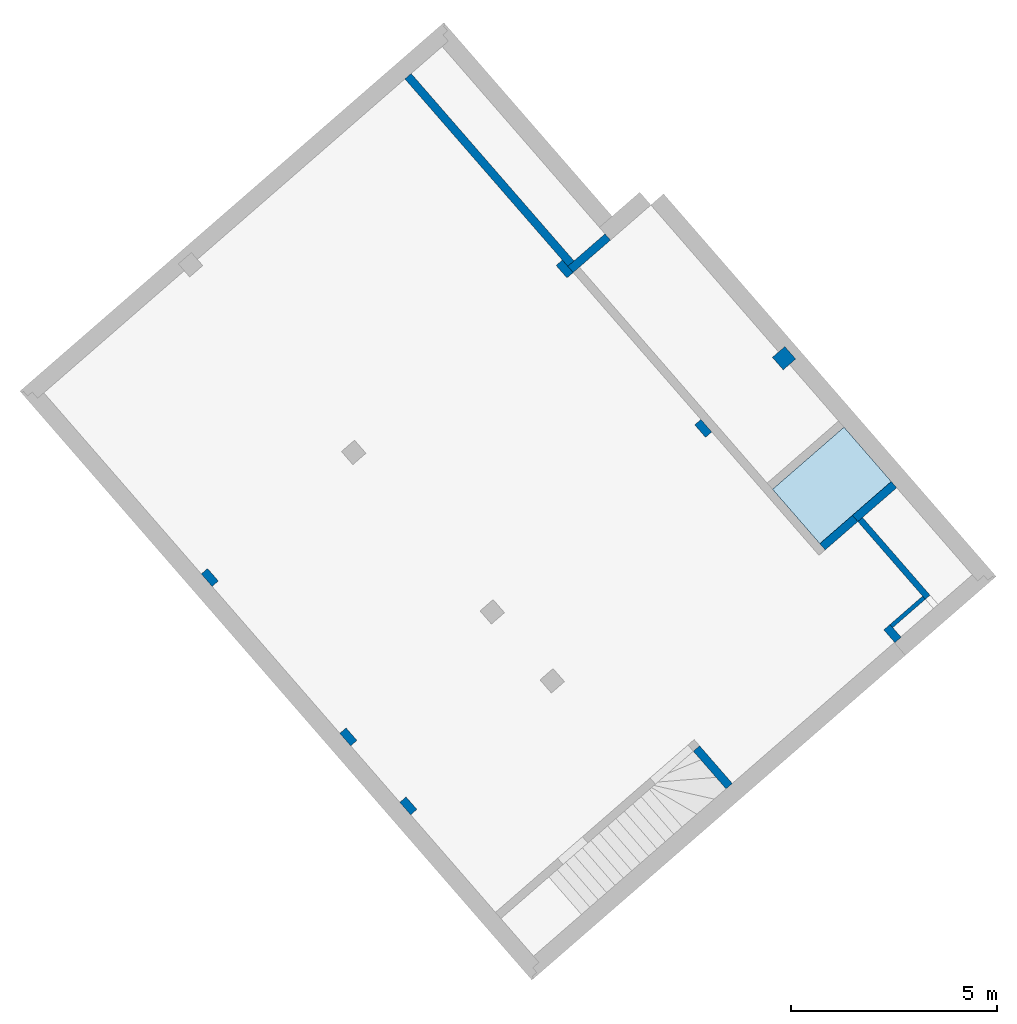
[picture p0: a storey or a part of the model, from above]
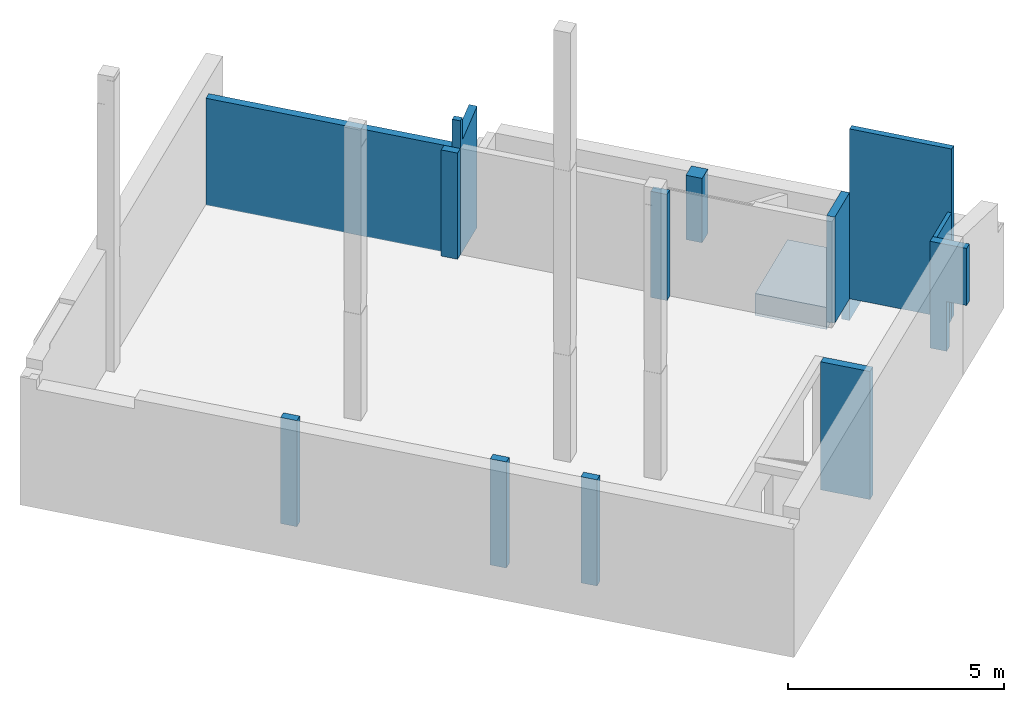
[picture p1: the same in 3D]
Properties of the parts of a building model (IFC2X3), part 1 of 13

# File
Description: ViewDefinition [CoordinationView_V2.0], Option [Drawing Scale: 100.000000], Option [Global Unique Identifiers (GUID): Keep existing], Option [Elements to export: Visible elements (on all stories)], Option [Partial Structure Display: Entire Model], Option [IFC Domain: All], Option [Structural Function: All Elements], Option [Convert Grid elements: On], Option [Convert IFC Annotations and ARCHICAD 2D elements: Off], Option [Convert 2D symbols of Doors and Windows: Off], Option [Explode Composite and Complex Profile elements into parts: Off], Option [Export geometries that Participates in Collision Detection only: Off], Option [Multi-skin complex geometries: Complex profile], Option [Elements in Solid Element Operations: BRep], Option [Elements with junctions: BRep], Option [Slabs with slanted edge(s): BRep], Option [Use legacy geometric methods as in Coordination View 1.0: Off], Option [IFC Site Geometry: As boundary representation (BRep)], Option [IFC Site Location: At Project Origin], Option [Curtain Wall export mode: Container Element], Option [Railing export mode: Single Element], Option [Stair export mode: Container Element], Option [Properties To Export: All properties], Option [Space containment: Off], Option [Bounding Box: Off], Option [Geometry to type objects: Off], Option [Element Properties: Off], Option [Building Material Properties: Off], Option [Element Parameters: Off], Option [Component Parameters: Off], Option [IFC Base Quantities: Off], Option [Door Window Parameters: On], Option [IFC Space boundaries: Off], Option [ARCHICAD Zone Categories as IFC Space classification data: Off], Option [Element Classifications: Off]
File name: C:\Users\Andro\Documents\2019_Tabasalu\VALMIS\PÕHIPROJEKT_2020-01-27\1940-A_TP_AR_2020-03-07.ifc
Time: 2020-03-06T18:38:55
Author: Architect
Organization: Building Designer Office
Written by: The EXPRESS Data Manager Version 5.02.0100.09 : 26 Sep 2013
Made in: IFC file generated by GRAPHISOFT ARCHICAD-64 22.0.0 INT FULL Windows version (IFC add-on version: 5009 INT FULL).
Authorization: The authorising person

# IfcSite, Site
RefLatitude: 47, 33, 34, 948800; RefLongitude: 19, 3, 17, 204400; RefElevation: 0 mm

# IfcBuildingStorey (6)
In: Building
Name | Elevation (mm)
-1 korrus | -3415
0 korrus | -1615
1 korrus | 0
1,5 korrus | 1800
2 korrus | 5215
Katus | 8715

# IfcSpace: Generic, 001
In: 0 korrus
Type - ElementType: Element type 001
LongName: Auditoorium; InteriorOrExteriorSpace: INTERNAL; Classification: 1.15 IfcSpace (ruum) (_RKAS BIM + ARCHICAD Classification)
Pset_SpaceCommon - Category: Generic
RUUMID - 1 Nimetus: Auditoorium; 2 Number: 001; 3 Kategooria: Generic; 4 Ruumi pindala: 151,9 Kasulik pindala: 151,9; 5 Ruumi kõrgus: 6 360
AC_Pset_RenovationAndPhasing - Renovation Status: New

# IfcSpace: Generic, 002
In: 0 korrus
Type - ElementType: Element type 002
LongName: Kabinet; InteriorOrExteriorSpace: INTERNAL; Classification: 1.15 IfcSpace (ruum) (_RKAS BIM + ARCHICAD Classification)
Pset_SpaceCommon - Category: Generic
RUUMID - 1 Nimetus: Kabinet; 2 Number: 002; 3 Kategooria: Generic; 4 Ruumi pindala: 18,7 Kasulik pindala: 18,7; 5 Ruumi kõrgus: 3 000
AC_Pset_RenovationAndPhasing - Renovation Status: New

# IfcSpace: Generic, 003
In: 0 korrus
Type - ElementType: Element type 003
LongName: Arvutiklass; InteriorOrExteriorSpace: INTERNAL; Classification: 1.15 IfcSpace (ruum) (_RKAS BIM + ARCHICAD Classification)
Pset_SpaceCommon - Category: Generic
RUUMID - 1 Nimetus: Arvutiklass; 2 Number: 003; 3 Kategooria: Generic; 4 Ruumi pindala: 40,9 Kasulik pindala: 40,9; 5 Ruumi kõrgus: 3 000
AC_Pset_RenovationAndPhasing - Renovation Status: New

# IfcSpace: Generic, 004
In: 0 korrus
Type - ElementType: Element type 004
LongName: IKT juht; InteriorOrExteriorSpace: INTERNAL; Classification: 1.15 IfcSpace (ruum) (_RKAS BIM + ARCHICAD Classification)
Pset_SpaceCommon - Category: Generic
RUUMID - 1 Nimetus: IKT juht; 2 Number: 004; 3 Kategooria: Generic; 4 Ruumi pindala: 15,7 Kasulik pindala: 15,7; 5 Ruumi kõrgus: 3 000
AC_Pset_RenovationAndPhasing - Renovation Status: New

# IfcSpace: Generic, 005
In: 0 korrus
Type - ElementType: Element type 005
LongName: Õpilasesindus; InteriorOrExteriorSpace: INTERNAL; Classification: 1.15 IfcSpace (ruum) (_RKAS BIM + ARCHICAD Classification)
Pset_SpaceCommon - Category: Generic
RUUMID - 1 Nimetus: Õpilasesindus; 2 Number: 005; 3 Kategooria: Generic; 4 Ruumi pindala: 17,8 Kasulik pindala: 17,8; 5 Ruumi kõrgus: 3 000
AC_Pset_RenovationAndPhasing - Renovation Status: New

# IfcSpace: Generic, 006
In: 0 korrus
Type - ElementType: Element type 006
LongName: Arvutiklass; InteriorOrExteriorSpace: INTERNAL; Classification: 1.15 IfcSpace (ruum) (_RKAS BIM + ARCHICAD Classification)
Pset_SpaceCommon - Category: Generic
RUUMID - 1 Nimetus: Arvutiklass; 2 Number: 006; 3 Kategooria: Generic; 4 Ruumi pindala: 72,2 Kasulik pindala: 72,2; 5 Ruumi kõrgus: 3 000
AC_Pset_RenovationAndPhasing - Renovation Status: New

# IfcSpace: Generic, 007
In: 0 korrus
Type - ElementType: Element type 007
LongName: IKT ladu; InteriorOrExteriorSpace: INTERNAL; Classification: 1.15 IfcSpace (ruum) (_RKAS BIM + ARCHICAD Classification)
Pset_SpaceCommon - Category: Generic
RUUMID - 1 Nimetus: IKT ladu; 2 Number: 007; 3 Kategooria: Generic; 4 Ruumi pindala: 3,3 Kasulik pindala: 3,3; 5 Ruumi kõrgus: 3 000
AC_Pset_RenovationAndPhasing - Renovation Status: New

# IfcSpace: Generic, 008
In: 0 korrus
Type - ElementType: Element type 008
LongName: IKT ladu; InteriorOrExteriorSpace: INTERNAL; Classification: 1.15 IfcSpace (ruum) (_RKAS BIM + ARCHICAD Classification)
Pset_SpaceCommon - Category: Generic
RUUMID - 1 Nimetus: IKT ladu; 2 Number: 008; 3 Kategooria: Generic; 4 Ruumi pindala: 3,4 Kasulik pindala: 3,4; 5 Ruumi kõrgus: 3 000
AC_Pset_RenovationAndPhasing - Renovation Status: New

# IfcSpace: Generic, 009
In: 0 korrus
Type - ElementType: Element type 009
LongName: Raamatukogu/rekreatsioon; InteriorOrExteriorSpace: INTERNAL; Classification: 1.15 IfcSpace (ruum) (_RKAS BIM + ARCHICAD Classification)
Pset_SpaceCommon - Category: Generic
RUUMID - 1 Nimetus: Raamatukogu/rekreatsioon; 2 Number: 009; 3 Kategooria: Generic; 4 Ruumi pindala: 240,4 Kasulik pindala: 238,7; 5 Ruumi kõrgus: 6 415
AC_Pset_RenovationAndPhasing - Renovation Status: New

# IfcSpace: Generic, 010
In: 0 korrus
Type - ElementType: Element type 010
LongName: Haridustehnoloog; InteriorOrExteriorSpace: INTERNAL; Classification: 1.15 IfcSpace (ruum) (_RKAS BIM + ARCHICAD Classification)
Pset_SpaceCommon - Category: Generic
RUUMID - 1 Nimetus: Haridustehnoloog; 2 Number: 010; 3 Kategooria: Generic; 4 Ruumi pindala: 21,0 Kasulik pindala: 21,0; 5 Ruumi kõrgus: 3 000
AC_Pset_RenovationAndPhasing - Renovation Status: New

# IfcSpace: Generic, 011
In: 0 korrus
Type - ElementType: Element type 011
LongName: Nõupidamisteruum; InteriorOrExteriorSpace: INTERNAL; Classification: 1.15 IfcSpace (ruum) (_RKAS BIM + ARCHICAD Classification)
Pset_SpaceCommon - Category: Generic
RUUMID - 1 Nimetus: Nõupidamisteruum; 2 Number: 011; 3 Kategooria: Generic; 4 Ruumi pindala: 28,0 Kasulik pindala: 27,7; 5 Ruumi kõrgus: 3 000
AC_Pset_RenovationAndPhasing - Renovation Status: New

# IfcSpace: Generic, 012
In: 0 korrus
Type - ElementType: Element type 012
LongName: Õppenõustaja; InteriorOrExteriorSpace: INTERNAL; Classification: 1.15 IfcSpace (ruum) (_RKAS BIM + ARCHICAD Classification)
Pset_SpaceCommon - Category: Generic
RUUMID - 1 Nimetus: Õppenõustaja; 2 Number: 012; 3 Kategooria: Generic; 4 Ruumi pindala: 12,6 Kasulik pindala: 12,6; 5 Ruumi kõrgus: 3 000
AC_Pset_RenovationAndPhasing - Renovation Status: New

# IfcSpace: Generic, 013
In: 0 korrus
Type - ElementType: Element type 013
LongName: Kilbiruum; InteriorOrExteriorSpace: INTERNAL; Classification: 1.15 IfcSpace (ruum) (_RKAS BIM + ARCHICAD Classification)
Pset_SpaceCommon - Category: Generic
RUUMID - 1 Nimetus: Kilbiruum; 2 Number: 013; 3 Kategooria: Generic; 4 Ruumi pindala: 3,0 Kasulik pindala: 3,0; 5 Ruumi kõrgus: 3 000
AC_Pset_RenovationAndPhasing - Renovation Status: New

# IfcSpace: Generic, 014
In: 0 korrus
Type - ElementType: Element type 014
LongName: Lift; InteriorOrExteriorSpace: INTERNAL; Classification: 1.15 IfcSpace (ruum) (_RKAS BIM + ARCHICAD Classification)
Pset_SpaceCommon - Category: Generic
RUUMID - 1 Nimetus: Lift; 2 Number: 014; 3 Kategooria: Generic; 4 Ruumi pindala: 4,0 Kasulik pindala: 4,0; 5 Ruumi kõrgus: 10 330
AC_Pset_RenovationAndPhasing - Renovation Status: New

# IfcSpace: Generic, 015
In: -1 korrus
Type - ElementType: Element type 015
LongName: Nõrkvool; InteriorOrExteriorSpace: INTERNAL; Classification: 1.15 IfcSpace (ruum) (_RKAS BIM + ARCHICAD Classification)
Pset_SpaceCommon - Category: Generic
RUUMID - 1 Nimetus: Nõrkvool; 2 Number: 015; 3 Kategooria: Generic; 4 Ruumi pindala: 15,9 Kasulik pindala: 14,3; 5 Ruumi kõrgus: 4 315
AC_Pset_RenovationAndPhasing - Renovation Status: New

# IfcSpace: Generic, 016
In: -1 korrus
Type - ElementType: Element type 016
LongName: Vent.ruum; InteriorOrExteriorSpace: INTERNAL; Classification: 1.15 IfcSpace (ruum) (_RKAS BIM + ARCHICAD Classification)
Pset_SpaceCommon - Category: Generic
RUUMID - 1 Nimetus: Vent.ruum; 2 Number: 016; 3 Kategooria: Generic; 4 Ruumi pindala: 200,6 Kasulik pindala: 200,6; 5 Ruumi kõrgus: 3 000
AC_Pset_RenovationAndPhasing - Renovation Status: New

# IfcSpace: Generic, 101
In: 1 korrus
Type - ElementType: Element type 101
LongName: Tuulekoda; InteriorOrExteriorSpace: INTERNAL; Classification: 1.15 IfcSpace (ruum) (_RKAS BIM + ARCHICAD Classification)
Pset_SpaceCommon - Category: Generic
RUUMID - 1 Nimetus: Tuulekoda; 2 Number: 101; 3 Kategooria: Generic; 4 Ruumi pindala: 11,2 Kasulik pindala: 11,2; 5 Ruumi kõrgus: 4 800
AC_Pset_RenovationAndPhasing - Renovation Status: New

# IfcSpace: Generic, 102
In: 1 korrus
Type - ElementType: Element type 102
LongName: Koridor; InteriorOrExteriorSpace: INTERNAL; Classification: 1.15 IfcSpace (ruum) (_RKAS BIM + ARCHICAD Classification)
Pset_SpaceCommon - Category: Generic
RUUMID - 1 Nimetus: Koridor; 2 Number: 102; 3 Kategooria: Generic; 4 Ruumi pindala: 33,4 Kasulik pindala: 1,3; 5 Ruumi kõrgus: 5 400
AC_Pset_RenovationAndPhasing - Renovation Status: New

# IfcSpace: Generic, 103
In: 1 korrus
Type - ElementType: Element type 103
LongName: Fuajee/rekreatsioon; InteriorOrExteriorSpace: INTERNAL; Classification: 1.15 IfcSpace (ruum) (_RKAS BIM + ARCHICAD Classification)
Pset_SpaceCommon - Category: Generic
RUUMID - 1 Nimetus: Fuajee/rekreatsioon; 2 Number: 103; 3 Kategooria: Generic; 4 Ruumi pindala: 248,1 Kasulik pindala: 248,1; 5 Ruumi kõrgus: 11 972
AC_Pset_RenovationAndPhasing - Renovation Status: New

# IfcSpace: Generic, 104
In: 1 korrus
Type - ElementType: Element type 104
LongName: Tuulekoda; InteriorOrExteriorSpace: INTERNAL; Classification: 1.15 IfcSpace (ruum) (_RKAS BIM + ARCHICAD Classification)
Pset_SpaceCommon - Category: Generic
RUUMID - 1 Nimetus: Tuulekoda; 2 Number: 104; 3 Kategooria: Generic; 4 Ruumi pindala: 5,7 Kasulik pindala: 5,7; 5 Ruumi kõrgus: 4 800
AC_Pset_RenovationAndPhasing - Renovation Status: New

# IfcSpace: Generic, 105
In: 1 korrus
Type - ElementType: Element type 105
LongName: Administraator; InteriorOrExteriorSpace: INTERNAL; Classification: 1.15 IfcSpace (ruum) (_RKAS BIM + ARCHICAD Classification)
Pset_SpaceCommon - Category: Generic
RUUMID - 1 Nimetus: Administraator; 2 Number: 105; 3 Kategooria: Generic; 4 Ruumi pindala: 6,1 Kasulik pindala: 6,1; 5 Ruumi kõrgus: 4 800
AC_Pset_RenovationAndPhasing - Renovation Status: New

# IfcSpace: Generic, 106
In: 1 korrus
Type - ElementType: Element type 106
LongName: Trepikoda; InteriorOrExteriorSpace: INTERNAL; Classification: 1.15 IfcSpace (ruum) (_RKAS BIM + ARCHICAD Classification)
Pset_SpaceCommon - Category: Generic
RUUMID - 1 Nimetus: Trepikoda; 2 Number: 106; 3 Kategooria: Generic; 4 Ruumi pindala: 7,3 Kasulik pindala: 7,3; 5 Ruumi kõrgus: 8 025
AC_Pset_RenovationAndPhasing - Renovation Status: New

# IfcSpace: Generic, 107
In: 1 korrus
Type - ElementType: Element type 107
LongName: Abiruum; InteriorOrExteriorSpace: INTERNAL; Classification: 1.15 IfcSpace (ruum) (_RKAS BIM + ARCHICAD Classification)
Pset_SpaceCommon - Category: Generic
RUUMID - 1 Nimetus: Abiruum; 2 Number: 107; 3 Kategooria: Generic; 4 Ruumi pindala: 1,8 Kasulik pindala: 1,8; 5 Ruumi kõrgus: 4 800
AC_Pset_RenovationAndPhasing - Renovation Status: New

# IfcSpace: Generic, 108
In: 1 korrus
Type - ElementType: Element type 108
LongName: Muusikaklassi abiruum; InteriorOrExteriorSpace: INTERNAL; Classification: 1.15 IfcSpace (ruum) (_RKAS BIM + ARCHICAD Classification)
Pset_SpaceCommon - Category: Generic
RUUMID - 1 Nimetus: Muusikaklassi abiruum; 2 Number: 108; 3 Kategooria: Generic; 4 Ruumi pindala: 10,5 Kasulik pindala: 10,5; 5 Ruumi kõrgus: 4 800
AC_Pset_RenovationAndPhasing - Renovation Status: New

# IfcSpace: Generic, 109
In: 1 korrus
Type - ElementType: Element type 109
LongName: Muusikaklass; InteriorOrExteriorSpace: INTERNAL; Classification: 1.15 IfcSpace (ruum) (_RKAS BIM + ARCHICAD Classification)
Pset_SpaceCommon - Category: Generic
RUUMID - 1 Nimetus: Muusikaklass; 2 Number: 109; 3 Kategooria: Generic; 4 Ruumi pindala: 61,5 Kasulik pindala: 61,5; 5 Ruumi kõrgus: 4 800
AC_Pset_RenovationAndPhasing - Renovation Status: New

# IfcSpace: Generic, 110
In: 1 korrus
Type - ElementType: Element type 110
LongName: Ladu; InteriorOrExteriorSpace: INTERNAL; Classification: 1.15 IfcSpace (ruum) (_RKAS BIM + ARCHICAD Classification)
Pset_SpaceCommon - Category: Generic
RUUMID - 1 Nimetus: Ladu; 2 Number: 110; 3 Kategooria: Generic; 4 Ruumi pindala: 9,2 Kasulik pindala: 9,2; 5 Ruumi kõrgus: 4 820
AC_Pset_RenovationAndPhasing - Renovation Status: New

# IfcSpace: Generic, 112
In: 1 korrus
Type - ElementType: Element type 112
LongName: Trepikoda; InteriorOrExteriorSpace: INTERNAL; Classification: 1.15 IfcSpace (ruum) (_RKAS BIM + ARCHICAD Classification)
Pset_SpaceCommon - Category: Generic
RUUMID - 1 Nimetus: Trepikoda; 2 Number: 112; 3 Kategooria: Generic; 4 Ruumi pindala: 6,2 Kasulik pindala: 1,2; 5 Ruumi kõrgus: 4 820
AC_Pset_RenovationAndPhasing - Renovation Status: New

# IfcSpace: Generic, 113
In: 1 korrus
Type - ElementType: Element type 113
LongName: Koristus; InteriorOrExteriorSpace: INTERNAL; Classification: 1.15 IfcSpace (ruum) (_RKAS BIM + ARCHICAD Classification)
Pset_SpaceCommon - Category: Generic
RUUMID - 1 Nimetus: Koristus; 2 Number: 113; 3 Kategooria: Generic; 4 Ruumi pindala: 0,9 Kasulik pindala: 0,9; 5 Ruumi kõrgus: 2 300
AC_Pset_RenovationAndPhasing - Renovation Status: New

# IfcSpace: Generic, 114
In: 1 korrus
Type - ElementType: Element type 114
LongName: Köök; InteriorOrExteriorSpace: INTERNAL; Classification: 1.15 IfcSpace (ruum) (_RKAS BIM + ARCHICAD Classification)
Pset_SpaceCommon - Category: Generic
RUUMID - 1 Nimetus: Köök; 2 Number: 114; 3 Kategooria: Generic; 4 Ruumi pindala: 51,5 Kasulik pindala: 51,5; 5 Ruumi kõrgus: 4 820
AC_Pset_RenovationAndPhasing - Renovation Status: New

# IfcSpace: Generic, 115
In: 1,5 korrus
Type - ElementType: Element type 115
LongName: Riietus; InteriorOrExteriorSpace: INTERNAL; Classification: 1.15 IfcSpace (ruum) (_RKAS BIM + ARCHICAD Classification)
Pset_SpaceCommon - Category: Generic
RUUMID - 1 Nimetus: Riietus; 2 Number: 115; 3 Kategooria: Generic; 4 Ruumi pindala: 5,6 Kasulik pindala: 5,6; 5 Ruumi kõrgus: 2 300
AC_Pset_RenovationAndPhasing - Renovation Status: New

# IfcSpace: Generic, 116
In: 1,5 korrus
Type - ElementType: Element type 116
LongName: Pesu; InteriorOrExteriorSpace: INTERNAL; Classification: 1.15 IfcSpace (ruum) (_RKAS BIM + ARCHICAD Classification)
Pset_SpaceCommon - Category: Generic
RUUMID - 1 Nimetus: Pesu; 2 Number: 116; 3 Kategooria: Generic; 4 Ruumi pindala: 1,4 Kasulik pindala: 1,4; 5 Ruumi kõrgus: 2 300
AC_Pset_RenovationAndPhasing - Renovation Status: New

# IfcSpace: Generic, 117
In: 1,5 korrus
Type - ElementType: Element type 117
LongName: wc; InteriorOrExteriorSpace: INTERNAL; Classification: 1.15 IfcSpace (ruum) (_RKAS BIM + ARCHICAD Classification)
Pset_SpaceCommon - Category: Generic
RUUMID - 1 Nimetus: wc; 2 Number: 117; 3 Kategooria: Generic; 4 Ruumi pindala: 1,4 Kasulik pindala: 1,4; 5 Ruumi kõrgus: 2 300
AC_Pset_RenovationAndPhasing - Renovation Status: New

# IfcSpace: Generic, 118
In: 1,5 korrus
Type - ElementType: Element type 118
LongName: Ladu; InteriorOrExteriorSpace: INTERNAL; Classification: 1.15 IfcSpace (ruum) (_RKAS BIM + ARCHICAD Classification)
Pset_SpaceCommon - Category: Generic
RUUMID - 1 Nimetus: Ladu; 2 Number: 118; 3 Kategooria: Generic; 4 Ruumi pindala: 9,7 Kasulik pindala: 9,7; 5 Ruumi kõrgus: 2 300
AC_Pset_RenovationAndPhasing - Renovation Status: New

# IfcSpace: Generic, 121
In: 1 korrus
Type - ElementType: Element type 121
LongName: Rekreatsioon/söökla; InteriorOrExteriorSpace: INTERNAL; Classification: 1.15 IfcSpace (ruum) (_RKAS BIM + ARCHICAD Classification)
Pset_SpaceCommon - Category: Generic
RUUMID - 1 Nimetus: Rekreatsioon/söökla; 2 Number: 121; 3 Kategooria: Generic; 4 Ruumi pindala: 210,1 Kasulik pindala: 209,5; 5 Ruumi kõrgus: 10 471
AC_Pset_RenovationAndPhasing - Renovation Status: New

# IfcSpace: Generic, 122
In: 1 korrus
Type - ElementType: Element type 122
LongName: Garderoob; InteriorOrExteriorSpace: INTERNAL; Classification: 1.15 IfcSpace (ruum) (_RKAS BIM + ARCHICAD Classification)
Pset_SpaceCommon - Category: Generic
RUUMID - 1 Nimetus: Garderoob; 2 Number: 122; 3 Kategooria: Generic; 4 Ruumi pindala: 110,3 Kasulik pindala: 109,2; 5 Ruumi kõrgus: 3 500
AC_Pset_RenovationAndPhasing - Renovation Status: New

# IfcSpace: Generic, 123
In: 1 korrus
Type - ElementType: Element type 123
LongName: Eesruum; InteriorOrExteriorSpace: INTERNAL; Classification: 1.15 IfcSpace (ruum) (_RKAS BIM + ARCHICAD Classification)
Pset_SpaceCommon - Category: Generic
RUUMID - 1 Nimetus: Eesruum; 2 Number: 123; 3 Kategooria: Generic; 4 Ruumi pindala: 10,8 Kasulik pindala: 10,8; 5 Ruumi kõrgus: 3 500
AC_Pset_RenovationAndPhasing - Renovation Status: New

# IfcSpace: Generic, 125
In: 1 korrus
Type - ElementType: Element type 125
LongName: wc; InteriorOrExteriorSpace: INTERNAL; Classification: 1.15 IfcSpace (ruum) (_RKAS BIM + ARCHICAD Classification)
Pset_SpaceCommon - Category: Generic
RUUMID - 1 Nimetus: wc; 2 Number: 125; 3 Kategooria: Generic; 4 Ruumi pindala: 1,3 Kasulik pindala: 1,3; 5 Ruumi kõrgus: 3 500
AC_Pset_RenovationAndPhasing - Renovation Status: New

# IfcSpace: Generic, 126
In: 1 korrus
Type - ElementType: Element type 126
LongName: wc; InteriorOrExteriorSpace: INTERNAL; Classification: 1.15 IfcSpace (ruum) (_RKAS BIM + ARCHICAD Classification)
Pset_SpaceCommon - Category: Generic
RUUMID - 1 Nimetus: wc; 2 Number: 126; 3 Kategooria: Generic; 4 Ruumi pindala: 1,1 Kasulik pindala: 1,1; 5 Ruumi kõrgus: 3 500
AC_Pset_RenovationAndPhasing - Renovation Status: New

# IfcSpace: Generic, 127
In: 1 korrus
Type - ElementType: Element type 127
LongName: wc; InteriorOrExteriorSpace: INTERNAL; Classification: 1.15 IfcSpace (ruum) (_RKAS BIM + ARCHICAD Classification)
Pset_SpaceCommon - Category: Generic
RUUMID - 1 Nimetus: wc; 2 Number: 127; 3 Kategooria: Generic; 4 Ruumi pindala: 1,3 Kasulik pindala: 1,3; 5 Ruumi kõrgus: 3 500
AC_Pset_RenovationAndPhasing - Renovation Status: New

# IfcSpace: Generic, 128
In: 1 korrus
Type - ElementType: Element type 128
LongName: wc; InteriorOrExteriorSpace: INTERNAL; Classification: 1.15 IfcSpace (ruum) (_RKAS BIM + ARCHICAD Classification)
Pset_SpaceCommon - Category: Generic
RUUMID - 1 Nimetus: wc; 2 Number: 128; 3 Kategooria: Generic; 4 Ruumi pindala: 1,3 Kasulik pindala: 1,3; 5 Ruumi kõrgus: 3 500
AC_Pset_RenovationAndPhasing - Renovation Status: New

# IfcSpace: Generic, 129
In: 1 korrus
Type - ElementType: Element type 129
LongName: wc; InteriorOrExteriorSpace: INTERNAL; Classification: 1.15 IfcSpace (ruum) (_RKAS BIM + ARCHICAD Classification)
Pset_SpaceCommon - Category: Generic
RUUMID - 1 Nimetus: wc; 2 Number: 129; 3 Kategooria: Generic; 4 Ruumi pindala: 1,3 Kasulik pindala: 1,3; 5 Ruumi kõrgus: 3 500
AC_Pset_RenovationAndPhasing - Renovation Status: New

# IfcSpace: Generic, 130
In: 1 korrus
Type - ElementType: Element type 130
LongName: Inva wc; InteriorOrExteriorSpace: INTERNAL; Classification: 1.15 IfcSpace (ruum) (_RKAS BIM + ARCHICAD Classification)
Pset_SpaceCommon - Category: Generic
RUUMID - 1 Nimetus: Inva wc; 2 Number: 130; 3 Kategooria: Generic; 4 Ruumi pindala: 6,5 Kasulik pindala: 6,5; 5 Ruumi kõrgus: 3 500
AC_Pset_RenovationAndPhasing - Renovation Status: New

# IfcSpace: Generic, 131
In: 1 korrus
Type - ElementType: Element type 131
LongName: korist.; InteriorOrExteriorSpace: INTERNAL; Classification: 1.15 IfcSpace (ruum) (_RKAS BIM + ARCHICAD Classification)
Pset_SpaceCommon - Category: Generic
RUUMID - 1 Nimetus: korist.; 2 Number: 131; 3 Kategooria: Generic; 4 Ruumi pindala: 1,5 Kasulik pindala: 1,5; 5 Ruumi kõrgus: 3 500
AC_Pset_RenovationAndPhasing - Renovation Status: New

# IfcSpace: Generic, 132
In: 1 korrus
Type - ElementType: Element type 132
LongName: wc; InteriorOrExteriorSpace: INTERNAL; Classification: 1.15 IfcSpace (ruum) (_RKAS BIM + ARCHICAD Classification)
Pset_SpaceCommon - Category: Generic
RUUMID - 1 Nimetus: wc; 2 Number: 132; 3 Kategooria: Generic; 4 Ruumi pindala: 1,3 Kasulik pindala: 1,3; 5 Ruumi kõrgus: 3 500
AC_Pset_RenovationAndPhasing - Renovation Status: New

# IfcSpace: Generic, 133
In: 1 korrus
Type - ElementType: Element type 133
LongName: wc; InteriorOrExteriorSpace: INTERNAL; Classification: 1.15 IfcSpace (ruum) (_RKAS BIM + ARCHICAD Classification)
Pset_SpaceCommon - Category: Generic
RUUMID - 1 Nimetus: wc; 2 Number: 133; 3 Kategooria: Generic; 4 Ruumi pindala: 1,3 Kasulik pindala: 1,3; 5 Ruumi kõrgus: 3 500
AC_Pset_RenovationAndPhasing - Renovation Status: New

# IfcSpace: Generic, 134
In: 1 korrus
Type - ElementType: Element type 134
LongName: wc; InteriorOrExteriorSpace: INTERNAL; Classification: 1.15 IfcSpace (ruum) (_RKAS BIM + ARCHICAD Classification)
Pset_SpaceCommon - Category: Generic
RUUMID - 1 Nimetus: wc; 2 Number: 134; 3 Kategooria: Generic; 4 Ruumi pindala: 1,3 Kasulik pindala: 1,3; 5 Ruumi kõrgus: 3 500
AC_Pset_RenovationAndPhasing - Renovation Status: New

# IfcSpace: Generic, 135
In: 1 korrus
Type - ElementType: Element type 135
LongName: Eesruum; InteriorOrExteriorSpace: INTERNAL; Classification: 1.15 IfcSpace (ruum) (_RKAS BIM + ARCHICAD Classification)
Pset_SpaceCommon - Category: Generic
RUUMID - 1 Nimetus: Eesruum; 2 Number: 135; 3 Kategooria: Generic; 4 Ruumi pindala: 1,7 Kasulik pindala: 1,7; 5 Ruumi kõrgus: 3 500
AC_Pset_RenovationAndPhasing - Renovation Status: New

# IfcSpace: Generic, 136
In: 1 korrus
Type - ElementType: Element type 136
LongName: Riietus; InteriorOrExteriorSpace: INTERNAL; Classification: 1.15 IfcSpace (ruum) (_RKAS BIM + ARCHICAD Classification)
Pset_SpaceCommon - Category: Generic
RUUMID - 1 Nimetus: Riietus; 2 Number: 136; 3 Kategooria: Generic; 4 Ruumi pindala: 18,4 Kasulik pindala: 18,4; 5 Ruumi kõrgus: 3 500
AC_Pset_RenovationAndPhasing - Renovation Status: New

# IfcSpace: Generic, 137
In: 1 korrus
Type - ElementType: Element type 137
LongName: Pesuruum; InteriorOrExteriorSpace: INTERNAL; Classification: 1.15 IfcSpace (ruum) (_RKAS BIM + ARCHICAD Classification)
Pset_SpaceCommon - Category: Generic
RUUMID - 1 Nimetus: Pesuruum; 2 Number: 137; 3 Kategooria: Generic; 4 Ruumi pindala: 7,9 Kasulik pindala: 7,9; 5 Ruumi kõrgus: 3 500
AC_Pset_RenovationAndPhasing - Renovation Status: New

# IfcSpace: Generic, 138
In: 1 korrus
Type - ElementType: Element type 138
LongName: wc; InteriorOrExteriorSpace: INTERNAL; Classification: 1.15 IfcSpace (ruum) (_RKAS BIM + ARCHICAD Classification)
Pset_SpaceCommon - Category: Generic
RUUMID - 1 Nimetus: wc; 2 Number: 138; 3 Kategooria: Generic; 4 Ruumi pindala: 2,2 Kasulik pindala: 2,2; 5 Ruumi kõrgus: 3 500
AC_Pset_RenovationAndPhasing - Renovation Status: New

# IfcSpace: Generic, 139
In: 1 korrus
Type - ElementType: Element type 139
LongName: wc; InteriorOrExteriorSpace: INTERNAL; Classification: 1.15 IfcSpace (ruum) (_RKAS BIM + ARCHICAD Classification)
Pset_SpaceCommon - Category: Generic
RUUMID - 1 Nimetus: wc; 2 Number: 139; 3 Kategooria: Generic; 4 Ruumi pindala: 2,2 Kasulik pindala: 2,2; 5 Ruumi kõrgus: 3 500
AC_Pset_RenovationAndPhasing - Renovation Status: New

# IfcSpace: Generic, 140
In: 1 korrus
Type - ElementType: Element type 140
LongName: Pesuruum; InteriorOrExteriorSpace: INTERNAL; Classification: 1.15 IfcSpace (ruum) (_RKAS BIM + ARCHICAD Classification)
Pset_SpaceCommon - Category: Generic
RUUMID - 1 Nimetus: Pesuruum; 2 Number: 140; 3 Kategooria: Generic; 4 Ruumi pindala: 8,1 Kasulik pindala: 8,1; 5 Ruumi kõrgus: 3 500
AC_Pset_RenovationAndPhasing - Renovation Status: New

# IfcSpace: Generic, 141
In: 1 korrus
Type - ElementType: Element type 141
LongName: Riietus; InteriorOrExteriorSpace: INTERNAL; Classification: 1.15 IfcSpace (ruum) (_RKAS BIM + ARCHICAD Classification)
Pset_SpaceCommon - Category: Generic
RUUMID - 1 Nimetus: Riietus; 2 Number: 141; 3 Kategooria: Generic; 4 Ruumi pindala: 18,4 Kasulik pindala: 18,4; 5 Ruumi kõrgus: 3 500
AC_Pset_RenovationAndPhasing - Renovation Status: New

# IfcSpace: Generic, 142
In: 1 korrus
Type - ElementType: Element type 142
LongName: Eesruum; InteriorOrExteriorSpace: INTERNAL; Classification: 1.15 IfcSpace (ruum) (_RKAS BIM + ARCHICAD Classification)
Pset_SpaceCommon - Category: Generic
RUUMID - 1 Nimetus: Eesruum; 2 Number: 142; 3 Kategooria: Generic; 4 Ruumi pindala: 2,5 Kasulik pindala: 2,5; 5 Ruumi kõrgus: 3 500
AC_Pset_RenovationAndPhasing - Renovation Status: New

# IfcSpace: Generic, 143
In: 1 korrus
Type - ElementType: Element type 143
LongName: Riietus; InteriorOrExteriorSpace: INTERNAL; Classification: 1.15 IfcSpace (ruum) (_RKAS BIM + ARCHICAD Classification)
Pset_SpaceCommon - Category: Generic
RUUMID - 1 Nimetus: Riietus; 2 Number: 143; 3 Kategooria: Generic; 4 Ruumi pindala: 3,9 Kasulik pindala: 3,9; 5 Ruumi kõrgus: 3 500
AC_Pset_RenovationAndPhasing - Renovation Status: New

# IfcSpace: Generic, 144
In: 1 korrus
Type - ElementType: Element type 144
LongName: Pesuruum/wc; InteriorOrExteriorSpace: INTERNAL; Classification: 1.15 IfcSpace (ruum) (_RKAS BIM + ARCHICAD Classification)
Pset_SpaceCommon - Category: Generic
RUUMID - 1 Nimetus: Pesuruum/wc; 2 Number: 144; 3 Kategooria: Generic; 4 Ruumi pindala: 3,0 Kasulik pindala: 3,0; 5 Ruumi kõrgus: 3 500
AC_Pset_RenovationAndPhasing - Renovation Status: New

# IfcSpace: Generic, 145
In: 1 korrus
Type - ElementType: Element type 145
LongName: Mööbli/majandus ladu; InteriorOrExteriorSpace: INTERNAL; Classification: 1.15 IfcSpace (ruum) (_RKAS BIM + ARCHICAD Classification)
Pset_SpaceCommon - Category: Generic
RUUMID - 1 Nimetus: Mööbli/majandus ladu; 2 Number: 145; 3 Kategooria: Generic; 4 Ruumi pindala: 24,0 Kasulik pindala: 24,0; 5 Ruumi kõrgus: 3 500
AC_Pset_RenovationAndPhasing - Renovation Status: New

# IfcSpace: Generic, 146
In: 1 korrus
Type - ElementType: Element type 146
LongName: Dokumendihoidla; InteriorOrExteriorSpace: INTERNAL; Classification: 1.15 IfcSpace (ruum) (_RKAS BIM + ARCHICAD Classification)
Pset_SpaceCommon - Category: Generic
RUUMID - 1 Nimetus: Dokumendihoidla; 2 Number: 146; 3 Kategooria: Generic; 4 Ruumi pindala: 13,8 Kasulik pindala: 13,8; 5 Ruumi kõrgus: 3 500
AC_Pset_RenovationAndPhasing - Renovation Status: New

# IfcSpace: Generic, 147
In: 1,5 korrus
Type - ElementType: Element type 147
LongName: Klass; InteriorOrExteriorSpace: INTERNAL; Classification: 1.15 IfcSpace (ruum) (_RKAS BIM + ARCHICAD Classification)
Pset_SpaceCommon - Category: Generic
RUUMID - 1 Nimetus: Klass; 2 Number: 147; 3 Kategooria: Generic; 4 Ruumi pindala: 40,0 Kasulik pindala: 40,0; 5 Ruumi kõrgus: 3 000
AC_Pset_RenovationAndPhasing - Renovation Status: New

# IfcSpace: Generic, 148
In: 1,5 korrus
Type - ElementType: Element type 148
LongName: Abiruum; InteriorOrExteriorSpace: INTERNAL; Classification: 1.15 IfcSpace (ruum) (_RKAS BIM + ARCHICAD Classification)
Pset_SpaceCommon - Category: Generic
RUUMID - 1 Nimetus: Abiruum; 2 Number: 148; 3 Kategooria: Generic; 4 Ruumi pindala: 12,2 Kasulik pindala: 12,2; 5 Ruumi kõrgus: 3 000
AC_Pset_RenovationAndPhasing - Renovation Status: New

# IfcSpace: Generic, 149
In: 1,5 korrus
Type - ElementType: Element type 149
LongName: Füüsikaklass; InteriorOrExteriorSpace: INTERNAL; Classification: 1.15 IfcSpace (ruum) (_RKAS BIM + ARCHICAD Classification)
Pset_SpaceCommon - Category: Generic
RUUMID - 1 Nimetus: Füüsikaklass; 2 Number: 149; 3 Kategooria: Generic; 4 Ruumi pindala: 61,3 Kasulik pindala: 61,3; 5 Ruumi kõrgus: 3 000
AC_Pset_RenovationAndPhasing - Renovation Status: New

# IfcSpace: Generic, 150
In: 1,5 korrus
Type - ElementType: Element type 150
LongName: Klass; InteriorOrExteriorSpace: INTERNAL; Classification: 1.15 IfcSpace (ruum) (_RKAS BIM + ARCHICAD Classification)
Pset_SpaceCommon - Category: Generic
RUUMID - 1 Nimetus: Klass; 2 Number: 150; 3 Kategooria: Generic; 4 Ruumi pindala: 61,3 Kasulik pindala: 61,3; 5 Ruumi kõrgus: 3 000
AC_Pset_RenovationAndPhasing - Renovation Status: New

# IfcSpace: Generic, 151
In: 1,5 korrus
Type - ElementType: Element type 151
LongName: Astmestik/koridor/ rekreatsioon; InteriorOrExteriorSpace: INTERNAL; Classification: 1.15 IfcSpace (ruum) (_RKAS BIM + ARCHICAD Classification)
Pset_SpaceCommon - Category: Generic
RUUMID - 1 Nimetus: Astmestik/koridor/ rekreatsioon; 2 Number: 151; 3 Kategooria: Generic; 4 Ruumi pindala: 172,4 Kasulik pindala: 0,4; 5 Ruumi kõrgus: 11 830
AC_Pset_RenovationAndPhasing - Renovation Status: New

# IfcSpace: Generic, 152
In: 1,5 korrus
Type - ElementType: Element type 152
LongName: Õppekorraldusspets.; InteriorOrExteriorSpace: INTERNAL; Classification: 1.15 IfcSpace (ruum) (_RKAS BIM + ARCHICAD Classification)
Pset_SpaceCommon - Category: Generic
RUUMID - 1 Nimetus: Õppekorraldusspets.; 2 Number: 152; 3 Kategooria: Generic; 4 Ruumi pindala: 11,4 Kasulik pindala: 11,4; 5 Ruumi kõrgus: 3 000
AC_Pset_RenovationAndPhasing - Renovation Status: New

# IfcSpace: Generic, 153
In: 1,5 korrus
Type - ElementType: Element type 153
LongName: Õppealajuhataja; InteriorOrExteriorSpace: INTERNAL; Classification: 1.15 IfcSpace (ruum) (_RKAS BIM + ARCHICAD Classification)
Pset_SpaceCommon - Category: Generic
RUUMID - 1 Nimetus: Õppealajuhataja; 2 Number: 153; 3 Kategooria: Generic; 4 Ruumi pindala: 14,4 Kasulik pindala: 14,4; 5 Ruumi kõrgus: 3 000
AC_Pset_RenovationAndPhasing - Renovation Status: New

# IfcSpace: Generic, 154
In: 1,5 korrus
Type - ElementType: Element type 154
LongName: Juhiabi; InteriorOrExteriorSpace: INTERNAL; Classification: 1.15 IfcSpace (ruum) (_RKAS BIM + ARCHICAD Classification)
Pset_SpaceCommon - Category: Generic
RUUMID - 1 Nimetus: Juhiabi; 2 Number: 154; 3 Kategooria: Generic; 4 Ruumi pindala: 12,3 Kasulik pindala: 12,3; 5 Ruumi kõrgus: 3 000
AC_Pset_RenovationAndPhasing - Renovation Status: New

# IfcSpace: Generic, 155
In: 1,5 korrus
Type - ElementType: Element type 155
LongName: Direktor; InteriorOrExteriorSpace: INTERNAL; Classification: 1.15 IfcSpace (ruum) (_RKAS BIM + ARCHICAD Classification)
Pset_SpaceCommon - Category: Generic
RUUMID - 1 Nimetus: Direktor; 2 Number: 155; 3 Kategooria: Generic; 4 Ruumi pindala: 16,2 Kasulik pindala: 16,2; 5 Ruumi kõrgus: 3 000
AC_Pset_RenovationAndPhasing - Renovation Status: New

# IfcSpace: Generic, 156
In: 1,5 korrus
Type - ElementType: Element type 156
LongName: Õpetajate tuba; InteriorOrExteriorSpace: INTERNAL; Classification: 1.15 IfcSpace (ruum) (_RKAS BIM + ARCHICAD Classification)
Pset_SpaceCommon - Category: Generic
RUUMID - 1 Nimetus: Õpetajate tuba; 2 Number: 156; 3 Kategooria: Generic; 4 Ruumi pindala: 42,9 Kasulik pindala: 42,9; 5 Ruumi kõrgus: 3 000
AC_Pset_RenovationAndPhasing - Renovation Status: New

# IfcSpace: Generic, 157
In: 1,5 korrus
Type - ElementType: Element type 157
LongName: Trepp; InteriorOrExteriorSpace: INTERNAL; Classification: 1.15 IfcSpace (ruum) (_RKAS BIM + ARCHICAD Classification)
Pset_SpaceCommon - Category: Generic
RUUMID - 1 Nimetus: Trepp; 2 Number: 157; 3 Kategooria: Generic; 4 Ruumi pindala: 6,1 Kasulik pindala: 0,2; 5 Ruumi kõrgus: 6 244
AC_Pset_RenovationAndPhasing - Renovation Status: New

# IfcSpace: Generic, 158
In: 1,5 korrus
Type - ElementType: Element type 158
LongName: wc; InteriorOrExteriorSpace: INTERNAL; Classification: 1.15 IfcSpace (ruum) (_RKAS BIM + ARCHICAD Classification)
Pset_SpaceCommon - Category: Generic
RUUMID - 1 Nimetus: wc; 2 Number: 158; 3 Kategooria: Generic; 4 Ruumi pindala: 2,6 Kasulik pindala: 2,6; 5 Ruumi kõrgus: 3 000
AC_Pset_RenovationAndPhasing - Renovation Status: New

# IfcSpace: Generic, 159
In: 1,5 korrus
Type - ElementType: Element type 159
LongName: Koristus; InteriorOrExteriorSpace: INTERNAL; Classification: 1.15 IfcSpace (ruum) (_RKAS BIM + ARCHICAD Classification)
Pset_SpaceCommon - Category: Generic
RUUMID - 1 Nimetus: Koristus; 2 Number: 159; 3 Kategooria: Generic; 4 Ruumi pindala: 3,0 Kasulik pindala: 3,0; 5 Ruumi kõrgus: 3 000
AC_Pset_RenovationAndPhasing - Renovation Status: New

# IfcSpace: Generic, 201
In: 2 korrus
Type - ElementType: Element type 201
LongName: Klass; InteriorOrExteriorSpace: INTERNAL; Classification: 1.15 IfcSpace (ruum) (_RKAS BIM + ARCHICAD Classification)
Pset_SpaceCommon - Category: Generic
RUUMID - 1 Nimetus: Klass; 2 Number: 201; 3 Kategooria: Generic; 4 Ruumi pindala: 41,6 Kasulik pindala: 41,6; 5 Ruumi kõrgus: 3 500
AC_Pset_RenovationAndPhasing - Renovation Status: New

# IfcSpace: Generic, 202
In: 2 korrus
Type - ElementType: Element type 202
LongName: Abiruum; InteriorOrExteriorSpace: INTERNAL; Classification: 1.15 IfcSpace (ruum) (_RKAS BIM + ARCHICAD Classification)
Pset_SpaceCommon - Category: Generic
RUUMID - 1 Nimetus: Abiruum; 2 Number: 202; 3 Kategooria: Generic; 4 Ruumi pindala: 2,6 Kasulik pindala: 2,6; 5 Ruumi kõrgus: 3 500
AC_Pset_RenovationAndPhasing - Renovation Status: New

# IfcSpace: Generic, 203
In: 2 korrus
Type - ElementType: Element type 203
LongName: Kunstiklass; InteriorOrExteriorSpace: INTERNAL; Classification: 1.15 IfcSpace (ruum) (_RKAS BIM + ARCHICAD Classification)
Pset_SpaceCommon - Category: Generic
RUUMID - 1 Nimetus: Kunstiklass; 2 Number: 203; 3 Kategooria: Generic; 4 Ruumi pindala: 65,6 Kasulik pindala: 65,6; 5 Ruumi kõrgus: 3 500
AC_Pset_RenovationAndPhasing - Renovation Status: New

# IfcSpace: Generic, 204
In: 2 korrus
Type - ElementType: Element type 204
LongName: Abiruum; InteriorOrExteriorSpace: INTERNAL; Classification: 1.15 IfcSpace (ruum) (_RKAS BIM + ARCHICAD Classification)
Pset_SpaceCommon - Category: Generic
RUUMID - 1 Nimetus: Abiruum; 2 Number: 204; 3 Kategooria: Generic; 4 Ruumi pindala: 11,6 Kasulik pindala: 11,6; 5 Ruumi kõrgus: 3 500
AC_Pset_RenovationAndPhasing - Renovation Status: New

# IfcSpace: Generic, 205
In: 2 korrus
Type - ElementType: Element type 205
LongName: Keemiaklass; InteriorOrExteriorSpace: INTERNAL; Classification: 1.15 IfcSpace (ruum) (_RKAS BIM + ARCHICAD Classification)
Pset_SpaceCommon - Category: Generic
RUUMID - 1 Nimetus: Keemiaklass; 2 Number: 205; 3 Kategooria: Generic; 4 Ruumi pindala: 61,3 Kasulik pindala: 61,3; 5 Ruumi kõrgus: 3 500
AC_Pset_RenovationAndPhasing - Renovation Status: New

# IfcSpace: Generic, 206
In: 2 korrus
Type - ElementType: Element type 206
LongName: Abiruum; InteriorOrExteriorSpace: INTERNAL; Classification: 1.15 IfcSpace (ruum) (_RKAS BIM + ARCHICAD Classification)
Pset_SpaceCommon - Category: Generic
RUUMID - 1 Nimetus: Abiruum; 2 Number: 206; 3 Kategooria: Generic; 4 Ruumi pindala: 17,9 Kasulik pindala: 17,9; 5 Ruumi kõrgus: 3 500
AC_Pset_RenovationAndPhasing - Renovation Status: New

# IfcSpace: Generic, 207
In: 2 korrus
Type - ElementType: Element type 207
LongName: Labor; InteriorOrExteriorSpace: INTERNAL; Classification: 1.15 IfcSpace (ruum) (_RKAS BIM + ARCHICAD Classification)
Pset_SpaceCommon - Category: Generic
RUUMID - 1 Nimetus: Labor; 2 Number: 207; 3 Kategooria: Generic; 4 Ruumi pindala: 90,1 Kasulik pindala: 90,1; 5 Ruumi kõrgus: 3 500
AC_Pset_RenovationAndPhasing - Renovation Status: New

# IfcSpace: Generic, 208
In: 2 korrus
Type - ElementType: Element type 208
LongName: Kilbiruum; InteriorOrExteriorSpace: INTERNAL; Classification: 1.15 IfcSpace (ruum) (_RKAS BIM + ARCHICAD Classification)
Pset_SpaceCommon - Category: Generic
RUUMID - 1 Nimetus: Kilbiruum; 2 Number: 208; 3 Kategooria: Generic; 4 Ruumi pindala: 1,4 Kasulik pindala: 1,4; 5 Ruumi kõrgus: 3 500
AC_Pset_RenovationAndPhasing - Renovation Status: New

# IfcSpace: Generic, 209
In: 2 korrus
Type - ElementType: Element type 209
LongName: Vaheruum; InteriorOrExteriorSpace: INTERNAL; Classification: 1.15 IfcSpace (ruum) (_RKAS BIM + ARCHICAD Classification)
Pset_SpaceCommon - Category: Generic
RUUMID - 1 Nimetus: Vaheruum; 2 Number: 209; 3 Kategooria: Generic; 4 Ruumi pindala: 1,1 Kasulik pindala: 1,1; 5 Ruumi kõrgus: 3 500
AC_Pset_RenovationAndPhasing - Renovation Status: New

# IfcSpace: Generic, 210
In: 2 korrus
Type - ElementType: Element type 210
LongName: Bioloogia klass; InteriorOrExteriorSpace: INTERNAL; Classification: 1.15 IfcSpace (ruum) (_RKAS BIM + ARCHICAD Classification)
Pset_SpaceCommon - Category: Generic
RUUMID - 1 Nimetus: Bioloogia klass; 2 Number: 210; 3 Kategooria: Generic; 4 Ruumi pindala: 61,3 Kasulik pindala: 61,3; 5 Ruumi kõrgus: 3 500
AC_Pset_RenovationAndPhasing - Renovation Status: New

# IfcSpace: Generic, 211
In: 2 korrus
Type - ElementType: Element type 211
LongName: Klass; InteriorOrExteriorSpace: INTERNAL; Classification: 1.15 IfcSpace (ruum) (_RKAS BIM + ARCHICAD Classification)
Pset_SpaceCommon - Category: Generic
RUUMID - 1 Nimetus: Klass; 2 Number: 211; 3 Kategooria: Generic; 4 Ruumi pindala: 40,0 Kasulik pindala: 40,0; 5 Ruumi kõrgus: 3 500
AC_Pset_RenovationAndPhasing - Renovation Status: New

# IfcSpace: Generic, 212
In: 2 korrus
Type - ElementType: Element type 212
LongName: Seminariruum; InteriorOrExteriorSpace: INTERNAL; Classification: 1.15 IfcSpace (ruum) (_RKAS BIM + ARCHICAD Classification)
Pset_SpaceCommon - Category: Generic
RUUMID - 1 Nimetus: Seminariruum; 2 Number: 212; 3 Kategooria: Generic; 4 Ruumi pindala: 19,1 Kasulik pindala: 19,1; 5 Ruumi kõrgus: 3 500
AC_Pset_RenovationAndPhasing - Renovation Status: New

# IfcSpace: Generic, 213
In: 2 korrus
Type - ElementType: Element type 213
LongName: Koridor/trepistik/ rekreatsioon; InteriorOrExteriorSpace: INTERNAL; Classification: 1.15 IfcSpace (ruum) (_RKAS BIM + ARCHICAD Classification)
Pset_SpaceCommon - Category: Generic
RUUMID - 1 Nimetus: Koridor/trepistik/ rekreatsioon; 2 Number: 213; 3 Kategooria: Generic; 4 Ruumi pindala: 312,0 Kasulik pindala: 2,3; 5 Ruumi kõrgus: 8 415
AC_Pset_RenovationAndPhasing - Renovation Status: New

# IfcSpace: Generic, 214
In: 2 korrus
Type - ElementType: Element type 214
LongName: Koridor; InteriorOrExteriorSpace: INTERNAL; Classification: 1.15 IfcSpace (ruum) (_RKAS BIM + ARCHICAD Classification)
Pset_SpaceCommon - Category: Generic
RUUMID - 1 Nimetus: Koridor; 2 Number: 214; 3 Kategooria: Generic; 4 Ruumi pindala: 5,7 Kasulik pindala: 5,7; 5 Ruumi kõrgus: 3 500
AC_Pset_RenovationAndPhasing - Renovation Status: New

# IfcSpace: Generic, 215
In: 2 korrus
Type - ElementType: Element type 215
LongName: Klass; InteriorOrExteriorSpace: INTERNAL; Classification: 1.15 IfcSpace (ruum) (_RKAS BIM + ARCHICAD Classification)
Pset_SpaceCommon - Category: Generic
RUUMID - 1 Nimetus: Klass; 2 Number: 215; 3 Kategooria: Generic; 4 Ruumi pindala: 39,7 Kasulik pindala: 39,7; 5 Ruumi kõrgus: 3 500
AC_Pset_RenovationAndPhasing - Renovation Status: New

# IfcSpace: Generic, 216
In: 2 korrus
Type - ElementType: Element type 216
LongName: Klass; InteriorOrExteriorSpace: INTERNAL; Classification: 1.15 IfcSpace (ruum) (_RKAS BIM + ARCHICAD Classification)
Pset_SpaceCommon - Category: Generic
RUUMID - 1 Nimetus: Klass; 2 Number: 216; 3 Kategooria: Generic; 4 Ruumi pindala: 40,2 Kasulik pindala: 40,2; 5 Ruumi kõrgus: 3 500
AC_Pset_RenovationAndPhasing - Renovation Status: New

# IfcSpace: Generic, 217
In: 2 korrus
Type - ElementType: Element type 217
LongName: Õpetajate (töö)tuba; InteriorOrExteriorSpace: INTERNAL; Classification: 1.15 IfcSpace (ruum) (_RKAS BIM + ARCHICAD Classification)
Pset_SpaceCommon - Category: Generic
RUUMID - 1 Nimetus: Õpetajate (töö)tuba; 2 Number: 217; 3 Kategooria: Generic; 4 Ruumi pindala: 20,3 Kasulik pindala: 20,3; 5 Ruumi kõrgus: 3 500
AC_Pset_RenovationAndPhasing - Renovation Status: New

# IfcSpace: Generic, 218
In: 2 korrus
Type - ElementType: Element type 218
LongName: Koristus; InteriorOrExteriorSpace: INTERNAL; Classification: 1.15 IfcSpace (ruum) (_RKAS BIM + ARCHICAD Classification)
Pset_SpaceCommon - Category: Generic
RUUMID - 1 Nimetus: Koristus; 2 Number: 218; 3 Kategooria: Generic; 4 Ruumi pindala: 3,0 Kasulik pindala: 3,0; 5 Ruumi kõrgus: 3 500
AC_Pset_RenovationAndPhasing - Renovation Status: New

# IfcSpace: Generic, 219
In: 2 korrus
Type - ElementType: Element type 219
LongName: Klass; InteriorOrExteriorSpace: INTERNAL; Classification: 1.15 IfcSpace (ruum) (_RKAS BIM + ARCHICAD Classification)
Pset_SpaceCommon - Category: Generic
RUUMID - 1 Nimetus: Klass; 2 Number: 219; 3 Kategooria: Generic; 4 Ruumi pindala: 40,3 Kasulik pindala: 40,3; 5 Ruumi kõrgus: 3 500
AC_Pset_RenovationAndPhasing - Renovation Status: New

# IfcSpace: Generic, 220
In: 2 korrus
Type - ElementType: Element type 220
LongName: wc; InteriorOrExteriorSpace: INTERNAL; Classification: 1.15 IfcSpace (ruum) (_RKAS BIM + ARCHICAD Classification)
Pset_SpaceCommon - Category: Generic
RUUMID - 1 Nimetus: wc; 2 Number: 220; 3 Kategooria: Generic; 4 Ruumi pindala: 1,2 Kasulik pindala: 1,2; 5 Ruumi kõrgus: 3 500
AC_Pset_RenovationAndPhasing - Renovation Status: New

# IfcSpace: Generic, 221
In: 2 korrus
Type - ElementType: Element type 221
LongName: wc; InteriorOrExteriorSpace: INTERNAL; Classification: 1.15 IfcSpace (ruum) (_RKAS BIM + ARCHICAD Classification)
Pset_SpaceCommon - Category: Generic
RUUMID - 1 Nimetus: wc; 2 Number: 221; 3 Kategooria: Generic; 4 Ruumi pindala: 1,2 Kasulik pindala: 1,2; 5 Ruumi kõrgus: 3 500
AC_Pset_RenovationAndPhasing - Renovation Status: New

# IfcSpace: Generic, 222
In: 2 korrus
Type - ElementType: Element type 222
LongName: wc; InteriorOrExteriorSpace: INTERNAL; Classification: 1.15 IfcSpace (ruum) (_RKAS BIM + ARCHICAD Classification)
Pset_SpaceCommon - Category: Generic
RUUMID - 1 Nimetus: wc; 2 Number: 222; 3 Kategooria: Generic; 4 Ruumi pindala: 1,2 Kasulik pindala: 1,2; 5 Ruumi kõrgus: 3 500
AC_Pset_RenovationAndPhasing - Renovation Status: New

# IfcSpace: Generic, 223
In: 2 korrus
Type - ElementType: Element type 223
LongName: wc; InteriorOrExteriorSpace: INTERNAL; Classification: 1.15 IfcSpace (ruum) (_RKAS BIM + ARCHICAD Classification)
Pset_SpaceCommon - Category: Generic
RUUMID - 1 Nimetus: wc; 2 Number: 223; 3 Kategooria: Generic; 4 Ruumi pindala: 1,2 Kasulik pindala: 1,2; 5 Ruumi kõrgus: 3 500
AC_Pset_RenovationAndPhasing - Renovation Status: New

# IfcSpace: Generic, 224
In: 2 korrus
Type - ElementType: Element type 224
LongName: Eesruum; InteriorOrExteriorSpace: INTERNAL; Classification: 1.15 IfcSpace (ruum) (_RKAS BIM + ARCHICAD Classification)
Pset_SpaceCommon - Category: Generic
RUUMID - 1 Nimetus: Eesruum; 2 Number: 224; 3 Kategooria: Generic; 4 Ruumi pindala: 7,4 Kasulik pindala: 7,4; 5 Ruumi kõrgus: 3 500
AC_Pset_RenovationAndPhasing - Renovation Status: New

# IfcSpace: Generic, 225
In: 2 korrus
Type - ElementType: Element type 225
LongName: wc; InteriorOrExteriorSpace: INTERNAL; Classification: 1.15 IfcSpace (ruum) (_RKAS BIM + ARCHICAD Classification)
Pset_SpaceCommon - Category: Generic
RUUMID - 1 Nimetus: wc; 2 Number: 225; 3 Kategooria: Generic; 4 Ruumi pindala: 1,8 Kasulik pindala: 1,8; 5 Ruumi kõrgus: 3 500
AC_Pset_RenovationAndPhasing - Renovation Status: New

# IfcSpace: Generic, 226
In: 2 korrus
Type - ElementType: Element type 226
LongName: wc; InteriorOrExteriorSpace: INTERNAL; Classification: 1.15 IfcSpace (ruum) (_RKAS BIM + ARCHICAD Classification)
Pset_SpaceCommon - Category: Generic
RUUMID - 1 Nimetus: wc; 2 Number: 226; 3 Kategooria: Generic; 4 Ruumi pindala: 1,9 Kasulik pindala: 1,9; 5 Ruumi kõrgus: 3 500
AC_Pset_RenovationAndPhasing - Renovation Status: New

# IfcSpace: Generic, 227
In: 2 korrus
Type - ElementType: Element type 227
LongName: Klass; InteriorOrExteriorSpace: INTERNAL; Classification: 1.15 IfcSpace (ruum) (_RKAS BIM + ARCHICAD Classification)
Pset_SpaceCommon - Category: Generic
RUUMID - 1 Nimetus: Klass; 2 Number: 227; 3 Kategooria: Generic; 4 Ruumi pindala: 62,5 Kasulik pindala: 62,5; 5 Ruumi kõrgus: 3 500
AC_Pset_RenovationAndPhasing - Renovation Status: New

# IfcSpace: Generic, 228
In: 2 korrus
Type - ElementType: Element type 228
LongName: Klass; InteriorOrExteriorSpace: INTERNAL; Classification: 1.15 IfcSpace (ruum) (_RKAS BIM + ARCHICAD Classification)
Pset_SpaceCommon - Category: Generic
RUUMID - 1 Nimetus: Klass; 2 Number: 228; 3 Kategooria: Generic; 4 Ruumi pindala: 68,6 Kasulik pindala: 68,6; 5 Ruumi kõrgus: 3 500
AC_Pset_RenovationAndPhasing - Renovation Status: New

# IfcSpace: Generic, 229
In: 2 korrus
Type - ElementType: Element type 229
LongName: Koridor/trepp/rekreatsioon; InteriorOrExteriorSpace: INTERNAL; Classification: 1.15 IfcSpace (ruum) (_RKAS BIM + ARCHICAD Classification)
Pset_SpaceCommon - Category: Generic
RUUMID - 1 Nimetus: Koridor/trepp/rekreatsioon; 2 Number: 229; 3 Kategooria: Generic; 4 Ruumi pindala: 58,2 Kasulik pindala: 58,2; 5 Ruumi kõrgus: 10 471
AC_Pset_RenovationAndPhasing - Renovation Status: New

# IfcSpace: Generic, 230
In: 2 korrus
Type - ElementType: Element type 230
LongName: Klass; InteriorOrExteriorSpace: INTERNAL; Classification: 1.15 IfcSpace (ruum) (_RKAS BIM + ARCHICAD Classification)
Pset_SpaceCommon - Category: Generic
RUUMID - 1 Nimetus: Klass; 2 Number: 230; 3 Kategooria: Generic; 4 Ruumi pindala: 62,0 Kasulik pindala: 62,0; 5 Ruumi kõrgus: 3 500
AC_Pset_RenovationAndPhasing - Renovation Status: New

# IfcSpace: Generic, 231
In: 2 korrus
Type - ElementType: Element type 231
LongName: Klass; InteriorOrExteriorSpace: INTERNAL; Classification: 1.15 IfcSpace (ruum) (_RKAS BIM + ARCHICAD Classification)
Pset_SpaceCommon - Category: Generic
RUUMID - 1 Nimetus: Klass; 2 Number: 231; 3 Kategooria: Generic; 4 Ruumi pindala: 61,8 Kasulik pindala: 61,8; 5 Ruumi kõrgus: 3 500
AC_Pset_RenovationAndPhasing - Renovation Status: New

# IfcSpace: Generic, 017
In: -1 korrus
Type - ElementType: Element type ZON - 015
LongName: Abiruum; InteriorOrExteriorSpace: INTERNAL; Classification: 1.15 IfcSpace (ruum) (_RKAS BIM + ARCHICAD Classification)
Pset_SpaceCommon - Category: Generic
RUUMID - 1 Nimetus: Abiruum; 2 Number: 017; 3 Kategooria: Generic; 4 Ruumi pindala: 4,2 Kasulik pindala: 4,2; 5 Ruumi kõrgus: 3 000
AC_Pset_RenovationAndPhasing - Renovation Status: New

# IfcSpace: Generic, 119
In: 1 korrus
Type - ElementType: Element type ZON - 041
LongName: Prügiruum; InteriorOrExteriorSpace: INTERNAL; Classification: 1.15 IfcSpace (ruum) (_RKAS BIM + ARCHICAD Classification)
Pset_SpaceCommon - Category: Generic
RUUMID - 1 Nimetus: Prügiruum; 2 Number: 119; 3 Kategooria: Generic; 4 Ruumi pindala: 16,1 Kasulik pindala: 16,1; 5 Ruumi kõrgus: 8 728
AC_Pset_RenovationAndPhasing - Renovation Status: New

# IfcSpace: Generic, 120
In: 1 korrus
Type - ElementType: Element type ZON - 042
LongName: Väliinventar; InteriorOrExteriorSpace: INTERNAL; Classification: 1.15 IfcSpace (ruum) (_RKAS BIM + ARCHICAD Classification)
Pset_SpaceCommon - Category: Generic
RUUMID - 1 Nimetus: Väliinventar; 2 Number: 120; 3 Kategooria: Generic; 4 Ruumi pindala: 15,6 Kasulik pindala: 15,6; 5 Ruumi kõrgus: 8 878
AC_Pset_RenovationAndPhasing - Renovation Status: New

# IfcBeam: Sarikas (24)
In: 2 korrus
Type - ElementType: Element type Sarikas
Classification: 1.1 IfcBeam (tala) (_RKAS BIM + ARCHICAD Classification); Material: Puit - Konstruktsioon
Ehituskonstruktsioonid - 01 Nimetus: Puit - Konstruktsioon; 02 Materjal: Puit - Konstruktsioon; 03 Tähistus või ristlõige: Sarikas; 06 Maht (kubatuur): 0,0; 11 Ülemine kõrgusmärk: 9 187; 12 Alumine kõrgusmärk: 9 187 - Tala paksus 150
AC_Pset_RenovationAndPhasing - Renovation Status: New
Pset_BeamCommon - LoadBearing: yes; IsExternal: yes; Reference: Puit - Konstruktsioon 50 x 150

# IfcBeam: T-11 (16)
Type - ElementType: Element type T-11
Classification: 1.1 IfcBeam (tala) (_RKAS BIM + ARCHICAD Classification); Material: Teras (musta värvi)
Ehituskonstruktsioonid - 02 Materjal: Teras (musta värvi); 03 Tähistus või ristlõige: T-11; 06 Maht (kubatuur): 0,0
AC_Pset_RenovationAndPhasing - Renovation Status: New
Pset_BeamCommon - LoadBearing: yes; IsExternal: yes
Name | In | 01 Nimetus | 11 Ülemine kõrgusmärk | 12 Alumine kõrgusmärk | Reference
2 x IPE 140 | 1 korrus | IPE 140 | 4 | 4 - Tala paksus 140 | IPE 140 73 x 140
Teras (musta värvi) | 1 korrus | Teras (musta värvi) | 99 | 99 - Tala paksus 480 | Teras (musta värvi) 5 x 480
2 x Teras (musta värvi) | 1,5 korrus | Teras (musta värvi) | 3 315 | 3 315 - Tala paksus 480 | Teras (musta värvi) 5 x 480
2 x Teras (musta värvi) | 1,5 korrus | Teras (musta värvi) | 5 195 | 5 195 - Tala paksus 480 | Teras (musta värvi) 20 x 480
4 x IPE 140 | 1,5 korrus | IPE 140 | 3 220 | 3 220 - Tala paksus 140 | IPE 140 73 x 140
2 x IPE 140 | 1,5 korrus | IPE 140 | 5 145 | 5 145 - Tala paksus 140 | IPE 140 73 x 140
IPE 140 | 1,5 korrus | IPE 140 | 3 080 | 3 080 - Tala paksus 140 | IPE 140 73 x 140
2 x IPE 140 | 1,5 korrus | IPE 140 | 5 005 | 5 005 - Tala paksus 140 | IPE 140 73 x 140

# IfcBeam: Tala (84)
Type - ElementType: Element type Tala
Classification: 1.1 IfcBeam (tala) (_RKAS BIM + ARCHICAD Classification)
Ehituskonstruktsioonid - 03 Tähistus või ristlõige: Tala
AC_Pset_RenovationAndPhasing - Renovation Status: New
Pset_BeamCommon - LoadBearing: yes
Name | In | Material | 01 Nimetus | 02 Materjal | 06 Maht (kubatuur) | 11 Ülemine kõrgusmärk | 12 Alumine kõrgusmärk | IsExternal | Reference | Slope (deg) | 01_Nimetus | 02_Materjal | 03_Ristloige | 04_Tugevusklass | 05_Keskkonnaklass | 06_Maht (m3) | 07_Mass | 08_Pikkus (mm) | 11_Ulemine korgusmark (mm) | 12_Alumine korgusmark (mm)
GENEERILINE - KONSTRUKTRIOON | 1 korrus | GENEERILINE - KONSTRUKTRIOON | GENEERILINE - KONSTRUKTRIOON | GENEERILINE - KONSTRUKTRIOON | 0,7 | 4 745 | 4 745 - Tala paksus 320 | no | GENEERILINE - KONSTRUKTRIOON 340 x 320
2 x GENEERILINE - KONSTRUKTRIOON | 1 korrus | GENEERILINE - KONSTRUKTRIOON | GENEERILINE - KONSTRUKTRIOON | GENEERILINE - KONSTRUKTRIOON | 0,8 | 4 745 | 4 745 - Tala paksus 320 | no | GENEERILINE - KONSTRUKTRIOON 340 x 320
GENEERILINE - KONSTRUKTRIOON | 1 korrus | GENEERILINE - KONSTRUKTRIOON | GENEERILINE - KONSTRUKTRIOON | GENEERILINE - KONSTRUKTRIOON | 0,0 | 4 745 | 4 745 - Tala paksus 320 | no | GENEERILINE - KONSTRUKTRIOON 140 x 320
Betoon - Konstuktsioon | 1 korrus | Betoon - Konstuktsioon | Betoon - Konstuktsioon | Betoon - Konstuktsioon | 0,6 | 4 745 | 4 745 - Tala paksus 140 | no | Betoon - Konstuktsioon 550 x 140
Betoon - Konstuktsioon | 1,5 korrus | Betoon - Konstuktsioon | Betoon - Konstuktsioon | Betoon - Konstuktsioon | 0,9 | 8 715 | 8 715 - Tala paksus 700 | no | Betoon - Konstuktsioon 420 x 700
3 x Betoon - Konstuktsioon | 1,5 korrus | Betoon - Konstuktsioon | Betoon - Konstuktsioon | Betoon - Konstuktsioon | 1,1 | 8 715 | 8 715 - Tala paksus 700 | no | Betoon - Konstuktsioon 420 x 700
5 x Betoon - Konstuktsioon | 1,5 korrus | Betoon - Konstuktsioon | Betoon - Konstuktsioon | Betoon - Konstuktsioon | 0,8 | 1 385 | 1 385 - Tala paksus 500 | no | Betoon - Konstuktsioon 420 x 500
5 x Betoon - Konstuktsioon | 1,5 korrus | Betoon - Konstuktsioon | Betoon - Konstuktsioon | Betoon - Konstuktsioon | 0,8 | 4 800 | 4 800 - Tala paksus 500 | no | Betoon - Konstuktsioon 420 x 500
Betoon - Konstuktsioon | 1,5 korrus | Betoon - Konstuktsioon | Betoon - Konstuktsioon | Betoon - Konstuktsioon | 1,9 | 4 800 | 4 800 - Tala paksus 500 | no | Betoon - Konstuktsioon 420 x 500
Betoon - Konstuktsioon | 1,5 korrus | Betoon - Konstuktsioon | Betoon - Konstuktsioon | Betoon - Konstuktsioon | 0,7 | 1 385 | 1 385 - Tala paksus 500 | no | Betoon - Konstuktsioon 420 x 500
3 x Betoon - Konstuktsioon | 1,5 korrus | Betoon - Konstuktsioon | Betoon - Konstuktsioon | Betoon - Konstuktsioon | 1,2 | 8 715 | 8 715 - Tala paksus 700 | no | Betoon - Konstuktsioon 420 x 700
Betoon - Konstuktsioon | 1,5 korrus | Betoon - Konstuktsioon | Betoon - Konstuktsioon | Betoon - Konstuktsioon | 0,7 | 4 800 | 4 800 - Tala paksus 500 | no | Betoon - Konstuktsioon 420 x 500
Betoon - Konstuktsioon | 1,5 korrus | Betoon - Konstuktsioon | Betoon - Konstuktsioon | Betoon - Konstuktsioon | 1,0 | 8 715 | 8 715 - Tala paksus 700 | no | Betoon - Konstuktsioon 420 x 700
Betoon - Konstuktsioon | 1,5 korrus | Betoon - Konstuktsioon | Betoon - Konstuktsioon | Betoon - Konstuktsioon | 0,6 | 8 715 | 8 715 - Tala paksus 700 | no | Betoon - Konstuktsioon 420 x 700
6 x Tala - teras - RHS:100x150x5:1643704 | 1,5 korrus | Teras (musta värvi) | 100x150x5 | Teras (musta värvi) | 0,0 | 150 | 150 - Tala paksus 100 | yes | 100x150x5 | 0 | Tala - teras - RHS | Teras, S355 | 100x150x5 | S355 | C3 | 0.0155784 | 122 | 6491 | 2500 | 2400
Betoon - Konstuktsioon | 1,5 korrus | Betoon - Konstuktsioon | Betoon - Konstuktsioon | Betoon - Konstuktsioon | 0,6 | 4 800 | 4 800 - Tala paksus 500 | no | Betoon - Konstuktsioon 420 x 500
2 x Tala - teras - RHS:100x150x5:1643704 | 1,5 korrus | Teras (musta värvi) (2) | 100x150x5 | Teras (musta värvi) | 0,0 | 150 | 150 - Tala paksus 100 | yes | 100x150x5 | 0 | Tala - teras - RHS | Teras, S355 | 100x150x5 | S355 | C3 | 0.0155784 | 122 | 6491 | 2500 | 2400
Betoon - Konstuktsioon | 1,5 korrus | Betoon - Konstuktsioon | Betoon - Konstuktsioon | Betoon - Konstuktsioon | 1,4 | 4 800 | 4 800 - Tala paksus 900 | no | Betoon - Konstuktsioon 340 x 900
Tala - teras - RHS:100x150x5:1653303 | 1,5 korrus | Teras (musta värvi) | Teras (musta värvi) | Teras (musta värvi) | 0,0 | 2 320 | 2 320 - Tala paksus 100 | yes | 100x150x5 | 0 | Tala - teras - RHS | Teras, S355 | 100x150x5 | S355 | C3 | 0.005616 | 44 | 2340 | 2500 | 2400
Tala - teras - RHS:100x150x5:1653280 | 1,5 korrus | Teras (musta värvi) (2) | Teras (musta värvi) | Teras (musta värvi) | 0,0 | 2 320 | 2 320 - Tala paksus 100 | yes | 100x150x5 | 0 | Tala - teras - RHS | Teras, S355 | 100x150x5 | S355 | C3 | 0.005616 | 44 | 2340 | 2500 | 2400
Tala - teras - RHS:100x150x5:1652662 | 1,5 korrus | Teras (musta värvi) | Teras (musta värvi) | Teras (musta värvi) | 0,0 | 2 320 | 2 320 - Tala paksus 100 | yes | 100x150x5 | 0 | Tala - teras - RHS | Teras, S355 | 100x150x5 | S355 | C3 | 0.005616 | 44 | 2340 | 2500 | 2400
Tala - teras - RHS:100x150x5:1652660 | 1,5 korrus | Teras (musta värvi) | Teras (musta värvi) | Teras (musta värvi) | 0,0 | 2 320 | 2 320 - Tala paksus 100 | yes | 100x150x5 | 0 | Tala - teras - RHS | Teras, S355 | 100x150x5 | S355 | C3 | 0.005616 | 44 | 2340 | 2500 | 2400
Tala - teras - RHS:100x150x5:1643704 | 1,5 korrus | Teras (musta värvi) (6) | 100x150x5 | Teras (musta värvi) | 0,1 | 2 270 | 2 270 - Tala paksus 100 | yes | 100x150x5 | 0 | Tala - teras - RHS | Teras, S355 | 100x150x5 | S355 | C3 | 0.0155784 | 122 | 6491 | 2500 | 2400
Tala - teras - RHS:100x150x5:1643702 | 1,5 korrus | Teras (musta värvi) (5) | 100x150x5 | Teras (musta värvi) | 0,1 | 2 270 | 2 270 - Tala paksus 100 | yes | 100x150x5 | 0 | Tala - teras - RHS | Teras, S355 | 100x150x5 | S355 | C3 | 0.0150744 | 118 | 6281 | 2500 | 2400
4 x Tala - teras - RHS:100x150x5:1652662 | 1,5 korrus | Teras (musta värvi) | Teras (musta värvi) | Teras (musta värvi) | 0,0 | 9 710 | 9 710 - Tala paksus 100 | yes | 100x150x5 | 0 | Tala - teras - RHS | Teras, S355 | 100x150x5 | S355 | C3 | 0.005616 | 44 | 2340 | 2500 | 2400
Tala - teras - RHS:100x150x5:1643704 | 1,5 korrus | Teras (musta värvi) | 100x150x5 | Teras (musta värvi) | 0,3 | 9 660 | 9 660 - Tala paksus 100 | yes | 100x150x5 | 0 | Tala - teras - RHS | Teras, S355 | 100x150x5 | S355 | C3 | 0.0155784 | 122 | 6491 | 2500 | 2400
Betoon - Konstuktsioon | 1,5 korrus | Betoon - Konstuktsioon | Betoon - Konstuktsioon | Betoon - Konstuktsioon | 1,3 | 8 715 | 8 715 - Tala paksus 700 | no | Betoon - Konstuktsioon 420 x 700
GENEERILINE - KONSTRUKTRIOON | 2 korrus | GENEERILINE - KONSTRUKTRIOON | GENEERILINE - KONSTRUKTRIOON | GENEERILINE - KONSTRUKTRIOON | 1,7 | 4 745 | 4 745 - Tala paksus 320 | no | GENEERILINE - KONSTRUKTRIOON 560 x 320
Tala - teras - SHS:150x150x5:1652076 | 2 korrus | Teras (musta värvi) | Teras (musta värvi) | Teras (musta värvi) | 0,1 | 4 800 | 4 800 - Tala paksus 150 | yes | 150x150x5 | 0 | Tala - teras - SHS | Teras, S355 | 150x150x5 | S355 | C3 | 0.006786 | 53 | 2340 | 4860 | 4710
Tala - teras - SHS:150x150x5:1652074 | 2 korrus | Teras (musta värvi) | Teras (musta värvi) | Teras (musta värvi) | 0,1 | 4 800 | 4 800 - Tala paksus 150 | yes | 150x150x5 | 0 | Tala - teras - SHS | Teras, S355 | 150x150x5 | S355 | C3 | 0.006786 | 53 | 2340 | 4860 | 4710
Tala - teras - SHS:150x150x5:1652072 | 2 korrus | Teras (musta värvi) | Teras (musta värvi) | Teras (musta värvi) | 0,1 | 4 800 | 4 800 - Tala paksus 150 | yes | 150x150x5 | 0 | Tala - teras - SHS | Teras, S355 | 150x150x5 | S355 | C3 | 0.006786 | 53 | 2340 | 4860 | 4710
Tala - teras - SHS:150x150x5:1652070 | 2 korrus | Teras (musta värvi) | Teras (musta värvi) | Teras (musta värvi) | 0,1 | 4 800 | 4 800 - Tala paksus 150 | yes | 150x150x5 | 0 | Tala - teras - SHS | Teras, S355 | 150x150x5 | S355 | C3 | 0.006786 | 53 | 2340 | 4860 | 4710
Tala - teras - SHS:150x150x5:1652068 | 2 korrus | Teras (musta värvi) | Teras (musta värvi) | Teras (musta värvi) | 0,0 | 4 800 | 4 800 - Tala paksus 150 | yes | 150x150x5 | 0 | Tala - teras - SHS | Teras, S355 | 150x150x5 | S355 | C3 | 0.0011107 | 9 | 383 | 4860 | 4710
Tala - teras - SHS:150x150x5:1652066 | 2 korrus | Teras (musta värvi) | Teras (musta värvi) | Teras (musta värvi) | 0,0 | 4 800 | 4 800 - Tala paksus 150 | yes | 150x150x5 | 0 | Tala - teras - SHS | Teras, S355 | 150x150x5 | S355 | C3 | 0.0011107 | 9 | 383 | 4860 | 4710
Tala - teras - SHS:150x150x5:1652064 | 2 korrus | Teras (musta värvi) | Teras (musta värvi) | Teras (musta värvi) | 0,0 | 4 800 | 4 800 - Tala paksus 150 | yes | 150x150x5 | 0 | Tala - teras - SHS | Teras, S355 | 150x150x5 | S355 | C3 | 0.0011107 | 9 | 383 | 4860 | 4710
Tala - teras - SHS:150x150x5:1652062 | 2 korrus | Teras (musta värvi) | Teras (musta värvi) | Teras (musta värvi) | 0,0 | 4 800 | 4 800 - Tala paksus 150 | yes | 150x150x5 | 0 | Tala - teras - SHS | Teras, S355 | 150x150x5 | S355 | C3 | 0.0011107 | 9 | 383 | 4860 | 4710
Tala - teras - SHS:150x150x5:1652060 | 2 korrus | Teras (musta värvi) | Teras (musta värvi) | Teras (musta värvi) | 0,1 | 4 800 | 4 800 - Tala paksus 150 | yes | 150x150x5 | 0 | Tala - teras - SHS | Teras, S355 | 150x150x5 | S355 | C3 | 0.006786 | 53 | 2340 | 4860 | 4710
Tala - teras - SHS:150x150x5:1652058 | 2 korrus | Teras (musta värvi) | Teras (musta värvi) | Teras (musta värvi) | 0,1 | 4 800 | 4 800 - Tala paksus 150 | yes | 150x150x5 | 0 | Tala - teras - SHS | Teras, S355 | 150x150x5 | S355 | C3 | 0.006786 | 53 | 2340 | 4860 | 4710
Tala - teras - SHS:150x150x5:1652052 | 2 korrus | Teras (musta värvi) | 150x150x5 (1) | Teras (musta värvi) | 0,2 | 4 725 | 4 725 - Tala paksus 150 | yes | 150x150x5 | 0 | Tala - teras - SHS | Teras, S355 | 150x150x5 | S355 | C3 | 0.0196939 | 155 | 6791 | 4860 | 4710
Tala - teras - SHS:150x150x5:1652056 | 2 korrus | Teras (musta värvi) | 150x150x5 (1) | Teras (musta värvi) | 0,1 | 7 790 | 7 790 - Tala paksus 150 | yes | 150x150x5 | 0 | Tala - teras - SHS | Teras, S355 | 150x150x5 | S355 | C3 | 0.0112636 | 88 | 3884 | 4860 | 4710
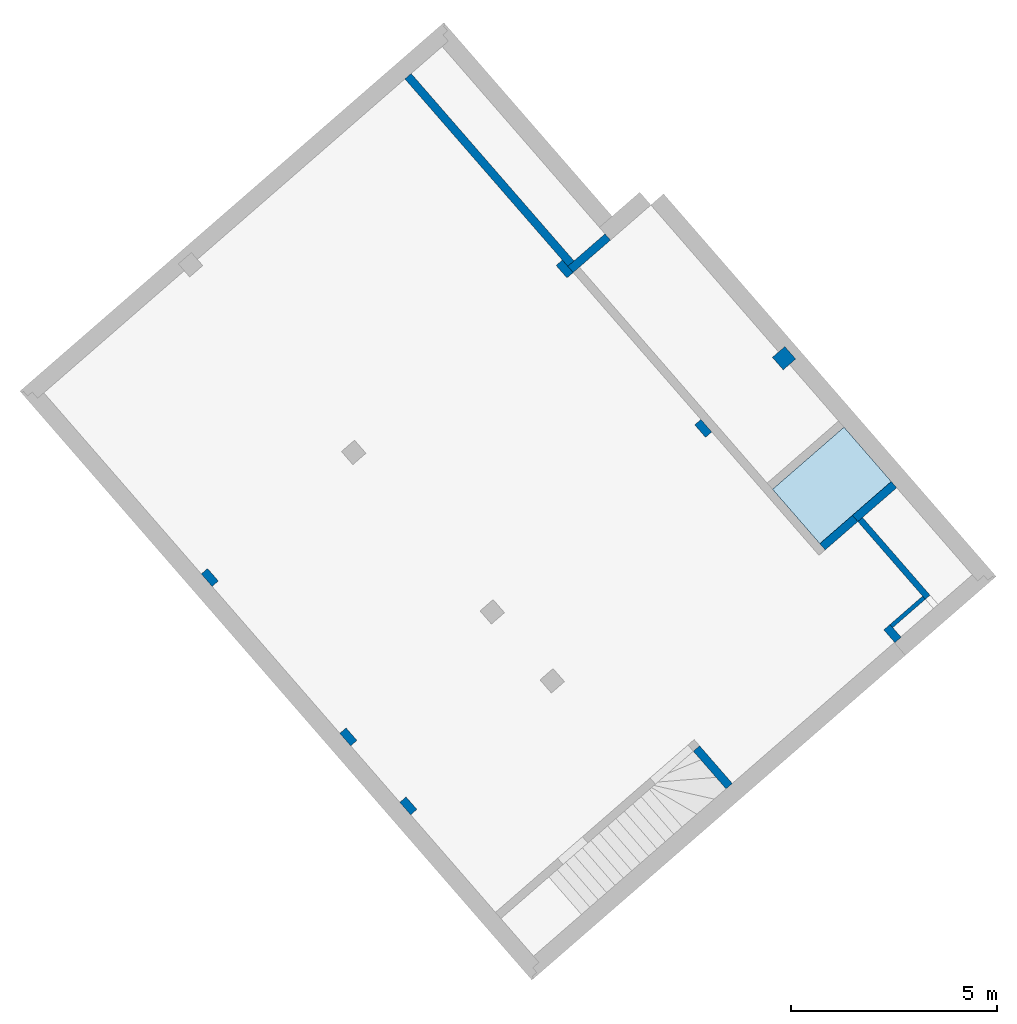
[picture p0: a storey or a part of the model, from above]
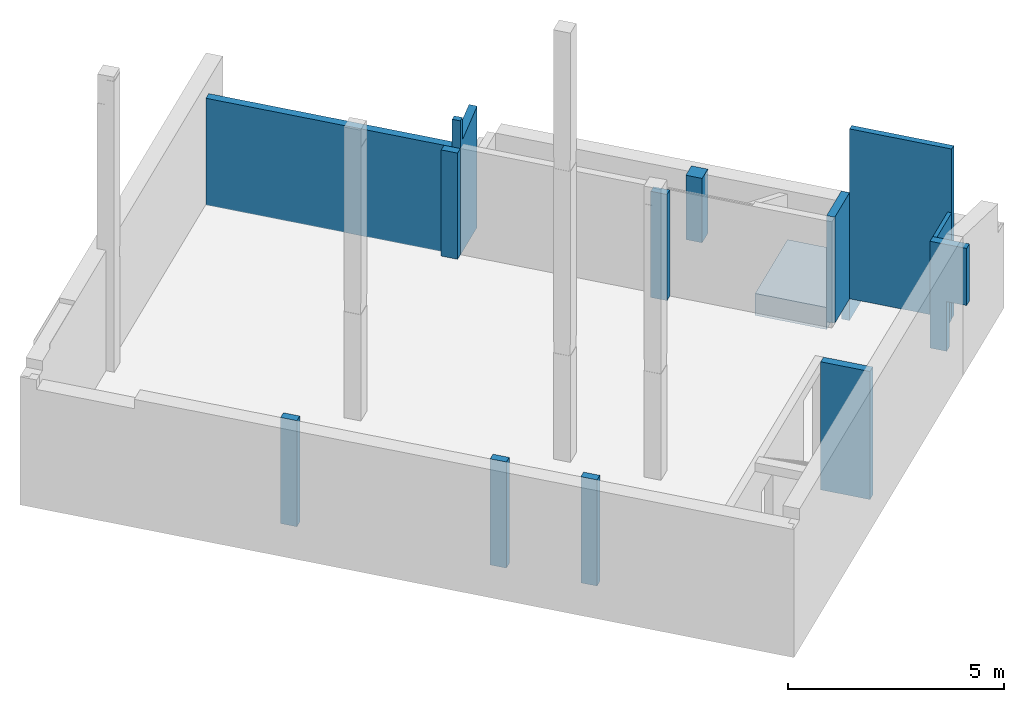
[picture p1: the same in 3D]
Properties of the parts of a building model (IFC2X3), part 2 of 13

# IfcBeam: Tala (84)
Name | In | Material | 01 Nimetus | 02 Materjal | 06 Maht (kubatuur) | 11 Ülemine kõrgusmärk | 12 Alumine kõrgusmärk | IsExternal | Reference | Slope (deg) | 01_Nimetus | 02_Materjal | 03_Ristloige | 04_Tugevusklass | 05_Keskkonnaklass | 06_Maht (m3) | 07_Mass | 08_Pikkus (mm) | 11_Ulemine korgusmark (mm) | 12_Alumine korgusmark (mm)
Tala - teras - SHS:150x150x5:1652050 | 2 korrus | Teras (musta värvi) (2) | 150x150x5 (1) | Teras (musta värvi) | 0,1 | 4 725 | 4 725 - Tala paksus 150 | yes | 150x150x5 | 0 | Tala - teras - SHS | Teras, S355 | 150x150x5 | S355 | C3 | 0.0196985 | 155 | 6792.6 | 4860 | 4710
Tala - teras - SHS:150x150x5:1652048 | 2 korrus | Teras (musta värvi) | 150x150x5 (1) | Teras (musta värvi) | 0,1 | 4 725 | 4 725 - Tala paksus 150 | yes | 150x150x5 | 0 | Tala - teras - SHS | Teras, S355 | 150x150x5 | S355 | C3 | 0.0190774 | 150 | 6578.4 | 4860 | 4710
Tala - teras - SHS:150x150x5:1652046 | 2 korrus | Teras (musta värvi) | 150x150x5 (1) | Teras (musta värvi) | 0,1 | 4 725 | 4 725 - Tala paksus 150 | yes | 150x150x5 | 0 | Tala - teras - SHS | Teras, S355 | 150x150x5 | S355 | C3 | 0.0190849 | 150 | 6581 | 4860 | 4710
Tala - teras - SHS:150x150x5:1652044 | 2 korrus | Teras (musta värvi) | Teras (musta värvi) | Teras (musta värvi) | 0,1 | 4 800 | 4 800 - Tala paksus 150 | yes | 150x150x5 | 0 | Tala - teras - SHS | Teras, S355 | 150x150x5 | S355 | C3 | 0.006786 | 53 | 2340 | 4860 | 4710
Tala - teras - SHS:150x150x5:1652042 | 2 korrus | Teras (musta värvi) | Teras (musta värvi) | Teras (musta värvi) | 0,1 | 4 800 | 4 800 - Tala paksus 150 | yes | 150x150x5 | 0 | Tala - teras - SHS | Teras, S355 | 150x150x5 | S355 | C3 | 0.006786 | 53 | 2340 | 4860 | 4710
Tala - teras - SHS:150x150x5:1651674 | Katus | Teras (musta värvi) | Teras (musta värvi) | Teras (musta värvi) | 0,1 | 8 878 | 8 878 - Tala paksus 150 | yes | 150x150x5 | 0 | Tala - teras - SHS | Teras, S355 | 150x150x5 | S355 | C3 | 0.006786 | 53 | 2340 | 8950 | 8800
Tala - teras - SHS:150x150x5:1651691 | Katus | Teras (musta värvi) | Teras (musta värvi) | Teras (musta värvi) | 0,1 | 8 878 | 8 878 - Tala paksus 150 | yes | 150x150x5 | 0 | Tala - teras - SHS | Teras, S355 | 150x150x5 | S355 | C3 | 0.006786 | 53 | 2340 | 8950 | 8800
Tala - teras - SHS:150x150x5:1651659 | Katus | Teras (musta värvi) | Teras (musta värvi) | Teras (musta värvi) | 0,1 | 8 878 | 8 878 - Tala paksus 150 | yes | 150x150x5 | 0 | Tala - teras - SHS | Teras, S355 | 150x150x5 | S355 | C3 | 0.006786 | 53 | 2340 | 8950 | 8800
Tala - teras - SHS:150x150x5:1650563 | Katus | Teras (musta värvi) | Teras (musta värvi) | Teras (musta värvi) | 0,0 | 8 878 | 8 878 - Tala paksus 150 | yes | 150x150x5 | 0 | Tala - teras - SHS | Teras, S355 | 150x150x5 | S355 | C3 | 0.0011107 | 9 | 383 | 8950 | 8800
Tala - teras - SHS:150x150x5:1651505 | Katus | Teras (musta värvi) | Teras (musta värvi) | Teras (musta värvi) | 0,1 | 8 878 | 8 878 - Tala paksus 150 | yes | 150x150x5 | 0 | Tala - teras - SHS | Teras, S355 | 150x150x5 | S355 | C3 | 0.006786 | 53 | 2340 | 8950 | 8800
Tala - teras - SHS:150x150x5:1650557 | Katus | Teras (musta värvi) | Teras (musta värvi) | Teras (musta värvi) | 0,0 | 8 878 | 8 878 - Tala paksus 150 | yes | 150x150x5 | 0 | Tala - teras - SHS | Teras, S355 | 150x150x5 | S355 | C3 | 0.0011107 | 9 | 383 | 8950 | 8800
Tala - teras - SHS:150x150x5:1650460 | Katus | Teras (musta värvi) | Teras (musta värvi) | Teras (musta värvi) | 0,0 | 8 878 | 8 878 - Tala paksus 150 | yes | 150x150x5 | 0 | Tala - teras - SHS | Teras, S355 | 150x150x5 | S355 | C3 | 0.0011107 | 9 | 383 | 8950 | 8800
Tala - teras - SHS:150x150x5:1650547 | Katus | Teras (musta värvi) | Teras (musta värvi) | Teras (musta värvi) | 0,0 | 8 878 | 8 878 - Tala paksus 150 | yes | 150x150x5 | 0 | Tala - teras - SHS | Teras, S355 | 150x150x5 | S355 | C3 | 0.0011107 | 9 | 383 | 8950 | 8800
Tala - teras - SHS:150x150x5:1648059 | Katus | Teras (musta värvi) | Teras (musta värvi) | Teras (musta värvi) | 0,1 | 8 878 | 8 878 - Tala paksus 150 | yes | 150x150x5 | 0 | Tala - teras - SHS | Teras, S355 | 150x150x5 | S355 | C3 | 0.006786 | 53 | 2340 | 8950 | 8800
Tala - teras - SHS:150x150x5:1643594 | Katus | Teras (musta värvi) | 150x150x5 (1) | Teras (musta värvi) | 0,1 | 8 803 | 8 803 - Tala paksus 150 | yes | 150x150x5 | 0 | Tala - teras - SHS | Teras, S355 | 150x150x5 | S355 | C3 | 0.0112636 | 88 | 3884 | 8950 | 8800
Tala - teras - SHS:150x150x5:1648046 | Katus | Teras (musta värvi) | Teras (musta värvi) | Teras (musta värvi) | 0,1 | 8 878 | 8 878 - Tala paksus 150 | yes | 150x150x5 | 0 | Tala - teras - SHS | Teras, S355 | 150x150x5 | S355 | C3 | 0.006786 | 53 | 2340 | 8950 | 8800
Tala - teras - SHS:150x150x5:1643590 | Katus | Teras (musta värvi) | 150x150x5 (1) | Teras (musta värvi) | 0,2 | 8 803 | 8 803 - Tala paksus 150 | yes | 150x150x5 | 0 | Tala - teras - SHS | Teras, S355 | 150x150x5 | S355 | C3 | 0.0196939 | 155 | 6791 | 8950 | 8800
Tala - teras - SHS:150x150x5:1643586 | Katus | Teras (musta värvi) | 150x150x5 (1) | Teras (musta värvi) | 0,1 | 8 803 | 8 803 - Tala paksus 150 | yes | 150x150x5 | 0 | Tala - teras - SHS | Teras, S355 | 150x150x5 | S355 | C3 | 0.0190774 | 150 | 6578.4 | 8950 | 8800
Tala - teras - SHS:150x150x5:1643588 | Katus | Teras (musta värvi) | 150x150x5 (1) | Teras (musta värvi) | 0,1 | 8 803 | 8 803 - Tala paksus 150 | yes | 150x150x5 | 0 | Tala - teras - SHS | Teras, S355 | 150x150x5 | S355 | C3 | 0.0196985 | 155 | 6792.6 | 8950 | 8800
Tala - teras - SHS:150x150x5:1643584 | Katus | Teras (musta värvi) | 150x150x5 (1) | Teras (musta värvi) | 0,1 | 8 803 | 8 803 - Tala paksus 150 | yes | 150x150x5 | 0 | Tala - teras - SHS | Teras, S355 | 150x150x5 | S355 | C3 | 0.0190849 | 150 | 6581 | 8950 | 8800
Tala - teras - SHS:150x150x5:1643502 | Katus | Teras (musta värvi) | Teras (musta värvi) | Teras (musta värvi) | 0,1 | 8 878 | 8 878 - Tala paksus 150 | yes | 150x150x5 | 0 | Tala - teras - SHS | Teras, S355 | 150x150x5 | S355 | C3 | 0.006786 | 53 | 2340 | 8950 | 8800
Tala - teras - SHS:150x150x5:1643535 | Katus | Teras (musta värvi) | Teras (musta värvi) | Teras (musta värvi) | 0,1 | 8 878 | 8 878 - Tala paksus 150 | yes | 150x150x5 | 0 | Tala - teras - SHS | Teras, S355 | 150x150x5 | S355 | C3 | 0.006786 | 53 | 2340 | 8950 | 8800

# IfcBuildingElementProxy: BMR - 052 (12)
In: 1 korrus
Type - ElementType: Element type BMR - 052
Material: Teras (musta värvi)
SEADMED - 02 Tähis: BMR - 052
AC_Pset_RenovationAndPhasing - Renovation Status: New

# IfcBuildingElementProxy: BMR - 054 (4)
In: 2 korrus
Type - ElementType: Element type BMR - 054
Material: Puit - Konstruktsioon
SEADMED - 02 Tähis: BMR - 054
AC_Pset_RenovationAndPhasing - Renovation Status: New

# IfcBuildingElementProxy: Frame-Bnd-441, Aluminium MUST; Objekti nimi: Modular Frame 22
In: 1,5 korrus
Type - ElementType: Element type Frame-Bnd-441
Material: Aluminium MUST (3)
SEADMED - 02 Tähis: Frame-Bnd-441
AC_Pset_RenovationAndPhasing - Renovation Status: New

# IfcBuildingElementProxy: Frame-Bnd-442, Aluminium MUST; Objekti nimi: Modular Frame 22
In: 1,5 korrus
Type - ElementType: Element type Frame-Bnd-442
Material: Aluminium MUST (3)
SEADMED - 02 Tähis: Frame-Bnd-442
AC_Pset_RenovationAndPhasing - Renovation Status: New

# IfcBuildingElementProxy: Frame-Bnd-443, Aluminium MUST; Objekti nimi: Modular Frame 22
In: 1,5 korrus
Type - ElementType: Element type Frame-Bnd-443
Material: Aluminium MUST (3)
SEADMED - 02 Tähis: Frame-Bnd-443
AC_Pset_RenovationAndPhasing - Renovation Status: New

# IfcBuildingElementProxy: Frame-Bnd-444, Aluminium MUST; Objekti nimi: Modular Frame 22
In: 1,5 korrus
Type - ElementType: Element type Frame-Bnd-444
Material: Aluminium MUST (3)
SEADMED - 02 Tähis: Frame-Bnd-444
AC_Pset_RenovationAndPhasing - Renovation Status: New

# IfcBuildingElementProxy: Frame-Bnd-445, Aluminium MUST; Objekti nimi: Modular Frame 22
In: 1,5 korrus
Type - ElementType: Element type Frame-Bnd-445
Material: Aluminium MUST (3)
SEADMED - 02 Tähis: Frame-Bnd-445
AC_Pset_RenovationAndPhasing - Renovation Status: New

# IfcBuildingElementProxy: Frame-Bnd-446, Aluminium MUST; Objekti nimi: Modular Frame 22
In: 1,5 korrus
Type - ElementType: Element type Frame-Bnd-446
Material: Aluminium MUST (3)
SEADMED - 02 Tähis: Frame-Bnd-446
AC_Pset_RenovationAndPhasing - Renovation Status: New

# IfcBuildingElementProxy: Frame-Mll-330, Aluminium MUST; Objekti nimi: Frame 22
In: 1,5 korrus
Type - ElementType: Element type Frame-Mll-330
Material: Aluminium MUST (2)
SEADMED - 02 Tähis: Frame-Mll-330
AC_Pset_RenovationAndPhasing - Renovation Status: New

# IfcBuildingElementProxy: SLA - 001, Default; Objekti nimi:
In: 1 korrus
Type - ElementType: Element type SLA - 001
Material: Default
SEADMED - 02 Tähis: SLA - 001
AC_Pset_RenovationAndPhasing - Renovation Status: New

# IfcColumn: Post (82)
Type - ElementType: Element type Post
Ehituskonstruktsioonid - 03 Tähistus või ristlõige: Post
AC_Pset_RenovationAndPhasing - Renovation Status: New
Name | In | Classification | Material | 01 Nimetus | 06 Maht (kubatuur) | 11 Ülemine kõrgusmärk | 12 Alumine kõrgusmärk | LoadBearing | IsExternal | Reference
Betoon - Konstuktsioon | -1 korrus | 1.3 IfcColumn (post) (_RKAS BIM + ARCHICAD Classification); 0 TELLIJA KULUD (EHITUSKULUDE LIIGITAMINE EVS 885:2005) | Betoon - Konstuktsioon, Krohv - Lubjakivi (2) | Betoon - Konstuktsioon | 2,1 | -3 435 + Posti kõrgus: 12 150 | -3 435 | yes | no | Betoon - Konstuktsioon 400 x 400
5 x Betoon - Konstuktsioon | -1 korrus | 1.3 IfcColumn (post) (_RKAS BIM + ARCHICAD Classification) | Betoon - Konstuktsioon | Betoon - Konstuktsioon | 0,2 | -3 415 + Posti kõrgus: 3 000 | -3 415 | yes | no | Betoon - Konstuktsioon 200 x 400
Betoon - Konstuktsioon | -1 korrus | 1.3 IfcColumn (post) (_RKAS BIM + ARCHICAD Classification); 0 TELLIJA KULUD (EHITUSKULUDE LIIGITAMINE EVS 885:2005) | Betoon - Konstuktsioon, Krohv - Lubjakivi (2) | Betoon - Konstuktsioon | 1,4 | -3 435 + Posti kõrgus: 8 235 | -3 435 | yes | no | Betoon - Konstuktsioon 400 x 400
Betoon - Konstuktsioon | -1 korrus | 1.3 IfcColumn (post) (_RKAS BIM + ARCHICAD Classification) | Betoon - Konstuktsioon, Krohv - Lubjakivi (2) | Betoon - Konstuktsioon | 1,4 | -3 435 + Posti kõrgus: 8 235 | -3 435 | yes | no | Betoon - Konstuktsioon 400 x 400
Betoon - Konstuktsioon | -1 korrus | 1.3 IfcColumn (post) (_RKAS BIM + ARCHICAD Classification); 0 TELLIJA KULUD (EHITUSKULUDE LIIGITAMINE EVS 885:2005) | Betoon - Konstuktsioon | Betoon - Konstuktsioon | 0,3 | -3 435 + Posti kõrgus: 1 820 | -3 435 | yes | no | Betoon - Konstuktsioon 400 x 400
Betoon - Konstuktsioon | -1 korrus | 1.3 IfcColumn (post) (_RKAS BIM + ARCHICAD Classification); 0 TELLIJA KULUD (EHITUSKULUDE LIIGITAMINE EVS 885:2005) | Betoon - Konstuktsioon, Krohv - Lubjakivi | Betoon - Konstuktsioon | 1,5 | -3 435 + Posti kõrgus: 8 350 | -3 435 | yes | yes | Betoon - Konstuktsioon 400 x 400
3 x Teras (musta värvi) | 0 korrus | 1.3 IfcColumn (post) (_RKAS BIM + ARCHICAD Classification); 0 TELLIJA KULUD (EHITUSKULUDE LIIGITAMINE EVS 885:2005) | Teras (musta värvi) | Teras (musta värvi) | 0,1 | -1 615 + Posti kõrgus: 2 550 | -1 615 |  |  | Teras (musta värvi) 150 x 150
Betoon - Konstuktsioon | 0 korrus | 1.3 IfcColumn (post) (_RKAS BIM + ARCHICAD Classification); 0 TELLIJA KULUD (EHITUSKULUDE LIIGITAMINE EVS 885:2005) | Betoon - Konstuktsioon, Krohv - Lubjakivi | Betoon - Konstuktsioon | 1,8 | -1 615 + Posti kõrgus: 10 330 | -1 615 | yes | no | Betoon - Konstuktsioon 400 x 400
Betoon - Konstuktsioon | 1 korrus | 1.3 IfcColumn (post) (_RKAS BIM + ARCHICAD Classification); 0 TELLIJA KULUD (EHITUSKULUDE LIIGITAMINE EVS 885:2005) | Betoon - Konstuktsioon, Krohv - Lubjakivi | Betoon - Konstuktsioon | 0,4 | 0 + Posti kõrgus: 4 100 | 0 | yes | yes | Betoon - Konstuktsioon 300 x 300
Betoon - Konstuktsioon | 1 korrus | 1.3 IfcColumn (post) (_RKAS BIM + ARCHICAD Classification); 0 TELLIJA KULUD (EHITUSKULUDE LIIGITAMINE EVS 885:2005) | Betoon - Konstuktsioon, Krohv - Lubjakivi | Betoon - Konstuktsioon | 0,9 | -400 + Posti kõrgus: 5 200 | -400 | yes | yes | Betoon - Konstuktsioon 400 x 400
2 x Betoon - Konstuktsioon | 1 korrus | 1.3 IfcColumn (post) (_RKAS BIM + ARCHICAD Classification); 0 TELLIJA KULUD (EHITUSKULUDE LIIGITAMINE EVS 885:2005) | Betoon - Konstuktsioon, Krohv - Lubjakivi | Betoon - Konstuktsioon | 0,8 | -20 + Posti kõrgus: 4 765 | -20 | yes | no | Betoon - Konstuktsioon 400 x 400
Betoon - Konstuktsioon | 1 korrus | 1.3 IfcColumn (post) (_RKAS BIM + ARCHICAD Classification); 0 TELLIJA KULUD (EHITUSKULUDE LIIGITAMINE EVS 885:2005) | Betoon - Konstuktsioon, Krohv - Lubjakivi | Betoon - Konstuktsioon | 0,8 | -20 + Posti kõrgus: 4 800 | -20 | yes | no | Betoon - Konstuktsioon 400 x 400
Betoon - Konstuktsioon | 1 korrus | 1.3 IfcColumn (post) (_RKAS BIM + ARCHICAD Classification) | Betoon - Konstuktsioon | Betoon - Konstuktsioon | 1,6 | 8 715 + Posti kõrgus: | 8 715 | yes | no
Betoon - Konstuktsioon | 1 korrus | 1.3 IfcColumn (post) (_RKAS BIM + ARCHICAD Classification) | Betoon - Konstuktsioon, Krohv - Lubjakivi | Betoon - Konstuktsioon | 0,5 | 0 + Posti kõrgus: 4 800 | 0 | yes | no | Betoon - Konstuktsioon 300 x 325
Betoon - Konstuktsioon | 1 korrus | 1.3 IfcColumn (post) (_RKAS BIM + ARCHICAD Classification); 0 TELLIJA KULUD (EHITUSKULUDE LIIGITAMINE EVS 885:2005) | Betoon - Konstuktsioon, Krohv - Lubjakivi | Betoon - Konstuktsioon | 0,8 | 0 + Posti kõrgus: 4 800 | 0 | yes | no | Betoon - Konstuktsioon 400 x 400
4 x Betoon - Konstuktsioon | 1 korrus | 1.3 IfcColumn (post) (_RKAS BIM + ARCHICAD Classification); 0 TELLIJA KULUD (EHITUSKULUDE LIIGITAMINE EVS 885:2005) | Betoon - Konstuktsioon, Krohv - Lubjakivi | Betoon - Konstuktsioon | 0,2 | -600 + Posti kõrgus: 2 770 | -600 | yes | no | Betoon - Konstuktsioon 320 x 200
Betoon - Konstuktsioon | 1 korrus | 1.3 IfcColumn (post) (_RKAS BIM + ARCHICAD Classification); 0 TELLIJA KULUD (EHITUSKULUDE LIIGITAMINE EVS 885:2005) | Betoon - Konstuktsioon, Krohv - Lubjakivi | Betoon - Konstuktsioon | 0,4 | -600 + Posti kõrgus: 2 770 | -600 | yes | no | Betoon - Konstuktsioon 794 x 200
Betoon - Konstuktsioon | 1 korrus | 1.3 IfcColumn (post) (_RKAS BIM + ARCHICAD Classification); 0 TELLIJA KULUD (EHITUSKULUDE LIIGITAMINE EVS 885:2005) | Betoon - Konstuktsioon, Krohv - Lubjakivi | Betoon - Konstuktsioon | 0,9 | -20 + Posti kõrgus: 4 820 | -20 | yes | no | Betoon - Konstuktsioon 400 x 400
Betoon - Konstuktsioon | 1 korrus | 1.3 IfcColumn (post) (_RKAS BIM + ARCHICAD Classification); 0 TELLIJA KULUD (EHITUSKULUDE LIIGITAMINE EVS 885:2005) | Betoon - Konstuktsioon, Krohv - Lubjakivi | Betoon - Konstuktsioon | 0,8 | -20 + Posti kõrgus: 4 820 | -20 | yes | no | Betoon - Konstuktsioon 400 x 400
Betoon - Konstuktsioon | 1 korrus | 1.3 IfcColumn (post) (_RKAS BIM + ARCHICAD Classification); 0 TELLIJA KULUD (EHITUSKULUDE LIIGITAMINE EVS 885:2005) | Betoon - Konstuktsioon, Krohv - Lubjakivi | Betoon - Konstuktsioon | 0,2 | -20 + Posti kõrgus: 2 320 | -20 | yes | no | Betoon - Konstuktsioon 300 x 300
Betoon - Konstuktsioon | 1 korrus | 1.3 IfcColumn (post) (_RKAS BIM + ARCHICAD Classification); 0 TELLIJA KULUD (EHITUSKULUDE LIIGITAMINE EVS 885:2005) | Betoon - Konstuktsioon, Krohv - Lubjakivi (3) | Betoon - Konstuktsioon | 0,8 | -20 + Posti kõrgus: 4 820 | -20 | yes | no | Betoon - Konstuktsioon 400 x 400
Betoon - Konstuktsioon | 1 korrus | 1.3 IfcColumn (post) (_RKAS BIM + ARCHICAD Classification) | Betoon - Konstuktsioon, Krohv - Lubjakivi | Betoon - Konstuktsioon | 0,8 | -20 + Posti kõrgus: 4 820 | -20 | yes | no | Betoon - Konstuktsioon 400 x 400
Betoon - Konstuktsioon | 1 korrus | 1.3 IfcColumn (post) (_RKAS BIM + ARCHICAD Classification); 0 TELLIJA KULUD (EHITUSKULUDE LIIGITAMINE EVS 885:2005) | Betoon - Konstuktsioon, Krohv - Lubjakivi (2) | Betoon - Konstuktsioon | 0,8 | -20 + Posti kõrgus: 4 820 | -20 | yes | no | Betoon - Konstuktsioon 400 x 400
Betoon - Konstuktsioon | 1 korrus | 1.3 IfcColumn (post) (_RKAS BIM + ARCHICAD Classification); 0 TELLIJA KULUD (EHITUSKULUDE LIIGITAMINE EVS 885:2005) | Betoon - Konstuktsioon, Krohv - Lubjakivi | Betoon - Konstuktsioon | 0,9 | -600 + Posti kõrgus: 5 345 | -600 | yes | no | Betoon - Konstuktsioon 400 x 400
Betoon - Konstuktsioon | 1 korrus | 1.3 IfcColumn (post) (_RKAS BIM + ARCHICAD Classification); 0 TELLIJA KULUD (EHITUSKULUDE LIIGITAMINE EVS 885:2005) | Betoon - Konstuktsioon, Krohv - Lubjakivi | Betoon - Konstuktsioon | 0,8 | -20 + Posti kõrgus: 4 765 | -20 | yes | yes | Betoon - Konstuktsioon 400 x 400
Betoon - Konstuktsioon | 1 korrus | 1.3 IfcColumn (post) (_RKAS BIM + ARCHICAD Classification); 0 TELLIJA KULUD (EHITUSKULUDE LIIGITAMINE EVS 885:2005) | Betoon - Konstuktsioon, Krohv - Lubjakivi | Betoon - Konstuktsioon | 0,8 | -20 + Posti kõrgus: 4 765 | -20 |  |  | Betoon - Konstuktsioon 400 x 400
GENEERILINE - KONSTRUKTRIOON | 1 korrus | 1.3 IfcColumn (post) (_RKAS BIM + ARCHICAD Classification) | GENEERILINE - KONSTRUKTRIOON | GENEERILINE - KONSTRUKTRIOON | 0,5 | 4 800 + Posti kõrgus: | 4 800 | no | no
Betoon - Konstuktsioon | 1 korrus | 1.3 IfcColumn (post) (_RKAS BIM + ARCHICAD Classification) | Betoon - Konstuktsioon | Betoon - Konstuktsioon | 0,3 | 2 775 + Posti kõrgus: | 2 775 | yes | no
Betoon - Konstuktsioon | 1 korrus | 1.3 IfcColumn (post) (_RKAS BIM + ARCHICAD Classification); 0 TELLIJA KULUD (EHITUSKULUDE LIIGITAMINE EVS 885:2005) | Betoon - Konstuktsioon | Betoon - Konstuktsioon | 0,3 | 2 775 + Posti kõrgus: | 2 775 | yes | no
Teras (musta värvi) | 1 korrus | 1.3 IfcColumn (post) (_RKAS BIM + ARCHICAD Classification) | Teras (musta värvi), Krohv - Lubjakivi (3) | Teras (musta värvi) | 0,1 | -620 + Posti kõrgus: 3 520 | -620 | yes | no | Teras (musta värvi) 300 x 300
Teras (musta värvi) | 1 korrus | 1.3 IfcColumn (post) (_RKAS BIM + ARCHICAD Classification) | Teras (musta värvi), Krohv - Lubjakivi | Teras (musta värvi) | 0,3 | -620 + Posti kõrgus: 3 520 | -620 | yes | no | Teras (musta värvi) 200 x 340
Post - teras - SHS:150x150x5:1650512 | 1 korrus | 1.3 IfcColumn (post) (_RKAS BIM + ARCHICAD Classification) | Teras (musta värvi) | 150x150x5 | 0,0 | -500 + Posti kõrgus: 9 228 | -500 | yes | yes | 150x150x5 | KONSTRUKTSIOON - 01_Nimetus: Post - teras - SHS; 02_Materjal: Teras, S355; 03_Ristloige: 150x150x5; 04_Tugevusklass: S355; 05_Keskkonnaklass: C3; 06_Maht: 0.015109 m3; 07_Mass: 115; 08_Pikkus: 5210 mm; 11_Ulemine korgusmark: 4710 mm; 12_Alumine korgusmark: -500 mm
Post - teras - SHS:150x150x5:1650528 | 1 korrus | 1.3 IfcColumn (post) (_RKAS BIM + ARCHICAD Classification) | Teras (musta värvi) | 150x150x5 | 0,0 | -500 + Posti kõrgus: 9 228 | -500 | yes | yes | 150x150x5 | KONSTRUKTSIOON - 01_Nimetus: Post - teras - SHS; 02_Materjal: Teras, S355; 03_Ristloige: 150x150x5; 04_Tugevusklass: S355; 05_Keskkonnaklass: C3; 06_Maht: 0.015109 m3; 07_Mass: 115; 08_Pikkus: 5210 mm; 11_Ulemine korgusmark: 4710 mm; 12_Alumine korgusmark: -500 mm
Post - teras - SHS:150x150x5:1650526 | 1 korrus | 1.3 IfcColumn (post) (_RKAS BIM + ARCHICAD Classification) | Teras (musta värvi) | 150x150x5 | 0,0 | -500 + Posti kõrgus: 5 150 | -500 | yes | yes | 150x150x5 | KONSTRUKTSIOON - 01_Nimetus: Post - teras - SHS; 02_Materjal: Teras, S355; 03_Ristloige: 150x150x5; 04_Tugevusklass: S355; 05_Keskkonnaklass: C3; 06_Maht: 0.015109 m3; 07_Mass: 115; 08_Pikkus: 5210 mm; 11_Ulemine korgusmark: 4710 mm; 12_Alumine korgusmark: -500 mm
Post - teras - SHS:150x150x5:1650510 | 1 korrus | 1.3 IfcColumn (post) (_RKAS BIM + ARCHICAD Classification) | Teras (musta värvi) | 150x150x5 | 0,0 | -500 + Posti kõrgus: 5 210 | -500 | yes | yes | 150x150x5 | KONSTRUKTSIOON - 01_Nimetus: Post - teras - SHS; 02_Materjal: Teras, S355; 03_Ristloige: 150x150x5; 04_Tugevusklass: S355; 05_Keskkonnaklass: C3; 06_Maht: 0.015109 m3; 07_Mass: 115; 08_Pikkus: 5210 mm; 11_Ulemine korgusmark: 4710 mm; 12_Alumine korgusmark: -500 mm
Post - teras - SHS:150x150x5:1650494 | 1 korrus | 1.3 IfcColumn (post) (_RKAS BIM + ARCHICAD Classification) | Teras (musta värvi) | 150x150x5 | 0,0 | -500 + Posti kõrgus: 5 150 | -500 | yes | yes | 150x150x5 | KONSTRUKTSIOON - 01_Nimetus: Post - teras - SHS; 02_Materjal: Teras, S355; 03_Ristloige: 150x150x5; 04_Tugevusklass: S355; 05_Keskkonnaklass: C3; 06_Maht: 0.015109 m3; 07_Mass: 115; 08_Pikkus: 5210 mm; 11_Ulemine korgusmark: 4710 mm; 12_Alumine korgusmark: -500 mm
Post - teras - SHS:150x150x5:1650496 | 1 korrus | 1.3 IfcColumn (post) (_RKAS BIM + ARCHICAD Classification) | Teras (musta värvi) | 150x150x5 | 0,0 | -500 + Posti kõrgus: 5 210 | -500 | yes | yes | 150x150x5 | KONSTRUKTSIOON - 01_Nimetus: Post - teras - SHS; 02_Materjal: Teras, S355; 03_Ristloige: 150x150x5; 04_Tugevusklass: S355; 05_Keskkonnaklass: C3; 06_Maht: 0.015109 m3; 07_Mass: 115; 08_Pikkus: 5210 mm; 11_Ulemine korgusmark: 4710 mm; 12_Alumine korgusmark: -500 mm
Post - teras - RHS:150x100x5:1643691 | 1 korrus | 1.3 IfcColumn (post) (_RKAS BIM + ARCHICAD Classification) | Teras (musta värvi) | 150x100x5 | 0,0 | -500 + Posti kõrgus: 5 150 | -500 | yes | yes | 150x100x5 | KONSTRUKTSIOON - 01_Nimetus: Post - teras - RHS; 02_Materjal: Teras, S355; 03_Ristloige: 150x100x5; 04_Tugevusklass: S355; 05_Keskkonnaklass: C3; 06_Maht: 0.012504 m3; 07_Mass: 95; 08_Pikkus: 5210 mm; 11_Ulemine korgusmark: 4710 mm; 12_Alumine korgusmark: -500 mm
Post - teras - RHS:150x100x5:1643688 | 1 korrus | 1.3 IfcColumn (post) (_RKAS BIM + ARCHICAD Classification) | Teras (musta värvi) | 150x100x5 | 0,0 | -500 + Posti kõrgus: 5 150 | -500 | yes | yes | 150x100x5 | KONSTRUKTSIOON - 01_Nimetus: Post - teras - RHS; 02_Materjal: Teras, S355; 03_Ristloige: 150x100x5; 04_Tugevusklass: S355; 05_Keskkonnaklass: C3; 06_Maht: 0.012504 m3; 07_Mass: 95; 08_Pikkus: 5210 mm; 11_Ulemine korgusmark: 4710 mm; 12_Alumine korgusmark: -500 mm
Post - teras - RHS:150x100x5:1643681 | 1 korrus | 1.3 IfcColumn (post) (_RKAS BIM + ARCHICAD Classification) | Teras (musta värvi) | 150x100x5 | 0,0 | -500 + Posti kõrgus: 5 210 | -500 | yes | yes | 150x100x5 | KONSTRUKTSIOON - 01_Nimetus: Post - teras - RHS; 02_Materjal: Teras, S355; 03_Ristloige: 150x100x5; 04_Tugevusklass: S355; 05_Keskkonnaklass: C3; 06_Maht: 0.012504 m3; 07_Mass: 95; 08_Pikkus: 5210 mm; 11_Ulemine korgusmark: 4710 mm; 12_Alumine korgusmark: -500 mm
Post - teras - RHS:150x100x5:1643673 | 1 korrus | 1.3 IfcColumn (post) (_RKAS BIM + ARCHICAD Classification) | Teras (musta värvi) | 150x100x5 | 0,0 | -500 + Posti kõrgus: 5 210 | -500 | yes | yes | 150x100x5 | KONSTRUKTSIOON - 01_Nimetus: Post - teras - RHS; 02_Materjal: Teras, S355; 03_Ristloige: 150x100x5; 04_Tugevusklass: S355; 05_Keskkonnaklass: C3; 06_Maht: 0.012504 m3; 07_Mass: 95; 08_Pikkus: 5210 mm; 11_Ulemine korgusmark: 4710 mm; 12_Alumine korgusmark: -500 mm; Pset_ColumnCommon - Slope: 0 deg
Post - teras - SHS:150x150x5:1634704 | 1 korrus | 1.3 IfcColumn (post) (_RKAS BIM + ARCHICAD Classification) | Teras (musta värvi) | 150x150x5 | 0,0 | -500 + Posti kõrgus: 5 210 | -500 | yes | yes | 150x150x5 | KONSTRUKTSIOON - 01_Nimetus: Post - teras - SHS; 02_Materjal: Teras, S355; 03_Ristloige: 150x150x5; 04_Tugevusklass: S355; 05_Keskkonnaklass: C3; 06_Maht: 0.015109 m3; 07_Mass: 115; 08_Pikkus: 5210 mm; 11_Ulemine korgusmark: 4710 mm; 12_Alumine korgusmark: -500 mm
Post - teras - SHS:150x150x5:1634688 | 1 korrus | 1.3 IfcColumn (post) (_RKAS BIM + ARCHICAD Classification) | Teras (musta värvi) | 150x150x5 | 0,0 | -500 + Posti kõrgus: 5 150 | -500 | yes | yes | 150x150x5 | KONSTRUKTSIOON - 01_Nimetus: Post - teras - SHS; 02_Materjal: Teras, S355; 03_Ristloige: 150x150x5; 04_Tugevusklass: S355; 05_Keskkonnaklass: C3; 06_Maht: 0.015109 m3; 07_Mass: 115; 08_Pikkus: 5210 mm; 11_Ulemine korgusmark: 4710 mm; 12_Alumine korgusmark: -500 mm; Pset_ColumnCommon - Slope: 0 deg
Teras (musta värvi) | 1,5 korrus | 1.3 IfcColumn (post) (_RKAS BIM + ARCHICAD Classification); 0 TELLIJA KULUD (EHITUSKULUDE LIIGITAMINE EVS 885:2005) | Teras (musta värvi) | Teras (musta värvi) | 0,1 | 1 780 + Posti kõrgus: 2 520 | 1 780 |  |  | Teras (musta värvi) 150 x 150
Betoon - Konstuktsioon | 2 korrus | 1.3 IfcColumn (post) (_RKAS BIM + ARCHICAD Classification); 0 TELLIJA KULUD (EHITUSKULUDE LIIGITAMINE EVS 885:2005) | Betoon - Konstuktsioon, Krohv - Lubjakivi (3) | Betoon - Konstuktsioon | 1,8 | -1 635 + Posti kõrgus: 10 350 | -1 635 | yes | no | Betoon - Konstuktsioon 400 x 400
5 x Betoon - Konstuktsioon | 2 korrus | 1.3 IfcColumn (post) (_RKAS BIM + ARCHICAD Classification); 0 TELLIJA KULUD (EHITUSKULUDE LIIGITAMINE EVS 885:2005) | Betoon - Konstuktsioon, Krohv - Lubjakivi | Betoon - Konstuktsioon | 1,8 | -1 635 + Posti kõrgus: 10 350 | -1 635 | yes | no | Betoon - Konstuktsioon 400 x 400
Betoon - Konstuktsioon | 2 korrus | 1.3 IfcColumn (post) (_RKAS BIM + ARCHICAD Classification); 0 TELLIJA KULUD (EHITUSKULUDE LIIGITAMINE EVS 885:2005) | Betoon - Konstuktsioon, Krohv - Lubjakivi | Betoon - Konstuktsioon | 1,8 | -1 615 + Posti kõrgus: 10 330 | -1 615 | yes | no | Betoon - Konstuktsioon 400 x 400
Betoon - Konstuktsioon | 2 korrus | 1.3 IfcColumn (post) (_RKAS BIM + ARCHICAD Classification); 0 TELLIJA KULUD (EHITUSKULUDE LIIGITAMINE EVS 885:2005) | Betoon - Konstuktsioon, Krohv - Lubjakivi | Betoon - Konstuktsioon | 0,7 | 4 800 + Posti kõrgus: 3 915 | 4 800 | no | no | Betoon - Konstuktsioon 400 x 400
Betoon - Konstuktsioon | 2 korrus | 1.3 IfcColumn (post) (_RKAS BIM + ARCHICAD Classification); 0 TELLIJA KULUD (EHITUSKULUDE LIIGITAMINE EVS 885:2005) | Betoon - Konstuktsioon, Krohv - Lubjakivi (2) | Betoon - Konstuktsioon | 1,8 | -1 635 + Posti kõrgus: 10 350 | -1 635 | yes | yes | Betoon - Konstuktsioon 400 x 400
Betoon - Konstuktsioon | 2 korrus | 1.3 IfcColumn (post) (_RKAS BIM + ARCHICAD Classification); 0 TELLIJA KULUD (EHITUSKULUDE LIIGITAMINE EVS 885:2005) | Betoon - Konstuktsioon, Krohv - Lubjakivi (3) | Betoon - Konstuktsioon | 1,8 | -1 635 + Posti kõrgus: 10 350 | -1 635 | yes | yes | Betoon - Konstuktsioon 400 x 400
Post - teras - RHS:150x100x5:1653070 | 2 korrus | 1.3 IfcColumn (post) (_RKAS BIM + ARCHICAD Classification) | Teras (musta värvi) | 150x100x5 | 0,0 | 4 800 + Posti kõrgus: 3 928 | 4 800 | yes | yes | 150x100x5 | KONSTRUKTSIOON - 01_Nimetus: Post - teras - RHS; 02_Materjal: Teras, S355; 03_Ristloige: 150x100x5; 04_Tugevusklass: S355; 05_Keskkonnaklass: C3; 06_Maht: 0.009456 m3; 07_Mass: 74; 08_Pikkus: 3940 mm; 11_Ulemine korgusmark: 8800 mm; 12_Alumine korgusmark: 4860 mm
Post - teras - RHS:150x100x5:1653066 | 2 korrus | 1.3 IfcColumn (post) (_RKAS BIM + ARCHICAD Classification) | Teras (musta värvi) | 150x100x5 | 0,0 | 4 800 + Posti kõrgus: 3 928 | 4 800 | yes | yes | 150x100x5 | KONSTRUKTSIOON - 01_Nimetus: Post - teras - RHS; 02_Materjal: Teras, S355; 03_Ristloige: 150x100x5; 04_Tugevusklass: S355; 05_Keskkonnaklass: C3; 06_Maht: 0.009456 m3; 07_Mass: 74; 08_Pikkus: 3940 mm; 11_Ulemine korgusmark: 8800 mm; 12_Alumine korgusmark: 4860 mm
Post - teras - RHS:150x100x5:1653068 | 2 korrus | 1.3 IfcColumn (post) (_RKAS BIM + ARCHICAD Classification) | Teras (musta värvi) | 150x100x5 | 0,0 | 4 800 + Posti kõrgus: 3 928 | 4 800 | yes | yes | 150x100x5 | KONSTRUKTSIOON - 01_Nimetus: Post - teras - RHS; 02_Materjal: Teras, S355; 03_Ristloige: 150x100x5; 04_Tugevusklass: S355; 05_Keskkonnaklass: C3; 06_Maht: 0.009456 m3; 07_Mass: 74; 08_Pikkus: 3940 mm; 11_Ulemine korgusmark: 8800 mm; 12_Alumine korgusmark: 4860 mm
Post - teras - RHS:150x100x5:1653064 | 2 korrus | 1.3 IfcColumn (post) (_RKAS BIM + ARCHICAD Classification) | Teras (musta värvi) | 150x100x5 | 0,0 | 4 800 + Posti kõrgus: 3 928 | 4 800 | yes | yes | 150x100x5 | KONSTRUKTSIOON - 01_Nimetus: Post - teras - RHS; 02_Materjal: Teras, S355; 03_Ristloige: 150x100x5; 04_Tugevusklass: S355; 05_Keskkonnaklass: C3; 06_Maht: 0.009456 m3; 07_Mass: 74; 08_Pikkus: 3940 mm; 11_Ulemine korgusmark: 8800 mm; 12_Alumine korgusmark: 4860 mm; Pset_ColumnCommon - Slope: 0 deg
Post - teras - SHS:150x150x5:1650530 | 2 korrus | 1.3 IfcColumn (post) (_RKAS BIM + ARCHICAD Classification) | Teras (musta värvi) | 150x150x5 | 0,0 | 4 800 + Posti kõrgus: 3 928 | 4 800 | yes | yes | 150x150x5 | KONSTRUKTSIOON - 01_Nimetus: Post - teras - SHS; 02_Materjal: Teras, S355; 03_Ristloige: 150x150x5; 04_Tugevusklass: S355; 05_Keskkonnaklass: C3; 06_Maht: 0.011426 m3; 07_Mass: 90; 08_Pikkus: 3940 mm; 11_Ulemine korgusmark: 8800 mm; 12_Alumine korgusmark: 4860 mm
Post - teras - SHS:150x150x5:1650514 | 2 korrus | 1.3 IfcColumn (post) (_RKAS BIM + ARCHICAD Classification) | Teras (musta värvi) | 150x150x5 | 0,0 | 4 800 + Posti kõrgus: 3 928 | 4 800 | yes | yes | 150x150x5 | KONSTRUKTSIOON - 01_Nimetus: Post - teras - SHS; 02_Materjal: Teras, S355; 03_Ristloige: 150x150x5; 04_Tugevusklass: S355; 05_Keskkonnaklass: C3; 06_Maht: 0.011426 m3; 07_Mass: 90; 08_Pikkus: 3940 mm; 11_Ulemine korgusmark: 8800 mm; 12_Alumine korgusmark: 4860 mm
Post - teras - SHS:150x150x5:1650500 | 2 korrus | 1.3 IfcColumn (post) (_RKAS BIM + ARCHICAD Classification) | Teras (musta värvi) | 150x150x5 | 0,0 | 4 800 + Posti kõrgus: 3 928 | 4 800 | yes | yes | 150x150x5 | KONSTRUKTSIOON - 01_Nimetus: Post - teras - SHS; 02_Materjal: Teras, S355; 03_Ristloige: 150x150x5; 04_Tugevusklass: S355; 05_Keskkonnaklass: C3; 06_Maht: 0.011426 m3; 07_Mass: 90; 08_Pikkus: 3940 mm; 11_Ulemine korgusmark: 8800 mm; 12_Alumine korgusmark: 4860 mm
Post - teras - SHS:150x150x5:1650498 | 2 korrus | 1.3 IfcColumn (post) (_RKAS BIM + ARCHICAD Classification) | Teras (musta värvi) | 150x150x5 | 0,0 | 4 800 + Posti kõrgus: 3 928 | 4 800 | yes | yes | 150x150x5 | KONSTRUKTSIOON - 01_Nimetus: Post - teras - SHS; 02_Materjal: Teras, S355; 03_Ristloige: 150x150x5; 04_Tugevusklass: S355; 05_Keskkonnaklass: C3; 06_Maht: 0.011426 m3; 07_Mass: 90; 08_Pikkus: 3940 mm; 11_Ulemine korgusmark: 8800 mm; 12_Alumine korgusmark: 4860 mm
Post - teras - SHS:150x150x5:1650477 | 2 korrus | 1.3 IfcColumn (post) (_RKAS BIM + ARCHICAD Classification) | Teras (musta värvi) | 150x150x5 | 0,0 | 4 800 + Posti kõrgus: 3 928 | 4 800 | yes | yes | 150x150x5 | KONSTRUKTSIOON - 01_Nimetus: Post - teras - SHS; 02_Materjal: Teras, S355; 03_Ristloige: 150x150x5; 04_Tugevusklass: S355; 05_Keskkonnaklass: C3; 06_Maht: 0.011426 m3; 07_Mass: 90; 08_Pikkus: 3940 mm; 11_Ulemine korgusmark: 8800 mm; 12_Alumine korgusmark: 4860 mm; Pset_ColumnCommon - Slope: 0 deg
Post - teras - SHS:150x150x5:1650479 | 2 korrus | 1.3 IfcColumn (post) (_RKAS BIM + ARCHICAD Classification) | Teras (musta värvi) | 150x150x5 | 0,0 | 4 800 + Posti kõrgus: 3 928 | 4 800 | yes | yes | 150x150x5 | KONSTRUKTSIOON - 01_Nimetus: Post - teras - SHS; 02_Materjal: Teras, S355; 03_Ristloige: 150x150x5; 04_Tugevusklass: S355; 05_Keskkonnaklass: C3; 06_Maht: 0.011426 m3; 07_Mass: 90; 08_Pikkus: 3940 mm; 11_Ulemine korgusmark: 8800 mm; 12_Alumine korgusmark: 4860 mm
8 x Post - teras - SHS:150x150x5:1650498 | 2 korrus | 1.3 IfcColumn (post) (_RKAS BIM + ARCHICAD Classification) | Teras (musta värvi) | 150x150x5 | 0,0 | 8 878 + Posti kõrgus: 732 | 8 878 | yes | yes | 150x150x5 | KONSTRUKTSIOON - 01_Nimetus: Post - teras - SHS; 02_Materjal: Teras, S355; 03_Ristloige: 150x150x5; 04_Tugevusklass: S355; 05_Keskkonnaklass: C3; 06_Maht: 0.011426 m3; 07_Mass: 90; 08_Pikkus: 3940 mm; 11_Ulemine korgusmark: 8800 mm; 12_Alumine korgusmark: 4860 mm

# IfcColumn: Post (C-profiiliga karkass; puitlaastplaat 12mm; mineraalkrohv 10mm) (16)
In: 1 korrus
Type - ElementType: Element type Post (C-profiiliga karkass; puitlaastplaat 12mm; mineraalkrohv 10mm)
Classification: 1.3 IfcColumn (post) (_RKAS BIM + ARCHICAD Classification); Material: GENEERILINE - KONSTRUKTRIOON, Krohv - Lubjakivi
Ehituskonstruktsioonid - 01 Nimetus: GENEERILINE - KONSTRUKTRIOON; 03 Tähistus või ristlõige: Post (C-profiiliga karkass; puitlaastplaat 12mm; mineraalkrohv 10mm)
AC_Pset_RenovationAndPhasing - Renovation Status: New
Pset_ColumnCommon - IsExternal: no; Reference: GENEERILINE - KONSTRUKTRIOON 300 x 300
Name | 06 Maht (kubatuur) | 11 Ülemine kõrgusmärk | 12 Alumine kõrgusmärk | LoadBearing
14 x GENEERILINE - KONSTRUKTRIOON | 0,4 | 0 + Posti kõrgus: 4 100 | 0 | no
GENEERILINE - KONSTRUKTRIOON | 0,5 | -150 + Posti kõrgus: 4 900 | -150 | yes
GENEERILINE - KONSTRUKTRIOON | 0,4 | -600 + Posti kõrgus: 4 700 | -600 | no

# IfcColumn: Päikesevarjestuspost (140)
In: 1 korrus
Type - ElementType: Element type Päikesevarjestuspost
Classification: 1.3 IfcColumn (post) (_RKAS BIM + ARCHICAD Classification); Material: Teras (musta värvi)
Ehituskonstruktsioonid - 01 Nimetus: Teras (musta värvi); 03 Tähistus või ristlõige: Päikesevarjestuspost
AC_Pset_RenovationAndPhasing - Renovation Status: New
Pset_ColumnCommon - LoadBearing: no; IsExternal: yes
Name | 06 Maht (kubatuur) | 11 Ülemine kõrgusmärk | 12 Alumine kõrgusmärk
105 x Teras (musta värvi) | 0,4 | 0 + Posti kõrgus: | 0
3 x Teras (musta värvi) | 0,5 | -2 015 + Posti kõrgus: | -2 015
12 x Teras (musta värvi) | 0,2 | 0 + Posti kõrgus: | 0
Teras (musta värvi) | 0,5 | -1 911 + Posti kõrgus: | -1 911
10 x Teras (musta värvi) | 0,5 | -1 715 + Posti kõrgus: | -1 715
Teras (musta värvi) | 0,5 | -1 659 + Posti kõrgus: | -1 659
Teras (musta värvi) | 0,5 | -1 615 + Posti kõrgus: | -1 615
Teras (musta värvi) | 0,5 | -1 865 + Posti kõrgus: | -1 865
6 x Teras (musta värvi) | 0,3 | 0 + Posti kõrgus: | 0

# IfcCovering: SS-01_krohv (4)
In: 0 korrus
Type - ElementType: Element type SS-01_krohv; PredefinedType: CLADDING
Classification: 1.5 IfcCovering (siseviimistlus) (_RKAS BIM + ARCHICAD Classification); Material: Krohv - Lubjakivi (5)
Pset_CoveringCommon - Material: Foreground
Ripplagi - 01 Nimetus: Foreground; 02 Materjal: Krohv - Lubjakivi
Siseviimistlus - 01 Nimetus: SS-01_krohv; 02 Materjal: Siseviimistlus; Lubikrohv 10mm; 03 Kategooria / tüüp: Undefined; 06 Aluspind: Undefined; 07 Tehnilised omadused: Undefined; 08 Toon: Undefined; 09 Tootja: Undefined; 10 Mudel või toote tunnus: Undefined; 11 Tooteinfo: Undefined; 12 Kasutus- ja hooldusjuhend: Undefined
AC_Pset_RenovationAndPhasing - Renovation Status: New

# IfcCovering: SS-07_krohv (2)
In: 1,5 korrus
Type - ElementType: Element type SS-07_krohv; PredefinedType: CLADDING
Classification: 1.5 IfcCovering (siseviimistlus) (_RKAS BIM + ARCHICAD Classification); Material: Krohv - Lubjakivi (5)
Pset_CoveringCommon - Material: Foreground
Ripplagi - 01 Nimetus: Foreground; 02 Materjal: Krohv - Lubjakivi
Siseviimistlus - 01 Nimetus: SS-07_krohv; 02 Materjal: Siseviimistlus; Lubikrohv 10mm; 03 Kategooria / tüüp: Undefined; 06 Aluspind: Undefined; 07 Tehnilised omadused: Undefined; 08 Toon: Undefined; 09 Tootja: Undefined; 10 Mudel või toote tunnus: Undefined; 11 Tooteinfo: Undefined; 12 Kasutus- ja hooldusjuhend: Undefined
AC_Pset_RenovationAndPhasing - Renovation Status: New

# IfcCovering: SS-10_krohv, Foreground
In: 0 korrus
Type - ElementType: Element type SS-10_krohv; PredefinedType: CLADDING
Classification: 1.5 IfcCovering (siseviimistlus) (_RKAS BIM + ARCHICAD Classification); Material: Krohv - Lubjakivi (5)
Pset_CoveringCommon - Material: Foreground
Ripplagi - 01 Nimetus: Foreground; 02 Materjal: Krohv - Lubjakivi
Siseviimistlus - 01 Nimetus: SS-10_krohv; 02 Materjal: Siseviimistlus; Lubikrohv 10mm; 03 Kategooria / tüüp: Undefined; 06 Aluspind: Undefined; 07 Tehnilised omadused: Undefined; 08 Toon: Undefined; 09 Tootja: Undefined; 10 Mudel või toote tunnus: Undefined; 11 Tooteinfo: Undefined; 12 Kasutus- ja hooldusjuhend: Undefined
AC_Pset_RenovationAndPhasing - Renovation Status: New

# IfcCurtainWall: KLF-01, Klaasfassaad
In: 0 korrus
Type - ElementType: Element type KLF-01
Classification: 0 TELLIJA KULUD (EHITUSKULUDE LIIGITAMINE EVS 885:2005); 1.7 IfcCurtainWall (rippfassaad) (_RKAS BIM + ARCHICAD Classification)
Rippfassaad - 01 Nimetus: Klaasfassaad; 02 Materjal: Klaas; Metall; 03 Kategooria / tüüp: KLF-01; 04 Pindala: Pinna pindala: 6,0; Pinna pindala ka. Äärte ala6,0 Täpsustus: 6,0 m2; 05 Helipidavus: 35dB; 06 Klaaspakett: kolmekordne klaaspakett, välimine klaas lamineeritud, sisemine klaas karastatud, klaaside vahelised liistud musta värvi; 07 Soojusläbivus: 0,7 W/m2K; 08 Päikesekiirgus tegur (g-väärtus): 0,38; 09 Tulekindlus: nõudeid ei esitata; 10 Raamistiku jaotus: jaotatud neljaks; 11 Paneelide materjal: kirgas klaas; 12 Karkassi materjal: metall, värvitud tehaseliselt tumehalliks RAL7016 (Anthrazitgrau); 13 Tootja: Schüco (või samaväärne analoog); 14 Mudel või toote tunnus: FWS 50 SI (või samaväärne analoog); 15 Tooteinfo: Undefined; 16 Kasutus- ja hooldusjuhend: Undefined
AC_Pset_RenovationAndPhasing - Renovation Status: New
Pset_CurtainWallCommon - IsExternal: yes

# IfcCurtainWall: KLF-02, Klaasfassaad
In: 0 korrus
Type - ElementType: Element type KLF-02
Classification: 0 TELLIJA KULUD (EHITUSKULUDE LIIGITAMINE EVS 885:2005); 1.7 IfcCurtainWall (rippfassaad) (_RKAS BIM + ARCHICAD Classification)
Rippfassaad - 01 Nimetus: Klaasfassaad; 02 Materjal: Klaas; Metall; 03 Kategooria / tüüp: KLF-02; 04 Pindala: Pinna pindala: 7,7; Pinna pindala ka. Äärte ala7,7 Täpsustus: 7,7 m2; 05 Helipidavus: 35dB; 06 Klaaspakett: kolmekordne klaaspakett, välimine klaas lamineeritud, sisemine klaas karastatud, klaaside vahelised liistud musta värvi; 07 Soojusläbivus: 0,7 W/m2K; 08 Päikesekiirgus tegur (g-väärtus): 0,38; 09 Tulekindlus: nõudeid ei esitata; 10 Raamistiku jaotus: jaotatud kolmeks; 11 Paneelide materjal: kirgas klaas; 12 Karkassi materjal: metall, värvitud tehaseliselt tumehalliks RAL7016 (Anthrazitgrau); 13 Tootja: Schüco (või samaväärne analoog); 14 Mudel või toote tunnus: FWS 50 SI (või samaväärne analoog); 15 Tooteinfo: Undefined; 16 Kasutus- ja hooldusjuhend: Undefined
AC_Pset_RenovationAndPhasing - Renovation Status: New
Pset_CurtainWallCommon - IsExternal: yes

# IfcCurtainWall: KLF-03, Klaasfassaad
In: 0 korrus
Type - ElementType: Element type KLF-03
Classification: 1.7 IfcCurtainWall (rippfassaad) (_RKAS BIM + ARCHICAD Classification)
Rippfassaad - 01 Nimetus: Klaasfassaad; 02 Materjal: Klaas; Metall; 03 Kategooria / tüüp: KLF-03; 04 Pindala: Pinna pindala: 8,7; Pinna pindala ka. Äärte ala8,7 Täpsustus: 8,7 m2; 05 Helipidavus: 35dB; 06 Klaaspakett: kolmekordne klaaspakett, välimine klaas lamineeritud, sisemine klaas karastatud, klaaside vahelised liistud musta värvi; 07 Soojusläbivus: 0,7 W/m2K; 08 Päikesekiirgus tegur (g-väärtus): 0,38; 09 Tulekindlus: nõudeid ei esitata; 10 Raamistiku jaotus: jaotatud kolmeks; 11 Paneelide materjal: kirgas klaas; 12 Karkassi materjal: metall, värvitud tehaseliselt tumehalliks RAL7016 (Anthrazitgrau); 13 Tootja: Schüco (või samaväärne analoog); 14 Mudel või toote tunnus: FWS 50 SI (või samaväärne analoog); 15 Tooteinfo: Undefined; 16 Kasutus- ja hooldusjuhend: Undefined
AC_Pset_RenovationAndPhasing - Renovation Status: New
Pset_CurtainWallCommon - IsExternal: no

# IfcCurtainWall: KLF-04, Klaasfassaad
In: 0 korrus
Type - ElementType: Element type KLF-04
Classification: 0 TELLIJA KULUD (EHITUSKULUDE LIIGITAMINE EVS 885:2005); 1.7 IfcCurtainWall (rippfassaad) (_RKAS BIM + ARCHICAD Classification)
Rippfassaad - 01 Nimetus: Klaasfassaad; 02 Materjal: Klaas; Metall; 03 Kategooria / tüüp: KLF-04; 04 Pindala: Pinna pindala: 15,8; Pinna pindala ka. Äärte ala15,8 Täpsustus: 15,8 m2; 05 Helipidavus: 35dB; 06 Klaaspakett: kolmekordne klaaspakett, välimine klaas lamineeritud, sisemine klaas karastatud, klaaside vahelised liistud musta värvi; 07 Soojusläbivus: 0,7 W/m2K; 08 Päikesekiirgus tegur (g-väärtus): 0,38; 09 Tulekindlus: nõudeid ei esitata; 10 Raamistiku jaotus: jaotatud kuueks; 11 Paneelide materjal: kirgas klaas; 12 Karkassi materjal: metall, värvitud tehaseliselt tumehalliks RAL7016 (Anthrazitgrau); 13 Tootja: Schüco (või samaväärne analoog); 14 Mudel või toote tunnus: FWS 50 SI (või samaväärne analoog); 15 Tooteinfo: Undefined; 16 Kasutus- ja hooldusjuhend: Undefined
AC_Pset_RenovationAndPhasing - Renovation Status: New
Pset_CurtainWallCommon - IsExternal: no

# IfcCurtainWall: KLF-05, Klaasfassaad
In: 0 korrus
Type - ElementType: Element type KLF-05
Classification: 1.7 IfcCurtainWall (rippfassaad) (_RKAS BIM + ARCHICAD Classification)
Rippfassaad - 01 Nimetus: Klaasfassaad; 02 Materjal: Klaas; Metall; 03 Kategooria / tüüp: KLF-05; 04 Pindala: Pinna pindala: 7,3; Pinna pindala ka. Äärte ala7,3 Täpsustus: 7,3 m2; 05 Helipidavus: 35dB; 06 Klaaspakett: kolmekordne klaaspakett, välimine klaas lamineeritud, sisemine klaas karastatud, klaaside vahelised liistud musta värvi; 07 Soojusläbivus: 0,7 W/m2K; 08 Päikesekiirgus tegur (g-väärtus): 0,38; 09 Tulekindlus: nõudeid ei esitata; 10 Raamistiku jaotus: jaotatud kolmeks; 11 Paneelide materjal: kirgas klaas; 12 Karkassi materjal: metall, värvitud tehaseliselt tumehalliks RAL7016 (Anthrazitgrau); 13 Tootja: Schüco (või samaväärne analoog); 14 Mudel või toote tunnus: FWS 50 SI (või samaväärne analoog); 15 Tooteinfo: Undefined; 16 Kasutus- ja hooldusjuhend: Undefined
AC_Pset_RenovationAndPhasing - Renovation Status: New
Pset_CurtainWallCommon - IsExternal: yes

# IfcCurtainWall: KLF-06, Klaasfassaad
In: 0 korrus
Type - ElementType: Element type KLF-06
Classification: 0 TELLIJA KULUD (EHITUSKULUDE LIIGITAMINE EVS 885:2005); 1.7 IfcCurtainWall (rippfassaad) (_RKAS BIM + ARCHICAD Classification)
Rippfassaad - 01 Nimetus: Klaasfassaad; 02 Materjal: Klaas; Metall; 03 Kategooria / tüüp: KLF-06; 04 Pindala: Pinna pindala: 5,6; Pinna pindala ka. Äärte ala5,6 Täpsustus: 5,6 m2; 05 Helipidavus: 35dB; 06 Klaaspakett: kolmekordne klaaspakett, välimine klaas lamineeritud, sisemine klaas karastatud, klaaside vahelised liistud musta värvi; 07 Soojusläbivus: 0,7 W/m2K; 08 Päikesekiirgus tegur (g-väärtus): 0,38; 09 Tulekindlus: nõudeid ei esitata; 10 Raamistiku jaotus: jaotatud kolmeks; 11 Paneelide materjal: kirgas klaas; 12 Karkassi materjal: metall, värvitud tehaseliselt tumehalliks RAL7016 (Anthrazitgrau); 13 Tootja: Schüco (või samaväärne analoog); 14 Mudel või toote tunnus: FWS 50 SI (või samaväärne analoog); 15 Tooteinfo: Undefined; 16 Kasutus- ja hooldusjuhend: Undefined
AC_Pset_RenovationAndPhasing - Renovation Status: New
Pset_CurtainWallCommon - IsExternal: no

# IfcCurtainWall: KLF-07, Klaasfassaad
In: 0 korrus
Type - ElementType: Element type KLF-07
Classification: 1.7 IfcCurtainWall (rippfassaad) (_RKAS BIM + ARCHICAD Classification)
Rippfassaad - 01 Nimetus: Klaasfassaad; 02 Materjal: Klaas; Metall; 03 Kategooria / tüüp: KLF-07; 04 Pindala: Pinna pindala: 5,2; Pinna pindala ka. Äärte ala5,2 Täpsustus: 5,2 m2; 05 Helipidavus: 35 dB; 06 Klaaspakett: kolmekordne klaaspakett, välimine klaas lamineeritud, sisemine klaas karastatud, klaaside vahelised liistud musta värvi; 07 Soojusläbivus: 0,7 W/m2K; 08 Päikesekiirgus tegur (g-väärtus): 0,38; 09 Tulekindlus: nõudeid ei esitata; 10 Raamistiku jaotus: jaotatud kolmeks; 11 Paneelide materjal: kirgas klaas; 12 Karkassi materjal: metall, värvitud tehaseliselt tumehalliks RAL7016 (Anthrazitgrau); 13 Tootja: Schüco (või samaväärne analoog); 14 Mudel või toote tunnus: FWS 50 SI (või samaväärne analoog); 15 Tooteinfo: Undefined; 16 Kasutus- ja hooldusjuhend: Undefined
AC_Pset_RenovationAndPhasing - Renovation Status: New
Pset_CurtainWallCommon - IsExternal: yes

# IfcCurtainWall: KLF-08, Klaasfassaad
In: 1,5 korrus
Type - ElementType: Element type KLF-08
Classification: 1.7 IfcCurtainWall (rippfassaad) (_RKAS BIM + ARCHICAD Classification)
Rippfassaad - 01 Nimetus: Klaasfassaad; 02 Materjal: Klaas; Metall; 03 Kategooria / tüüp: KLF-08; 04 Pindala: Pinna pindala: 12,0; Pinna pindala ka. Äärte ala12,0 Täpsustus: 12,0 m2; 05 Helipidavus: 35dB; 06 Klaaspakett: kolmekordne klaaspakett, välimine klaas karastatud, sisemine klaas lamineeritud, klaaside vahelised liistud musta värvi; 07 Soojusläbivus: 0,7 W/m2K; 08 Päikesekiirgus tegur (g-väärtus): 0,38; 09 Tulekindlus: nõudeid ei esitata; 10 Raamistiku jaotus: jaotatud viieks; 11 Paneelide materjal: kirgas klaas; 12 Karkassi materjal: metall, värvitud tehaseliselt tumehalliks RAL7016 (Anthrazitgrau); 13 Tootja: Schüco (või samaväärne analoog); 14 Mudel või toote tunnus: FWS 50 SI (või samaväärne analoog); 15 Tooteinfo: Undefined; 16 Kasutus- ja hooldusjuhend: Undefined
AC_Pset_RenovationAndPhasing - Renovation Status: New
Pset_CurtainWallCommon - IsExternal: yes

# IfcCurtainWall: KLF-09, Klaasfassaad
In: 2 korrus
Type - ElementType: Element type KLF-09
Classification: 1.7 IfcCurtainWall (rippfassaad) (_RKAS BIM + ARCHICAD Classification)
Rippfassaad - 01 Nimetus: Klaasfassaad; 02 Materjal: Klaas; Metall; 03 Kategooria / tüüp: KLF-09; 04 Pindala: Pinna pindala: 9,2; Pinna pindala ka. Äärte ala9,2 Täpsustus: 9,2 m2; 05 Helipidavus: 35dB; 06 Klaaspakett: kolmekordne klaaspakett, välimine klaas karastatud, sisemine klaas lamineeritud, klaaside vahelised liistud musta värvi; 07 Soojusläbivus: 0,7 W/m2K; 08 Päikesekiirgus tegur (g-väärtus): 0,38; 09 Tulekindlus: nõudeid ei esitata; 10 Raamistiku jaotus: jaotatud neljaks; 11 Paneelide materjal: kirgas klaas; 12 Karkassi materjal: metall, värvitud tehaseliselt tumehalliks RAL7016 (Anthrazitgrau); 13 Tootja: Schüco (või samaväärne analoog); 14 Mudel või toote tunnus: FWS 50 SI (või samaväärne analoog); 15 Tooteinfo: Undefined; 16 Kasutus- ja hooldusjuhend: Undefined
AC_Pset_RenovationAndPhasing - Renovation Status: New
Pset_CurtainWallCommon - IsExternal: yes

# IfcCurtainWall: KLF-10, Klaasfassaad
In: 2 korrus
Type - ElementType: Element type KLF-10
Classification: 1.7 IfcCurtainWall (rippfassaad) (_RKAS BIM + ARCHICAD Classification)
Rippfassaad - 01 Nimetus: Klaasfassaad; 02 Materjal: Klaas; Metall; 03 Kategooria / tüüp: KLF-10; 04 Pindala: Pinna pindala: 8,0; Pinna pindala ka. Äärte ala8,0 Täpsustus: 8,0 m2; 05 Helipidavus: 35dB; 06 Klaaspakett: kolmekordne klaaspakett, välimine klaas karastatud, sisemine klaas lamineeritud, klaaside vahelised liistud musta värvi; 07 Soojusläbivus: 0,7 W/m2K; 08 Päikesekiirgus tegur (g-väärtus): 0,38; 09 Tulekindlus: nõudeid ei esitata; 10 Raamistiku jaotus: jaotatud kolmeks; 11 Paneelide materjal: kirgas klaas; 12 Karkassi materjal: metall, värvitud tehaseliselt tumehalliks RAL7016 (Anthrazitgrau); 13 Tootja: Schüco (või samaväärne analoog); 14 Mudel või toote tunnus: FWS 50 SI (või samaväärne analoog); 15 Tooteinfo: Undefined; 16 Kasutus- ja hooldusjuhend: Undefined
AC_Pset_RenovationAndPhasing - Renovation Status: New
Pset_CurtainWallCommon - IsExternal: yes

# IfcCurtainWall: KLF-11 (2)
In: 1 korrus
Type - ElementType: Element type KLF-11
Rippfassaad - 01 Nimetus: Klaasfassaad; 02 Materjal: Klaas; Metall; 03 Kategooria / tüüp: KLF-11; 04 Pindala: Pinna pindala: 9,8; Pinna pindala ka. Äärte ala9,8 Täpsustus: 9,8 m2; 05 Helipidavus: 35dB; 06 Klaaspakett: kolmekordne klaaspakett, välimine klaas lamineeritud, sisemine klaas karastatud, klaaside vahelised liistud musta värvi; 07 Soojusläbivus: 0,7 W/m2K; 08 Päikesekiirgus tegur (g-väärtus): 0,38; 09 Tulekindlus: nõudeid ei esitata; 10 Raamistiku jaotus: jaotatud neljaks; 11 Paneelide materjal: kirgas klaas; 12 Karkassi materjal: metall, värvitud tehaseliselt tumehalliks RAL7016 (Anthrazitgrau); 13 Tootja: Schüco (või samaväärne analoog); 14 Mudel või toote tunnus: FWS 50 SI (või samaväärne analoog); 15 Tooteinfo: Undefined; 16 Kasutus- ja hooldusjuhend: Undefined
AC_Pset_RenovationAndPhasing - Renovation Status: New
Pset_CurtainWallCommon - IsExternal: yes
Name | Classification
Klaasfassaad | 0 TELLIJA KULUD (EHITUSKULUDE LIIGITAMINE EVS 885:2005); 1.7 IfcCurtainWall (rippfassaad) (_RKAS BIM + ARCHICAD Classification)
Klaasfassaad | 1.7 IfcCurtainWall (rippfassaad) (_RKAS BIM + ARCHICAD Classification)

# IfcCurtainWall: KLF-12, Klaasfassaad
In: 2 korrus
Type - ElementType: Element type KLF-12
Classification: 1.7 IfcCurtainWall (rippfassaad) (_RKAS BIM + ARCHICAD Classification)
Rippfassaad - 01 Nimetus: Klaasfassaad; 02 Materjal: Klaas; Metall; 03 Kategooria / tüüp: KLF-12; 04 Pindala: Pinna pindala: 3,8; Pinna pindala ka. Äärte ala3,8 Täpsustus: 3,8 m2; 05 Helipidavus: 35dB; 06 Klaaspakett: kolmekordne klaaspakett, välimine klaas karastatud, sisemine klaas lamineeritud, klaaside vahelised liistud musta värvi; 07 Soojusläbivus: 0,7 W/m2K; 08 Päikesekiirgus tegur (g-väärtus): 0,38; 09 Tulekindlus: nõudeid ei esitata; 10 Raamistiku jaotus: jaotatud kaheks; 11 Paneelide materjal: Kirgas klaas; 12 Karkassi materjal: metall, värvitud tehaseliselt tumehalliks RAL7016 (Anthrazitgrau); 13 Tootja: Schüco (või samaväärne analoog); 14 Mudel või toote tunnus: FWS 50 SI (või samaväärne analoog); 15 Tooteinfo: Undefined; 16 Kasutus- ja hooldusjuhend: Undefined
AC_Pset_RenovationAndPhasing - Renovation Status: New
Pset_CurtainWallCommon - IsExternal: yes

# IfcCurtainWall: KLF-13, Klaasfassaad
In: 1 korrus
Type - ElementType: Element type KLF-13
Classification: 1.7 IfcCurtainWall (rippfassaad) (_RKAS BIM + ARCHICAD Classification)
Rippfassaad - 01 Nimetus: Klaasfassaad; 02 Materjal: Klaas; Metall; 03 Kategooria / tüüp: KLF-13; 04 Pindala: Pinna pindala: 28,8; Pinna pindala ka. Äärte ala28,8 Täpsustus: 28,8 m2; 05 Helipidavus: 35dB; 06 Klaaspakett: kolmekordne klaaspakett, välimine klaas lamineeritud, sisemine klaas karastatud, klaaside vahelised liistud musta värvi; 07 Soojusläbivus: 0,7 W/m2K; 08 Päikesekiirgus tegur (g-väärtus): 0,38; 09 Tulekindlus: nõudeid ei esitata; 10 Raamistiku jaotus: jaotatud 12-ks; 11 Paneelide materjal: kirgas klaas; 12 Karkassi materjal: metall, värvitud tehaseliselt tumehalliks RAL7016 (Anthrazitgrau); 13 Tootja: Schüco (või samaväärne analoog); 14 Mudel või toote tunnus: FWS 50 SI (või samaväärne analoog); 15 Tooteinfo: Undefined; 16 Kasutus- ja hooldusjuhend: Undefined
AC_Pset_RenovationAndPhasing - Renovation Status: New
Pset_CurtainWallCommon - IsExternal: yes

# IfcCurtainWall: KLF-14, Klaasfassaad
In: 1 korrus
Type - ElementType: Element type KLF-14
Classification: 1.7 IfcCurtainWall (rippfassaad) (_RKAS BIM + ARCHICAD Classification)
Rippfassaad - 01 Nimetus: Klaasfassaad; 02 Materjal: Klaas; Metall; 03 Kategooria / tüüp: KLF-14; 04 Pindala: Pinna pindala: 47,4; Pinna pindala ka. Äärte ala47,4 Täpsustus: 48,7 m2; 05 Helipidavus: 35dB; 06 Klaaspakett: kolmekordne klaaspakett, välimine klaas lamineeritud, sisemine klaas karastatud, klaaside vahelised liistud musta värvi; 07 Soojusläbivus: 0,7 W/m2K; 08 Päikesekiirgus tegur (g-väärtus): 0,38; 09 Tulekindlus: nõudeid ei esitata; 10 Raamistiku jaotus: jaotatud 39-ks; 11 Paneelide materjal: kirgas klaas; 12 Karkassi materjal: metall, värvitud tehaseliselt tumehalliks RAL7016 (Anthrazitgrau); 13 Tootja: Schüco (või samaväärne analoog); 14 Mudel või toote tunnus: FWS 50 SI (või samaväärne analoog); 15 Tooteinfo: Undefined; 16 Kasutus- ja hooldusjuhend: Undefined
AC_Pset_RenovationAndPhasing - Renovation Status: New
Pset_CurtainWallCommon - IsExternal: yes

# IfcCurtainWall: KLF-15, Klaasfassaad
In: 2 korrus
Type - ElementType: Element type KLF-15
Classification: 1.7 IfcCurtainWall (rippfassaad) (_RKAS BIM + ARCHICAD Classification)
Rippfassaad - 01 Nimetus: Klaasfassaad; 02 Materjal: Klaas; Metall; 03 Kategooria / tüüp: KLF-15; 04 Pindala: Pinna pindala: 18,6; Pinna pindala ka. Äärte ala18,6 Täpsustus: 7,7 m2; 05 Helipidavus: 35dB; 06 Klaaspakett: kolmekordne klaaspakett, välimine klaas lamineeritud, sisemine klaas karastatud, klaaside vahelised liistud musta värvi; 07 Soojusläbivus: 0,7 W/m2K; 08 Päikesekiirgus tegur (g-väärtus): 0,38; 09 Tulekindlus: nõudeid ei esitata; 10 Raamistiku jaotus: jaotatud kaheksaks; 11 Paneelide materjal: kirgas klaas; 12 Karkassi materjal: metall, värvitud tehaseliselt tumehalliks RAL7016 (Anthrazitgrau); 13 Tootja: Schüco (või samaväärne analoog); 14 Mudel või toote tunnus: FWS 50 SI (või samaväärne analoog); 15 Tooteinfo: Undefined; 16 Kasutus- ja hooldusjuhend: Undefined
AC_Pset_RenovationAndPhasing - Renovation Status: New
Pset_CurtainWallCommon - IsExternal: yes

# IfcCurtainWall: KLF-16, Klaasfassaad
In: 1 korrus
Type - ElementType: Element type KLF-16
Classification: 1.7 IfcCurtainWall (rippfassaad) (_RKAS BIM + ARCHICAD Classification)
Rippfassaad - 01 Nimetus: Klaasfassaad; 02 Materjal: Klaas; Metall; 03 Kategooria / tüüp: KLF-16; 04 Pindala: Pinna pindala: 59,5; Pinna pindala ka. Äärte ala59,5 Täpsustus: 59,5 m2; 05 Helipidavus: 35dB; 06 Klaaspakett: kolmekordne klaaspakett, välimine klaas lamineeritud, sisemine klaas karastatud, klaaside vahelised liistud musta värvi; 07 Soojusläbivus: 0,7 W/m2K; 08 Päikesekiirgus tegur (g-väärtus): 0,38; 09 Tulekindlus: nõudeid ei esitata; 10 Raamistiku jaotus: jaotatud 37-ks; 11 Paneelide materjal: kirgas klaas; 12 Karkassi materjal: metall, värvitud tehaseliselt tumehalliks RAL7016 (Anthrazitgrau); 13 Tootja: Schüco (või samaväärne analoog); 14 Mudel või toote tunnus: FWS 50 SI (või samaväärne analoog); 15 Tooteinfo: Undefined; 16 Kasutus- ja hooldusjuhend: Undefined
AC_Pset_RenovationAndPhasing - Renovation Status: New
Pset_CurtainWallCommon - IsExternal: yes

# IfcCurtainWall: KLF-17, Klaasfassaad
In: 1 korrus
Type - ElementType: Element type KLF-17
Classification: 1.7 IfcCurtainWall (rippfassaad) (_RKAS BIM + ARCHICAD Classification)
Rippfassaad - 14 Mudel või toote tunnus: FWS 50 SI (või samaväärne analoog); 01 Nimetus: Klaasfassaad; 02 Materjal: Klaas; Metall; 03 Kategooria / tüüp: KLF-17; 04 Pindala: Pinna pindala: 131,8; Pinna pindala ka. Äärte ala131,8 Täpsustus: 131,8 m2; 05 Helipidavus: 35dB; 06 Klaaspakett: kolmekordne klaaspakett, välimine klaas lamineeritud, sisemine klaas karastatud, klaaside vahelised liistud musta värvi; 07 Soojusläbivus: 0,7 W/m2K; 08 Päikesekiirgus tegur (g-väärtus): 0,58; 09 Tulekindlus: nõudeid ei esitata; 10 Raamistiku jaotus: jaotatud 64-ks; 11 Paneelide materjal: kirgas klaas, vahelae ja postide taga olevas osas on 1x taustvärvitud (must) karastatud 6mm klaas, mille tagune peab olema tuulduv; 12 Karkassi materjal: metall, värvitud tehaseliselt tumehalliks RAL7016 (Anthrazitgrau); 13 Tootja: Schüco (või samaväärne analoog); 15 Tooteinfo: Undefined; 16 Kasutus- ja hooldusjuhend: Undefined
AC_Pset_RenovationAndPhasing - Renovation Status: New
Pset_CurtainWallCommon - IsExternal: yes

# IfcCurtainWall: KS-01, Klaas-sein
In: 2 korrus
Type - ElementType: Element type KS-01
Classification: 1.7 IfcCurtainWall (rippfassaad) (_RKAS BIM + ARCHICAD Classification)
Rippfassaad - 01 Nimetus: Klaas-sein; 02 Materjal: Klaas; Alumiinium; 03 Kategooria / tüüp: KS-01; 04 Pindala: Pinna pindala: 11,3; Pinna pindala ka. Äärte ala11,3 Täpsustus: 11,3 m2; 05 Helipidavus: 38dB; 06 Klaaspakett: 6+1+6 kilelaminaadiga karastatud kirgas klaas; 07 Soojusläbivus: -; 08 Päikesekiirgus tegur (g-väärtus): -; 09 Tulekindlus: nõudeid ei esitata; 10 Raamistiku jaotus: jaotatud neljaks; 11 Paneelide materjal: kirgas klaas; 12 Karkassi materjal: metall, värvitud tehaseliselt tumehalliks RAL7016 (Anthrazitgrau); 13 Tootja: Forster (või samaväärne analoog); 14 Mudel või toote tunnus: Fuego Light (või samaväärne analoog); 15 Tooteinfo: Undefined; 16 Kasutus- ja hooldusjuhend: Undefined
AC_Pset_RenovationAndPhasing - Renovation Status: New
Pset_CurtainWallCommon - IsExternal: no

# IfcCurtainWall: KS-02, Klaas-sein
In: 2 korrus
Type - ElementType: Element type KS-02
Classification: 0 TELLIJA KULUD (EHITUSKULUDE LIIGITAMINE EVS 885:2005); 1.7 IfcCurtainWall (rippfassaad) (_RKAS BIM + ARCHICAD Classification)
Rippfassaad - 01 Nimetus: Klaas-sein; 02 Materjal: Klaas; Alumiinium; 03 Kategooria / tüüp: KS-02; 04 Pindala: Pinna pindala: 4,6; Pinna pindala ka. Äärte ala4,6 Täpsustus: 4,6 m2; 05 Helipidavus: 38dB; 06 Klaaspakett: 6+1+6 kilelaminaadiga karastatud kirgas klaas; 07 Soojusläbivus: -; 08 Päikesekiirgus tegur (g-väärtus): -; 09 Tulekindlus: nõudeid ei esitata; 10 Raamistiku jaotus: jaotatud kaheks; 11 Paneelide materjal: kirgas klaas; 12 Karkassi materjal: metall, värvitud tumehalliks RAL7016 (Anthrazitgrau); 13 Tootja: Forster (või samaväärne analoog); 14 Mudel või toote tunnus: Fuego Light (või samaväärne analoog); 15 Tooteinfo: Undefined; 16 Kasutus- ja hooldusjuhend: Undefined
AC_Pset_RenovationAndPhasing - Renovation Status: New
Pset_CurtainWallCommon - IsExternal: no

# IfcCurtainWall: KS-03, Klaasfassaad
In: 1,5 korrus
Type - ElementType: Element type KS-03
Classification: 1.7 IfcCurtainWall (rippfassaad) (_RKAS BIM + ARCHICAD Classification)
Rippfassaad - 01 Nimetus: Klaasfassaad; 02 Materjal: Klaas; Metall; 03 Kategooria / tüüp: KS-03; 04 Pindala: Pinna pindala: 4,3; Pinna pindala ka. Äärte ala4,3 Täpsustus: 4,6 m2; 05 Helipidavus: 38dB; 06 Klaaspakett: 6+1+6 kilelaminaadiga karastatud kirgas klaas; 07 Soojusläbivus: -; 08 Päikesekiirgus tegur (g-väärtus): -; 09 Tulekindlus: nõudeid ei esitata; 10 Raamistiku jaotus: jaotatud kaheks; 11 Paneelide materjal: kirgas klaas; 12 Karkassi materjal: metall, värvitud tehaseliselt tumehalliks RAL7016 (Anthrazitgrau); 13 Tootja: Forster (või samaväärne analoog); 14 Mudel või toote tunnus: Fuego Light (või samaväärne analoog); 15 Tooteinfo: Undefined; 16 Kasutus- ja hooldusjuhend: Undefined
AC_Pset_RenovationAndPhasing - Renovation Status: New
Pset_CurtainWallCommon - IsExternal: no

# IfcCurtainWall: KS-07 (6)
In: 0 korrus
Type - ElementType: Element type KS-07
Rippfassaad - 01 Nimetus: Klaas-sein; 02 Materjal: Klaas; Metall; 03 Kategooria / tüüp: KS-07; 04 Pindala: Pinna pindala: 2,2; Pinna pindala ka. Äärte ala2,2 Täpsustus: 2,2 m2; 05 Helipidavus: 38dB; 06 Klaaspakett: 6+1+6 kilelaminaadiga karastatud kirgas klaas; 07 Soojusläbivus: -; 08 Päikesekiirgus tegur (g-väärtus): -; 09 Tulekindlus: nõudeid ei esitata; 10 Raamistiku jaotus: -; 11 Paneelide materjal: Kirgas klaas; 12 Karkassi materjal: Metall; 13 Tootja: Forster (või samaväärne analoog); 14 Mudel või toote tunnus: Fuego Light (või samaväärne analoog); 15 Tooteinfo: Undefined; 16 Kasutus- ja hooldusjuhend: Undefined
AC_Pset_RenovationAndPhasing - Renovation Status: New
Pset_CurtainWallCommon - IsExternal: no
Name | Classification
2 x Klaas-sein | 1.7 IfcCurtainWall (rippfassaad) (_RKAS BIM + ARCHICAD Classification)
4 x Klaas-sein | 0 TELLIJA KULUD (EHITUSKULUDE LIIGITAMINE EVS 885:2005); 1.7 IfcCurtainWall (rippfassaad) (_RKAS BIM + ARCHICAD Classification)

# IfcCurtainWall: KS-08, Klaas-sein
In: 0 korrus
Type - ElementType: Element type KS-08
Classification: 1.7 IfcCurtainWall (rippfassaad) (_RKAS BIM + ARCHICAD Classification)
Rippfassaad - 01 Nimetus: Klaas-sein; 02 Materjal: Klaas; Metall; 03 Kategooria / tüüp: KS-08; 04 Pindala: Pinna pindala: 0,9; Pinna pindala ka. Äärte ala0,9 Täpsustus: 1,1 m2; 05 Helipidavus: 38dB; 06 Klaaspakett: 6+1+6 kilelaminaadiga karastatud kirgas klaas; 07 Soojusläbivus: -; 08 Päikesekiirgus tegur (g-väärtus): -; 09 Tulekindlus: nõudeid ei esitata; 10 Raamistiku jaotus: -; 11 Paneelide materjal: kirgas klaas; 12 Karkassi materjal: metall; 13 Tootja: Forster (või samaväärne analoog); 14 Mudel või toote tunnus: Fuego Light (või samaväärne analoog); 15 Tooteinfo: Undefined; 16 Kasutus- ja hooldusjuhend: Undefined
AC_Pset_RenovationAndPhasing - Renovation Status: New
Pset_CurtainWallCommon - IsExternal: no

# IfcCurtainWall: KS-09, Klaas-sein
In: 0 korrus
Type - ElementType: Element type KS-09
Classification: 0 TELLIJA KULUD (EHITUSKULUDE LIIGITAMINE EVS 885:2005); 1.7 IfcCurtainWall (rippfassaad) (_RKAS BIM + ARCHICAD Classification)
Rippfassaad - 01 Nimetus: Klaas-sein; 02 Materjal: Klaas; Metall; 03 Kategooria / tüüp: KS-09; 04 Pindala: Pinna pindala: 1,5; Pinna pindala ka. Äärte ala1,5 Täpsustus: 1,5 m2; 05 Helipidavus: 38dB; 06 Klaaspakett: 6+1+6 kilelaminaadiga karastatud kirgas klaas; 07 Soojusläbivus: -; 08 Päikesekiirgus tegur (g-väärtus): -; 09 Tulekindlus: nõudeid ei esitata; 10 Raamistiku jaotus: -; 11 Paneelide materjal: kirgas klaas; 12 Karkassi materjal: metall; 13 Tootja: Forster (või samaväärne analoog); 14 Mudel või toote tunnus: Fuego Light (või samaväärne analoog); 15 Tooteinfo: Undefined; 16 Kasutus- ja hooldusjuhend: Undefined
AC_Pset_RenovationAndPhasing - Renovation Status: New
Pset_CurtainWallCommon - IsExternal: no

# IfcCurtainWall: KS-11, Klaas-sein
In: 0 korrus
Type - ElementType: Element type KS-11
Classification: 0 TELLIJA KULUD (EHITUSKULUDE LIIGITAMINE EVS 885:2005); 1.7 IfcCurtainWall (rippfassaad) (_RKAS BIM + ARCHICAD Classification)
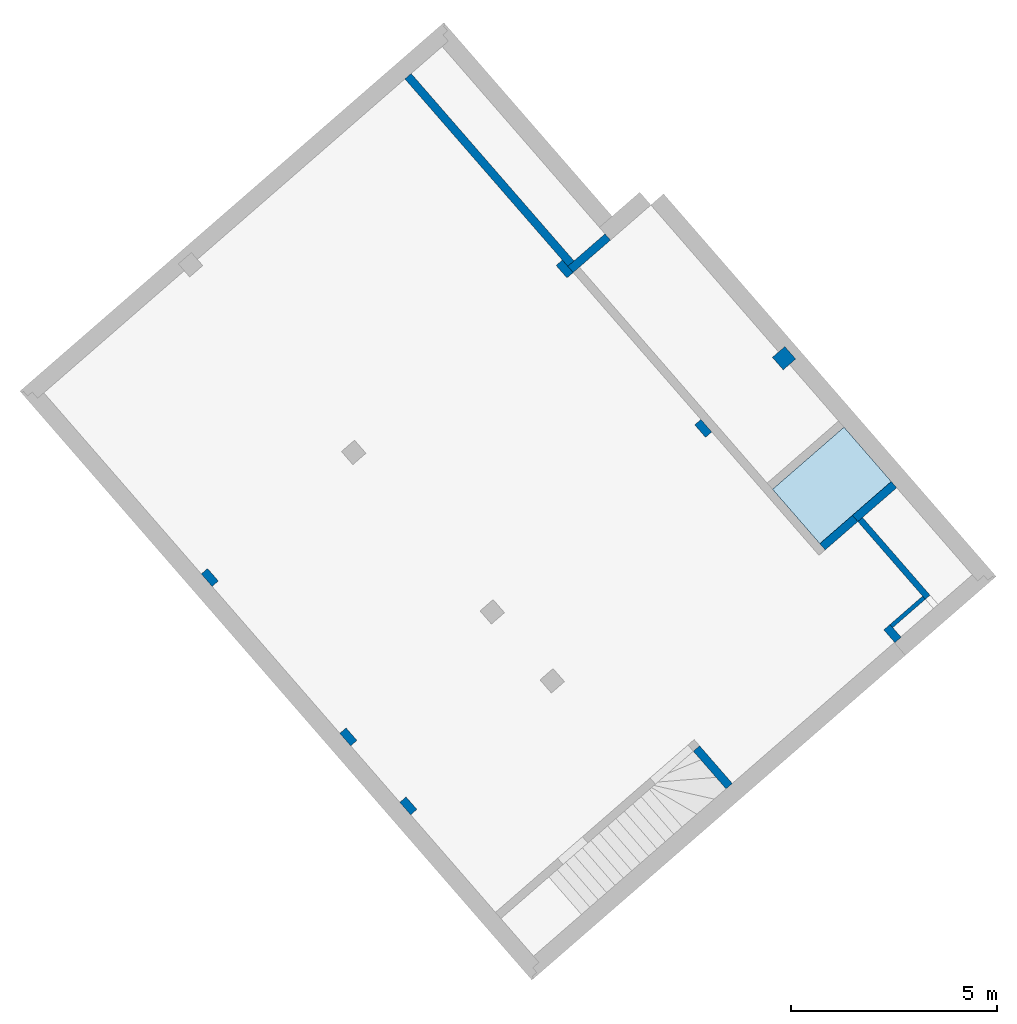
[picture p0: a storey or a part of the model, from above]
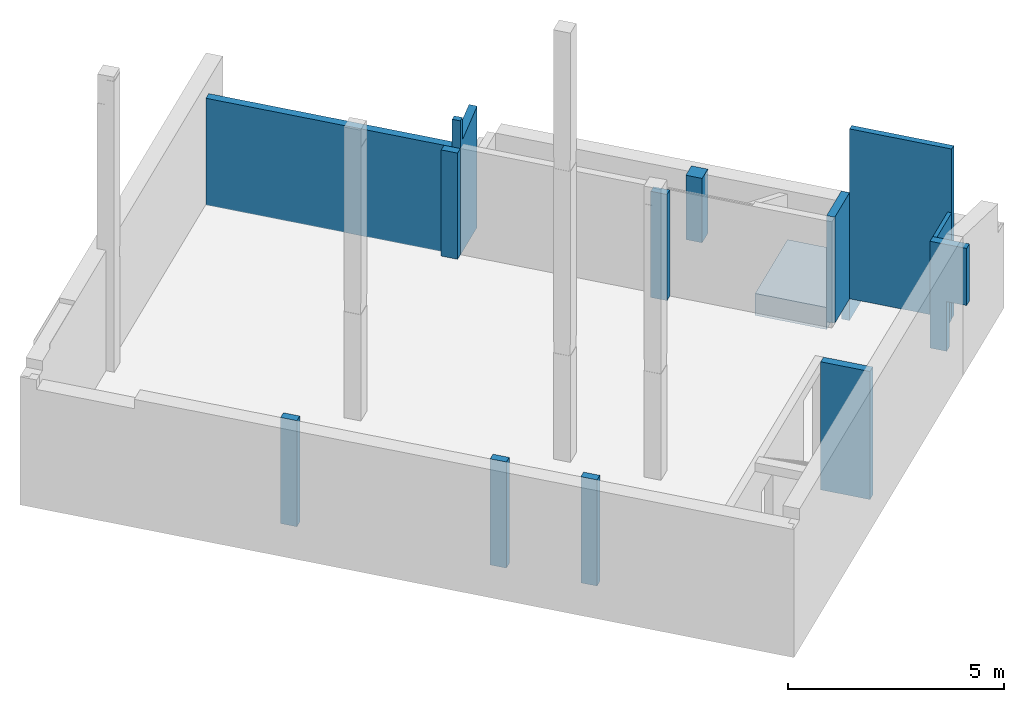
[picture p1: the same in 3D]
Properties of the parts of a building model (IFC2X3), part 3 of 13

# IfcCurtainWall: KS-11, Klaas-sein
Rippfassaad - 01 Nimetus: Klaas-sein; 02 Materjal: Klaas; Metall; 03 Kategooria / tüüp: KS-11; 04 Pindala: Pinna pindala: 1,9; Pinna pindala ka. Äärte ala1,9 Täpsustus: 1,9 m2; 05 Helipidavus: 38dB; 06 Klaaspakett: 6+1+6 kilelaminaadiga karastatud kirgas klaas; 07 Soojusläbivus: -; 08 Päikesekiirgus tegur (g-väärtus): -; 09 Tulekindlus: nõudeid ei esitata; 10 Raamistiku jaotus: -; 11 Paneelide materjal: kirgas klaas; 12 Karkassi materjal: metall; 13 Tootja: Forster (või samaväärne analoog); 14 Mudel või toote tunnus: Fuego Light (või samaväärne analoog); 15 Tooteinfo: Undefined; 16 Kasutus- ja hooldusjuhend: Undefined
AC_Pset_RenovationAndPhasing - Renovation Status: New
Pset_CurtainWallCommon - IsExternal: no

# IfcCurtainWall: KS-13, Klaas-sein
In: 0 korrus
Type - ElementType: Element type KS-13
Classification: 1.7 IfcCurtainWall (rippfassaad) (_RKAS BIM + ARCHICAD Classification)
Rippfassaad - 01 Nimetus: Klaas-sein; 02 Materjal: Klaas; Metall; 03 Kategooria / tüüp: KS-13; 04 Pindala: Pinna pindala: 11,0; Pinna pindala ka. Äärte ala11,0 Täpsustus: 11,0 m2; 05 Helipidavus: 38dB; 06 Klaaspakett: 6+1+6 kilelaminaadiga karastatud kirgas klaas; 07 Soojusläbivus: -; 08 Päikesekiirgus tegur (g-väärtus): -; 09 Tulekindlus: nõudeid ei esitata; 10 Raamistiku jaotus: jaotatud neljaks; 11 Paneelide materjal: kirgas klaas; 12 Karkassi materjal: metall; 13 Tootja: Forster (või samaväärne analoog); 14 Mudel või toote tunnus: Fuego Light (või samaväärne analoog); 15 Tooteinfo: Undefined; 16 Kasutus- ja hooldusjuhend: Undefined
AC_Pset_RenovationAndPhasing - Renovation Status: New
Pset_CurtainWallCommon - IsExternal: no

# IfcCurtainWall: KS-14, Klaas-sein
In: 0 korrus
Type - ElementType: Element type KS-14
Classification: 0 TELLIJA KULUD (EHITUSKULUDE LIIGITAMINE EVS 885:2005); 1.7 IfcCurtainWall (rippfassaad) (_RKAS BIM + ARCHICAD Classification)
Rippfassaad - 01 Nimetus: Klaas-sein; 02 Materjal: Klaas; Metall; 03 Kategooria / tüüp: KS-14; 04 Pindala: Pinna pindala: 16,5; Pinna pindala ka. Äärte ala16,5 Täpsustus: 16,5 m2; 05 Helipidavus: 38dB; 06 Klaaspakett: 6+1+6 kilelaminaadiga karastatud kirgas klaas; 07 Soojusläbivus: -; 08 Päikesekiirgus tegur (g-väärtus): -; 09 Tulekindlus: nõudeid ei esitata; 10 Raamistiku jaotus: jaotatud kuueks; 11 Paneelide materjal: kirgas klaas; 12 Karkassi materjal: metall; 13 Tootja: Forster (või samaväärne analoog); 14 Mudel või toote tunnus: Fuego Light (või samaväärne analoog); 15 Tooteinfo: Undefined; 16 Kasutus- ja hooldusjuhend: Undefined
AC_Pset_RenovationAndPhasing - Renovation Status: New
Pset_CurtainWallCommon - IsExternal: no

# IfcCurtainWall: KS-15, Klaas-sein
In: 0 korrus
Type - ElementType: Element type KS-15
Classification: 1.7 IfcCurtainWall (rippfassaad) (_RKAS BIM + ARCHICAD Classification)
Rippfassaad - 01 Nimetus: Klaas-sein; 02 Materjal: Klaas; Metall; 03 Kategooria / tüüp: KS-15; 04 Pindala: Pinna pindala: 5,8; Pinna pindala ka. Äärte ala5,8 Täpsustus: 5,8 m2; 05 Helipidavus: 38dB; 06 Klaaspakett: 6+1+6 kilelaminaadiga karastatud kirgas klaas; 07 Soojusläbivus: -; 08 Päikesekiirgus tegur (g-väärtus): -; 09 Tulekindlus: nõudeid ei esitata; 10 Raamistiku jaotus: jaotatud kaheks; 11 Paneelide materjal: kirgas klaas; 12 Karkassi materjal: metall; 13 Tootja: Forster (või samaväärne analoog); 14 Mudel või toote tunnus: Fuego Light (või samaväärne analoog); 15 Tooteinfo: Undefined; 16 Kasutus- ja hooldusjuhend: Undefined
AC_Pset_RenovationAndPhasing - Renovation Status: New
Pset_CurtainWallCommon - IsExternal: no

# IfcCurtainWall: KS-16 (2)
In: 1 korrus
Type - ElementType: Element type KS-16
Rippfassaad - 01 Nimetus: Klaas-sein; 02 Materjal: Klaas; Metall; 03 Kategooria / tüüp: KS-16; 04 Pindala: Pinna pindala: 9,8; Pinna pindala ka. Äärte ala9,8 Täpsustus: 9,8 m2; 05 Helipidavus: -; 06 Klaaspakett: kahekordne karastatud klaasist klaaspakett, klaaside vahelised liistud musta värvi; 07 Soojusläbivus: -; 08 Päikesekiirgus tegur (g-väärtus): -; 09 Tulekindlus: nõudeid ei esitata; 10 Raamistiku jaotus: jaotatud neljaks; 11 Paneelide materjal: kirgas karastatud klaas; 12 Karkassi materjal: metall, värvitud tehaseliselt tumehalliks RAL7016 (Anthrazitgrau); 13 Tootja: Schüco (või samaväärne analoog); 14 Mudel või toote tunnus: FW50+ (või samaväärne analoog); 15 Tooteinfo: Undefined; 16 Kasutus- ja hooldusjuhend: Undefined
AC_Pset_RenovationAndPhasing - Renovation Status: New
Pset_CurtainWallCommon - IsExternal: no
Name | Classification
Klaas-sein | 1.7 IfcCurtainWall (rippfassaad) (_RKAS BIM + ARCHICAD Classification)
Klaas-sein | 0 TELLIJA KULUD (EHITUSKULUDE LIIGITAMINE EVS 885:2005); 1.7 IfcCurtainWall (rippfassaad) (_RKAS BIM + ARCHICAD Classification)

# IfcCurtainWall: KS-17 (5)
In: 1 korrus
Type - ElementType: Element type KS-17
Classification: 1.7 IfcCurtainWall (rippfassaad) (_RKAS BIM + ARCHICAD Classification)
Rippfassaad - 01 Nimetus: Klaas-sein; 02 Materjal: Klaas; Metall; 03 Kategooria / tüüp: KS-17; 04 Pindala: Pinna pindala: 1,5; Pinna pindala ka. Äärte ala1,5 Täpsustus: 1,5 m2; 05 Helipidavus: 50dB; 06 Klaaspakett: 2xSSG Stadip Silence laminaadiga kirgas klaas; 07 Soojusläbivus: -; 08 Päikesekiirgus tegur (g-väärtus): -; 09 Tulekindlus: nõudeid ei esitata; 10 Raamistiku jaotus: -; 11 Paneelide materjal: 2xSSG Stadip Silence laminaadiga kirgas klaas; 12 Karkassi materjal: metall; 13 Tootja: Forster (või samaväärne analoog); 14 Mudel või toote tunnus: Fuego Light (või samaväärne analoog); 15 Tooteinfo: Undefined; 16 Kasutus- ja hooldusjuhend: Undefined
AC_Pset_RenovationAndPhasing - Renovation Status: New
Pset_CurtainWallCommon - IsExternal: no

# IfcCurtainWall: KS-18 (2)
In: 1 korrus
Type - ElementType: Element type KS-18
Classification: 1.7 IfcCurtainWall (rippfassaad) (_RKAS BIM + ARCHICAD Classification)
Rippfassaad - 01 Nimetus: Klaas-sein; 02 Materjal: Klaas; Metall; 03 Kategooria / tüüp: KS-18; 04 Pindala: Pinna pindala: 9,0; Pinna pindala ka. Äärte ala9,0 Täpsustus: 9,0 m2; 05 Helipidavus: -; 06 Klaaspakett: kahekordne klaaspakett, klaasid karastatud, klaaside vahelised liistud musta värvi; 07 Soojusläbivus: -; 08 Päikesekiirgus tegur (g-väärtus): -; 09 Tulekindlus: nõudeid ei esitata; 10 Raamistiku jaotus: jaotatud neljaks; 11 Paneelide materjal: kirgas karastatud klaas; 12 Karkassi materjal: metall, värvitud tehaseliselt tumehalliks RAL7016 (Anthrazitgrau); 13 Tootja: Schüco (või samaväärne analoog); 14 Mudel või toote tunnus: FWS 50 (või samaväärne analoog); 15 Tooteinfo: Undefined; 16 Kasutus- ja hooldusjuhend: Undefined
AC_Pset_RenovationAndPhasing - Renovation Status: New
Pset_CurtainWallCommon - IsExternal: no

# IfcCurtainWall: KS-19, Klaasfassaad
In: 1 korrus
Type - ElementType: Element type KS-19
Classification: 1.7 IfcCurtainWall (rippfassaad) (_RKAS BIM + ARCHICAD Classification)
Rippfassaad - 01 Nimetus: Klaasfassaad; 02 Materjal: Klaas; Metall; 03 Kategooria / tüüp: KS-19; 04 Pindala: Pinna pindala: 9,3; Pinna pindala ka. Äärte ala9,3 Täpsustus: 9,3 m2; 05 Helipidavus: -; 06 Klaaspakett: kahekordne klaaspakett, klaasid karastatud, klaaside vahelised liistud musta värvi; 07 Soojusläbivus: -; 08 Päikesekiirgus tegur (g-väärtus): -; 09 Tulekindlus: nõudeid ei esitata; 10 Raamistiku jaotus: jaotatud neljaks; 11 Paneelide materjal: kirgas karastatud klaas; 12 Karkassi materjal: metall, värvitud tehaseliselt tumehalliks RAL7016 (Anthrazitgrau); 13 Tootja: Schüco (või samaväärne analoog); 14 Mudel või toote tunnus: FWS 50 (või samaväärne analoog); 15 Tooteinfo: Undefined; 16 Kasutus- ja hooldusjuhend: Undefined
AC_Pset_RenovationAndPhasing - Renovation Status: New
Pset_CurtainWallCommon - IsExternal: no

# IfcCurtainWall: KS-20, Klaas-sein
In: 1,5 korrus
Type - ElementType: Element type KS-20
Classification: 1.7 IfcCurtainWall (rippfassaad) (_RKAS BIM + ARCHICAD Classification)
Rippfassaad - 01 Nimetus: Klaas-sein; 02 Materjal: Klaas; Metall; 03 Kategooria / tüüp: KS-20; 04 Pindala: Pinna pindala: 14,9; Pinna pindala ka. Äärte ala14,9 Täpsustus: 14,9 m2; 05 Helipidavus: 34dB; 06 Klaaspakett: Kahekordne; 07 Soojusläbivus: -; 08 Päikesekiirgus tegur (g-väärtus): -; 09 Tulekindlus: EI 60; 10 Raamistiku jaotus: jaotatud viieks; 11 Paneelide materjal: kirgas tuletõkke klaas, üks klaas karastatud, teine lamineeritud; 12 Karkassi materjal: metall, värvitud tehaseliselt tumehalliks RAL7016 (Anthrazitgrau); 13 Tootja: Forster (või samaväärne analoog); 14 Mudel või toote tunnus: Fuego Light (või samaväärne analoog); 15 Tooteinfo: Undefined; 16 Kasutus- ja hooldusjuhend: Undefined
AC_Pset_RenovationAndPhasing - Renovation Status: New
Pset_CurtainWallCommon - IsExternal: no

# IfcCurtainWall: KS-21, Klaas-sein
In: 0 korrus
Type - ElementType: Element type KS-21
Classification: 1.7 IfcCurtainWall (rippfassaad) (_RKAS BIM + ARCHICAD Classification)
Rippfassaad - 01 Nimetus: Klaas-sein; 02 Materjal: Klaas; Metall; 03 Kategooria / tüüp: KS-21; 04 Pindala: Pinna pindala: 4,3; Pinna pindala ka. Äärte ala4,3 Täpsustus: 4,0 m2; 05 Helipidavus: -; 06 Klaaspakett: 6+1+6 kilelaminaadiga karastatud kirgas klaas; 07 Soojusläbivus: -; 08 Päikesekiirgus tegur (g-väärtus): -; 09 Tulekindlus: nõudeid ei esitata; 10 Raamistiku jaotus: jaotatud kolmeks; 11 Paneelide materjal: kirgas klaas; 12 Karkassi materjal: metall, värvitud tehaseliselt tumehalliks RAL7016 (Anthrazitgrau); 13 Tootja: Forster (või samaväärne analoog); 14 Mudel või toote tunnus: Fuego Light (või samaväärne analoog); 15 Tooteinfo: Undefined; 16 Kasutus- ja hooldusjuhend: Undefined
AC_Pset_RenovationAndPhasing - Renovation Status: New
Pset_CurtainWallCommon - IsExternal: no

# IfcDiscreteAccessory: 1045 x 2256 x 20, KLF-17 klaaspakett
In: 1 korrus
Type - ElementType: Element type KLF-17 klaaspakett
Classification: 1.8 IfcDiscreteAccessory (tarvik) (_RKAS BIM + ARCHICAD Classification); Material: Klaas
AC_Pset_RenovationAndPhasing - Renovation Status: New

# IfcDiscreteAccessory: 1045 x 2281 x 20, KLF-17 klaaspakett
In: 1 korrus
Type - ElementType: Element type KLF-17 klaaspakett
Classification: 1.8 IfcDiscreteAccessory (tarvik) (_RKAS BIM + ARCHICAD Classification); Material: Klaas
AC_Pset_RenovationAndPhasing - Renovation Status: New

# IfcDiscreteAccessory: 1045 x 2305 x 20, KLF-17 klaaspakett
In: 1 korrus
Type - ElementType: Element type KLF-17 klaaspakett
Classification: 1.8 IfcDiscreteAccessory (tarvik) (_RKAS BIM + ARCHICAD Classification); Material: Klaas
AC_Pset_RenovationAndPhasing - Renovation Status: New

# IfcDiscreteAccessory: 1045 x 2320 x 20 (3)
In: 1 korrus
Type - ElementType: Element type KLF-17 klaaspakett
Classification: 1.8 IfcDiscreteAccessory (tarvik) (_RKAS BIM + ARCHICAD Classification); Material: Klaas
AC_Pset_RenovationAndPhasing - Renovation Status: New

# IfcDiscreteAccessory: 1045 x 2380 x 20, KLF-17 klaaspakett
In: 1 korrus
Type - ElementType: Element type KLF-17 klaaspakett
Classification: 1.8 IfcDiscreteAccessory (tarvik) (_RKAS BIM + ARCHICAD Classification); Material: Klaas
AC_Pset_RenovationAndPhasing - Renovation Status: New

# IfcDiscreteAccessory: 1045 x 2655 x 20 (3)
In: 1 korrus
Type - ElementType: Element type KLF-17 klaaspakett
Classification: 1.8 IfcDiscreteAccessory (tarvik) (_RKAS BIM + ARCHICAD Classification); Material: Klaas
AC_Pset_RenovationAndPhasing - Renovation Status: New

# IfcDiscreteAccessory: 1045 x 520 x 20 (4)
In: 1 korrus
Type - ElementType: Element type KLF-17 klaaspakett
Classification: 1.8 IfcDiscreteAccessory (tarvik) (_RKAS BIM + ARCHICAD Classification); Material: Klaas
AC_Pset_RenovationAndPhasing - Renovation Status: New

# IfcDiscreteAccessory: 1160 x 2223 x 20, KLF-17 klaaspakett
In: 1 korrus
Type - ElementType: Element type KLF-17 klaaspakett
Classification: 1.8 IfcDiscreteAccessory (tarvik) (_RKAS BIM + ARCHICAD Classification); Material: Klaas
AC_Pset_RenovationAndPhasing - Renovation Status: New

# IfcDiscreteAccessory: 1160 x 2320 x 20, KLF-17 klaaspakett
In: 1 korrus
Type - ElementType: Element type KLF-17 klaaspakett
Classification: 1.8 IfcDiscreteAccessory (tarvik) (_RKAS BIM + ARCHICAD Classification); Material: Klaas
AC_Pset_RenovationAndPhasing - Renovation Status: New

# IfcDiscreteAccessory: 1160 x 2655 x 20, KLF-17 klaaspakett
In: 1 korrus
Type - ElementType: Element type KLF-17 klaaspakett
Classification: 1.8 IfcDiscreteAccessory (tarvik) (_RKAS BIM + ARCHICAD Classification); Material: Klaas
AC_Pset_RenovationAndPhasing - Renovation Status: New

# IfcDiscreteAccessory: 1160 x 520 x 20, KLF-17 klaaspakett
In: 1 korrus
Type - ElementType: Element type KLF-17 klaaspakett
Classification: 1.8 IfcDiscreteAccessory (tarvik) (_RKAS BIM + ARCHICAD Classification); Material: Klaas
AC_Pset_RenovationAndPhasing - Renovation Status: New

# IfcDiscreteAccessory: 1170 x 2142 x 20, KLF-17 klaaspakett
In: 1 korrus
Type - ElementType: Element type KLF-17 klaaspakett
Classification: 1.8 IfcDiscreteAccessory (tarvik) (_RKAS BIM + ARCHICAD Classification); Material: Klaas
AC_Pset_RenovationAndPhasing - Renovation Status: New

# IfcDiscreteAccessory: 1170 x 2169 x 20, KLF-17 klaaspakett
In: 1 korrus
Type - ElementType: Element type KLF-17 klaaspakett
Classification: 1.8 IfcDiscreteAccessory (tarvik) (_RKAS BIM + ARCHICAD Classification); Material: Klaas
AC_Pset_RenovationAndPhasing - Renovation Status: New

# IfcDiscreteAccessory: 1170 x 2196 x 20, KLF-17 klaaspakett
In: 1 korrus
Type - ElementType: Element type KLF-17 klaaspakett
Classification: 1.8 IfcDiscreteAccessory (tarvik) (_RKAS BIM + ARCHICAD Classification); Material: Klaas
AC_Pset_RenovationAndPhasing - Renovation Status: New

# IfcDiscreteAccessory: 1170 x 2320 x 20 (3)
In: 1 korrus
Type - ElementType: Element type KLF-17 klaaspakett
Classification: 1.8 IfcDiscreteAccessory (tarvik) (_RKAS BIM + ARCHICAD Classification); Material: Klaas
AC_Pset_RenovationAndPhasing - Renovation Status: New

# IfcDiscreteAccessory: 1170 x 2655 x 20 (3)
In: 1 korrus
Type - ElementType: Element type KLF-17 klaaspakett
Classification: 1.8 IfcDiscreteAccessory (tarvik) (_RKAS BIM + ARCHICAD Classification); Material: Klaas
AC_Pset_RenovationAndPhasing - Renovation Status: New

# IfcDiscreteAccessory: 1170 x 520 x 20 (3)
In: 1 korrus
Type - ElementType: Element type KLF-17 klaaspakett
Classification: 1.8 IfcDiscreteAccessory (tarvik) (_RKAS BIM + ARCHICAD Classification); Material: Klaas
AC_Pset_RenovationAndPhasing - Renovation Status: New

# IfcDiscreteAccessory: 1195 x 2320 x 20, KLF-17 klaaspakett
In: 1 korrus
Type - ElementType: Element type KLF-17 klaaspakett
Classification: 1.8 IfcDiscreteAccessory (tarvik) (_RKAS BIM + ARCHICAD Classification); Material: Klaas
AC_Pset_RenovationAndPhasing - Renovation Status: New

# IfcDiscreteAccessory: 1195 x 520 x 20, KLF-17 klaaspakett
In: 1 korrus
Type - ElementType: Element type KLF-17 klaaspakett
Classification: 1.8 IfcDiscreteAccessory (tarvik) (_RKAS BIM + ARCHICAD Classification); Material: Klaas
AC_Pset_RenovationAndPhasing - Renovation Status: New

# IfcDiscreteAccessory: 1260 x 1988 x 20, KLF-17 klaaspakett
In: 1 korrus
Type - ElementType: Element type KLF-17 klaaspakett
Classification: 1.8 IfcDiscreteAccessory (tarvik) (_RKAS BIM + ARCHICAD Classification); Material: Klaas
AC_Pset_RenovationAndPhasing - Renovation Status: New

# IfcDiscreteAccessory: 1260 x 2017 x 20, KLF-17 klaaspakett
In: 1 korrus
Type - ElementType: Element type KLF-17 klaaspakett
Classification: 1.8 IfcDiscreteAccessory (tarvik) (_RKAS BIM + ARCHICAD Classification); Material: Klaas
AC_Pset_RenovationAndPhasing - Renovation Status: New

# IfcDiscreteAccessory: 1260 x 2047 x 20, KLF-17 klaaspakett
In: 1 korrus
Type - ElementType: Element type KLF-17 klaaspakett
Classification: 1.8 IfcDiscreteAccessory (tarvik) (_RKAS BIM + ARCHICAD Classification); Material: Klaas
AC_Pset_RenovationAndPhasing - Renovation Status: New

# IfcDiscreteAccessory: 1260 x 2076 x 20, KLF-17 klaaspakett
In: 1 korrus
Type - ElementType: Element type KLF-17 klaaspakett
Classification: 1.8 IfcDiscreteAccessory (tarvik) (_RKAS BIM + ARCHICAD Classification); Material: Klaas
AC_Pset_RenovationAndPhasing - Renovation Status: New

# IfcDiscreteAccessory: 1260 x 2106 x 20, KLF-17 klaaspakett
In: 1 korrus
Type - ElementType: Element type KLF-17 klaaspakett
Classification: 1.8 IfcDiscreteAccessory (tarvik) (_RKAS BIM + ARCHICAD Classification); Material: Klaas
AC_Pset_RenovationAndPhasing - Renovation Status: New

# IfcDiscreteAccessory: 1260 x 2320 x 20 (4)
In: 1 korrus
Type - ElementType: Element type KLF-17 klaaspakett
Classification: 1.8 IfcDiscreteAccessory (tarvik) (_RKAS BIM + ARCHICAD Classification); Material: Klaas
AC_Pset_RenovationAndPhasing - Renovation Status: New

# IfcDiscreteAccessory: 1260 x 2655 x 20 (3)
In: 1 korrus
Type - ElementType: Element type KLF-17 klaaspakett
Classification: 1.8 IfcDiscreteAccessory (tarvik) (_RKAS BIM + ARCHICAD Classification); Material: Klaas
AC_Pset_RenovationAndPhasing - Renovation Status: New

# IfcDiscreteAccessory: 1260 x 520 x 20 (5)
In: 1 korrus
Type - ElementType: Element type KLF-17 klaaspakett
Classification: 1.8 IfcDiscreteAccessory (tarvik) (_RKAS BIM + ARCHICAD Classification); Material: Klaas
AC_Pset_RenovationAndPhasing - Renovation Status: New

# IfcDiscreteAccessory: 370 x 2114 x 20, KLF-17 klaaspakett
In: 1 korrus
Type - ElementType: Element type KLF-17 klaaspakett
Classification: 1.8 IfcDiscreteAccessory (tarvik) (_RKAS BIM + ARCHICAD Classification); Material: Klaas
AC_Pset_RenovationAndPhasing - Renovation Status: New

# IfcDiscreteAccessory: 370 x 2232 x 20, KLF-17 klaaspakett
In: 1 korrus
Type - ElementType: Element type KLF-17 klaaspakett
Classification: 1.8 IfcDiscreteAccessory (tarvik) (_RKAS BIM + ARCHICAD Classification); Material: Klaas
AC_Pset_RenovationAndPhasing - Renovation Status: New

# IfcDiscreteAccessory: 370 x 2320 x 20 (2)
In: 1 korrus
Type - ElementType: Element type KLF-17 klaaspakett
Classification: 1.8 IfcDiscreteAccessory (tarvik) (_RKAS BIM + ARCHICAD Classification); Material: Klaas
AC_Pset_RenovationAndPhasing - Renovation Status: New

# IfcDiscreteAccessory: 370 x 2655 x 20 (2)
In: 1 korrus
Type - ElementType: Element type KLF-17 klaaspakett
Classification: 1.8 IfcDiscreteAccessory (tarvik) (_RKAS BIM + ARCHICAD Classification); Material: Klaas
AC_Pset_RenovationAndPhasing - Renovation Status: New

# IfcDiscreteAccessory: 370 x 520 x 20 (2)
In: 1 korrus
Type - ElementType: Element type KLF-17 klaaspakett
Classification: 1.8 IfcDiscreteAccessory (tarvik) (_RKAS BIM + ARCHICAD Classification); Material: Klaas
AC_Pset_RenovationAndPhasing - Renovation Status: New

# IfcDiscreteAccessory: 5 x 1959 x 20, KLF-17 klaaspakett
In: 1 korrus
Type - ElementType: Element type KLF-17 klaaspakett
Classification: 1.8 IfcDiscreteAccessory (tarvik) (_RKAS BIM + ARCHICAD Classification); Material: Klaas
AC_Pset_RenovationAndPhasing - Renovation Status: New

# IfcDiscreteAccessory: 5 x 2320 x 20, KLF-17 klaaspakett
In: 1 korrus
Type - ElementType: Element type KLF-17 klaaspakett
Classification: 1.8 IfcDiscreteAccessory (tarvik) (_RKAS BIM + ARCHICAD Classification); Material: Klaas
AC_Pset_RenovationAndPhasing - Renovation Status: New

# IfcDiscreteAccessory: 5 x 2655 x 20, KLF-17 klaaspakett
In: 1 korrus
Type - ElementType: Element type KLF-17 klaaspakett
Classification: 1.8 IfcDiscreteAccessory (tarvik) (_RKAS BIM + ARCHICAD Classification); Material: Klaas
AC_Pset_RenovationAndPhasing - Renovation Status: New

# IfcDiscreteAccessory: 5 x 520 x 20, KLF-17 klaaspakett
In: 1 korrus
Type - ElementType: Element type KLF-17 klaaspakett
Classification: 1.8 IfcDiscreteAccessory (tarvik) (_RKAS BIM + ARCHICAD Classification); Material: Klaas
AC_Pset_RenovationAndPhasing - Renovation Status: New

# IfcDiscreteAccessory: 50 x 150 (139)
In: 1 korrus
Type - ElementType: Element type KLF-14 profiil
AC_Pset_RenovationAndPhasing - Renovation Status: New
Name | Classification | Material
88 x KLF-14 profiil | 1.8 IfcDiscreteAccessory (tarvik) (_RKAS BIM + ARCHICAD Classification) | Aluminium MUST (3)
50 x KLF-14 profiil | 1.8 IfcDiscreteAccessory (tarvik) (_RKAS BIM + ARCHICAD Classification) | Aluminium MUST (2)
KLF-14 profiil | 0 TELLIJA KULUD (EHITUSKULUDE LIIGITAMINE EVS 885:2005); 1.8 IfcDiscreteAccessory (tarvik) (_RKAS BIM + ARCHICAD Classification) | Aluminium MUST (2)

# IfcDiscreteAccessory: 50 x 150 (7)
In: 2 korrus
Type - ElementType: Element type KS-02 profiil
Classification: 1.8 IfcDiscreteAccessory (tarvik) (_RKAS BIM + ARCHICAD Classification)
AC_Pset_RenovationAndPhasing - Renovation Status: New
Name | Material
6 x KS-02 profiil | Aluminium MUST (3)
KS-02 profiil | Aluminium MUST (2)

# IfcDiscreteAccessory: 50 x 150 (19)
In: 1,5 korrus
Type - ElementType: Element type KS-20 profiil
Classification: 1.8 IfcDiscreteAccessory (tarvik) (_RKAS BIM + ARCHICAD Classification)
AC_Pset_RenovationAndPhasing - Renovation Status: New
Name | Material
14 x KS-20 profiil | Aluminium MUST (3)
5 x KS-20 profiil | Aluminium MUST (2)

# IfcDiscreteAccessory: 50 x 150 (15)
In: 0 korrus
Type - ElementType: Element type KS-21 profiil
Classification: 1.8 IfcDiscreteAccessory (tarvik) (_RKAS BIM + ARCHICAD Classification)
AC_Pset_RenovationAndPhasing - Renovation Status: New
Name | Material
11 x KS-21 profiil | Aluminium MUST
4 x KS-21 profiil | Aluminium MUST (2)

# IfcDiscreteAccessory: 50 x 200 (10)
In: 0 korrus
Type - ElementType: Element type KLF-02 profiil
Classification: 1.8 IfcDiscreteAccessory (tarvik) (_RKAS BIM + ARCHICAD Classification)
AC_Pset_RenovationAndPhasing - Renovation Status: New
Name | Material
2 x KLF-02 profiil | Aluminium MUST (2)
8 x KLF-02 profiil | Aluminium MUST

# IfcDiscreteAccessory: 50 x 200 (9)
In: 0 korrus
Type - ElementType: Element type KLF-03 profiil
Classification: 1.8 IfcDiscreteAccessory (tarvik) (_RKAS BIM + ARCHICAD Classification)
AC_Pset_RenovationAndPhasing - Renovation Status: New
Name
7 x KLF-03 profiil
2 x KLF-03 profiil | Material: Aluminium MUST (2)

# IfcDiscreteAccessory: 50 x 200 (32)
In: 0 korrus
Type - ElementType: Element type KLF-04 profiil
Classification: 1.8 IfcDiscreteAccessory (tarvik) (_RKAS BIM + ARCHICAD Classification)
AC_Pset_RenovationAndPhasing - Renovation Status: New
Name | Material
10 x KLF-04 profiil | Aluminium MUST
8 x KLF-04 profiil | Aluminium MUST (2)
14 x KLF-04 profiil

# IfcDiscreteAccessory: 50 x 200 (9)
In: 0 korrus
Type - ElementType: Element type KLF-05 profiil
Classification: 1.8 IfcDiscreteAccessory (tarvik) (_RKAS BIM + ARCHICAD Classification)
AC_Pset_RenovationAndPhasing - Renovation Status: New
Name | Material
7 x KLF-05 profiil | Aluminium MUST (3)
2 x KLF-05 profiil | Aluminium MUST (2)

# IfcDiscreteAccessory: 50 x 200 (10)
In: 0 korrus
Type - ElementType: Element type KLF-06 profiil
Classification: 1.8 IfcDiscreteAccessory (tarvik) (_RKAS BIM + ARCHICAD Classification)
AC_Pset_RenovationAndPhasing - Renovation Status: New
Name | Material
8 x KLF-06 profiil | Aluminium MUST (3)
2 x KLF-06 profiil | Aluminium MUST (2)

# IfcDiscreteAccessory: 50 x 200 (10)
In: 0 korrus
Type - ElementType: Element type KLF-07 profiil
Classification: 1.8 IfcDiscreteAccessory (tarvik) (_RKAS BIM + ARCHICAD Classification)
AC_Pset_RenovationAndPhasing - Renovation Status: New
Name | Material
8 x KLF-07 profiil | Aluminium MUST
2 x KLF-07 profiil | Aluminium MUST (2)

# IfcDiscreteAccessory: 50 x 200 (16)
In: 1,5 korrus
Type - ElementType: Element type KLF-08 profiil
Classification: 1.8 IfcDiscreteAccessory (tarvik) (_RKAS BIM + ARCHICAD Classification)
AC_Pset_RenovationAndPhasing - Renovation Status: New
Name | Material
12 x KLF-08 profiil | Aluminium MUST
4 x KLF-08 profiil | Aluminium MUST (2)

# IfcDiscreteAccessory: 50 x 200 (13)
In: 2 korrus
Type - ElementType: Element type KLF-09 profiil
Classification: 1.8 IfcDiscreteAccessory (tarvik) (_RKAS BIM + ARCHICAD Classification)
AC_Pset_RenovationAndPhasing - Renovation Status: New
Name | Material
10 x KLF-09 profiil | Aluminium MUST
3 x KLF-09 profiil | Aluminium MUST (2)

# IfcDiscreteAccessory: 50 x 200 (10)
In: 2 korrus
Type - ElementType: Element type KLF-10 profiil
Classification: 1.8 IfcDiscreteAccessory (tarvik) (_RKAS BIM + ARCHICAD Classification)
AC_Pset_RenovationAndPhasing - Renovation Status: New
Name | Material
8 x KLF-10 profiil | Aluminium MUST
2 x KLF-10 profiil | Aluminium MUST (2)

# IfcDiscreteAccessory: 50 x 200 (7)
In: 2 korrus
Type - ElementType: Element type KLF-12 profiil
Classification: 1.8 IfcDiscreteAccessory (tarvik) (_RKAS BIM + ARCHICAD Classification)
AC_Pset_RenovationAndPhasing - Renovation Status: New
Name | Material
6 x KLF-12 profiil | Aluminium MUST
KLF-12 profiil | Aluminium MUST (2)

# IfcDiscreteAccessory: 50 x 200 (102)
In: 1 korrus
Type - ElementType: Element type KLF-16 profiil
Classification: 1.8 IfcDiscreteAccessory (tarvik) (_RKAS BIM + ARCHICAD Classification)
AC_Pset_RenovationAndPhasing - Renovation Status: New
Name | Material
54 x KLF-16 profiil | Aluminium MUST (2)
48 x KLF-16 profiil | Aluminium MUST (3)

# IfcDiscreteAccessory: 50 x 200 (156)
In: 1 korrus
Type - ElementType: Element type KLF-17 profiil
Classification: 1.8 IfcDiscreteAccessory (tarvik) (_RKAS BIM + ARCHICAD Classification)
AC_Pset_RenovationAndPhasing - Renovation Status: New
Name | Material
112 x KLF-17 profiil | Aluminium MUST (2)
44 x KLF-17 profiil

# IfcDiscreteAccessory: 50 x 200 (12)
In: 2 korrus
Type - ElementType: Element type KS-01 profiil
Classification: 1.8 IfcDiscreteAccessory (tarvik) (_RKAS BIM + ARCHICAD Classification)
AC_Pset_RenovationAndPhasing - Renovation Status: New
Name | Material
9 x KS-01 profiil | Aluminium MUST (3)
3 x KS-01 profiil | Aluminium MUST (2)

# IfcDiscreteAccessory: 50 x 200 (42)
In: 0 korrus
Type - ElementType: Element type KS-07 profiil
Classification: 1.8 IfcDiscreteAccessory (tarvik) (_RKAS BIM + ARCHICAD Classification); Material: Aluminium MUST (3)
AC_Pset_RenovationAndPhasing - Renovation Status: New

# IfcDiscreteAccessory: 50 x 200 (4)
In: 0 korrus
Type - ElementType: Element type KS-08 profiil
Classification: 1.8 IfcDiscreteAccessory (tarvik) (_RKAS BIM + ARCHICAD Classification); Material: Aluminium MUST (3)
AC_Pset_RenovationAndPhasing - Renovation Status: New

# IfcDiscreteAccessory: 50 x 200 (4)
In: 0 korrus
Type - ElementType: Element type KS-09 profiil
Classification: 1.8 IfcDiscreteAccessory (tarvik) (_RKAS BIM + ARCHICAD Classification); Material: Aluminium MUST (3)
AC_Pset_RenovationAndPhasing - Renovation Status: New

# IfcDiscreteAccessory: 50 x 200 (6)
In: 0 korrus
Type - ElementType: Element type KS-11profiil
Classification: 1.8 IfcDiscreteAccessory (tarvik) (_RKAS BIM + ARCHICAD Classification); Material: Aluminium MUST (3)
AC_Pset_RenovationAndPhasing - Renovation Status: New

# IfcDiscreteAccessory: 50 x 200 (17)
In: 0 korrus
Type - ElementType: Element type KS-13 profiil
Classification: 1.8 IfcDiscreteAccessory (tarvik) (_RKAS BIM + ARCHICAD Classification)
AC_Pset_RenovationAndPhasing - Renovation Status: New
Name | Material
6 x KS-13 profiil | Aluminium MUST (2)
11 x KS-13 profiil | Aluminium MUST

# IfcDiscreteAccessory: 50 x 200 (25)
In: 0 korrus
Type - ElementType: Element type KS-14 profiil
Classification: 1.8 IfcDiscreteAccessory (tarvik) (_RKAS BIM + ARCHICAD Classification)
AC_Pset_RenovationAndPhasing - Renovation Status: New
Name
10 x KS-14 profiil | Material: Aluminium MUST (2)
15 x KS-14 profiil

# IfcDiscreteAccessory: 50 x 200 (10)
In: 0 korrus
Type - ElementType: Element type KS-15 profiil
Classification: 1.8 IfcDiscreteAccessory (tarvik) (_RKAS BIM + ARCHICAD Classification)
AC_Pset_RenovationAndPhasing - Renovation Status: New
Name | Material
2 x KS-15 profiil | Aluminium MUST (2)
8 x KS-15 profiil | Aluminium MUST

# IfcDiscreteAccessory: 50 x 200 (28)
In: 1 korrus
Type - ElementType: Element type KS-17 profiil
Classification: 1.8 IfcDiscreteAccessory (tarvik) (_RKAS BIM + ARCHICAD Classification); Material: Aluminium MUST (3)
AC_Pset_RenovationAndPhasing - Renovation Status: New

# IfcDiscreteAccessory: 50 x 250 (6)
In: 1 korrus
Type - ElementType: Element type KLF-11 profiil
Material: Aluminium MUST (2)
AC_Pset_RenovationAndPhasing - Renovation Status: New
Name | Classification
4 x KLF-11 profiil | 0 TELLIJA KULUD (EHITUSKULUDE LIIGITAMINE EVS 885:2005); 1.8 IfcDiscreteAccessory (tarvik) (_RKAS BIM + ARCHICAD Classification)
2 x KLF-11 profiil | 1.8 IfcDiscreteAccessory (tarvik) (_RKAS BIM + ARCHICAD Classification)

# IfcDiscreteAccessory: 50 x 250 (28)
In: 1 korrus
Type - ElementType: Element type KLF-13 profiil
AC_Pset_RenovationAndPhasing - Renovation Status: New
Name | Classification | Material
12 x KLF-13 profiil | 1.8 IfcDiscreteAccessory (tarvik) (_RKAS BIM + ARCHICAD Classification) | Aluminium MUST
8 x KLF-13 profiil | 1.8 IfcDiscreteAccessory (tarvik) (_RKAS BIM + ARCHICAD Classification) | Aluminium MUST (2)
8 x KLF-13 profiil | 0 TELLIJA KULUD (EHITUSKULUDE LIIGITAMINE EVS 885:2005); 1.8 IfcDiscreteAccessory (tarvik) (_RKAS BIM + ARCHICAD Classification) | Aluminium MUST (2)

# IfcDiscreteAccessory: 50 x 250 (5)
In: 1 korrus
Type - ElementType: Element type KLF-16 profiil
AC_Pset_RenovationAndPhasing - Renovation Status: New
Name | Classification | Material
KLF-16 profiil | 1.8 IfcDiscreteAccessory (tarvik) (_RKAS BIM + ARCHICAD Classification) | Aluminium MUST (2)
2 x KLF-16 profiil | 0 TELLIJA KULUD (EHITUSKULUDE LIIGITAMINE EVS 885:2005); 1.8 IfcDiscreteAccessory (tarvik) (_RKAS BIM + ARCHICAD Classification) | Aluminium MUST (2)
2 x KLF-16 profiil | 1.8 IfcDiscreteAccessory (tarvik) (_RKAS BIM + ARCHICAD Classification) | Aluminium MUST (3)

# IfcDiscreteAccessory: 50 x 250 (3)
In: 1 korrus
Type - ElementType: Element type KS-16 profiil
Material: Aluminium MUST (2)
AC_Pset_RenovationAndPhasing - Renovation Status: New
Name | Classification
KS-16 profiil | 1.8 IfcDiscreteAccessory (tarvik) (_RKAS BIM + ARCHICAD Classification)
2 x KS-16 profiil | 0 TELLIJA KULUD (EHITUSKULUDE LIIGITAMINE EVS 885:2005); 1.8 IfcDiscreteAccessory (tarvik) (_RKAS BIM + ARCHICAD Classification)

# IfcDiscreteAccessory: 50 x 250 (6)
In: 1 korrus
Type - ElementType: Element type KS-18 profiil
Material: Aluminium MUST (2)
AC_Pset_RenovationAndPhasing - Renovation Status: New
Name | Classification
2 x KS-18 profiil | 1.8 IfcDiscreteAccessory (tarvik) (_RKAS BIM + ARCHICAD Classification)
4 x KS-18 profiil | 0 TELLIJA KULUD (EHITUSKULUDE LIIGITAMINE EVS 885:2005); 1.8 IfcDiscreteAccessory (tarvik) (_RKAS BIM + ARCHICAD Classification)

# IfcDiscreteAccessory: 50 x 250 (3)
In: 1 korrus
Type - ElementType: Element type KS-19 profiil
Material: Aluminium MUST (2)
AC_Pset_RenovationAndPhasing - Renovation Status: New
Name | Classification
KS-19 profiil | 1.8 IfcDiscreteAccessory (tarvik) (_RKAS BIM + ARCHICAD Classification)
2 x KS-19 profiil | 0 TELLIJA KULUD (EHITUSKULUDE LIIGITAMINE EVS 885:2005); 1.8 IfcDiscreteAccessory (tarvik) (_RKAS BIM + ARCHICAD Classification)

# IfcDiscreteAccessory: 50 x 300 (16)
In: 1 korrus
Type - ElementType: Element type KLF-11 profiil
Classification: 1.8 IfcDiscreteAccessory (tarvik) (_RKAS BIM + ARCHICAD Classification); Material: Aluminium MUST
AC_Pset_RenovationAndPhasing - Renovation Status: New

# IfcDiscreteAccessory: 50 x 300 (14)
In: 2 korrus
Type - ElementType: Element type KLF-15 profiil
Classification: 1.8 IfcDiscreteAccessory (tarvik) (_RKAS BIM + ARCHICAD Classification)
AC_Pset_RenovationAndPhasing - Renovation Status: New
Name | Material
10 x KLF-15 profiil | Aluminium MUST
4 x KLF-15 profiil | Aluminium MUST (2)

# IfcDiscreteAccessory: 50 x 300 (7)
In: 1 korrus
Type - ElementType: Element type KLF-16 profiil
Classification: 1.8 IfcDiscreteAccessory (tarvik) (_RKAS BIM + ARCHICAD Classification); Material: Aluminium MUST
AC_Pset_RenovationAndPhasing - Renovation Status: New

# IfcDiscreteAccessory: 50 x 300 (7)
In: 1 korrus
Type - ElementType: Element type KS-16 profiil
Classification: 1.8 IfcDiscreteAccessory (tarvik) (_RKAS BIM + ARCHICAD Classification); Material: Aluminium MUST
AC_Pset_RenovationAndPhasing - Renovation Status: New

# IfcDiscreteAccessory: 50 x 300 (12)
In: 1 korrus
Type - ElementType: Element type KS-18 profiil
Classification: 1.8 IfcDiscreteAccessory (tarvik) (_RKAS BIM + ARCHICAD Classification); Material: Aluminium MUST
AC_Pset_RenovationAndPhasing - Renovation Status: New

# IfcDiscreteAccessory: 50 x 300 (6)
In: 1 korrus
Type - ElementType: Element type KS-19 profiil
Classification: 1.8 IfcDiscreteAccessory (tarvik) (_RKAS BIM + ARCHICAD Classification); Material: Aluminium MUST
AC_Pset_RenovationAndPhasing - Renovation Status: New

# IfcDiscreteAccessory: 50 x 350 (5)
In: 2 korrus
Type - ElementType: Element type KLF-15 profiil
Classification: 1.8 IfcDiscreteAccessory (tarvik) (_RKAS BIM + ARCHICAD Classification); Material: Aluminium MUST (2)
AC_Pset_RenovationAndPhasing - Renovation Status: New

# IfcDiscreteAccessory: Betoon - Konstuktsioon 300 x 300, Aluslaudis
In: 1 korrus
Type - ElementType: Element type Aluslaudis
Classification: 1.8 IfcDiscreteAccessory (tarvik) (_RKAS BIM + ARCHICAD Classification); Material: Betoon - Konstuktsioon
AC_Pset_RenovationAndPhasing - Renovation Status: New

# IfcDiscreteAccessory: Distinct Panel 101 x 64 x 20, KS-21 klaaspakett
In: 0 korrus
Type - ElementType: Element type KS-21 klaaspakett
Classification: 1.8 IfcDiscreteAccessory (tarvik) (_RKAS BIM + ARCHICAD Classification); Material: Klaas
AC_Pset_RenovationAndPhasing - Renovation Status: Existing

# IfcDiscreteAccessory: Distinct Panel 1010 x 380 x 20, KS-14 klaaspakett
In: 0 korrus
Type - ElementType: Element type KS-14 klaaspakett
Classification: 1.8 IfcDiscreteAccessory (tarvik) (_RKAS BIM + ARCHICAD Classification); Material: Klaas
AC_Pset_RenovationAndPhasing - Renovation Status: New

# IfcDiscreteAccessory: Distinct Panel 1015 x 2460 x 20, KLF-08 klaaspakett
In: 1,5 korrus
Type - ElementType: Element type KLF-08 klaaspakett
Classification: 1.8 IfcDiscreteAccessory (tarvik) (_RKAS BIM + ARCHICAD Classification); Material: Klaas
AC_Pset_RenovationAndPhasing - Renovation Status: New

# IfcDiscreteAccessory: Distinct Panel 1020 x 2460 x 20, KLF-08 klaaspakett
In: 1,5 korrus
Type - ElementType: Element type KLF-08 klaaspakett
Classification: 1.8 IfcDiscreteAccessory (tarvik) (_RKAS BIM + ARCHICAD Classification); Material: Klaas
AC_Pset_RenovationAndPhasing - Renovation Status: New

# IfcDiscreteAccessory: Distinct Panel 1059 x 1830 x 20, KLF-15 klaaspakett
In: 2 korrus
Type - ElementType: Element type KLF-15 klaaspakett
Classification: 1.8 IfcDiscreteAccessory (tarvik) (_RKAS BIM + ARCHICAD Classification); Material: Klaas
AC_Pset_RenovationAndPhasing - Renovation Status: Existing

# IfcDiscreteAccessory: Distinct Panel 1059 x 2430 x 20, KLF-15 klaaspakett
In: 2 korrus
Type - ElementType: Element type KLF-15 klaaspakett
Classification: 1.8 IfcDiscreteAccessory (tarvik) (_RKAS BIM + ARCHICAD Classification); Material: Klaas
AC_Pset_RenovationAndPhasing - Renovation Status: New

# IfcDiscreteAccessory: Distinct Panel 1060 x 1830 x 20, KLF-15 klaaspakett
In: 2 korrus
Type - ElementType: Element type KLF-15 klaaspakett
Classification: 1.8 IfcDiscreteAccessory (tarvik) (_RKAS BIM + ARCHICAD Classification); Material: Klaas
AC_Pset_RenovationAndPhasing - Renovation Status: Existing

# IfcDiscreteAccessory: Distinct Panel 1070 x 380 x 20, KS-13 klaaspakett
In: 0 korrus
Type - ElementType: Element type KS-13 klaaspakett
Classification: 1.8 IfcDiscreteAccessory (tarvik) (_RKAS BIM + ARCHICAD Classification); Material: Klaas
AC_Pset_RenovationAndPhasing - Renovation Status: New

# IfcDiscreteAccessory: Distinct Panel 1075 x 1645 x 20 (3)
In: 1 korrus
Type - ElementType: Element type KLF-16 klaaspakett
Classification: 1.8 IfcDiscreteAccessory (tarvik) (_RKAS BIM + ARCHICAD Classification); Material: Klaas
AC_Pset_RenovationAndPhasing - Renovation Status: Existing

# IfcDiscreteAccessory: Distinct Panel 1080 x 1645 x 20, KLF-16 klaaspakett
In: 1 korrus
Type - ElementType: Element type KLF-16 klaaspakett
Classification: 1.8 IfcDiscreteAccessory (tarvik) (_RKAS BIM + ARCHICAD Classification); Material: Klaas
AC_Pset_RenovationAndPhasing - Renovation Status: Existing

# IfcDiscreteAccessory: Distinct Panel 1080 x 1655 x 20 (2)
In: 1 korrus
Type - ElementType: Element type KS-18 klaaspakett
Classification: 1.8 IfcDiscreteAccessory (tarvik) (_RKAS BIM + ARCHICAD Classification); Material: Klaas
AC_Pset_RenovationAndPhasing - Renovation Status: New

# IfcDiscreteAccessory: Distinct Panel 1080 x 1830 x 20 (2)
In: 2 korrus
Type - ElementType: Element type KLF-15 klaaspakett
Classification: 1.8 IfcDiscreteAccessory (tarvik) (_RKAS BIM + ARCHICAD Classification); Material: Klaas
AC_Pset_RenovationAndPhasing - Renovation Status: Existing

# IfcDiscreteAccessory: Distinct Panel 1080 x 2430 x 20, KLF-15 klaaspakett
In: 2 korrus
Type - ElementType: Element type KLF-15 klaaspakett
Classification: 1.8 IfcDiscreteAccessory (tarvik) (_RKAS BIM + ARCHICAD Classification); Material: Klaas
AC_Pset_RenovationAndPhasing - Renovation Status: New

# IfcDiscreteAccessory: Distinct Panel 1090 x 2510 x 20 (2)
In: 0 korrus
Type - ElementType: Element type KLF-03 klaaspakett
Classification: 1.8 IfcDiscreteAccessory (tarvik) (_RKAS BIM + ARCHICAD Classification); Material: Klaas
AC_Pset_RenovationAndPhasing - Renovation Status: New

# IfcDiscreteAccessory: Distinct Panel 1090 x 380 x 20 (2)
In: 0 korrus
Type - ElementType: Element type KS-13 klaaspakett
Classification: 1.8 IfcDiscreteAccessory (tarvik) (_RKAS BIM + ARCHICAD Classification); Material: Klaas
AC_Pset_RenovationAndPhasing - Renovation Status: New

# IfcDiscreteAccessory: Distinct Panel 1100 x 380 x 20 (4)
In: 0 korrus
Type - ElementType: Element type KS-14 klaaspakett
Classification: 1.8 IfcDiscreteAccessory (tarvik) (_RKAS BIM + ARCHICAD Classification); Material: Klaas
AC_Pset_RenovationAndPhasing - Renovation Status: New

# IfcDiscreteAccessory: Distinct Panel 1119 x 1820 x 20, KLF-14 klaaspakett
In: 1 korrus
Type - ElementType: Element type KLF-14 klaaspakett
Classification: 1.8 IfcDiscreteAccessory (tarvik) (_RKAS BIM + ARCHICAD Classification); Material: Klaas
AC_Pset_RenovationAndPhasing - Renovation Status: Existing

# IfcDiscreteAccessory: Distinct Panel 1120 x 1655 x 20, KS-19 klaaspakett
In: 1 korrus
Type - ElementType: Element type KS-19 klaaspakett
Classification: 1.8 IfcDiscreteAccessory (tarvik) (_RKAS BIM + ARCHICAD Classification); Material: Klaas
AC_Pset_RenovationAndPhasing - Renovation Status: New

# IfcDiscreteAccessory: Distinct Panel 1120 x 1880 x 20 (2)
In: 1 korrus
Type - ElementType: Element type KLF-11 klaaspakett
Classification: 1.8 IfcDiscreteAccessory (tarvik) (_RKAS BIM + ARCHICAD Classification); Material: Klaas
AC_Pset_RenovationAndPhasing - Renovation Status: New

# IfcDiscreteAccessory: Distinct Panel 1120 x 1880 x 20 (2)
In: 1 korrus
Type - ElementType: Element type KS-16 klaaspakett
Classification: 1.8 IfcDiscreteAccessory (tarvik) (_RKAS BIM + ARCHICAD Classification); Material: Klaas
AC_Pset_RenovationAndPhasing - Renovation Status: New

# IfcDiscreteAccessory: Distinct Panel 1125 x 1820 x 20, KLF-14 klaaspakett
In: 1 korrus
Type - ElementType: Element type KLF-14 klaaspakett
Classification: 1.8 IfcDiscreteAccessory (tarvik) (_RKAS BIM + ARCHICAD Classification); Material: Klaas
AC_Pset_RenovationAndPhasing - Renovation Status: Existing

# IfcDiscreteAccessory: Distinct Panel 1125 x 2565 x 20, KLF-14 klaaspakett
In: 1 korrus
Type - ElementType: Element type KLF-14 klaaspakett
Classification: 1.8 IfcDiscreteAccessory (tarvik) (_RKAS BIM + ARCHICAD Classification); Material: Klaas
AC_Pset_RenovationAndPhasing - Renovation Status: Existing

# IfcDiscreteAccessory: Distinct Panel 1130 x 380 x 20, KS-15 klaaspakett
In: 0 korrus
Type - ElementType: Element type KS-15 klaaspakett
Classification: 1.8 IfcDiscreteAccessory (tarvik) (_RKAS BIM + ARCHICAD Classification); Material: Klaas
AC_Pset_RenovationAndPhasing - Renovation Status: New

# IfcDiscreteAccessory: Distinct Panel 1135 x 2114 x 20, KLF-02 klaaspakett
In: 0 korrus
Type - ElementType: Element type KLF-02 klaaspakett
Classification: 1.8 IfcDiscreteAccessory (tarvik) (_RKAS BIM + ARCHICAD Classification); Material: Klaas
AC_Pset_RenovationAndPhasing - Renovation Status: New

# IfcDiscreteAccessory: Distinct Panel 1135 x 2407 x 20, KLF-02 klaaspakett
In: 0 korrus
Type - ElementType: Element type KLF-02 klaaspakett
Classification: 1.8 IfcDiscreteAccessory (tarvik) (_RKAS BIM + ARCHICAD Classification); Material: Klaas
AC_Pset_RenovationAndPhasing - Renovation Status: New

# IfcDiscreteAccessory: Distinct Panel 1150 x 2650 x 20 (2)
In: 1 korrus
Type - ElementType: Element type KLF-13 klaaspakett
Classification: 1.8 IfcDiscreteAccessory (tarvik) (_RKAS BIM + ARCHICAD Classification); Material: Klaas
AC_Pset_RenovationAndPhasing - Renovation Status: Existing

# IfcDiscreteAccessory: Distinct Panel 1150 x 2820 x 20 (2)
In: 1 korrus
Type - ElementType: Element type KLF-13 klaaspakett
Classification: 1.8 IfcDiscreteAccessory (tarvik) (_RKAS BIM + ARCHICAD Classification); Material: Klaas
AC_Pset_RenovationAndPhasing - Renovation Status: Existing

# IfcDiscreteAccessory: Distinct Panel 1155 x 2262 x 20, KLF-02 klaaspakett
In: 0 korrus
Type - ElementType: Element type KLF-02 klaaspakett
Classification: 1.8 IfcDiscreteAccessory (tarvik) (_RKAS BIM + ARCHICAD Classification); Material: Klaas
AC_Pset_RenovationAndPhasing - Renovation Status: New

# IfcDiscreteAccessory: Distinct Panel 1160 x 1536 x 20, KS-21 klaaspakett
In: 0 korrus
Type - ElementType: Element type KS-21 klaaspakett
Classification: 1.8 IfcDiscreteAccessory (tarvik) (_RKAS BIM + ARCHICAD Classification); Material: Klaas
AC_Pset_RenovationAndPhasing - Renovation Status: Existing

# IfcDiscreteAccessory: Distinct Panel 1160 x 2360 x 20 (2)
In: 2 korrus
Type - ElementType: Element type KS-01 klaaspakett
Classification: 1.8 IfcDiscreteAccessory (tarvik) (_RKAS BIM + ARCHICAD Classification); Material: Klaas
AC_Pset_RenovationAndPhasing - Renovation Status: New

# IfcDiscreteAccessory: Distinct Panel 1160 x 801 x 20, KS-21 klaaspakett
In: 0 korrus
Type - ElementType: Element type KS-21 klaaspakett
Classification: 1.8 IfcDiscreteAccessory (tarvik) (_RKAS BIM + ARCHICAD Classification); Material: Klaas
AC_Pset_RenovationAndPhasing - Renovation Status: Existing

# IfcDiscreteAccessory: Distinct Panel 1165 x 64 x 20, KS-21 klaaspakett
In: 0 korrus
Type - ElementType: Element type KS-21 klaaspakett
Classification: 1.8 IfcDiscreteAccessory (tarvik) (_RKAS BIM + ARCHICAD Classification); Material: Klaas
AC_Pset_RenovationAndPhasing - Renovation Status: New

# IfcDiscreteAccessory: Distinct Panel 1180 x 2360 x 20, KS-01 klaaspakett
In: 2 korrus
Type - ElementType: Element type KS-01 klaaspakett
Classification: 1.8 IfcDiscreteAccessory (tarvik) (_RKAS BIM + ARCHICAD Classification); Material: Klaas
AC_Pset_RenovationAndPhasing - Renovation Status: New

# IfcDiscreteAccessory: Distinct Panel 370 x 1645 x 20 (2)
In: 1 korrus
Type - ElementType: Element type KLF-16 klaaspakett
Classification: 1.8 IfcDiscreteAccessory (tarvik) (_RKAS BIM + ARCHICAD Classification); Material: Klaas
AC_Pset_RenovationAndPhasing - Renovation Status: Existing

# IfcDiscreteAccessory: Distinct Panel 370 x 2415 x 20 (2)
In: 1 korrus
Type - ElementType: Element type KLF-16 klaaspakett
Classification: 1.8 IfcDiscreteAccessory (tarvik) (_RKAS BIM + ARCHICAD Classification); Material: Klaas
AC_Pset_RenovationAndPhasing - Renovation Status: New

# IfcDiscreteAccessory: Distinct Panel 5 x 1645 x 20, KLF-16 klaaspakett
In: 1 korrus
Type - ElementType: Element type KLF-16 klaaspakett
Classification: 1.8 IfcDiscreteAccessory (tarvik) (_RKAS BIM + ARCHICAD Classification); Material: Klaas
AC_Pset_RenovationAndPhasing - Renovation Status: Existing

# IfcDiscreteAccessory: Distinct Panel 5 x 2270 x 20, KS-21 klaaspakett
In: 0 korrus
Type - ElementType: Element type KS-21 klaaspakett
Classification: 1.8 IfcDiscreteAccessory (tarvik) (_RKAS BIM + ARCHICAD Classification); Material: Klaas
AC_Pset_RenovationAndPhasing - Renovation Status: Existing

# IfcDiscreteAccessory: Distinct Panel 5 x 5 x 20, KLF-14 klaaspakett
In: 1 korrus
Type - ElementType: Element type KLF-14 klaaspakett
Classification: 1.8 IfcDiscreteAccessory (tarvik) (_RKAS BIM + ARCHICAD Classification); Material: Klaas
AC_Pset_RenovationAndPhasing - Renovation Status: Existing

# IfcDiscreteAccessory: Distinct Panel 5 x 5 x 20, KLF-16 klaaspakett
In: 1 korrus
Type - ElementType: Element type KLF-16 klaaspakett
Classification: 1.8 IfcDiscreteAccessory (tarvik) (_RKAS BIM + ARCHICAD Classification); Material: Klaas
AC_Pset_RenovationAndPhasing - Renovation Status: Existing

# IfcDiscreteAccessory: Distinct Panel 5 x 590 x 20, KLF-14 klaaspakett
In: 1 korrus
Type - ElementType: Element type KLF-14 klaaspakett
Classification: 1.8 IfcDiscreteAccessory (tarvik) (_RKAS BIM + ARCHICAD Classification); Material: Klaas
AC_Pset_RenovationAndPhasing - Renovation Status: Existing

# IfcDiscreteAccessory: Distinct Panel 50 x 1820 x 20, KLF-14 klaaspakett
In: 1 korrus
Type - ElementType: Element type KLF-14 klaaspakett
Classification: 1.8 IfcDiscreteAccessory (tarvik) (_RKAS BIM + ARCHICAD Classification); Material: Klaas
AC_Pset_RenovationAndPhasing - Renovation Status: Existing

# IfcDiscreteAccessory: Distinct Panel 660 x 2060 x 20, KS-17 klaaspakett
In: 1 korrus
Type - ElementType: Element type KS-17 klaaspakett
Classification: 1.8 IfcDiscreteAccessory (tarvik) (_RKAS BIM + ARCHICAD Classification); Material: Klaas
AC_Pset_RenovationAndPhasing - Renovation Status: Existing

# IfcDiscreteAccessory: Distinct Panel 680 x 2660 x 20, KLF-12 klaaspakett
In: 2 korrus
Type - ElementType: Element type KLF-12 klaaspakett
Classification: 1.8 IfcDiscreteAccessory (tarvik) (_RKAS BIM + ARCHICAD Classification); Material: Klaas
AC_Pset_RenovationAndPhasing - Renovation Status: New

# IfcDiscreteAccessory: Distinct Panel 720 x 2105 x 20 (2)
In: 1 korrus
Type - ElementType: Element type KLF-13 klaaspakett
Classification: 1.8 IfcDiscreteAccessory (tarvik) (_RKAS BIM + ARCHICAD Classification); Material: Klaas
AC_Pset_RenovationAndPhasing - Renovation Status: New

# IfcDiscreteAccessory: Distinct Panel 720 x 2650 x 20, KLF-13 klaaspakett
In: 1 korrus
Type - ElementType: Element type KLF-13 klaaspakett
Classification: 1.8 IfcDiscreteAccessory (tarvik) (_RKAS BIM + ARCHICAD Classification); Material: Klaas
AC_Pset_RenovationAndPhasing - Renovation Status: Existing

# IfcDiscreteAccessory: Distinct Panel 720 x 2820 x 20, KLF-13 klaaspakett
In: 1 korrus
Type - ElementType: Element type KLF-13 klaaspakett
Classification: 1.8 IfcDiscreteAccessory (tarvik) (_RKAS BIM + ARCHICAD Classification); Material: Klaas
AC_Pset_RenovationAndPhasing - Renovation Status: Existing

# IfcDiscreteAccessory: Distinct Panel 725 x 2510 x 20 (2)
In: 0 korrus
Type - ElementType: Element type KLF-06 klaaspakett
Classification: 1.8 IfcDiscreteAccessory (tarvik) (_RKAS BIM + ARCHICAD Classification); Material: Klaas
Name | Renovation Status
KLF-06 klaaspakett | New
KLF-06 klaaspakett | Existing

# IfcDiscreteAccessory: Distinct Panel 730 x 2360 x 20, KS-07 klaaspakett
In: 0 korrus
Type - ElementType: Element type KS-07 klaaspakett
Classification: 1.8 IfcDiscreteAccessory (tarvik) (_RKAS BIM + ARCHICAD Classification); Material: Klaas
AC_Pset_RenovationAndPhasing - Renovation Status: Existing

# IfcDiscreteAccessory: Distinct Panel 785 x 1235 x 20, KLF-14 klaaspakett
In: 1 korrus
Type - ElementType: Element type KLF-14 klaaspakett
Classification: 1.8 IfcDiscreteAccessory (tarvik) (_RKAS BIM + ARCHICAD Classification); Material: Klaas
AC_Pset_RenovationAndPhasing - Renovation Status: Existing

# IfcDiscreteAccessory: Distinct Panel 785 x 1415 x 20, KLF-14 klaaspakett
In: 1 korrus
Type - ElementType: Element type KLF-14 klaaspakett
Classification: 1.8 IfcDiscreteAccessory (tarvik) (_RKAS BIM + ARCHICAD Classification); Material: Klaas
AC_Pset_RenovationAndPhasing - Renovation Status: Existing

# IfcDiscreteAccessory: Distinct Panel 785 x 1645 x 20, KLF-14 klaaspakett
In: 1 korrus
Type - ElementType: Element type KLF-14 klaaspakett
Classification: 1.8 IfcDiscreteAccessory (tarvik) (_RKAS BIM + ARCHICAD Classification); Material: Klaas
AC_Pset_RenovationAndPhasing - Renovation Status: Existing

# IfcDiscreteAccessory: Distinct Panel 785 x 1820 x 20 (7)
In: 1 korrus
Type - ElementType: Element type KLF-14 klaaspakett
Classification: 1.8 IfcDiscreteAccessory (tarvik) (_RKAS BIM + ARCHICAD Classification); Material: Klaas
AC_Pset_RenovationAndPhasing - Renovation Status: Existing

# IfcDiscreteAccessory: Distinct Panel 785 x 2055 x 20, KLF-14 klaaspakett
In: 1 korrus
Type - ElementType: Element type KLF-14 klaaspakett
Classification: 1.8 IfcDiscreteAccessory (tarvik) (_RKAS BIM + ARCHICAD Classification); Material: Klaas
AC_Pset_RenovationAndPhasing - Renovation Status: Existing

# IfcDiscreteAccessory: Distinct Panel 785 x 2565 x 20, KLF-14 klaaspakett
In: 1 korrus
Type - ElementType: Element type KLF-14 klaaspakett
Classification: 1.8 IfcDiscreteAccessory (tarvik) (_RKAS BIM + ARCHICAD Classification); Material: Klaas
AC_Pset_RenovationAndPhasing - Renovation Status: Existing

# IfcDiscreteAccessory: Distinct Panel 785 x 415 x 20, KLF-14 klaaspakett
In: 1 korrus
Type - ElementType: Element type KLF-14 klaaspakett
Classification: 1.8 IfcDiscreteAccessory (tarvik) (_RKAS BIM + ARCHICAD Classification); Material: Klaas
AC_Pset_RenovationAndPhasing - Renovation Status: Existing

# IfcDiscreteAccessory: Distinct Panel 785 x 590 x 20, KLF-14 klaaspakett
In: 1 korrus
Type - ElementType: Element type KLF-14 klaaspakett
Classification: 1.8 IfcDiscreteAccessory (tarvik) (_RKAS BIM + ARCHICAD Classification); Material: Klaas
AC_Pset_RenovationAndPhasing - Renovation Status: Existing

# IfcDiscreteAccessory: Distinct Panel 785 x 825 x 20, KLF-14 klaaspakett
In: 1 korrus
Type - ElementType: Element type KLF-14 klaaspakett
Classification: 1.8 IfcDiscreteAccessory (tarvik) (_RKAS BIM + ARCHICAD Classification); Material: Klaas
AC_Pset_RenovationAndPhasing - Renovation Status: Existing

# IfcDiscreteAccessory: Distinct Panel 790 x 1005 x 20 (2)
In: 1 korrus
Type - ElementType: Element type KLF-14 klaaspakett
Classification: 1.8 IfcDiscreteAccessory (tarvik) (_RKAS BIM + ARCHICAD Classification); Material: Klaas
AC_Pset_RenovationAndPhasing - Renovation Status: Existing

# IfcDiscreteAccessory: Distinct Panel 790 x 1235 x 20, KLF-14 klaaspakett
In: 1 korrus
Type - ElementType: Element type KLF-14 klaaspakett
Classification: 1.8 IfcDiscreteAccessory (tarvik) (_RKAS BIM + ARCHICAD Classification); Material: Klaas
AC_Pset_RenovationAndPhasing - Renovation Status: Existing

# IfcDiscreteAccessory: Distinct Panel 790 x 1415 x 20, KLF-14 klaaspakett
In: 1 korrus
Type - ElementType: Element type KLF-14 klaaspakett
Classification: 1.8 IfcDiscreteAccessory (tarvik) (_RKAS BIM + ARCHICAD Classification); Material: Klaas
AC_Pset_RenovationAndPhasing - Renovation Status: Existing

# IfcDiscreteAccessory: Distinct Panel 790 x 1645 x 20, KLF-14 klaaspakett
In: 1 korrus
Type - ElementType: Element type KLF-14 klaaspakett
Classification: 1.8 IfcDiscreteAccessory (tarvik) (_RKAS BIM + ARCHICAD Classification); Material: Klaas
AC_Pset_RenovationAndPhasing - Renovation Status: Existing

# IfcDiscreteAccessory: Distinct Panel 790 x 1820 x 20 (6)
In: 1 korrus
Type - ElementType: Element type KLF-14 klaaspakett
Classification: 1.8 IfcDiscreteAccessory (tarvik) (_RKAS BIM + ARCHICAD Classification); Material: Klaas
AC_Pset_RenovationAndPhasing - Renovation Status: Existing

# IfcDiscreteAccessory: Distinct Panel 790 x 2055 x 20, KLF-14 klaaspakett
In: 1 korrus
Type - ElementType: Element type KLF-14 klaaspakett
Classification: 1.8 IfcDiscreteAccessory (tarvik) (_RKAS BIM + ARCHICAD Classification); Material: Klaas
AC_Pset_RenovationAndPhasing - Renovation Status: Existing

# IfcDiscreteAccessory: Distinct Panel 790 x 415 x 20, KLF-14 klaaspakett
In: 1 korrus
Type - ElementType: Element type KLF-14 klaaspakett
Classification: 1.8 IfcDiscreteAccessory (tarvik) (_RKAS BIM + ARCHICAD Classification); Material: Klaas
AC_Pset_RenovationAndPhasing - Renovation Status: Existing

# IfcDiscreteAccessory: Distinct Panel 790 x 5 x 20, KLF-14 klaaspakett
In: 1 korrus
Type - ElementType: Element type KLF-14 klaaspakett
Classification: 1.8 IfcDiscreteAccessory (tarvik) (_RKAS BIM + ARCHICAD Classification); Material: Klaas
AC_Pset_RenovationAndPhasing - Renovation Status: Existing

# IfcDiscreteAccessory: Distinct Panel 790 x 825 x 20, KLF-14 klaaspakett
In: 1 korrus
Type - ElementType: Element type KLF-14 klaaspakett
Classification: 1.8 IfcDiscreteAccessory (tarvik) (_RKAS BIM + ARCHICAD Classification); Material: Klaas
AC_Pset_RenovationAndPhasing - Renovation Status: Existing

# IfcDiscreteAccessory: Distinct Panel 80 x 2060 x 20 (4)
In: 1 korrus
Type - ElementType: Element type KS-17 klaaspakett
Classification: 1.8 IfcDiscreteAccessory (tarvik) (_RKAS BIM + ARCHICAD Classification); Material: Klaas
AC_Pset_RenovationAndPhasing - Renovation Status: New

# IfcDiscreteAccessory: Distinct Panel 80 x 2360 x 20 (4)
In: 0 korrus
Type - ElementType: Element type KS-07 klaaspakett
Material: Klaas
AC_Pset_RenovationAndPhasing - Renovation Status: Existing
Name | Classification
3 x KS-07 klaaspakett | 1.8 IfcDiscreteAccessory (tarvik) (_RKAS BIM + ARCHICAD Classification)
KS-07 klaaspakett | 0 TELLIJA KULUD (EHITUSKULUDE LIIGITAMINE EVS 885:2005); 1.8 IfcDiscreteAccessory (tarvik) (_RKAS BIM + ARCHICAD Classification)

# IfcDiscreteAccessory: Distinct Panel 800 x 2510 x 20, KLF-05 klaaspakett
In: 0 korrus
Type - ElementType: Element type KLF-05 klaaspakett
Classification: 1.8 IfcDiscreteAccessory (tarvik) (_RKAS BIM + ARCHICAD Classification); Material: Klaas
AC_Pset_RenovationAndPhasing - Renovation Status: New

# IfcDiscreteAccessory: Distinct Panel 820 x 2360 x 20, KS-02 klaaspakett
In: 2 korrus
Type - ElementType: Element type KS-02 klaaspakett
Classification: 1.8 IfcDiscreteAccessory (tarvik) (_RKAS BIM + ARCHICAD Classification); Material: Klaas
AC_Pset_RenovationAndPhasing - Renovation Status: New

# IfcDiscreteAccessory: Distinct Panel 825 x 2510 x 20, KLF-05 klaaspakett
In: 0 korrus
Type - ElementType: Element type KLF-05 klaaspakett
Classification: 1.8 IfcDiscreteAccessory (tarvik) (_RKAS BIM + ARCHICAD Classification); Material: Klaas
AC_Pset_RenovationAndPhasing - Renovation Status: New

# IfcDiscreteAccessory: Distinct Panel 843 x 1601 x 20, KLF-01 klaaspakett
In: 0 korrus
Type - ElementType: Element type KLF-01 klaaspakett
Classification: 1.8 IfcDiscreteAccessory (tarvik) (_RKAS BIM + ARCHICAD Classification); Material: Klaas
AC_Pset_RenovationAndPhasing - Renovation Status: New

# IfcDiscreteAccessory: Distinct Panel 843 x 1888 x 20, KLF-01 klaaspakett
In: 0 korrus
Type - ElementType: Element type KLF-01 klaaspakett
Classification: 1.8 IfcDiscreteAccessory (tarvik) (_RKAS BIM + ARCHICAD Classification); Material: Klaas
AC_Pset_RenovationAndPhasing - Renovation Status: New

# IfcDiscreteAccessory: Distinct Panel 845 x 1832 x 20, KLF-07 klaaspakett
In: 0 korrus
Type - ElementType: Element type KLF-07 klaaspakett
Classification: 1.8 IfcDiscreteAccessory (tarvik) (_RKAS BIM + ARCHICAD Classification); Material: Klaas
AC_Pset_RenovationAndPhasing - Renovation Status: New

# IfcDiscreteAccessory: Distinct Panel 845 x 2079 x 20, KLF-07 klaaspakett
In: 0 korrus
Type - ElementType: Element type KLF-07 klaaspakett
Classification: 1.8 IfcDiscreteAccessory (tarvik) (_RKAS BIM + ARCHICAD Classification); Material: Klaas
AC_Pset_RenovationAndPhasing - Renovation Status: New

# IfcDiscreteAccessory: Distinct Panel 845 x 2660 x 20 (3)
In: 2 korrus
Type - ElementType: Element type KLF-09 klaaspakett
Classification: 1.8 IfcDiscreteAccessory (tarvik) (_RKAS BIM + ARCHICAD Classification); Material: Klaas
AC_Pset_RenovationAndPhasing - Renovation Status: New

# IfcDiscreteAccessory: Distinct Panel 850 x 1832 x 20, KLF-07 klaaspakett
In: 0 korrus
Type - ElementType: Element type KLF-07 klaaspakett
Classification: 1.8 IfcDiscreteAccessory (tarvik) (_RKAS BIM + ARCHICAD Classification); Material: Klaas
AC_Pset_RenovationAndPhasing - Renovation Status: New

# IfcDiscreteAccessory: Distinct Panel 855 x 2360 x 20, KS-04 klaaspakett
In: 1,5 korrus
Type - ElementType: Element type KS-04 klaaspakett
Classification: 1.8 IfcDiscreteAccessory (tarvik) (_RKAS BIM + ARCHICAD Classification); Material: Klaas
AC_Pset_RenovationAndPhasing - Renovation Status: New

# IfcDiscreteAccessory: Distinct Panel 855 x 2460 x 20 (2)
In: 1,5 korrus
Type - ElementType: Element type KLF-08 klaaspakett
Classification: 1.8 IfcDiscreteAccessory (tarvik) (_RKAS BIM + ARCHICAD Classification); Material: Klaas
AC_Pset_RenovationAndPhasing - Renovation Status: New

# IfcDiscreteAccessory: Distinct Panel 860 x 1439 x 20, KS-09 klaaspakett
In: 0 korrus
Type - ElementType: Element type KS-09 klaaspakett
Classification: 1.8 IfcDiscreteAccessory (tarvik) (_RKAS BIM + ARCHICAD Classification); Material: Klaas
AC_Pset_RenovationAndPhasing - Renovation Status: Existing

# IfcDiscreteAccessory: Distinct Panel 860 x 2360 x 20, KS-07 klaaspakett
In: 0 korrus
Type - ElementType: Element type KS-07 klaaspakett
Classification: 1.8 IfcDiscreteAccessory (tarvik) (_RKAS BIM + ARCHICAD Classification); Material: Klaas
AC_Pset_RenovationAndPhasing - Renovation Status: Existing

# IfcDiscreteAccessory: Distinct Panel 860 x 666 x 20, KS-11 klaaspakett
In: 0 korrus
Type - ElementType: Element type KS-11 klaaspakett
Classification: 1.8 IfcDiscreteAccessory (tarvik) (_RKAS BIM + ARCHICAD Classification); Material: Klaas
AC_Pset_RenovationAndPhasing - Renovation Status: Existing

# IfcDiscreteAccessory: Distinct Panel 860 x 811 x 20, KS-08 klaaspakett
In: 0 korrus
Type - ElementType: Element type KS-08 klaaspakett
Classification: 1.8 IfcDiscreteAccessory (tarvik) (_RKAS BIM + ARCHICAD Classification); Material: Klaas
AC_Pset_RenovationAndPhasing - Renovation Status: Existing

# IfcDiscreteAccessory: Distinct Panel 863 x 1698 x 20, KLF-01 klaaspakett
In: 0 korrus
Type - ElementType: Element type KLF-01 klaaspakett
Classification: 1.8 IfcDiscreteAccessory (tarvik) (_RKAS BIM + ARCHICAD Classification); Material: Klaas
AC_Pset_RenovationAndPhasing - Renovation Status: New

# IfcDiscreteAccessory: Distinct Panel 863 x 1794 x 20, KLF-01 klaaspakett
In: 0 korrus
Type - ElementType: Element type KLF-01 klaaspakett
Classification: 1.8 IfcDiscreteAccessory (tarvik) (_RKAS BIM + ARCHICAD Classification); Material: Klaas
AC_Pset_RenovationAndPhasing - Renovation Status: New

# IfcDiscreteAccessory: Distinct Panel 905 x 2360 x 20, KS-05 klaaspakett
In: 1,5 korrus
Type - ElementType: Element type KS-05 klaaspakett
Classification: 1.8 IfcDiscreteAccessory (tarvik) (_RKAS BIM + ARCHICAD Classification); Material: Klaas
AC_Pset_RenovationAndPhasing - Renovation Status: New

# IfcDiscreteAccessory: Distinct Panel 910 x 1645 x 20, KLF-16 klaaspakett
In: 1 korrus
Type - ElementType: Element type KLF-16 klaaspakett
Classification: 1.8 IfcDiscreteAccessory (tarvik) (_RKAS BIM + ARCHICAD Classification); Material: Klaas
AC_Pset_RenovationAndPhasing - Renovation Status: Existing

# IfcDiscreteAccessory: Distinct Panel 910 x 1855 x 20, KLF-16 klaaspakett
In: 1 korrus
Type - ElementType: Element type KLF-16 klaaspakett
Classification: 1.8 IfcDiscreteAccessory (tarvik) (_RKAS BIM + ARCHICAD Classification); Material: Klaas
AC_Pset_RenovationAndPhasing - Renovation Status: New

# IfcDiscreteAccessory: Distinct Panel 915 x 1390 x 20 (2)
In: 1 korrus
Type - ElementType: Element type KLF-16 klaaspakett
Classification: 1.8 IfcDiscreteAccessory (tarvik) (_RKAS BIM + ARCHICAD Classification); Material: Klaas
AC_Pset_RenovationAndPhasing - Renovation Status: New

# IfcDiscreteAccessory: Distinct Panel 915 x 1645 x 20 (8)
In: 1 korrus
Type - ElementType: Element type KLF-16 klaaspakett
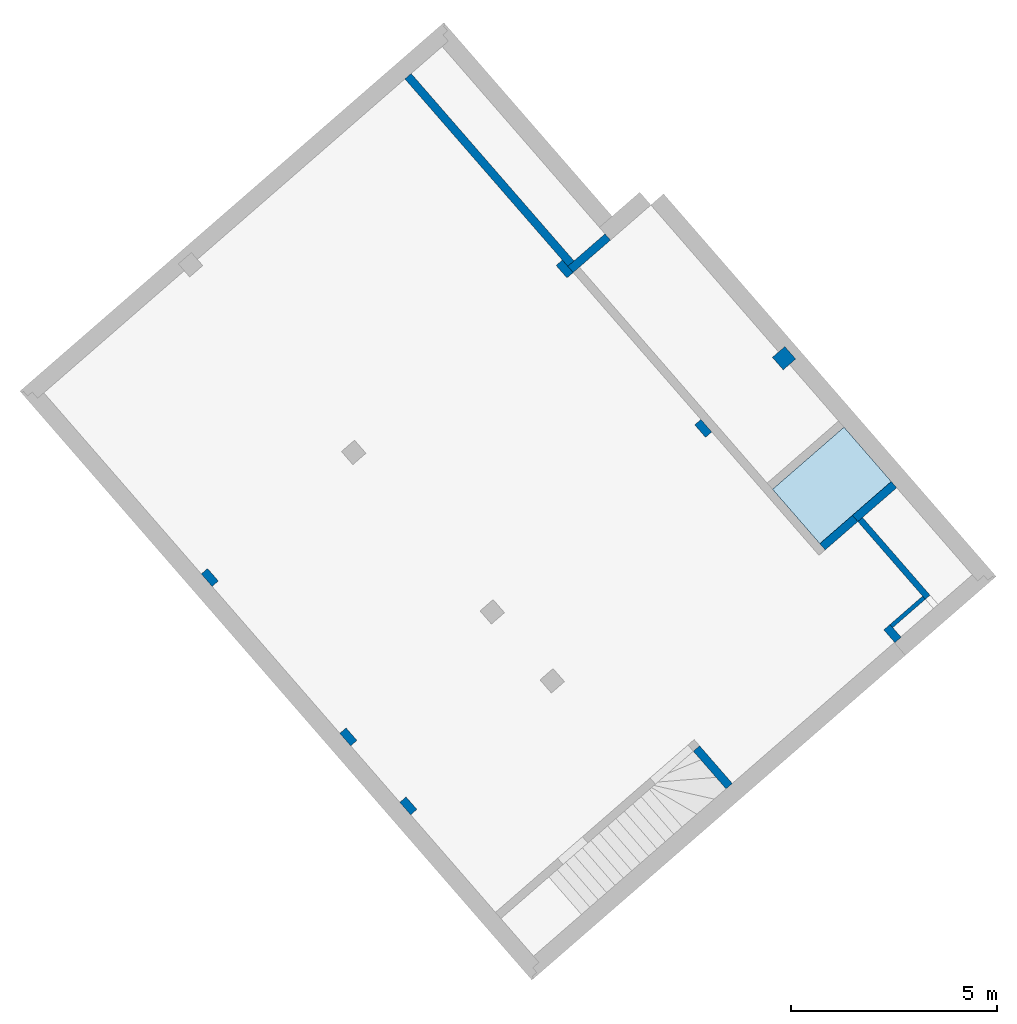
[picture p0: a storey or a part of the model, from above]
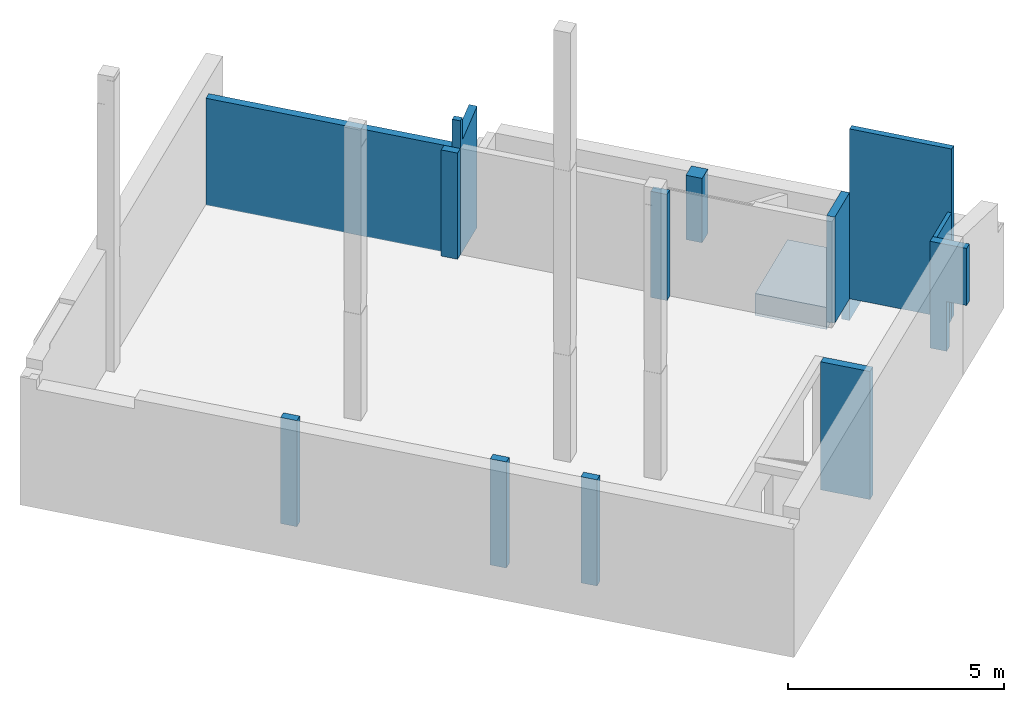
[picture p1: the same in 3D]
Properties of the parts of a building model (IFC2X3), part 4 of 13

# IfcDiscreteAccessory: Distinct Panel 915 x 1645 x 20 (8)
Classification: 1.8 IfcDiscreteAccessory (tarvik) (_RKAS BIM + ARCHICAD Classification); Material: Klaas
AC_Pset_RenovationAndPhasing - Renovation Status: Existing

# IfcDiscreteAccessory: Distinct Panel 915 x 1855 x 20, KLF-16 klaaspakett
In: 1 korrus
Type - ElementType: Element type KLF-16 klaaspakett
Classification: 1.8 IfcDiscreteAccessory (tarvik) (_RKAS BIM + ARCHICAD Classification); Material: Klaas
AC_Pset_RenovationAndPhasing - Renovation Status: New

# IfcDiscreteAccessory: Distinct Panel 915 x 2415 x 20, KLF-16 klaaspakett
In: 1 korrus
Type - ElementType: Element type KLF-16 klaaspakett
Classification: 1.8 IfcDiscreteAccessory (tarvik) (_RKAS BIM + ARCHICAD Classification); Material: Klaas
AC_Pset_RenovationAndPhasing - Renovation Status: New

# IfcDiscreteAccessory: Distinct Panel 915 x 465 x 20 (2)
In: 1 korrus
Type - ElementType: Element type KLF-16 klaaspakett
Classification: 1.8 IfcDiscreteAccessory (tarvik) (_RKAS BIM + ARCHICAD Classification); Material: Klaas
Name | Renovation Status
KLF-16 klaaspakett | Existing
KLF-16 klaaspakett | New

# IfcDiscreteAccessory: Distinct Panel 915 x 930 x 20 (2)
In: 1 korrus
Type - ElementType: Element type KLF-16 klaaspakett
Classification: 1.8 IfcDiscreteAccessory (tarvik) (_RKAS BIM + ARCHICAD Classification); Material: Klaas
AC_Pset_RenovationAndPhasing - Renovation Status: New

# IfcDiscreteAccessory: Distinct Panel 970 x 2460 x 20 (5)
In: 1,5 korrus
Type - ElementType: Element type KS-20 klaaspakett
Classification: 1.8 IfcDiscreteAccessory (tarvik) (_RKAS BIM + ARCHICAD Classification); Material: Klaas
Name | Renovation Status
4 x KS-20 klaaspakett | New
KS-20 klaaspakett | Existing

# IfcDiscreteAccessory: Distinct Panel 970 x 2510 x 20, KLF-04 klaaspakett
In: 0 korrus
Type - ElementType: Element type KLF-04 klaaspakett
Classification: 1.8 IfcDiscreteAccessory (tarvik) (_RKAS BIM + ARCHICAD Classification); Material: Klaas
AC_Pset_RenovationAndPhasing - Renovation Status: New

# IfcDiscreteAccessory: Distinct Panel 975 x 2660 x 20 (2)
In: 2 korrus
Type - ElementType: Element type KLF-10 klaaspakett
Classification: 1.8 IfcDiscreteAccessory (tarvik) (_RKAS BIM + ARCHICAD Classification); Material: Klaas
AC_Pset_RenovationAndPhasing - Renovation Status: New

# IfcDiscreteAccessory: Distinct Panel 990 x 1645 x 20 (4)
In: 1 korrus
Type - ElementType: Element type KLF-16 klaaspakett
Classification: 1.8 IfcDiscreteAccessory (tarvik) (_RKAS BIM + ARCHICAD Classification); Material: Klaas
AC_Pset_RenovationAndPhasing - Renovation Status: Existing

# IfcDiscreteAccessory: Distinct Panel 990 x 2415 x 20 (4)
In: 1 korrus
Type - ElementType: Element type KLF-16 klaaspakett
Classification: 1.8 IfcDiscreteAccessory (tarvik) (_RKAS BIM + ARCHICAD Classification); Material: Klaas
AC_Pset_RenovationAndPhasing - Renovation Status: New

# IfcDiscreteAccessory: Distinct Panel 990 x 2510 x 20 (3)
In: 0 korrus
Type - ElementType: Element type KLF-04 klaaspakett
Classification: 1.8 IfcDiscreteAccessory (tarvik) (_RKAS BIM + ARCHICAD Classification); Material: Klaas
AC_Pset_RenovationAndPhasing - Renovation Status: New

# IfcDiscreteAccessory: Distinct Panel 995 x 2510 x 20, KLF-04 klaaspakett
In: 0 korrus
Type - ElementType: Element type KLF-04 klaaspakett
Classification: 1.8 IfcDiscreteAccessory (tarvik) (_RKAS BIM + ARCHICAD Classification); Material: Klaas
AC_Pset_RenovationAndPhasing - Renovation Status: New

# IfcDiscreteAccessory: GENEERILINE - VÄLINE VOODER (420)
In: 1 korrus
Type - ElementType: Element type Päikesevarjestuspost
Classification: 1.8 IfcDiscreteAccessory (tarvik) (_RKAS BIM + ARCHICAD Classification); Material: GENEERILINE - VÄLINE VOODER
AC_Pset_RenovationAndPhasing - Renovation Status: New

# IfcDiscreteAccessory: GENERIC - STRUCTURAL 145 x 28 (60)
In: 2 korrus
Type - ElementType: Element type lehise laudis
Classification: 1.8 IfcDiscreteAccessory (tarvik) (_RKAS BIM + ARCHICAD Classification); Material: GENERIC - STRUCTURAL
AC_Pset_RenovationAndPhasing - Renovation Status: Existing

# IfcDiscreteAccessory: GENERIC - STRUCTURAL 5 (39)
In: 2 korrus
Type - ElementType: Element type Terasleht
Classification: 1.8 IfcDiscreteAccessory (tarvik) (_RKAS BIM + ARCHICAD Classification)
AC_Pset_RenovationAndPhasing - Renovation Status: Existing
Name | Material
38 x Terasleht | GENERIC - STRUCTURAL
Terasleht | GENERIC - STRUCTURAL (2)

# IfcDiscreteAccessory: GENERIC - STRUCTURAL 70 x 28 (6)
In: 2 korrus
Type - ElementType: Element type lehise laudis
Classification: 1.8 IfcDiscreteAccessory (tarvik) (_RKAS BIM + ARCHICAD Classification); Material: GENERIC - STRUCTURAL
AC_Pset_RenovationAndPhasing - Renovation Status: Existing

# IfcDiscreteAccessory: Lipp teras 50 x 50 (20)
In: 2 korrus
Type - ElementType: Element type Terasest lipp
Classification: 1.8 IfcDiscreteAccessory (tarvik) (_RKAS BIM + ARCHICAD Classification)
AC_Pset_RenovationAndPhasing - Renovation Status: New
Name | Material
10 x Terasest lipp | Teras (musta värvi)
10 x Terasest lipp | Teras (musta värvi) (5)

# IfcDiscreteAccessory: MISSING 1 (2)
In: 2 korrus
Type - ElementType: Element type Valtsplekk
Classification: 1.8 IfcDiscreteAccessory (tarvik) (_RKAS BIM + ARCHICAD Classification)
AC_Pset_RenovationAndPhasing - Renovation Status: New

# IfcDiscreteAccessory: Main Panel 1080 x 1655 x 20 (2)
In: 1 korrus
Type - ElementType: Element type KS-18 klaaspakett
Classification: 1.8 IfcDiscreteAccessory (tarvik) (_RKAS BIM + ARCHICAD Classification); Material: Klaas
AC_Pset_RenovationAndPhasing - Renovation Status: New

# IfcDiscreteAccessory: Main Panel 1120 x 1655 x 20, KS-19 klaaspakett
In: 1 korrus
Type - ElementType: Element type KS-19 klaaspakett
Classification: 1.8 IfcDiscreteAccessory (tarvik) (_RKAS BIM + ARCHICAD Classification); Material: Klaas
AC_Pset_RenovationAndPhasing - Renovation Status: New

# IfcDiscreteAccessory: Main Panel 1120 x 1880 x 20 (2)
In: 1 korrus
Type - ElementType: Element type KLF-11 klaaspakett
Classification: 1.8 IfcDiscreteAccessory (tarvik) (_RKAS BIM + ARCHICAD Classification); Material: Klaas
AC_Pset_RenovationAndPhasing - Renovation Status: New

# IfcDiscreteAccessory: Main Panel 1120 x 1880 x 20 (2)
In: 1 korrus
Type - ElementType: Element type KS-16 klaaspakett
Classification: 1.8 IfcDiscreteAccessory (tarvik) (_RKAS BIM + ARCHICAD Classification); Material: Klaas
AC_Pset_RenovationAndPhasing - Renovation Status: New

# IfcDiscreteAccessory: Puit - Konstruktsioon (787)
In: 2 korrus
Type - ElementType: Element type Puitlaudis
Classification: 1.8 IfcDiscreteAccessory (tarvik) (_RKAS BIM + ARCHICAD Classification); Material: Puit - Konstruktsioon
AC_Pset_RenovationAndPhasing - Renovation Status: New

# IfcDiscreteAccessory: Puit - Konstruktsioon 21 x 95 (227)
In: 1 korrus
Type - ElementType: Element type Puitroovitus
Classification: 1.8 IfcDiscreteAccessory (tarvik) (_RKAS BIM + ARCHICAD Classification)
AC_Pset_RenovationAndPhasing - Renovation Status: New
Name | Material
223 x Puitroovitus | Puit - Konstruktsioon
4 x Puitroovitus | Puit - Konstruktsioon (2)

# IfcDiscreteAccessory: Puit - Konstruktsioon 6260 x 21 (23)
In: 2 korrus
Type - ElementType: Element type Aluslaudis
Classification: 1.8 IfcDiscreteAccessory (tarvik) (_RKAS BIM + ARCHICAD Classification); Material: Puit - Konstruktsioon
AC_Pset_RenovationAndPhasing - Renovation Status: New

# IfcDiscreteAccessory: Puit - Konstruktsioon 6480 x 21 (23)
In: 2 korrus
Type - ElementType: Element type Aluslaudis
Classification: 1.8 IfcDiscreteAccessory (tarvik) (_RKAS BIM + ARCHICAD Classification); Material: Puit - Konstruktsioon
AC_Pset_RenovationAndPhasing - Renovation Status: New

# IfcDiscreteAccessory: Site specified 105 x 22 (2)
In: 1 korrus
Type - ElementType: Element type Puitfassaadi laudis
Classification: 1.8 IfcDiscreteAccessory (tarvik) (_RKAS BIM + ARCHICAD Classification); Material: Site specified
AC_Pset_RenovationAndPhasing - Renovation Status: New

# IfcDiscreteAccessory: Site specified 130 x 22 (2)
In: 1 korrus
Type - ElementType: Element type Puitfassaadi laudis
Classification: 1.8 IfcDiscreteAccessory (tarvik) (_RKAS BIM + ARCHICAD Classification); Material: Site specified
AC_Pset_RenovationAndPhasing - Renovation Status: New

# IfcDiscreteAccessory: Site specified 150 x 22 (100)
In: 1 korrus
Type - ElementType: Element type Puitfassaadi laudis
Classification: 1.8 IfcDiscreteAccessory (tarvik) (_RKAS BIM + ARCHICAD Classification)
AC_Pset_RenovationAndPhasing - Renovation Status: New
Name | Material
70 x Puitfassaadi laudis | Site specified
30 x Puitfassaadi laudis | Site specified (2)

# IfcDiscreteAccessory: Site specified 60 x 22 (2)
In: 1 korrus
Type - ElementType: Element type Puitfassaadi laudis
Classification: 1.8 IfcDiscreteAccessory (tarvik) (_RKAS BIM + ARCHICAD Classification); Material: Site specified
AC_Pset_RenovationAndPhasing - Renovation Status: New

# IfcDiscreteAccessory: Site specified 80 x 22 (4)
In: 1 korrus
Type - ElementType: Element type Puitfassaadi laudis
Classification: 1.8 IfcDiscreteAccessory (tarvik) (_RKAS BIM + ARCHICAD Classification); Material: Site specified
AC_Pset_RenovationAndPhasing - Renovation Status: New

# IfcDiscreteAccessory: Site specified 90 x 22 (5)
In: 1 korrus
Type - ElementType: Element type Puitfassaadi laudis
Classification: 1.8 IfcDiscreteAccessory (tarvik) (_RKAS BIM + ARCHICAD Classification); Material: Site specified
AC_Pset_RenovationAndPhasing - Renovation Status: New

# IfcDiscreteAccessory: Teras (musta värvi) 3 x 2120 (10)
In: 2 korrus
Type - ElementType: Element type Terasest lipp
Classification: 1.8 IfcDiscreteAccessory (tarvik) (_RKAS BIM + ARCHICAD Classification); Material: Teras (musta värvi)
AC_Pset_RenovationAndPhasing - Renovation Status: New

# IfcDiscreteAccessory: Teras (musta värvi) 30 x 30 (2)
In: 1,5 korrus
Type - ElementType: Element type Piirdepulk
Classification: 1.8 IfcDiscreteAccessory (tarvik) (_RKAS BIM + ARCHICAD Classification); Material: Teras (musta värvi)
AC_Pset_RenovationAndPhasing - Renovation Status: New

# IfcDiscreteAccessory: Teras (musta värvi) 395 (3)
In: 1 korrus
Type - ElementType: Element type Kasvumuld
Classification: 1.8 IfcDiscreteAccessory (tarvik) (_RKAS BIM + ARCHICAD Classification); Material: Teras (musta värvi)
AC_Pset_RenovationAndPhasing - Renovation Status: New

# IfcDiscreteAccessory: Teras (musta värvi) 42 x 42 (8)
In: 1 korrus
Type - ElementType: Element type Metall-raam
Classification: 1.8 IfcDiscreteAccessory (tarvik) (_RKAS BIM + ARCHICAD Classification); Material: Teras (musta värvi) (2)
AC_Pset_RenovationAndPhasing - Renovation Status: New

# IfcDiscreteAccessory: Teras (musta värvi) 60 (44)
In: 1 korrus
Type - ElementType: Element type Rattahoidja
Classification: 1.8 IfcDiscreteAccessory (tarvik) (_RKAS BIM + ARCHICAD Classification); Material: Teras (musta värvi)
AC_Pset_RenovationAndPhasing - Renovation Status: New

# IfcDiscreteAccessory: Text 3D 22, Nimesilt N-01 (vt. 2D jooniseid)
In: Katus
Type - ElementType: Element type Nimesilt N-01 (vt. 2D jooniseid)
Classification: 1.8 IfcDiscreteAccessory (tarvik) (_RKAS BIM + ARCHICAD Classification)
AC_Pset_RenovationAndPhasing - Renovation Status: New

# IfcDoor: 1040 x 2380 x 20, Klaas-seina integreeritud siseuks * CW Door 22
In: 2 korrus
Type - ParameterTakesPrecedence: no; Sizeable: no
Classification: 0 TELLIJA KULUD (EHITUSKULUDE LIIGITAMINE EVS 885:2005); 1.9 IfcDoor (uks) (_RKAS BIM + ARCHICAD Classification); Material: Aluminium MUST (23), Klaas
Avatäited - 01 Nimetus: Klaas-seina integreeritud siseuks; 02 Materjal: Klaas; Alumiinium; 06 Soojusläbivus: -; 07 Helipidavus: 30dB; 08 Veepidavus: -; 09 Õhuläbilaskvus: -; 10 Tulekindlus: nõudeid ei esitata; 11 Vastupanu tulekoormusele: -; 12 Klaaspakett: -; 13 Klaasingu erisused: karastatud ja lamineeritud kirgas klaas; 14 Päikesekiirgus tegur (g-väärtus): -; 15 Avanemine: Avanemine: "R{Abbreviation of Right}" (L - vasak; R - parem); 16 Liigendatus: -; 17 Sulused, lukustus: Link AssaAbloy Aperio (tagasi keeratud lingi otsaga). Lukustus vastavalt lukustusprojektile. Sulgur puudub. Hinged tootekesksed, viimistlus on sama, mis on ukselehel. Uks varustada piirajaga.; 18 Viimistlus: Tehaseliselt värvitud tumehalliks RAL7016 (Anthrazitgrau). Lävepakk - harjatud roostevaba terasleht t=1mm, kõrgus max 20mm.; 19 Mudel või toote tunnus: Fuego Light (või samaväärne analoog); 20 Tootja: Forster (või samaväärne analoog); 21 Tooteinfo: Undefined; 22 Kasutus- ja hooldusjuhend: Undefined; 23 viide sõlmele: Undefined
Pset_ManufacturerOccurrence - SerialNumber: Off
AC_Pset_RenovationAndPhasing - Renovation Status: New

# IfcDoor: 1060 x 2450 x 20, Klaasfassaadi integreeritud välisuks * CW Double Door 22
In: 2 korrus
Type - ParameterTakesPrecedence: no; Sizeable: no
Classification: 1.9 IfcDoor (uks) (_RKAS BIM + ARCHICAD Classification); Material: Aluminium MUST (31), Klaas (2)
Avatäited - 01 Nimetus: Klaasfassaadi integreeritud välisuks; 02 Materjal: Klaas; Metall; 06 Soojusläbivus: 1,1 W/m2K; 07 Helipidavus: 35dB; 08 Veepidavus: A7; 09 Õhuläbilaskvus: klass 4; 10 Tulekindlus: nõudeid ei esitata; 11 Vastupanu tulekoormusele: C3; 12 Klaaspakett: kolmekordne klaaspakett; 13 Klaasingu erisused: Kirgas klaas, sisemine klaas karastatud, välimine klaas lamineeritud, klaaside vahelised liistud musta värvi; 14 Päikesekiirgus tegur (g-väärtus): 0,38; 15 Avanemine: Avanemine: "" (L - vasak; R - parem); 16 Liigendatus: Uks koosneb kahest ukselehest; 17 Sulused, lukustus: Link AssaAbloy Inoxi 3-19 tagasi pööratud otsaga evak.link (harjatud roostevaba viimistlusega). Lukustus vastavalt lukustusprojektile. Uksed varustatud evakuatsioonipoomidega (vt. lukustusprojekti). Must liugsulgur Abloy DC700 (või samaväärne analoog), sulgur paigaldada sissepoole. Uks varustada taktiseadmega. Hinged tootekesksed, viimistlus on sama, mis on ukselehel. Uks varustada piirajaga (sulguri sisene).; 18 Viimistlus: Tehaseliselt värvitud tumehalliks RAL7016 (Anthrazitgrau). Lävepakk - harjatud roostevaba terasleht t=1mm, kõrgus max 20mm.; 19 Mudel või toote tunnus: AD UP 75 (või samaväärne analoog); 20 Tootja: Schüco (või samaväärne analoog); 21 Tooteinfo: Undefined; 22 Kasutus- ja hooldusjuhend: Undefined; 23 viide sõlmele: Undefined
Pset_ManufacturerOccurrence - SerialNumber: Off
AC_Pset_RenovationAndPhasing - Renovation Status: New

# IfcDoor: 1075 x 2435 x 20, Klaasfassaadi integreeritud välisuks * CW Double Door 22
In: 1 korrus
Type - ParameterTakesPrecedence: no; Sizeable: no
Classification: 0 TELLIJA KULUD (EHITUSKULUDE LIIGITAMINE EVS 885:2005); 1.9 IfcDoor (uks) (_RKAS BIM + ARCHICAD Classification); Material: Aluminium MUST (31), Klaas (2)
Avatäited - 01 Nimetus: Klaasfassaadi integreeritud välisuks; 02 Materjal: Klaas; Metall; 06 Soojusläbivus: 1,1 W/m2K; 07 Helipidavus: 30dB; 08 Veepidavus: 7A; 09 Õhuläbilaskvus: klass 4; 10 Tulekindlus: nõudeid ei esitata; 11 Vastupanu tulekoormusele: C3; 12 Klaaspakett: kolmekordne klaaspakett; 13 Klaasingu erisused: kirgas klaas, sisemine klaas karastatud, välimine klaas lamineeritud, klaaside vahelised liistud musta värvi; 14 Päikesekiirgus tegur (g-väärtus): 0,38; 15 Avanemine: Avanemine: "" (L - vasak; R - parem); 16 Liigendatus: uks koosneb kahest ukselehest; 17 Sulused, lukustus: aktiivsel ukselehel kahepoolsed käepidemed Dormakaba TG9335 (käepide on sama kõrge kui on ukse klaas). Lukustus vastavalt lukustusprojektile. Ukselehed varustatud mustade liugsulguritega Abloy DC700 (või samaväärne analoog), sulgurid paigaldada tuulekoja poole. Hinged tootekesksed, viimistlus sama mis on ukselengil. Uks varustada taktiseadmega. Uks varustada piirajaga (sulguri sisene).; 18 Viimistlus: tehaseliselt värvitud tumehalliks RAL7016 (Anthrazitgrau). Lävepakk - harjatud roostevaba terasleht t=1mm, kõrgus max 20mm.; 19 Mudel või toote tunnus: AD UP 75 (või samaväärne analoog); 20 Tootja: Schüco (või samaväärne analoog); 21 Tooteinfo: Undefined; 22 Kasutus- ja hooldusjuhend: Undefined; 23 viide sõlmele: Undefined
Pset_ManufacturerOccurrence - SerialNumber: Off
AC_Pset_RenovationAndPhasing - Renovation Status: New

# IfcDoor: 1080 x 2425 x 20 (2)
In: 1 korrus
Type - ParameterTakesPrecedence: no; Sizeable: no
Avatäited - 01 Nimetus: Klaas-seina integreeritud siseuks; 02 Materjal: Klaas; Metall; 06 Soojusläbivus: -; 07 Helipidavus: -; 08 Veepidavus: -; 09 Õhuläbilaskvus: -; 10 Tulekindlus: nõudeid ei esitata; 11 Vastupanu tulekoormusele: -; 13 Klaasingu erisused: Kirgas klaas, sisemine klaas karastatud, välimine klaas lamineeritud, klaaside vahelised liistud musta värvi; 14 Päikesekiirgus tegur (g-väärtus): -; 15 Avanemine: Avanemine: "" (L - vasak; R - parem); 16 Liigendatus: Uks koosneb kahest ukselehest; 19 Mudel või toote tunnus: AD UP 75 (või samaväärne analoog); 20 Tootja: Schüco (või samaväärne analoog); 21 Tooteinfo: Undefined; 22 Kasutus- ja hooldusjuhend: Undefined; 23 viide sõlmele: Undefined
Pset_ManufacturerOccurrence - SerialNumber: Off
AC_Pset_RenovationAndPhasing - Renovation Status: New
Name | Classification | 12 Klaaspakett | 17 Sulused, lukustus | 18 Viimistlus
Klaas-seina integreeritud siseuks * CW Double Door 22 | 1.9 IfcDoor (uks) (_RKAS BIM + ARCHICAD Classification) | kahekordne klaaspakett | ukselehtedel kahepoolsed käepidemed Dormakaba TG9335 (käepide on sama kõrge kui on ukse klaas). Lukustus vastavalt lukustusprojektile. Ukselehed varustatud mustade liugsulguritega Abloy DC700 (või samaväärne analoog), sulgurid paigaldada tuulekoja poole. Hinged tootekesksed, viimistlus sama mis on ukselengil. Uks varustada taktiseadmega. Uks varustada piirajaga (sulguri sisene). | Tehaseliselt värvitud tumehalliks RAL7016 (Anthrazitgrau). Lävepakk - harjatud roostevaba terasleht t=1mm, kõrgus max 20mm | Material: Aluminium MUST (17), Klaas (2), Teras - Roostevaba (14)
Klaas-seina integreeritud siseuks * CW Double Door 22 | 0 TELLIJA KULUD (EHITUSKULUDE LIIGITAMINE EVS 885:2005); 1.9 IfcDoor (uks) (_RKAS BIM + ARCHICAD Classification) | Kahekordne klaaspakett | ukselehtedel kahepoolsed käepidemed Dormakaba TG9335 (käepide on sama kõrge kui on ukse klaas). Lukustus vastavalt lukustusprojektile. Ukselehed varustatud mustade liugsulguritega Abloy DC700 (või samaväärne analoog), sulgurid paigaldada tuulekoja poole. Hinged tootekesksed, viimistlus sama mis on ukselengil. Uks varustada taktiseadmega. Uks varustada piirajaga (sulguri sisene). Uks varustada forosilmaga. | Tehaseliselt värvitud tumehalliks RAL7016 (Anthrazitgrau). Lävepakk - harjatud roostevaba terasleht t=1mm, kõrgus max 20mm.

# IfcDoor: 1080 x 2435 x 20, Klaasfassaadi integreeritud välisuks * CW Double Door 22
In: 1 korrus
Type - ParameterTakesPrecedence: no; Sizeable: no
Classification: 1.9 IfcDoor (uks) (_RKAS BIM + ARCHICAD Classification); Material: Aluminium MUST (31), Klaas (2)
Avatäited - 01 Nimetus: Klaasfassaadi integreeritud välisuks; 02 Materjal: Klaas; Metall; 06 Soojusläbivus: 1,1 W/m2K; 07 Helipidavus: 30dB; 08 Veepidavus: 7A; 09 Õhuläbilaskvus: klass 4; 10 Tulekindlus: nõudeid ei esitata; 11 Vastupanu tulekoormusele: C3; 12 Klaaspakett: kolmekordne klaaspakett; 13 Klaasingu erisused: kirgas klaas, sisemine klaas karastatud, välimine klaas lamineeritud, klaaside vahelised liistud musta värvi; 14 Päikesekiirgus tegur (g-väärtus): 0,38; 15 Avanemine: Avanemine: "" (L - vasak; R - parem); 16 Liigendatus: uks koosneb kahest ukselehest; 17 Sulused, lukustus: aktiivsel ukselehel kahepoolsed käepidemed Dormakaba TG9335 (käepide on sama kõrge kui on ukse klaas). Lukustus vastavalt lukustusprojektile. Uks varustatud fotosilmaga. Uks varustatud fonolukuga (musta viimistlusega). Ukselehed varustatud mustade liugsulguritega Abloy DC700 (või samaväärne analoog), sulgurid paigaldada tuulekoja poole. Hinged tootekesksed, viimistlus sama mis on ukselengil. Uks varustada taktiseadmega. Uks varustada piirajaga (sulguri sisene).; 18 Viimistlus: Tehaseliselt värvitud tumehalliks RAL7016 (Anthrazitgrau). Lävepakk - harjatud roostevaba terasleht t=1mm, kõrgus max 20mm.; 19 Mudel või toote tunnus: AD UP 75 (või samaväärne analoog); 20 Tootja: Schüco (või samaväärne analoog); 21 Tooteinfo: Undefined; 22 Kasutus- ja hooldusjuhend: Undefined; 23 viide sõlmele: Undefined
Pset_ManufacturerOccurrence - SerialNumber: Off
AC_Pset_RenovationAndPhasing - Renovation Status: New

# IfcDoor: 1080 x 2460 x 20, Klaas-seina integreeritud tuletõkke klaasuks * CW Door 22
In: 1,5 korrus
Type - ParameterTakesPrecedence: no; Sizeable: no
Classification: 1.9 IfcDoor (uks) (_RKAS BIM + ARCHICAD Classification)
Avatäited - 01 Nimetus: Klaas-seina integreeritud tuletõkke klaasuks; 02 Materjal: Klaas; Metall; 06 Soojusläbivus: -; 07 Helipidavus: 30dB; 08 Veepidavus: -; 09 Õhuläbilaskvus: -; 10 Tulekindlus: EI 30; 11 Vastupanu tulekoormusele: -; 12 Klaaspakett: Kahekordne klaaspakett; 13 Klaasingu erisused: kirgas tuletõkkeklaas, mille üks klaas on lamineeritud ja teine karastatud. Klaaside vaheline liist musta värvi; 14 Päikesekiirgus tegur (g-väärtus): -; 15 Avanemine: Avanemine: "R{Abbreviation of Right}" (L - vasak; R - parem); 16 Liigendatus: -; 17 Sulused, lukustus: Link AssaAbloy Inoxi 3-19 (harjatud roostevaba viimistlusega) tagasi keeratud lingi otsaga. Lukustus vastavalt lukustusprojektile. Uks peab olema õpetajate toa poolt lingist avatav. Must liugsulgur Abloy DC700 (või samaväärne analoog), sulgur paigaldada trepi poole. Hinged tootekesksed, viimistlus on sama, mis on ukselehel.; 18 Viimistlus: Tehaseliselt värvitud tumehalliks RAL7016 (Anthrazitgrau). Lävepakk - harjatud roostevaba terasleht t=1mm, kõrgus max 20mm; 19 Mudel või toote tunnus: Fuego Light (või samaväärne analoog); 20 Tootja: Forster (või samaväärne analoog); 21 Tooteinfo: Undefined; 22 Kasutus- ja hooldusjuhend: Undefined; 23 viide sõlmele: Undefined
Pset_ManufacturerOccurrence - SerialNumber: Off
AC_Pset_RenovationAndPhasing - Renovation Status: Existing

# IfcDoor: 1120 x 2400 x 20 (4)
In: 1 korrus
Type - ParameterTakesPrecedence: no; Sizeable: no
Avatäited - 02 Materjal: Klaas; Metall; 10 Tulekindlus: nõudeid ei esitata; 15 Avanemine: Avanemine: "" (L - vasak; R - parem); 18 Viimistlus: Tehaseliselt värvitud tumehalliks RAL7016 (Anthrazitgrau). Lävepakk - harjatud roostevaba terasleht t=1mm, kõrgus max 20mm.; 19 Mudel või toote tunnus: AD UP 75 (või samaväärne analoog); 20 Tootja: Schüco (või samaväärne analoog); 21 Tooteinfo: Undefined; 22 Kasutus- ja hooldusjuhend: Undefined; 23 viide sõlmele: Undefined
Pset_ManufacturerOccurrence - SerialNumber: Off
AC_Pset_RenovationAndPhasing - Renovation Status: New
Name | Classification | Material | 01 Nimetus | 06 Soojusläbivus | 07 Helipidavus | 08 Veepidavus | 09 Õhuläbilaskvus | 11 Vastupanu tulekoormusele | 12 Klaaspakett | 13 Klaasingu erisused | 14 Päikesekiirgus tegur (g-väärtus) | 16 Liigendatus | 17 Sulused, lukustus
Klaasfassaadi integreeritud välisuks * CW Double Door 22 | 0 TELLIJA KULUD (EHITUSKULUDE LIIGITAMINE EVS 885:2005); 1.9 IfcDoor (uks) (_RKAS BIM + ARCHICAD Classification) | Aluminium MUST (17), Klaas (2), Teras (musta värvi) (14) | Klaasfassaadi integreeritud välisuks | 1,1 W/m2K | 30dB | 7A | klass 4 | C3 | Kolmekordne klaaspakett | kirgas kolmekordne klaaspakett, välimine klaas lamineeritud, sisemine klaas karastatud, klaaside vahelised liistud musta värvi | 0,38 | Uks koosneb kahest ukselehest | Link AssaAbloy Inoxi 3-19 (harjatud roostevaba viimistlusega). Lukustus vastavalt lukustusprojektile. Mustad liugsulgurid Abloy DC700 (või samaväärne analoog), sulgur paigaldada sissepoole. Uks varustada taktiseadmega. Hinged tootekesksed, viimistlus on sama, mis on ukselehel. Uks varustada piirajaga (sulguri sisene).
Klaas-seina integreeritud siseuks * CW Double Door 22 | 1.9 IfcDoor (uks) (_RKAS BIM + ARCHICAD Classification) | Aluminium MUST (17), Klaas (2), Teras (musta värvi) (14) | Klaas-seina integreeritud siseuks | - | - | - | - | - | kahekordne klaaspakett | Kirgas klaas, sisemine klaas karastatud, välimine klaas lamineeritud, klaaside vahelised liistud musta värvi | - | Uks koosneb kahest ukselehest | ukselehtedel kahepoolsed käepidemed Dormakaba TG9335 (käepide on sama kõrge kui on ukse klaas). Lukustus vastavalt lukustusprojektile. Ukselehed varustatud mustade liugsulguritega Abloy DC700 (või samaväärne analoog), sulgurid paigaldada tuulekoja poole. Hinged tootekesksed, viimistlus sama mis on ukselengil. Uks varustada taktiseadmega. Uks varustada piirajaga (sulguri sisene).
Klaas-seina integreeritud siseuks * CW Double Door 22 | 1.9 IfcDoor (uks) (_RKAS BIM + ARCHICAD Classification) | Aluminium MUST (17), Klaas (2), Teras (musta värvi) (14) | Klaas-seina integreeritud siseuks | - | - | - | - | - | kahekordne klaaspakett | Kirgas klaas, sisemine klaas karastatud, välimine klaas lamineeritud, klaaside vahelised liistud musta värvi | - | uks koosneb kahest ukselehest | ukselehtedel kahepoolsed käepidemed Dormakaba TG9335 (käepide on sama kõrge kui on ukse klaas). Lukustus vastavalt lukustusprojektile. Ukselehed varustatud mustade liugsulguritega Abloy DC700 (või samaväärne analoog), sulgurid paigaldada tuulekoja poole. Hinged tootekesksed, viimistlus sama mis on ukselengil. Uks varustada taktiseadmega. Uks varustada piirajaga (sulguri sisene).
Klaasfassaadi integreeritud välisuks * CW Double Door 22 | 0 TELLIJA KULUD (EHITUSKULUDE LIIGITAMINE EVS 885:2005); 1.9 IfcDoor (uks) (_RKAS BIM + ARCHICAD Classification) |  | Klaasfassaadi integreeritud välisuks | 1,1 W/m2K | 30dB | 7A | klass 4 | C3 | kolmekordne klaaspakett | kirkast klaasist kolmekordne klaaspakett, välimine klaas lamineeritud, sisemine klaas karastatud, klaaside vahelised liistud musta värvi | 0,38 | Uks koosneb kahest ukselehest | Link AssaAbloy Inoxi 3-19 (harjatud roostevaba viimistlusega). Lukustus vastavalt lukustusprojektile. Mustad liugsulgurid Abloy DC700 (või samaväärne analoog), sulgur paigaldada sissepoole. Uks varustada taktiseadmega. Hinged tootekesksed, viimistlus on sama, mis on ukselehel. Uks varustada piirajaga (sulguri sisene).

# IfcDoor: 1120 x 2425 x 20, Klaas-seina integreeritud siseuks * CW Double Door 22
In: 1 korrus
Type - ParameterTakesPrecedence: no; Sizeable: no
Classification: 1.9 IfcDoor (uks) (_RKAS BIM + ARCHICAD Classification); Material: Aluminium MUST (17), Klaas (2), Teras (musta värvi) (14)
Avatäited - 01 Nimetus: Klaas-seina integreeritud siseuks; 02 Materjal: Klaas; Metall; 06 Soojusläbivus: -; 07 Helipidavus: -; 08 Veepidavus: -; 09 Õhuläbilaskvus: -; 10 Tulekindlus: nõudeid ei esitata; 11 Vastupanu tulekoormusele: -; 12 Klaaspakett: kahekordne klaaspakett; 13 Klaasingu erisused: Kirgas klaas, sisemine klaas karastatud, välimine klaas lamineeritud, klaaside vahelised liistud musta värvi; 14 Päikesekiirgus tegur (g-väärtus): -; 15 Avanemine: Avanemine: "" (L - vasak; R - parem); 16 Liigendatus: Uks koosneb kahest ukselehest; 17 Sulused, lukustus: ukselehtedel kahepoolsed käepidemed Dormakaba TG9335 (käepide on sama kõrge kui on ukse klaas). Lukustus vastavalt lukustusprojektile. Ukselehed varustatud mustade liugsulguritega Abloy DC700 (või samaväärne analoog), sulgurid paigaldada tuulekoja poole. Hinged tootekesksed, viimistlus sama mis on ukselengil. Uks varustada taktiseadmega. Uks varustada piirajaga (sulguri sisene).; 18 Viimistlus: Tehaseliselt värvitud tumehalliks RAL7016 (Anthrazitgrau). Lävepakk - harjatud roostevaba terasleht t=1mm, kõrgus max 20mm.; 19 Mudel või toote tunnus: AD UP 75 (või samaväärne analoog); 20 Tootja: Schüco (või samaväärne analoog); 21 Tooteinfo: Undefined; 22 Kasutus- ja hooldusjuhend: Undefined; 23 viide sõlmele: Undefined
Pset_ManufacturerOccurrence - SerialNumber: Off
AC_Pset_RenovationAndPhasing - Renovation Status: New

# IfcDoor: 1130 x 380 x 20 (3)
In: 0 korrus
Type - ParameterTakesPrecedence: no; Sizeable: no
Avatäited - 02 Materjal: Klaas; Metall; 06 Soojusläbivus: -; 07 Helipidavus: 30dB; 08 Veepidavus: -; 09 Õhuläbilaskvus: -; 10 Tulekindlus: nõudeid ei esitata; 11 Vastupanu tulekoormusele: -; 12 Klaaspakett: 6+1+6 kilelaminaadiga karastatud kirgas klaas; 14 Päikesekiirgus tegur (g-väärtus): -; 16 Liigendatus: -; 17 Sulused, lukustus: Link AssaAbloy Aperio (tagasi keeratud lingi otsaga). Lukustus vastavalt lukustusprojektile. Sulgur puudub. Hinged tootekesksed, viimistlus on sama, mis on ukselehel.; 18 Viimistlus: Tehaseliselt värvitud tumehalliks RAL7016 (Anthrazitgrau). Lävepakk - harjatud roostevaba terasleht t=1mm, kõrgus max 20mm.; 19 Mudel või toote tunnus: Fuego Light (või samaväärne analoog); 20 Tootja: Forster (või samaväärne analoog); 21 Tooteinfo: Undefined; 22 Kasutus- ja hooldusjuhend: Undefined; 23 viide sõlmele: Undefined
Pset_ManufacturerOccurrence - SerialNumber: Off
AC_Pset_RenovationAndPhasing - Renovation Status: New
Name | Classification | Material | 01 Nimetus | 13 Klaasingu erisused | 15 Avanemine
Klaas-seina integreeritud siseuks * CW Door 22 | 1.9 IfcDoor (uks) (_RKAS BIM + ARCHICAD Classification) | Aluminium MUST (27), Klaas | Klaas-seina integreeritud siseuks | lamineeritud, karastatud kirgas klaas | Avanemine: "L{Abbreviation of Left}" (L - vasak; R - parem)
Klaas-seinaintegreeritud siseuks * CW Door 22 | 0 TELLIJA KULUD (EHITUSKULUDE LIIGITAMINE EVS 885:2005); 1.9 IfcDoor (uks) (_RKAS BIM + ARCHICAD Classification) | Aluminium MUST (13), Klaas, Teras (musta värvi) (14) | Klaas-seinaintegreeritud siseuks | lamineeritud, karastatud kirgas klaas | Avanemine: "R{Abbreviation of Right}" (L - vasak; R - parem)
Klaas-seina integreeritud siseuks * CW Door 22 | 0 TELLIJA KULUD (EHITUSKULUDE LIIGITAMINE EVS 885:2005); 1.9 IfcDoor (uks) (_RKAS BIM + ARCHICAD Classification) | Aluminium MUST (13), Klaas, Teras (musta värvi) (14) | Klaas-seina integreeritud siseuks | karastatud, lamineeritud kirgas klaas | Avanemine: "R{Abbreviation of Right}" (L - vasak; R - parem)

# IfcDoor: 1150 x 2125 x 20, Klaasfassaadi integreeritud klaasuks * CW Double Door 22
In: 1 korrus
Type - ParameterTakesPrecedence: no; Sizeable: no
Classification: 0 TELLIJA KULUD (EHITUSKULUDE LIIGITAMINE EVS 885:2005); 1.9 IfcDoor (uks) (_RKAS BIM + ARCHICAD Classification); Material: Aluminium MUST (31), Klaas (2)
Avatäited - 01 Nimetus: Klaasfassaadi integreeritud klaasuks; 02 Materjal: Metall, klaas; 06 Soojusläbivus: 1,1W/m2K; 07 Helipidavus: 35dB; 08 Veepidavus: 7A; 09 Õhuläbilaskvus: klass 4; 10 Tulekindlus: nõudeid ei esitata; 11 Vastupanu tulekoormusele: C3; 12 Klaaspakett: kolmekordne klaaspakett; 13 Klaasingu erisused: kirkast klaasist kolmekordne klaaspakett, välimine klaas lamineeritud, sisemine klaas karastatud, klaaside vahelised liistud musta värvi; 14 Päikesekiirgus tegur (g-väärtus): 0,38; 15 Avanemine: Avanemine: "" (L - vasak; R - parem); 16 Liigendatus: Uks koosneb kahest ukselehest; 17 Sulused, lukustus: Link AssaAbloy Inoxi 3-19 (harjatud roostevaba viimistlusega). Lukustus vastavalt lukustusprojektile. Must liugsulgur Abloy DC700 (või samaväärne analoog), sulgur paigaldada sissepoole. Uks varustada taktiseadmega. Hinged tootekesksed, viimistlus on sama, mis on ukselehel. Uks varustada piirajaga (sulguri sisene).; 18 Viimistlus: Tehaseliselt värvitud tumehalliks RAL7016 (Anthrazitgrau). Lävepakk - harjatud roostevaba terasleht t=1mm, kõrgus max 20mm.; 19 Mudel või toote tunnus: AD UP 75 (või samaväärne analoog); 20 Tootja: Schüco (või samaväärne analoog); 21 Tooteinfo: Undefined; 22 Kasutus- ja hooldusjuhend: Undefined; 23 viide sõlmele: Undefined
Pset_ManufacturerOccurrence - SerialNumber: Off
AC_Pset_RenovationAndPhasing - Renovation Status: New

# IfcDoor: 1180 x 2380 x 20, Klaas-seina integreeritud siseuks * CW Door 22
In: 2 korrus
Type - ParameterTakesPrecedence: no; Sizeable: no
Classification: 0 TELLIJA KULUD (EHITUSKULUDE LIIGITAMINE EVS 885:2005); 1.9 IfcDoor (uks) (_RKAS BIM + ARCHICAD Classification); Material: Aluminium MUST (23), Klaas
Avatäited - 01 Nimetus: Klaas-seina integreeritud siseuks; 02 Materjal: Metall-raamis klaaspakett; 06 Soojusläbivus: -; 07 Helipidavus: 30dB; 08 Veepidavus: -; 09 Õhuläbilaskvus: -; 10 Tulekindlus: nõudeid ei esitata; 11 Vastupanu tulekoormusele: -; 12 Klaaspakett: -; 13 Klaasingu erisused: karastatud ja lamineeritud kirgas klaas; 14 Päikesekiirgus tegur (g-väärtus): -; 15 Avanemine: Avanemine: "R{Abbreviation of Right}" (L - vasak; R - parem); 16 Liigendatus: -; 17 Sulused, lukustus: Link AssaAbloy Aperio (tagasi keeratud lingi otsaga). Lukustus vastavalt lukustusprojektile. Sulgur puudub. Hinged tootekesksed, viimistlus on sama, mis on ukselehel. Uks varustada piirajaga.; 18 Viimistlus: Tehaseliselt värvitud tumehalliks RAL7016 (Anthrazitgrau). Lävepakk - harjatud roostevaba terasleht t=1mm, kõrgus max 20mm.; 19 Mudel või toote tunnus: Fuego Light (või samaväärne analoog); 20 Tootja: Forster (või samaväärne analoog); 21 Tooteinfo: Undefined; 22 Kasutus- ja hooldusjuhend: Undefined; 23 viide sõlmele: Undefined
Pset_ManufacturerOccurrence - SerialNumber: Off
AC_Pset_RenovationAndPhasing - Renovation Status: New

# IfcDoor: 1195 x 2380 x 20, Klaasfassaadi integreeritud välisuks * CW Door 22
In: 1 korrus
Type - ParameterTakesPrecedence: no; Sizeable: no
Classification: 1.9 IfcDoor (uks) (_RKAS BIM + ARCHICAD Classification); Material: Aluminium MUST (28), Klaas
Avatäited - 01 Nimetus: Klaasfassaadi integreeritud välisuks; 02 Materjal: Klaas; Metall; 06 Soojusläbivus: 1,1 W/m2K; 07 Helipidavus: 30dB; 08 Veepidavus: 7A; 09 Õhuläbilaskvus: klass 4; 10 Tulekindlus: nõudeid ei esitata; 11 Vastupanu tulekoormusele: C3; 12 Klaaspakett: Kolmekordne klaaspakett; 13 Klaasingu erisused: Kirgas klaas, sisemine klaas karastatud, välimine klaas lamineeritud, klaaside vahelised liistud musta värvi; 14 Päikesekiirgus tegur (g-väärtus): 0,58; 15 Avanemine: Avanemine: "L{Abbreviation of Left}" (L - vasak; R - parem); 16 Liigendatus: -; 17 Sulused, lukustus: Link seespool AssaAbloy Inoxi 3-19 (harjatud roostevaba viimistlusega), väljaspool käepide Dormakaba TG9335 (käepide sama kõrge kui ukseklaas). Lukustus vastavalt lukustusprojektile. Must liugsulgur Abloy DC700 (või samaväärne analoog), sulgur paigaldada sissepoole. Uks varustada piirajaga (sulguri siene). Hinged tootekesksed, viimistlus on sama, mis on ukselehel.; 18 Viimistlus: Tehaseliselt värvitud tumehalliks RAL7016 (Anthrazitgrau). Lävepakk - harjatud roostevaba terasleht t=1mm, kõrgus max 20mm.; 19 Mudel või toote tunnus: AD UP 75 (või samaväärne analoog); 20 Tootja: Schüco (või samaväärne analoog); 21 Tooteinfo: Undefined; 22 Kasutus- ja hooldusjuhend: Undefined; 23 viide sõlmele: Undefined
Pset_ManufacturerOccurrence - SerialNumber: Off
AC_Pset_RenovationAndPhasing - Renovation Status: New

# IfcDoor: 1200 x 2530 x 20, Klaasfassaadi integreeritud välisuks * CW Door 22
In: 0 korrus
Type - ParameterTakesPrecedence: no; Sizeable: no
Classification: 0 TELLIJA KULUD (EHITUSKULUDE LIIGITAMINE EVS 885:2005); 1.9 IfcDoor (uks) (_RKAS BIM + ARCHICAD Classification); Material: Aluminium MUST (27), Klaas
Avatäited - 01 Nimetus: Klaasfassaadi integreeritud välisuks; 02 Materjal: Metall, klaas; 06 Soojusläbivus: 1,1w/m2K; 07 Helipidavus: 35dB; 08 Veepidavus: 7A; 09 Õhuläbilaskvus: klass 4; 10 Tulekindlus: nõudeid ei esitata; 11 Vastupanu tulekoormusele: C3; 12 Klaaspakett: Kolmekordne klaaspakett; 13 Klaasingu erisused: kolmekordne klaaspakett, välimine klaas lamineeritud, sisemine klaas karastatud, klaaside vahelised liistud musta värvi; 14 Päikesekiirgus tegur (g-väärtus): 0,38; 15 Avanemine: Avanemine: "L{Abbreviation of Left}" (L - vasak; R - parem); 16 Liigendatus: -; 17 Sulused, lukustus: Link AssaAbloy Inoxi 3-19 (harjatud roostevaba viimistlusega). Lukustus vastavalt lukustusprojektile. Must liugsulgur Abloy DC700 (või samaväärne analoog), sulgur paigaldada sissepoole. Hinged tootekesksed, viimistlus on sama, mis on ukselehel. Uks varustada piirajaga (sulguri sisene).; 18 Viimistlus: Tehaseliselt värvitud tumehalliks RAL7016 (Anthrazitgrau). Lävepakk - harjatud roostevaba terasleht t=1mm, kõrgus max 20mm. Sulgur puudub.; 19 Mudel või toote tunnus: AD UP 75 (või samaväärne analoog); 20 Tootja: Schüco (või samaväärne analoog); 21 Tooteinfo: Undefined; 22 Kasutus- ja hooldusjuhend: Undefined; 23 viide sõlmele: Undefined
Pset_ManufacturerOccurrence - SerialNumber: Off
AC_Pset_RenovationAndPhasing - Renovation Status: New

# IfcDoor: 1205 x 2510 x 20, Klaasfassaadi integreeritud välisuks * CW Door 22
In: 0 korrus
Type - ParameterTakesPrecedence: no; Sizeable: no
Classification: 1.9 IfcDoor (uks) (_RKAS BIM + ARCHICAD Classification); Material: Aluminium MUST (27), Teras - Roostevaba, Klaas
Avatäited - 01 Nimetus: Klaasfassaadi integreeritud välisuks; 02 Materjal: Klaas; Metall; 06 Soojusläbivus: 1,0W/m2K; 07 Helipidavus: 30dB; 08 Veepidavus: 7A; 09 Õhuläbilaskvus: klass 4; 10 Tulekindlus: nõudeid ei esitata; 11 Vastupanu tulekoormusele: C3; 12 Klaaspakett: kolmekordne klaaspakett; 13 Klaasingu erisused: kolmekordne klaaspakett, välimine klaas lamineeritud, sisemine klaas karastatud, klaaside vahelised liistud musta värvi; 14 Päikesekiirgus tegur (g-väärtus): 0,38; 15 Avanemine: Avanemine: "L{Abbreviation of Left}" (L - vasak; R - parem); 16 Liigendatus: -; 17 Sulused, lukustus: Link AssaAbloy Inoxi 3-19 (harjatud roostevaba viimistlusega). Lukustus vastavalt lukustusprojektile. Must liugsulgur Abloy DC700 (või samaväärne analoog), sulgur paigaldada sissepoole. Hinged tootekesksed, viimistlus on sama, mis on ukselehel. Uks varustada piirajaga (sulguri sisene).; 18 Viimistlus: Tehaseliselt värvitud tumehalliks RAL7016 (Anthrazitgrau). Lävepakk - harjatud roostevaba terasleht t=1mm, kõrgus max 20mm. Sulgur puudub.; 19 Mudel või toote tunnus: AD UP 75 (või samaväärne analoog); 20 Tootja: Schüco (või samaväärne analoog); 21 Tooteinfo: Undefined; 22 Kasutus- ja hooldusjuhend: Undefined; 23 viide sõlmele: Undefined
Pset_ManufacturerOccurrence - SerialNumber: Off
AC_Pset_RenovationAndPhasing - Renovation Status: New

# IfcDoor: 1205 x 2530 x 20, Klaasfassaadi integreeritud välisuks * CW Door 22
In: 0 korrus
Type - ParameterTakesPrecedence: no; Sizeable: no
Classification: 1.9 IfcDoor (uks) (_RKAS BIM + ARCHICAD Classification); Material: Aluminium MUST (27), Klaas
Avatäited - 01 Nimetus: Klaasfassaadi integreeritud välisuks; 02 Materjal: Klaas; Metall; 06 Soojusläbivus: 1,1W/m2K; 07 Helipidavus: 35dB; 08 Veepidavus: 7A; 09 Õhuläbilaskvus: klass 4; 10 Tulekindlus: nõudeid ei esitata; 11 Vastupanu tulekoormusele: C3; 12 Klaaspakett: kolmekordne klaaspakett; 13 Klaasingu erisused: kolmekordne klaaspakett, välimine klaas lamineeritud, sisemine klaas karastatud, klaaside vahelised liistud musta värvi; 14 Päikesekiirgus tegur (g-väärtus): 0,38; 15 Avanemine: Avanemine: "L{Abbreviation of Left}" (L - vasak; R - parem); 16 Liigendatus: -; 17 Sulused, lukustus: Link AssaAbloy Inoxi 3-19 (harjatud roostevaba viimistlusega). Lukustus vastavalt lukustusprojektile. Must liugsulgur Abloy DC700 (või samaväärne analoog), sulgur paigaldada sissepoole. Hinged tootekesksed, viimistlus on sama, mis on ukselehel. Uks varustada piirajaga (sulguri sisene).; 18 Viimistlus: Tehaseliselt värvitud tumehalliks RAL7016 (Anthrazitgrau). Lävepakk - harjatud roostevaba terasleht t=1mm, kõrgus max 20mm. Sulgur puudub.; 19 Mudel või toote tunnus: AD UP 75 (või samaväärne analoog); 20 Tootja: Schüco (või samaväärne analoog); 21 Tooteinfo: Undefined; 22 Kasutus- ja hooldusjuhend: Undefined; 23 viide sõlmele: Undefined
Pset_ManufacturerOccurrence - SerialNumber: Off
AC_Pset_RenovationAndPhasing - Renovation Status: New

# IfcDoor: 50 x 2565 x 20, Klaasfassaadi integreeritud välisuks * CW Double Door 22
In: 1 korrus
Type - ParameterTakesPrecedence: no; Sizeable: no
Classification: 1.9 IfcDoor (uks) (_RKAS BIM + ARCHICAD Classification); Material: Aluminium MUST (31), Klaas (2)
Avatäited - 01 Nimetus: Klaasfassaadi integreeritud välisuks; 02 Materjal: Klaas; Metall; 06 Soojusläbivus: 1,1 W/m2K; 07 Helipidavus: 35dB; 08 Veepidavus: A7; 09 Õhuläbilaskvus: klass 4; 10 Tulekindlus: nõudeid ei esitata; 11 Vastupanu tulekoormusele: C3; 12 Klaaspakett: kolmekordne klaaspakett; 13 Klaasingu erisused: Kirgas klaas, sisemine klaas karastatud, välimine klaas lamineeritud, klaaside vahelised liistud musta värvi; 14 Päikesekiirgus tegur (g-väärtus): 0,38; 15 Avanemine: Avanemine: "" (L - vasak; R - parem); 16 Liigendatus: Uks koosneb kahest ukselehest; 17 Sulused, lukustus: Link AssaAbloy Inoxi 3-19 (harjatud roostevaba viimistlusega). Lukustus vastavalt lukustusprojektile. Must liugsulgur Abloy DC700 (või samaväärne analoog), sulgur paigaldada sissepoole. Uks varustada taktiseadmega. Hinged tootekesksed, viimistlus on sama, mis on ukselehel. Uks varustada piirajaga (sulguri sisene).; 18 Viimistlus: Tehaseliselt värvitud tumehalliks RAL7016 (Anthrazitgrau). Lävepakk - harjatud roostevaba terasleht t=1mm, kõrgus max 20mm.; 19 Mudel või toote tunnus: AD UP 75 (või samaväärne analoog); 20 Tootja: Schüco (või samaväärne analoog); 21 Tooteinfo: Undefined; 22 Kasutus- ja hooldusjuhend: Undefined
Pset_ManufacturerOccurrence - SerialNumber: Off
AC_Pset_RenovationAndPhasing - Renovation Status: Existing

# IfcDoor: SS-02 900×2 100, Siseuks * Door 22
In: 1,5 korrus
Type - OperationType: SINGLE_SWING_LEFT; ParameterTakesPrecedence: no; Sizeable: no
Type - Door Lining Properties - LiningDepth: 100 mm; LiningThickness: 40 mm; ThresholdDepth: 60 mm; ThresholdThickness: 5 mm; LiningOffset: 210 mm; ThresholdOffset: 250 mm
Type - Door Panel Properties - Panel 1 - PanelDepth: 40 mm; PanelOperation: SWINGING; PanelWidth: 1; PanelPosition: MIDDLE
OverallHeight: 2100 mm; OverallWidth: 900 mm; Classification: 1.9 IfcDoor (uks) (_RKAS BIM + ARCHICAD Classification)
Pset_DoorCommon - ThermalTransmittance: 0; GlazingAreaFraction: 1.14117; IsExternal: no
Avatäited - 01 Nimetus: Siseuks; 02 Materjal: Klaas; Alumiinium; 03 Tähistus: SS-02 900×2 100; 04 Avamõõdu geomeetria: 900×2 100; 05 Asukoha info: Interior; 06 Soojusläbivus: -; 07 Helipidavus: 30dB; 08 Veepidavus: -; 09 Õhuläbilaskvus: -; 10 Tulekindlus: EI 30; 11 Vastupanu tulekoormusele: -; 12 Klaaspakett: 6+1+6 kilelaminaadiga karastatud kirgas klaas; 13 Klaasingu erisused: kahekordne kirgas tuletõkke klaaspakett, välimine klaas karastatud, sisemine klaas lamineeritud, klaaside vahelised liistud musta värvi; 14 Päikesekiirgus tegur (g-väärtus): -; 15 Avanemine: Avanemine: "R" (L - vasak; R - parem); 16 Liigendatus: -; 17 Sulused, lukustus: Link AssaAbloy Aperio (tagasi keeratud lingi otsaga). Lukustus vastavalt lukustusprojektile. Sulgur puudub. Hinged tootekesksed, viimistlus on sama, mis on ukselehel.; 18 Viimistlus: Tehaseliselt värvitud tumehalliks RAL7016 (Anthrazitgrau). Lävepakk - harjatud roostevaba terasleht t=1mm, kõrgus max 20mm. Leng - pikendatud leng, detailijoonist vt. sisearhitektuursest osast, viimistlus sama, mis ukselehel.; 19 Mudel või toote tunnus: Fuego Light (või samaväärne analoog); 20 Tootja: Forster (või samaväärne analoog); 21 Tooteinfo: Undefined; 22 Kasutus- ja hooldusjuhend: Undefined; 23 viide sõlmele: Undefined
AC_Pset_RenovationAndPhasing - Renovation Status: New

# IfcDoor: SU-01 900×2 400, Siseuks * Door 22
In: 2 korrus
Type - OperationType: SINGLE_SWING_LEFT; ParameterTakesPrecedence: no; Sizeable: no
Type - Door Lining Properties - LiningDepth: 100 mm; LiningThickness: 40 mm; ThresholdDepth: 60 mm; ThresholdThickness: 5 mm; LiningOffset: -10 mm; ThresholdOffset: -10 mm
Type - Door Panel Properties - Panel 1 - PanelDepth: 40 mm; PanelOperation: SWINGING; PanelWidth: 1; PanelPosition: MIDDLE
OverallHeight: 2400 mm; OverallWidth: 900 mm; Classification: 0 TELLIJA KULUD (EHITUSKULUDE LIIGITAMINE EVS 885:2005); 1.9 IfcDoor (uks) (_RKAS BIM + ARCHICAD Classification)
Pset_DoorCommon - ThermalTransmittance: 0; GlazingAreaFraction: 1.33437; IsExternal: no
Avatäited - 01 Nimetus: Siseuks; 02 Materjal: Metallraamis klaasuks; 03 Tähistus: SU-01 900×2 400; 04 Avamõõdu geomeetria: 900×2 400; 05 Asukoha info: Interior; 06 Soojusläbivus: -; 07 Helipidavus: 30dB; 08 Veepidavus: -; 09 Õhuläbilaskvus: -; 10 Tulekindlus: nõudeid ei esitata; 11 Vastupanu tulekoormusele: -; 12 Klaaspakett: -; 13 Klaasingu erisused: karastatud ja lamineeritud kirgas klaas; 14 Päikesekiirgus tegur (g-väärtus): -; 15 Avanemine: Avanemine: "R" (L - vasak; R - parem); 16 Liigendatus: -; 17 Sulused, lukustus: Link AssaAbloy Aperio (tagasi keeratud lingi otsaga). Lukustus vastavalt lukustusprojektile. Sulgur puudub. Hinged tootekesksed, viimistlus on sama, mis on ukselehel.; 18 Viimistlus: Tehaseliselt värvitud tumehalliks RAL7016 (Anthrazitgrau). Lävepakk - harjatud roostevaba terasleht t=1mm, kõrgus max 20mm. Leng - pikendatud leng, detailijoonist vt. sisearhitektuursest osast, viimistlus sama, mis ukselehel.; 19 Mudel või toote tunnus: Fuego Light (või samaväärne analoog); 20 Tootja: Forster (või samaväärne analoog); 21 Tooteinfo: Undefined; 22 Kasutus- ja hooldusjuhend: Undefined; 23 viide sõlmele: Undefined
AC_Pset_RenovationAndPhasing - Renovation Status: New

# IfcDoor: SU-01 900×2 400 (2)
In: 2 korrus
Type - OperationType: SINGLE_SWING_LEFT; ParameterTakesPrecedence: no; Sizeable: no
Type - Door Lining Properties - LiningDepth: 100 mm; LiningThickness: 40 mm; ThresholdDepth: 60 mm; ThresholdThickness: 5 mm; LiningOffset: 210 mm; ThresholdOffset: 210 mm
Type - Door Panel Properties - Panel 1 - PanelDepth: 40 mm; PanelOperation: SWINGING; PanelWidth: 1; PanelPosition: MIDDLE
OverallHeight: 2400 mm; OverallWidth: 900 mm; Classification: 0 TELLIJA KULUD (EHITUSKULUDE LIIGITAMINE EVS 885:2005); 1.9 IfcDoor (uks) (_RKAS BIM + ARCHICAD Classification)
Pset_DoorCommon - ThermalTransmittance: 0; GlazingAreaFraction: 1.33437; IsExternal: no
Avatäited - 01 Nimetus: Siseuks; 02 Materjal: Metallraamis klaasuks; 03 Tähistus: SU-01 900×2 400; 04 Avamõõdu geomeetria: 900×2 400; 05 Asukoha info: Interior; 06 Soojusläbivus: -; 07 Helipidavus: 30dB; 08 Veepidavus: -; 09 Õhuläbilaskvus: -; 11 Vastupanu tulekoormusele: -; 12 Klaaspakett: -; 13 Klaasingu erisused: karastatud ja lamineeritud kirgas klaas; 14 Päikesekiirgus tegur (g-väärtus): -; 15 Avanemine: Avanemine: "R" (L - vasak; R - parem); 16 Liigendatus: -; 18 Viimistlus: Tehaseliselt värvitud tumehalliks RAL7016 (Anthrazitgrau). Lävepakk - harjatud roostevaba terasleht t=1mm, kõrgus max 20mm. Leng - pikendatud leng, detailijoonist vt. sisearhitektuursest osast, viimistlus sama, mis ukselehel.; 19 Mudel või toote tunnus: Fuego Light (või samaväärne analoog); 20 Tootja: Forster (või samaväärne analoog); 21 Tooteinfo: Undefined; 22 Kasutus- ja hooldusjuhend: Undefined; 23 viide sõlmele: Undefined
AC_Pset_RenovationAndPhasing - Renovation Status: New
Name | 10 Tulekindlus | 17 Sulused, lukustus
Siseuks * Door 22 | EI 30 | Link AssaAbloy Aperio (tagasi keeratud lingi otsaga). Lukustus vastavalt lukustusprojektile. Must liugsulgur Abloy DC700 (või samaväärne analoog), sulgur paigaldada abiruumi poole. Hinged tootekesksed, viimistlus on sama, mis on ukselehel.
Siseuks * Door 22 | nõudeid ei esitata | Link AssaAbloy Aperio (tagasi keeratud lingi otsaga). Lukustus vastavalt lukustusprojektile. Sulgur puudub. Hinged tootekesksed, viimistlus on sama, mis on ukselehel.

# IfcDoor: SU-01 900×2 400 (7)
Type - OperationType: SINGLE_SWING_LEFT; ParameterTakesPrecedence: no; Sizeable: no
Type - Door Lining Properties - LiningDepth: 100 mm; LiningThickness: 40 mm; ThresholdDepth: 60 mm; ThresholdThickness: 5 mm; LiningOffset: 210 mm; ThresholdOffset: 250 mm
Type - Door Panel Properties - Panel 1 - PanelDepth: 40 mm; PanelOperation: SWINGING; PanelWidth: 1; PanelPosition: MIDDLE
OverallHeight: 2400 mm; OverallWidth: 900 mm
Pset_DoorCommon - ThermalTransmittance: 0; GlazingAreaFraction: 1.33437; IsExternal: no
Avatäited - 01 Nimetus: Siseuks; 03 Tähistus: SU-01 900×2 400; 04 Avamõõdu geomeetria: 900×2 400; 05 Asukoha info: Interior; 06 Soojusläbivus: -; 08 Veepidavus: -; 09 Õhuläbilaskvus: -; 11 Vastupanu tulekoormusele: -; 14 Päikesekiirgus tegur (g-väärtus): -; 15 Avanemine: Avanemine: "R" (L - vasak; R - parem); 16 Liigendatus: -; 18 Viimistlus: Tehaseliselt värvitud tumehalliks RAL7016 (Anthrazitgrau). Lävepakk - harjatud roostevaba terasleht t=1mm, kõrgus max 20mm. Leng - pikendatud leng, detailijoonist vt. sisearhitektuursest osast, viimistlus sama, mis ukselehel.; 19 Mudel või toote tunnus: Fuego Light (või samaväärne analoog); 20 Tootja: Forster (või samaväärne analoog); 21 Tooteinfo: Undefined; 22 Kasutus- ja hooldusjuhend: Undefined; 23 viide sõlmele: Undefined
AC_Pset_RenovationAndPhasing - Renovation Status: New
Name | In | Classification | 02 Materjal | 07 Helipidavus | 10 Tulekindlus | 12 Klaaspakett | 13 Klaasingu erisused | 17 Sulused, lukustus
Siseuks * Door 22 | 0 korrus | 0 TELLIJA KULUD (EHITUSKULUDE LIIGITAMINE EVS 885:2005); 1.9 IfcDoor (uks) (_RKAS BIM + ARCHICAD Classification) | Klaas; Metall | 38dB | nõudeid ei esitata | 6+1+6 kilelaminaadiga karastatud kirgas klaas | - | Link AssaAbloy Aperio (tagasi keeratud lingi otsaga). Lukustus vastavalt lukustusprojektile. Sulgur puudub. Hinged tootekesksed, viimistlus on sama, mis on ukselehel.
Siseuks * Door 22 | 2 korrus | 0 TELLIJA KULUD (EHITUSKULUDE LIIGITAMINE EVS 885:2005); 1.9 IfcDoor (uks) (_RKAS BIM + ARCHICAD Classification) | Metallraamis klaasuks | 30dB | EI 30 | - | karastatud ja lamineeritud kirgas klaas | Link AssaAbloy Aperio (tagasi keeratud lingi otsaga). Lukustus vastavalt lukustusprojektile. Must liugsulgur Abloy DC700 (või samaväärne analoog), sulgur paigaldada abiruumi poole. Hinged tootekesksed, viimistlus on sama, mis on ukselehel.
4 x Siseuks * Door 22 | 2 korrus | 0 TELLIJA KULUD (EHITUSKULUDE LIIGITAMINE EVS 885:2005); 1.9 IfcDoor (uks) (_RKAS BIM + ARCHICAD Classification) | Metallraamis klaasuks | 30dB | nõudeid ei esitata | - | karastatud ja lamineeritud kirgas klaas | Link AssaAbloy Aperio (tagasi keeratud lingi otsaga). Lukustus vastavalt lukustusprojektile. Sulgur puudub. Hinged tootekesksed, viimistlus on sama, mis on ukselehel.
Siseuks * Door 22 | 2 korrus | 1.9 IfcDoor (uks) (_RKAS BIM + ARCHICAD Classification) | Metallraamis klaasuks | 30dB | nõudeid ei esitata | - | karastatud ja lamineeritud kirgas klaas | Link AssaAbloy Aperio (tagasi keeratud lingi otsaga). Lukustus vastavalt lukustusprojektile. Sulgur puudub. Hinged tootekesksed, viimistlus on sama, mis on ukselehel.

# IfcDoor: SU-01 900×2 400, Siseuks * Door 22
In: 0 korrus
Type - OperationType: SINGLE_SWING_RIGHT; ParameterTakesPrecedence: no; Sizeable: no
Type - Door Lining Properties - LiningDepth: 100 mm; LiningThickness: 40 mm; ThresholdDepth: 60 mm; ThresholdThickness: 5 mm; LiningOffset: -10 mm; ThresholdOffset: -10 mm
Type - Door Panel Properties - Panel 1 - PanelDepth: 40 mm; PanelOperation: SWINGING; PanelWidth: 1; PanelPosition: MIDDLE
OverallHeight: 2400 mm; OverallWidth: 900 mm; Classification: 0 TELLIJA KULUD (EHITUSKULUDE LIIGITAMINE EVS 885:2005); 1.9 IfcDoor (uks) (_RKAS BIM + ARCHICAD Classification)
Pset_DoorCommon - ThermalTransmittance: 0; GlazingAreaFraction: 1.33437; IsExternal: no
Avatäited - 01 Nimetus: Siseuks; 02 Materjal: Klaas; Metall; 03 Tähistus: SU-01 900×2 400; 04 Avamõõdu geomeetria: 900×2 400; 05 Asukoha info: Interior; 06 Soojusläbivus: -; 07 Helipidavus: 38dB; 08 Veepidavus: -; 09 Õhuläbilaskvus: -; 10 Tulekindlus: nõudeid ei esitata; 11 Vastupanu tulekoormusele: -; 12 Klaaspakett: 6+1+6 kilelaminaadiga karastatud kirgas klaas; 13 Klaasingu erisused: -; 14 Päikesekiirgus tegur (g-väärtus): -; 15 Avanemine: Avanemine: "L" (L - vasak; R - parem); 16 Liigendatus: -; 17 Sulused, lukustus: Link AssaAbloy Aperio (tagasi keeratud lingi otsaga). Lukustus vastavalt lukustusprojektile. Sulgur puudub. Hinged tootekesksed, viimistlus on sama, mis on ukselehel.; 18 Viimistlus: Tehaseliselt värvitud tumehalliks RAL7016 (Anthrazitgrau). Lävepakk - harjatud roostevaba terasleht t=1mm, kõrgus max 20mm. Leng - pikendatud leng, detailijoonist vt. sisearhitektuursest osast, viimistlus sama, mis ukselehel.; 19 Mudel või toote tunnus: Fuego Light (või samaväärne analoog); 20 Tootja: Forster (või samaväärne analoog); 21 Tooteinfo: Undefined; 22 Kasutus- ja hooldusjuhend: Undefined; 23 viide sõlmele: Undefined
AC_Pset_RenovationAndPhasing - Renovation Status: New

# IfcDoor: SU-01 900×2 400 (4)
In: 2 korrus
Type - OperationType: SINGLE_SWING_RIGHT; ParameterTakesPrecedence: no; Sizeable: no
Type - Door Lining Properties - LiningDepth: 100 mm; LiningThickness: 40 mm; ThresholdDepth: 60 mm; ThresholdThickness: 5 mm; LiningOffset: -10 mm; ThresholdOffset: 30 mm
Type - Door Panel Properties - Panel 1 - PanelDepth: 40 mm; PanelOperation: SWINGING; PanelWidth: 1; PanelPosition: MIDDLE
OverallHeight: 2400 mm; OverallWidth: 900 mm; Classification: 0 TELLIJA KULUD (EHITUSKULUDE LIIGITAMINE EVS 885:2005); 1.9 IfcDoor (uks) (_RKAS BIM + ARCHICAD Classification)
Pset_DoorCommon - ThermalTransmittance: 0; GlazingAreaFraction: 1.33437; IsExternal: no
Avatäited - 01 Nimetus: Siseuks; 03 Tähistus: SU-01 900×2 400; 04 Avamõõdu geomeetria: 900×2 400; 05 Asukoha info: Interior; 06 Soojusläbivus: -; 07 Helipidavus: 30dB; 08 Veepidavus: -; 09 Õhuläbilaskvus: -; 10 Tulekindlus: nõudeid ei esitata; 11 Vastupanu tulekoormusele: -; 12 Klaaspakett: -; 13 Klaasingu erisused: karastatud ja lamineeritud kirgas klaas; 14 Päikesekiirgus tegur (g-väärtus): -; 15 Avanemine: Avanemine: "L" (L - vasak; R - parem); 16 Liigendatus: -; 17 Sulused, lukustus: Link AssaAbloy Aperio (tagasi keeratud lingi otsaga). Lukustus vastavalt lukustusprojektile. Sulgur puudub. Hinged tootekesksed, viimistlus on sama, mis on ukselehel.; 18 Viimistlus: Tehaseliselt värvitud tumehalliks RAL7016 (Anthrazitgrau). Lävepakk - harjatud roostevaba terasleht t=1mm, kõrgus max 20mm. Leng - pikendatud leng, detailijoonist vt. sisearhitektuursest osast, viimistlus sama, mis ukselehel.; 19 Mudel või toote tunnus: Fuego Light (või samaväärne analoog); 20 Tootja: Forster (või samaväärne analoog); 21 Tooteinfo: Undefined; 22 Kasutus- ja hooldusjuhend: Undefined; 23 viide sõlmele: Undefined
AC_Pset_RenovationAndPhasing - Renovation Status: New
Name | 02 Materjal
3 x Siseuks * Door 22 | Metallraamis klaasuks
Siseuks * Door 22 | Klaas; Alumiinium

# IfcDoor: SU-01 900×2 400, Siseuks * Door 22
In: 0 korrus
Type - OperationType: SINGLE_SWING_RIGHT; ParameterTakesPrecedence: no; Sizeable: no
Type - Door Lining Properties - LiningDepth: 100 mm; LiningThickness: 40 mm; ThresholdDepth: 60 mm; ThresholdThickness: 5 mm; LiningOffset: 210 mm; ThresholdOffset: 210 mm
Type - Door Panel Properties - Panel 1 - PanelDepth: 40 mm; PanelOperation: SWINGING; PanelWidth: 1; PanelPosition: MIDDLE
OverallHeight: 2400 mm; OverallWidth: 900 mm; Classification: 0 TELLIJA KULUD (EHITUSKULUDE LIIGITAMINE EVS 885:2005); 1.9 IfcDoor (uks) (_RKAS BIM + ARCHICAD Classification)
Pset_DoorCommon - ThermalTransmittance: 0; GlazingAreaFraction: 1.33437; IsExternal: no
Avatäited - 01 Nimetus: Siseuks; 02 Materjal: Klaas; Metall; 03 Tähistus: SU-01 900×2 400; 04 Avamõõdu geomeetria: 900×2 400; 05 Asukoha info: Interior; 06 Soojusläbivus: -; 07 Helipidavus: 38dB; 08 Veepidavus: -; 09 Õhuläbilaskvus: -; 10 Tulekindlus: nõudeid ei esitata; 11 Vastupanu tulekoormusele: -; 12 Klaaspakett: 6+1+6 kilelaminaadiga karastatud kirgas klaas; 13 Klaasingu erisused: -; 14 Päikesekiirgus tegur (g-väärtus): -; 15 Avanemine: Avanemine: "L" (L - vasak; R - parem); 16 Liigendatus: -; 17 Sulused, lukustus: Link AssaAbloy Aperio (tagasi keeratud lingi otsaga). Lukustus vastavalt lukustusprojektile. Sulgur puudub. Hinged tootekesksed, viimistlus on sama, mis on ukselehel.; 18 Viimistlus: Tehaseliselt värvitud tumehalliks RAL7016 (Anthrazitgrau). Lävepakk - harjatud roostevaba terasleht t=1mm, kõrgus max 20mm. Leng - pikendatud leng, detailijoonist vt. sisearhitektuursest osast, viimistlus sama, mis ukselehel.; 19 Mudel või toote tunnus: Fuego Light (või samaväärne analoog); 20 Tootja: Forster (või samaväärne analoog); 21 Tooteinfo: Undefined; 22 Kasutus- ja hooldusjuhend: Undefined; 23 viide sõlmele: Undefined
AC_Pset_RenovationAndPhasing - Renovation Status: New

# IfcDoor: SU-01 900×2 400 (3)
In: 2 korrus
Type - OperationType: SINGLE_SWING_RIGHT; ParameterTakesPrecedence: no; Sizeable: no
Type - Door Lining Properties - LiningDepth: 100 mm; LiningThickness: 40 mm; ThresholdDepth: 60 mm; ThresholdThickness: 5 mm; LiningOffset: 210 mm; ThresholdOffset: 250 mm
Type - Door Panel Properties - Panel 1 - PanelDepth: 40 mm; PanelOperation: SWINGING; PanelWidth: 1; PanelPosition: MIDDLE
OverallHeight: 2400 mm; OverallWidth: 900 mm
Pset_DoorCommon - ThermalTransmittance: 0; GlazingAreaFraction: 1.33437; IsExternal: no
Avatäited - 01 Nimetus: Siseuks; 02 Materjal: Metallraamis klaasuks; 03 Tähistus: SU-01 900×2 400; 04 Avamõõdu geomeetria: 900×2 400; 05 Asukoha info: Interior; 06 Soojusläbivus: -; 07 Helipidavus: 30dB; 08 Veepidavus: -; 09 Õhuläbilaskvus: -; 11 Vastupanu tulekoormusele: -; 12 Klaaspakett: -; 13 Klaasingu erisused: karastatud ja lamineeritud kirgas klaas; 14 Päikesekiirgus tegur (g-väärtus): -; 15 Avanemine: Avanemine: "L" (L - vasak; R - parem); 16 Liigendatus: -; 18 Viimistlus: Tehaseliselt värvitud tumehalliks RAL7016 (Anthrazitgrau). Lävepakk - harjatud roostevaba terasleht t=1mm, kõrgus max 20mm. Leng - pikendatud leng, detailijoonist vt. sisearhitektuursest osast, viimistlus sama, mis ukselehel.; 19 Mudel või toote tunnus: Fuego Light (või samaväärne analoog); 20 Tootja: Forster (või samaväärne analoog); 21 Tooteinfo: Undefined; 22 Kasutus- ja hooldusjuhend: Undefined; 23 viide sõlmele: Undefined
AC_Pset_RenovationAndPhasing - Renovation Status: New
Name | Classification | 10 Tulekindlus | 17 Sulused, lukustus
Siseuks * Door 22 | 1.9 IfcDoor (uks) (_RKAS BIM + ARCHICAD Classification) | nõudeid ei esitata | Link AssaAbloy Aperio (tagasi keeratud lingi otsaga). Lukustus vastavalt lukustusprojektile. Sulgur puudub. Hinged tootekesksed, viimistlus on sama, mis on ukselehel.
Siseuks * Door 22 | 1.9 IfcDoor (uks) (_RKAS BIM + ARCHICAD Classification) | EI 30 | Link AssaAbloy Aperio (tagasi keeratud lingi otsaga). Lukustus vastavalt lukustusprojektile. Must liugsulgur Abloy DC700 (või samaväärne analoog), sulgur paigaldada abiruumi poole. Hinged tootekesksed, viimistlus on sama, mis on ukselehel.
Siseuks * Door 22 | 0 TELLIJA KULUD (EHITUSKULUDE LIIGITAMINE EVS 885:2005); 1.9 IfcDoor (uks) (_RKAS BIM + ARCHICAD Classification) | nõudeid ei esitata | Link AssaAbloy Aperio (tagasi keeratud lingi otsaga). Lukustus vastavalt lukustusprojektile. Sulgur puudub. Hinged tootekesksed, viimistlus on sama, mis on ukselehel.

# IfcDoor: SU-02 900×2 100, Siseuks * Door 22
In: 0 korrus
Type - OperationType: SINGLE_SWING_LEFT; ParameterTakesPrecedence: no; Sizeable: no
Type - Door Lining Properties - LiningDepth: 100 mm; LiningThickness: 40 mm; ThresholdDepth: 60 mm; ThresholdThickness: 5 mm; LiningOffset: -10 mm; ThresholdOffset: 30 mm
Type - Door Panel Properties - Panel 1 - PanelDepth: 40 mm; PanelOperation: SWINGING; PanelWidth: 1; PanelPosition: MIDDLE
OverallHeight: 2100 mm; OverallWidth: 900 mm; Classification: 0 TELLIJA KULUD (EHITUSKULUDE LIIGITAMINE EVS 885:2005); 1.9 IfcDoor (uks) (_RKAS BIM + ARCHICAD Classification)
Pset_DoorCommon - ThermalTransmittance: 0; GlazingAreaFraction: 1.14117; IsExternal: no
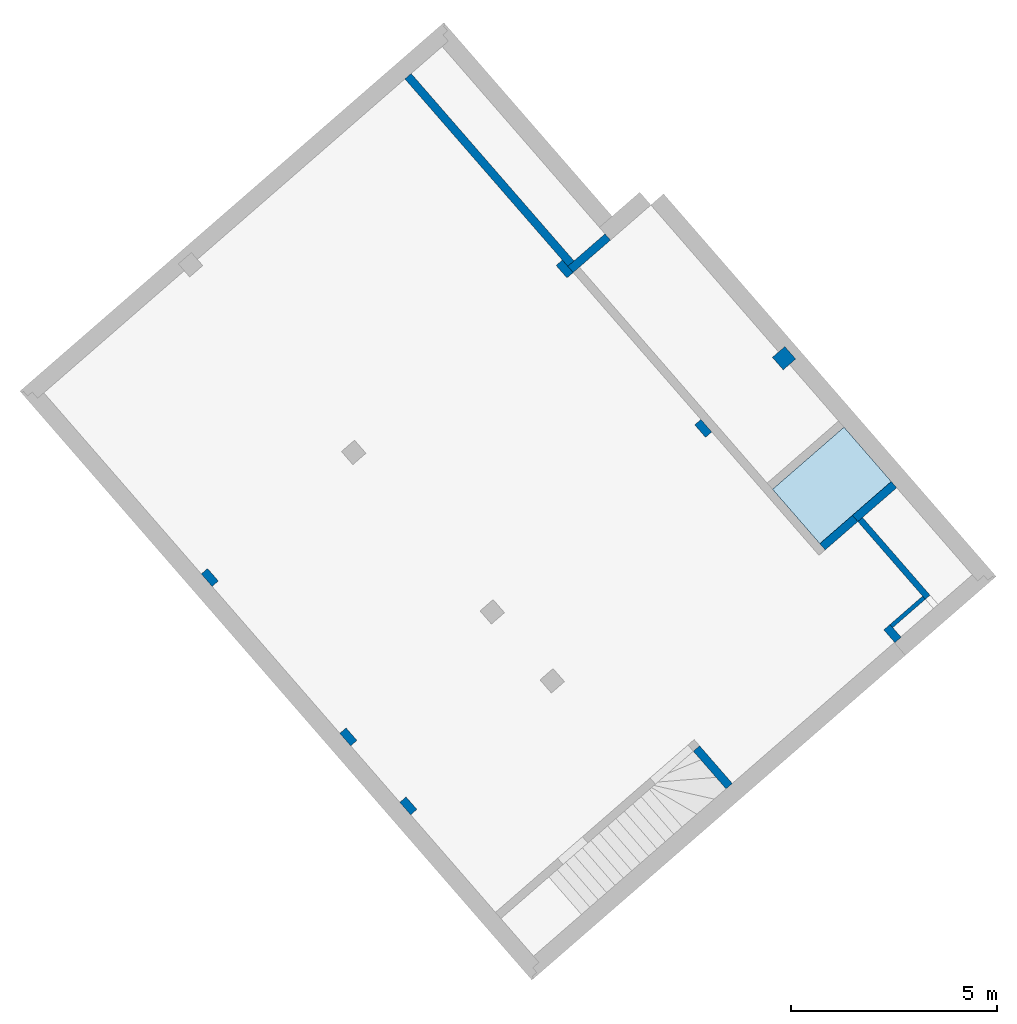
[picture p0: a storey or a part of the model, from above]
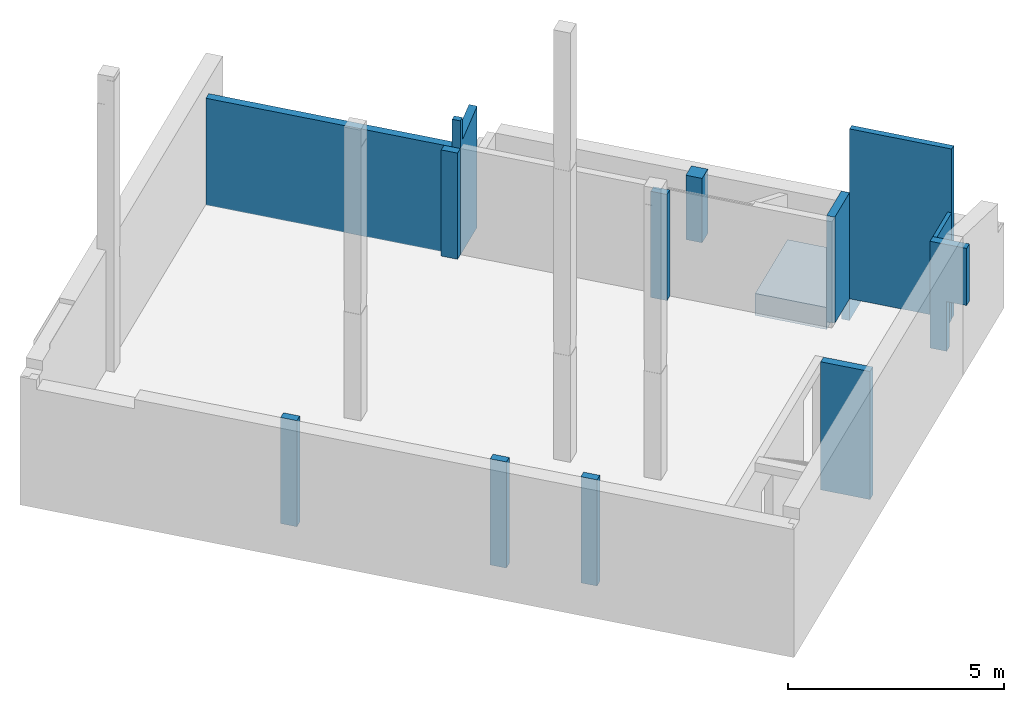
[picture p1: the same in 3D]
Properties of the parts of a building model (IFC2X3), part 5 of 13

# IfcDoor: SU-02 900×2 100, Siseuks * Door 22
Avatäited - 01 Nimetus: Siseuks; 02 Materjal: Klaas; Alumiinium; 03 Tähistus: SU-02 900×2 100; 04 Avamõõdu geomeetria: 900×2 100; 05 Asukoha info: Interior; 06 Soojusläbivus: -; 07 Helipidavus: 30dB; 08 Veepidavus: -; 09 Õhuläbilaskvus: -; 10 Tulekindlus: nõudeid ei esitata; 11 Vastupanu tulekoormusele: -; 12 Klaaspakett: 6+1+6 kilelaminaadiga karastatud kirgas klaas; 13 Klaasingu erisused: lamineeritud ja karastatud kirgas klaas; 14 Päikesekiirgus tegur (g-väärtus): -; 15 Avanemine: Avanemine: "R" (L - vasak; R - parem); 16 Liigendatus: -; 17 Sulused, lukustus: Link AssaAbloy Aperio (tagasi keeratud lingi otsaga). Lukustus vastavalt lukustusprojektile. Sulgur puudub. Hinged tootekesksed, viimistlus on sama, mis on ukselehel.; 18 Viimistlus: Tehaseliselt värvitud tumehalliks RAL7016 (Anthrazitgrau). Lävepakk - harjatud roostevaba terasleht t=1mm, kõrgus max 20mm. Leng - pikendatud leng, detailijoonist vt. sisearhitektuursest osast, viimistlus sama, mis ukselehel.; 19 Mudel või toote tunnus: Fuego Light (või samaväärne analoog); 20 Tootja: Forster (või samaväärne analoog); 21 Tooteinfo: Undefined; 22 Kasutus- ja hooldusjuhend: Undefined; 23 viide sõlmele: Undefined
AC_Pset_RenovationAndPhasing - Renovation Status: New

# IfcDoor: SU-02 900×2 100, Siseuks * Door 22
In: 1,5 korrus
Type - OperationType: SINGLE_SWING_LEFT; ParameterTakesPrecedence: no; Sizeable: no
Type - Door Lining Properties - LiningDepth: 100 mm; LiningThickness: 40 mm; ThresholdDepth: 60 mm; ThresholdThickness: 5 mm; LiningOffset: 160 mm; ThresholdOffset: 200 mm
Type - Door Panel Properties - Panel 1 - PanelDepth: 40 mm; PanelOperation: SWINGING; PanelWidth: 1; PanelPosition: MIDDLE
OverallHeight: 2100 mm; OverallWidth: 900 mm; Classification: 0 TELLIJA KULUD (EHITUSKULUDE LIIGITAMINE EVS 885:2005); 1.9 IfcDoor (uks) (_RKAS BIM + ARCHICAD Classification)
Pset_DoorCommon - ThermalTransmittance: 0; GlazingAreaFraction: 1.14117; IsExternal: no
Avatäited - 01 Nimetus: Siseuks; 02 Materjal: Metall, klaas; 03 Tähistus: SU-02 900×2 100; 04 Avamõõdu geomeetria: 900×2 100; 05 Asukoha info: Interior; 06 Soojusläbivus: -; 07 Helipidavus: 30dB; 08 Veepidavus: -; 09 Õhuläbilaskvus: -; 10 Tulekindlus: EI 30; 11 Vastupanu tulekoormusele: -; 12 Klaaspakett: kahekordne klaaspakett; 13 Klaasingu erisused: kahekordne kirgas tuletõkke klaaspakett, välimine klaas karastatud, sisemine klaas lamineeritud, klaaside vahelised liistud musta värvi; 14 Päikesekiirgus tegur (g-väärtus): -; 15 Avanemine: Avanemine: "R" (L - vasak; R - parem); 16 Liigendatus: -; 17 Sulused, lukustus: Link AssaAbloy Aperio (tagasi keeratud lingi otsaga). Lukustus vastavalt lukustusprojektile. Uks peab ATS-i rakendumise korral automaatselt avanema! Sulgur puudub. Hinged tootekesksed, viimistlus on sama, mis on ukselehel.; 18 Viimistlus: Tehaseliselt värvitud tumehalliks RAL7016 (Anthrazitgrau). Lävepakk - harjatud roostevaba terasleht t=1mm, kõrgus max 20mm. Leng - pikendatud leng, detailijoonist vt. sisearhitektuursest osast, viimistlus sama, mis ukselehel.; 19 Mudel või toote tunnus: Fuego Light (või samaväärne analoog); 20 Tootja: Forster (või samaväärne analoog); 21 Tooteinfo: Undefined; 22 Kasutus- ja hooldusjuhend: Undefined; 23 viide sõlmele: Undefined
AC_Pset_RenovationAndPhasing - Renovation Status: New

# IfcDoor: SU-02 900×2 100, Siseuks * Door 22
In: 1 korrus
Type - OperationType: SINGLE_SWING_LEFT; ParameterTakesPrecedence: no; Sizeable: no
Type - Door Lining Properties - LiningDepth: 100 mm; LiningThickness: 40 mm; ThresholdDepth: 60 mm; ThresholdThickness: 5 mm; LiningOffset: 210 mm; ThresholdOffset: 210 mm
Type - Door Panel Properties - Panel 1 - PanelDepth: 40 mm; PanelOperation: SWINGING; PanelWidth: 1; PanelPosition: MIDDLE
OverallHeight: 2100 mm; OverallWidth: 900 mm; Classification: 0 TELLIJA KULUD (EHITUSKULUDE LIIGITAMINE EVS 885:2005); 1.9 IfcDoor (uks) (_RKAS BIM + ARCHICAD Classification)
Pset_DoorCommon - ThermalTransmittance: 0; GlazingAreaFraction: 1.14117; IsExternal: no
Avatäited - 01 Nimetus: Siseuks; 02 Materjal: Klaas; Metall; 03 Tähistus: SU-02 900×2 100; 04 Avamõõdu geomeetria: 900×2 100; 05 Asukoha info: Interior; 06 Soojusläbivus: -; 07 Helipidavus: 50dB; 08 Veepidavus: -; 09 Õhuläbilaskvus: -; 10 Tulekindlus: nõudeid ei esitata; 11 Vastupanu tulekoormusele: -; 12 Klaaspakett: 2xSSG Stadip Silence laminaadiga klaas; 13 Klaasingu erisused: 2xSSG Stadip Silence laminaadiga klaas; 14 Päikesekiirgus tegur (g-väärtus): -; 15 Avanemine: Avanemine: "R" (L - vasak; R - parem); 16 Liigendatus: -; 17 Sulused, lukustus: Link AssaAbloy Aperio (tagasi keeratud lingi otsaga). Lukustus vastavalt lukustusprojektile. Must liugsulgur Abloy DC700 (või samaväärne analoog), sulgur paigaldada klassi poole. Hinged tootekesksed, viimistlus on sama, mis on ukselehel.; 18 Viimistlus: Tehaseliselt värvitud tumehalliks RAL7016 (Anthrazitgrau). Lävepakk - harjatud roostevaba terasleht t=1mm, kõrgus max 20mm. Leng - pikendatud leng, detailijoonist vt. sisearhitektuursest osast, viimistlus sama, mis ukselehel.; 19 Mudel või toote tunnus: Fuego Light (või samaväärne analoog); 20 Tootja: Forster (või samaväärne analoog); 21 Tooteinfo: Undefined; 22 Kasutus- ja hooldusjuhend: Undefined; 23 viide sõlmele: Undefined
AC_Pset_RenovationAndPhasing - Renovation Status: New

# IfcDoor: SU-02 900×2 100 (6)
In: 1,5 korrus
Type - OperationType: SINGLE_SWING_LEFT; ParameterTakesPrecedence: no; Sizeable: no
Type - Door Lining Properties - LiningDepth: 100 mm; LiningThickness: 40 mm; ThresholdDepth: 60 mm; ThresholdThickness: 5 mm; LiningOffset: 210 mm; ThresholdOffset: 250 mm
Type - Door Panel Properties - Panel 1 - PanelDepth: 40 mm; PanelOperation: SWINGING; PanelWidth: 1; PanelPosition: MIDDLE
OverallHeight: 2100 mm; OverallWidth: 900 mm
Pset_DoorCommon - ThermalTransmittance: 0; GlazingAreaFraction: 1.14117; IsExternal: no
Avatäited - 01 Nimetus: Siseuks; 02 Materjal: Metall, klaas; 03 Tähistus: SU-02 900×2 100; 04 Avamõõdu geomeetria: 900×2 100; 05 Asukoha info: Interior; 06 Soojusläbivus: -; 07 Helipidavus: 30dB; 08 Veepidavus: -; 11 Vastupanu tulekoormusele: -; 12 Klaaspakett: kahekordne klaaspakett; 13 Klaasingu erisused: kahekordne kirgas tuletõkke klaaspakett, välimine klaas karastatud, sisemine klaas lamineeritud, klaaside vahelised liistud musta värvi; 14 Päikesekiirgus tegur (g-väärtus): -; 15 Avanemine: Avanemine: "R" (L - vasak; R - parem); 16 Liigendatus: -; 18 Viimistlus: Tehaseliselt värvitud tumehalliks RAL7016 (Anthrazitgrau). Lävepakk - harjatud roostevaba terasleht t=1mm, kõrgus max 20mm. Leng - pikendatud leng, detailijoonist vt. sisearhitektuursest osast, viimistlus sama, mis ukselehel.; 19 Mudel või toote tunnus: Fuego Light (või samaväärne analoog); 20 Tootja: Forster (või samaväärne analoog); 21 Tooteinfo: Undefined; 22 Kasutus- ja hooldusjuhend: Undefined; 23 viide sõlmele: Undefined
AC_Pset_RenovationAndPhasing - Renovation Status: New
Name | Classification | 09 Õhuläbilaskvus | 10 Tulekindlus | 17 Sulused, lukustus
Siseuks * Door 22 | 0 TELLIJA KULUD (EHITUSKULUDE LIIGITAMINE EVS 885:2005); 1.9 IfcDoor (uks) (_RKAS BIM + ARCHICAD Classification) | - | nõudeid ei esitata | Link AssaAbloy Aperio (tagasi keeratud lingi otsaga). Lukustus vastavalt lukustusprojektile. Uks peab ATS-i rakendumise korral automaatselt avanema! Sulgur puudub. Hinged tootekesksed, viimistlus on sama, mis on ukselehel.
Siseuks * Door 22 | 0 TELLIJA KULUD (EHITUSKULUDE LIIGITAMINE EVS 885:2005); 1.9 IfcDoor (uks) (_RKAS BIM + ARCHICAD Classification) | ukse all siirdeõhu pilu | nõudeid ei esitata | Link AssaAbloy Aperio (tagasi keeratud lingi otsaga). Lukustus vastavalt lukustusprojektile. Uks peab ATS-i rakendumise korral automaatselt avanema! Sulgur puudub. Hinged tootekesksed, viimistlus on sama, mis on ukselehel.
2 x Siseuks * Door 22 | 0 TELLIJA KULUD (EHITUSKULUDE LIIGITAMINE EVS 885:2005); 1.9 IfcDoor (uks) (_RKAS BIM + ARCHICAD Classification) | - | EI 30 | Link AssaAbloy Aperio (tagasi keeratud lingi otsaga). Lukustus vastavalt lukustusprojektile. Must liugsulgur Abloy DC700 (või samaväärne analoog), sulgur paigaldada klassi poole. Hinged tootekesksed, viimistlus on sama, mis on ukselehel.
Siseuks * Door 22 | 1.9 IfcDoor (uks) (_RKAS BIM + ARCHICAD Classification) | - | nõudeid ei esitata | Link AssaAbloy Aperio (tagasi keeratud lingi otsaga). Lukustus vastavalt lukustusprojektile. Uks peab ATS-i rakendumise korral automaatselt avanema! Sulgur puudub. Hinged tootekesksed, viimistlus on sama, mis on ukselehel.
Siseuks * Door 22 | 1.9 IfcDoor (uks) (_RKAS BIM + ARCHICAD Classification) | - | EI 30 | Link AssaAbloy Inoxi 3-19 (harjatud roostevaba viimistlusega). Lukustus vastavalt lukustusprojektile. Uksel direktori kabineti pool väändenupp, millega saab ukse avada. Sulgur puudub. Hinged tootekesksed, viimistlus on sama, mis on ukselehel.

# IfcDoor: SU-02 900×2 100, Siseuks * Door 22
In: 1,5 korrus
Type - OperationType: SINGLE_SWING_RIGHT; ParameterTakesPrecedence: no; Sizeable: no
Type - Door Lining Properties - LiningDepth: 100 mm; LiningThickness: 40 mm; ThresholdDepth: 60 mm; ThresholdThickness: 5 mm; LiningOffset: -10 mm; ThresholdOffset: -10 mm
Type - Door Panel Properties - Panel 1 - PanelDepth: 40 mm; PanelOperation: SWINGING; PanelWidth: 1; PanelPosition: MIDDLE
OverallHeight: 2100 mm; OverallWidth: 900 mm; Classification: 0 TELLIJA KULUD (EHITUSKULUDE LIIGITAMINE EVS 885:2005); 1.9 IfcDoor (uks) (_RKAS BIM + ARCHICAD Classification)
Pset_DoorCommon - ThermalTransmittance: 0; GlazingAreaFraction: 1.14117; IsExternal: no
Avatäited - 01 Nimetus: Siseuks; 02 Materjal: Metall, klaas; 03 Tähistus: SU-02 900×2 100; 04 Avamõõdu geomeetria: 900×2 100; 05 Asukoha info: Interior; 06 Soojusläbivus: -; 07 Helipidavus: 30dB; 08 Veepidavus: -; 09 Õhuläbilaskvus: -; 10 Tulekindlus: EI 30; 11 Vastupanu tulekoormusele: -; 12 Klaaspakett: kahekordne klaaspakett; 13 Klaasingu erisused: kahekordne kirgas tuletõkke klaaspakett, välimine klaas karastatud, sisemine klaas lamineeritud, klaaside vahelised liistud musta värvi; 14 Päikesekiirgus tegur (g-väärtus): -; 15 Avanemine: Avanemine: "L" (L - vasak; R - parem); 16 Liigendatus: -; 17 Sulused, lukustus: Link AssaAbloy Inoxi 3-19 (harjatud roostevaba viimistlusega). Lukustus vastavalt lukustusprojektile. Uks peab ATS-i rakendumise korral automaatselt avanema! Sulgur puudub. Hinged tootekesksed, viimistlus on sama, mis on ukselehel.; 18 Viimistlus: Tehaseliselt värvitud tumehalliks RAL7016 (Anthrazitgrau). Lävepakk - harjatud roostevaba terasleht t=1mm, kõrgus max 20mm. Leng - pikendatud leng, detailijoonist vt. sisearhitektuursest osast, viimistlus sama, mis ukselehel.; 19 Mudel või toote tunnus: Fuego Light (või samaväärne analoog); 20 Tootja: Forster (või samaväärne analoog); 21 Tooteinfo: Undefined; 22 Kasutus- ja hooldusjuhend: Undefined; 23 viide sõlmele: Undefined
AC_Pset_RenovationAndPhasing - Renovation Status: New

# IfcDoor: SU-02 900×2 100 (2)
Type - OperationType: SINGLE_SWING_RIGHT; ParameterTakesPrecedence: no; Sizeable: no
Type - Door Lining Properties - LiningDepth: 100 mm; LiningThickness: 40 mm; ThresholdDepth: 60 mm; ThresholdThickness: 5 mm; LiningOffset: -10 mm; ThresholdOffset: 30 mm
Type - Door Panel Properties - Panel 1 - PanelDepth: 40 mm; PanelOperation: SWINGING; PanelWidth: 1; PanelPosition: MIDDLE
OverallHeight: 2100 mm; OverallWidth: 900 mm
Pset_DoorCommon - ThermalTransmittance: 0; GlazingAreaFraction: 1.14117; IsExternal: no
Avatäited - 01 Nimetus: Siseuks; 03 Tähistus: SU-02 900×2 100; 04 Avamõõdu geomeetria: 900×2 100; 05 Asukoha info: Interior; 06 Soojusläbivus: -; 07 Helipidavus: 30dB; 08 Veepidavus: -; 09 Õhuläbilaskvus: -; 11 Vastupanu tulekoormusele: -; 14 Päikesekiirgus tegur (g-väärtus): -; 15 Avanemine: Avanemine: "L" (L - vasak; R - parem); 16 Liigendatus: -; 18 Viimistlus: Tehaseliselt värvitud tumehalliks RAL7016 (Anthrazitgrau). Lävepakk - harjatud roostevaba terasleht t=1mm, kõrgus max 20mm. Leng - pikendatud leng, detailijoonist vt. sisearhitektuursest osast, viimistlus sama, mis ukselehel.; 19 Mudel või toote tunnus: Fuego Light (või samaväärne analoog); 20 Tootja: Forster (või samaväärne analoog); 21 Tooteinfo: Undefined; 22 Kasutus- ja hooldusjuhend: Undefined; 23 viide sõlmele: Undefined
AC_Pset_RenovationAndPhasing - Renovation Status: New
Name | In | Classification | 02 Materjal | 10 Tulekindlus | 12 Klaaspakett | 13 Klaasingu erisused | 17 Sulused, lukustus
Siseuks * Door 22 | 0 korrus | 0 TELLIJA KULUD (EHITUSKULUDE LIIGITAMINE EVS 885:2005); 1.9 IfcDoor (uks) (_RKAS BIM + ARCHICAD Classification) | Klaas; Alumiinium | nõudeid ei esitata | 6+1+6 kilelaminaadiga karastatud kirgas klaas | lamineeritud ja karastatud kirgas klaas | Link AssaAbloy Aperio (tagasi keeratud lingi otsaga). Lukustus vastavalt lukustusprojektile. Sulgur puudub. Hinged tootekesksed, viimistlus on sama, mis on ukselehel.
Siseuks * Door 22 | 1,5 korrus | 1.9 IfcDoor (uks) (_RKAS BIM + ARCHICAD Classification) | Metall, klaas | EI 30 | kahekordne klaaspakett | kahekordne kirgas tuletõkke klaaspakett, välimine klaas karastatud, sisemine klaas lamineeritud, klaaside vahelised liistud musta värvi | Link AssaAbloy Aperio (tagasi keeratud lingi otsaga). Lukustus vastavalt lukustusprojektile. Uks peab ATS-i rakendumise korral automaatselt avanema! Sulgur puudub. Hinged tootekesksed, viimistlus on sama, mis on ukselehel.

# IfcDoor: SU-02 900×2 100 (3)
In: 1,5 korrus
Type - OperationType: SINGLE_SWING_RIGHT; ParameterTakesPrecedence: no; Sizeable: no
Type - Door Lining Properties - LiningDepth: 100 mm; LiningThickness: 40 mm; ThresholdDepth: 60 mm; ThresholdThickness: 5 mm; LiningOffset: 210 mm; ThresholdOffset: 250 mm
Type - Door Panel Properties - Panel 1 - PanelDepth: 40 mm; PanelOperation: SWINGING; PanelWidth: 1; PanelPosition: MIDDLE
OverallHeight: 2100 mm; OverallWidth: 900 mm; Classification: 0 TELLIJA KULUD (EHITUSKULUDE LIIGITAMINE EVS 885:2005); 1.9 IfcDoor (uks) (_RKAS BIM + ARCHICAD Classification)
Pset_DoorCommon - ThermalTransmittance: 0; GlazingAreaFraction: 1.14117; IsExternal: no
Avatäited - 01 Nimetus: Siseuks; 02 Materjal: Metall, klaas; 03 Tähistus: SU-02 900×2 100; 04 Avamõõdu geomeetria: 900×2 100; 05 Asukoha info: Interior; 06 Soojusläbivus: -; 07 Helipidavus: 30dB; 08 Veepidavus: -; 09 Õhuläbilaskvus: -; 10 Tulekindlus: EI 30; 11 Vastupanu tulekoormusele: -; 12 Klaaspakett: kahekordne klaaspakett; 13 Klaasingu erisused: kahekordne kirgas tuletõkke klaaspakett, välimine klaas karastatud, sisemine klaas lamineeritud, klaaside vahelised liistud musta värvi; 14 Päikesekiirgus tegur (g-väärtus): -; 15 Avanemine: Avanemine: "L" (L - vasak; R - parem); 16 Liigendatus: -; 18 Viimistlus: Tehaseliselt värvitud tumehalliks RAL7016 (Anthrazitgrau). Lävepakk - harjatud roostevaba terasleht t=1mm, kõrgus max 20mm. Leng - pikendatud leng, detailijoonist vt. sisearhitektuursest osast, viimistlus sama, mis ukselehel.; 19 Mudel või toote tunnus: Fuego Light (või samaväärne analoog); 20 Tootja: Forster (või samaväärne analoog); 21 Tooteinfo: Undefined; 22 Kasutus- ja hooldusjuhend: Undefined; 23 viide sõlmele: Undefined
AC_Pset_RenovationAndPhasing - Renovation Status: New
Name | 17 Sulused, lukustus
Siseuks * Door 22 | Link AssaAbloy Aperio (tagasi keeratud lingi otsaga). Lukustus vastavalt lukustusprojektile. Must liugsulgur Abloy DC700 (või samaväärne analoog), sulgur paigaldada õpetajate toa poole. Hinged tootekesksed, viimistlus on sama, mis on ukselehel.
2 x Siseuks * Door 22 | Link AssaAbloy Aperio (tagasi keeratud lingi otsaga). Lukustus vastavalt lukustusprojektile. Must liugsulgur Abloy DC700 (või samaväärne analoog), sulgur paigaldada kabineti poole. Hinged tootekesksed, viimistlus on sama, mis on ukselehel.

# IfcDoor: SU-03 800×2 400, Siseuks * Door 22
In: 2 korrus
Type - OperationType: SINGLE_SWING_LEFT; ParameterTakesPrecedence: no; Sizeable: no
Type - Door Lining Properties - LiningDepth: 100 mm; LiningThickness: 40 mm; ThresholdDepth: 60 mm; ThresholdThickness: 5 mm; LiningOffset: 210 mm; ThresholdOffset: 250 mm
Type - Door Panel Properties - Panel 1 - PanelDepth: 40 mm; PanelOperation: SWINGING; PanelWidth: 1; PanelPosition: MIDDLE
OverallHeight: 2400 mm; OverallWidth: 800 mm; Classification: 1.9 IfcDoor (uks) (_RKAS BIM + ARCHICAD Classification)
Pset_DoorCommon - ThermalTransmittance: 0; GlazingAreaFraction: 1.12717; IsExternal: no
Avatäited - 01 Nimetus: Siseuks; 02 Materjal: Metallraamis klaasuks; 03 Tähistus: SU-03 800×2 400; 04 Avamõõdu geomeetria: 800×2 400; 05 Asukoha info: Interior; 06 Soojusläbivus: -; 07 Helipidavus: 30dB; 08 Veepidavus: -; 09 Õhuläbilaskvus: -; 10 Tulekindlus: nõudeid ei esitata; 11 Vastupanu tulekoormusele: -; 12 Klaaspakett: -; 13 Klaasingu erisused: karastatud ja lamineeritud kirgas klaas; 14 Päikesekiirgus tegur (g-väärtus): -; 15 Avanemine: Avanemine: "R" (L - vasak; R - parem); 16 Liigendatus: -; 17 Sulused, lukustus: Link AssaAbloy Aperio (tagasi keeratud lingi otsaga). Lukustus vastavalt lukustusprojektile. Sulgur puudub. Hinged tootekesksed, viimistlus on sama, mis on ukselehel.; 18 Viimistlus: Tehaseliselt värvitud tumehalliks RAL7016 (Anthrazitgrau). Lävepakk - harjatud roostevaba terasleht t=1mm, kõrgus max 20mm. Leng - pikendatud leng, detailijoonist vt. sisearhitektuursest osast, viimistlus sama, mis ukselehel.; 19 Mudel või toote tunnus: Fuego Light (või samaväärne analoog); 20 Tootja: Forster (või samaväärne analoog); 21 Tooteinfo: Undefined; 22 Kasutus- ja hooldusjuhend: Undefined; 23 viide sõlmele: Undefined
AC_Pset_RenovationAndPhasing - Renovation Status: New

# IfcDoor: SU-03 800×2 400, Siseuks * Door 22
In: 2 korrus
Type - OperationType: SINGLE_SWING_RIGHT; ParameterTakesPrecedence: no; Sizeable: no
Type - Door Lining Properties - LiningDepth: 100 mm; LiningThickness: 40 mm; ThresholdDepth: 60 mm; ThresholdThickness: 5 mm; LiningOffset: 210 mm; ThresholdOffset: 250 mm
Type - Door Panel Properties - Panel 1 - PanelDepth: 40 mm; PanelOperation: SWINGING; PanelWidth: 1; PanelPosition: MIDDLE
OverallHeight: 2400 mm; OverallWidth: 800 mm; Classification: 1.9 IfcDoor (uks) (_RKAS BIM + ARCHICAD Classification)
Pset_DoorCommon - ThermalTransmittance: 0; GlazingAreaFraction: 1.12717; IsExternal: no
Avatäited - 01 Nimetus: Siseuks; 02 Materjal: Metallraamis klaasuks; 03 Tähistus: SU-03 800×2 400; 04 Avamõõdu geomeetria: 800×2 400; 05 Asukoha info: Interior; 06 Soojusläbivus: -; 07 Helipidavus: -; 08 Veepidavus: -; 09 Õhuläbilaskvus: ukse all siirdeõhu pilu; 10 Tulekindlus: nõudeid ei esitata; 11 Vastupanu tulekoormusele: -; 12 Klaaspakett: -; 13 Klaasingu erisused: karastatud ja lamineeritud kirgas klaas; 14 Päikesekiirgus tegur (g-väärtus): -; 15 Avanemine: Avanemine: "L" (L - vasak; R - parem); 16 Liigendatus: -; 17 Sulused, lukustus: Link AssaAbloy Aperio (tagasi keeratud lingi otsaga). Lukustus vastavalt lukustusprojektile. Sulgur puudub. Hinged tootekesksed, viimistlus on sama, mis on ukselehel.; 18 Viimistlus: Tehaseliselt värvitud tumehalliks RAL7016 (Anthrazitgrau). Lävepakk - harjatud roostevaba terasleht t=1mm, kõrgus max 20mm. Leng - pikendatud leng, detailijoonist vt. sisearhitektuursest osast, viimistlus sama, mis ukselehel.; 19 Mudel või toote tunnus: Fuego Light (või samaväärne analoog); 20 Tootja: Forster (või samaväärne analoog); 21 Tooteinfo: Undefined; 22 Kasutus- ja hooldusjuhend: Undefined; 23 viide sõlmele: Undefined
AC_Pset_RenovationAndPhasing - Renovation Status: New

# IfcDoor: SU-04 800×2 100, Siseuks * Door 22
In: 0 korrus
Type - OperationType: SINGLE_SWING_RIGHT; ParameterTakesPrecedence: no; Sizeable: no
Type - Door Lining Properties - LiningDepth: 100 mm; LiningThickness: 40 mm; ThresholdDepth: 60 mm; ThresholdThickness: 5 mm; LiningOffset: -10 mm; ThresholdOffset: -10 mm
Type - Door Panel Properties - Panel 1 - PanelDepth: 40 mm; PanelOperation: SWINGING; PanelWidth: 1; PanelPosition: MIDDLE
OverallHeight: 2100 mm; OverallWidth: 800 mm; Classification: 1.9 IfcDoor (uks) (_RKAS BIM + ARCHICAD Classification)
Pset_DoorCommon - ThermalTransmittance: 0; GlazingAreaFraction: 0.963968; IsExternal: no
Avatäited - 01 Nimetus: Siseuks; 02 Materjal: Klaas; Alumiinium; 03 Tähistus: SU-04 800×2 100; 04 Avamõõdu geomeetria: 800×2 100; 05 Asukoha info: Interior; 06 Soojusläbivus: -; 07 Helipidavus: 30dB; 08 Veepidavus: -; 09 Õhuläbilaskvus: -; 10 Tulekindlus: nõudeid ei esitata; 11 Vastupanu tulekoormusele: -; 12 Klaaspakett: -; 13 Klaasingu erisused: karastatud ja lamineeritud kirgas klaas; 14 Päikesekiirgus tegur (g-väärtus): -; 15 Avanemine: Avanemine: "L" (L - vasak; R - parem); 16 Liigendatus: -; 17 Sulused, lukustus: Link AssaAbloy Aperio (tagasi keeratud lingi otsaga). Lukustus vastavalt lukustusprojektile. Sulgur puudub. Hinged tootekesksed, viimistlus on sama, mis on ukselehel.; 18 Viimistlus: Tehaseliselt värvitud tumehalliks RAL7016 (Anthrazitgrau). Lävepakk - harjatud roostevaba terasleht t=1mm, kõrgus max 20mm. Leng - pikendatud leng, detailijoonist vt. sisearhitektuursest osast, viimistlus sama, mis ukselehel.; 19 Mudel või toote tunnus: Fuego Light (või samaväärne analoog); 20 Tootja: Forster (või samaväärne analoog); 21 Tooteinfo: Undefined; 22 Kasutus- ja hooldusjuhend: Undefined; 23 viide sõlmele: Undefined
AC_Pset_RenovationAndPhasing - Renovation Status: New

# IfcDoor: SU-05 1 200×2 400, Siseuks * Door 22
In: 2 korrus
Type - OperationType: SINGLE_SWING_LEFT; ParameterTakesPrecedence: no; Sizeable: no
Type - Door Lining Properties - LiningDepth: 100 mm; LiningThickness: 40 mm; ThresholdDepth: 60 mm; ThresholdThickness: 5 mm; LiningOffset: 210 mm; ThresholdOffset: 210 mm
Type - Door Panel Properties - Panel 1 - PanelDepth: 40 mm; PanelOperation: SWINGING; PanelWidth: 1; PanelPosition: MIDDLE
OverallHeight: 2400 mm; OverallWidth: 1200 mm; Classification: 0 TELLIJA KULUD (EHITUSKULUDE LIIGITAMINE EVS 885:2005); 1.9 IfcDoor (uks) (_RKAS BIM + ARCHICAD Classification)
Pset_DoorCommon - ThermalTransmittance: 0; GlazingAreaFraction: 1.95597; IsExternal: no
Avatäited - 01 Nimetus: Siseuks; 02 Materjal: Metallraamis klaasuks; 03 Tähistus: SU-05 1 200×2 400; 04 Avamõõdu geomeetria: 1 200×2 400; 05 Asukoha info: Interior; 06 Soojusläbivus: -; 07 Helipidavus: -; 08 Veepidavus: -; 09 Õhuläbilaskvus: -; 10 Tulekindlus: EI 30; 11 Vastupanu tulekoormusele: -; 12 Klaaspakett: Kahekordne klaaspakett, klaaside vahelised liistudmusta värvi; 13 Klaasingu erisused: karastatud ja lamineeritud kirgas tuletõkke klaas; 14 Päikesekiirgus tegur (g-väärtus): -; 15 Avanemine: Avanemine: "R" (L - vasak; R - parem); 16 Liigendatus: -; 17 Sulused, lukustus: AssaAbloy Inoxi 3-19 (harjatud roostevaba viimistlus), Lukustus vastavalt lukustusprojektile. Must liugsulgur Abloy DC700 (või samaväärne analoog), sulgur paigaldada koridori (ruum 214) poole. Hinged tootekesksed, viimistlus on sama, mis on ukselehel.; 18 Viimistlus: Tehaseliselt värvitud tumehalliks RAL7016 (Anthrazitgrau). Lävepakk - harjatud roostevaba terasleht t=1mm, kõrgus max 20mm. Leng - pikendatud leng, detailijoonist vt. sisearhitektuursest osast, viimistlus sama, mis ukselehel.; 19 Mudel või toote tunnus: Fuego Light (või samaväärne analoog); 20 Tootja: Forster (või samaväärne analoog); 21 Tooteinfo: Undefined; 22 Kasutus- ja hooldusjuhend: Undefined; 23 viide sõlmele: Undefined
AC_Pset_RenovationAndPhasing - Renovation Status: New

# IfcDoor: SU-06 800×2 100, Siseuks * Door 22
In: 1 korrus
Type - OperationType: SINGLE_SWING_LEFT; ParameterTakesPrecedence: no; Sizeable: no
Type - Door Lining Properties - LiningDepth: 100 mm; LiningThickness: 40 mm; ThresholdDepth: 60 mm; ThresholdThickness: 5 mm; LiningOffset: -10 mm; ThresholdOffset: 30 mm
Type - Door Panel Properties - Panel 1 - PanelDepth: 40 mm; PanelOperation: SWINGING; PanelWidth: 1; PanelPosition: MIDDLE
OverallHeight: 2100 mm; OverallWidth: 800 mm; Classification: 0 TELLIJA KULUD (EHITUSKULUDE LIIGITAMINE EVS 885:2005); 1.9 IfcDoor (uks) (_RKAS BIM + ARCHICAD Classification)
Pset_DoorCommon - ThermalTransmittance: 0; GlazingAreaFraction: 0.963968; IsExternal: no
Avatäited - 01 Nimetus: Siseuks; 02 Materjal: Metallraamis klaasuks; 03 Tähistus: SU-06 800×2 100; 04 Avamõõdu geomeetria: 800×2 100; 05 Asukoha info: Interior; 06 Soojusläbivus: -; 07 Helipidavus: -; 08 Veepidavus: -; 09 Õhuläbilaskvus: -; 10 Tulekindlus: nõudeid ei esitata; 11 Vastupanu tulekoormusele: -; 12 Klaaspakett: 4+1+4 kilelaminaadiga karastatud kirgas klaas.; 13 Klaasingu erisused: Klaasi osa kaetud matistava kilega.; 14 Päikesekiirgus tegur (g-väärtus): -; 15 Avanemine: Avanemine: "R" (L - vasak; R - parem); 16 Liigendatus: -; 17 Sulused, lukustus: Link AssaAbloy Inoxi 3-19 (harjatud roostevaba viimistlusega). Lukustus vastavalt lukustusprojektile. Must liugsulgur Abloy DC700 (või samaväärne analoog), sulgur paigaldada eesruumi (ruum 142) poole. Uks varustada piirajaga (sulguri sisene). Hinged tootekesksed, viimistlus on sama, mis on ukselehel.; 18 Viimistlus: Tehaseliselt värvitud tumehalliks RAL7016 (Anthrazitgrau). Lävepakk - harjatud roostevaba terasleht t=1mm, kõrgus max 20mm. Leng - pikendatud leng, detailijoonist vt. sisearhitektuursest osast, viimistlus sama, mis ukselehel.; 19 Mudel või toote tunnus: Undefined; 20 Tootja: Undefined; 21 Tooteinfo: Undefined; 22 Kasutus- ja hooldusjuhend: Undefined; 23 viide sõlmele: Undefined
AC_Pset_RenovationAndPhasing - Renovation Status: New

# IfcDoor: SU-06 800×2 100 (2)
In: 1 korrus
Type - OperationType: SINGLE_SWING_LEFT; ParameterTakesPrecedence: no; Sizeable: no
Type - Door Lining Properties - LiningDepth: 100 mm; LiningThickness: 40 mm; ThresholdDepth: 60 mm; ThresholdThickness: 5 mm; LiningOffset: 210 mm; ThresholdOffset: 250 mm
Type - Door Panel Properties - Panel 1 - PanelDepth: 40 mm; PanelOperation: SWINGING; PanelWidth: 1; PanelPosition: MIDDLE
OverallHeight: 2100 mm; OverallWidth: 800 mm; Classification: 0 TELLIJA KULUD (EHITUSKULUDE LIIGITAMINE EVS 885:2005); 1.9 IfcDoor (uks) (_RKAS BIM + ARCHICAD Classification)
Pset_DoorCommon - ThermalTransmittance: 0; GlazingAreaFraction: 0.963968; IsExternal: no
Avatäited - 01 Nimetus: Siseuks; 02 Materjal: Metallraamis klaasuks; 03 Tähistus: SU-06 800×2 100; 04 Avamõõdu geomeetria: 800×2 100; 05 Asukoha info: Interior; 06 Soojusläbivus: -; 07 Helipidavus: -; 08 Veepidavus: -; 09 Õhuläbilaskvus: -; 10 Tulekindlus: nõudeid ei esitata; 11 Vastupanu tulekoormusele: -; 12 Klaaspakett: 4+1+4 kilelaminaadiga karastatud kirgas klaas.; 13 Klaasingu erisused: Klaasi osa kaetud matistava kilega.; 14 Päikesekiirgus tegur (g-väärtus): -; 15 Avanemine: Avanemine: "R" (L - vasak; R - parem); 16 Liigendatus: -; 17 Sulused, lukustus: Link AssaAbloy Inoxi 3-19 (harjatud roostevaba viimistlusega). Lukustus vastavalt lukustusprojektile. Must liugsulgur Abloy DC700 (või samaväärne analoog), sulgur paigaldada eesruumi (ruum 142) poole. Uks varustada piirajaga (sulguri sisene). Hinged tootekesksed, viimistlus on sama, mis on ukselehel.; 18 Viimistlus: Tehaseliselt värvitud tumehalliks RAL7016 (Anthrazitgrau). Lävepakk - harjatud roostevaba terasleht t=1mm, kõrgus max 20mm. Leng - pikendatud leng, detailijoonist vt. sisearhitektuursest osast, viimistlus sama, mis ukselehel.; 19 Mudel või toote tunnus: Undefined; 20 Tootja: Undefined; 21 Tooteinfo: Undefined; 22 Kasutus- ja hooldusjuhend: Undefined; 23 viide sõlmele: Undefined
AC_Pset_RenovationAndPhasing - Renovation Status: New

# IfcDoor: SU-06 800×2 100, Siseuks * Door 22
In: 1 korrus
Type - OperationType: SINGLE_SWING_RIGHT; ParameterTakesPrecedence: no; Sizeable: no
Type - Door Lining Properties - LiningDepth: 100 mm; LiningThickness: 40 mm; ThresholdDepth: 60 mm; ThresholdThickness: 5 mm; LiningOffset: -10 mm; ThresholdOffset: 30 mm
Type - Door Panel Properties - Panel 1 - PanelDepth: 40 mm; PanelOperation: SWINGING; PanelWidth: 1; PanelPosition: MIDDLE
OverallHeight: 2100 mm; OverallWidth: 800 mm; Classification: 0 TELLIJA KULUD (EHITUSKULUDE LIIGITAMINE EVS 885:2005); 1.9 IfcDoor (uks) (_RKAS BIM + ARCHICAD Classification)
Pset_DoorCommon - ThermalTransmittance: 0; GlazingAreaFraction: 0.963968; IsExternal: no
Avatäited - 01 Nimetus: Siseuks; 02 Materjal: Metallraamis klaasuks; 03 Tähistus: SU-06 800×2 100; 04 Avamõõdu geomeetria: 800×2 100; 05 Asukoha info: Interior; 06 Soojusläbivus: -; 07 Helipidavus: -; 08 Veepidavus: -; 09 Õhuläbilaskvus: -; 10 Tulekindlus: nõudeid ei esitata; 11 Vastupanu tulekoormusele: -; 12 Klaaspakett: 4+1+4 kilelaminaadiga karastatud kirgas klaas.; 13 Klaasingu erisused: Klaasi osa kaetud matistava kilega.; 14 Päikesekiirgus tegur (g-väärtus): -; 15 Avanemine: Avanemine: "L" (L - vasak; R - parem); 16 Liigendatus: -; 17 Sulused, lukustus: Link AssaAbloy Inoxi 3-19 (harjatud roostevaba viimistlusega). Lukustus vastavalt lukustusprojektile. Must liugsulgur Abloy DC700 (või samaväärne analoog), sulgur paigaldada eesruumi (ruum 135) poole. Uks varustada piirajaga (sulguri sisene). Hinged tootekesksed, viimistlus on sama, mis on ukselehel.; 18 Viimistlus: Tehaseliselt värvitud tumehalliks RAL7016 (Anthrazitgrau). Lävepakk - harjatud roostevaba terasleht t=1mm, kõrgus max 20mm. Leng - pikendatud leng, detailijoonist vt. sisearhitektuursest osast, viimistlus sama, mis ukselehel.; 19 Mudel või toote tunnus: Undefined; 20 Tootja: Undefined; 21 Tooteinfo: Undefined; 22 Kasutus- ja hooldusjuhend: Undefined; 23 viide sõlmele: Undefined
AC_Pset_RenovationAndPhasing - Renovation Status: New

# IfcDoor: SU-06 800×2 100, Siseuks * Door 22
In: 1 korrus
Type - OperationType: SINGLE_SWING_RIGHT; ParameterTakesPrecedence: no; Sizeable: no
Type - Door Lining Properties - LiningDepth: 100 mm; LiningThickness: 40 mm; ThresholdDepth: 60 mm; ThresholdThickness: 5 mm; LiningOffset: 210 mm; ThresholdOffset: 210 mm
Type - Door Panel Properties - Panel 1 - PanelDepth: 40 mm; PanelOperation: SWINGING; PanelWidth: 1; PanelPosition: MIDDLE
OverallHeight: 2100 mm; OverallWidth: 800 mm; Classification: 0 TELLIJA KULUD (EHITUSKULUDE LIIGITAMINE EVS 885:2005); 1.9 IfcDoor (uks) (_RKAS BIM + ARCHICAD Classification)
Pset_DoorCommon - ThermalTransmittance: 0; GlazingAreaFraction: 0.963968; IsExternal: no
Avatäited - 01 Nimetus: Siseuks; 02 Materjal: Metallraamis klaasuks; 03 Tähistus: SU-06 800×2 100; 04 Avamõõdu geomeetria: 800×2 100; 05 Asukoha info: Interior; 06 Soojusläbivus: -; 07 Helipidavus: -; 08 Veepidavus: -; 09 Õhuläbilaskvus: -; 10 Tulekindlus: nõudeid ei esitata; 11 Vastupanu tulekoormusele: -; 12 Klaaspakett: 4+1+4 kilelaminaadiga karastatud kirgas klaas.; 13 Klaasingu erisused: Klaasi osa kaetud matistava kilega.; 14 Päikesekiirgus tegur (g-väärtus): -; 15 Avanemine: Avanemine: "L" (L - vasak; R - parem); 16 Liigendatus: -; 17 Sulused, lukustus: Link AssaAbloy Inoxi 3-19 (harjatud roostevaba viimistlusega). Lukustus vastavalt lukustusprojektile. Must liugsulgur Abloy DC700 (või samaväärne analoog), sulgur paigaldada eesruumi (ruum 135) poole. Uks varustada piirajaga (sulguri sisene). Hinged tootekesksed, viimistlus on sama, mis on ukselehel.; 18 Viimistlus: Tehaseliselt värvitud tumehalliks RAL7016 (Anthrazitgrau). Lävepakk - harjatud roostevaba terasleht t=1mm, kõrgus max 20mm. Leng - pikendatud leng, detailijoonist vt. sisearhitektuursest osast, viimistlus sama, mis ukselehel.; 19 Mudel või toote tunnus: Undefined; 20 Tootja: Undefined; 21 Tooteinfo: Undefined; 22 Kasutus- ja hooldusjuhend: Undefined; 23 viide sõlmele: Undefined
AC_Pset_RenovationAndPhasing - Renovation Status: New

# IfcDoor: SU-07 1 000×2 100, Siseuks * Door 22
In: 1 korrus
Type - OperationType: SINGLE_SWING_LEFT; ParameterTakesPrecedence: no; Sizeable: no
Type - Door Lining Properties - LiningDepth: 100 mm; LiningThickness: 40 mm; ThresholdDepth: 60 mm; ThresholdThickness: 5 mm; LiningOffset: -10 mm; ThresholdOffset: 30 mm
Type - Door Panel Properties - Panel 1 - PanelDepth: 40 mm; PanelOperation: SWINGING; PanelWidth: 1; PanelPosition: MIDDLE
OverallHeight: 2100 mm; OverallWidth: 1000 mm; Classification: 1.9 IfcDoor (uks) (_RKAS BIM + ARCHICAD Classification)
Pset_DoorCommon - ThermalTransmittance: 0; GlazingAreaFraction: 1.31837; IsExternal: no
Avatäited - 01 Nimetus: Siseuks; 02 Materjal: Klaas; Metall; 03 Tähistus: SU-07 1 000×2 100; 04 Avamõõdu geomeetria: 1 000×2 100; 05 Asukoha info: Interior; 06 Soojusläbivus: -; 07 Helipidavus: -; 08 Veepidavus: -; 09 Õhuläbilaskvus: -; 10 Tulekindlus: nõudeid ei esitata; 11 Vastupanu tulekoormusele: -; 12 Klaaspakett: 4+1+4 kilelaminaadiga karastatud kirgas klaas; 13 Klaasingu erisused: kirgas klaas; 14 Päikesekiirgus tegur (g-väärtus): -; 15 Avanemine: Avanemine: "R" (L - vasak; R - parem); 16 Liigendatus: -; 17 Sulused, lukustus: Link AssaAbloy Inoxi 3-19 (harjatud roostevaba viimistlusega). Lukustus vastavalt lukustusprojektile. Sulgur puudub. Hinged tootekesksed, viimistlus on sama, mis on ukselehel.; 18 Viimistlus: Tehaseliselt värvitud tumehalliks RAL7016 (Anthrazitgrau). Lävepakk - harjatud roostevaba terasleht t=1mm, kõrgus max 20mm.; 19 Mudel või toote tunnus: Undefined; 20 Tootja: Undefined; 21 Tooteinfo: Undefined; 22 Kasutus- ja hooldusjuhend: Undefined; 23 viide sõlmele: Undefined
AC_Pset_RenovationAndPhasing - Renovation Status: New

# IfcDoor: SU-08 1 800×2 500, Siseuks * Double Door 22
In: 0 korrus
Type - OperationType: DOUBLE_DOOR_SINGLE_SWING; ParameterTakesPrecedence: no; Sizeable: no
Type - Door Lining Properties - LiningDepth: 115 mm; LiningThickness: 40 mm; LiningOffset: -5 mm; CasingThickness: 50 mm; CasingDepth: 19 mm
Type - Door Panel Properties - Panel 1 - PanelDepth: 40 mm; PanelOperation: SWINGING; PanelWidth: 0.506977; PanelPosition: LEFT
Type - Door Panel Properties - Panel 2 - PanelDepth: 40 mm; PanelOperation: SWINGING; PanelWidth: 0.506977; PanelPosition: RIGHT
OverallHeight: 2500 mm; OverallWidth: 1800 mm; Classification: 0 TELLIJA KULUD (EHITUSKULUDE LIIGITAMINE EVS 885:2005); 1.9 IfcDoor (uks) (_RKAS BIM + ARCHICAD Classification)
Pset_DoorCommon - ThermalTransmittance: 0; GlazingAreaFraction: 2.91917; IsExternal: no
Avatäited - 01 Nimetus: Siseuks; 02 Materjal: Klaas; Metall; 03 Tähistus: SU-08 1 800×2 500; 04 Avamõõdu geomeetria: 1 800×2 500; 05 Asukoha info: Interior; 06 Soojusläbivus: -; 07 Helipidavus: 30dB; 08 Veepidavus: -; 09 Õhuläbilaskvus: -; 10 Tulekindlus: nõudeid ei esitata; 11 Vastupanu tulekoormusele: -; 12 Klaaspakett: 6+1+6 kilelaminaadiga karastatud kirgas klaas; 13 Klaasingu erisused: karastatud kirgas klaas; 14 Päikesekiirgus tegur (g-väärtus): -; 15 Avanemine: Avanemine: "L" (L - vasak; R - parem); 16 Liigendatus: Uks koosneb kahest ukselehest; 17 Sulused, lukustus: Link AssaAbloy Aperio (tagasi keeratud lingi otsaga). Lukustus vastavalt lukustusprojektile. Must liugsulgur Abloy DC700 (või samaväärne analoog), sulgur paigaldada auditooriumi poole. Hinged tootekesksed, viimistlus on sama, mis on ukselehel. Uks varustada taktiseadmega. Uks varustada piirajaga (sulguri sisene).; 18 Viimistlus: Tehaseliselt värvitud tumehalliks RAL7016 (Anthrazitgrau). Lävepakk - harjatud roostevaba terasleht t=1mm, kõrgus max 20mm. Leng - pikendatud leng, detailijoonist vt. sisearhitektuursest osast, viimistlus sama, mis ukselehel.; 19 Mudel või toote tunnus: Fuego Light (või samaväärne analoog); 20 Tootja: Forster (või samaväärne analoog); 21 Tooteinfo: Undefined; 22 Kasutus- ja hooldusjuhend: Undefined; 23 viide sõlmele: Undefined
AC_Pset_RenovationAndPhasing - Renovation Status: New

# IfcDoor: SU-09 700×2 100, Siseuks * Door 22
In: 1 korrus
Type - OperationType: SINGLE_SWING_RIGHT; ParameterTakesPrecedence: no; Sizeable: no
Type - Door Lining Properties - LiningDepth: 100 mm; LiningThickness: 40 mm; ThresholdDepth: 60 mm; ThresholdThickness: 5 mm; LiningOffset: -10 mm; ThresholdOffset: 30 mm
Type - Door Panel Properties - Panel 1 - PanelDepth: 40 mm; PanelOperation: SWINGING; PanelWidth: 1; PanelPosition: MIDDLE
OverallHeight: 2100 mm; OverallWidth: 700 mm; Classification: 1.9 IfcDoor (uks) (_RKAS BIM + ARCHICAD Classification)
Pset_DoorCommon - ThermalTransmittance: 0; GlazingAreaFraction: 0; IsExternal: no
Avatäited - 01 Nimetus: Siseuks; 02 Materjal: Puitlengil olev vahtolüsterooltäidisega puidust sileuks, kaetud kõrgsurvelaminaadiga Formica F7902 MAT; 03 Tähistus: SU-09 700×2 100; 04 Avamõõdu geomeetria: 700×2 100; 05 Asukoha info: Interior; 06 Soojusläbivus: -; 07 Helipidavus: -; 08 Veepidavus: -; 09 Õhuläbilaskvus: ukse all siirdeõhu pilu; 10 Tulekindlus: nõudeid ei esitata; 11 Vastupanu tulekoormusele: -; 12 Klaaspakett: -; 13 Klaasingu erisused: -; 14 Päikesekiirgus tegur (g-väärtus): -; 15 Avanemine: Avanemine: "L" (L - vasak; R - parem); 16 Liigendatus: -; 17 Sulused, lukustus: AssaAbloy Aperio (harjatud roostevaba viimistlusega). Lukustus vastavalt lukustusprojektile. Sulgur puudub. Hinged on tootekesksed, lengiga sama viimistlusega.; 18 Viimistlus: Leng värvitud halliks RAL 7044 (Seidengrau), ukseleht on kaetud kõrgsurvelaminaadiga Formica F7902 MAT. Lävepakk - harjatud roostevaba terasleht t=1mm, kõrgus max 20mm. Leng - pikendatud leng, detailijoonist vt. sisearhitektuursest osast, viimistlus sama, mis ukselehel.; 19 Mudel või toote tunnus: Undefined; 20 Tootja: Undefined; 21 Tooteinfo: Undefined; 22 Kasutus- ja hooldusjuhend: Undefined; 23 viide sõlmele: Undefined
AC_Pset_RenovationAndPhasing - Renovation Status: New

# IfcDoor: SU-09 700×2 100, Siseuks * Door 22
In: 1 korrus
Type - OperationType: SINGLE_SWING_RIGHT; ParameterTakesPrecedence: no; Sizeable: no
Type - Door Lining Properties - LiningDepth: 100 mm; LiningThickness: 40 mm; ThresholdDepth: 60 mm; ThresholdThickness: 5 mm; LiningOffset: 210 mm; ThresholdOffset: 210 mm
Type - Door Panel Properties - Panel 1 - PanelDepth: 40 mm; PanelOperation: SWINGING; PanelWidth: 1; PanelPosition: MIDDLE
OverallHeight: 2100 mm; OverallWidth: 700 mm; Classification: 1.9 IfcDoor (uks) (_RKAS BIM + ARCHICAD Classification)
Pset_DoorCommon - ThermalTransmittance: 0; GlazingAreaFraction: 0; IsExternal: no
Avatäited - 01 Nimetus: Siseuks; 02 Materjal: Puitlengil olev vahtolüsterooltäidisega puidust sileuks, kaetud kõrgsurvelaminaadiga Formica F7902 MAT; 03 Tähistus: SU-09 700×2 100; 04 Avamõõdu geomeetria: 700×2 100; 05 Asukoha info: Interior; 06 Soojusläbivus: -; 07 Helipidavus: -; 08 Veepidavus: -; 09 Õhuläbilaskvus: ukse all siirdeõhu pilu; 10 Tulekindlus: nõudeid ei esitata; 11 Vastupanu tulekoormusele: -; 12 Klaaspakett: -; 13 Klaasingu erisused: -; 14 Päikesekiirgus tegur (g-väärtus): -; 15 Avanemine: Avanemine: "L" (L - vasak; R - parem); 16 Liigendatus: -; 17 Sulused, lukustus: AssaAbloy Inoxi 3-19 (harjatud roostevaba viimistlusega). Lukustus vastavalt lukustusprojektile. Sulgur puudub. Hinged on tootekesksed, lengiga sama viimistlusega.; 18 Viimistlus: Leng värvitud halliks RAL 7044 (Seidengrau), ukseleht on kaetud kõrgsurvelaminaadiga Formica F7902 MAT; 19 Mudel või toote tunnus: Undefined; 20 Tootja: Undefined; 21 Tooteinfo: Undefined; 22 Kasutus- ja hooldusjuhend: Undefined; 23 viide sõlmele: Undefined
AC_Pset_RenovationAndPhasing - Renovation Status: New

# IfcDoor: SU-10 700×2 100 (4)
In: 1 korrus
Type - OperationType: SINGLE_SWING_LEFT; ParameterTakesPrecedence: no; Sizeable: no
Type - Door Lining Properties - LiningDepth: 100 mm; LiningThickness: 40 mm; ThresholdDepth: 60 mm; ThresholdThickness: 5 mm; LiningOffset: -10 mm; ThresholdOffset: -10 mm
Type - Door Panel Properties - Panel 1 - PanelDepth: 40 mm; PanelOperation: SWINGING; PanelWidth: 1; PanelPosition: MIDDLE
OverallHeight: 2100 mm; OverallWidth: 700 mm; Classification: 1.9 IfcDoor (uks) (_RKAS BIM + ARCHICAD Classification)
Pset_DoorCommon - ThermalTransmittance: 0; GlazingAreaFraction: 0; IsExternal: no
Avatäited - 01 Nimetus: Siseuks; 02 Materjal: Puitlengil olev vahtolüsterooltäidisega puidust sileuks, kaetud kõrgsurvelaminaadiga Formica F2297 MAT; 03 Tähistus: SU-10 700×2 100; 04 Avamõõdu geomeetria: 700×2 100; 05 Asukoha info: Interior; 06 Soojusläbivus: -; 07 Helipidavus: -; 08 Veepidavus: -; 09 Õhuläbilaskvus: ukse all siirdeõhu pilu; 10 Tulekindlus: nõudeid ei esitata; 11 Vastupanu tulekoormusele: -; 12 Klaaspakett: -; 13 Klaasingu erisused: -; 14 Päikesekiirgus tegur (g-väärtus): -; 15 Avanemine: Avanemine: "R" (L - vasak; R - parem); 16 Liigendatus: -; 17 Sulused, lukustus: AssaAbloy Inoxi 3-19 (harjatud roostevaba viimistlusega). Lukustus vastavalt lukustusprojektile, ustel on seespool Abloy 007 WC indikaatoriga lukustusnupp (mattkroomi viimistlusega). Sulgur puudub. Hinged on tootekesksed, lengiga sama viimistlusega.; 18 Viimistlus: Leng värvitud tumehalliks RAL 7016 (Anthrazitgrau), ukseleht on kaetud kõrgsurvelaminaadiga Formica F2297 MAT. Leng - pikendatud leng, detailijoonist vt. sisearhitektuursest osast.; 19 Mudel või toote tunnus: Undefined; 20 Tootja: Undefined; 21 Tooteinfo: Undefined; 22 Kasutus- ja hooldusjuhend: Undefined; 23 viide sõlmele: Undefined
AC_Pset_RenovationAndPhasing - Renovation Status: New

# IfcDoor: SU-10 700×2 100 (4)
Type - OperationType: SINGLE_SWING_LEFT; ParameterTakesPrecedence: no; Sizeable: no
Type - Door Lining Properties - LiningDepth: 100 mm; LiningThickness: 40 mm; ThresholdDepth: 60 mm; ThresholdThickness: 5 mm; LiningOffset: -10 mm; ThresholdOffset: 30 mm
Type - Door Panel Properties - Panel 1 - PanelDepth: 40 mm; PanelOperation: SWINGING; PanelWidth: 1; PanelPosition: MIDDLE
OverallHeight: 2100 mm; OverallWidth: 700 mm; Classification: 1.9 IfcDoor (uks) (_RKAS BIM + ARCHICAD Classification)
Pset_DoorCommon - ThermalTransmittance: 0; GlazingAreaFraction: 0; IsExternal: no
Avatäited - 01 Nimetus: Siseuks; 02 Materjal: Puitlengil olev vahtolüsterooltäidisega puidust sileuks, kaetud kõrgsurvelaminaadiga Formica F2297 MAT; 03 Tähistus: SU-10 700×2 100; 04 Avamõõdu geomeetria: 700×2 100; 05 Asukoha info: Interior; 06 Soojusläbivus: -; 07 Helipidavus: -; 08 Veepidavus: -; 10 Tulekindlus: nõudeid ei esitata; 11 Vastupanu tulekoormusele: -; 12 Klaaspakett: -; 13 Klaasingu erisused: -; 14 Päikesekiirgus tegur (g-väärtus): -; 15 Avanemine: Avanemine: "R" (L - vasak; R - parem); 16 Liigendatus: -; 19 Mudel või toote tunnus: Undefined; 20 Tootja: Undefined; 21 Tooteinfo: Undefined; 22 Kasutus- ja hooldusjuhend: Undefined; 23 viide sõlmele: Undefined
AC_Pset_RenovationAndPhasing - Renovation Status: New
Name | In | 09 Õhuläbilaskvus | 17 Sulused, lukustus | 18 Viimistlus
Siseuks * Door 22 | 1 korrus | ukse sisse integreeritud siirdeõhurest (toon sama, mis ukselehel) | AssaAbloy Inoxi 3-19 (harjatud roostevaba viimistlusega). Lukustus vastavalt lukustusprojektile, ustel on seespool Abloy 007 WC indikaatoriga lukustusnupp (mattkroomi viimistlusega). Sulgur puudub. Hinged on tootekesksed, lengiga sama viimistlusega. | Leng värvitud halliks RAL 7016 (Anthrazitgrau), ukseleht on kaetud kõrgsurvelaminaadiga Formica F2297 MAT. Leng - pikendatud leng, detailijoonist vt. sisearhitektuursest osast.
Siseuks * Door 22 | 1 korrus | ukse sisse integreeritud siirdeõhurest (toon sama, mis ukselehel) | AssaAbloy Inoxi 3-19 (harjatud roostevaba viimistlusega). Lukustus vastavalt lukustusprojektile. Sulgur puudub. Hinged on tootekesksed, lengiga sama viimistlusega. | Leng värvitud halliks RAL 7016 (Anthrazitgrau), ukseleht on kaetud kõrgsurvelaminaadiga Formica F2297 MAT. Leng - pikendatud leng, detailijoonist vt. sisearhitektuursest osast.
2 x Siseuks * Door 22 | 2 korrus | ukse all siirdeõhu pilu | AssaAbloy Inoxi 3-19 (harjatud roostevaba viimistlusega). Lukustus vastavalt lukustusprojektile, ustel on seespool Abloy 007 WC indikaatoriga lukustusnupp (mattkroomi viimistlusega). Sulgur puudub. Hinged on tootekesksed, lengiga sama viimistlusega. | Leng värvitud tumehalliks RAL 7016 (Anthrazitgrau), ukseleht on kaetud kõrgsurvelaminaadiga Formica F2297 MAT. Leng - pikendatud leng, detailijoonist vt. sisearhitektuursest osast.

# IfcDoor: SU-10 700×2 100, Siseuks * Door 22
In: 1,5 korrus
Type - OperationType: SINGLE_SWING_LEFT; ParameterTakesPrecedence: no; Sizeable: no
Type - Door Lining Properties - LiningDepth: 100 mm; LiningThickness: 40 mm; ThresholdDepth: 60 mm; ThresholdThickness: 5 mm; LiningOffset: 110 mm; ThresholdOffset: 110 mm
Type - Door Panel Properties - Panel 1 - PanelDepth: 40 mm; PanelOperation: SWINGING; PanelWidth: 1; PanelPosition: MIDDLE
OverallHeight: 2100 mm; OverallWidth: 700 mm; Classification: 0 TELLIJA KULUD (EHITUSKULUDE LIIGITAMINE EVS 885:2005); 1.9 IfcDoor (uks) (_RKAS BIM + ARCHICAD Classification)
Pset_DoorCommon - ThermalTransmittance: 0; GlazingAreaFraction: 0; IsExternal: no
Avatäited - 01 Nimetus: Siseuks; 02 Materjal: Puitlengil olev vahtolüsterooltäidisega puidust sileuks, kaetud kõrgsurvelaminaadiga Formica F7902 MAT; 03 Tähistus: SU-10 700×2 100; 04 Avamõõdu geomeetria: 700×2 100; 05 Asukoha info: Interior; 06 Soojusläbivus: -; 07 Helipidavus: -; 08 Veepidavus: -; 09 Õhuläbilaskvus: ukse all siirdeõhu pilu; 10 Tulekindlus: nõudeid ei esitata; 11 Vastupanu tulekoormusele: -; 12 Klaaspakett: -; 13 Klaasingu erisused: -; 14 Päikesekiirgus tegur (g-väärtus): -; 15 Avanemine: Avanemine: "R" (L - vasak; R - parem); 16 Liigendatus: -; 17 Sulused, lukustus: AssaAbloy Inoxi 3-19 (harjatud roostevaba viimistlusega). Lukustus vastavalt lukustusprojektile, uksel on seespool Abloy 007 WC indikaatoriga lukustusnupp (mattkroomi viimistlusega). Sulgur puudub. Hinged on tootekesksed, lengiga sama viimistlusega.; 18 Viimistlus: Leng värvitud halliks RAL 7044 (Seidengrau), ukseleht on kaetud kõrgsurvelaminaadiga Formica F7902 MAT; 19 Mudel või toote tunnus: Undefined; 20 Tootja: Undefined; 21 Tooteinfo: Undefined; 22 Kasutus- ja hooldusjuhend: Undefined; 23 viide sõlmele: Undefined
AC_Pset_RenovationAndPhasing - Renovation Status: New

# IfcDoor: SU-10 700×2 100, Siseuks * Door 22
In: 1 korrus
Type - OperationType: SINGLE_SWING_RIGHT; ParameterTakesPrecedence: no; Sizeable: no
Type - Door Lining Properties - LiningDepth: 100 mm; LiningThickness: 40 mm; ThresholdDepth: 60 mm; ThresholdThickness: 5 mm; LiningOffset: -10 mm; ThresholdOffset: -10 mm
Type - Door Panel Properties - Panel 1 - PanelDepth: 40 mm; PanelOperation: SWINGING; PanelWidth: 1; PanelPosition: MIDDLE
OverallHeight: 2100 mm; OverallWidth: 700 mm; Classification: 0 TELLIJA KULUD (EHITUSKULUDE LIIGITAMINE EVS 885:2005); 1.9 IfcDoor (uks) (_RKAS BIM + ARCHICAD Classification)
Pset_DoorCommon - ThermalTransmittance: 0; GlazingAreaFraction: 0; IsExternal: no
Avatäited - 01 Nimetus: Siseuks; 02 Materjal: Puitlengil olev vahtolüsterooltäidisega puidust sileuks, kaetud kõrgsurvelaminaadiga Formica F7902 MAT; 03 Tähistus: SU-10 700×2 100; 04 Avamõõdu geomeetria: 700×2 100; 05 Asukoha info: Interior; 06 Soojusläbivus: -; 07 Helipidavus: -; 08 Veepidavus: -; 09 Õhuläbilaskvus: ukse all siirdeõhu pilu; 10 Tulekindlus: nõudeid ei esitata; 11 Vastupanu tulekoormusele: -; 12 Klaaspakett: -; 13 Klaasingu erisused: -; 14 Päikesekiirgus tegur (g-väärtus): -; 15 Avanemine: Avanemine: "L" (L - vasak; R - parem); 16 Liigendatus: -; 17 Sulused, lukustus: AssaAbloy Inoxi 3-19 (harjatud roostevaba viimistlusega). Lukustus vastavalt lukustusprojektile, ustel on seespool Abloy 007 WC indikaatoriga lukustusnupp (mattkroomi viimistlusega). Sulgur puudub. Hinged on tootekesksed, lengiga sama viimistlusega.; 18 Viimistlus: Leng värvitud halliks RAL 7044 (Seidengrau), ukseleht on kaetud kõrgsurvelaminaadiga Formica F7902 MAT. Leng - pikendatud leng, detailijoonist vt. sisearhitektuursest osast.; 19 Mudel või toote tunnus: Undefined; 20 Tootja: Undefined; 21 Tooteinfo: Undefined; 22 Kasutus- ja hooldusjuhend: Undefined; 23 viide sõlmele: Undefined
AC_Pset_RenovationAndPhasing - Renovation Status: New

# IfcDoor: SU-10 700×2 100 (6)
Type - OperationType: SINGLE_SWING_RIGHT; ParameterTakesPrecedence: no; Sizeable: no
Type - Door Lining Properties - LiningDepth: 100 mm; LiningThickness: 40 mm; ThresholdDepth: 60 mm; ThresholdThickness: 5 mm; LiningOffset: -10 mm; ThresholdOffset: 30 mm
Type - Door Panel Properties - Panel 1 - PanelDepth: 40 mm; PanelOperation: SWINGING; PanelWidth: 1; PanelPosition: MIDDLE
OverallHeight: 2100 mm; OverallWidth: 700 mm; Classification: 1.9 IfcDoor (uks) (_RKAS BIM + ARCHICAD Classification)
Pset_DoorCommon - ThermalTransmittance: 0; GlazingAreaFraction: 0; IsExternal: no
Avatäited - 01 Nimetus: Siseuks; 02 Materjal: Puitlengil olev vahtolüsterooltäidisega puidust sileuks, kaetud kõrgsurvelaminaadiga Formica F2297 MAT; 03 Tähistus: SU-10 700×2 100; 04 Avamõõdu geomeetria: 700×2 100; 05 Asukoha info: Interior; 06 Soojusläbivus: -; 07 Helipidavus: -; 08 Veepidavus: -; 10 Tulekindlus: nõudeid ei esitata; 11 Vastupanu tulekoormusele: -; 12 Klaaspakett: -; 13 Klaasingu erisused: -; 14 Päikesekiirgus tegur (g-väärtus): -; 15 Avanemine: Avanemine: "L" (L - vasak; R - parem); 16 Liigendatus: -; 19 Mudel või toote tunnus: Undefined; 20 Tootja: Undefined; 21 Tooteinfo: Undefined; 22 Kasutus- ja hooldusjuhend: Undefined; 23 viide sõlmele: Undefined
AC_Pset_RenovationAndPhasing - Renovation Status: New
Name | In | 09 Õhuläbilaskvus | 17 Sulused, lukustus | 18 Viimistlus
2 x Siseuks * Door 22 | 1 korrus | ukse sisse integreeritud siirdeõhurest (toon sama, mis ukselehel) | AssaAbloy Inoxi 3-19 (harjatud roostevaba viimistlusega). Lukustus vastavalt lukustusprojektile. Sulgur puudub. Hinged on tootekesksed, lengiga sama viimistlusega. | Leng värvitud halliks RAL 7016 (Anthrazitgrau), ukseleht on kaetud kõrgsurvelaminaadiga Formica F2297 MAT. Leng - pikendatud leng, detailijoonist vt. sisearhitektuursest osast.
4 x Siseuks * Door 22 | 2 korrus | ukse all siirdeõhu pilu | AssaAbloy Inoxi 3-19 (harjatud roostevaba viimistlusega). Lukustus vastavalt lukustusprojektile, ustel on seespool Abloy 007 WC indikaatoriga lukustusnupp (mattkroomi viimistlusega). Sulgur puudub. Hinged on tootekesksed, lengiga sama viimistlusega. | Leng värvitud tumehalliks RAL 7016 (Anthrazitgrau), ukseleht on kaetud kõrgsurvelaminaadiga Formica F2297 MAT. Leng - pikendatud leng, detailijoonist vt. sisearhitektuursest osast.

# IfcDoor: SU-10 700×2 100 (5)
In: 1 korrus
Type - OperationType: SINGLE_SWING_RIGHT; ParameterTakesPrecedence: no; Sizeable: no
Type - Door Lining Properties - LiningDepth: 100 mm; LiningThickness: 40 mm; ThresholdDepth: 60 mm; ThresholdThickness: 5 mm; LiningOffset: 100 mm; ThresholdOffset: 140 mm
Type - Door Panel Properties - Panel 1 - PanelDepth: 40 mm; PanelOperation: SWINGING; PanelWidth: 1; PanelPosition: MIDDLE
OverallHeight: 2100 mm; OverallWidth: 700 mm; Classification: 1.9 IfcDoor (uks) (_RKAS BIM + ARCHICAD Classification)
Pset_DoorCommon - ThermalTransmittance: 0; GlazingAreaFraction: 0; IsExternal: no
Avatäited - 01 Nimetus: Siseuks; 02 Materjal: Puitlengil olev vahtolüsterooltäidisega puidust sileuks, kaetud kõrgsurvelaminaadiga Formica F2297 MAT; 03 Tähistus: SU-10 700×2 100; 04 Avamõõdu geomeetria: 700×2 100; 05 Asukoha info: Interior; 06 Soojusläbivus: -; 07 Helipidavus: -; 08 Veepidavus: -; 09 Õhuläbilaskvus: ukse all siirdeõhu pilu; 10 Tulekindlus: nõudeid ei esitata; 11 Vastupanu tulekoormusele: -; 12 Klaaspakett: -; 13 Klaasingu erisused: -; 14 Päikesekiirgus tegur (g-väärtus): -; 15 Avanemine: Avanemine: "L" (L - vasak; R - parem); 16 Liigendatus: -; 17 Sulused, lukustus: AssaAbloy Inoxi 3-19 (harjatud roostevaba viimistlusega). Lukustus vastavalt lukustusprojektile, ustel on seespool Abloy 007 WC indikaatoriga lukustusnupp (mattkroomi viimistlusega). Sulgur puudub. Hinged on tootekesksed, lengiga sama viimistlusega.; 18 Viimistlus: Leng värvitud tumehalliks RAL 7016 (Anthrazitgrau), ukseleht on kaetud kõrgsurvelaminaadiga Formica F2297 MAT. Leng - pikendatud leng, detailijoonist vt. sisearhitektuursest osast.; 19 Mudel või toote tunnus: Undefined; 20 Tootja: Undefined; 21 Tooteinfo: Undefined; 22 Kasutus- ja hooldusjuhend: Undefined; 23 viide sõlmele: Undefined
AC_Pset_RenovationAndPhasing - Renovation Status: New

# IfcDoor: SU-10 700×2 100, Siseuks * Door 22
In: 1,5 korrus
Type - OperationType: SINGLE_SWING_RIGHT; ParameterTakesPrecedence: no; Sizeable: no
Type - Door Lining Properties - LiningDepth: 100 mm; LiningThickness: 40 mm; ThresholdDepth: 60 mm; ThresholdThickness: 5 mm; LiningOffset: 110 mm; ThresholdOffset: 150 mm
Type - Door Panel Properties - Panel 1 - PanelDepth: 40 mm; PanelOperation: SWINGING; PanelWidth: 1; PanelPosition: MIDDLE
OverallHeight: 2100 mm; OverallWidth: 700 mm; Classification: 0 TELLIJA KULUD (EHITUSKULUDE LIIGITAMINE EVS 885:2005); 1.9 IfcDoor (uks) (_RKAS BIM + ARCHICAD Classification)
Pset_DoorCommon - ThermalTransmittance: 0; GlazingAreaFraction: 0; IsExternal: no
Avatäited - 01 Nimetus: Siseuks; 02 Materjal: Puitlengil olev vahtolüsterooltäidisega puidust sileuks, kaetud kõrgsurvelaminaadiga Formica F7902 MAT; 03 Tähistus: SU-10 700×2 100; 04 Avamõõdu geomeetria: 700×2 100; 05 Asukoha info: Interior; 06 Soojusläbivus: -; 07 Helipidavus: -; 08 Veepidavus: -; 09 Õhuläbilaskvus: ukse all siirdeõhu pilu; 10 Tulekindlus: nõudeid ei esitata; 11 Vastupanu tulekoormusele: -; 12 Klaaspakett: -; 13 Klaasingu erisused: -; 14 Päikesekiirgus tegur (g-väärtus): -; 15 Avanemine: Avanemine: "L" (L - vasak; R - parem); 16 Liigendatus: -; 17 Sulused, lukustus: AssaAbloy Inoxi 3-19 (harjatud roostevaba viimistlusega). Lukustus vastavalt lukustusprojektile, uksel on seespool Abloy 007 WC indikaatoriga lukustusnupp (mattkroomi viimistlusega). Sulgur puudub. Hinged on tootekesksed, lengiga sama viimistlusega.; 18 Viimistlus: Leng värvitud halliks RAL 7044 (Seidengrau), ukseleht on kaetud kõrgsurvelaminaadiga Formica F7902 MAT; 19 Mudel või toote tunnus: Undefined; 20 Tootja: Undefined; 21 Tooteinfo: Undefined; 22 Kasutus- ja hooldusjuhend: Undefined; 23 viide sõlmele: Undefined
AC_Pset_RenovationAndPhasing - Renovation Status: New

# IfcDoor: SU-11 1 000×2 100, Siseuks * Door 22
In: 1 korrus
Type - OperationType: SINGLE_SWING_LEFT; ParameterTakesPrecedence: no; Sizeable: no
Type - Door Lining Properties - LiningDepth: 100 mm; LiningThickness: 40 mm; ThresholdDepth: 60 mm; ThresholdThickness: 5 mm; LiningOffset: 110 mm; ThresholdOffset: 150 mm
Type - Door Panel Properties - Panel 1 - PanelDepth: 40 mm; PanelOperation: SWINGING; PanelWidth: 1; PanelPosition: MIDDLE
OverallHeight: 2100 mm; OverallWidth: 1000 mm; Classification: 1.9 IfcDoor (uks) (_RKAS BIM + ARCHICAD Classification)
Pset_DoorCommon - ThermalTransmittance: 0; GlazingAreaFraction: 0; IsExternal: no
Avatäited - 01 Nimetus: Siseuks; 02 Materjal: Puitlengil olev vahtolüsterooltäidisega puidust sileuks, kaetud kõrgsurvelaminaadiga Formica F2297 MAT; 03 Tähistus: SU-11 1 000×2 100; 04 Avamõõdu geomeetria: 1 000×2 100; 05 Asukoha info: Interior; 06 Soojusläbivus: -; 07 Helipidavus: -; 08 Veepidavus: -; 09 Õhuläbilaskvus: ukse all siirdeõhu pilu; 10 Tulekindlus: nõudeid ei esitata; 11 Vastupanu tulekoormusele: -; 12 Klaaspakett: -; 13 Klaasingu erisused: -; 14 Päikesekiirgus tegur (g-väärtus): -; 15 Avanemine: Avanemine: "R" (L - vasak; R - parem); 16 Liigendatus: -; 17 Sulused, lukustus: AssaAbloy Inoxi 3-19 (harjatud roostevaba viimistlusega). Lukustus seestpoolt lingiga. Sulgur puudub. Hinged on tootekesksed, lengiga sama viimistlusega.; 18 Viimistlus: Leng värvitud tumehalliks RAL 7016 (Anthrazitgrau), ukseleht on kaetud kõrgsurvelaminaadiga Formica F2297 MAT. Leng - pikendatud leng, detailijoonist vt. sisearhitektuursest osast.; 19 Mudel või toote tunnus: Undefined; 20 Tootja: Undefined; 21 Tooteinfo: Undefined; 22 Kasutus- ja hooldusjuhend: Undefined; 23 viide sõlmele: Undefined
AC_Pset_RenovationAndPhasing - Renovation Status: New

# IfcDoor: SU-12 700×2 400, Siseuks * Door 22
In: 2 korrus
Type - OperationType: SINGLE_SWING_RIGHT; ParameterTakesPrecedence: no; Sizeable: no
Type - Door Lining Properties - LiningDepth: 100 mm; LiningThickness: 40 mm; ThresholdDepth: 60 mm; ThresholdThickness: 5 mm; LiningOffset: -10 mm; ThresholdOffset: -10 mm
Type - Door Panel Properties - Panel 1 - PanelDepth: 40 mm; PanelOperation: SWINGING; PanelWidth: 1; PanelPosition: MIDDLE
OverallHeight: 2400 mm; OverallWidth: 700 mm; Classification: 1.9 IfcDoor (uks) (_RKAS BIM + ARCHICAD Classification)
Pset_DoorCommon - ThermalTransmittance: 0; GlazingAreaFraction: 0; IsExternal: no
Avatäited - 01 Nimetus: Siseuks; 02 Materjal: Metall; 03 Tähistus: SU-12 700×2 400; 04 Avamõõdu geomeetria: 700×2 400; 05 Asukoha info: Interior; 06 Soojusläbivus: -; 07 Helipidavus: -; 08 Veepidavus: -; 09 Õhuläbilaskvus: -; 10 Tulekindlus: EI 30; 11 Vastupanu tulekoormusele: -; 12 Klaaspakett: -; 13 Klaasingu erisused: -; 14 Päikesekiirgus tegur (g-väärtus): -; 15 Avanemine: Avanemine: "L" (L - vasak; R - parem); 16 Liigendatus: -; 17 Sulused, lukustus: link AssaAbloy Aperio (tagasi keeratud lingi otsaga). Lukustus vastavalt lukustusprojektile. Käärvarrega sulgur, sulgur paigaldada kilbiruumi poole. Hinged tootekesksed, viimistlus on sama, mis on ukslehel.; 18 Viimistlus: Tehaseliselt värvitud tumehalliks RAL7016 (Anthrazitgrau). Lävepakk - harjatud roostevaba terasleht t=1mm, kõrgus max 20mm. Leng - pikendatud leng, detailijoonist vt. sisearhitektuursest osast, viimistlus sama, mis ukselehel.; 19 Mudel või toote tunnus: Undefined; 20 Tootja: Undefined; 21 Tooteinfo: Undefined; 22 Kasutus- ja hooldusjuhend: Undefined; 23 viide sõlmele: Undefined
AC_Pset_RenovationAndPhasing - Renovation Status: New

# IfcDoor: SU-12 700×2 400, Siseuks * Door 22
In: 2 korrus
Type - OperationType: SINGLE_SWING_RIGHT; ParameterTakesPrecedence: no; Sizeable: no
Type - Door Lining Properties - LiningDepth: 100 mm; LiningThickness: 40 mm; ThresholdDepth: 60 mm; ThresholdThickness: 5 mm; LiningOffset: 160 mm; ThresholdOffset: 200 mm
Type - Door Panel Properties - Panel 1 - PanelDepth: 40 mm; PanelOperation: SWINGING; PanelWidth: 1; PanelPosition: MIDDLE
OverallHeight: 2400 mm; OverallWidth: 700 mm; Classification: 0 TELLIJA KULUD (EHITUSKULUDE LIIGITAMINE EVS 885:2005); 1.9 IfcDoor (uks) (_RKAS BIM + ARCHICAD Classification)
Pset_DoorCommon - ThermalTransmittance: 0; GlazingAreaFraction: 0; IsExternal: no
Avatäited - 01 Nimetus: Siseuks; 02 Materjal: Metall; 03 Tähistus: SU-12 700×2 400; 04 Avamõõdu geomeetria: 700×2 400; 05 Asukoha info: Interior; 06 Soojusläbivus: -; 07 Helipidavus: -; 08 Veepidavus: -; 09 Õhuläbilaskvus: ukse all siirdeõhu pilu; 10 Tulekindlus: nõudeid ei esitata; 11 Vastupanu tulekoormusele: -; 12 Klaaspakett: -; 13 Klaasingu erisused: -; 14 Päikesekiirgus tegur (g-väärtus): -; 15 Avanemine: Avanemine: "L" (L - vasak; R - parem); 16 Liigendatus: -; 17 Sulused, lukustus: Link AssaAbloy Aperio (tagasi keeratud lingi otsaga)- Lukustus vastavalt lukustusprojektile. Sulgur puudub. Hinged tootekesksed, viimistlus on sama, mis on ukselehel.; 18 Viimistlus: Tehaseliselt värvitud tumehalliks RAL7016 (Anthrazitgrau). Lävepakk - harjatud roostevaba terasleht t=1mm, kõrgus max 20mm. Leng - pikendatud leng, detailijoonist vt. sisearhitektuursest osast, viimistlus sama, mis ukselehel.; 19 Mudel või toote tunnus: Undefined; 20 Tootja: Undefined; 21 Tooteinfo: Undefined; 22 Kasutus- ja hooldusjuhend: Undefined; 23 viide sõlmele: Undefined
AC_Pset_RenovationAndPhasing - Renovation Status: New

# IfcDoor: SU-12 700×2 400, Siseuks * Door 22
In: 2 korrus
Type - OperationType: SINGLE_SWING_RIGHT; ParameterTakesPrecedence: no; Sizeable: no
Type - Door Lining Properties - LiningDepth: 100 mm; LiningThickness: 40 mm; ThresholdDepth: 60 mm; ThresholdThickness: 5 mm; LiningOffset: 210 mm; ThresholdOffset: 210 mm
Type - Door Panel Properties - Panel 1 - PanelDepth: 40 mm; PanelOperation: SWINGING; PanelWidth: 1; PanelPosition: MIDDLE
OverallHeight: 2400 mm; OverallWidth: 700 mm; Classification: 1.9 IfcDoor (uks) (_RKAS BIM + ARCHICAD Classification)
Pset_DoorCommon - ThermalTransmittance: 0; GlazingAreaFraction: 0; IsExternal: no
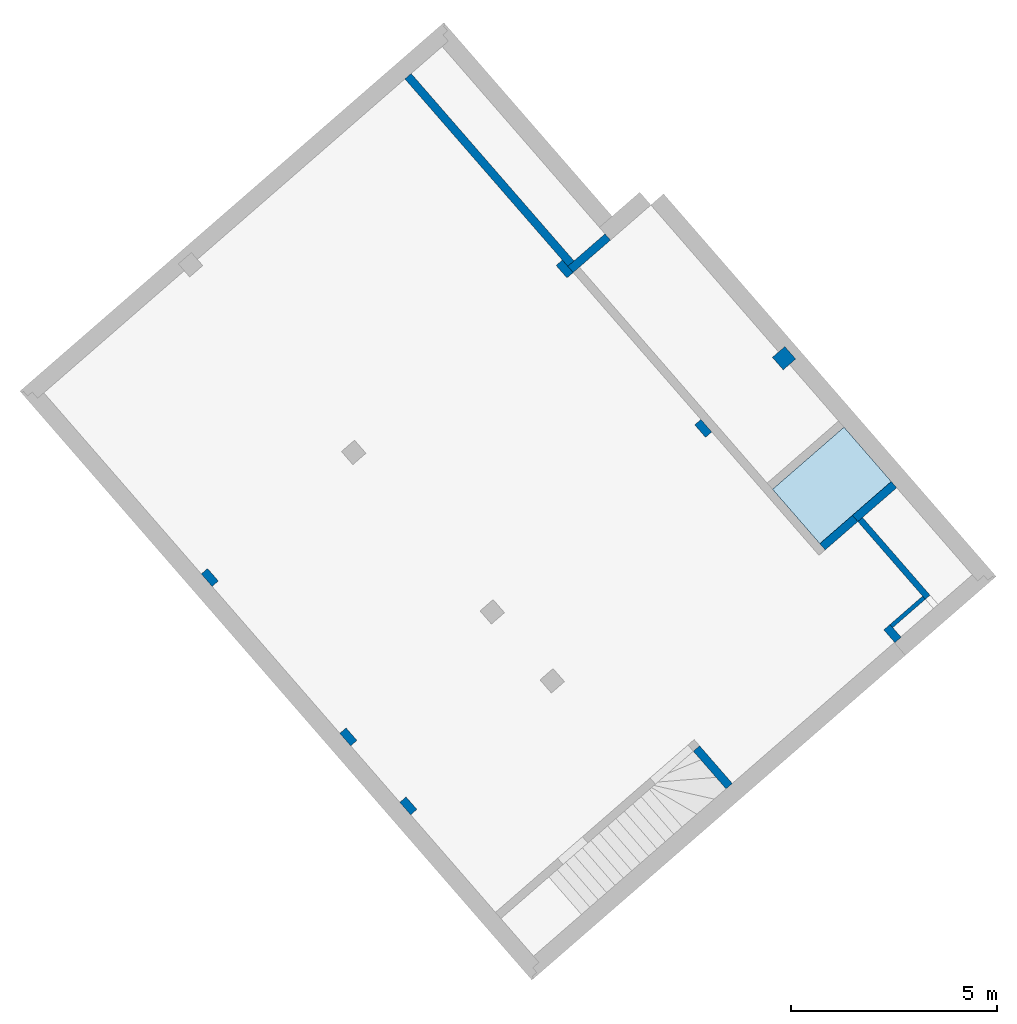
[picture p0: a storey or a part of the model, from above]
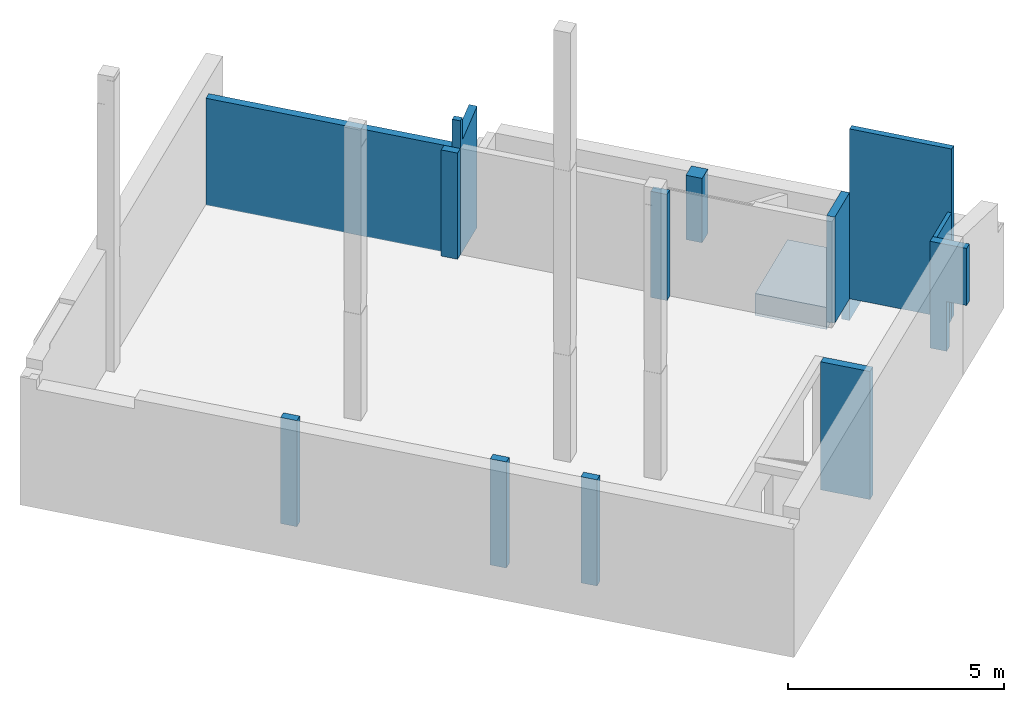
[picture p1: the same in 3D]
Properties of the parts of a building model (IFC2X3), part 6 of 13

# IfcDoor: SU-12 700×2 400, Siseuks * Door 22
Avatäited - 01 Nimetus: Siseuks; 02 Materjal: Metall; 03 Tähistus: SU-12 700×2 400; 04 Avamõõdu geomeetria: 700×2 400; 05 Asukoha info: Interior; 06 Soojusläbivus: -; 07 Helipidavus: -; 08 Veepidavus: -; 09 Õhuläbilaskvus: -; 10 Tulekindlus: EI 30; 11 Vastupanu tulekoormusele: -; 12 Klaaspakett: -; 13 Klaasingu erisused: -; 14 Päikesekiirgus tegur (g-väärtus): -; 15 Avanemine: Avanemine: "L" (L - vasak; R - parem); 16 Liigendatus: -; 17 Sulused, lukustus: link AssaAbloy Aperio. Lukustus vastavalt lukustusprojektile. Käärvarrega sulgur, sulgur paigaldada kilbiruumi poole. Hinged tootekesksed, viimistlus on sama, mis on ukslehel.; 18 Viimistlus: Tehaseliselt värvitud tumehalliks RAL7016 (Anthrazitgrau). Lävepakk - harjatud roostevaba terasleht t=1mm, kõrgus max 20mm. Leng - pikendatud leng, detailijoonist vt. sisearhitektuursest osast, viimistlus sama, mis ukselehel.; 19 Mudel või toote tunnus: Undefined; 20 Tootja: Undefined; 21 Tooteinfo: Undefined; 22 Kasutus- ja hooldusjuhend: Undefined; 23 viide sõlmele: Undefined
AC_Pset_RenovationAndPhasing - Renovation Status: New

# IfcDoor: SU-13 900×2 280 (2)
Type - OperationType: SINGLE_SWING_RIGHT; ParameterTakesPrecedence: no; Sizeable: no
Type - Door Lining Properties - LiningDepth: 100 mm; LiningThickness: 40 mm; ThresholdDepth: 60 mm; ThresholdThickness: 5 mm; LiningOffset: 210 mm; ThresholdOffset: 250 mm
Type - Door Panel Properties - Panel 1 - PanelDepth: 40 mm; PanelOperation: SWINGING; PanelWidth: 1; PanelPosition: MIDDLE
OverallHeight: 2280 mm; OverallWidth: 900 mm; Classification: 1.9 IfcDoor (uks) (_RKAS BIM + ARCHICAD Classification)
Pset_DoorCommon - ThermalTransmittance: 0; GlazingAreaFraction: 0; IsExternal: no
Avatäited - 01 Nimetus: Siseuks; 02 Materjal: Metall; 03 Tähistus: SU-13 900×2 280; 04 Avamõõdu geomeetria: 900×2 280; 05 Asukoha info: Interior; 06 Soojusläbivus: -; 07 Helipidavus: -; 08 Veepidavus: -; 09 Õhuläbilaskvus: ukse all siirdeõhu pilu; 10 Tulekindlus: nõudeid ei esitata; 11 Vastupanu tulekoormusele: -; 12 Klaaspakett: -; 13 Klaasingu erisused: -; 14 Päikesekiirgus tegur (g-väärtus): -; 15 Avanemine: Avanemine: "L" (L - vasak; R - parem); 16 Liigendatus: -; 18 Viimistlus: Tehaseliselt värvitud helehalliks RAL7044 (Seidengrau). Lävepakk - harjatud roostevaba terasleht t=1mm, kõrgus max 20mm. Leng - pikendatud leng, detailijoonist vt. sisearhitektuursest osast, viimistlus sama, mis ukselehel.; 19 Mudel või toote tunnus: Undefined; 20 Tootja: Undefined; 21 Tooteinfo: Undefined; 22 Kasutus- ja hooldusjuhend: Undefined; 23 viide sõlmele: Undefined
AC_Pset_RenovationAndPhasing - Renovation Status: New
Name | In | 17 Sulused, lukustus
Siseuks * Door 22 | 1,5 korrus | Link AssaAbloy Aperio (tagasi keeratud lingi otsaga). Lukustus vastavalt lukustusprojektile. Hinged tootekesksed, viimistlus on sama, mis on ukselehel.
Siseuks * Door 22 | 2 korrus | Link AssaAbloy Aperio (tagasi keeratud lingi otsaga). Lukustus vastavalt lukustusprojektile. Sulgur puudub. Hinged tootekesksed, viimistlus on sama, mis on ukselehel.

# IfcDoor: SU-14 900×2 100, Siseuks * Door 22
In: 1,5 korrus
Type - OperationType: SINGLE_SWING_LEFT; ParameterTakesPrecedence: no; Sizeable: no
Type - Door Lining Properties - LiningDepth: 100 mm; LiningThickness: 40 mm; ThresholdDepth: 60 mm; ThresholdThickness: 5 mm; LiningOffset: 110 mm; ThresholdOffset: 150 mm
Type - Door Panel Properties - Panel 1 - PanelDepth: 40 mm; PanelOperation: SWINGING; PanelWidth: 1; PanelPosition: MIDDLE
OverallHeight: 2100 mm; OverallWidth: 900 mm; Classification: 0 TELLIJA KULUD (EHITUSKULUDE LIIGITAMINE EVS 885:2005); 1.9 IfcDoor (uks) (_RKAS BIM + ARCHICAD Classification)
Pset_DoorCommon - ThermalTransmittance: 0; GlazingAreaFraction: 0; IsExternal: no
Avatäited - 01 Nimetus: Siseuks; 02 Materjal: Metall; 03 Tähistus: SU-14 900×2 100; 04 Avamõõdu geomeetria: 900×2 100; 05 Asukoha info: Interior; 06 Soojusläbivus: -; 07 Helipidavus: -; 08 Veepidavus: -; 09 Õhuläbilaskvus: -; 10 Tulekindlus: nõudeid ei esitata; 11 Vastupanu tulekoormusele: -; 12 Klaaspakett: -; 13 Klaasingu erisused: -; 14 Päikesekiirgus tegur (g-väärtus): -; 15 Avanemine: Avanemine: "R" (L - vasak; R - parem); 16 Liigendatus: -; 17 Sulused, lukustus: AssaAbloy Inoxi 3-19 (harjatud roostevaba viimistlusega). Lukustus vastavalt lukustusprojektile. Sulgur puudub. Hinged on tootekesksed, lengiga sama viimistlusega.; 18 Viimistlus: Tehaseliselt värvitud tumehalliks RAL7016 (Anthrazitgrau). Lävepakk - harjatud roostevaba terasleht t=1mm, kõrgus max 20mm.; 19 Mudel või toote tunnus: Undefined; 20 Tootja: Undefined; 21 Tooteinfo: Undefined; 22 Kasutus- ja hooldusjuhend: Undefined; 23 viide sõlmele: Undefined
AC_Pset_RenovationAndPhasing - Renovation Status: New

# IfcDoor: SU-14 900×2 100, Siseuks * Door 22
In: 1,5 korrus
Type - OperationType: SINGLE_SWING_LEFT; ParameterTakesPrecedence: no; Sizeable: no
Type - Door Lining Properties - LiningDepth: 100 mm; LiningThickness: 40 mm; ThresholdDepth: 60 mm; ThresholdThickness: 5 mm; LiningOffset: 210 mm; ThresholdOffset: 210 mm
Type - Door Panel Properties - Panel 1 - PanelDepth: 40 mm; PanelOperation: SWINGING; PanelWidth: 1; PanelPosition: MIDDLE
OverallHeight: 2100 mm; OverallWidth: 900 mm; Classification: 1.9 IfcDoor (uks) (_RKAS BIM + ARCHICAD Classification)
Pset_DoorCommon - ThermalTransmittance: 0; GlazingAreaFraction: 0; IsExternal: no
Avatäited - 01 Nimetus: Siseuks; 02 Materjal: Metall; 03 Tähistus: SU-14 900×2 100; 04 Avamõõdu geomeetria: 900×2 100; 05 Asukoha info: Interior; 06 Soojusläbivus: -; 07 Helipidavus: 30dB; 08 Veepidavus: -; 09 Õhuläbilaskvus: -; 10 Tulekindlus: EI 30; 11 Vastupanu tulekoormusele: -; 12 Klaaspakett: -; 13 Klaasingu erisused: -; 14 Päikesekiirgus tegur (g-väärtus): -; 15 Avanemine: Avanemine: "R" (L - vasak; R - parem); 16 Liigendatus: -; 17 Sulused, lukustus: AssaAbloy Inoxi 3-19 (harjatud roostevaba viimistlusega). Lukustus vastavalt lukustusprojektile, ustel on seespool Abloy 007 WC indikaatoriga lukustusnupp (mattkroomi viimistlusega). Must liugsulgur Abloy DC700 (või samaväärne analoog), sulgur paigaldada WC poole.; 18 Viimistlus: Tehaseliselt värvitud tumehalliks RAL7016 (Anthrazitgrau). Lävepakk - harjatud roostevaba terasleht t=1mm, kõrgus max 20mm. Leng - pikendatud leng, detailijoonist vt. sisearhitektuursest osast, viimistlus sama, mis ukselehel.; 19 Mudel või toote tunnus: Undefined; 20 Tootja: Undefined; 21 Tooteinfo: Undefined; 22 Kasutus- ja hooldusjuhend: Undefined; 23 viide sõlmele: Undefined
AC_Pset_RenovationAndPhasing - Renovation Status: New

# IfcDoor: SU-14 900×2 100, Siseuks * Door 22
In: 1 korrus
Type - OperationType: SINGLE_SWING_RIGHT; ParameterTakesPrecedence: no; Sizeable: no
Type - Door Lining Properties - LiningDepth: 100 mm; LiningThickness: 40 mm; ThresholdDepth: 60 mm; ThresholdThickness: 5 mm; LiningOffset: -10 mm; ThresholdOffset: -10 mm
Type - Door Panel Properties - Panel 1 - PanelDepth: 40 mm; PanelOperation: SWINGING; PanelWidth: 1; PanelPosition: MIDDLE
OverallHeight: 2100 mm; OverallWidth: 900 mm; Classification: 1.9 IfcDoor (uks) (_RKAS BIM + ARCHICAD Classification)
Pset_DoorCommon - ThermalTransmittance: 0; GlazingAreaFraction: 0; IsExternal: no
Avatäited - 01 Nimetus: Siseuks; 02 Materjal: Metall; 03 Tähistus: SU-14 900×2 100; 04 Avamõõdu geomeetria: 900×2 100; 05 Asukoha info: Interior; 06 Soojusläbivus: -; 07 Helipidavus: -; 08 Veepidavus: -; 09 Õhuläbilaskvus: ukse all siirdeõhu pilu; 10 Tulekindlus: nõudeid ei esitata; 11 Vastupanu tulekoormusele: -; 12 Klaaspakett: -; 13 Klaasingu erisused: -; 14 Päikesekiirgus tegur (g-väärtus): -; 15 Avanemine: Avanemine: "L" (L - vasak; R - parem); 16 Liigendatus: -; 17 Sulused, lukustus: AssaAbloy Inoxi 3-19 (harjatud roostevaba viimistlusega). Lukustus vastavalt lukustusprojektile. Sulgur puudub. Hinged tootekesksed, viimistlus on sama, mis on ukselehel.; 18 Viimistlus: Tehaseliselt värvitud tumehalliks RAL7044 (Seidengrau). Lävepakk - harjatud roostevaba terasleht t=1mm, kõrgus max 20mm. Leng - pikendatud leng, detailijoonist vt. sisearhitektuursest osast, viimistlus sama, mis ukselehel.; 19 Mudel või toote tunnus: Undefined; 20 Tootja: Undefined; 21 Tooteinfo: Undefined; 22 Kasutus- ja hooldusjuhend: Undefined; 23 viide sõlmele: Undefined
AC_Pset_RenovationAndPhasing - Renovation Status: New

# IfcDoor: SU-14 900×2 100, Siseuks * Door 22
In: 1 korrus
Type - OperationType: SINGLE_SWING_RIGHT; ParameterTakesPrecedence: no; Sizeable: no
Type - Door Lining Properties - LiningDepth: 100 mm; LiningThickness: 40 mm; ThresholdDepth: 60 mm; ThresholdThickness: 5 mm; LiningOffset: -10 mm; ThresholdOffset: 30 mm
Type - Door Panel Properties - Panel 1 - PanelDepth: 40 mm; PanelOperation: SWINGING; PanelWidth: 1; PanelPosition: MIDDLE
OverallHeight: 2100 mm; OverallWidth: 900 mm; Classification: 0 TELLIJA KULUD (EHITUSKULUDE LIIGITAMINE EVS 885:2005); 1.9 IfcDoor (uks) (_RKAS BIM + ARCHICAD Classification)
Pset_DoorCommon - ThermalTransmittance: 0; GlazingAreaFraction: 0; IsExternal: no
Avatäited - 01 Nimetus: Siseuks; 02 Materjal: Klaas; Metall; 03 Tähistus: SU-14 900×2 100; 04 Avamõõdu geomeetria: 900×2 100; 05 Asukoha info: Interior; 06 Soojusläbivus: -; 07 Helipidavus: -; 08 Veepidavus: -; 09 Õhuläbilaskvus: -; 10 Tulekindlus: nõudeid ei esitata; 11 Vastupanu tulekoormusele: -; 12 Klaaspakett: -; 13 Klaasingu erisused: -; 14 Päikesekiirgus tegur (g-väärtus): -; 15 Avanemine: Avanemine: "L" (L - vasak; R - parem); 16 Liigendatus: -; 17 Sulused, lukustus: Link AssaAbloy Aperio (tagasi keeratud lingi otsaga). Lukustus vastavalt lukustusprojektile. Sulgur puudub. Hinged tootekesksed, viimistlus on sama, mis on ukselehel.; 18 Viimistlus: Tehaseliselt värvitud tumehalliks RAL7016 (Anthrazitgrau). Lävepakk - harjatud roostevaba terasleht t=1mm, kõrgus max 20mm. Leng - pikendatud leng, detailijoonist vt. sisearhitektuursest osast, viimistlus sama, mis ukselehel.; 19 Mudel või toote tunnus: Undefined; 20 Tootja: Undefined; 21 Tooteinfo: Undefined; 22 Kasutus- ja hooldusjuhend: Undefined; 23 viide sõlmele: Undefined
AC_Pset_RenovationAndPhasing - Renovation Status: New

# IfcDoor: SU-14 900×2 100, Siseuks * Door 22
In: 1,5 korrus
Type - OperationType: SINGLE_SWING_RIGHT; ParameterTakesPrecedence: no; Sizeable: no
Type - Door Lining Properties - LiningDepth: 100 mm; LiningThickness: 40 mm; ThresholdDepth: 60 mm; ThresholdThickness: 5 mm; LiningOffset: 110 mm; ThresholdOffset: 110 mm
Type - Door Panel Properties - Panel 1 - PanelDepth: 40 mm; PanelOperation: SWINGING; PanelWidth: 1; PanelPosition: MIDDLE
OverallHeight: 2100 mm; OverallWidth: 900 mm; Classification: 1.9 IfcDoor (uks) (_RKAS BIM + ARCHICAD Classification)
Pset_DoorCommon - ThermalTransmittance: 0; GlazingAreaFraction: 0; IsExternal: no
Avatäited - 01 Nimetus: Siseuks; 02 Materjal: Metall; 03 Tähistus: SU-14 900×2 100; 04 Avamõõdu geomeetria: 900×2 100; 05 Asukoha info: Interior; 06 Soojusläbivus: -; 07 Helipidavus: -; 08 Veepidavus: -; 09 Õhuläbilaskvus: ukse all siirdeõhu pilu; 10 Tulekindlus: nõudeid ei esitata; 11 Vastupanu tulekoormusele: -; 12 Klaaspakett: -; 13 Klaasingu erisused: -; 14 Päikesekiirgus tegur (g-väärtus): -; 15 Avanemine: Avanemine: "L" (L - vasak; R - parem); 16 Liigendatus: -; 17 Sulused, lukustus: AssaAbloy Inoxi 3-19 (harjatud roostevaba viimistlusega). Lukustus vastavalt lukustusprojektile. Sulgur puudub. Hinged on tootekesksed, lengiga sama viimistlusega.; 18 Viimistlus: Tehaseliselt värvitud tumehalliks RAL7016 (Anthrazitgrau). Lävepakk - harjatud roostevaba terasleht t=1mm, kõrgus max 20mm.; 19 Mudel või toote tunnus: Undefined; 20 Tootja: Undefined; 21 Tooteinfo: Undefined; 22 Kasutus- ja hooldusjuhend: Undefined; 23 viide sõlmele: Undefined
AC_Pset_RenovationAndPhasing - Renovation Status: New

# IfcDoor: SU-15 900×2 400, Siseuks * Door 22
In: 0 korrus
Type - OperationType: SINGLE_SWING_LEFT; ParameterTakesPrecedence: no; Sizeable: no
Type - Door Lining Properties - LiningDepth: 100 mm; LiningThickness: 40 mm; ThresholdDepth: 60 mm; ThresholdThickness: 5 mm; LiningOffset: 210 mm; ThresholdOffset: 250 mm
Type - Door Panel Properties - Panel 1 - PanelDepth: 40 mm; PanelOperation: SWINGING; PanelWidth: 1; PanelPosition: MIDDLE
OverallHeight: 2400 mm; OverallWidth: 900 mm; Classification: 1.9 IfcDoor (uks) (_RKAS BIM + ARCHICAD Classification)
Pset_DoorCommon - ThermalTransmittance: 0; GlazingAreaFraction: 0; IsExternal: no
Avatäited - 01 Nimetus: Siseuks; 02 Materjal: Metall; 03 Tähistus: SU-15 900×2 400; 04 Avamõõdu geomeetria: 900×2 400; 05 Asukoha info: Interior; 06 Soojusläbivus: -; 07 Helipidavus: -; 08 Veepidavus: -; 09 Õhuläbilaskvus: ukse all siirdeõhu pilu; 10 Tulekindlus: nõudeid ei esitata; 11 Vastupanu tulekoormusele: -; 12 Klaaspakett: -; 13 Klaasingu erisused: -; 14 Päikesekiirgus tegur (g-väärtus): -; 15 Avanemine: Avanemine: "R" (L - vasak; R - parem); 16 Liigendatus: -; 17 Sulused, lukustus: Link AssaAbloy Inoxi 3-19 (harjatud roostevaba viimistlusega). Lukustus vastavalt lukustusprojektile. Sulgur puudub. Hinged tootekesksed, viimistlus on sama, mis on ukselehel.; 18 Viimistlus: Tehaseliselt värvitud tumehalliks RAL7016 (Anthrazitgrau). Lävepakk - harjatud roostevaba terasleht t=1mm, kõrgus max 20mm. Leng - pikendatud leng, detailijoonist vt. sisearhitektuursest osast, viimistlus sama, mis ukselehel.; 19 Mudel või toote tunnus: Undefined; 20 Tootja: Undefined; 21 Tooteinfo: Undefined; 22 Kasutus- ja hooldusjuhend: Undefined; 23 viide sõlmele: Undefined
AC_Pset_RenovationAndPhasing - Renovation Status: New

# IfcDoor: SU-15 900×2 400, Siseuks * Door 22
In: 0 korrus
Type - OperationType: SINGLE_SWING_RIGHT; ParameterTakesPrecedence: no; Sizeable: no
Type - Door Lining Properties - LiningDepth: 100 mm; LiningThickness: 40 mm; ThresholdDepth: 60 mm; ThresholdThickness: 5 mm; LiningOffset: 210 mm; ThresholdOffset: 250 mm
Type - Door Panel Properties - Panel 1 - PanelDepth: 40 mm; PanelOperation: SWINGING; PanelWidth: 1; PanelPosition: MIDDLE
OverallHeight: 2400 mm; OverallWidth: 900 mm; Classification: 0 TELLIJA KULUD (EHITUSKULUDE LIIGITAMINE EVS 885:2005); 1.9 IfcDoor (uks) (_RKAS BIM + ARCHICAD Classification)
Pset_DoorCommon - ThermalTransmittance: 0; GlazingAreaFraction: 0; IsExternal: no
Avatäited - 01 Nimetus: Siseuks; 02 Materjal: Metall; 03 Tähistus: SU-15 900×2 400; 04 Avamõõdu geomeetria: 900×2 400; 05 Asukoha info: Interior; 06 Soojusläbivus: -; 07 Helipidavus: -; 08 Veepidavus: -; 09 Õhuläbilaskvus: -; 10 Tulekindlus: nõudeid ei esitata; 11 Vastupanu tulekoormusele: -; 12 Klaaspakett: -; 13 Klaasingu erisused: -; 14 Päikesekiirgus tegur (g-väärtus): -; 15 Avanemine: Avanemine: "L" (L - vasak; R - parem); 16 Liigendatus: -; 17 Sulused, lukustus: Link AssaAbloy Inoxi 3-19 (harjatud roostevaba viimistlusega). Lukustus vastavalt lukustusprojektile. Sulgur puudub. Hinged tootekesksed, viimistlus on sama, mis on ukselehel.; 18 Viimistlus: Tehaseliselt värvitud tumehalliks RAL7016 (Anthrazitgrau). Lävepakk - harjatud roostevaba terasleht t=1mm, kõrgus max 20mm. Leng - pikendatud leng, detailijoonist vt. sisearhitektuursest osast, viimistlus sama, mis ukselehel.; 19 Mudel või toote tunnus: Undefined; 20 Tootja: Undefined; 21 Tooteinfo: Undefined; 22 Kasutus- ja hooldusjuhend: Undefined; 23 viide sõlmele: Undefined
AC_Pset_RenovationAndPhasing - Renovation Status: New

# IfcDoor: SU-16 2 000×2 100 (2)
In: 1 korrus
Type - OperationType: DOUBLE_DOOR_SINGLE_SWING; ParameterTakesPrecedence: no; Sizeable: no
Type - Door Lining Properties - LiningDepth: 115 mm; LiningThickness: 40 mm; ThresholdDepth: 75 mm; ThresholdThickness: 10 mm; LiningOffset: -10 mm; ThresholdOffset: 30 mm; CasingThickness: 50 mm; CasingDepth: 19 mm
Type - Door Panel Properties - Panel 1 - PanelDepth: 40 mm; PanelOperation: SWINGING; PanelWidth: 0.50625; PanelPosition: RIGHT
Type - Door Panel Properties - Panel 2 - PanelDepth: 40 mm; PanelOperation: SWINGING; PanelWidth: 0.50625; PanelPosition: LEFT
OverallHeight: 2100 mm; OverallWidth: 2000 mm
Pset_DoorCommon - ThermalTransmittance: 0; GlazingAreaFraction: 0; IsExternal: no
Avatäited - 01 Nimetus: Siseuks; 02 Materjal: Metall; 03 Tähistus: SU-16 2 000×2 100; 04 Avamõõdu geomeetria: 2 000×2 100; 05 Asukoha info: Interior; 06 Soojusläbivus: -; 07 Helipidavus: 30dB; 08 Veepidavus: -; 09 Õhuläbilaskvus: -; 10 Tulekindlus: EI 30; 11 Vastupanu tulekoormusele: -; 12 Klaaspakett: -; 13 Klaasingu erisused: -; 14 Päikesekiirgus tegur (g-väärtus): -; 15 Avanemine: Avanemine: "R" (L - vasak; R - parem); 16 Liigendatus: Uks koosneb kahest ukselehest; 17 Sulused, lukustus: Link AssaAbloy Aperio (tagasi keeratud lingi otsaga). Lukustus vastavalt lukustusprojektile. Käärsulgur, sulgur paigaldada lao poole. Hinged tootekesksed, viimistlus on sama, mis on ukselehel.; 19 Mudel või toote tunnus: Undefined; 20 Tootja: Undefined; 21 Tooteinfo: Undefined; 22 Kasutus- ja hooldusjuhend: Undefined; 23 viide sõlmele: Undefined
AC_Pset_RenovationAndPhasing - Renovation Status: New
Name | Classification | 18 Viimistlus
Siseuks * Double Door 22 | 0 TELLIJA KULUD (EHITUSKULUDE LIIGITAMINE EVS 885:2005); 1.9 IfcDoor (uks) (_RKAS BIM + ARCHICAD Classification) | Tehaseliselt värvitud tumehalliks RAL7016 (Anthrazitgrau). Lävepakk - harjatud roostevaba terasleht t=1mm, kõrgus max 20mm. Leng - pikendatud leng, detailijoonist vt. sisearhitektuursest osast, viimistlus sama, mis ukselehel.
Siseuks * Double Door 22 | 1.9 IfcDoor (uks) (_RKAS BIM + ARCHICAD Classification) | Tehaseliselt värvitud helehalliks RAL7044 (Seidengrau). Lävepakk - harjatud roostevaba terasleht t=1mm, kõrgus max 20mm. Leng - pikendatud leng, detailijoonist vt. sisearhitektuursest osast, viimistlus sama, mis ukselehel.

# IfcDoor: SU-17 1 200×2 100, Siseuks * Double Door Asymmetric 22
In: 1 korrus
Type - OperationType: DOUBLE_DOOR_SINGLE_SWING; ParameterTakesPrecedence: no; Sizeable: no
Type - Door Lining Properties - LiningDepth: 100 mm; LiningThickness: 40 mm; ThresholdDepth: 60 mm; ThresholdThickness: 10 mm; LiningOffset: -10 mm; ThresholdOffset: -10 mm; CasingThickness: 50 mm; CasingDepth: 19 mm
Type - Door Panel Properties - Panel 1 - PanelDepth: 40 mm; PanelOperation: SWINGING; PanelWidth: 0.753571; PanelPosition: LEFT
Type - Door Panel Properties - Panel 2 - PanelDepth: 40 mm; PanelOperation: SWINGING; PanelWidth: 0.267857; PanelPosition: RIGHT
OverallHeight: 2100 mm; OverallWidth: 1200 mm; Classification: 1.9 IfcDoor (uks) (_RKAS BIM + ARCHICAD Classification)
Pset_DoorCommon - ThermalTransmittance: 0; GlazingAreaFraction: 0; IsExternal: no
Avatäited - 01 Nimetus: Siseuks; 02 Materjal: Metall; 03 Tähistus: SU-17 1 200×2 100; 04 Avamõõdu geomeetria: 1 200×2 100; 05 Asukoha info: Interior; 06 Soojusläbivus: -; 07 Helipidavus: -; 08 Veepidavus: -; 09 Õhuläbilaskvus: -; 10 Tulekindlus: EI 60; 11 Vastupanu tulekoormusele: -; 12 Klaaspakett: -; 13 Klaasingu erisused: -; 14 Päikesekiirgus tegur (g-väärtus): -; 15 Avanemine: Avanemine: "L" (L - vasak; R - parem); 16 Liigendatus: Uks koosneb kahest poolest; 17 Sulused, lukustus: Link AssaAbloy Aperio (tagasi keeratud lingi otsaga). Lukustus vastavalt lukustusprojektile. Passiivne pool varustatud servariiviga. Uks peab olema varustatud taktiseadmega. Käärsulgur, sulgur paigaldada laoruumi poole. Hinged tootekesksed, viimistlus on sama, mis on ukselehel.; 18 Viimistlus: Tehaseliselt värvitud helehalliks RAL7044 (Seidengrau). Lävepakk - harjatud roostevaba terasleht t=1mm, kõrgus max 20mm. Leng - pikendatud leng, detailijoonist vt. sisearhitektuursest osast, viimistlus sama, mis ukselehel.; 19 Mudel või toote tunnus: Undefined; 20 Tootja: Undefined; 21 Tooteinfo: Undefined; 22 Kasutus- ja hooldusjuhend: Undefined; 23 viide sõlmele: Undefined
AC_Pset_RenovationAndPhasing - Renovation Status: New

# IfcDoor: SU-18 1 600×2 280, Siseuks * Double Door 22
In: 0 korrus
Type - OperationType: DOUBLE_DOOR_SINGLE_SWING; ParameterTakesPrecedence: no; Sizeable: no
Type - Door Lining Properties - LiningDepth: 115 mm; LiningThickness: 40 mm; ThresholdDepth: 75 mm; ThresholdThickness: 10 mm; LiningOffset: 210 mm; ThresholdOffset: 250 mm; CasingThickness: 50 mm; CasingDepth: 19 mm
Type - Door Panel Properties - Panel 1 - PanelDepth: 40 mm; PanelOperation: SWINGING; PanelWidth: 0.507895; PanelPosition: LEFT
Type - Door Panel Properties - Panel 2 - PanelDepth: 40 mm; PanelOperation: SWINGING; PanelWidth: 0.507895; PanelPosition: RIGHT
OverallHeight: 2280 mm; OverallWidth: 1600 mm; Classification: 1.9 IfcDoor (uks) (_RKAS BIM + ARCHICAD Classification)
Pset_DoorCommon - ThermalTransmittance: 0; GlazingAreaFraction: 0; IsExternal: no
Avatäited - 01 Nimetus: Siseuks; 02 Materjal: Metall; 03 Tähistus: SU-18 1 600×2 280; 04 Avamõõdu geomeetria: 1 600×2 280; 05 Asukoha info: Interior; 06 Soojusläbivus: -; 07 Helipidavus: -; 08 Veepidavus: -; 09 Õhuläbilaskvus: -; 10 Tulekindlus: EI 30; 11 Vastupanu tulekoormusele: -; 12 Klaaspakett: -; 13 Klaasingu erisused: -; 14 Päikesekiirgus tegur (g-väärtus): -; 15 Avanemine: Avanemine: "L" (L - vasak; R - parem); 16 Liigendatus: Uks koosneb kahest ukselehest; 17 Sulused, lukustus: Link puudub. Lukustus vastavalt lukustusprojektile. Käärsulgur, sulgur paigaldada kilbiruumi poole. Uks varustada taktiseadmega. Hinged tootekesksed, viimistlus on sama, mis on ukselehel. Uks varustada piirajaga (sulguri sisene). Passiivsel ukselehel servariiv.; 18 Viimistlus: Tehaseliselt värvitud tumehalliks RAL7044 (Seidengrau). Lävepakk - harjatud roostevaba terasleht t=1mm, kõrgus max 20mm. Leng - pikendatud leng, detailijoonist vt. sisearhitektuursest osast, viimistlus sama, mis ukselehel.; 19 Mudel või toote tunnus: Undefined; 20 Tootja: Undefined; 21 Tooteinfo: Undefined; 22 Kasutus- ja hooldusjuhend: Undefined; 23 viide sõlmele: Undefined
AC_Pset_RenovationAndPhasing - Renovation Status: New

# IfcDoor: SU-19 900×1 700, Siseuks * Viltune uks 1
In: 0 korrus
Type - ParameterTakesPrecedence: no; Sizeable: no
OverallHeight: 1700 mm; OverallWidth: 900 mm; Classification: 1.9 IfcDoor (uks) (_RKAS BIM + ARCHICAD Classification); Material: Teras (musta värvi) (2)
Avatäited - 01 Nimetus: Siseuks; 02 Materjal: Metall; 03 Tähistus: SU-19 900×1 700; 04 Avamõõdu geomeetria: 900×1 700; 05 Asukoha info: Interior; 06 Soojusläbivus: -; 07 Helipidavus: -; 08 Veepidavus: -; 09 Õhuläbilaskvus: -; 10 Tulekindlus: EI 30; 11 Vastupanu tulekoormusele: -; 12 Klaaspakett: -; 13 Klaasingu erisused: -; 14 Päikesekiirgus tegur (g-väärtus): -; 15 Avanemine: Avanemine: "L" (L - vasak; R - parem); 16 Liigendatus: -; 17 Sulused, lukustus: Link AssaAbloy Inoxi 3-19 (harjatud roostevaba viimistlusega). Lukustus vastavalt lukustusprojektile. Sulgur puudub. Hinged tootekesksed, viimistlus on sama, mis on ukselehel.; 18 Viimistlus: Tehaseliselt värvitud tumehalliks RAL7016 (Anthrazitgrau). Lävepakk - harjatud roostevaba terasleht t=1mm, kõrgus max 20mm.; 19 Mudel või toote tunnus: Undefined; 20 Tootja: Undefined; 21 Tooteinfo: Undefined; 22 Kasutus- ja hooldusjuhend: Undefined; 23 viide sõlmele: Undefined
AC_Pset_RenovationAndPhasing - Renovation Status: New
Pset_DoorCommon - IsExternal: no

# IfcDoor: SU-20 700×2 100, Peitluuk (vt. sisearhitektuurset projekti) * Door 22
In: 1 korrus
Type - OperationType: SINGLE_SWING_RIGHT; ParameterTakesPrecedence: no; Sizeable: no
Type - Door Lining Properties - LiningDepth: 100 mm; LiningThickness: 40 mm; ThresholdDepth: 60 mm; ThresholdThickness: 5 mm; LiningOffset: 110 mm; ThresholdOffset: 150 mm
Type - Door Panel Properties - Panel 1 - PanelDepth: 40 mm; PanelOperation: SWINGING; PanelWidth: 1; PanelPosition: MIDDLE
OverallHeight: 2100 mm; OverallWidth: 700 mm; Classification: 1.9 IfcDoor (uks) (_RKAS BIM + ARCHICAD Classification)
Pset_DoorCommon - ThermalTransmittance: 0; GlazingAreaFraction: 0; IsExternal: no
Avatäited - 01 Nimetus: Peitluuk (vt. sisearhitektuurset projekti); 02 Materjal: Puidust sileuks seina viimistlusega (vt. sisearhitektuurset projekti); 03 Tähistus: SU-20 700×2 100; 04 Avamõõdu geomeetria: 700×2 100; 05 Asukoha info: Interior; 06 Soojusläbivus: -; 07 Helipidavus: -; 08 Veepidavus: -; 09 Õhuläbilaskvus: -; 10 Tulekindlus: nõudeid ei esitata; 11 Vastupanu tulekoormusele: -; 12 Klaaspakett: -; 13 Klaasingu erisused: -; 14 Päikesekiirgus tegur (g-väärtus): -; 15 Avanemine: Avanemine: "L" (L - vasak; R - parem); 16 Liigendatus: -; 17 Sulused, lukustus: Link puudub. Lukustus vastavalt lukustusprojektile. Sulgur puudub. Peithinged.; 18 Viimistlus: vt. sisearhitektuurset projekti; 19 Mudel või toote tunnus: Undefined; 20 Tootja: Undefined; 21 Tooteinfo: Undefined; 22 Kasutus- ja hooldusjuhend: Undefined; 23 viide sõlmele: Undefined
AC_Pset_RenovationAndPhasing - Renovation Status: New

# IfcDoor: VU-05 1 400×2 400, Välisuks * Double Door 22
In: 1 korrus
Type - OperationType: DOUBLE_DOOR_SINGLE_SWING; ParameterTakesPrecedence: no; Sizeable: no
Type - Door Lining Properties - LiningDepth: 115 mm; LiningThickness: 40 mm; LiningOffset: 412 mm
Type - Door Panel Properties - Panel 1 - PanelDepth: 40 mm; PanelOperation: SWINGING; PanelWidth: 0.509091; PanelPosition: LEFT
Type - Door Panel Properties - Panel 2 - PanelDepth: 40 mm; PanelOperation: SWINGING; PanelWidth: 0.509091; PanelPosition: RIGHT
OverallHeight: 2400 mm; OverallWidth: 1400 mm; Classification: 1.9 IfcDoor (uks) (_RKAS BIM + ARCHICAD Classification)
Pset_DoorCommon - ThermalTransmittance: 0; GlazingAreaFraction: 0; IsExternal: yes
Avatäited - 01 Nimetus: Välisuks; 02 Materjal: Metall; 03 Tähistus: VU-05 1 400×2 400; 04 Avamõõdu geomeetria: 1 400×2 400; 05 Asukoha info: Exterior; 06 Soojusläbivus: 1,54 W/m2K; 07 Helipidavus: -; 08 Veepidavus: 7A; 09 Õhuläbilaskvus: klass 4; 10 Tulekindlus: nõudeid ei esitata; 11 Vastupanu tulekoormusele: C3; 12 Klaaspakett: -; 13 Klaasingu erisused: -; 14 Päikesekiirgus tegur (g-väärtus): -; 15 Avanemine: Avanemine: "L" (L - vasak; R - parem); 16 Liigendatus: Uks koosneb kahest ukselehest; 17 Sulused, lukustus: Link AssaAbloy Inoxi 3-19 (harjatud roostevaba viimistlusega). Lukustus vastavalt lukustusprojektile. Käärsulgur), sulgur paigaldada sissepoole. Uks varustada taktiseadmega. Hinged tootekesksed, viimistlus on sama, mis on ukselehel. Uks varustada piirajaga (sulguri sisene). Passiivsel poolel servariiv.; 18 Viimistlus: Tehaseliselt värvitud tumepunaseks RAL3011 (Braunrot). Lävepakk - harjatud roostevaba terasleht t=1mm, kõrgus max 20mm. Uks kaetud peale liimitud puitribidega (ribide mõõdud 50x25 ja 50x50mm). Ribide viimistlus sama, mis hoone fassaadil.; 19 Mudel või toote tunnus: Undefined; 20 Tootja: Undefined; 21 Tooteinfo: Undefined; 22 Kasutus- ja hooldusjuhend: Undefined; 23 viide sõlmele: Undefined
AC_Pset_RenovationAndPhasing - Renovation Status: New

# IfcDoor: VU-06 1 000×3 000 (2)
In: 1 korrus
Type - OperationType: SINGLE_SWING_LEFT; ParameterTakesPrecedence: no; Sizeable: no
Type - Door Lining Properties - LiningDepth: 100 mm; LiningThickness: 40 mm; TransomThickness: 40 mm; TransomOffset: 2400 mm; LiningOffset: 372 mm
Type - Door Panel Properties - Panel 1 - PanelDepth: 40 mm; PanelOperation: SWINGING; PanelWidth: 1; PanelPosition: MIDDLE
OverallHeight: 3000 mm; OverallWidth: 1000 mm; Classification: 1.9 IfcDoor (uks) (_RKAS BIM + ARCHICAD Classification)
Pset_DoorCommon - ThermalTransmittance: 0; GlazingAreaFraction: 2.04973; IsExternal: yes
Avatäited - 01 Nimetus: Välisuks framuugiga; 02 Materjal: Klaas; Metall; 03 Tähistus: VU-06 1 000×3 000; 04 Avamõõdu geomeetria: 1 000×3 000; 05 Asukoha info: Exterior; 06 Soojusläbivus: 1,1W/m2K; 08 Veepidavus: 7A; 09 Õhuläbilaskvus: klass 4; 10 Tulekindlus: nõudeid ei esitata; 11 Vastupanu tulekoormusele: C3; 12 Klaaspakett: kolmekordne klaaspakett; 13 Klaasingu erisused: kirka klaasiga kolmekordne klaaspakett, välimine klaas lamineeritud, sisemine klaas karastatud, klaaside vahelised liistud musta värvi; 14 Päikesekiirgus tegur (g-väärtus): 0,38; 15 Avanemine: Avanemine: "R" (L - vasak; R - parem); 16 Liigendatus: jaotatud kaheks (ukselehe kohal framuug); 17 Sulused, lukustus: Link AssaAbloy Inoxi 3-19 (harjatud roostevaba viimistlusega). Lukustus vastavalt lukustusprojektile. Must liugsulgur Abloy DC700 (või samaväärne analoog), sulgur paigaldada sissepoole. Hinged tootekesksed, viimistlus on sama, mis on ukselehel.; 18 Viimistlus: Tehaseliselt värvitud tumehalliks RAL7016 (Anthrazitgrau). Lävepakk - harjatud roostevaba terasleht t=1mm, kõrgus max 20mm.; 19 Mudel või toote tunnus: AD UP 75 (või samaväärne analoog); 20 Tootja: Schüco (või samaväärne analoog); 21 Tooteinfo: Undefined; 22 Kasutus- ja hooldusjuhend: Undefined; 23 viide sõlmele: Undefined
AC_Pset_RenovationAndPhasing - Renovation Status: New
Name | 07 Helipidavus
Välisuks framuugiga * Door with Transom 22 | 35dB
Välisuks framuugiga * Door with Transom 22 | 30dB

# IfcDoor: VU-12 1 200×2 400, Välisuks * Door 22
In: 2 korrus
Type - OperationType: SINGLE_SWING_RIGHT; ParameterTakesPrecedence: no; Sizeable: no
Type - Door Lining Properties - LiningDepth: 115 mm; LiningThickness: 40 mm; LiningOffset: 429 mm
Type - Door Panel Properties - Panel 1 - PanelDepth: 40 mm; PanelOperation: SWINGING; PanelWidth: 1; PanelPosition: MIDDLE
OverallHeight: 2400 mm; OverallWidth: 1200 mm; Classification: 1.9 IfcDoor (uks) (_RKAS BIM + ARCHICAD Classification)
Pset_DoorCommon - ThermalTransmittance: 0; GlazingAreaFraction: 1.95597
Avatäited - 01 Nimetus: Välisuks; 02 Materjal: Metallraamis klaasuks; 03 Tähistus: VU-12 1 200×2 400; 04 Avamõõdu geomeetria: 1 200×2 400; 05 Asukoha info: Undefined; 06 Soojusläbivus: 1,1W/m2K; 07 Helipidavus: 35dB; 08 Veepidavus: 7A; 09 Õhuläbilaskvus: klass 4; 10 Tulekindlus: nõudeid ei esitata; 11 Vastupanu tulekoormusele: C3; 12 Klaaspakett: kolmekordne klaaspakett; 13 Klaasingu erisused: kolmekordne klaaspakett, välimine klaas lamineeritud, sisemine klaas karastatud, klaaside vahelised liistud musta värvi; 14 Päikesekiirgus tegur (g-väärtus): 0,38; 15 Avanemine: Avanemine: "L" (L - vasak; R - parem); 16 Liigendatus: -; 17 Sulused, lukustus: Link AssaAbloy Inoxi 3-19 tagasi pööratud otsaga evak.link (harjatud roostevaba viimistlusega). Lukustus vastavalt lukustusprojektile. Must liugsulgur Abloy DC700 (või samaväärne analoog), sulgur paigaldada sissepoole. Hinged tootekesksed, viimistlus on sama, mis on ukselehel.; 18 Viimistlus: Tehaseliselt värvitud tumehalliks RAL7016 (Anthrazitgrau). Lävepakk - harjatud roostevaba terasleht t=1mm, kõrgus max 20mm.; 19 Mudel või toote tunnus: AD UP 75 (või samaväärne analoog); 20 Tootja: Schüco (või samaväärne analoog); 21 Tooteinfo: Undefined; 22 Kasutus- ja hooldusjuhend: Undefined; 23 viide sõlmele: Undefined
AC_Pset_RenovationAndPhasing - Renovation Status: New

# IfcDoor: VU-13 1 150×2 300, Välisuks * Door 22
In: 1,5 korrus
Type - OperationType: SINGLE_SWING_LEFT; ParameterTakesPrecedence: no; Sizeable: no
Type - Door Lining Properties - LiningDepth: 100 mm; LiningThickness: 40 mm; ThresholdDepth: 60 mm; ThresholdThickness: 5 mm; LiningOffset: 487 mm; ThresholdOffset: 527 mm
Type - Door Panel Properties - Panel 1 - PanelDepth: 40 mm; PanelOperation: SWINGING; PanelWidth: 1; PanelPosition: MIDDLE
OverallHeight: 2300 mm; OverallWidth: 1150 mm; Classification: 1.9 IfcDoor (uks) (_RKAS BIM + ARCHICAD Classification)
Pset_DoorCommon - ThermalTransmittance: 0; GlazingAreaFraction: 1.76297; IsExternal: no
Avatäited - 01 Nimetus: Välisuks; 02 Materjal: Metallraamis klaasuks; 03 Tähistus: VU-13 1 150×2 300; 04 Avamõõdu geomeetria: 1 150×2 300; 05 Asukoha info: Interior; 06 Soojusläbivus: 1,1W/m2K; 07 Helipidavus: 35dB; 08 Veepidavus: 7A; 09 Õhuläbilaskvus: klass 4; 10 Tulekindlus: nõudeid ei esitata; 11 Vastupanu tulekoormusele: C3; 12 Klaaspakett: kolmekordne klaaspakett; 13 Klaasingu erisused: kolmekordne klaaspakett, välimine klaas lamineeritud, sisemine klaas karastatud, klaaside vahelised liistud musta värvi; 14 Päikesekiirgus tegur (g-väärtus): 0,38; 15 Avanemine: Avanemine: "R" (L - vasak; R - parem); 16 Liigendatus: -; 17 Sulused, lukustus: Link AssaAbloy Inoxi 3-19 tagasi pööratud otsaga evak.link (harjatud roostevaba viimistlusega). Lukustus vastavalt lukustusprojektile. Must liugsulgur Abloy DC700 (või samaväärne analoog), sulgur paigaldada sissepoole. Hinged tootekesksed, viimistlus on sama, mis on ukselehel.; 18 Viimistlus: Tehaseliselt värvitud tumehalliks RAL7016 (Anthrazitgrau). Lävepakk - harjatud roostevaba terasleht t=1mm, kõrgus max 20mm.; 19 Mudel või toote tunnus: AD UP 75 (või samaväärne analoog); 20 Tootja: Schüco (või samaväärne analoog); 21 Tooteinfo: Undefined; 22 Kasutus- ja hooldusjuhend: Undefined; 23 viide sõlmele: Undefined
AC_Pset_RenovationAndPhasing - Renovation Status: New

# IfcPlate: KLF-i paneel (2)
In: 1 korrus
Type - ElementType: Element type KLF-i paneel; PredefinedType: CURTAIN_PANEL
Classification: Curtain Wall Panel (_RKAS BIM + ARCHICAD Classification); Material: Klaas
Ehituskonstruktsioonid - 01 Nimetus: Klaas; 02 Materjal: Klaas; 03 Tähistus või ristlõige: KLF-i paneel; 06 Maht (kubatuur): 0,0
AC_Pset_RenovationAndPhasing - Renovation Status: Existing
Name | 12 Alumine kõrgusmärk
Klaas | 2 125
Klaas | 4 775

# IfcRailing: Keermelatt M12 (80)
Type - ElementType: Element type Keermelatt M12
Classification: 1.11 IfcRailing (piire) (_RKAS BIM + ARCHICAD Classification); Material: Teras (musta värvi)
AC_Pset_RenovationAndPhasing - Renovation Status: New
Pset_RailingCommon - IsExternal: yes
Name | In
24 x Keermelatt M12 | 1 korrus
25 x Keermelatt M12 | 1,5 korrus
31 x Keermelatt M12 | 2 korrus

# IfcRailing: T-11 (2)
Type - ElementType: Element type T-11
Classification: 1.11 IfcRailing (piire) (_RKAS BIM + ARCHICAD Classification)
AC_Pset_RenovationAndPhasing - Renovation Status: New
Pset_RailingCommon - IsExternal: yes
Name | In | Material
T-11 | 1 korrus | Teras (musta värvi)
T-11 | 1,5 korrus | Teras (musta värvi) (2)

# IfcRailing: Teraspost
In: 1 korrus
Type - ElementType: Element type Teraspost
Classification: 1.11 IfcRailing (piire) (_RKAS BIM + ARCHICAD Classification); Material: Teras (musta värvi)
AC_Pset_RenovationAndPhasing - Renovation Status: New
Pset_RailingCommon - IsExternal: yes

# IfcRailing: Terastala (14)
Type - ElementType: Element type Terastala
Classification: 1.11 IfcRailing (piire) (_RKAS BIM + ARCHICAD Classification); Material: Teras (musta värvi)
AC_Pset_RenovationAndPhasing - Renovation Status: New
Pset_RailingCommon - IsExternal: yes
Name | In
6 x Terastala | 1 korrus
4 x Terastala | 1,5 korrus
4 x Terastala | 2 korrus

# IfcRamp (2)
In: 1 korrus
Classification: 1.12 IfcRamp (ramp) (_RKAS BIM + ARCHICAD Classification)
Arhitektuur - 05 Asukoht: Interior
AC_Pset_RenovationAndPhasing - Renovation Status: New
Pset_RampCommon - IsExternal: no
Name | Material | 01 Nimetus = 03 Tähistus | 02 Materjal | 04 Tulepüsivus | 06 Kandevelementide eristatus | 07 Helipidavus | 08 Soojusläbivus (U-arv)
PP-01 | Membraan - Veekindel (2), Killustik, Soojustus - Plastik Kõva (2), Radoonitõkke kile, Betoon, Puit - Põrand | PP-01 | Puit - Põrand; Betoon; Membraan - Veekindel; Soojustus - Plastik Kõva; Radoonitõkke kile; Soojustus - Plastik Kõva; Killustik; Membraan - Veekindel | nõudeid ei esitata | Non-Load-Bearing Element | - | 0,11 W/m2K
VL-01 | Raudbetoon - Konstruktsioon, Soojustus - Plastik Kõva, 00_mineraalvillaplaat - jäik, Membraan - Veekindel, Betoon, Puit - Põrand | VL-01 | Puit - Põrand; Betoon; Membraan - Veekindel; 00_mineraalvillaplaat - jäik; Soojustus - Plastik Kõva; Raudbetoon - Konstruktsioon | EI 60 | Load-Bearing Element | 60dB | -

# IfcRoof (96)
Arhitektuur - 05 Asukoht: Exterior
AC_Pset_RenovationAndPhasing - Renovation Status: New
Pset_RoofCommon - IsExternal: yes
Name | In | Classification | Material | Arhitektuur, 01 Nimetus | Arhitektuur, 02 Materjal | 03 Tähistus = 03 Tähistus või ristlõige | 04 Tulepüsivus | 06 Kandevelementide eristatus | 07 Helipidavus | 08 Soojusläbivus (U-arv) | Ehituskonstruktsioonid, 01 Nimetus | Ehituskonstruktsioonid, 02 Materjal | 06 Maht (kubatuur) | 12 Alumine kõrgusmärk
KL-03 | 1 korrus | 0 TELLIJA KULUD (EHITUSKULUDE LIIGITAMINE EVS 885:2005); 1.13 IfcRoof (katus) (_RKAS BIM + ARCHICAD Classification) | Raudbetoon - Konstruktsioon (2), 00_mineraalvillaplaat - jäik, 00_membraan_PVC kate | katus | Kiudbetoonplaat 120mm; PUR-soojustusplaadid Kingspan Therma (või analoog) 200mm, alt soontega vee liikumise võimaldamiseks; Hüdroisolatsioon 3x SBS rullmaterjal; Monoliitne kalde all r/bet.plaat 250mm; Viimistluskiht | KL-03 | R 60 | Load-Bearing Element | 60dB | 0,11W/m2K | KL-03 | Raudbetoon - Konstruktsioon; 00_mineraalvillaplaat - jäik; 00_membraan_PVC kate; Raudbetoon - Konstruktsioon | 34,9 | -934
KL-03 | 1 korrus | 0 TELLIJA KULUD (EHITUSKULUDE LIIGITAMINE EVS 885:2005); 1.13 IfcRoof (katus) (_RKAS BIM + ARCHICAD Classification) | Raudbetoon - Konstruktsioon (2), 00_membraan_PVC kate, 00_mineraalvillaplaat - jäik | katus | Kiudbetoonplaat 120mm; PUR-soojustusplaadid Kingspan Therma (või analoog) 200mm, alt soontega vee liikumise võimaldamiseks; Hüdroisolatsioon 3x SBS rullmaterjal; Monoliitne kalde all r/bet.plaat 250mm; Viimistluskiht | KL-03 | R 60 | Load-Bearing Element | 60dB | 0,11W/m2K | KL-03 | Raudbetoon - Konstruktsioon; 00_mineraalvillaplaat - jäik; 00_membraan_PVC kate; Raudbetoon - Konstruktsioon | 82,3 | 295
Teras (musta värvi) | 1,5 korrus | 1.13 IfcRoof (katus) (_RKAS BIM + ARCHICAD Classification) | Teras (musta värvi) | Varikatus | 3mm Terasleht (keskkonnaklass C3); Teraskarkass; Valtsplekk RR33 | V-02 | nõudeid ei esitata | Non-Load-Bearing Element | - | - | Teras (musta värvi) | Teras (musta värvi) | 5,5 | 4 100
Teras (musta värvi) | 1,5 korrus | 1.13 IfcRoof (katus) (_RKAS BIM + ARCHICAD Classification) | Teras (musta värvi) | Varikatus | 3mm Terasleht (keskkonnaklass C3); Teraskarkass; Valtsplekk RR33 | V-01 | nõudeid ei esitata | Non-Load-Bearing Element | - | - | Teras (musta värvi) | Teras (musta värvi) | 4,7 | 1 330
KL-03 | 1,5 korrus | 0 TELLIJA KULUD (EHITUSKULUDE LIIGITAMINE EVS 885:2005); 1.13 IfcRoof (katus) (_RKAS BIM + ARCHICAD Classification) | Raudbetoon - Konstruktsioon (2), 00_mineraalvillaplaat - jäik, 00_membraan_PVC kate | katus | Kiudbetoonplaat 120mm; PUR-soojustusplaadid Kingspan Therma (või analoog) 200mm, alt soontega vee liikumise võimaldamiseks; Hüdroisolatsioon 3x SBS rullmaterjal; Monoliitne kalde all r/bet.plaat 250mm; Viimistluskiht | KL-03 | R 60 | Load-Bearing Element | 60dB | 0,11W/m2K | KL-03 | Raudbetoon - Konstruktsioon; 00_mineraalvillaplaat - jäik; 00_membraan_PVC kate; Raudbetoon - Konstruktsioon | 94,1 | 2 775
Teras (musta värvi) | 2 korrus | 1.13 IfcRoof (katus) (_RKAS BIM + ARCHICAD Classification) | Teras (musta värvi) | Metallrestist evakuatsioonitrepi made | Kuumtsingitud metallrest | K-11 | nõudeid ei esitata | Load-Bearing Element | - | - | Teras (musta värvi) | Teras (musta värvi) | 0,1 | 5 195
Membraan - Veekindel | 2 korrus | 1.13 IfcRoof (katus) (_RKAS BIM + ARCHICAD Classification) | Membraan - Veekindel | Katusekattematerjal | 2x Veekindel membraan | KL-04 | nõudeid ei esitata | Non-Load-Bearing Element | - | - | Membraan - Veekindel | Membraan - Veekindel | 0,1 | 4 147
KL-01 | Katus | 1.13 IfcRoof (katus) (_RKAS BIM + ARCHICAD Classification) | Membraan - Veekindel, Raudbetoon - Toode | Katuslagi | R/betoon õõnespaneel 265mm | KL-01 | nõudeid ei esitata | Load-Bearing Element | Undefined | 0,09W/m2K | KL-01 | Membraan - Veekindel; Raudbetoon - Toode | 365,5 | 8 985
8 x Membraan - Veekindel | Katus | 1.13 IfcRoof (katus) (_RKAS BIM + ARCHICAD Classification) | Membraan - Veekindel | Katusekattematerjal | 2x Veekindel membraan | KL-04 | nõudeid ei esitata | Load-Bearing Element | - | - | Membraan - Veekindel | Membraan - Veekindel | 0,1 | 10 273
8 x Membraan - Veekindel | Katus | 1.13 IfcRoof (katus) (_RKAS BIM + ARCHICAD Classification) | Membraan - Veekindel | Katusekattematerjal | 2x Veekindel membraan | KL-04 | nõudeid ei esitata | Load-Bearing Element | - | - | Membraan - Veekindel | Membraan - Veekindel | 0,2 | 9 860
3 x Membraan - Veekindel | Katus | 1.13 IfcRoof (katus) (_RKAS BIM + ARCHICAD Classification) | Membraan - Veekindel | Katusekattematerjal | 2x Veekindel membraan | KL-04 | nõudeid ei esitata | Load-Bearing Element | - | - | Membraan - Veekindel | Membraan - Veekindel | 0,1 | 9 860
KL-01* | Katus | 1.13 IfcRoof (katus) (_RKAS BIM + ARCHICAD Classification) | Membraan - Veekindel (4), 00_mineraalvillaplaat - jäik (2), Soojustus - Plastik Kõva (2) | Katuslae välimine kiht | Hüdroisolatsioon PVC kate (musta värvi); Tuulutussoontega jäik mineraalvillaplaat 50mm; Vahtpolüstüreenplaat EPS 60 (või analoog), ülemine kiht kaldu lõigatud 50...150mm; Soojusisolatsioon KINGSPAN Therma TR26 (või analoog); Aurutõkke 1x SBS rullmaterjal; | KL-01* | nõudeid ei esitata | Non-Load-Bearing Element | 60dB | 0,09W/m2K | KL-01* | Membraan - Veekindel; Membraan - Veekindel; 00_mineraalvillaplaat - jäik; Soojustus - Plastik Kõva | 11,7 | 8 895
KL-01* | Katus | 1.13 IfcRoof (katus) (_RKAS BIM + ARCHICAD Classification) | Membraan - Veekindel (2), 00_mineraalvillaplaat - jäik, Soojustus - Plastik Kõva | Katuslae välimine kiht | Hüdroisolatsioon PVC kate (musta värvi); Tuulutussoontega jäik mineraalvillaplaat 50mm; Vahtpolüstüreenplaat EPS 60 (või analoog), ülemine kiht kaldu lõigatud 50...150mm; Soojusisolatsioon KINGSPAN Therma TR26 (või analoog); Aurutõkke 1x SBS rullmaterjal; | KL-01* | nõudeid ei esitata | Non-Load-Bearing Element | 60dB | 0,09W/m2K | KL-01* | Membraan - Veekindel; Membraan - Veekindel; 00_mineraalvillaplaat - jäik; Soojustus - Plastik Kõva | 3,1 | 8 878
KL-01* | Katus | 1.13 IfcRoof (katus) (_RKAS BIM + ARCHICAD Classification) | Membraan - Veekindel (2), 00_mineraalvillaplaat - jäik, Soojustus - Plastik Kõva | Katuslae välimine kiht | Hüdroisolatsioon PVC kate (musta värvi); Tuulutussoontega jäik mineraalvillaplaat 50mm; Vahtpolüstüreenplaat EPS 60 (või analoog), ülemine kiht kaldu lõigatud 50...150mm; Soojusisolatsioon KINGSPAN Therma TR26 (või analoog); Aurutõkke 1x SBS rullmaterjal; | KL-01* | nõudeid ei esitata | Non-Load-Bearing Element | 60dB | 0,09W/m2K | KL-01* | Membraan - Veekindel; Membraan - Veekindel; 00_mineraalvillaplaat - jäik; Soojustus - Plastik Kõva | 13,8 | 8 894
KL-01* | Katus | 1.13 IfcRoof (katus) (_RKAS BIM + ARCHICAD Classification) | Membraan - Veekindel (4), 00_mineraalvillaplaat - jäik (2), Soojustus - Plastik Kõva (2) | Katuslae välimine kiht | Hüdroisolatsioon PVC kate (musta värvi); Tuulutussoontega jäik mineraalvillaplaat 50mm; Vahtpolüstüreenplaat EPS 60 (või analoog), ülemine kiht kaldu lõigatud 50...150mm; Soojusisolatsioon KINGSPAN Therma TR26 (või analoog); Aurutõkke 1x SBS rullmaterjal; | KL-01* | nõudeid ei esitata | Non-Load-Bearing Element | 60dB | 0,09W/m2K | KL-01* | Membraan - Veekindel; Membraan - Veekindel; 00_mineraalvillaplaat - jäik; Soojustus - Plastik Kõva | 4,0 | 8 889
KL-01* | Katus | 1.13 IfcRoof (katus) (_RKAS BIM + ARCHICAD Classification) | Membraan - Veekindel (2), 00_mineraalvillaplaat - jäik, Soojustus - Plastik Kõva | Katuslae välimine kiht | Hüdroisolatsioon PVC kate (musta värvi); Tuulutussoontega jäik mineraalvillaplaat 50mm; Vahtpolüstüreenplaat EPS 60 (või analoog), ülemine kiht kaldu lõigatud 50...150mm; Soojusisolatsioon KINGSPAN Therma TR26 (või analoog); Aurutõkke 1x SBS rullmaterjal; | KL-01* | nõudeid ei esitata | Non-Load-Bearing Element | 60dB | 0,09W/m2K | KL-01* | Membraan - Veekindel; Membraan - Veekindel; 00_mineraalvillaplaat - jäik; Soojustus - Plastik Kõva | 7,7 | 8 895
2 x KL-01* | Katus | 1.13 IfcRoof (katus) (_RKAS BIM + ARCHICAD Classification) | Membraan - Veekindel (2), 00_mineraalvillaplaat - jäik, Soojustus - Plastik Kõva | Katuslae välimine kiht | Hüdroisolatsioon PVC kate (musta värvi); Tuulutussoontega jäik mineraalvillaplaat 50mm; Vahtpolüstüreenplaat EPS 60 (või analoog), ülemine kiht kaldu lõigatud 50...150mm; Soojusisolatsioon KINGSPAN Therma TR26 (või analoog); Aurutõkke 1x SBS rullmaterjal; | KL-01* | nõudeid ei esitata | Non-Load-Bearing Element | 60dB | 0,09W/m2K | KL-01* | Membraan - Veekindel; Membraan - Veekindel; 00_mineraalvillaplaat - jäik; Soojustus - Plastik Kõva | 6,7 | 8 893
KL-01* | Katus | 1.13 IfcRoof (katus) (_RKAS BIM + ARCHICAD Classification) | Membraan - Veekindel (2), 00_mineraalvillaplaat - jäik, Soojustus - Plastik Kõva | Katuslae välimine kiht | Hüdroisolatsioon PVC kate (musta värvi); Tuulutussoontega jäik mineraalvillaplaat 50mm; Vahtpolüstüreenplaat EPS 60 (või analoog), ülemine kiht kaldu lõigatud 50...150mm; Soojusisolatsioon KINGSPAN Therma TR26 (või analoog); Aurutõkke 1x SBS rullmaterjal; | KL-01* | nõudeid ei esitata | Non-Load-Bearing Element | 60dB | 0,09W/m2K | KL-01* | Membraan - Veekindel; Membraan - Veekindel; 00_mineraalvillaplaat - jäik; Soojustus - Plastik Kõva | 12,7 | 8 895
KL-01* | Katus | 1.13 IfcRoof (katus) (_RKAS BIM + ARCHICAD Classification) | Membraan - Veekindel (2), 00_mineraalvillaplaat - jäik, Soojustus - Plastik Kõva | Katuslae välimine kiht | Hüdroisolatsioon PVC kate (musta värvi); Tuulutussoontega jäik mineraalvillaplaat 50mm; Vahtpolüstüreenplaat EPS 60 (või analoog), ülemine kiht kaldu lõigatud 50...150mm; Soojusisolatsioon KINGSPAN Therma TR26 (või analoog); Aurutõkke 1x SBS rullmaterjal; | KL-01* | nõudeid ei esitata | Non-Load-Bearing Element | 60dB | 0,09W/m2K | KL-01* | Membraan - Veekindel; Membraan - Veekindel; 00_mineraalvillaplaat - jäik; Soojustus - Plastik Kõva | 8,3 | 8 893
2 x KL-01* | Katus | 1.13 IfcRoof (katus) (_RKAS BIM + ARCHICAD Classification) | Membraan - Veekindel (2), 00_mineraalvillaplaat - jäik, Soojustus - Plastik Kõva | Katuslae välimine kiht | Hüdroisolatsioon PVC kate (musta värvi); Tuulutussoontega jäik mineraalvillaplaat 50mm; Vahtpolüstüreenplaat EPS 60 (või analoog), ülemine kiht kaldu lõigatud 50...150mm; Soojusisolatsioon KINGSPAN Therma TR26 (või analoog); Aurutõkke 1x SBS rullmaterjal; | KL-01* | nõudeid ei esitata | Non-Load-Bearing Element | 60dB | 0,09W/m2K | KL-01* | Membraan - Veekindel; Membraan - Veekindel; 00_mineraalvillaplaat - jäik; Soojustus - Plastik Kõva | 8,8 | 8 893
KL-01* | Katus | 1.13 IfcRoof (katus) (_RKAS BIM + ARCHICAD Classification) | Membraan - Veekindel (2), 00_mineraalvillaplaat - jäik, Soojustus - Plastik Kõva | Katuslae välimine kiht | Hüdroisolatsioon PVC kate (musta värvi); Tuulutussoontega jäik mineraalvillaplaat 50mm; Vahtpolüstüreenplaat EPS 60 (või analoog), ülemine kiht kaldu lõigatud 50...150mm; Soojusisolatsioon KINGSPAN Therma TR26 (või analoog); Aurutõkke 1x SBS rullmaterjal; | KL-01* | nõudeid ei esitata | Non-Load-Bearing Element | 60dB | 0,09W/m2K | KL-01* | Membraan - Veekindel; Membraan - Veekindel; 00_mineraalvillaplaat - jäik; Soojustus - Plastik Kõva | 11,4 | 8 895
KL-01* | Katus | 1.13 IfcRoof (katus) (_RKAS BIM + ARCHICAD Classification) | Membraan - Veekindel (2), 00_mineraalvillaplaat - jäik, Soojustus - Plastik Kõva | Katuslae välimine kiht | Hüdroisolatsioon PVC kate (musta värvi); Tuulutussoontega jäik mineraalvillaplaat 50mm; Vahtpolüstüreenplaat EPS 60 (või analoog), ülemine kiht kaldu lõigatud 50...150mm; Soojusisolatsioon KINGSPAN Therma TR26 (või analoog); Aurutõkke 1x SBS rullmaterjal; | KL-01* | nõudeid ei esitata | Non-Load-Bearing Element | 60dB | 0,09W/m2K | KL-01* | Membraan - Veekindel; Membraan - Veekindel; 00_mineraalvillaplaat - jäik; Soojustus - Plastik Kõva | 6,4 | 8 878
KL-01* | Katus | 1.13 IfcRoof (katus) (_RKAS BIM + ARCHICAD Classification) | Membraan - Veekindel (2), 00_mineraalvillaplaat - jäik, Soojustus - Plastik Kõva | Katuslae välimine kiht | Hüdroisolatsioon PVC kate (musta värvi); Tuulutussoontega jäik mineraalvillaplaat 50mm; Vahtpolüstüreenplaat EPS 60 (või analoog), ülemine kiht kaldu lõigatud 50...150mm; Soojusisolatsioon KINGSPAN Therma TR26 (või analoog); Aurutõkke 1x SBS rullmaterjal; | KL-01* | nõudeid ei esitata | Non-Load-Bearing Element | 60dB | 0,09W/m2K | KL-01* | Membraan - Veekindel; Membraan - Veekindel; 00_mineraalvillaplaat - jäik; Soojustus - Plastik Kõva | 12,1 | 8 895
KL-01* | Katus | 1.13 IfcRoof (katus) (_RKAS BIM + ARCHICAD Classification) | Membraan - Veekindel (2), 00_mineraalvillaplaat - jäik, Soojustus - Plastik Kõva | Katuslae välimine kiht | Hüdroisolatsioon PVC kate (musta värvi); Tuulutussoontega jäik mineraalvillaplaat 50mm; Vahtpolüstüreenplaat EPS 60 (või analoog), ülemine kiht kaldu lõigatud 50...150mm; Soojusisolatsioon KINGSPAN Therma TR26 (või analoog); Aurutõkke 1x SBS rullmaterjal; | KL-01* | nõudeid ei esitata | Non-Load-Bearing Element | 60dB | 0,09W/m2K | KL-01* | Membraan - Veekindel; Membraan - Veekindel; 00_mineraalvillaplaat - jäik; Soojustus - Plastik Kõva | 17,7 | 8 895
KL-01* | Katus | 1.13 IfcRoof (katus) (_RKAS BIM + ARCHICAD Classification) | Membraan - Veekindel (2), 00_mineraalvillaplaat - jäik, Soojustus - Plastik Kõva | Katuslae välimine kiht | Hüdroisolatsioon PVC kate (musta värvi); Tuulutussoontega jäik mineraalvillaplaat 50mm; Vahtpolüstüreenplaat EPS 60 (või analoog), ülemine kiht kaldu lõigatud 50...150mm; Soojusisolatsioon KINGSPAN Therma TR26 (või analoog); Aurutõkke 1x SBS rullmaterjal; | KL-01* | nõudeid ei esitata | Non-Load-Bearing Element | 60dB | 0,09W/m2K | KL-01* | Membraan - Veekindel; Membraan - Veekindel; 00_mineraalvillaplaat - jäik; Soojustus - Plastik Kõva | 13,8 | 8 895
2 x KL-01* | Katus | 1.13 IfcRoof (katus) (_RKAS BIM + ARCHICAD Classification) | Membraan - Veekindel (2), 00_mineraalvillaplaat - jäik, Soojustus - Plastik Kõva | Katuslae välimine kiht | Hüdroisolatsioon PVC kate (musta värvi); Tuulutussoontega jäik mineraalvillaplaat 50mm; Vahtpolüstüreenplaat EPS 60 (või analoog), ülemine kiht kaldu lõigatud 50...150mm; Soojusisolatsioon KINGSPAN Therma TR26 (või analoog); Aurutõkke 1x SBS rullmaterjal; | KL-01* | nõudeid ei esitata | Non-Load-Bearing Element | 60dB | 0,09W/m2K | KL-01* | Membraan - Veekindel; Membraan - Veekindel; 00_mineraalvillaplaat - jäik; Soojustus - Plastik Kõva | 7,9 | 8 893
KL-01* | Katus | 1.13 IfcRoof (katus) (_RKAS BIM + ARCHICAD Classification) | Membraan - Veekindel (4), 00_mineraalvillaplaat - jäik (2), Soojustus - Plastik Kõva (2) | Katuslae välimine kiht | Hüdroisolatsioon PVC kate (musta värvi); Tuulutussoontega jäik mineraalvillaplaat 50mm; Vahtpolüstüreenplaat EPS 60 (või analoog), ülemine kiht kaldu lõigatud 50...150mm; Soojusisolatsioon KINGSPAN Therma TR26 (või analoog); Aurutõkke 1x SBS rullmaterjal; | KL-01* | nõudeid ei esitata | Non-Load-Bearing Element | 60dB | 0,09W/m2K | KL-01* | Membraan - Veekindel; Membraan - Veekindel; 00_mineraalvillaplaat - jäik; Soojustus - Plastik Kõva | 4,2 | 8 889
2 x KL-01* | Katus | 1.13 IfcRoof (katus) (_RKAS BIM + ARCHICAD Classification) | Membraan - Veekindel (2), 00_mineraalvillaplaat - jäik, Soojustus - Plastik Kõva | Katuslae välimine kiht | Hüdroisolatsioon PVC kate (musta värvi); Tuulutussoontega jäik mineraalvillaplaat 50mm; Vahtpolüstüreenplaat EPS 60 (või analoog), ülemine kiht kaldu lõigatud 50...150mm; Soojusisolatsioon KINGSPAN Therma TR26 (või analoog); Aurutõkke 1x SBS rullmaterjal; | KL-01* | nõudeid ei esitata | Non-Load-Bearing Element | 60dB | 0,09W/m2K | KL-01* | Membraan - Veekindel; Membraan - Veekindel; 00_mineraalvillaplaat - jäik; Soojustus - Plastik Kõva | 3,5 | 8 888
KL-01* | Katus | 1.13 IfcRoof (katus) (_RKAS BIM + ARCHICAD Classification) | Membraan - Veekindel (2), 00_mineraalvillaplaat - jäik, Soojustus - Plastik Kõva | Katuslae välimine kiht | Hüdroisolatsioon PVC kate (musta värvi); Tuulutussoontega jäik mineraalvillaplaat 50mm; Vahtpolüstüreenplaat EPS 60 (või analoog), ülemine kiht kaldu lõigatud 50...150mm; Soojusisolatsioon KINGSPAN Therma TR26 (või analoog); Aurutõkke 1x SBS rullmaterjal; | KL-01* | nõudeid ei esitata | Non-Load-Bearing Element | 60dB | 0,09W/m2K | KL-01* | Membraan - Veekindel; Membraan - Veekindel; 00_mineraalvillaplaat - jäik; Soojustus - Plastik Kõva | 9,7 | 8 895
4 x KL-01* | Katus | 1.13 IfcRoof (katus) (_RKAS BIM + ARCHICAD Classification) | Membraan - Veekindel (2), 00_mineraalvillaplaat - jäik, Soojustus - Plastik Kõva | Katuslae välimine kiht | Hüdroisolatsioon PVC kate (musta värvi); Tuulutussoontega jäik mineraalvillaplaat 50mm; Vahtpolüstüreenplaat EPS 60 (või analoog), ülemine kiht kaldu lõigatud 50...150mm; Soojusisolatsioon KINGSPAN Therma TR26 (või analoog); Aurutõkke 1x SBS rullmaterjal; | KL-01* | nõudeid ei esitata | Non-Load-Bearing Element | 60dB | 0,09W/m2K | KL-01* | Membraan - Veekindel; Membraan - Veekindel; 00_mineraalvillaplaat - jäik; Soojustus - Plastik Kõva | 5,0 | 8 889
2 x KL-01* | Katus | 1.13 IfcRoof (katus) (_RKAS BIM + ARCHICAD Classification) | Membraan - Veekindel (2), 00_mineraalvillaplaat - jäik, Soojustus - Plastik Kõva | Katuslae välimine kiht | Hüdroisolatsioon PVC kate (musta värvi); Tuulutussoontega jäik mineraalvillaplaat 50mm; Vahtpolüstüreenplaat EPS 60 (või analoog), ülemine kiht kaldu lõigatud 50...150mm; Soojusisolatsioon KINGSPAN Therma TR26 (või analoog); Aurutõkke 1x SBS rullmaterjal; | KL-01* | nõudeid ei esitata | Non-Load-Bearing Element | 60dB | 0,09W/m2K | KL-01* | Membraan - Veekindel; Membraan - Veekindel; 00_mineraalvillaplaat - jäik; Soojustus - Plastik Kõva | 6,6 | 8 893
2 x KL-01* | Katus | 1.13 IfcRoof (katus) (_RKAS BIM + ARCHICAD Classification) | Membraan - Veekindel (2), 00_mineraalvillaplaat - jäik, Soojustus - Plastik Kõva | Katuslae välimine kiht | Hüdroisolatsioon PVC kate (musta värvi); Tuulutussoontega jäik mineraalvillaplaat 50mm; Vahtpolüstüreenplaat EPS 60 (või analoog), ülemine kiht kaldu lõigatud 50...150mm; Soojusisolatsioon KINGSPAN Therma TR26 (või analoog); Aurutõkke 1x SBS rullmaterjal; | KL-01* | nõudeid ei esitata | Non-Load-Bearing Element | 60dB | 0,09W/m2K | KL-01* | Membraan - Veekindel; Membraan - Veekindel; 00_mineraalvillaplaat - jäik; Soojustus - Plastik Kõva | 12,8 | 8 895
KL-01* | Katus | 1.13 IfcRoof (katus) (_RKAS BIM + ARCHICAD Classification) | Membraan - Veekindel (2), 00_mineraalvillaplaat - jäik, Soojustus - Plastik Kõva | Katuslae välimine kiht | Hüdroisolatsioon PVC kate (musta värvi); Tuulutussoontega jäik mineraalvillaplaat 50mm; Vahtpolüstüreenplaat EPS 60 (või analoog), ülemine kiht kaldu lõigatud 50...150mm; Soojusisolatsioon KINGSPAN Therma TR26 (või analoog); Aurutõkke 1x SBS rullmaterjal; | KL-01* | nõudeid ei esitata | Non-Load-Bearing Element | 60dB | 0,09W/m2K | KL-01* | Membraan - Veekindel; Membraan - Veekindel; 00_mineraalvillaplaat - jäik; Soojustus - Plastik Kõva | 6,5 | 8 893
KL-01* | Katus | 1.13 IfcRoof (katus) (_RKAS BIM + ARCHICAD Classification) | Membraan - Veekindel (4), 00_mineraalvillaplaat - jäik (2), Soojustus - Plastik Kõva (2) | Katuslae välimine kiht | Hüdroisolatsioon PVC kate (musta värvi); Tuulutussoontega jäik mineraalvillaplaat 50mm; Vahtpolüstüreenplaat EPS 60 (või analoog), ülemine kiht kaldu lõigatud 50...150mm; Soojusisolatsioon KINGSPAN Therma TR26 (või analoog); Aurutõkke 1x SBS rullmaterjal; | KL-01* | nõudeid ei esitata | Non-Load-Bearing Element | 60dB | 0,09W/m2K | KL-01* | Membraan - Veekindel; Membraan - Veekindel; 00_mineraalvillaplaat - jäik; Soojustus - Plastik Kõva | 13,2 | 8 895
KL-01* | Katus | 1.13 IfcRoof (katus) (_RKAS BIM + ARCHICAD Classification) | Membraan - Veekindel (2), 00_mineraalvillaplaat - jäik, Soojustus - Plastik Kõva | Katuslae välimine kiht | Hüdroisolatsioon PVC kate (musta värvi); Tuulutussoontega jäik mineraalvillaplaat 50mm; Vahtpolüstüreenplaat EPS 60 (või analoog), ülemine kiht kaldu lõigatud 50...150mm; Soojusisolatsioon KINGSPAN Therma TR26 (või analoog); Aurutõkke 1x SBS rullmaterjal; | KL-01* | nõudeid ei esitata | Non-Load-Bearing Element | 60dB | 0,09W/m2K | KL-01* | Membraan - Veekindel; Membraan - Veekindel; 00_mineraalvillaplaat - jäik; Soojustus - Plastik Kõva | 10,5 | 8 894
KL-01* | Katus | 1.13 IfcRoof (katus) (_RKAS BIM + ARCHICAD Classification) | Membraan - Veekindel (2), 00_mineraalvillaplaat - jäik, Soojustus - Plastik Kõva | Katuslae välimine kiht | Hüdroisolatsioon PVC kate (musta värvi); Tuulutussoontega jäik mineraalvillaplaat 50mm; Vahtpolüstüreenplaat EPS 60 (või analoog), ülemine kiht kaldu lõigatud 50...150mm; Soojusisolatsioon KINGSPAN Therma TR26 (või analoog); Aurutõkke 1x SBS rullmaterjal; | KL-01* | nõudeid ei esitata | Non-Load-Bearing Element | 60dB | 0,09W/m2K | KL-01* | Membraan - Veekindel; Membraan - Veekindel; 00_mineraalvillaplaat - jäik; Soojustus - Plastik Kõva | 10,7 | 8 894
KL-01* | Katus | 1.13 IfcRoof (katus) (_RKAS BIM + ARCHICAD Classification) | Membraan - Veekindel (2), 00_mineraalvillaplaat - jäik, Soojustus - Plastik Kõva | Katuslae välimine kiht | Hüdroisolatsioon PVC kate (musta värvi); Tuulutussoontega jäik mineraalvillaplaat 50mm; Vahtpolüstüreenplaat EPS 60 (või analoog), ülemine kiht kaldu lõigatud 50...150mm; Soojusisolatsioon KINGSPAN Therma TR26 (või analoog); Aurutõkke 1x SBS rullmaterjal; | KL-01* | nõudeid ei esitata | Non-Load-Bearing Element | 60dB | 0,09W/m2K | KL-01* | Membraan - Veekindel; Membraan - Veekindel; 00_mineraalvillaplaat - jäik; Soojustus - Plastik Kõva | 7,1 | 8 893
2 x KL-01* | Katus | 1.13 IfcRoof (katus) (_RKAS BIM + ARCHICAD Classification) | Membraan - Veekindel (2), 00_mineraalvillaplaat - jäik, Soojustus - Plastik Kõva | Katuslae välimine kiht | Hüdroisolatsioon PVC kate (musta värvi); Tuulutussoontega jäik mineraalvillaplaat 50mm; Vahtpolüstüreenplaat EPS 60 (või analoog), ülemine kiht kaldu lõigatud 50...150mm; Soojusisolatsioon KINGSPAN Therma TR26 (või analoog); Aurutõkke 1x SBS rullmaterjal; | KL-01* | nõudeid ei esitata | Non-Load-Bearing Element | 60dB | 0,09W/m2K | KL-01* | Membraan - Veekindel; Membraan - Veekindel; 00_mineraalvillaplaat - jäik; Soojustus - Plastik Kõva | 8,2 | 8 893
KL-01* | Katus | 1.13 IfcRoof (katus) (_RKAS BIM + ARCHICAD Classification) | Membraan - Veekindel (2), 00_mineraalvillaplaat - jäik, Soojustus - Plastik Kõva | Katuslae välimine kiht | Hüdroisolatsioon PVC kate (musta värvi); Tuulutussoontega jäik mineraalvillaplaat 50mm; Vahtpolüstüreenplaat EPS 60 (või analoog), ülemine kiht kaldu lõigatud 50...150mm; Soojusisolatsioon KINGSPAN Therma TR26 (või analoog); Aurutõkke 1x SBS rullmaterjal; | KL-01* | nõudeid ei esitata | Non-Load-Bearing Element | 60dB | 0,09W/m2K | KL-01* | Membraan - Veekindel; Membraan - Veekindel; 00_mineraalvillaplaat - jäik; Soojustus - Plastik Kõva | 12,5 | 8 895
KL-01* | Katus | 1.13 IfcRoof (katus) (_RKAS BIM + ARCHICAD Classification) | Membraan - Veekindel (2), 00_mineraalvillaplaat - jäik, Soojustus - Plastik Kõva | Katuslae välimine kiht | Hüdroisolatsioon PVC kate (musta värvi); Tuulutussoontega jäik mineraalvillaplaat 50mm; Vahtpolüstüreenplaat EPS 60 (või analoog), ülemine kiht kaldu lõigatud 50...150mm; Soojusisolatsioon KINGSPAN Therma TR26 (või analoog); Aurutõkke 1x SBS rullmaterjal; | KL-01* | nõudeid ei esitata | Non-Load-Bearing Element | 60dB | 0,09W/m2K | KL-01* | Membraan - Veekindel; Membraan - Veekindel; 00_mineraalvillaplaat - jäik; Soojustus - Plastik Kõva | 8,7 | 8 893
KL-01* | Katus | 1.13 IfcRoof (katus) (_RKAS BIM + ARCHICAD Classification) | Membraan - Veekindel (2), 00_mineraalvillaplaat - jäik, Soojustus - Plastik Kõva | Katuslae välimine kiht | Hüdroisolatsioon PVC kate (musta värvi); Tuulutussoontega jäik mineraalvillaplaat 50mm; Vahtpolüstüreenplaat EPS 60 (või analoog), ülemine kiht kaldu lõigatud 50...150mm; Soojusisolatsioon KINGSPAN Therma TR26 (või analoog); Aurutõkke 1x SBS rullmaterjal; | KL-01* | nõudeid ei esitata | Non-Load-Bearing Element | 60dB | 0,09W/m2K | KL-01* | Membraan - Veekindel; Membraan - Veekindel; 00_mineraalvillaplaat - jäik; Soojustus - Plastik Kõva | 16,7 | 8 895
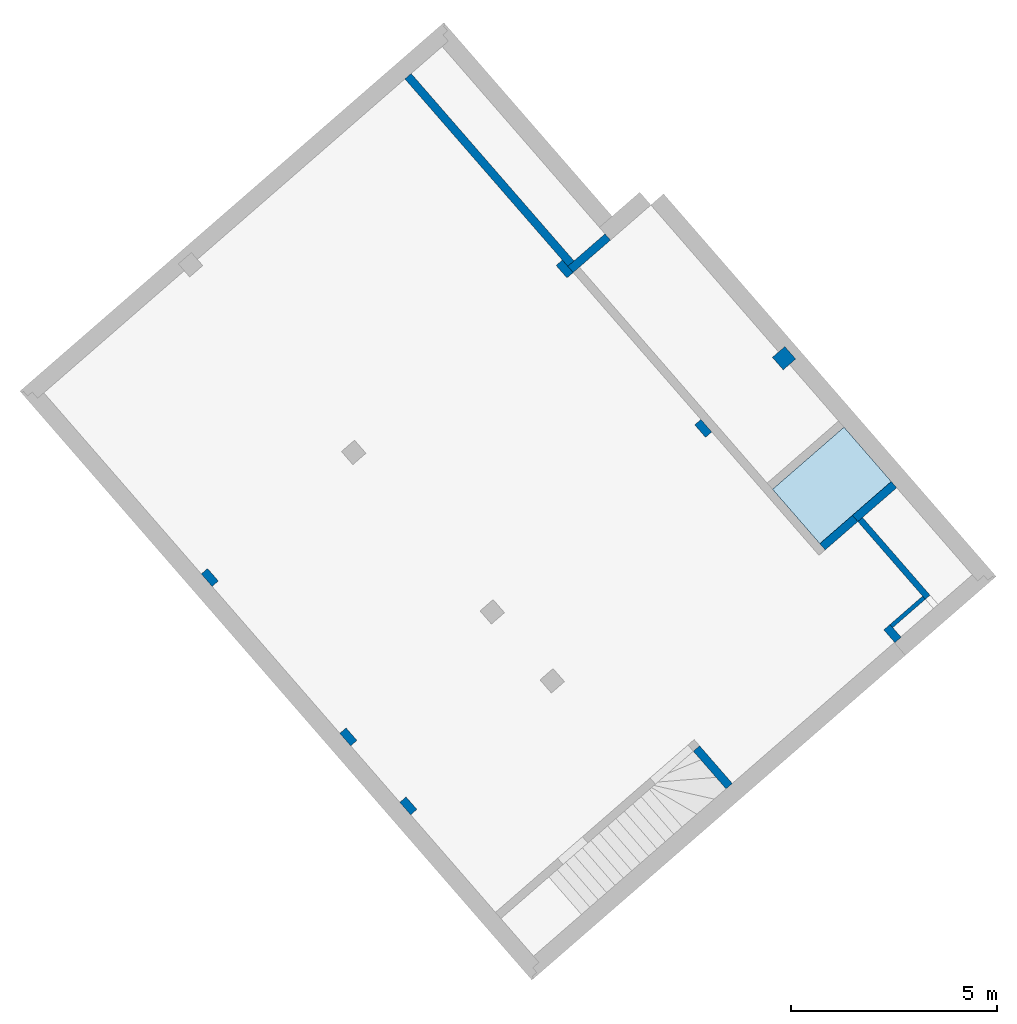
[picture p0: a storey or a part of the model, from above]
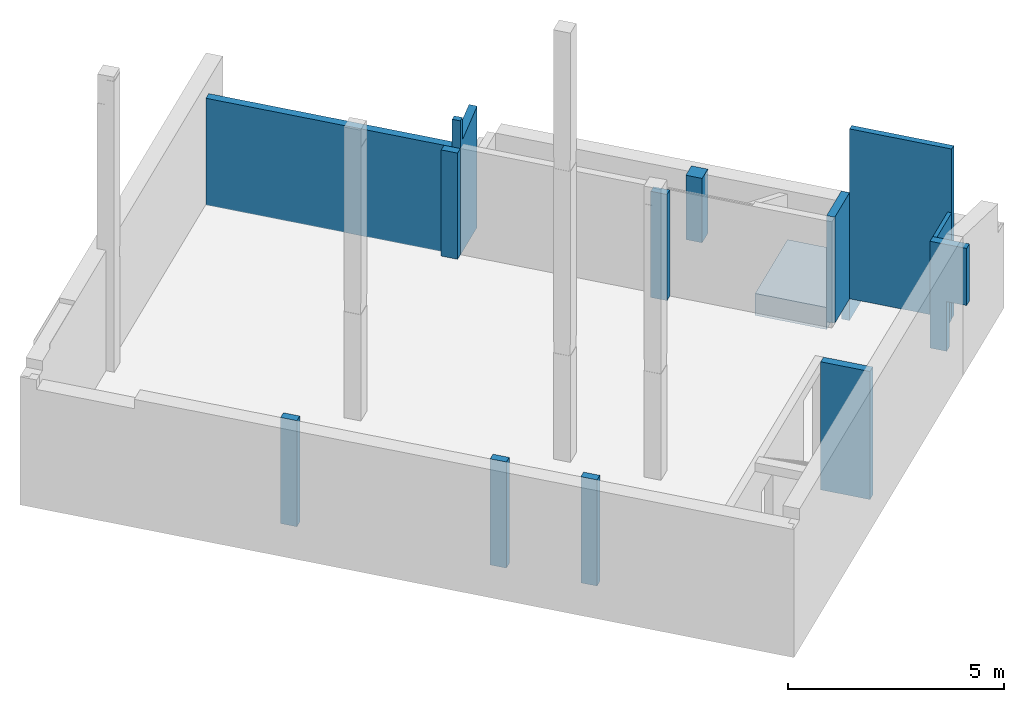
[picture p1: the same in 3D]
Properties of the parts of a building model (IFC2X3), part 7 of 13

# IfcRoof (96)
Name | In | Classification | Material | Arhitektuur, 01 Nimetus | Arhitektuur, 02 Materjal | 03 Tähistus = 03 Tähistus või ristlõige | 04 Tulepüsivus | 06 Kandevelementide eristatus | 07 Helipidavus | 08 Soojusläbivus (U-arv) | Ehituskonstruktsioonid, 01 Nimetus | Ehituskonstruktsioonid, 02 Materjal | 06 Maht (kubatuur) | 12 Alumine kõrgusmärk
KL-01* | Katus | 1.13 IfcRoof (katus) (_RKAS BIM + ARCHICAD Classification) | Membraan - Veekindel (2), 00_mineraalvillaplaat - jäik, Soojustus - Plastik Kõva | Katuslae välimine kiht | Hüdroisolatsioon PVC kate (musta värvi); Tuulutussoontega jäik mineraalvillaplaat 50mm; Vahtpolüstüreenplaat EPS 60 (või analoog), ülemine kiht kaldu lõigatud 50...150mm; Soojusisolatsioon KINGSPAN Therma TR26 (või analoog); Aurutõkke 1x SBS rullmaterjal; | KL-01* | nõudeid ei esitata | Non-Load-Bearing Element | 60dB | 0,09W/m2K | KL-01* | Membraan - Veekindel; Membraan - Veekindel; 00_mineraalvillaplaat - jäik; Soojustus - Plastik Kõva | 8,1 | 8 893
KL-01* | Katus | 1.13 IfcRoof (katus) (_RKAS BIM + ARCHICAD Classification) | Membraan - Veekindel (4), 00_mineraalvillaplaat - jäik (2), Soojustus - Plastik Kõva (2) | Katuslae välimine kiht | Hüdroisolatsioon PVC kate (musta värvi); Tuulutussoontega jäik mineraalvillaplaat 50mm; Vahtpolüstüreenplaat EPS 60 (või analoog), ülemine kiht kaldu lõigatud 50...150mm; Soojusisolatsioon KINGSPAN Therma TR26 (või analoog); Aurutõkke 1x SBS rullmaterjal; | KL-01* | nõudeid ei esitata | Non-Load-Bearing Element | 60dB | 0,09W/m2K | KL-01* | Membraan - Veekindel; Membraan - Veekindel; 00_mineraalvillaplaat - jäik; Soojustus - Plastik Kõva | 18,6 | 8 895
KL-01* | Katus | 1.13 IfcRoof (katus) (_RKAS BIM + ARCHICAD Classification) | Membraan - Veekindel (2), 00_mineraalvillaplaat - jäik, Soojustus - Plastik Kõva | Katuslae välimine kiht | Hüdroisolatsioon PVC kate (musta värvi); Tuulutussoontega jäik mineraalvillaplaat 50mm; Vahtpolüstüreenplaat EPS 60 (või analoog), ülemine kiht kaldu lõigatud 50...150mm; Soojusisolatsioon KINGSPAN Therma TR26 (või analoog); Aurutõkke 1x SBS rullmaterjal; | KL-01* | nõudeid ei esitata | Non-Load-Bearing Element | 60dB | 0,09W/m2K | KL-01* | Membraan - Veekindel; Membraan - Veekindel; 00_mineraalvillaplaat - jäik; Soojustus - Plastik Kõva | 13,1 | 8 895
KL-01* | Katus | 1.13 IfcRoof (katus) (_RKAS BIM + ARCHICAD Classification) | Membraan - Veekindel (2), 00_mineraalvillaplaat - jäik, Soojustus - Plastik Kõva | Katuslae välimine kiht | Hüdroisolatsioon PVC kate (musta värvi); Tuulutussoontega jäik mineraalvillaplaat 50mm; Vahtpolüstüreenplaat EPS 60 (või analoog), ülemine kiht kaldu lõigatud 50...150mm; Soojusisolatsioon KINGSPAN Therma TR26 (või analoog); Aurutõkke 1x SBS rullmaterjal; | KL-01* | nõudeid ei esitata | Non-Load-Bearing Element | 60dB | 0,09W/m2K | KL-01* | Membraan - Veekindel; Membraan - Veekindel; 00_mineraalvillaplaat - jäik; Soojustus - Plastik Kõva | 13,4 | 8 895
KL-01* | Katus | 1.13 IfcRoof (katus) (_RKAS BIM + ARCHICAD Classification) | Membraan - Veekindel (2), 00_mineraalvillaplaat - jäik, Soojustus - Plastik Kõva | Katuslae välimine kiht | Hüdroisolatsioon PVC kate (musta värvi); Tuulutussoontega jäik mineraalvillaplaat 50mm; Vahtpolüstüreenplaat EPS 60 (või analoog), ülemine kiht kaldu lõigatud 50...150mm; Soojusisolatsioon KINGSPAN Therma TR26 (või analoog); Aurutõkke 1x SBS rullmaterjal; | KL-01* | nõudeid ei esitata | Non-Load-Bearing Element | 60dB | 0,09W/m2K | KL-01* | Membraan - Veekindel; Membraan - Veekindel; 00_mineraalvillaplaat - jäik; Soojustus - Plastik Kõva | 6,9 | 8 895
KL-01* | Katus | 1.13 IfcRoof (katus) (_RKAS BIM + ARCHICAD Classification) | Membraan - Veekindel (2), 00_mineraalvillaplaat - jäik, Soojustus - Plastik Kõva | Katuslae välimine kiht | Hüdroisolatsioon PVC kate (musta värvi); Tuulutussoontega jäik mineraalvillaplaat 50mm; Vahtpolüstüreenplaat EPS 60 (või analoog), ülemine kiht kaldu lõigatud 50...150mm; Soojusisolatsioon KINGSPAN Therma TR26 (või analoog); Aurutõkke 1x SBS rullmaterjal; | KL-01* | nõudeid ei esitata | Non-Load-Bearing Element | 60dB | 0,09W/m2K | KL-01* | Membraan - Veekindel; Membraan - Veekindel; 00_mineraalvillaplaat - jäik; Soojustus - Plastik Kõva | 13,7 | 8 895
KL-01* | Katus | 1.13 IfcRoof (katus) (_RKAS BIM + ARCHICAD Classification) | Membraan - Veekindel (4), 00_mineraalvillaplaat - jäik (2), Soojustus - Plastik Kõva (2) | Katuslae välimine kiht | Hüdroisolatsioon PVC kate (musta värvi); Tuulutussoontega jäik mineraalvillaplaat 50mm; Vahtpolüstüreenplaat EPS 60 (või analoog), ülemine kiht kaldu lõigatud 50...150mm; Soojusisolatsioon KINGSPAN Therma TR26 (või analoog); Aurutõkke 1x SBS rullmaterjal; | KL-01* | nõudeid ei esitata | Non-Load-Bearing Element | 60dB | 0,09W/m2K | KL-01* | Membraan - Veekindel; Membraan - Veekindel; 00_mineraalvillaplaat - jäik; Soojustus - Plastik Kõva | 4,7 | 8 890
KL-01* | Katus | 1.13 IfcRoof (katus) (_RKAS BIM + ARCHICAD Classification) | Membraan - Veekindel (2), 00_mineraalvillaplaat - jäik, Soojustus - Plastik Kõva | Katuslae välimine kiht | Hüdroisolatsioon PVC kate (musta värvi); Tuulutussoontega jäik mineraalvillaplaat 50mm; Vahtpolüstüreenplaat EPS 60 (või analoog), ülemine kiht kaldu lõigatud 50...150mm; Soojusisolatsioon KINGSPAN Therma TR26 (või analoog); Aurutõkke 1x SBS rullmaterjal; | KL-01* | nõudeid ei esitata | Non-Load-Bearing Element | 60dB | 0,09W/m2K | KL-01* | Membraan - Veekindel; Membraan - Veekindel; 00_mineraalvillaplaat - jäik; Soojustus - Plastik Kõva | 1,9 | 8 852
KL-01* | Katus | 1.13 IfcRoof (katus) (_RKAS BIM + ARCHICAD Classification) | Membraan - Veekindel (2), 00_mineraalvillaplaat - jäik, Soojustus - Plastik Kõva | Katuslae välimine kiht | Hüdroisolatsioon PVC kate (musta värvi); Tuulutussoontega jäik mineraalvillaplaat 50mm; Vahtpolüstüreenplaat EPS 60 (või analoog), ülemine kiht kaldu lõigatud 50...150mm; Soojusisolatsioon KINGSPAN Therma TR26 (või analoog); Aurutõkke 1x SBS rullmaterjal; | KL-01* | nõudeid ei esitata | Non-Load-Bearing Element | 60dB | 0,09W/m2K | KL-01* | Membraan - Veekindel; Membraan - Veekindel; 00_mineraalvillaplaat - jäik; Soojustus - Plastik Kõva | 4,5 | 8 889
2 x KL-01* | Katus | 1.13 IfcRoof (katus) (_RKAS BIM + ARCHICAD Classification) | Membraan - Veekindel (2), 00_mineraalvillaplaat - jäik, Soojustus - Plastik Kõva | Katuslae välimine kiht | Hüdroisolatsioon PVC kate (musta värvi); Tuulutussoontega jäik mineraalvillaplaat 50mm; Vahtpolüstüreenplaat EPS 60 (või analoog), ülemine kiht kaldu lõigatud 50...150mm; Soojusisolatsioon KINGSPAN Therma TR26 (või analoog); Aurutõkke 1x SBS rullmaterjal; | KL-01* | nõudeid ei esitata | Non-Load-Bearing Element | 60dB | 0,09W/m2K | KL-01* | Membraan - Veekindel; Membraan - Veekindel; 00_mineraalvillaplaat - jäik; Soojustus - Plastik Kõva | 15,0 | 8 895
2 x KL-01* | Katus | 1.13 IfcRoof (katus) (_RKAS BIM + ARCHICAD Classification) | Membraan - Veekindel (2), 00_mineraalvillaplaat - jäik, Soojustus - Plastik Kõva | Katuslae välimine kiht | Hüdroisolatsioon PVC kate (musta värvi); Tuulutussoontega jäik mineraalvillaplaat 50mm; Vahtpolüstüreenplaat EPS 60 (või analoog), ülemine kiht kaldu lõigatud 50...150mm; Soojusisolatsioon KINGSPAN Therma TR26 (või analoog); Aurutõkke 1x SBS rullmaterjal; | KL-01* | nõudeid ei esitata | Non-Load-Bearing Element | 60dB | 0,09W/m2K | KL-01* | Membraan - Veekindel; Membraan - Veekindel; 00_mineraalvillaplaat - jäik; Soojustus - Plastik Kõva | 13,0 | 8 895
KL-01* | Katus | 1.13 IfcRoof (katus) (_RKAS BIM + ARCHICAD Classification) | Membraan - Veekindel (2), 00_mineraalvillaplaat - jäik, Soojustus - Plastik Kõva | Katuslae välimine kiht | Hüdroisolatsioon PVC kate (musta värvi); Tuulutussoontega jäik mineraalvillaplaat 50mm; Vahtpolüstüreenplaat EPS 60 (või analoog), ülemine kiht kaldu lõigatud 50...150mm; Soojusisolatsioon KINGSPAN Therma TR26 (või analoog); Aurutõkke 1x SBS rullmaterjal; | KL-01* | nõudeid ei esitata | Non-Load-Bearing Element | 60dB | 0,09W/m2K | KL-01* | Membraan - Veekindel; Membraan - Veekindel; 00_mineraalvillaplaat - jäik; Soojustus - Plastik Kõva | 4,9 | 8 890
KL-01* | Katus | 1.13 IfcRoof (katus) (_RKAS BIM + ARCHICAD Classification) | Membraan - Veekindel (2), 00_mineraalvillaplaat - jäik, Soojustus - Plastik Kõva | Katuslae välimine kiht | Hüdroisolatsioon PVC kate (musta värvi); Tuulutussoontega jäik mineraalvillaplaat 50mm; Vahtpolüstüreenplaat EPS 60 (või analoog), ülemine kiht kaldu lõigatud 50...150mm; Soojusisolatsioon KINGSPAN Therma TR26 (või analoog); Aurutõkke 1x SBS rullmaterjal; | KL-01* | nõudeid ei esitata | Non-Load-Bearing Element | 60dB | 0,09W/m2K | KL-01* | Membraan - Veekindel; Membraan - Veekindel; 00_mineraalvillaplaat - jäik; Soojustus - Plastik Kõva | 2,8 | 8 881
2 x KL-01* | Katus | 1.13 IfcRoof (katus) (_RKAS BIM + ARCHICAD Classification) | Membraan - Veekindel (2), 00_mineraalvillaplaat - jäik, Soojustus - Plastik Kõva | Katuslae välimine kiht | Hüdroisolatsioon PVC kate (musta värvi); Tuulutussoontega jäik mineraalvillaplaat 50mm; Vahtpolüstüreenplaat EPS 60 (või analoog), ülemine kiht kaldu lõigatud 50...150mm; Soojusisolatsioon KINGSPAN Therma TR26 (või analoog); Aurutõkke 1x SBS rullmaterjal; | KL-01* | nõudeid ei esitata | Non-Load-Bearing Element | 60dB | 0,09W/m2K | KL-01* | Membraan - Veekindel; Membraan - Veekindel; 00_mineraalvillaplaat - jäik; Soojustus - Plastik Kõva | 10,0 | 8 894
KL-01* | Katus | 1.13 IfcRoof (katus) (_RKAS BIM + ARCHICAD Classification) | Membraan - Veekindel (2), 00_mineraalvillaplaat - jäik, Soojustus - Plastik Kõva | Katuslae välimine kiht | Hüdroisolatsioon PVC kate (musta värvi); Tuulutussoontega jäik mineraalvillaplaat 50mm; Vahtpolüstüreenplaat EPS 60 (või analoog), ülemine kiht kaldu lõigatud 50...150mm; Soojusisolatsioon KINGSPAN Therma TR26 (või analoog); Aurutõkke 1x SBS rullmaterjal; | KL-01* | nõudeid ei esitata | Non-Load-Bearing Element | 60dB | 0,09W/m2K | KL-01* | Membraan - Veekindel; Membraan - Veekindel; 00_mineraalvillaplaat - jäik; Soojustus - Plastik Kõva | 0,5 | 8 787
KL-01* | Katus | 1.13 IfcRoof (katus) (_RKAS BIM + ARCHICAD Classification) | Membraan - Veekindel (2), 00_mineraalvillaplaat - jäik, Soojustus - Plastik Kõva | Katuslae välimine kiht | Hüdroisolatsioon PVC kate (musta värvi); Tuulutussoontega jäik mineraalvillaplaat 50mm; Vahtpolüstüreenplaat EPS 60 (või analoog), ülemine kiht kaldu lõigatud 50...150mm; Soojusisolatsioon KINGSPAN Therma TR26 (või analoog); Aurutõkke 1x SBS rullmaterjal; | KL-01* | nõudeid ei esitata | Non-Load-Bearing Element | 60dB | 0,09W/m2K | KL-01* | Membraan - Veekindel; Membraan - Veekindel; 00_mineraalvillaplaat - jäik; Soojustus - Plastik Kõva | 8,4 | 8 894
KL-01* | Katus | 1.13 IfcRoof (katus) (_RKAS BIM + ARCHICAD Classification) | Membraan - Veekindel (4), 00_mineraalvillaplaat - jäik (2), Soojustus - Plastik Kõva (2) | Katuslae välimine kiht | Hüdroisolatsioon PVC kate (musta värvi); Tuulutussoontega jäik mineraalvillaplaat 50mm; Vahtpolüstüreenplaat EPS 60 (või analoog), ülemine kiht kaldu lõigatud 50...150mm; Soojusisolatsioon KINGSPAN Therma TR26 (või analoog); Aurutõkke 1x SBS rullmaterjal; | KL-01* | nõudeid ei esitata | Non-Load-Bearing Element | 60dB | 0,09W/m2K | KL-01* | Membraan - Veekindel; Membraan - Veekindel; 00_mineraalvillaplaat - jäik; Soojustus - Plastik Kõva | 13,8 | 8 895
KL-01* | Katus | 1.13 IfcRoof (katus) (_RKAS BIM + ARCHICAD Classification) | Membraan - Veekindel (4), 00_mineraalvillaplaat - jäik (2), Soojustus - Plastik Kõva (2) | Katuslae välimine kiht | Hüdroisolatsioon PVC kate (musta värvi); Tuulutussoontega jäik mineraalvillaplaat 50mm; Vahtpolüstüreenplaat EPS 60 (või analoog), ülemine kiht kaldu lõigatud 50...150mm; Soojusisolatsioon KINGSPAN Therma TR26 (või analoog); Aurutõkke 1x SBS rullmaterjal; | KL-01* | nõudeid ei esitata | Non-Load-Bearing Element | 60dB | 0,09W/m2K | KL-01* | Membraan - Veekindel; Membraan - Veekindel; 00_mineraalvillaplaat - jäik; Soojustus - Plastik Kõva | 2,3 | 8 895
KL-01* | Katus | 1.13 IfcRoof (katus) (_RKAS BIM + ARCHICAD Classification) | Membraan - Veekindel (2), 00_mineraalvillaplaat - jäik, Soojustus - Plastik Kõva | Katuslae välimine kiht | Hüdroisolatsioon PVC kate (musta värvi); Tuulutussoontega jäik mineraalvillaplaat 50mm; Vahtpolüstüreenplaat EPS 60 (või analoog), ülemine kiht kaldu lõigatud 50...150mm; Soojusisolatsioon KINGSPAN Therma TR26 (või analoog); Aurutõkke 1x SBS rullmaterjal; | KL-01* | nõudeid ei esitata | Non-Load-Bearing Element | 60dB | 0,09W/m2K | KL-01* | Membraan - Veekindel; Membraan - Veekindel; 00_mineraalvillaplaat - jäik; Soojustus - Plastik Kõva | 9,6 | 8 895
KL-01* | Katus | 1.13 IfcRoof (katus) (_RKAS BIM + ARCHICAD Classification) | Membraan - Veekindel (2), 00_mineraalvillaplaat - jäik, Soojustus - Plastik Kõva | Katuslae välimine kiht | Hüdroisolatsioon PVC kate (musta värvi); Tuulutussoontega jäik mineraalvillaplaat 50mm; Vahtpolüstüreenplaat EPS 60 (või analoog), ülemine kiht kaldu lõigatud 50...150mm; Soojusisolatsioon KINGSPAN Therma TR26 (või analoog); Aurutõkke 1x SBS rullmaterjal; | KL-01* | nõudeid ei esitata | Non-Load-Bearing Element | 60dB | 0,09W/m2K | KL-01* | Membraan - Veekindel; Membraan - Veekindel; 00_mineraalvillaplaat - jäik; Soojustus - Plastik Kõva | 11,5 | 8 894
KL-01* | Katus | 1.13 IfcRoof (katus) (_RKAS BIM + ARCHICAD Classification) | Membraan - Veekindel (4), 00_mineraalvillaplaat - jäik (2), Soojustus - Plastik Kõva (2) | Katuslae välimine kiht | Hüdroisolatsioon PVC kate (musta värvi); Tuulutussoontega jäik mineraalvillaplaat 50mm; Vahtpolüstüreenplaat EPS 60 (või analoog), ülemine kiht kaldu lõigatud 50...150mm; Soojusisolatsioon KINGSPAN Therma TR26 (või analoog); Aurutõkke 1x SBS rullmaterjal; | KL-01* | nõudeid ei esitata | Non-Load-Bearing Element | 60dB | 0,09W/m2K | KL-01* | Membraan - Veekindel; Membraan - Veekindel; 00_mineraalvillaplaat - jäik; Soojustus - Plastik Kõva | 5,3 | 8 892
KL-01* | Katus | 1.13 IfcRoof (katus) (_RKAS BIM + ARCHICAD Classification) | Membraan - Veekindel (2), 00_mineraalvillaplaat - jäik, Soojustus - Plastik Kõva | Katuslae välimine kiht | Hüdroisolatsioon PVC kate (musta värvi); Tuulutussoontega jäik mineraalvillaplaat 50mm; Vahtpolüstüreenplaat EPS 60 (või analoog), ülemine kiht kaldu lõigatud 50...150mm; Soojusisolatsioon KINGSPAN Therma TR26 (või analoog); Aurutõkke 1x SBS rullmaterjal; | KL-01* | nõudeid ei esitata | Non-Load-Bearing Element | 60dB | 0,09W/m2K | KL-01* | Membraan - Veekindel; Membraan - Veekindel; 00_mineraalvillaplaat - jäik; Soojustus - Plastik Kõva | 0,7 | 8 814
KL-01* | Katus | 1.13 IfcRoof (katus) (_RKAS BIM + ARCHICAD Classification) | Membraan - Veekindel (4), 00_mineraalvillaplaat - jäik (2), Soojustus - Plastik Kõva (2) | Katuslae välimine kiht | Hüdroisolatsioon PVC kate (musta värvi); Tuulutussoontega jäik mineraalvillaplaat 50mm; Vahtpolüstüreenplaat EPS 60 (või analoog), ülemine kiht kaldu lõigatud 50...150mm; Soojusisolatsioon KINGSPAN Therma TR26 (või analoog); Aurutõkke 1x SBS rullmaterjal; | KL-01* | nõudeid ei esitata | Non-Load-Bearing Element | 60dB | 0,09W/m2K | KL-01* | Membraan - Veekindel; Membraan - Veekindel; 00_mineraalvillaplaat - jäik; Soojustus - Plastik Kõva | 5,9 | 8 892
3 x Membraan - Veekindel | Katus | 1.13 IfcRoof (katus) (_RKAS BIM + ARCHICAD Classification) | Membraan - Veekindel | Katusekattematerjal | 2x Veekindel membraan | KL-04 | nõudeid ei esitata | Load-Bearing Element | - | - | Membraan - Veekindel | Membraan - Veekindel | 0,1 | 10 237

# IfcSlab: K-11
In: 0 korrus
Type - ElementType: Element type K-11; PredefinedType: FLOOR
Classification: 1.14 IfcSlab (vahelagi) (_RKAS BIM + ARCHICAD Classification); Material: Teras - Roostevaba, Teras (musta värvi)
Arhitektuur - 01 Nimetus: Metallrestist põrand; 02 Materjal: Kuumtsingitud metallrest; 03 Tähistus: K-11; 04 Tulepüsivus: nõudeid ei esitata; 05 Asukoht: Exterior; 06 Kandevelementide eristatus: Load-Bearing Element; 07 Helipidavus: -; 08 Soojusläbivus (U-arv): -
Ehituskonstruktsioonid - 01 Nimetus: K-11; 02 Materjal: Teras - Roostevaba; Teras (musta värvi); 03 Tähistus või ristlõige: K-11; 06 Maht (kubatuur): 0,6; 12 Alumine kõrgusmärk: -1 615
AC_Pset_RenovationAndPhasing - Renovation Status: New
Pset_SlabCommon - LoadBearing: yes; IsExternal: yes

# IfcSlab: PP-01 (15)
Type - ElementType: Element type PP-01; PredefinedType: FLOOR
Classification: 1.14 IfcSlab (vahelagi) (_RKAS BIM + ARCHICAD Classification)
Arhitektuur - 02 Materjal: Viimistluskiht; Kiudbetoonplaat 200mm; PVC-kile; Soojustus EPS100 100mm; Radoonitõkke kile; Soojustus EPS100 100mm; Killustik 200mm; Geotekstiil; 03 Tähistus: PP-01; 04 Tulepüsivus: nõudeid ei esitata; 05 Asukoht: Interior; 06 Kandevelementide eristatus: Non-Load-Bearing Element; 07 Helipidavus: -; 08 Soojusläbivus (U-arv): 0,11 W/m2K
Ehituskonstruktsioonid - 01 Nimetus: PP-01; 02 Materjal: Puit - Põrand; Betoon; Membraan - Veekindel; Soojustus - Plastik Kõva; Radoonitõkke kile; Soojustus - Plastik Kõva; Killustik; Membraan - Veekindel; 03 Tähistus või ristlõige: PP-01
AC_Pset_RenovationAndPhasing - Renovation Status: New
Pset_SlabCommon - LoadBearing: no; IsExternal: no
Name | In | Material | 01 Nimetus | 06 Maht (kubatuur) | 12 Alumine kõrgusmärk
PP-01 | -1 korrus | Puit - Põrand, Betoon, Soojustus - Plastik Kõva (2), Killustik | Põrand pinnasel | 150,4 | -3 415
PP-01 | -1 korrus | Puit - Põrand 20 mm, Betoon 200 mm, Membraan - Veekindel 0 mm, Soojustus - Plastik Kõva 100 mm, Radoonitõkke kile 0 mm, Soojustus - Plastik Kõva 100 mm, Killustik 200 mm, Membraan - Veekindel 0 mm | Põrand pinnasel | 2,5 | -3 015
PP-01 | 0 korrus | Puit - Põrand (7), Betoon, Soojustus - Plastik Kõva (2), Killustik | Põran pinnasel | 364,6 | -1 615
PP-01 | 0 korrus | Puit - Põrand, Betoon, Soojustus - Plastik Kõva (2), Killustik | Põrand pinnasel | 5,5 | -975
PP-01 | 0 korrus | Puit - Põrand, Betoon, Soojustus - Plastik Kõva (2), Killustik | Põrand pinnasel | 5,5 | -1 455
PP-01 | 0 korrus | Puit - Põrand, Betoon, Soojustus - Plastik Kõva (2), Killustik | Põrand pinnasel | 5,5 | -175
PP-01 | 0 korrus | Puit - Põrand, Betoon, Soojustus - Plastik Kõva (2), Killustik | Põrand pinnasel | 8,9 | -15
PP-01 | 0 korrus | Puit - Põrand, Betoon, Soojustus - Plastik Kõva (2), Killustik | Põrand pinnasel | 5,5 | -1 295
PP-01 | 0 korrus | Puit - Põrand, Betoon, Soojustus - Plastik Kõva (2), Killustik | Põrand pinnasel | 5,5 | -1 135
PP-01 | 0 korrus | Puit - Põrand, Betoon, Soojustus - Plastik Kõva (2), Killustik | Põrand pinnasel | 5,5 | -655
PP-01 | 0 korrus | Puit - Põrand, Betoon, Soojustus - Plastik Kõva (2), Killustik | Põrand pinnasel | 5,5 | -495
PP-01 | 0 korrus | Puit - Põrand, Betoon, Soojustus - Plastik Kõva (2), Killustik | Põrand pinnasel | 5,5 | -335
PP-01 | 0 korrus | Puit - Põrand, Betoon, Soojustus - Plastik Kõva (2), Killustik | Põrand pinnasel | 5,5 | -815
PP-01 | 1 korrus | Puit - Põrand (3), Betoon, Soojustus - Plastik Kõva (2), Killustik | Põran pinnasel | 286,0 | 0
PP-01 | 1 korrus | Puit - Põrand (9), Betoon, Soojustus - Plastik Kõva (2), Killustik | Põrand pinnasel | 174,9 | -600

# IfcSlab: PP-03 (5)
In: 1 korrus
Type - ElementType: Element type PP-03; PredefinedType: FLOOR
Classification: 1.14 IfcSlab (vahelagi) (_RKAS BIM + ARCHICAD Classification); Material: Teras - Roostevaba 30 mm, Õhkvahe 8 mm, Betoon 120 mm, Membraan - Veekindel 1 mm, Soojustus - Plastik Kõva 100 mm, Membraan - Veekindel 1 mm, Liiv 50 mm, Membraan - Veekindel 1 mm, Killustik 200 mm
Arhitektuur - 01 Nimetus: Põrand pinnasel; 02 Materjal: Roostevabast terasest libisemiskindel Ritilä terasrest FINN LT 18/x50 / 30x3 või samaväärne analoog (Paigaldada kummiribadele ja fikseerida resti tootja poolt pakutavate kinnitusklambritega); Monol. r/bet.plaat (elektriküttega) 120mm, pealevalu kaldega trapi suunas 1:80; Polüetüleenkile; Vahtpolüstüreen EPS120 100mm; Tihendatud liivalus 50mm; Geotekstiil; Tihendatud killustikalus 200mm; Filterkangas; Mineraalne täite- või aluspinnas.; 03 Tähistus: PP-03; 04 Tulepüsivus: nõudeid ei esitata; 05 Asukoht: Exterior; 06 Kandevelementide eristatus: Non-Load-Bearing Element; 07 Helipidavus: -; 08 Soojusläbivus (U-arv): -
Ehituskonstruktsioonid - 01 Nimetus: PP-03; 02 Materjal: Teras - Roostevaba; Õhkvahe; Betoon; Membraan - Veekindel; Soojustus - Plastik Kõva; Membraan - Veekindel; Liiv; Membraan - Veekindel; Killustik; 03 Tähistus või ristlõige: PP-03; 12 Alumine kõrgusmärk: -531
AC_Pset_RenovationAndPhasing - Renovation Status: New
Pset_SlabCommon - LoadBearing: no; IsExternal: yes
Name | 06 Maht (kubatuur)
PP-03 | 3,0
PP-03 | 3,8
PP-03 | 1,4
PP-03 | 2,3
PP-03 | 0,6

# IfcSlab: VL-01 (15)
Type - ElementType: Element type VL-01; PredefinedType: FLOOR
Arhitektuur - 01 Nimetus: Vahelagi; 03 Tähistus: VL-01; 05 Asukoht: Interior; 06 Kandevelementide eristatus: Load-Bearing Element; 07 Helipidavus: 48 dB; 08 Soojusläbivus (U-arv): -
Ehituskonstruktsioonid - 01 Nimetus: VL-01; 02 Materjal: Puit - Põrand; Betoon; Membraan - Veekindel; 00_mineraalvillaplaat - jäik; Soojustus - Plastik Kõva; Raudbetoon - Konstruktsioon; 03 Tähistus või ristlõige: VL-01
AC_Pset_RenovationAndPhasing - Renovation Status: New
Pset_SlabCommon - LoadBearing: yes; IsExternal: no
Name | In | Classification | Material | 02 Materjal | 04 Tulepüsivus | 06 Maht (kubatuur) | 12 Alumine kõrgusmärk
VL-01 | 1 korrus | 1.14 IfcSlab (vahelagi) (_RKAS BIM + ARCHICAD Classification); 0 TELLIJA KULUD (EHITUSKULUDE LIIGITAMINE EVS 885:2005) | Puit - Põrand (2), Betoon (2), 00_mineraalvillaplaat - jäik, Soojustus - Plastik Kõva, Raudbetoon - Konstruktsioon | Viimistluskiht 20mm; Tsementkiudbetoonplaat 80mm; PVC-kile; Mürasummutusvill 30mm; Vahtpolüstüroolplaat EPS80 20mm; Monteeritav õõnespaneel 265mm; Viimistluskiht | EI 60 | 2,8 | 0
VL-01 | 1 korrus | 1.14 IfcSlab (vahelagi) (_RKAS BIM + ARCHICAD Classification); 0 TELLIJA KULUD (EHITUSKULUDE LIIGITAMINE EVS 885:2005) | Puit - Põrand, Betoon, 00_mineraalvillaplaat - jäik, Soojustus - Plastik Kõva, Raudbetoon - Konstruktsioon | Viimistluskiht 20mm; Tsementkiudbetoonplaat 80mm; PVC-kile; Mürasummutusvill 30mm; Vahtpolüstüroolplaat EPS80 20mm; Monteeritav õõnespaneel 265mm; Viimistluskiht | EI 60 | 4,8 | 0
VL-01 | 1 korrus | 1.14 IfcSlab (vahelagi) (_RKAS BIM + ARCHICAD Classification) | Puit - Põrand (3), Betoon (2), 00_mineraalvillaplaat - jäik (2), Soojustus - Plastik Kõva (2), Raudbetoon - Konstruktsioon | Viimistluskiht 20mm; Armeeritud betoonplaat 80mm; PVC-kile; Mürasummutusvill 30mm; Vahtpolüstüroolplaat 20mm; Monteeritav õõnespaneel 265mm; Viimistluskiht | EI 60 | 2,4 | 0
VL-01 | 1 korrus | 1.14 IfcSlab (vahelagi) (_RKAS BIM + ARCHICAD Classification); 0 TELLIJA KULUD (EHITUSKULUDE LIIGITAMINE EVS 885:2005) | Puit - Põrand (2), Betoon (2), 00_mineraalvillaplaat - jäik, Soojustus - Plastik Kõva (3), Raudbetoon - Konstruktsioon | Viimistluskiht 20mm; Tsementkiudbetoonplaat 80mm; PVC-kile; Mürasummutusvill 30mm; Vahtpolüstüroolplaat EPS80 20mm; Monteeritav õõnespaneel 265mm; Viimistluskiht | EI 60 | 70,2 | 0
VL-01 | 1,5 korrus | 1.14 IfcSlab (vahelagi) (_RKAS BIM + ARCHICAD Classification) | Puit - Põrand, Betoon, 00_mineraalvillaplaat - jäik, Soojustus - Plastik Kõva, Raudbetoon - Konstruktsioon | Viimistluskiht 20mm; Armeeritud betoonplaat 80mm; PVC-kile; Mürasummutusvill 30mm; Vahtpolüstüroolplaat 20mm; Monteeritav õõnespaneel 265mm; Viimistluskiht | EI 60 | 3,2 | 1 800
VL-01 | 1,5 korrus | 1.14 IfcSlab (vahelagi) (_RKAS BIM + ARCHICAD Classification); 0 TELLIJA KULUD (EHITUSKULUDE LIIGITAMINE EVS 885:2005) | Puit - Põrand, Betoon, 00_mineraalvillaplaat - jäik, Soojustus - Plastik Kõva, Raudbetoon - Konstruktsioon | Viimistluskiht 20mm; Tsementkiudbetoonplaat 80mm; PVC-kile; Mürasummutusvill 30mm; Vahtpolüstüroolplaat EPS80 20mm; Monteeritav õõnespaneel 265mm; Viimistluskiht | EI 60 | 3,4 | 1 800
VL-01 | 1,5 korrus | 1.14 IfcSlab (vahelagi) (_RKAS BIM + ARCHICAD Classification); 0 TELLIJA KULUD (EHITUSKULUDE LIIGITAMINE EVS 885:2005) | Puit - Põrand (4), Betoon (3), 00_mineraalvillaplaat - jäik, Soojustus - Plastik Kõva (2), Raudbetoon - Konstruktsioon | Viimistluskiht 20mm; Tsementkiudbetoonplaat 80mm; PVC-kile; Mürasummutusvill 30mm; Vahtpolüstüroolplaat EPS80 20mm; Monteeritav õõnespaneel 265mm; Viimistluskiht | EI 60 | 77,9 | 1 800
VL-01 | 1,5 korrus | 1.14 IfcSlab (vahelagi) (_RKAS BIM + ARCHICAD Classification); 0 TELLIJA KULUD (EHITUSKULUDE LIIGITAMINE EVS 885:2005) | Puit - Põrand, Betoon, 00_mineraalvillaplaat - jäik, Soojustus - Plastik Kõva (2), Raudbetoon - Konstruktsioon | Viimistluskiht 20mm; Tsementkiudbetoonplaat 80mm; PVC-kile; Mürasummutusvill 30mm; Vahtpolüstüroolplaat EPS80 20mm; Monteeritav õõnespaneel 265mm; Viimistluskiht | EI 60 | 76,5 | 1 800
VL-01 | 1,5 korrus | 1.14 IfcSlab (vahelagi) (_RKAS BIM + ARCHICAD Classification) | Puit - Põrand, Betoon, 00_mineraalvillaplaat - jäik, Soojustus - Plastik Kõva, Raudbetoon - Konstruktsioon | Viimistluskiht 20mm; Armeeritud betoonplaat 80mm; PVC-kile; Mürasummutusvill 30mm; Vahtpolüstüroolplaat 20mm; Monteeritav õõnespaneel 265mm; Viimistluskiht | EI 60 | 7,4 | 1 800
VL-01 | 2 korrus | 1.14 IfcSlab (vahelagi) (_RKAS BIM + ARCHICAD Classification); 0 TELLIJA KULUD (EHITUSKULUDE LIIGITAMINE EVS 885:2005) | Puit - Põrand, Betoon, 00_mineraalvillaplaat - jäik, Soojustus - Plastik Kõva (2), Raudbetoon - Konstruktsioon | Viimistluskiht 20mm; Tsementkiudbetoonplaat 80mm; PVC-kile; Mürasummutusvill 30mm; Vahtpolüstüroolplaat EPS80 20mm; Monteeritav õõnespaneel 265mm; Viimistluskiht | EI 60 | 42,6 | 5 215
VL-01 | 2 korrus | 1.14 IfcSlab (vahelagi) (_RKAS BIM + ARCHICAD Classification); 0 TELLIJA KULUD (EHITUSKULUDE LIIGITAMINE EVS 885:2005) | Puit - Põrand, Betoon, 00_mineraalvillaplaat - jäik, Soojustus - Plastik Kõva, Raudbetoon - Konstruktsioon | Viimistluskiht 20mm; Tsementkiudbetoonplaat 80mm; PVC-kile; Mürasummutusvill 30mm; Vahtpolüstüroolplaat EPS80 20mm; Monteeritav õõnespaneel 265mm; Viimistluskiht | EI 60 | 7,5 | 5 215
VL-01 | 2 korrus | 1.14 IfcSlab (vahelagi) (_RKAS BIM + ARCHICAD Classification); 0 TELLIJA KULUD (EHITUSKULUDE LIIGITAMINE EVS 885:2005) | Puit - Põrand (2), Betoon (2), 00_mineraalvillaplaat - jäik (2), Soojustus - Plastik Kõva (2), Raudbetoon - Konstruktsioon | Viimistluskiht 20mm; Tsementkiudbetoonplaat 80mm; PVC-kile; Mürasummutusvill 30mm; Vahtpolüstüroolplaat EPS80 20mm; Monteeritav õõnespaneel 265mm; Viimistluskiht | nõudeid ei esitata | 56,6 | 5 215
VL-01 | 2 korrus | 1.14 IfcSlab (vahelagi) (_RKAS BIM + ARCHICAD Classification); 0 TELLIJA KULUD (EHITUSKULUDE LIIGITAMINE EVS 885:2005) | Puit - Põrand (12), Betoon (5), 00_mineraalvillaplaat - jäik, Soojustus - Plastik Kõva, Raudbetoon - Konstruktsioon | Viimistluskiht 20mm; Tsementkiudbetoonplaat 80mm; PVC-kile; Mürasummutusvill 30mm; Vahtpolüstüroolplaat EPS80 20mm; Monteeritav õõnespaneel 265mm; Viimistluskiht | EI 60 | 120,9 | 5 215
VL-01 | 2 korrus | 1.14 IfcSlab (vahelagi) (_RKAS BIM + ARCHICAD Classification) | Puit - Põrand (3), Betoon (3), 00_mineraalvillaplaat - jäik, Soojustus - Plastik Kõva (2), Raudbetoon - Konstruktsioon | Viimistluskiht 20mm; Tsementkiudbetoonplaat 80mm; PVC-kile; Mürasummutusvill 30mm; Vahtpolüstüroolplaat EPS80 20mm; Monteeritav õõnespaneel 265mm; Viimistluskiht | EI 60 | 119,1 | 5 215
VL-01 | 2 korrus | 1.14 IfcSlab (vahelagi) (_RKAS BIM + ARCHICAD Classification); 0 TELLIJA KULUD (EHITUSKULUDE LIIGITAMINE EVS 885:2005) | Puit - Põrand, Betoon, 00_mineraalvillaplaat - jäik, Soojustus - Plastik Kõva, Raudbetoon - Konstruktsioon | Viimistluskiht 20mm; Tsementkiudbetoonplaat 80mm; PVC-kile; Mürasummutusvill 30mm; Vahtpolüstüroolplaat EPS80 20mm; Monteeritav õõnespaneel 265mm; Viimistluskiht | EI 60 | 8,3 | 5 215

# IfcSlab: VL-02 (2)
In: 2 korrus
Type - ElementType: Element type VL-02; PredefinedType: FLOOR
Classification: 1.14 IfcSlab (vahelagi) (_RKAS BIM + ARCHICAD Classification); 0 TELLIJA KULUD (EHITUSKULUDE LIIGITAMINE EVS 885:2005)
Arhitektuur - 01 Nimetus: Vahelagi; 03 Tähistus: VL-02; 05 Asukoht: Interior; 06 Kandevelementide eristatus: Load-Bearing Element; 07 Helipidavus: 48 dB; 08 Soojusläbivus (U-arv): -
Ehituskonstruktsioonid - 01 Nimetus: VL-02; 02 Materjal: Puit - Põrand; Betoon; Membraan - Veekindel; 00_mineraalvillaplaat - jäik; Soojustus - Plastik Kõva; Raudbetoon - Konstruktsioon; 03 Tähistus või ristlõige: VL-02; 12 Alumine kõrgusmärk: 5 215
AC_Pset_RenovationAndPhasing - Renovation Status: New
Pset_SlabCommon - LoadBearing: yes; IsExternal: no
Name | Material | 02 Materjal | 04 Tulepüsivus | 06 Maht (kubatuur)
VL-02 | Puit - Põrand (2), Betoon (2), 00_mineraalvillaplaat - jäik, Soojustus - Plastik Kõva, Raudbetoon - Konstruktsioon | Viimistluskiht 20mm; Armeeritud betoonplaat 80mm; PVC-kile; Mürasummutusvill 30mm; Vahtpolüstüroolplaat 20mm; Monteeritav õõnespaneel 320mm; Viimistluskiht | EI 60 | 72,6
VL-02 | Puit - Põrand, Betoon, 00_mineraalvillaplaat - jäik, Soojustus - Plastik Kõva, Raudbetoon - Konstruktsioon | Viimistluskiht 20mm; Tsementkiudbetoonplaat 80mm; PVC-kile; Mürasummutusvill 30mm; Vahtpolüstüroolplaat EPS80 20mm; Monteeritav õõnespaneel 320mm; Viimistluskiht | nõudeid ei esitata | 82,8

# IfcSlab: VL-03
In: 1,5 korrus
Type - ElementType: Element type VL-03; PredefinedType: FLOOR
Classification: 1.14 IfcSlab (vahelagi) (_RKAS BIM + ARCHICAD Classification); Material: Kivi - Viimistlus (3), Raudbetoon - Konstruktsioon
Arhitektuur - 01 Nimetus: Vahelagi; 02 Materjal: Viimistluskiht; Monoliitne betoonplaat 200mm; Viimistluskiht; 03 Tähistus: VL-03; 04 Tulepüsivus: nõudeid ei esitata; 05 Asukoht: Interior; 06 Kandevelementide eristatus: Load-Bearing Element; 07 Helipidavus: -; 08 Soojusläbivus (U-arv): -
Ehituskonstruktsioonid - 01 Nimetus: VL-03; 02 Materjal: Kivi - Viimistlus; Raudbetoon - Konstruktsioon; 03 Tähistus või ristlõige: VL-03; 06 Maht (kubatuur): 4,7; 12 Alumine kõrgusmärk: 2 500
AC_Pset_RenovationAndPhasing - Renovation Status: New
Pset_SlabCommon - LoadBearing: yes; IsExternal: no

# IfcStair (142)
AC_Pset_RenovationAndPhasing - Renovation Status: New
Name | In | Classification | IsExternal | 03 Tähistus või ristlõige | 06 Maht (kubatuur) | 12 Alumine kõrgusmärk | Material
T-08 | -1 korrus | 1.16 IfcStair (trepp) (_RKAS BIM + ARCHICAD Classification) | no | T-08 | 2,1 | -3 415 | Pset_StairCommon - NumberOfRiser: 18; NumberOfTreads: 17; RiserHeight: 189.722 mm; RequiredHeadroom: 2200 mm
GENEERILINE - KONSTRUKTRIOON | -1 korrus | 1.16 IfcStair (trepp) (_RKAS BIM + ARCHICAD Classification) |  | T-08 | 2,1 | -190 | GENEERILINE - KONSTRUKTRIOON
T-03 | 0 korrus | 1.16 IfcStair (trepp) (_RKAS BIM + ARCHICAD Classification) | no | T-03 | 14,9 | -1 615 | Pset_StairCommon - NumberOfRiser: 8; NumberOfTreads: 7; RiserHeight: 426.875 mm; RequiredHeadroom: 2200 mm
GENEERILINE - KONSTRUKTRIOON | 0 korrus | 1.16 IfcStair (trepp) (_RKAS BIM + ARCHICAD Classification) |  | T-03 | 14,9 | 1 373 | GENEERILINE - KONSTRUKTRIOON
T-05 | 0 korrus | 1.16 IfcStair (trepp) (_RKAS BIM + ARCHICAD Classification) | no | T-05 | 1,8 | -1 615 | Pset_StairCommon - NumberOfRiser: 20; NumberOfTreads: 19; RiserHeight: 170.75 mm; RequiredHeadroom: 2200 mm
T-05 | 0 korrus | 1.16 IfcStair (trepp) (_RKAS BIM + ARCHICAD Classification) |  | T-05 | 0,3 | 1 629 | GENEERILINE - KONSTRUKTRIOON
GENEERILINE - KONSTRUKTRIOON | 0 korrus | 1.16 IfcStair (trepp) (_RKAS BIM + ARCHICAD Classification) |  | T-05 | 1,5 | 1 629 | GENEERILINE - KONSTRUKTRIOON
T-10 | 0 korrus | 1.16 IfcStair (trepp) (_RKAS BIM + ARCHICAD Classification) | no | T-10 | 2,0 | -1 615 | Pset_StairCommon - NumberOfRiser: 10; NumberOfTreads: 9; RiserHeight: 161.5 mm; RequiredHeadroom: 2200 mm
GENEERILINE - KONSTRUKTRIOON | 0 korrus | 1.16 IfcStair (trepp) (_RKAS BIM + ARCHICAD Classification) |  | T-10 | 2,0 | -162 | GENEERILINE - KONSTRUKTRIOON
T-06 | 0 korrus | 1.16 IfcStair (trepp) (_RKAS BIM + ARCHICAD Classification) | no | T-06 | 0,6 | -3 415 | Pset_StairCommon - NumberOfRiser: 8; NumberOfTreads: 7; RiserHeight: 225 mm; RequiredHeadroom: 2200 mm
GENEERILINE - KONSTRUKTRIOON | 0 korrus | 1.16 IfcStair (trepp) (_RKAS BIM + ARCHICAD Classification) |  | T-06 | 0,6 | -1 840 | GENEERILINE - KONSTRUKTRIOON
GENEERILINE - KONSTRUKTRIOON | 0 korrus | 1.16 IfcStair (trepp) (_RKAS BIM + ARCHICAD Classification) | no | T-03 | 0,2 | -1 473 | GENEERILINE - KONSTRUKTRIOON
GENEERILINE - KONSTRUKTRIOON | 0 korrus | 1.16 IfcStair (trepp) (_RKAS BIM + ARCHICAD Classification) | no | T-03 | 0,1 | -1 331 | GENEERILINE - KONSTRUKTRIOON
GENEERILINE - KONSTRUKTRIOON | 0 korrus | 1.16 IfcStair (trepp) (_RKAS BIM + ARCHICAD Classification) | no | T-03 | 0,2 | -1 046 | GENEERILINE - KONSTRUKTRIOON
GENEERILINE - KONSTRUKTRIOON | 0 korrus | 1.16 IfcStair (trepp) (_RKAS BIM + ARCHICAD Classification) | no | T-03 | 0,1 | -904 | GENEERILINE - KONSTRUKTRIOON
Vineer | 1 korrus | 1.16 IfcStair (trepp) (_RKAS BIM + ARCHICAD Classification) | no | T-01 | 0,2 | 600 | Vineer
Vineer | 1 korrus | 1.16 IfcStair (trepp) (_RKAS BIM + ARCHICAD Classification) | no | T-01 | 0,1 | 750 | Vineer
Vineer | 1 korrus | 1.16 IfcStair (trepp) (_RKAS BIM + ARCHICAD Classification) | no | T-01 | 0,2 | 150 | Vineer
Vineer | 1 korrus | 1.16 IfcStair (trepp) (_RKAS BIM + ARCHICAD Classification) | no | T-01 | 0,1 | 300 | Vineer
Vineer | 1 korrus | 1.16 IfcStair (trepp) (_RKAS BIM + ARCHICAD Classification) | no | T-01 | 0,1 | 1 200 | Vineer
Vineer | 1 korrus | 1.16 IfcStair (trepp) (_RKAS BIM + ARCHICAD Classification) | no | T-01 | 0,2 | 1 050 | Vineer
T-09 | 1 korrus | 0 TELLIJA KULUD (EHITUSKULUDE LIIGITAMINE EVS 885:2005); 1.16 IfcStair (trepp) (_RKAS BIM + ARCHICAD Classification) | no | T-09 | 1,3 | 0 | Pset_StairCommon - NumberOfRiser: 15; NumberOfTreads: 14; RiserHeight: 166.667 mm; RequiredHeadroom: 2200 mm
GENEERILINE - KONSTRUKTRIOON | 1 korrus | 1.16 IfcStair (trepp) (_RKAS BIM + ARCHICAD Classification) |  | T-09 | 1,3 | 2 333 | GENEERILINE - KONSTRUKTRIOON
T-13 | 1 korrus | 1.16 IfcStair (trepp) (_RKAS BIM + ARCHICAD Classification) | no | T-13 | 0,5 | -600 | Pset_StairCommon - NumberOfRiser: 4; NumberOfTreads: 3; RiserHeight: 150 mm; RequiredHeadroom: 2200 mm
GENEERILINE - KONSTRUKTRIOON | 1 korrus | 1.16 IfcStair (trepp) (_RKAS BIM + ARCHICAD Classification) |  | T-13 | 0,5 | -150 | GENEERILINE - KONSTRUKTRIOON
T-04 | 1 korrus | 1.16 IfcStair (trepp) (_RKAS BIM + ARCHICAD Classification) | no | T-04 | 4,5 | 0 | Pset_StairCommon - NumberOfRiser: 30; NumberOfTreads: 29; RiserHeight: 173.833 mm; RequiredHeadroom: 2200 mm
GENEERILINE - KONSTRUKTRIOON | 1 korrus | 1.16 IfcStair (trepp) (_RKAS BIM + ARCHICAD Classification) |  | T-04 | 2,2 | 2 608 | GENEERILINE - KONSTRUKTRIOON
GENEERILINE - KONSTRUKTRIOON | 1 korrus | 1.16 IfcStair (trepp) (_RKAS BIM + ARCHICAD Classification) |  | T-04 | 0,4 | 2 781 | GENEERILINE - KONSTRUKTRIOON
GENEERILINE - KONSTRUKTRIOON | 1 korrus | 1.16 IfcStair (trepp) (_RKAS BIM + ARCHICAD Classification) |  | T-04 | 1,9 | 5 041 | GENEERILINE - KONSTRUKTRIOON
GENEERILINE - KONSTRUKTRIOON | 1 korrus | 1.16 IfcStair (trepp) (_RKAS BIM + ARCHICAD Classification) | no | T-03 | 0,1 | 1 657 | GENEERILINE - KONSTRUKTRIOON
GENEERILINE - KONSTRUKTRIOON | 1 korrus | 1.16 IfcStair (trepp) (_RKAS BIM + ARCHICAD Classification) | no | T-03 | 0,2 | 1 515 | GENEERILINE - KONSTRUKTRIOON
GENEERILINE - KONSTRUKTRIOON | 1 korrus | 1.16 IfcStair (trepp) (_RKAS BIM + ARCHICAD Classification) | no | T-03 | 0,2 | -619 | GENEERILINE - KONSTRUKTRIOON
GENEERILINE - KONSTRUKTRIOON | 1 korrus | 1.16 IfcStair (trepp) (_RKAS BIM + ARCHICAD Classification) | no | T-03 | 0,1 | -477 | GENEERILINE - KONSTRUKTRIOON
GENEERILINE - KONSTRUKTRIOON | 1 korrus | 1.16 IfcStair (trepp) (_RKAS BIM + ARCHICAD Classification) | no | T-03 | 0,2 | -192 | GENEERILINE - KONSTRUKTRIOON
GENEERILINE - KONSTRUKTRIOON | 1 korrus | 1.16 IfcStair (trepp) (_RKAS BIM + ARCHICAD Classification) | no | T-03 | 0,1 | -50 | GENEERILINE - KONSTRUKTRIOON
GENEERILINE - KONSTRUKTRIOON | 1 korrus | 1.16 IfcStair (trepp) (_RKAS BIM + ARCHICAD Classification) | no | T-03 | 0,2 | 235 | GENEERILINE - KONSTRUKTRIOON
GENEERILINE - KONSTRUKTRIOON | 1 korrus | 1.16 IfcStair (trepp) (_RKAS BIM + ARCHICAD Classification) | no | T-03 | 0,1 | 377 | GENEERILINE - KONSTRUKTRIOON
GENEERILINE - KONSTRUKTRIOON | 1 korrus | 1.16 IfcStair (trepp) (_RKAS BIM + ARCHICAD Classification) | no | T-03 | 0,2 | 661 | GENEERILINE - KONSTRUKTRIOON
GENEERILINE - KONSTRUKTRIOON | 1 korrus | 1.16 IfcStair (trepp) (_RKAS BIM + ARCHICAD Classification) | no | T-03 | 0,1 | 803 | GENEERILINE - KONSTRUKTRIOON
GENEERILINE - KONSTRUKTRIOON | 1 korrus | 1.16 IfcStair (trepp) (_RKAS BIM + ARCHICAD Classification) | no | T-03 | 0,2 | 1 088 | GENEERILINE - KONSTRUKTRIOON
GENEERILINE - KONSTRUKTRIOON | 1 korrus | 1.16 IfcStair (trepp) (_RKAS BIM + ARCHICAD Classification) | no | T-03 | 0,1 | 1 230 | GENEERILINE - KONSTRUKTRIOON
T-12 | 1 korrus | 1.16 IfcStair (trepp) (_RKAS BIM + ARCHICAD Classification) | no | T-12 | 0,7 | -10 | Pset_StairCommon - NumberOfRiser: 20; NumberOfTreads: 19; RiserHeight: 90 mm; RequiredHeadroom: 2200 mm
2 x T-12 | 1 korrus | 1.16 IfcStair (trepp) (_RKAS BIM + ARCHICAD Classification) |  | T-12 | 0,0 | 1 640 | Teras (musta värvi)
T-12 | 1 korrus | 1.16 IfcStair (trepp) (_RKAS BIM + ARCHICAD Classification) |  | T-12 | 0,0 | 80 | Teras (musta värvi) | Pset_StairCommon - TreadLength: 490 mm
T-12 | 1 korrus | 1.16 IfcStair (trepp) (_RKAS BIM + ARCHICAD Classification) |  | T-12 | 0,0 | 170 | Teras (musta värvi) | Pset_StairCommon - TreadLength: 490 mm
T-12 | 1 korrus | 1.16 IfcStair (trepp) (_RKAS BIM + ARCHICAD Classification) |  | T-12 | 0,0 | 260 | Teras (musta värvi) | Pset_StairCommon - TreadLength: 490 mm
T-12 | 1 korrus | 1.16 IfcStair (trepp) (_RKAS BIM + ARCHICAD Classification) |  | T-12 | 0,0 | 350 | Teras (musta värvi) | Pset_StairCommon - TreadLength: 490 mm
T-12 | 1 korrus | 1.16 IfcStair (trepp) (_RKAS BIM + ARCHICAD Classification) |  | T-12 | 0,0 | 440 | Teras (musta värvi) | Pset_StairCommon - TreadLength: 490 mm
T-12 | 1 korrus | 1.16 IfcStair (trepp) (_RKAS BIM + ARCHICAD Classification) |  | T-12 | 0,0 | 530 | Teras (musta värvi) | Pset_StairCommon - TreadLength: 490 mm
T-12 | 1 korrus | 1.16 IfcStair (trepp) (_RKAS BIM + ARCHICAD Classification) |  | T-12 | 0,0 | 620 | Teras (musta värvi) | Pset_StairCommon - TreadLength: 490 mm
T-12 | 1 korrus | 1.16 IfcStair (trepp) (_RKAS BIM + ARCHICAD Classification) |  | T-12 | 0,0 | 710 | Teras (musta värvi) | Pset_StairCommon - TreadLength: 490 mm
T-12 | 1 korrus | 1.16 IfcStair (trepp) (_RKAS BIM + ARCHICAD Classification) |  | T-12 | 0,0 | 800 | Teras (musta värvi) | Pset_StairCommon - TreadLength: 490 mm
T-12 | 1 korrus | 1.16 IfcStair (trepp) (_RKAS BIM + ARCHICAD Classification) |  | T-12 | 0,0 | 890 | Teras (musta värvi) | Pset_StairCommon - TreadLength: 490 mm
T-12 | 1 korrus | 1.16 IfcStair (trepp) (_RKAS BIM + ARCHICAD Classification) |  | T-12 | 0,0 | 980 | Teras (musta värvi) | Pset_StairCommon - TreadLength: 490 mm
T-12 | 1 korrus | 1.16 IfcStair (trepp) (_RKAS BIM + ARCHICAD Classification) |  | T-12 | 0,0 | 1 070 | Teras (musta värvi) | Pset_StairCommon - TreadLength: 490 mm
T-12 | 1 korrus | 1.16 IfcStair (trepp) (_RKAS BIM + ARCHICAD Classification) |  | T-12 | 0,0 | 1 160 | Teras (musta värvi) | Pset_StairCommon - TreadLength: 490 mm
T-12 | 1 korrus | 1.16 IfcStair (trepp) (_RKAS BIM + ARCHICAD Classification) |  | T-12 | 0,0 | 1 250 | Teras (musta värvi) | Pset_StairCommon - TreadLength: 490 mm
T-12 | 1 korrus | 1.16 IfcStair (trepp) (_RKAS BIM + ARCHICAD Classification) |  | T-12 | 0,0 | 1 340 | Teras (musta värvi) | Pset_StairCommon - TreadLength: 490 mm
T-12 | 1 korrus | 1.16 IfcStair (trepp) (_RKAS BIM + ARCHICAD Classification) |  | T-12 | 0,0 | 1 430 | Teras (musta värvi) | Pset_StairCommon - TreadLength: 490 mm
T-12 | 1 korrus | 1.16 IfcStair (trepp) (_RKAS BIM + ARCHICAD Classification) |  | T-12 | 0,0 | 1 520 | Teras (musta värvi) | Pset_StairCommon - TreadLength: 490 mm
T-12 | 1 korrus | 1.16 IfcStair (trepp) (_RKAS BIM + ARCHICAD Classification) |  | T-12 | 0,0 | 1 610 | Teras (musta värvi) | Pset_StairCommon - TreadLength: 490 mm
T-12 | 1 korrus | 1.16 IfcStair (trepp) (_RKAS BIM + ARCHICAD Classification) |  | T-12 | 0,0 | 1 700 | Teras (musta värvi) | Pset_StairCommon - TreadLength: 450 mm
2 x Teras (musta värvi) | 1 korrus | 1.16 IfcStair (trepp) (_RKAS BIM + ARCHICAD Classification) | yes | T-12 | 0,1 | 10 | Teras (musta värvi)
T-11 | 1 korrus | 1.16 IfcStair (trepp) (_RKAS BIM + ARCHICAD Classification) | no | T-11 | 0,6 | 120 | Pset_StairCommon - NumberOfRiser: 29; NumberOfTreads: 28; RiserHeight: 175 mm; RequiredHeadroom: 2200 mm
T-11 | 1 korrus | 1.16 IfcStair (trepp) (_RKAS BIM + ARCHICAD Classification) |  | T-11 | 0,0 | 3 045 | Teras (musta värvi) (2)
T-11 | 1 korrus | 1.16 IfcStair (trepp) (_RKAS BIM + ARCHICAD Classification) |  | T-11 | 0,0 | 3 220 | Teras (musta värvi) (2)
T-11 | 1 korrus | 1.16 IfcStair (trepp) (_RKAS BIM + ARCHICAD Classification) |  | T-11 | 0,0 | 4 970 | Teras (musta värvi) (2)
T-11 | 1 korrus | 1.16 IfcStair (trepp) (_RKAS BIM + ARCHICAD Classification) |  | T-11 | 0,0 | 295 | Teras (musta värvi) | Pset_StairCommon - TreadLength: 320 mm
T-11 | 1 korrus | 1.16 IfcStair (trepp) (_RKAS BIM + ARCHICAD Classification) |  | T-11 | 0,0 | 470 | Teras (musta värvi) | Pset_StairCommon - TreadLength: 320 mm
T-11 | 1 korrus | 1.16 IfcStair (trepp) (_RKAS BIM + ARCHICAD Classification) |  | T-11 | 0,0 | 645 | Teras (musta värvi) | Pset_StairCommon - TreadLength: 320 mm
T-11 | 1 korrus | 1.16 IfcStair (trepp) (_RKAS BIM + ARCHICAD Classification) |  | T-11 | 0,0 | 820 | Teras (musta värvi) | Pset_StairCommon - TreadLength: 320 mm
T-11 | 1 korrus | 1.16 IfcStair (trepp) (_RKAS BIM + ARCHICAD Classification) |  | T-11 | 0,0 | 995 | Teras (musta värvi) | Pset_StairCommon - TreadLength: 320 mm
T-11 | 1 korrus | 1.16 IfcStair (trepp) (_RKAS BIM + ARCHICAD Classification) |  | T-11 | 0,0 | 1 170 | Teras (musta värvi) | Pset_StairCommon - TreadLength: 320 mm
T-11 | 1 korrus | 1.16 IfcStair (trepp) (_RKAS BIM + ARCHICAD Classification) |  | T-11 | 0,0 | 1 345 | Teras (musta värvi) | Pset_StairCommon - TreadLength: 320 mm
T-11 | 1 korrus | 1.16 IfcStair (trepp) (_RKAS BIM + ARCHICAD Classification) |  | T-11 | 0,0 | 1 520 | Teras (musta värvi) | Pset_StairCommon - TreadLength: 320 mm
T-11 | 1 korrus | 1.16 IfcStair (trepp) (_RKAS BIM + ARCHICAD Classification) |  | T-11 | 0,0 | 1 695 | Teras (musta värvi) | Pset_StairCommon - TreadLength: 320 mm
T-11 | 1 korrus | 1.16 IfcStair (trepp) (_RKAS BIM + ARCHICAD Classification) |  | T-11 | 0,0 | 1 870 | Teras (musta värvi) | Pset_StairCommon - TreadLength: 320 mm
T-11 | 1 korrus | 1.16 IfcStair (trepp) (_RKAS BIM + ARCHICAD Classification) |  | T-11 | 0,0 | 2 045 | Teras (musta värvi) | Pset_StairCommon - TreadLength: 320 mm
T-11 | 1 korrus | 1.16 IfcStair (trepp) (_RKAS BIM + ARCHICAD Classification) |  | T-11 | 0,0 | 2 220 | Teras (musta värvi) | Pset_StairCommon - TreadLength: 320 mm
T-11 | 1 korrus | 1.16 IfcStair (trepp) (_RKAS BIM + ARCHICAD Classification) |  | T-11 | 0,0 | 2 395 | Teras (musta värvi) | Pset_StairCommon - TreadLength: 320 mm
T-11 | 1 korrus | 1.16 IfcStair (trepp) (_RKAS BIM + ARCHICAD Classification) |  | T-11 | 0,0 | 2 570 | Teras (musta värvi) | Pset_StairCommon - TreadLength: 320 mm
T-11 | 1 korrus | 1.16 IfcStair (trepp) (_RKAS BIM + ARCHICAD Classification) |  | T-11 | 0,0 | 2 745 | Teras (musta värvi) | Pset_StairCommon - TreadLength: 320 mm
T-11 | 1 korrus | 1.16 IfcStair (trepp) (_RKAS BIM + ARCHICAD Classification) |  | T-11 | 0,0 | 2 920 | Teras (musta värvi) | Pset_StairCommon - TreadLength: 320 mm
T-11 | 1 korrus | 1.16 IfcStair (trepp) (_RKAS BIM + ARCHICAD Classification) |  | T-11 | 0,0 | 3 095 | Teras (musta värvi) | Pset_StairCommon - TreadLength: 320 mm
T-11 | 1 korrus | 1.16 IfcStair (trepp) (_RKAS BIM + ARCHICAD Classification) |  | T-11 | 0,1 | 3 270 | Teras (musta värvi) | Pset_StairCommon - TreadLength: 910.167 mm
T-11 | 1 korrus | 1.16 IfcStair (trepp) (_RKAS BIM + ARCHICAD Classification) |  | T-11 | 0,0 | 3 445 | Teras (musta värvi) | Pset_StairCommon - TreadLength: 320 mm
T-11 | 1 korrus | 1.16 IfcStair (trepp) (_RKAS BIM + ARCHICAD Classification) |  | T-11 | 0,0 | 3 620 | Teras (musta värvi) | Pset_StairCommon - TreadLength: 320 mm
T-11 | 1 korrus | 1.16 IfcStair (trepp) (_RKAS BIM + ARCHICAD Classification) |  | T-11 | 0,0 | 3 795 | Teras (musta värvi) | Pset_StairCommon - TreadLength: 320 mm
T-11 | 1 korrus | 1.16 IfcStair (trepp) (_RKAS BIM + ARCHICAD Classification) |  | T-11 | 0,0 | 3 970 | Teras (musta värvi) | Pset_StairCommon - TreadLength: 320 mm
T-11 | 1 korrus | 1.16 IfcStair (trepp) (_RKAS BIM + ARCHICAD Classification) |  | T-11 | 0,0 | 4 145 | Teras (musta värvi) | Pset_StairCommon - TreadLength: 320 mm
T-11 | 1 korrus | 1.16 IfcStair (trepp) (_RKAS BIM + ARCHICAD Classification) |  | T-11 | 0,0 | 4 320 | Teras (musta värvi) | Pset_StairCommon - TreadLength: 320 mm
T-11 | 1 korrus | 1.16 IfcStair (trepp) (_RKAS BIM + ARCHICAD Classification) |  | T-11 | 0,0 | 4 495 | Teras (musta värvi) | Pset_StairCommon - TreadLength: 320 mm
T-11 | 1 korrus | 1.16 IfcStair (trepp) (_RKAS BIM + ARCHICAD Classification) |  | T-11 | 0,0 | 4 670 | Teras (musta värvi) | Pset_StairCommon - TreadLength: 320 mm
T-11 | 1 korrus | 1.16 IfcStair (trepp) (_RKAS BIM + ARCHICAD Classification) |  | T-11 | 0,0 | 4 845 | Teras (musta värvi) | Pset_StairCommon - TreadLength: 320 mm
T-11 | 1 korrus | 1.16 IfcStair (trepp) (_RKAS BIM + ARCHICAD Classification) |  | T-11 | 0,0 | 5 020 | Teras (musta värvi) | Pset_StairCommon - TreadLength: 270 mm
Vineer | 1,5 korrus | 1.16 IfcStair (trepp) (_RKAS BIM + ARCHICAD Classification) | no | T-01 | 5,0 | 1 800 | Vineer
Vineer | 1,5 korrus | 1.16 IfcStair (trepp) (_RKAS BIM + ARCHICAD Classification) | no | T-02 | 0,1 | 2 369 | Vineer
Vineer | 1,5 korrus | 1.16 IfcStair (trepp) (_RKAS BIM + ARCHICAD Classification) | no | T-02 | 0,1 | 2 084 | Vineer
Vineer | 1,5 korrus | 1.16 IfcStair (trepp) (_RKAS BIM + ARCHICAD Classification) | no | T-01 | 0,1 | 1 650 | Vineer
Vineer | 1,5 korrus | 1.16 IfcStair (trepp) (_RKAS BIM + ARCHICAD Classification) | no | T-02 | 0,1 | 1 942 | Vineer
Vineer | 1,5 korrus | 1.16 IfcStair (trepp) (_RKAS BIM + ARCHICAD Classification) | no | T-01 | 0,2 | 1 500 | Vineer
Vineer | 1,5 korrus | 1.16 IfcStair (trepp) (_RKAS BIM + ARCHICAD Classification) | no | T-02 | 0,1 | 2 938 | Vineer
Vineer | 1,5 korrus | 1.16 IfcStair (trepp) (_RKAS BIM + ARCHICAD Classification) | no | T-02 | 0,1 | 2 796 | Vineer
Vineer | 1,5 korrus | 1.16 IfcStair (trepp) (_RKAS BIM + ARCHICAD Classification) | no | T-02 | 0,1 | 2 511 | Vineer
Teras (musta värvi) | 1,5 korrus | 1.16 IfcStair (trepp) (_RKAS BIM + ARCHICAD Classification) | yes | T-12 | 0,8 | 1 780 | Teras (musta värvi)
Vineer | 1,5 korrus | 1.16 IfcStair (trepp) (_RKAS BIM + ARCHICAD Classification) | no | T-01 | 6,1 | 1 350 | Vineer
Vineer | 1,5 korrus | 1.16 IfcStair (trepp) (_RKAS BIM + ARCHICAD Classification) | no | T-01 | 6,9 | 450 | Vineer
Vineer | 1,5 korrus | 1.16 IfcStair (trepp) (_RKAS BIM + ARCHICAD Classification) | no | T-01 | 5,6 | 900 | Vineer
Vineer | 1,5 korrus | 1.16 IfcStair (trepp) (_RKAS BIM + ARCHICAD Classification) | no | T-02 | 3,8 | 2 227 | Vineer
Vineer | 1,5 korrus | 1.16 IfcStair (trepp) (_RKAS BIM + ARCHICAD Classification) | no | T-02 | 4,1 | 2 654 | Vineer
VL-03 | 2 korrus | 1.16 IfcStair (trepp) (_RKAS BIM + ARCHICAD Classification) | no | T-07 | 0,8 | 3 615 | Raudbetoon - Konstruktsioon, Kivi - Viimistlus
VL-03 | 2 korrus | 1.16 IfcStair (trepp) (_RKAS BIM + ARCHICAD Classification) | no | T-07 | 0,6 | 4 415 | Raudbetoon - Konstruktsioon, Kivi - Viimistlus
VL-03 | 2 korrus | 1.16 IfcStair (trepp) (_RKAS BIM + ARCHICAD Classification) | no | T-07 | 0,6 | 4 015 | Raudbetoon - Konstruktsioon, Kivi - Viimistlus
Vineer | 2 korrus | 1.16 IfcStair (trepp) (_RKAS BIM + ARCHICAD Classification) | no | T-02 | 0,1 | 4 503 | Vineer
Vineer | 2 korrus | 1.16 IfcStair (trepp) (_RKAS BIM + ARCHICAD Classification) | no | T-02 | 0,1 | 4 645 | Vineer
Vineer | 2 korrus | 1.16 IfcStair (trepp) (_RKAS BIM + ARCHICAD Classification) | no | T-02 | 0,1 | 5 072 | Vineer
Vineer | 2 korrus | 1.16 IfcStair (trepp) (_RKAS BIM + ARCHICAD Classification) | no | T-02 | 0,1 | 4 930 | Vineer
Vineer | 2 korrus | 1.16 IfcStair (trepp) (_RKAS BIM + ARCHICAD Classification) | no | T-02 | 0,1 | 4 218 | Vineer
Vineer | 2 korrus | 1.16 IfcStair (trepp) (_RKAS BIM + ARCHICAD Classification) | no | T-02 | 0,1 | 4 076 | Vineer
Vineer | 2 korrus | 1.16 IfcStair (trepp) (_RKAS BIM + ARCHICAD Classification) | no | T-02 | 0,1 | 3 650 | Vineer
Vineer | 2 korrus | 1.16 IfcStair (trepp) (_RKAS BIM + ARCHICAD Classification) | no | T-02 | 0,1 | 3 792 | Vineer
Vineer | 2 korrus | 1.16 IfcStair (trepp) (_RKAS BIM + ARCHICAD Classification) | no | T-02 | 0,1 | 3 365 | Vineer
Vineer | 2 korrus | 1.16 IfcStair (trepp) (_RKAS BIM + ARCHICAD Classification) | no | T-02 | 0,1 | 3 223 | Vineer
GENEERILINE - KONSTRUKTRIOON | 2 korrus | 1.16 IfcStair (trepp) (_RKAS BIM + ARCHICAD Classification) | no | T-07 | 0,1 | 4 948 | GENEERILINE - KONSTRUKTRIOON
GENEERILINE - KONSTRUKTRIOON | 2 korrus | 1.16 IfcStair (trepp) (_RKAS BIM + ARCHICAD Classification) | no | T-07 | 0,2 | 5 081 | GENEERILINE - KONSTRUKTRIOON
GENEERILINE - KONSTRUKTRIOON | 2 korrus | 1.16 IfcStair (trepp) (_RKAS BIM + ARCHICAD Classification) | no | T-07 | 0,2 | 3 881 | GENEERILINE - KONSTRUKTRIOON
GENEERILINE - KONSTRUKTRIOON | 2 korrus | 1.16 IfcStair (trepp) (_RKAS BIM + ARCHICAD Classification) | no | T-07 | 0,1 | 4 548 | GENEERILINE - KONSTRUKTRIOON
GENEERILINE - KONSTRUKTRIOON | 2 korrus | 1.16 IfcStair (trepp) (_RKAS BIM + ARCHICAD Classification) | no | T-07 | 0,1 | 3 748 | GENEERILINE - KONSTRUKTRIOON
GENEERILINE - KONSTRUKTRIOON | 2 korrus | 1.16 IfcStair (trepp) (_RKAS BIM + ARCHICAD Classification) | no | T-07 | 0,1 | 4 148 | GENEERILINE - KONSTRUKTRIOON
Vineer | 2 korrus | 1.16 IfcStair (trepp) (_RKAS BIM + ARCHICAD Classification) | no | T-02 | 3,8 | 3 081 | Vineer
Vineer | 2 korrus | 1.16 IfcStair (trepp) (_RKAS BIM + ARCHICAD Classification) | no | T-02 | 4,0 | 4 788 | Vineer
GENEERILINE - KONSTRUKTRIOON | 2 korrus | 1.16 IfcStair (trepp) (_RKAS BIM + ARCHICAD Classification) | no | T-07 | 0,2 | 4 681 | GENEERILINE - KONSTRUKTRIOON
Vineer | 2 korrus | 1.16 IfcStair (trepp) (_RKAS BIM + ARCHICAD Classification) | no | T-02 | 4,1 | 3 508 | Vineer
Vineer | 2 korrus | 1.16 IfcStair (trepp) (_RKAS BIM + ARCHICAD Classification) | no | T-02 | 3,8 | 4 362 | Vineer
Vineer | 2 korrus | 1.16 IfcStair (trepp) (_RKAS BIM + ARCHICAD Classification) | no | T-02 | 4,1 | 3 935 | Vineer
GENEERILINE - KONSTRUKTRIOON | 2 korrus | 1.16 IfcStair (trepp) (_RKAS BIM + ARCHICAD Classification) | no | T-07 | 0,2 | 4 281 | GENEERILINE - KONSTRUKTRIOON
SS-12 | 2 korrus | 1.16 IfcStair (trepp) (_RKAS BIM + ARCHICAD Classification) | no | T-07 | 0,1 | 4 415 | Raudbetoon - Konstruktsioon
SS-12 | 2 korrus | 1.16 IfcStair (trepp) (_RKAS BIM + ARCHICAD Classification) | no | T-07 | 0,1 | 4 015 | Raudbetoon - Konstruktsioon
SS-12 | 2 korrus | 1.16 IfcStair (trepp) (_RKAS BIM + ARCHICAD Classification) | no | T-07 | 0,0 | 3 615 | Raudbetoon - Konstruktsioon
VL-03 | 2 korrus | 1.16 IfcStair (trepp) (_RKAS BIM + ARCHICAD Classification) | no | T-07 | 0,4 | 4 815 | Kivi - Viimistlus, Raudbetoon - Konstruktsioon

# IfcTransportElement: KONE_Buffer_Extension_Single_Pillar_KM841600_CAR:KONE_Buffer_Extension_Single_Pillar_KM841600:300901
In: 0 korrus
Type - ElementType: Element type KONE_Buffer_Extension_Single_Pillar_KM841600_CAR:KONE_Buffer_Extension_Single_Pillar_KM841600:300901
OperationType: ELEVATOR; CapacityByWeight: 0 kg; CapacityByNumber: 0; Classification: 1.17 IfcTransportElement (lift) (_RKAS BIM + ARCHICAD Classification); Material: IFC Building Material (4)
Constraints - Moves With Nearby Elements: no; Offset: -1400 mm
Dimensions - Area: 0.217802 m2; DIM_BUFFER_EXT_HEIGHT_HE: 897 mm; Volume: 0.000910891 m3
Other - Category: Specialty Equipment; Family: KONE_Buffer_Extension_Single_Pillar_KM841600_CAR: KONE_Buffer_Extension_Single_Pillar_KM841600; Family and Type: KONE_Buffer_Extension_Single_Pillar_KM841600_CAR: KONE_Buffer_Extension_Single_Pillar_KM841600; Type: KONE_Buffer_Extension_Single_Pillar_KM841600_CAR: KONE_Buffer_Extension_Single_Pillar_KM841600; Type Id: KONE_Buffer_Extension_Single_Pillar_KM841600_CAR: KONE_Buffer_Extension_Single_Pillar_KM841600
Phasing - Phase Created: Phase 3
SEADMED - 01 Nimetus: Undefined; 02 Tähis: KONE_Buffer_Extension_Single_Pillar_KM841600_CAR:KONE_Buffer_Extension_Single_Pillar_KM841600:300901; 03 Osasüsteem: Undefined; 04 Tehniline karakteristika: Undefined; 05 Tootja: Undefined; 06 Mudel või toote tunnus: Undefined; 07 Tooteinfo: Undefined; 08 Kasutus- ja hooldusjuhend: Undefined
AC_Pset_RenovationAndPhasing - Renovation Status: Existing

# IfcTransportElement: KONE_Buffer_PU_165x80D_CAR:KONE_Buffer_PU_165x80D:300900
In: 0 korrus
Type - ElementType: Element type KONE_Buffer_PU_165x80D_CAR:KONE_Buffer_PU_165x80D:300900
OperationType: ELEVATOR; CapacityByWeight: 0 kg; CapacityByNumber: 0; Classification: 1.17 IfcTransportElement (lift) (_RKAS BIM + ARCHICAD Classification); Material: IFC Building Material (2)
Constraints - Moves With Nearby Elements: no; Offset: -503 mm
Dimensions - Area: 0.0754375 m2; Volume: 0.00180698 m3
Other - Category: Specialty Equipment; Family: KONE_Buffer_PU_165x80D_CAR: KONE_Buffer_PU_165x80D; Family and Type: KONE_Buffer_PU_165x80D_CAR: KONE_Buffer_PU_165x80D; Type: KONE_Buffer_PU_165x80D_CAR: KONE_Buffer_PU_165x80D; Type Id: KONE_Buffer_PU_165x80D_CAR: KONE_Buffer_PU_165x80D
Phasing - Phase Created: Phase 3
SEADMED - 01 Nimetus: Undefined; 02 Tähis: KONE_Buffer_PU_165x80D_CAR:KONE_Buffer_PU_165x80D:300900; 03 Osasüsteem: Undefined; 04 Tehniline karakteristika: Undefined; 05 Tootja: Undefined; 06 Mudel või toote tunnus: Undefined; 07 Tooteinfo: Undefined; 08 Kasutus- ja hooldusjuhend: Undefined
AC_Pset_RenovationAndPhasing - Renovation Status: Existing

# IfcTransportElement: KONE_CWT:KONE_CWT:300896
In: 0 korrus
Type - ElementType: Element type KONE_CWT:KONE_CWT:300896
OperationType: ELEVATOR; CapacityByWeight: 0 kg; CapacityByNumber: 0; Classification: 1.17 IfcTransportElement (lift) (_RKAS BIM + ARCHICAD Classification); Material: IFC Building Material
Constraints - Moves With Nearby Elements: no; Offset: -1400 mm
Dimensions - Area: 11.3783 m2; B: 199 mm; C: 700 mm; CWTTravel: 9955 mm; Height: 2435 mm; Installation height: 10000 mm; Volume: 1.48482 m3
Other - Category: Specialty Equipment; Family: KONE_CWT: KONE_CWT; Family and Type: KONE_CWT: KONE_CWT; Type: KONE_CWT: KONE_CWT; Type Id: KONE_CWT: KONE_CWT
Phasing - Phase Created: Phase 3
SEADMED - 01 Nimetus: Undefined; 02 Tähis: KONE_CWT:KONE_CWT:300896; 03 Osasüsteem: Undefined; 04 Tehniline karakteristika: Undefined; 05 Tootja: Undefined; 06 Mudel või toote tunnus: Undefined; 07 Tooteinfo: Undefined; 08 Kasutus- ja hooldusjuhend: Undefined
AC_Pset_RenovationAndPhasing - Renovation Status: Existing

# IfcTransportElement: KONE_CWT_Bracket_KM838255G01_L109-178_LH:KONE_CWT_Bracket_KM838255G01_L109-178_LH:300916
In: 0 korrus
Type - ElementType: Element type KONE_CWT_Bracket_KM838255G01_L109-178_LH:KONE_CWT_Bracket_KM838255G01_L109-178_LH:300916
OperationType: ELEVATOR; CapacityByWeight: 0 kg; CapacityByNumber: 0; Classification: 1.17 IfcTransportElement (lift) (_RKAS BIM + ARCHICAD Classification); Material: IFC Building Material (2)
Constraints - Moves With Nearby Elements: no; Offset: -2426.39 mm
Dimensions - Area: 0.0497937 m2; DIM_CWT_BRACKET_L: 170 mm; DIM_Ext: 178 mm; Volume: 0.000224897 m3
Other - Category: Specialty Equipment; Family: KONE_CWT_Bracket_KM838255G01_L109-178_LH: KONE_CWT_Bracket_KM838255G01_L109-178_LH; Family and Type: KONE_CWT_Bracket_KM838255G01_L109-178_LH: KONE_CWT_Bracket_KM838255G01_L109-178_LH; Type: KONE_CWT_Bracket_KM838255G01_L109-178_LH: KONE_CWT_Bracket_KM838255G01_L109-178_LH; Type Id: KONE_CWT_Bracket_KM838255G01_L109-178_LH: KONE_CWT_Bracket_KM838255G01_L109-178_LH
Phasing - Phase Created: Phase 3
SEADMED - 01 Nimetus: Undefined; 02 Tähis: KONE_CWT_Bracket_KM838255G01_L109-178_LH:KONE_CWT_Bracket_KM838255G01_L109-178_LH:300916; 03 Osasüsteem: Undefined; 04 Tehniline karakteristika: Undefined; 05 Tootja: Undefined; 06 Mudel või toote tunnus: Undefined; 07 Tooteinfo: Undefined; 08 Kasutus- ja hooldusjuhend: Undefined
AC_Pset_RenovationAndPhasing - Renovation Status: Existing

# IfcTransportElement: KONE_CWT_Bracket_KM838255G01_L109-178_LH:KONE_CWT_Bracket_KM838255G01_L109-178_LH:300917
In: 0 korrus
Type - ElementType: Element type KONE_CWT_Bracket_KM838255G01_L109-178_LH:KONE_CWT_Bracket_KM838255G01_L109-178_LH:300917
OperationType: ELEVATOR; CapacityByWeight: 0 kg; CapacityByNumber: 0; Classification: 1.17 IfcTransportElement (lift) (_RKAS BIM + ARCHICAD Classification)
Constraints - Moves With Nearby Elements: no; Offset: -826.387 mm
Dimensions - Area: 0.0497937 m2; DIM_CWT_BRACKET_L: 170 mm; DIM_Ext: 178 mm; Volume: 0.000224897 m3
Other - Category: Specialty Equipment; Family: KONE_CWT_Bracket_KM838255G01_L109-178_LH: KONE_CWT_Bracket_KM838255G01_L109-178_LH; Family and Type: KONE_CWT_Bracket_KM838255G01_L109-178_LH: KONE_CWT_Bracket_KM838255G01_L109-178_LH; Type: KONE_CWT_Bracket_KM838255G01_L109-178_LH: KONE_CWT_Bracket_KM838255G01_L109-178_LH; Type Id: KONE_CWT_Bracket_KM838255G01_L109-178_LH: KONE_CWT_Bracket_KM838255G01_L109-178_LH
Phasing - Phase Created: Phase 3
SEADMED - 01 Nimetus: Undefined; 02 Tähis: KONE_CWT_Bracket_KM838255G01_L109-178_LH:KONE_CWT_Bracket_KM838255G01_L109-178_LH:300917; 03 Osasüsteem: Undefined; 04 Tehniline karakteristika: Undefined; 05 Tootja: Undefined; 06 Mudel või toote tunnus: Undefined; 07 Tooteinfo: Undefined; 08 Kasutus- ja hooldusjuhend: Undefined
AC_Pset_RenovationAndPhasing - Renovation Status: Existing

# IfcTransportElement: KONE_CWT_Bracket_KM838255G01_L109-178_LH:KONE_CWT_Bracket_KM838255G01_L109-178_LH:300918
In: 0 korrus
Type - ElementType: Element type KONE_CWT_Bracket_KM838255G01_L109-178_LH:KONE_CWT_Bracket_KM838255G01_L109-178_LH:300918
OperationType: ELEVATOR; CapacityByWeight: 0 kg; CapacityByNumber: 0; Classification: 1.17 IfcTransportElement (lift) (_RKAS BIM + ARCHICAD Classification)
Constraints - Moves With Nearby Elements: no; Offset: 1673.61 mm
Dimensions - Area: 0.0497937 m2; DIM_CWT_BRACKET_L: 170 mm; DIM_Ext: 178 mm; Volume: 0.000224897 m3
Other - Category: Specialty Equipment; Family: KONE_CWT_Bracket_KM838255G01_L109-178_LH: KONE_CWT_Bracket_KM838255G01_L109-178_LH; Family and Type: KONE_CWT_Bracket_KM838255G01_L109-178_LH: KONE_CWT_Bracket_KM838255G01_L109-178_LH; Type: KONE_CWT_Bracket_KM838255G01_L109-178_LH: KONE_CWT_Bracket_KM838255G01_L109-178_LH; Type Id: KONE_CWT_Bracket_KM838255G01_L109-178_LH: KONE_CWT_Bracket_KM838255G01_L109-178_LH
Phasing - Phase Created: Phase 3
SEADMED - 01 Nimetus: Undefined; 02 Tähis: KONE_CWT_Bracket_KM838255G01_L109-178_LH:KONE_CWT_Bracket_KM838255G01_L109-178_LH:300918; 03 Osasüsteem: Undefined; 04 Tehniline karakteristika: Undefined; 05 Tootja: Undefined; 06 Mudel või toote tunnus: Undefined; 07 Tooteinfo: Undefined; 08 Kasutus- ja hooldusjuhend: Undefined
AC_Pset_RenovationAndPhasing - Renovation Status: Existing

# IfcTransportElement: KONE_CWT_Bracket_KM838255G01_L109-178_LH:KONE_CWT_Bracket_KM838255G01_L109-178_LH:300919
In: 0 korrus
Type - ElementType: Element type KONE_CWT_Bracket_KM838255G01_L109-178_LH:KONE_CWT_Bracket_KM838255G01_L109-178_LH:300919
OperationType: ELEVATOR; CapacityByWeight: 0 kg; CapacityByNumber: 0; Classification: 1.17 IfcTransportElement (lift) (_RKAS BIM + ARCHICAD Classification)
Constraints - Moves With Nearby Elements: no; Offset: 3673.61 mm
Dimensions - Area: 0.0497937 m2; DIM_CWT_BRACKET_L: 170 mm; DIM_Ext: 178 mm; Volume: 0.000224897 m3
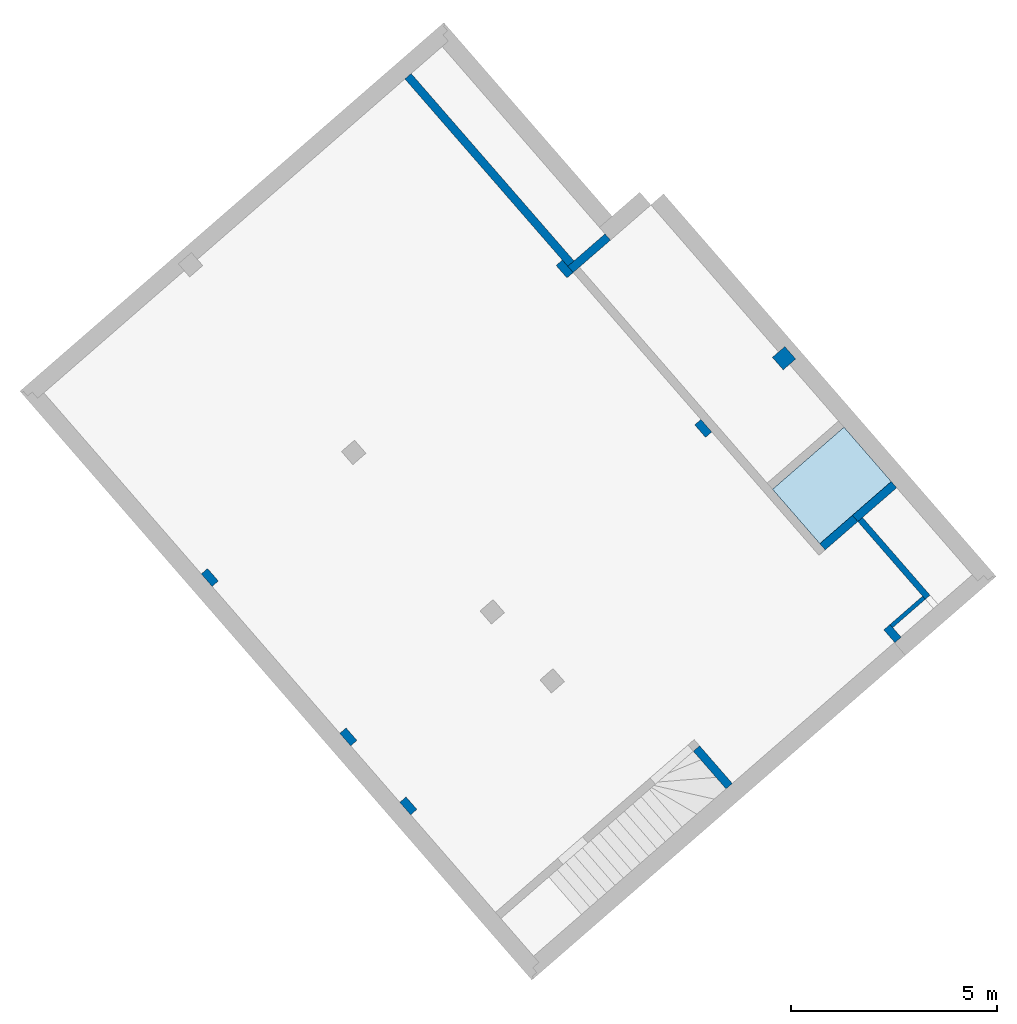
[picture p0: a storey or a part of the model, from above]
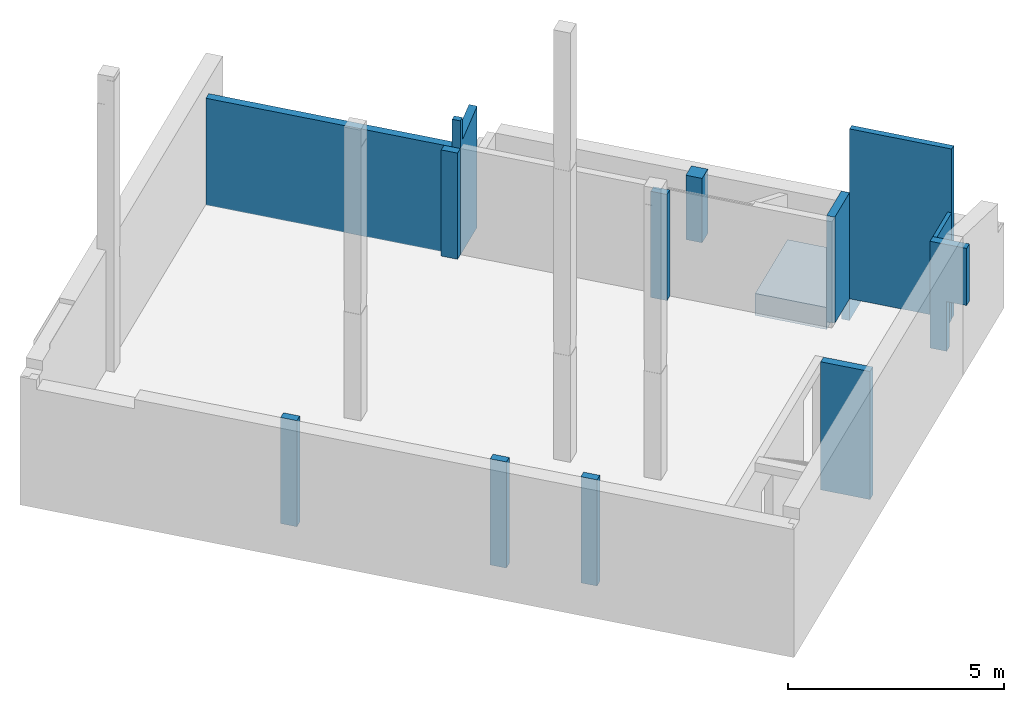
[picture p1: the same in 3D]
Properties of the parts of a building model (IFC2X3), part 8 of 13

# IfcTransportElement: KONE_CWT_Bracket_KM838255G01_L109-178_LH:KONE_CWT_Bracket_KM838255G01_L109-178_LH:300919
Other - Category: Specialty Equipment; Family: KONE_CWT_Bracket_KM838255G01_L109-178_LH: KONE_CWT_Bracket_KM838255G01_L109-178_LH; Family and Type: KONE_CWT_Bracket_KM838255G01_L109-178_LH: KONE_CWT_Bracket_KM838255G01_L109-178_LH; Type: KONE_CWT_Bracket_KM838255G01_L109-178_LH: KONE_CWT_Bracket_KM838255G01_L109-178_LH; Type Id: KONE_CWT_Bracket_KM838255G01_L109-178_LH: KONE_CWT_Bracket_KM838255G01_L109-178_LH
Phasing - Phase Created: Phase 3
SEADMED - 01 Nimetus: Undefined; 02 Tähis: KONE_CWT_Bracket_KM838255G01_L109-178_LH:KONE_CWT_Bracket_KM838255G01_L109-178_LH:300919; 03 Osasüsteem: Undefined; 04 Tehniline karakteristika: Undefined; 05 Tootja: Undefined; 06 Mudel või toote tunnus: Undefined; 07 Tooteinfo: Undefined; 08 Kasutus- ja hooldusjuhend: Undefined
AC_Pset_RenovationAndPhasing - Renovation Status: Existing

# IfcTransportElement: KONE_CWT_Bracket_KM838255G01_L109-178_LH:KONE_CWT_Bracket_KM838255G01_L109-178_LH:300920
In: 0 korrus
Type - ElementType: Element type KONE_CWT_Bracket_KM838255G01_L109-178_LH:KONE_CWT_Bracket_KM838255G01_L109-178_LH:300920
OperationType: ELEVATOR; CapacityByWeight: 0 kg; CapacityByNumber: 0; Classification: 1.17 IfcTransportElement (lift) (_RKAS BIM + ARCHICAD Classification)
Constraints - Moves With Nearby Elements: no; Offset: 5343.61 mm
Dimensions - Area: 0.0497937 m2; DIM_CWT_BRACKET_L: 170 mm; DIM_Ext: 178 mm; Volume: 0.000224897 m3
Other - Category: Specialty Equipment; Family: KONE_CWT_Bracket_KM838255G01_L109-178_LH: KONE_CWT_Bracket_KM838255G01_L109-178_LH; Family and Type: KONE_CWT_Bracket_KM838255G01_L109-178_LH: KONE_CWT_Bracket_KM838255G01_L109-178_LH; Type: KONE_CWT_Bracket_KM838255G01_L109-178_LH: KONE_CWT_Bracket_KM838255G01_L109-178_LH; Type Id: KONE_CWT_Bracket_KM838255G01_L109-178_LH: KONE_CWT_Bracket_KM838255G01_L109-178_LH
Phasing - Phase Created: Phase 3
SEADMED - 01 Nimetus: Undefined; 02 Tähis: KONE_CWT_Bracket_KM838255G01_L109-178_LH:KONE_CWT_Bracket_KM838255G01_L109-178_LH:300920; 03 Osasüsteem: Undefined; 04 Tehniline karakteristika: Undefined; 05 Tootja: Undefined; 06 Mudel või toote tunnus: Undefined; 07 Tooteinfo: Undefined; 08 Kasutus- ja hooldusjuhend: Undefined
AC_Pset_RenovationAndPhasing - Renovation Status: Existing

# IfcTransportElement: KONE_CWT_Bracket_KM838255G01_L109-178_LH:KONE_CWT_Bracket_KM838255G01_L109-178_LH:300921
In: 0 korrus
Type - ElementType: Element type KONE_CWT_Bracket_KM838255G01_L109-178_LH:KONE_CWT_Bracket_KM838255G01_L109-178_LH:300921
OperationType: ELEVATOR; CapacityByWeight: 0 kg; CapacityByNumber: 0; Classification: 1.17 IfcTransportElement (lift) (_RKAS BIM + ARCHICAD Classification)
Constraints - Moves With Nearby Elements: no; Offset: 6943.61 mm
Dimensions - Area: 0.0497937 m2; DIM_CWT_BRACKET_L: 170 mm; DIM_Ext: 178 mm; Volume: 0.000224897 m3
Other - Category: Specialty Equipment; Family: KONE_CWT_Bracket_KM838255G01_L109-178_LH: KONE_CWT_Bracket_KM838255G01_L109-178_LH; Family and Type: KONE_CWT_Bracket_KM838255G01_L109-178_LH: KONE_CWT_Bracket_KM838255G01_L109-178_LH; Type: KONE_CWT_Bracket_KM838255G01_L109-178_LH: KONE_CWT_Bracket_KM838255G01_L109-178_LH; Type Id: KONE_CWT_Bracket_KM838255G01_L109-178_LH: KONE_CWT_Bracket_KM838255G01_L109-178_LH
Phasing - Phase Created: Phase 3
SEADMED - 01 Nimetus: Undefined; 02 Tähis: KONE_CWT_Bracket_KM838255G01_L109-178_LH:KONE_CWT_Bracket_KM838255G01_L109-178_LH:300921; 03 Osasüsteem: Undefined; 04 Tehniline karakteristika: Undefined; 05 Tootja: Undefined; 06 Mudel või toote tunnus: Undefined; 07 Tooteinfo: Undefined; 08 Kasutus- ja hooldusjuhend: Undefined
AC_Pset_RenovationAndPhasing - Renovation Status: Existing

# IfcTransportElement: KONE_CWT_Bracket_KM838255G01_L109-178_LH:KONE_CWT_Bracket_KM838255G01_L109-178_LH:300922
In: 0 korrus
Type - ElementType: Element type KONE_CWT_Bracket_KM838255G01_L109-178_LH:KONE_CWT_Bracket_KM838255G01_L109-178_LH:300922
OperationType: ELEVATOR; CapacityByWeight: 0 kg; CapacityByNumber: 0; Classification: 1.17 IfcTransportElement (lift) (_RKAS BIM + ARCHICAD Classification)
Constraints - Moves With Nearby Elements: no; Offset: 8173.61 mm
Dimensions - Area: 0.0497937 m2; DIM_CWT_BRACKET_L: 170 mm; DIM_Ext: 178 mm; Volume: 0.000224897 m3
Other - Category: Specialty Equipment; Family: KONE_CWT_Bracket_KM838255G01_L109-178_LH: KONE_CWT_Bracket_KM838255G01_L109-178_LH; Family and Type: KONE_CWT_Bracket_KM838255G01_L109-178_LH: KONE_CWT_Bracket_KM838255G01_L109-178_LH; Type: KONE_CWT_Bracket_KM838255G01_L109-178_LH: KONE_CWT_Bracket_KM838255G01_L109-178_LH; Type Id: KONE_CWT_Bracket_KM838255G01_L109-178_LH: KONE_CWT_Bracket_KM838255G01_L109-178_LH
Phasing - Phase Created: Phase 3
SEADMED - 01 Nimetus: Undefined; 02 Tähis: KONE_CWT_Bracket_KM838255G01_L109-178_LH:KONE_CWT_Bracket_KM838255G01_L109-178_LH:300922; 03 Osasüsteem: Undefined; 04 Tehniline karakteristika: Undefined; 05 Tootja: Undefined; 06 Mudel või toote tunnus: Undefined; 07 Tooteinfo: Undefined; 08 Kasutus- ja hooldusjuhend: Undefined
AC_Pset_RenovationAndPhasing - Renovation Status: Existing

# IfcTransportElement: KONE_CWT_guiderail:KONE_CWT_guiderail:300897
In: 0 korrus
Type - ElementType: Element type KONE_CWT_guiderail:KONE_CWT_guiderail:300897
OperationType: ELEVATOR; CapacityByWeight: 0 kg; CapacityByNumber: 0; Classification: 1.17 IfcTransportElement (lift) (_RKAS BIM + ARCHICAD Classification); Material: IFC Building Material
Constraints - Moves With Nearby Elements: no; Offset: -1400 mm
Dimensions - Area: 1.19761 m2; Depth: 50 mm; Guide rail h: 10255 mm; Volume: 0.0122569 m3; Width: 66.6667 mm
Other - Category: Specialty Equipment; Family: KONE_CWT_guiderail: KONE_CWT_guiderail; Family and Type: KONE_CWT_guiderail: KONE_CWT_guiderail; Type: KONE_CWT_guiderail: KONE_CWT_guiderail; Type Id: KONE_CWT_guiderail: KONE_CWT_guiderail
Phasing - Phase Created: Phase 3
SEADMED - 01 Nimetus: Undefined; 02 Tähis: KONE_CWT_guiderail:KONE_CWT_guiderail:300897; 03 Osasüsteem: Undefined; 04 Tehniline karakteristika: Undefined; 05 Tootja: Undefined; 06 Mudel või toote tunnus: Undefined; 07 Tooteinfo: Undefined; 08 Kasutus- ja hooldusjuhend: Undefined
AC_Pset_RenovationAndPhasing - Renovation Status: Existing

# IfcTransportElement: KONE_CWT_guiderail:KONE_CWT_guiderail:300898
In: 0 korrus
Type - ElementType: Element type KONE_CWT_guiderail:KONE_CWT_guiderail:300898
OperationType: ELEVATOR; CapacityByWeight: 0 kg; CapacityByNumber: 0; Classification: 1.17 IfcTransportElement (lift) (_RKAS BIM + ARCHICAD Classification); Material: IFC Building Material
Constraints - Moves With Nearby Elements: no; Offset: -1400 mm
Dimensions - Area: 1.3312 m2; Depth: 50 mm; Guide rail h: 11400 mm; Volume: 0.0136254 m3; Width: 66.6667 mm
Other - Category: Specialty Equipment; Family: KONE_CWT_guiderail: KONE_CWT_guiderail; Family and Type: KONE_CWT_guiderail: KONE_CWT_guiderail; Type: KONE_CWT_guiderail: KONE_CWT_guiderail; Type Id: KONE_CWT_guiderail: KONE_CWT_guiderail
Phasing - Phase Created: Phase 3
SEADMED - 01 Nimetus: Undefined; 02 Tähis: KONE_CWT_guiderail:KONE_CWT_guiderail:300898; 03 Osasüsteem: Undefined; 04 Tehniline karakteristika: Undefined; 05 Tootja: Undefined; 06 Mudel või toote tunnus: Undefined; 07 Tooteinfo: Undefined; 08 Kasutus- ja hooldusjuhend: Undefined
AC_Pset_RenovationAndPhasing - Renovation Status: Existing

# IfcTransportElement: KONE_Car:KONE_Car:300887
In: 0 korrus
Type - ElementType: Element type KONE_Car:KONE_Car:300887
OperationType: ELEVATOR; CapacityByWeight: 0 kg; CapacityByNumber: 0; Classification: 1.17 IfcTransportElement (lift) (_RKAS BIM + ARCHICAD Classification); Material: IFC Building Material (26)
Constraints - Moves With Nearby Elements: no; Offset: 0 mm
Dimensions - Area: 7.99411 m2; DIM_BB: 1200 mm; DIM_CH: 2200 mm; DIM_DD: 1500 mm; TYP_CAR_SCE_DR: 0 mm; Volume: 3.96048 m3
Other - Category: Specialty Equipment; Family: KONE_Car: KONE_Car; Family and Type: KONE_Car: KONE_Car; Type: KONE_Car: KONE_Car; Type Id: KONE_Car: KONE_Car
Phasing - Phase Created: Phase 3
SEADMED - 01 Nimetus: Undefined; 02 Tähis: KONE_Car:KONE_Car:300887; 03 Osasüsteem: Undefined; 04 Tehniline karakteristika: Undefined; 05 Tootja: Undefined; 06 Mudel või toote tunnus: Undefined; 07 Tooteinfo: Undefined; 08 Kasutus- ja hooldusjuhend: Undefined
AC_Pset_RenovationAndPhasing - Renovation Status: Existing

# IfcTransportElement: KONE_Car_Bracket_Top Most_KM927058G01_L50-80:KONE_Car_Bracket_Top Most_KM927058G01_L50-80:300911
In: 0 korrus
Type - ElementType: Element type KONE_Car_Bracket_Top Most_KM927058G01_L50-80:KONE_Car_Bracket_Top Most_KM927058G01_L50-80:300911
OperationType: ELEVATOR; CapacityByWeight: 0 kg; CapacityByNumber: 0; Classification: 1.17 IfcTransportElement (lift) (_RKAS BIM + ARCHICAD Classification); Material: Generic (2)
Constraints - Moves With Nearby Elements: no; Offset: -2474.18 mm
Dimensions - Area: 0.072627 m2; DIM_CAR_BRACKET_L: 78 mm; Volume: 0.00206063 m3
Other - Category: Specialty Equipment; Family: KONE_Car_Bracket_Top Most_KM927058G01_L50-80: KONE_Car_Bracket_Top Most_KM927058G01_L50-80; Family and Type: KONE_Car_Bracket_Top Most_KM927058G01_L50-80: KONE_Car_Bracket_Top Most_KM927058G01_L50-80; Type: KONE_Car_Bracket_Top Most_KM927058G01_L50-80: KONE_Car_Bracket_Top Most_KM927058G01_L50-80; Type Id: KONE_Car_Bracket_Top Most_KM927058G01_L50-80: KONE_Car_Bracket_Top Most_KM927058G01_L50-80
Phasing - Phase Created: Phase 3
SEADMED - 01 Nimetus: Undefined; 02 Tähis: KONE_Car_Bracket_Top Most_KM927058G01_L50-80:KONE_Car_Bracket_Top Most_KM927058G01_L50-80:300911; 03 Osasüsteem: Undefined; 04 Tehniline karakteristika: Undefined; 05 Tootja: Undefined; 06 Mudel või toote tunnus: Undefined; 07 Tooteinfo: Undefined; 08 Kasutus- ja hooldusjuhend: Undefined
AC_Pset_RenovationAndPhasing - Renovation Status: Existing

# IfcTransportElement: KONE_Car_Bracket_Top Most_KM927058G01_L50-80:KONE_Car_Bracket_Top Most_KM927058G01_L50-80:300912
In: 0 korrus
Type - ElementType: Element type KONE_Car_Bracket_Top Most_KM927058G01_L50-80:KONE_Car_Bracket_Top Most_KM927058G01_L50-80:300912
OperationType: ELEVATOR; CapacityByWeight: 0 kg; CapacityByNumber: 0; Classification: 1.17 IfcTransportElement (lift) (_RKAS BIM + ARCHICAD Classification)
Constraints - Moves With Nearby Elements: no; Offset: -874.182 mm
Dimensions - Area: 0.072627 m2; DIM_CAR_BRACKET_L: 78 mm; Volume: 0.00206063 m3
Other - Category: Specialty Equipment; Family: KONE_Car_Bracket_Top Most_KM927058G01_L50-80: KONE_Car_Bracket_Top Most_KM927058G01_L50-80; Family and Type: KONE_Car_Bracket_Top Most_KM927058G01_L50-80: KONE_Car_Bracket_Top Most_KM927058G01_L50-80; Type: KONE_Car_Bracket_Top Most_KM927058G01_L50-80: KONE_Car_Bracket_Top Most_KM927058G01_L50-80; Type Id: KONE_Car_Bracket_Top Most_KM927058G01_L50-80: KONE_Car_Bracket_Top Most_KM927058G01_L50-80
Phasing - Phase Created: Phase 3
SEADMED - 01 Nimetus: Undefined; 02 Tähis: KONE_Car_Bracket_Top Most_KM927058G01_L50-80:KONE_Car_Bracket_Top Most_KM927058G01_L50-80:300912; 03 Osasüsteem: Undefined; 04 Tehniline karakteristika: Undefined; 05 Tootja: Undefined; 06 Mudel või toote tunnus: Undefined; 07 Tooteinfo: Undefined; 08 Kasutus- ja hooldusjuhend: Undefined
AC_Pset_RenovationAndPhasing - Renovation Status: Existing

# IfcTransportElement: KONE_Car_Bracket_Top Most_KM927058G01_L50-80:KONE_Car_Bracket_Top Most_KM927058G01_L50-80:300913
In: 0 korrus
Type - ElementType: Element type KONE_Car_Bracket_Top Most_KM927058G01_L50-80:KONE_Car_Bracket_Top Most_KM927058G01_L50-80:300913
OperationType: ELEVATOR; CapacityByWeight: 0 kg; CapacityByNumber: 0; Classification: 1.17 IfcTransportElement (lift) (_RKAS BIM + ARCHICAD Classification)
Constraints - Moves With Nearby Elements: no; Offset: 1625.82 mm
Dimensions - Area: 0.072627 m2; DIM_CAR_BRACKET_L: 78 mm; Volume: 0.00206063 m3
Other - Category: Specialty Equipment; Family: KONE_Car_Bracket_Top Most_KM927058G01_L50-80: KONE_Car_Bracket_Top Most_KM927058G01_L50-80; Family and Type: KONE_Car_Bracket_Top Most_KM927058G01_L50-80: KONE_Car_Bracket_Top Most_KM927058G01_L50-80; Type: KONE_Car_Bracket_Top Most_KM927058G01_L50-80: KONE_Car_Bracket_Top Most_KM927058G01_L50-80; Type Id: KONE_Car_Bracket_Top Most_KM927058G01_L50-80: KONE_Car_Bracket_Top Most_KM927058G01_L50-80
Phasing - Phase Created: Phase 3
SEADMED - 01 Nimetus: Undefined; 02 Tähis: KONE_Car_Bracket_Top Most_KM927058G01_L50-80:KONE_Car_Bracket_Top Most_KM927058G01_L50-80:300913; 03 Osasüsteem: Undefined; 04 Tehniline karakteristika: Undefined; 05 Tootja: Undefined; 06 Mudel või toote tunnus: Undefined; 07 Tooteinfo: Undefined; 08 Kasutus- ja hooldusjuhend: Undefined
AC_Pset_RenovationAndPhasing - Renovation Status: Existing

# IfcTransportElement: KONE_Car_Bracket_Top Most_KM927058G01_L50-80:KONE_Car_Bracket_Top Most_KM927058G01_L50-80:300914
In: 0 korrus
Type - ElementType: Element type KONE_Car_Bracket_Top Most_KM927058G01_L50-80:KONE_Car_Bracket_Top Most_KM927058G01_L50-80:300914
OperationType: ELEVATOR; CapacityByWeight: 0 kg; CapacityByNumber: 0; Classification: 1.17 IfcTransportElement (lift) (_RKAS BIM + ARCHICAD Classification)
Constraints - Moves With Nearby Elements: no; Offset: 3625.82 mm
Dimensions - Area: 0.072627 m2; DIM_CAR_BRACKET_L: 78 mm; Volume: 0.00206063 m3
Other - Category: Specialty Equipment; Family: KONE_Car_Bracket_Top Most_KM927058G01_L50-80: KONE_Car_Bracket_Top Most_KM927058G01_L50-80; Family and Type: KONE_Car_Bracket_Top Most_KM927058G01_L50-80: KONE_Car_Bracket_Top Most_KM927058G01_L50-80; Type: KONE_Car_Bracket_Top Most_KM927058G01_L50-80: KONE_Car_Bracket_Top Most_KM927058G01_L50-80; Type Id: KONE_Car_Bracket_Top Most_KM927058G01_L50-80: KONE_Car_Bracket_Top Most_KM927058G01_L50-80
Phasing - Phase Created: Phase 3
SEADMED - 01 Nimetus: Undefined; 02 Tähis: KONE_Car_Bracket_Top Most_KM927058G01_L50-80:KONE_Car_Bracket_Top Most_KM927058G01_L50-80:300914; 03 Osasüsteem: Undefined; 04 Tehniline karakteristika: Undefined; 05 Tootja: Undefined; 06 Mudel või toote tunnus: Undefined; 07 Tooteinfo: Undefined; 08 Kasutus- ja hooldusjuhend: Undefined
AC_Pset_RenovationAndPhasing - Renovation Status: Existing

# IfcTransportElement: KONE_Car_Bracket_Top Most_KM927058G01_L50-80:KONE_Car_Bracket_Top Most_KM927058G01_L50-80:300915
In: 0 korrus
Type - ElementType: Element type KONE_Car_Bracket_Top Most_KM927058G01_L50-80:KONE_Car_Bracket_Top Most_KM927058G01_L50-80:300915
OperationType: ELEVATOR; CapacityByWeight: 0 kg; CapacityByNumber: 0; Classification: 1.17 IfcTransportElement (lift) (_RKAS BIM + ARCHICAD Classification)
Constraints - Moves With Nearby Elements: no; Offset: 5295.82 mm
Dimensions - Area: 0.072627 m2; DIM_CAR_BRACKET_L: 78 mm; Volume: 0.00206063 m3
Other - Category: Specialty Equipment; Family: KONE_Car_Bracket_Top Most_KM927058G01_L50-80: KONE_Car_Bracket_Top Most_KM927058G01_L50-80; Family and Type: KONE_Car_Bracket_Top Most_KM927058G01_L50-80: KONE_Car_Bracket_Top Most_KM927058G01_L50-80; Type: KONE_Car_Bracket_Top Most_KM927058G01_L50-80: KONE_Car_Bracket_Top Most_KM927058G01_L50-80; Type Id: KONE_Car_Bracket_Top Most_KM927058G01_L50-80: KONE_Car_Bracket_Top Most_KM927058G01_L50-80
Phasing - Phase Created: Phase 3
SEADMED - 01 Nimetus: Undefined; 02 Tähis: KONE_Car_Bracket_Top Most_KM927058G01_L50-80:KONE_Car_Bracket_Top Most_KM927058G01_L50-80:300915; 03 Osasüsteem: Undefined; 04 Tehniline karakteristika: Undefined; 05 Tootja: Undefined; 06 Mudel või toote tunnus: Undefined; 07 Tooteinfo: Undefined; 08 Kasutus- ja hooldusjuhend: Undefined
AC_Pset_RenovationAndPhasing - Renovation Status: Existing

# IfcTransportElement: KONE_Car_Bracket_Top Most_KM927058G01_L50-80:KONE_Car_Bracket_Top Most_KM927058G01_L50-80:300930
In: 0 korrus
Type - ElementType: Element type KONE_Car_Bracket_Top Most_KM927058G01_L50-80:KONE_Car_Bracket_Top Most_KM927058G01_L50-80:300930
OperationType: ELEVATOR; CapacityByWeight: 0 kg; CapacityByNumber: 0; Classification: 1.17 IfcTransportElement (lift) (_RKAS BIM + ARCHICAD Classification)
Constraints - Moves With Nearby Elements: no; Offset: 6895.82 mm
Dimensions - Area: 0.072627 m2; DIM_CAR_BRACKET_L: 78 mm; Volume: 0.00206063 m3
Other - Category: Specialty Equipment; Family: KONE_Car_Bracket_Top Most_KM927058G01_L50-80: KONE_Car_Bracket_Top Most_KM927058G01_L50-80; Family and Type: KONE_Car_Bracket_Top Most_KM927058G01_L50-80: KONE_Car_Bracket_Top Most_KM927058G01_L50-80; Type: KONE_Car_Bracket_Top Most_KM927058G01_L50-80: KONE_Car_Bracket_Top Most_KM927058G01_L50-80; Type Id: KONE_Car_Bracket_Top Most_KM927058G01_L50-80: KONE_Car_Bracket_Top Most_KM927058G01_L50-80
Phasing - Phase Created: Phase 3
SEADMED - 01 Nimetus: Undefined; 02 Tähis: KONE_Car_Bracket_Top Most_KM927058G01_L50-80:KONE_Car_Bracket_Top Most_KM927058G01_L50-80:300930; 03 Osasüsteem: Undefined; 04 Tehniline karakteristika: Undefined; 05 Tootja: Undefined; 06 Mudel või toote tunnus: Undefined; 07 Tooteinfo: Undefined; 08 Kasutus- ja hooldusjuhend: Undefined
AC_Pset_RenovationAndPhasing - Renovation Status: Existing

# IfcTransportElement: KONE_Car_Bracket_Top Most_KM927058G01_L50-80:KONE_Car_Bracket_Top Most_KM927058G01_L50-80:300931
In: 0 korrus
Type - ElementType: Element type KONE_Car_Bracket_Top Most_KM927058G01_L50-80:KONE_Car_Bracket_Top Most_KM927058G01_L50-80:300931
OperationType: ELEVATOR; CapacityByWeight: 0 kg; CapacityByNumber: 0; Classification: 1.17 IfcTransportElement (lift) (_RKAS BIM + ARCHICAD Classification)
Constraints - Moves With Nearby Elements: no; Offset: 8335.82 mm
Dimensions - Area: 0.072627 m2; DIM_CAR_BRACKET_L: 78 mm; Volume: 0.00206063 m3
Other - Category: Specialty Equipment; Family: KONE_Car_Bracket_Top Most_KM927058G01_L50-80: KONE_Car_Bracket_Top Most_KM927058G01_L50-80; Family and Type: KONE_Car_Bracket_Top Most_KM927058G01_L50-80: KONE_Car_Bracket_Top Most_KM927058G01_L50-80; Type: KONE_Car_Bracket_Top Most_KM927058G01_L50-80: KONE_Car_Bracket_Top Most_KM927058G01_L50-80; Type Id: KONE_Car_Bracket_Top Most_KM927058G01_L50-80: KONE_Car_Bracket_Top Most_KM927058G01_L50-80
Phasing - Phase Created: Phase 3
SEADMED - 01 Nimetus: Undefined; 02 Tähis: KONE_Car_Bracket_Top Most_KM927058G01_L50-80:KONE_Car_Bracket_Top Most_KM927058G01_L50-80:300931; 03 Osasüsteem: Undefined; 04 Tehniline karakteristika: Undefined; 05 Tootja: Undefined; 06 Mudel või toote tunnus: Undefined; 07 Tooteinfo: Undefined; 08 Kasutus- ja hooldusjuhend: Undefined
AC_Pset_RenovationAndPhasing - Renovation Status: Existing

# IfcTransportElement: KONE_Car_Door_2L:KONE_Car_Door_2L:300889
In: 0 korrus
Type - ElementType: Element type KONE_Car_Door_2L:KONE_Car_Door_2L:300889
OperationType: ELEVATOR; CapacityByWeight: 0 kg; CapacityByNumber: 0; Classification: 1.17 IfcTransportElement (lift) (_RKAS BIM + ARCHICAD Classification); Material: IFC Building Material (3)
Constraints - Moves With Nearby Elements: no; Offset: 0 mm
Dimensions - Area: 2.44367 m2; DIM_DOOR_HH: 2100 mm; DIM_DOOR_LL: 900 mm; Volume: 0.0954765 m3
Other - Category: Specialty Equipment; Family: KONE_Car_Door_2L: KONE_Car_Door_2L; Family and Type: KONE_Car_Door_2L: KONE_Car_Door_2L; Type: KONE_Car_Door_2L: KONE_Car_Door_2L; Type Id: KONE_Car_Door_2L: KONE_Car_Door_2L
Phasing - Phase Created: Phase 3
SEADMED - 01 Nimetus: Undefined; 02 Tähis: KONE_Car_Door_2L:KONE_Car_Door_2L:300889; 03 Osasüsteem: Undefined; 04 Tehniline karakteristika: Undefined; 05 Tootja: Undefined; 06 Mudel või toote tunnus: Undefined; 07 Tooteinfo: Undefined; 08 Kasutus- ja hooldusjuhend: Undefined
AC_Pset_RenovationAndPhasing - Renovation Status: Existing

# IfcTransportElement: KONE_Car_Door_2R:KONE_Car_Door_2R:300890
In: 0 korrus
Type - ElementType: Element type KONE_Car_Door_2R:KONE_Car_Door_2R:300890
OperationType: ELEVATOR; CapacityByWeight: 0 kg; CapacityByNumber: 0; Classification: 1.17 IfcTransportElement (lift) (_RKAS BIM + ARCHICAD Classification); Material: IFC Building Material (3)
Constraints - Moves With Nearby Elements: no; Offset: 0 mm
Dimensions - Area: 2.44367 m2; DIM_DOOR_HH: 2100 mm; DIM_DOOR_LL: 900 mm; Volume: 0.0954765 m3
Other - Category: Specialty Equipment; Family: KONE_Car_Door_2R: KONE_Car_Door_2R; Family and Type: KONE_Car_Door_2R: KONE_Car_Door_2R; Type: KONE_Car_Door_2R: KONE_Car_Door_2R; Type Id: KONE_Car_Door_2R: KONE_Car_Door_2R
Phasing - Phase Created: Phase 3
SEADMED - 01 Nimetus: Undefined; 02 Tähis: KONE_Car_Door_2R:KONE_Car_Door_2R:300890; 03 Osasüsteem: Undefined; 04 Tehniline karakteristika: Undefined; 05 Tootja: Undefined; 06 Mudel või toote tunnus: Undefined; 07 Tooteinfo: Undefined; 08 Kasutus- ja hooldusjuhend: Undefined
AC_Pset_RenovationAndPhasing - Renovation Status: Existing

# IfcTransportElement: KONE_Car_guiderail:KONE_Car_guiderail:300885
In: 0 korrus
Type - ElementType: Element type KONE_Car_guiderail:KONE_Car_guiderail:300885
OperationType: ELEVATOR; CapacityByWeight: 0 kg; CapacityByNumber: 0; Classification: 1.17 IfcTransportElement (lift) (_RKAS BIM + ARCHICAD Classification); Material: IFC Building Material
Constraints - Moves With Nearby Elements: no; Offset: -1400 mm
Dimensions - Area: 1.67675 m2; Depth: 62 mm; Guide rail h: 11580 mm; Volume: 0.017511 m3; Width: 82.6667 mm
Other - Category: Specialty Equipment; Family: KONE_Car_guiderail: KONE_Car_guiderail; Family and Type: KONE_Car_guiderail: KONE_Car_guiderail; Type: KONE_Car_guiderail: KONE_Car_guiderail; Type Id: KONE_Car_guiderail: KONE_Car_guiderail
Phasing - Phase Created: Phase 3
SEADMED - 01 Nimetus: Undefined; 02 Tähis: KONE_Car_guiderail:KONE_Car_guiderail:300885; 03 Osasüsteem: Undefined; 04 Tehniline karakteristika: Undefined; 05 Tootja: Undefined; 06 Mudel või toote tunnus: Undefined; 07 Tooteinfo: Undefined; 08 Kasutus- ja hooldusjuhend: Undefined
AC_Pset_RenovationAndPhasing - Renovation Status: Existing

# IfcTransportElement: KONE_Car_guiderail:KONE_Car_guiderail:300886
In: 0 korrus
Type - ElementType: Element type KONE_Car_guiderail:KONE_Car_guiderail:300886
OperationType: ELEVATOR; CapacityByWeight: 0 kg; CapacityByNumber: 0; Classification: 1.17 IfcTransportElement (lift) (_RKAS BIM + ARCHICAD Classification)
Constraints - Moves With Nearby Elements: no; Offset: -1400 mm
Dimensions - Area: 1.67675 m2; Depth: 62 mm; Guide rail h: 11580 mm; Volume: 0.017511 m3; Width: 82.6667 mm
Other - Category: Specialty Equipment; Family: KONE_Car_guiderail: KONE_Car_guiderail; Family and Type: KONE_Car_guiderail: KONE_Car_guiderail; Type: KONE_Car_guiderail: KONE_Car_guiderail; Type Id: KONE_Car_guiderail: KONE_Car_guiderail
Phasing - Phase Created: Phase 3
SEADMED - 01 Nimetus: Undefined; 02 Tähis: KONE_Car_guiderail:KONE_Car_guiderail:300886; 03 Osasüsteem: Undefined; 04 Tehniline karakteristika: Undefined; 05 Tootja: Undefined; 06 Mudel või toote tunnus: Undefined; 07 Tooteinfo: Undefined; 08 Kasutus- ja hooldusjuhend: Undefined
AC_Pset_RenovationAndPhasing - Renovation Status: Existing

# IfcTransportElement: KONE_Combination_Bracket_KM927051G01_L205-370_LH:KONE_Combination_Bracket_KM927051G01_L205-370_LH:300923
In: 0 korrus
Type - ElementType: Element type KONE_Combination_Bracket_KM927051G01_L205-370_LH:KONE_Combination_Bracket_KM927051G01_L205-370_LH:300923
OperationType: ELEVATOR; CapacityByWeight: 0 kg; CapacityByNumber: 0; Classification: 1.17 IfcTransportElement (lift) (_RKAS BIM + ARCHICAD Classification); Material: Generic (2)
Constraints - Moves With Nearby Elements: no; Offset: -2473.08 mm
Dimensions - Area: 0.138293 m2; DIM_COMB_BRACKET_L: 268 mm; Volume: 0.000657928 m3
Other - Category: Specialty Equipment; Family: KONE_Combination_Bracket_KM927051G01_L205-370_LH: KONE_Combination_Bracket_KM927051G01_L205-370_LH; Family and Type: KONE_Combination_Bracket_KM927051G01_L205-370_LH: KONE_Combination_Bracket_KM927051G01_L205-370_LH; Type: KONE_Combination_Bracket_KM927051G01_L205-370_LH: KONE_Combination_Bracket_KM927051G01_L205-370_LH; Type Id: KONE_Combination_Bracket_KM927051G01_L205-370_LH: KONE_Combination_Bracket_KM927051G01_L205-370_LH
Phasing - Phase Created: Phase 3
SEADMED - 01 Nimetus: Undefined; 02 Tähis: KONE_Combination_Bracket_KM927051G01_L205-370_LH:KONE_Combination_Bracket_KM927051G01_L205-370_LH:300923; 03 Osasüsteem: Undefined; 04 Tehniline karakteristika: Undefined; 05 Tootja: Undefined; 06 Mudel või toote tunnus: Undefined; 07 Tooteinfo: Undefined; 08 Kasutus- ja hooldusjuhend: Undefined
AC_Pset_RenovationAndPhasing - Renovation Status: Existing

# IfcTransportElement: KONE_Combination_Bracket_KM927051G01_L205-370_LH:KONE_Combination_Bracket_KM927051G01_L205-370_LH:300924
In: 0 korrus
Type - ElementType: Element type KONE_Combination_Bracket_KM927051G01_L205-370_LH:KONE_Combination_Bracket_KM927051G01_L205-370_LH:300924
OperationType: ELEVATOR; CapacityByWeight: 0 kg; CapacityByNumber: 0; Classification: 1.17 IfcTransportElement (lift) (_RKAS BIM + ARCHICAD Classification)
Constraints - Moves With Nearby Elements: no; Offset: -873.081 mm
Dimensions - Area: 0.138293 m2; DIM_COMB_BRACKET_L: 268 mm; Volume: 0.000657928 m3
Other - Category: Specialty Equipment; Family: KONE_Combination_Bracket_KM927051G01_L205-370_LH: KONE_Combination_Bracket_KM927051G01_L205-370_LH; Family and Type: KONE_Combination_Bracket_KM927051G01_L205-370_LH: KONE_Combination_Bracket_KM927051G01_L205-370_LH; Type: KONE_Combination_Bracket_KM927051G01_L205-370_LH: KONE_Combination_Bracket_KM927051G01_L205-370_LH; Type Id: KONE_Combination_Bracket_KM927051G01_L205-370_LH: KONE_Combination_Bracket_KM927051G01_L205-370_LH
Phasing - Phase Created: Phase 3
SEADMED - 01 Nimetus: Undefined; 02 Tähis: KONE_Combination_Bracket_KM927051G01_L205-370_LH:KONE_Combination_Bracket_KM927051G01_L205-370_LH:300924; 03 Osasüsteem: Undefined; 04 Tehniline karakteristika: Undefined; 05 Tootja: Undefined; 06 Mudel või toote tunnus: Undefined; 07 Tooteinfo: Undefined; 08 Kasutus- ja hooldusjuhend: Undefined
AC_Pset_RenovationAndPhasing - Renovation Status: Existing

# IfcTransportElement: KONE_Combination_Bracket_KM927051G01_L205-370_LH:KONE_Combination_Bracket_KM927051G01_L205-370_LH:300925
In: 0 korrus
Type - ElementType: Element type KONE_Combination_Bracket_KM927051G01_L205-370_LH:KONE_Combination_Bracket_KM927051G01_L205-370_LH:300925
OperationType: ELEVATOR; CapacityByWeight: 0 kg; CapacityByNumber: 0; Classification: 1.17 IfcTransportElement (lift) (_RKAS BIM + ARCHICAD Classification)
Constraints - Moves With Nearby Elements: no; Offset: 1626.92 mm
Dimensions - Area: 0.138293 m2; DIM_COMB_BRACKET_L: 268 mm; Volume: 0.000657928 m3
Other - Category: Specialty Equipment; Family: KONE_Combination_Bracket_KM927051G01_L205-370_LH: KONE_Combination_Bracket_KM927051G01_L205-370_LH; Family and Type: KONE_Combination_Bracket_KM927051G01_L205-370_LH: KONE_Combination_Bracket_KM927051G01_L205-370_LH; Type: KONE_Combination_Bracket_KM927051G01_L205-370_LH: KONE_Combination_Bracket_KM927051G01_L205-370_LH; Type Id: KONE_Combination_Bracket_KM927051G01_L205-370_LH: KONE_Combination_Bracket_KM927051G01_L205-370_LH
Phasing - Phase Created: Phase 3
SEADMED - 01 Nimetus: Undefined; 02 Tähis: KONE_Combination_Bracket_KM927051G01_L205-370_LH:KONE_Combination_Bracket_KM927051G01_L205-370_LH:300925; 03 Osasüsteem: Undefined; 04 Tehniline karakteristika: Undefined; 05 Tootja: Undefined; 06 Mudel või toote tunnus: Undefined; 07 Tooteinfo: Undefined; 08 Kasutus- ja hooldusjuhend: Undefined
AC_Pset_RenovationAndPhasing - Renovation Status: Existing

# IfcTransportElement: KONE_Combination_Bracket_KM927051G01_L205-370_LH:KONE_Combination_Bracket_KM927051G01_L205-370_LH:300926
In: 0 korrus
Type - ElementType: Element type KONE_Combination_Bracket_KM927051G01_L205-370_LH:KONE_Combination_Bracket_KM927051G01_L205-370_LH:300926
OperationType: ELEVATOR; CapacityByWeight: 0 kg; CapacityByNumber: 0; Classification: 1.17 IfcTransportElement (lift) (_RKAS BIM + ARCHICAD Classification)
Constraints - Moves With Nearby Elements: no; Offset: 3626.92 mm
Dimensions - Area: 0.138293 m2; DIM_COMB_BRACKET_L: 268 mm; Volume: 0.000657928 m3
Other - Category: Specialty Equipment; Family: KONE_Combination_Bracket_KM927051G01_L205-370_LH: KONE_Combination_Bracket_KM927051G01_L205-370_LH; Family and Type: KONE_Combination_Bracket_KM927051G01_L205-370_LH: KONE_Combination_Bracket_KM927051G01_L205-370_LH; Type: KONE_Combination_Bracket_KM927051G01_L205-370_LH: KONE_Combination_Bracket_KM927051G01_L205-370_LH; Type Id: KONE_Combination_Bracket_KM927051G01_L205-370_LH: KONE_Combination_Bracket_KM927051G01_L205-370_LH
Phasing - Phase Created: Phase 3
SEADMED - 01 Nimetus: Undefined; 02 Tähis: KONE_Combination_Bracket_KM927051G01_L205-370_LH:KONE_Combination_Bracket_KM927051G01_L205-370_LH:300926; 03 Osasüsteem: Undefined; 04 Tehniline karakteristika: Undefined; 05 Tootja: Undefined; 06 Mudel või toote tunnus: Undefined; 07 Tooteinfo: Undefined; 08 Kasutus- ja hooldusjuhend: Undefined
AC_Pset_RenovationAndPhasing - Renovation Status: Existing

# IfcTransportElement: KONE_Combination_Bracket_KM927051G01_L205-370_LH:KONE_Combination_Bracket_KM927051G01_L205-370_LH:300927
In: 0 korrus
Type - ElementType: Element type KONE_Combination_Bracket_KM927051G01_L205-370_LH:KONE_Combination_Bracket_KM927051G01_L205-370_LH:300927
OperationType: ELEVATOR; CapacityByWeight: 0 kg; CapacityByNumber: 0; Classification: 1.17 IfcTransportElement (lift) (_RKAS BIM + ARCHICAD Classification)
Constraints - Moves With Nearby Elements: no; Offset: 5296.92 mm
Dimensions - Area: 0.138293 m2; DIM_COMB_BRACKET_L: 268 mm; Volume: 0.000657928 m3
Other - Category: Specialty Equipment; Family: KONE_Combination_Bracket_KM927051G01_L205-370_LH: KONE_Combination_Bracket_KM927051G01_L205-370_LH; Family and Type: KONE_Combination_Bracket_KM927051G01_L205-370_LH: KONE_Combination_Bracket_KM927051G01_L205-370_LH; Type: KONE_Combination_Bracket_KM927051G01_L205-370_LH: KONE_Combination_Bracket_KM927051G01_L205-370_LH; Type Id: KONE_Combination_Bracket_KM927051G01_L205-370_LH: KONE_Combination_Bracket_KM927051G01_L205-370_LH
Phasing - Phase Created: Phase 3
SEADMED - 01 Nimetus: Undefined; 02 Tähis: KONE_Combination_Bracket_KM927051G01_L205-370_LH:KONE_Combination_Bracket_KM927051G01_L205-370_LH:300927; 03 Osasüsteem: Undefined; 04 Tehniline karakteristika: Undefined; 05 Tootja: Undefined; 06 Mudel või toote tunnus: Undefined; 07 Tooteinfo: Undefined; 08 Kasutus- ja hooldusjuhend: Undefined
AC_Pset_RenovationAndPhasing - Renovation Status: Existing

# IfcTransportElement: KONE_Combination_Bracket_KM927051G01_L205-370_LH:KONE_Combination_Bracket_KM927051G01_L205-370_LH:300928
In: 0 korrus
Type - ElementType: Element type KONE_Combination_Bracket_KM927051G01_L205-370_LH:KONE_Combination_Bracket_KM927051G01_L205-370_LH:300928
OperationType: ELEVATOR; CapacityByWeight: 0 kg; CapacityByNumber: 0; Classification: 1.17 IfcTransportElement (lift) (_RKAS BIM + ARCHICAD Classification)
Constraints - Moves With Nearby Elements: no; Offset: 6896.92 mm
Dimensions - Area: 0.138293 m2; DIM_COMB_BRACKET_L: 268 mm; Volume: 0.000657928 m3
Other - Category: Specialty Equipment; Family: KONE_Combination_Bracket_KM927051G01_L205-370_LH: KONE_Combination_Bracket_KM927051G01_L205-370_LH; Family and Type: KONE_Combination_Bracket_KM927051G01_L205-370_LH: KONE_Combination_Bracket_KM927051G01_L205-370_LH; Type: KONE_Combination_Bracket_KM927051G01_L205-370_LH: KONE_Combination_Bracket_KM927051G01_L205-370_LH; Type Id: KONE_Combination_Bracket_KM927051G01_L205-370_LH: KONE_Combination_Bracket_KM927051G01_L205-370_LH
Phasing - Phase Created: Phase 3
SEADMED - 01 Nimetus: Undefined; 02 Tähis: KONE_Combination_Bracket_KM927051G01_L205-370_LH:KONE_Combination_Bracket_KM927051G01_L205-370_LH:300928; 03 Osasüsteem: Undefined; 04 Tehniline karakteristika: Undefined; 05 Tootja: Undefined; 06 Mudel või toote tunnus: Undefined; 07 Tooteinfo: Undefined; 08 Kasutus- ja hooldusjuhend: Undefined
AC_Pset_RenovationAndPhasing - Renovation Status: Existing

# IfcTransportElement: KONE_Combination_Bracket_KM927051G01_L205-370_LH:KONE_Combination_Bracket_KM927051G01_L205-370_LH:300929
In: 0 korrus
Type - ElementType: Element type KONE_Combination_Bracket_KM927051G01_L205-370_LH:KONE_Combination_Bracket_KM927051G01_L205-370_LH:300929
OperationType: ELEVATOR; CapacityByWeight: 0 kg; CapacityByNumber: 0; Classification: 1.17 IfcTransportElement (lift) (_RKAS BIM + ARCHICAD Classification)
Constraints - Moves With Nearby Elements: no; Offset: 8336.92 mm
Dimensions - Area: 0.138293 m2; DIM_COMB_BRACKET_L: 268 mm; Volume: 0.000657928 m3
Other - Category: Specialty Equipment; Family: KONE_Combination_Bracket_KM927051G01_L205-370_LH: KONE_Combination_Bracket_KM927051G01_L205-370_LH; Family and Type: KONE_Combination_Bracket_KM927051G01_L205-370_LH: KONE_Combination_Bracket_KM927051G01_L205-370_LH; Type: KONE_Combination_Bracket_KM927051G01_L205-370_LH: KONE_Combination_Bracket_KM927051G01_L205-370_LH; Type Id: KONE_Combination_Bracket_KM927051G01_L205-370_LH: KONE_Combination_Bracket_KM927051G01_L205-370_LH
Phasing - Phase Created: Phase 3
SEADMED - 01 Nimetus: Undefined; 02 Tähis: KONE_Combination_Bracket_KM927051G01_L205-370_LH:KONE_Combination_Bracket_KM927051G01_L205-370_LH:300929; 03 Osasüsteem: Undefined; 04 Tehniline karakteristika: Undefined; 05 Tootja: Undefined; 06 Mudel või toote tunnus: Undefined; 07 Tooteinfo: Undefined; 08 Kasutus- ja hooldusjuhend: Undefined
AC_Pset_RenovationAndPhasing - Renovation Status: Existing

# IfcTransportElement: KONE_DRIVE_KDL16L_KCE_LH:KONE_DRIVE_KDL16L_81-20_KCE_LH:300960
In: 0 korrus
Type - ElementType: Element type KONE_DRIVE_KDL16L_KCE_LH:KONE_DRIVE_KDL16L_81-20_KCE_LH:300960
OperationType: ELEVATOR; CapacityByWeight: 0 kg; CapacityByNumber: 0; Classification: 1.17 IfcTransportElement (lift) (_RKAS BIM + ARCHICAD Classification); Material: IFC Building Material (917)
Constraints - Moves With Nearby Elements: no; Offset: 7142 mm
Dimensions - Area: 0.397986 m2; DIM_DRIVE_DSH: 1037 mm; DIM_DRIVE_Z: 543 mm; DIM_L1: 50 mm; DIM_RBO_JAD: 543 mm; DIM_RBO_JAH: 1800 mm; DIM_RBO_L: 53 mm; DIM_RBO_OFFSET_TO_DRIVE: 0 mm; DIM_THD_HEIGHT: 1279 mm; Volume: 0.0217683 m3
Other - Category: Specialty Equipment; Family: KONE_DRIVE_KDL16L_KCE_LH: KONE_DRIVE_KDL16L_81-20_KCE_LH; Family and Type: KONE_DRIVE_KDL16L_KCE_LH: KONE_DRIVE_KDL16L_81-20_KCE_LH; Type: KONE_DRIVE_KDL16L_KCE_LH: KONE_DRIVE_KDL16L_81-20_KCE_LH; Type Id: KONE_DRIVE_KDL16L_KCE_LH: KONE_DRIVE_KDL16L_81-20_KCE_LH
Phasing - Phase Created: Phase 3
Visibility - VIS_RBO: yes
SEADMED - 01 Nimetus: Undefined; 02 Tähis: KONE_DRIVE_KDL16L_KCE_LH:KONE_DRIVE_KDL16L_81-20_KCE_LH:300960; 03 Osasüsteem: Undefined; 04 Tehniline karakteristika: Undefined; 05 Tootja: Undefined; 06 Mudel või toote tunnus: Undefined; 07 Tooteinfo: Undefined; 08 Kasutus- ja hooldusjuhend: Undefined
AC_Pset_RenovationAndPhasing - Renovation Status: Existing

# IfcTransportElement: KONE_Hook_Embedded:KONE_Hook_Embedded:300949
In: 0 korrus
Type - ElementType: Element type KONE_Hook_Embedded:KONE_Hook_Embedded:300949
OperationType: ELEVATOR; CapacityByWeight: 0 kg; CapacityByNumber: 0; Classification: 1.17 IfcTransportElement (lift) (_RKAS BIM + ARCHICAD Classification); Material: IFC Building Material (2)
Constraints - Moves With Nearby Elements: no; Offset: 10330 mm
Dimensions - Area: 0.229067 m2; Volume: 0.0128411 m3
Other - Category: Specialty Equipment; Family: KONE_Hook_Embedded: KONE_Hook_Embedded; Family and Type: KONE_Hook_Embedded: KONE_Hook_Embedded; Type: KONE_Hook_Embedded: KONE_Hook_Embedded; Type Id: KONE_Hook_Embedded: KONE_Hook_Embedded
Phasing - Phase Created: Phase 3
Text - Eye Diameter: D50 min.; Hook Diameter: D16-D18
SEADMED - 01 Nimetus: Undefined; 02 Tähis: KONE_Hook_Embedded:KONE_Hook_Embedded:300949; 03 Osasüsteem: Undefined; 04 Tehniline karakteristika: Undefined; 05 Tootja: Undefined; 06 Mudel või toote tunnus: Undefined; 07 Tooteinfo: Undefined; 08 Kasutus- ja hooldusjuhend: Undefined
AC_Pset_RenovationAndPhasing - Renovation Status: Existing

# IfcTransportElement: KONE_Hook_Embedded:KONE_Hook_Embedded:300950
In: 0 korrus
Type - ElementType: Element type KONE_Hook_Embedded:KONE_Hook_Embedded:300950
OperationType: ELEVATOR; CapacityByWeight: 0 kg; CapacityByNumber: 0; Classification: 1.17 IfcTransportElement (lift) (_RKAS BIM + ARCHICAD Classification)
Constraints - Moves With Nearby Elements: no; Offset: 10330 mm
Dimensions - Area: 0.229067 m2; Volume: 0.0128411 m3
Other - Category: Specialty Equipment; Family: KONE_Hook_Embedded: KONE_Hook_Embedded; Family and Type: KONE_Hook_Embedded: KONE_Hook_Embedded; Type: KONE_Hook_Embedded: KONE_Hook_Embedded; Type Id: KONE_Hook_Embedded: KONE_Hook_Embedded
Phasing - Phase Created: Phase 3
Text - Eye Diameter: D50 min.; Hook Diameter: D16-D18
SEADMED - 01 Nimetus: Undefined; 02 Tähis: KONE_Hook_Embedded:KONE_Hook_Embedded:300950; 03 Osasüsteem: Undefined; 04 Tehniline karakteristika: Undefined; 05 Tootja: Undefined; 06 Mudel või toote tunnus: Undefined; 07 Tooteinfo: Undefined; 08 Kasutus- ja hooldusjuhend: Undefined
AC_Pset_RenovationAndPhasing - Renovation Status: Existing

# IfcTransportElement: KONE_Hook_Embedded:KONE_Hook_Embedded:300951
In: 0 korrus
Type - ElementType: Element type KONE_Hook_Embedded:KONE_Hook_Embedded:300951
OperationType: ELEVATOR; CapacityByWeight: 0 kg; CapacityByNumber: 0; Classification: 1.17 IfcTransportElement (lift) (_RKAS BIM + ARCHICAD Classification); Material: IFC Building Material (2)
Constraints - Moves With Nearby Elements: no; Offset: 10330 mm
Dimensions - Area: 0.229067 m2; Volume: 0.0128411 m3
Other - Category: Specialty Equipment; Family: KONE_Hook_Embedded: KONE_Hook_Embedded; Family and Type: KONE_Hook_Embedded: KONE_Hook_Embedded; Type: KONE_Hook_Embedded: KONE_Hook_Embedded; Type Id: KONE_Hook_Embedded: KONE_Hook_Embedded
Phasing - Phase Created: Phase 3
Text - Eye Diameter: D50 min.; Hook Diameter: D16-D18
SEADMED - 01 Nimetus: Undefined; 02 Tähis: KONE_Hook_Embedded:KONE_Hook_Embedded:300951; 03 Osasüsteem: Undefined; 04 Tehniline karakteristika: Undefined; 05 Tootja: Undefined; 06 Mudel või toote tunnus: Undefined; 07 Tooteinfo: Undefined; 08 Kasutus- ja hooldusjuhend: Undefined
AC_Pset_RenovationAndPhasing - Renovation Status: Existing

# IfcTransportElement: KONE_LDO_KES201_2L_P15_TX:KONE_LDO_KES201_2L_P15_TX:300903
In: 0 korrus
Type - ElementType: Element type KONE_LDO_KES201_2L_P15_TX:KONE_LDO_KES201_2L_P15_TX:300903
CapacityByWeight: 0 kg; CapacityByNumber: 0; Classification: 1.17 IfcTransportElement (lift) (_RKAS BIM + ARCHICAD Classification); Material: Default (15)
Other - Category: Specialty Equipment; Family Name: KONE_LDO_KES201_2L_P15_TX; Family: KONE_LDO_KES201_2L_P15_TX: KONE_LDO_KES201_2L_P15_TX; Family and Type: KONE_LDO_KES201_2L_P15_TX: KONE_LDO_KES201_2L_P15_TX; TYP_DOOR_FIRE_CLASS_CODE: yes; Type: KONE_LDO_KES201_2L_P15_TX: KONE_LDO_KES201_2L_P15_TX; Type Id: KONE_LDO_KES201_2L_P15_TX: KONE_LDO_KES201_2L_P15_TX
Identity Data - OmniClass Number: 23.50.05.11.11.14; OmniClass Title: Passenger Electric Traction Elevators; Revision: SO-03.12.101_en_E.1_Main; RevisionDate: 28/8/2019; Type Name: KONE_LDO_KES201_2L_P15_TX
Dimensions - DIM_DOOR_CUTOUT_DEPTH_FROM_WALL: 999 mm; DIM_LDO_RECESS_MANUAL: 0 mm; DIM_RAILING_FIX_FROM_SHAFT_WALL: 0 mm; Area: 24.0301 m2; DIM_DOOR_HH: 2100 mm; DIM_DOOR_HR: 2280 mm; DIM_DOOR_LL: 900 mm; DIM_DOOR_LR: 1200 mm; DIM_DOOR_LR_LEFTSIDE: 600 mm; DIM_DOOR_LR_RIGHTSIDE: 600 mm; DIM_DOOR_PH_LEFTSIDE: 620 mm; DIM_DOOR_PH_RIGHTSIDE: 970 mm; DIM_FLOORING_THICKNESS: 0 mm; DIM_FRAME_BR_FIX_LEVEL: 0 mm; DIM_FRAME_BR_FIX_LEVEL_OPT_1: 0 mm; DIM_FRAME_BR_FIX_LEVEL_OPT_2: 0 mm; DIM_FRAME_BR_FIX_LEVEL_OPT_3: 0 mm; DIM_FRAME_BR_FIX_LEVEL_OPT_4: 0 mm; DIM_FRAME_BR_HEIGHT: 0 mm; DIM_FRAME_BR_LEFTSIDE: 0 mm; DIM_FRAME_BR_LEFTSIDE_OPT_1: 0 mm; DIM_FRAME_BR_LEFTSIDE_OPT_2: 0 mm; DIM_FRAME_BR_LEFTSIDE_OPT_3: 0 mm; DIM_FRAME_BR_LEFTSIDE_OPT_4: 0 mm; DIM_FRAME_BR_OPT_HEIGHT: 0 mm; DIM_FRAME_BR_RIGHTSIDE: 0 mm; DIM_FRAME_BR_RIGHTSIDE_OPT_1: 0 mm; DIM_FRAME_BR_RIGHTSIDE_OPT_2: 0 mm; DIM_FRAME_BR_RIGHTSIDE_OPT_3: 0 mm; DIM_FRAME_BR_RIGHTSIDE_OPT_4: 0 mm; DIM_FRAME_BR_SUPPORT_LEFTSIDE: 0 mm; DIM_FRAME_BR_SUPPORT_LEFTSIDE_OPT: 0 mm; DIM_FRAME_BR_SUPPORT_RIGHTSIDE: 0 mm; DIM_FRAME_BR_SUPPORT_RIGHTSIDE_OPT: 0 mm; DIM_LDO_HA: 150 mm; DIM_LDO_LA: 120 mm; DIM_LDO_LB: 120 mm; DIM_LDO_RECESS_MANUAL_FROM_SILL_LINE: 140 mm; DIM_LDO_WALL_TO_SILL_LINE: 140 mm; DIM_PANEL_FRAME_BOTTOM_WIDTH: 1 mm; DIM_PANEL_FRAME_LEFT_WIDTH: 1 mm; DIM_PANEL_FRAME_RIGHT_WIDTH: 1 mm; DIM_PANEL_FRAME_TOP_WIDTH: 1 mm; DIM_PANEL_GAP_TO_FRAME: 5 mm; DIM_PANEL_THICKNESS_BACK: 45 mm; DIM_PANEL_THICKNESS_FRONT: 45 mm; DIM_PANEL_WIDTH: 472 mm; DIM_RAILING_BR_FIX_LEVEL: 2430 mm; DIM_RAILING_BR_FIX_LEVEL_OPT: 2430 mm; DIM_RAILING_BR_LEFTSIDE: 510 mm; DIM_RAILING_BR_LEFTSIDE_OPT: 0 mm; DIM_RAILING_BR_RIGHTSIDE: 510 mm; DIM_RAILING_BR_RIGHTSIDE_OPT: 850 mm; DIM_RAILING_BR_TOP_FROM_HH: 500 mm; DIM_RAILING_CUTOUT_EXT: 0 mm; DIM_RAILING_FIX_FROM_SILL_LINE: 140 mm; DIM_SHAFT_TOLERANCE: 25 mm; DIM_SHAFT_WALL_THICKNESS: 150 mm; DIM_SILL_BR_BOTTOM_FROM_FFL: 275 mm; DIM_SILL_BR_FIX_LEVEL: 100 mm; DIM_SILL_BR_LEFTSIDE_1: 0 mm; DIM_SILL_BR_LEFTSIDE_2: 0 mm; DIM_SILL_BR_LEFTSIDE_3: 350 mm; DIM_SILL_BR_LEFTSIDE_4: 0 mm; DIM_SILL_BR_LEFTSIDE_5: 0 mm; DIM_SILL_BR_RIGHTSIDE_1: 0 mm; DIM_SILL_BR_RIGHTSIDE_2: 0 mm; DIM_SILL_BR_RIGHTSIDE_3: 350 mm; DIM_SILL_BR_RIGHTSIDE_4: 0 mm; DIM_SILL_BR_RIGHTSIDE_5: 0 mm; DIM_SILL_CUTOUT_EXT: 30 mm; DIM_SILL_FIX_FROM_SHAFT_WALL: 0 mm; DIM_SILL_FIX_FROM_SILL_LINE: 140 mm; DIM_SILL_PH_DEPTH: 140 mm; DIM_SILL_PH_HEIGHT: 2 mm; Volume: 4.61209 m3
Constraints - Default Elevation: 1219.2 mm; Moves With Nearby Elements: no; Offset: 0 mm
Pset_BuildingElementProxyCommon - Reference: KONE_LDO_KES201_2L_P15_TX
Phasing - Phase Created: Phase 3
Visibility - VIS_CINSERT: no; VIS_DOOR_OPENING: no; VIS_DOOR_WALL_CUTOUT: no; VIS_FRAME: yes; VIS_FRAME_BR_LEFTSIDE_OPT_1: no; VIS_FRAME_BR_LEFTSIDE_OPT_2: no; VIS_FRAME_BR_LEFTSIDE_OPT_3: no; VIS_FRAME_BR_LEFTSIDE_OPT_4: no; VIS_FRAME_BR_RIGHTSIDE_OPT_1: no; VIS_FRAME_BR_RIGHTSIDE_OPT_2: no; VIS_FRAME_BR_RIGHTSIDE_OPT_3: no; VIS_FRAME_BR_RIGHTSIDE_OPT_4: no; VIS_FRAME_BRACKETS: no; VIS_FRAME_CINSERT_OPT_1: no; VIS_FRAME_CINSERT_OPT_2: no; VIS_FRAME_MAP_LEFT: no; VIS_FRAME_MAP_RIGHT: no; VIS_PANEL_GLASS_WINDOW_LEFT: no; VIS_PANEL_GLASS_WINDOW_RIGHT: no; VIS_RAILING_BR_LEFTSIDE: yes; VIS_RAILING_BR_LEFTSIDE_OPT: no; VIS_RAILING_BR_RIGHTSIDE: yes; VIS_RAILING_BR_RIGHTSIDE_OPT: no; VIS_RAILING_BRACKETS: yes; VIS_RAILING_CINSERT_OPT: no; VIS_SILL_BR_LEFTSIDE_1: yes; VIS_SILL_BR_LEFTSIDE_2: no; VIS_SILL_BR_LEFTSIDE_3: yes; VIS_SILL_BR_LEFTSIDE_4: no; VIS_SILL_BR_LEFTSIDE_5: no; VIS_SILL_BR_RIGHTSIDE_1: no; VIS_SILL_BR_RIGHTSIDE_2: no; VIS_SILL_BR_RIGHTSIDE_3: yes; VIS_SILL_BR_RIGHTSIDE_4: no; VIS_SILL_BR_RIGHTSIDE_5: no; VIS_SILL_BRACKETS: yes; VIS_SILL_CINSERT_OPT_1: no; VIS_SILL_CINSERT_OPT_2: no; VIS_SILL_CINSERT_OPT_3: no; VIS_SILL_CINSERT_OPT_4: no; VIS_SILL_CINSERT_VERTICAL: no; VIS_SILL_POV: no
SEADMED - 01 Nimetus: Undefined; 02 Tähis: KONE_LDO_KES201_2L_P15_TX:KONE_LDO_KES201_2L_P15_TX:300903; 03 Osasüsteem: Undefined; 04 Tehniline karakteristika: Undefined; 05 Tootja: Undefined; 06 Mudel või toote tunnus: Undefined; 07 Tooteinfo: Undefined; 08 Kasutus- ja hooldusjuhend: Undefined
AC_Pset_RenovationAndPhasing - Renovation Status: Existing

# IfcTransportElement: KONE_LDO_KES201_2L_P15_TX:KONE_LDO_KES201_2L_P15_TX:300905
In: 0 korrus
Type - ElementType: Element type KONE_LDO_KES201_2L_P15_TX:KONE_LDO_KES201_2L_P15_TX:300905
CapacityByWeight: 0 kg; CapacityByNumber: 0; Classification: 1.17 IfcTransportElement (lift) (_RKAS BIM + ARCHICAD Classification); Material: Default (15)
Other - Category: Specialty Equipment; Family Name: KONE_LDO_KES201_2L_P15_TX; Family: KONE_LDO_KES201_2L_P15_TX: KONE_LDO_KES201_2L_P15_TX; Family and Type: KONE_LDO_KES201_2L_P15_TX: KONE_LDO_KES201_2L_P15_TX; TYP_DOOR_FIRE_CLASS_CODE: yes; Type: KONE_LDO_KES201_2L_P15_TX: KONE_LDO_KES201_2L_P15_TX; Type Id: KONE_LDO_KES201_2L_P15_TX: KONE_LDO_KES201_2L_P15_TX
Identity Data - OmniClass Number: 23.50.05.11.11.14; OmniClass Title: Passenger Electric Traction Elevators; Revision: SO-03.12.101_en_E.1_Main; RevisionDate: 28/8/2019; Type Name: KONE_LDO_KES201_2L_P15_TX
Dimensions - DIM_DOOR_CUTOUT_DEPTH_FROM_WALL: 999 mm; DIM_LDO_RECESS_MANUAL: 0 mm; DIM_RAILING_FIX_FROM_SHAFT_WALL: 0 mm; DIM_FRAME_BR_FIX_LEVEL: 0 mm; DIM_FRAME_BR_FIX_LEVEL_OPT_1: 0 mm; DIM_FRAME_BR_FIX_LEVEL_OPT_2: 0 mm; DIM_FRAME_BR_FIX_LEVEL_OPT_3: 0 mm; DIM_FRAME_BR_FIX_LEVEL_OPT_4: 0 mm; DIM_FRAME_BR_HEIGHT: 0 mm; DIM_FRAME_BR_LEFTSIDE: 0 mm; DIM_FRAME_BR_LEFTSIDE_OPT_1: 0 mm; DIM_FRAME_BR_LEFTSIDE_OPT_2: 0 mm; DIM_FRAME_BR_LEFTSIDE_OPT_3: 0 mm; DIM_FRAME_BR_LEFTSIDE_OPT_4: 0 mm; DIM_FRAME_BR_OPT_HEIGHT: 0 mm; DIM_FRAME_BR_RIGHTSIDE: 0 mm; DIM_FRAME_BR_RIGHTSIDE_OPT_1: 0 mm; DIM_FRAME_BR_RIGHTSIDE_OPT_2: 0 mm; DIM_FRAME_BR_RIGHTSIDE_OPT_3: 0 mm; DIM_FRAME_BR_RIGHTSIDE_OPT_4: 0 mm; DIM_FRAME_BR_SUPPORT_LEFTSIDE: 0 mm; DIM_FRAME_BR_SUPPORT_LEFTSIDE_OPT: 0 mm; DIM_FRAME_BR_SUPPORT_RIGHTSIDE: 0 mm; DIM_FRAME_BR_SUPPORT_RIGHTSIDE_OPT: 0 mm; DIM_RAILING_BR_LEFTSIDE_OPT: 0 mm; DIM_RAILING_CUTOUT_EXT: 0 mm; DIM_SILL_BR_LEFTSIDE_1: 0 mm; DIM_SILL_BR_LEFTSIDE_2: 0 mm; DIM_SILL_BR_LEFTSIDE_4: 0 mm; DIM_SILL_BR_LEFTSIDE_5: 0 mm; DIM_SILL_BR_RIGHTSIDE_1: 0 mm; DIM_SILL_BR_RIGHTSIDE_2: 0 mm; DIM_SILL_BR_RIGHTSIDE_4: 0 mm; DIM_SILL_BR_RIGHTSIDE_5: 0 mm; DIM_SILL_FIX_FROM_SHAFT_WALL: 0 mm; Area: 24.0301 m2; DIM_DOOR_HH: 2100 mm; DIM_DOOR_HR: 2280 mm; DIM_DOOR_LL: 900 mm; DIM_DOOR_LR: 1200 mm; DIM_DOOR_LR_LEFTSIDE: 600 mm; DIM_DOOR_LR_RIGHTSIDE: 600 mm; DIM_DOOR_PH_LEFTSIDE: 620 mm; DIM_DOOR_PH_RIGHTSIDE: 970 mm; DIM_FLOORING_THICKNESS: 150 mm; DIM_LDO_HA: 150 mm; DIM_LDO_LA: 120 mm; DIM_LDO_LB: 120 mm; DIM_LDO_RECESS_MANUAL_FROM_SILL_LINE: 140 mm; DIM_LDO_WALL_TO_SILL_LINE: 140 mm; DIM_PANEL_FRAME_BOTTOM_WIDTH: 1 mm; DIM_PANEL_FRAME_LEFT_WIDTH: 1 mm; DIM_PANEL_FRAME_RIGHT_WIDTH: 1 mm; DIM_PANEL_FRAME_TOP_WIDTH: 1 mm; DIM_PANEL_GAP_TO_FRAME: 5 mm; DIM_PANEL_THICKNESS_BACK: 45 mm; DIM_PANEL_THICKNESS_FRONT: 45 mm; DIM_PANEL_WIDTH: 472 mm; DIM_RAILING_BR_FIX_LEVEL: 2430 mm; DIM_RAILING_BR_FIX_LEVEL_OPT: 2430 mm; DIM_RAILING_BR_LEFTSIDE: 510 mm; DIM_RAILING_BR_RIGHTSIDE: 510 mm; DIM_RAILING_BR_RIGHTSIDE_OPT: 850 mm; DIM_RAILING_BR_TOP_FROM_HH: 500 mm; DIM_RAILING_FIX_FROM_SILL_LINE: 140 mm; DIM_SHAFT_TOLERANCE: 25 mm; DIM_SHAFT_WALL_THICKNESS: 150 mm; DIM_SILL_BR_BOTTOM_FROM_FFL: 275 mm; DIM_SILL_BR_FIX_LEVEL: 250 mm; DIM_SILL_BR_LEFTSIDE_3: 350 mm; DIM_SILL_BR_RIGHTSIDE_3: 350 mm; DIM_SILL_CUTOUT_EXT: 30 mm; DIM_SILL_FIX_FROM_SILL_LINE: 140 mm; DIM_SILL_PH_DEPTH: 140 mm; DIM_SILL_PH_HEIGHT: 2 mm; Volume: 4.61209 m3
Constraints - Default Elevation: 1219.2 mm; Moves With Nearby Elements: no; Offset: 3415 mm
Pset_BuildingElementProxyCommon - Reference: KONE_LDO_KES201_2L_P15_TX
Phasing - Phase Created: Phase 3
Visibility - VIS_CINSERT: no; VIS_DOOR_OPENING: no; VIS_DOOR_WALL_CUTOUT: no; VIS_FRAME: yes; VIS_FRAME_BR_LEFTSIDE_OPT_1: no; VIS_FRAME_BR_LEFTSIDE_OPT_2: no; VIS_FRAME_BR_LEFTSIDE_OPT_3: no; VIS_FRAME_BR_LEFTSIDE_OPT_4: no; VIS_FRAME_BR_RIGHTSIDE_OPT_1: no; VIS_FRAME_BR_RIGHTSIDE_OPT_2: no; VIS_FRAME_BR_RIGHTSIDE_OPT_3: no; VIS_FRAME_BR_RIGHTSIDE_OPT_4: no; VIS_FRAME_BRACKETS: no; VIS_FRAME_CINSERT_OPT_1: no; VIS_FRAME_CINSERT_OPT_2: no; VIS_FRAME_MAP_LEFT: no; VIS_FRAME_MAP_RIGHT: no; VIS_PANEL_GLASS_WINDOW_LEFT: no; VIS_PANEL_GLASS_WINDOW_RIGHT: no; VIS_RAILING_BR_LEFTSIDE: yes; VIS_RAILING_BR_LEFTSIDE_OPT: no; VIS_RAILING_BR_RIGHTSIDE: yes; VIS_RAILING_BR_RIGHTSIDE_OPT: no; VIS_RAILING_BRACKETS: yes; VIS_RAILING_CINSERT_OPT: no; VIS_SILL_BR_LEFTSIDE_1: yes; VIS_SILL_BR_LEFTSIDE_2: no; VIS_SILL_BR_LEFTSIDE_3: yes; VIS_SILL_BR_LEFTSIDE_4: no; VIS_SILL_BR_LEFTSIDE_5: no; VIS_SILL_BR_RIGHTSIDE_1: no; VIS_SILL_BR_RIGHTSIDE_2: no; VIS_SILL_BR_RIGHTSIDE_3: yes; VIS_SILL_BR_RIGHTSIDE_4: no; VIS_SILL_BR_RIGHTSIDE_5: no; VIS_SILL_BRACKETS: yes; VIS_SILL_CINSERT_OPT_1: no; VIS_SILL_CINSERT_OPT_2: no; VIS_SILL_CINSERT_OPT_3: no; VIS_SILL_CINSERT_OPT_4: no; VIS_SILL_CINSERT_VERTICAL: no; VIS_SILL_POV: no
SEADMED - 01 Nimetus: Undefined; 02 Tähis: KONE_LDO_KES201_2L_P15_TX:KONE_LDO_KES201_2L_P15_TX:300905; 03 Osasüsteem: Undefined; 04 Tehniline karakteristika: Undefined; 05 Tootja: Undefined; 06 Mudel või toote tunnus: Undefined; 07 Tooteinfo: Undefined; 08 Kasutus- ja hooldusjuhend: Undefined
AC_Pset_RenovationAndPhasing - Renovation Status: Existing

# IfcTransportElement: KONE_LDO_KES201_2L_P15_TX:KONE_LDO_KES201_2L_P15_TX:300906
In: 0 korrus
Type - ElementType: Element type KONE_LDO_KES201_2L_P15_TX:KONE_LDO_KES201_2L_P15_TX:300906
CapacityByWeight: 0 kg; CapacityByNumber: 0; Classification: 1.17 IfcTransportElement (lift) (_RKAS BIM + ARCHICAD Classification); Material: Default (16)
Other - Category: Specialty Equipment; Family Name: KONE_LDO_KES201_2L_P15_TX; Family: KONE_LDO_KES201_2L_P15_TX: KONE_LDO_KES201_2L_P15_TX; Family and Type: KONE_LDO_KES201_2L_P15_TX: KONE_LDO_KES201_2L_P15_TX; TYP_DOOR_FIRE_CLASS_CODE: yes; Type: KONE_LDO_KES201_2L_P15_TX: KONE_LDO_KES201_2L_P15_TX; Type Id: KONE_LDO_KES201_2L_P15_TX: KONE_LDO_KES201_2L_P15_TX
Identity Data - OmniClass Number: 23.50.05.11.11.14; OmniClass Title: Passenger Electric Traction Elevators; Revision: SO-03.12.101_en_E.1_Main; RevisionDate: 28/8/2019; Type Name: KONE_LDO_KES201_2L_P15_TX
Dimensions - DIM_DOOR_CUTOUT_DEPTH_FROM_WALL: 999 mm; DIM_LDO_RECESS_MANUAL: 0 mm; DIM_RAILING_FIX_FROM_SHAFT_WALL: 0 mm; DIM_FLOORING_THICKNESS: 0 mm; DIM_FRAME_BR_FIX_LEVEL: 0 mm; DIM_FRAME_BR_FIX_LEVEL_OPT_1: 0 mm; DIM_FRAME_BR_FIX_LEVEL_OPT_2: 0 mm; DIM_FRAME_BR_FIX_LEVEL_OPT_3: 0 mm; DIM_FRAME_BR_FIX_LEVEL_OPT_4: 0 mm; DIM_FRAME_BR_HEIGHT: 0 mm; DIM_FRAME_BR_LEFTSIDE: 0 mm; DIM_FRAME_BR_LEFTSIDE_OPT_1: 0 mm; DIM_FRAME_BR_LEFTSIDE_OPT_2: 0 mm; DIM_FRAME_BR_LEFTSIDE_OPT_3: 0 mm; DIM_FRAME_BR_LEFTSIDE_OPT_4: 0 mm; DIM_FRAME_BR_OPT_HEIGHT: 0 mm; DIM_FRAME_BR_RIGHTSIDE: 0 mm; DIM_FRAME_BR_RIGHTSIDE_OPT_1: 0 mm; DIM_FRAME_BR_RIGHTSIDE_OPT_2: 0 mm; DIM_FRAME_BR_RIGHTSIDE_OPT_3: 0 mm; DIM_FRAME_BR_RIGHTSIDE_OPT_4: 0 mm; DIM_FRAME_BR_SUPPORT_LEFTSIDE: 0 mm; DIM_FRAME_BR_SUPPORT_LEFTSIDE_OPT: 0 mm; DIM_FRAME_BR_SUPPORT_RIGHTSIDE: 0 mm; DIM_FRAME_BR_SUPPORT_RIGHTSIDE_OPT: 0 mm; DIM_RAILING_BR_LEFTSIDE_OPT: 0 mm; DIM_RAILING_CUTOUT_EXT: 0 mm; DIM_SILL_BR_LEFTSIDE_1: 0 mm; DIM_SILL_BR_LEFTSIDE_2: 0 mm; DIM_SILL_BR_LEFTSIDE_4: 0 mm; DIM_SILL_BR_LEFTSIDE_5: 0 mm; DIM_SILL_BR_RIGHTSIDE_1: 0 mm; DIM_SILL_BR_RIGHTSIDE_2: 0 mm; DIM_SILL_BR_RIGHTSIDE_4: 0 mm; DIM_SILL_BR_RIGHTSIDE_5: 0 mm; DIM_SILL_FIX_FROM_SHAFT_WALL: 0 mm; Area: 24.0301 m2; DIM_DOOR_HH: 2100 mm; DIM_DOOR_HR: 2280 mm; DIM_DOOR_LL: 900 mm; DIM_DOOR_LR: 1200 mm; DIM_DOOR_LR_LEFTSIDE: 600 mm; DIM_DOOR_LR_RIGHTSIDE: 600 mm; DIM_DOOR_PH_LEFTSIDE: 620 mm; DIM_DOOR_PH_RIGHTSIDE: 970 mm; DIM_LDO_HA: 150 mm; DIM_LDO_LA: 120 mm; DIM_LDO_LB: 120 mm; DIM_LDO_RECESS_MANUAL_FROM_SILL_LINE: 140 mm; DIM_LDO_WALL_TO_SILL_LINE: 140 mm; DIM_PANEL_FRAME_BOTTOM_WIDTH: 1 mm; DIM_PANEL_FRAME_LEFT_WIDTH: 1 mm; DIM_PANEL_FRAME_RIGHT_WIDTH: 1 mm; DIM_PANEL_FRAME_TOP_WIDTH: 1 mm; DIM_PANEL_GAP_TO_FRAME: 5 mm; DIM_PANEL_THICKNESS_BACK: 45 mm; DIM_PANEL_THICKNESS_FRONT: 45 mm; DIM_PANEL_WIDTH: 472 mm; DIM_RAILING_BR_FIX_LEVEL: 2430 mm; DIM_RAILING_BR_FIX_LEVEL_OPT: 2430 mm; DIM_RAILING_BR_LEFTSIDE: 510 mm; DIM_RAILING_BR_RIGHTSIDE: 510 mm; DIM_RAILING_BR_RIGHTSIDE_OPT: 850 mm; DIM_RAILING_BR_TOP_FROM_HH: 500 mm; DIM_RAILING_FIX_FROM_SILL_LINE: 140 mm; DIM_SHAFT_TOLERANCE: 25 mm; DIM_SHAFT_WALL_THICKNESS: 150 mm; DIM_SILL_BR_BOTTOM_FROM_FFL: 275 mm; DIM_SILL_BR_FIX_LEVEL: 100 mm; DIM_SILL_BR_LEFTSIDE_3: 350 mm; DIM_SILL_BR_RIGHTSIDE_3: 350 mm; DIM_SILL_CUTOUT_EXT: 30 mm; DIM_SILL_FIX_FROM_SILL_LINE: 140 mm; DIM_SILL_PH_DEPTH: 140 mm; DIM_SILL_PH_HEIGHT: 2 mm; Volume: 4.64449 m3
Constraints - Default Elevation: 1219.2 mm; Moves With Nearby Elements: no; Offset: 6830 mm
Pset_BuildingElementProxyCommon - Reference: KONE_LDO_KES201_2L_P15_TX
Phasing - Phase Created: Phase 3
Visibility - VIS_CINSERT: no; VIS_DOOR_OPENING: no; VIS_DOOR_WALL_CUTOUT: no; VIS_FRAME: yes; VIS_FRAME_BR_LEFTSIDE_OPT_1: no; VIS_FRAME_BR_LEFTSIDE_OPT_2: no; VIS_FRAME_BR_LEFTSIDE_OPT_3: no; VIS_FRAME_BR_LEFTSIDE_OPT_4: no; VIS_FRAME_BR_RIGHTSIDE_OPT_1: no; VIS_FRAME_BR_RIGHTSIDE_OPT_2: no; VIS_FRAME_BR_RIGHTSIDE_OPT_3: no; VIS_FRAME_BR_RIGHTSIDE_OPT_4: no; VIS_FRAME_BRACKETS: no; VIS_FRAME_CINSERT_OPT_1: no; VIS_FRAME_CINSERT_OPT_2: no; VIS_FRAME_MAP_RIGHT: no; VIS_PANEL_GLASS_WINDOW_LEFT: no; VIS_PANEL_GLASS_WINDOW_RIGHT: no; VIS_RAILING_BR_LEFTSIDE: yes; VIS_RAILING_BR_LEFTSIDE_OPT: no; VIS_RAILING_BR_RIGHTSIDE: yes; VIS_RAILING_BR_RIGHTSIDE_OPT: no; VIS_RAILING_BRACKETS: yes; VIS_RAILING_CINSERT_OPT: no; VIS_SILL_BR_LEFTSIDE_1: yes; VIS_SILL_BR_LEFTSIDE_2: no; VIS_SILL_BR_LEFTSIDE_3: yes; VIS_SILL_BR_LEFTSIDE_4: no; VIS_SILL_BR_LEFTSIDE_5: no; VIS_SILL_BR_RIGHTSIDE_1: no; VIS_SILL_BR_RIGHTSIDE_2: no; VIS_SILL_BR_RIGHTSIDE_3: yes; VIS_SILL_BR_RIGHTSIDE_4: no; VIS_SILL_BR_RIGHTSIDE_5: no; VIS_SILL_BRACKETS: yes; VIS_SILL_CINSERT_OPT_1: no; VIS_SILL_CINSERT_OPT_2: no; VIS_SILL_CINSERT_OPT_3: no; VIS_SILL_CINSERT_OPT_4: no; VIS_SILL_CINSERT_VERTICAL: no; VIS_SILL_POV: no; VIS_FRAME_MAP_LEFT: yes
SEADMED - 01 Nimetus: Undefined; 02 Tähis: KONE_LDO_KES201_2L_P15_TX:KONE_LDO_KES201_2L_P15_TX:300906; 03 Osasüsteem: Undefined; 04 Tehniline karakteristika: Undefined; 05 Tootja: Undefined; 06 Mudel või toote tunnus: Undefined; 07 Tooteinfo: Undefined; 08 Kasutus- ja hooldusjuhend: Undefined
AC_Pset_RenovationAndPhasing - Renovation Status: Existing

# IfcTransportElement: KONE_LDO_KES201_2R_P15_TX:KONE_LDO_KES201_2R_P15_TX:300904
In: 0 korrus
Type - ElementType: Element type KONE_LDO_KES201_2R_P15_TX:KONE_LDO_KES201_2R_P15_TX:300904
CapacityByWeight: 0 kg; CapacityByNumber: 0; Classification: 1.17 IfcTransportElement (lift) (_RKAS BIM + ARCHICAD Classification); Material: Default (15)
Other - Category: Specialty Equipment; Family Name: KONE_LDO_KES201_2R_P15_TX; TYP_DOOR_FIRE_CLASS_CODE: yes; Family: KONE_LDO_KES201_2R_P15_TX: KONE_LDO_KES201_2R_P15_TX; Family and Type: KONE_LDO_KES201_2R_P15_TX: KONE_LDO_KES201_2R_P15_TX; Type: KONE_LDO_KES201_2R_P15_TX: KONE_LDO_KES201_2R_P15_TX; Type Id: KONE_LDO_KES201_2R_P15_TX: KONE_LDO_KES201_2R_P15_TX
Identity Data - OmniClass Number: 23.50.05.11.11.14; OmniClass Title: Passenger Electric Traction Elevators; Revision: SO-03.12.101_en_E.1_Main; RevisionDate: 28/8/2019; Type Name: KONE_LDO_KES201_2R_P15_TX
Dimensions - DIM_LDO_RECESS_MANUAL: 0 mm; DIM_RAILING_FIX_FROM_SHAFT_WALL: 0 mm; DIM_DOOR_CUTOUT_DEPTH_FROM_WALL: 999 mm; DIM_FLOORING_THICKNESS: 0 mm; DIM_FRAME_BR_FIX_LEVEL: 0 mm; DIM_FRAME_BR_FIX_LEVEL_OPT_1: 0 mm; DIM_FRAME_BR_FIX_LEVEL_OPT_2: 0 mm; DIM_FRAME_BR_FIX_LEVEL_OPT_3: 0 mm; DIM_FRAME_BR_FIX_LEVEL_OPT_4: 0 mm; DIM_FRAME_BR_HEIGHT: 0 mm; DIM_FRAME_BR_LEFTSIDE: 0 mm; DIM_FRAME_BR_LEFTSIDE_OPT_1: 0 mm; DIM_FRAME_BR_LEFTSIDE_OPT_2: 0 mm; DIM_FRAME_BR_LEFTSIDE_OPT_3: 0 mm; DIM_FRAME_BR_LEFTSIDE_OPT_4: 0 mm; DIM_FRAME_BR_OPT_HEIGHT: 0 mm; DIM_FRAME_BR_RIGHTSIDE: 0 mm; DIM_FRAME_BR_RIGHTSIDE_OPT_1: 0 mm; DIM_FRAME_BR_RIGHTSIDE_OPT_2: 0 mm; DIM_FRAME_BR_RIGHTSIDE_OPT_3: 0 mm; DIM_FRAME_BR_RIGHTSIDE_OPT_4: 0 mm; DIM_FRAME_BR_SUPPORT_LEFTSIDE: 0 mm; DIM_FRAME_BR_SUPPORT_LEFTSIDE_OPT: 0 mm; DIM_FRAME_BR_SUPPORT_RIGHTSIDE: 0 mm; DIM_FRAME_BR_SUPPORT_RIGHTSIDE_OPT: 0 mm; DIM_RAILING_BR_LEFTSIDE_OPT: 0 mm; DIM_RAILING_CUTOUT_EXT: 0 mm; DIM_SILL_BR_LEFTSIDE_1: 0 mm; DIM_SILL_BR_LEFTSIDE_2: 0 mm; DIM_SILL_BR_LEFTSIDE_4: 0 mm; DIM_SILL_BR_LEFTSIDE_5: 0 mm; DIM_SILL_BR_RIGHTSIDE_1: 0 mm; DIM_SILL_BR_RIGHTSIDE_2: 0 mm; DIM_SILL_BR_RIGHTSIDE_4: 0 mm; DIM_SILL_BR_RIGHTSIDE_5: 0 mm; DIM_SILL_FIX_FROM_SHAFT_WALL: 0 mm; Area: 24.0301 m2; DIM_DOOR_HH: 2100 mm; DIM_DOOR_HR: 2280 mm; DIM_DOOR_LL: 900 mm; DIM_DOOR_LR: 1200 mm; DIM_DOOR_LR_LEFTSIDE: 600 mm; DIM_DOOR_LR_RIGHTSIDE: 600 mm; DIM_DOOR_PH_LEFTSIDE: 620 mm; DIM_DOOR_PH_RIGHTSIDE: 970 mm; DIM_LDO_HA: 150 mm; DIM_LDO_LA: 120 mm; DIM_LDO_LB: 120 mm; DIM_LDO_RECESS_MANUAL_FROM_SILL_LINE: 140 mm; DIM_LDO_WALL_TO_SILL_LINE: 140 mm; DIM_PANEL_FRAME_BOTTOM_WIDTH: 1 mm; DIM_PANEL_FRAME_LEFT_WIDTH: 1 mm; DIM_PANEL_FRAME_RIGHT_WIDTH: 1 mm; DIM_PANEL_FRAME_TOP_WIDTH: 1 mm; DIM_PANEL_GAP_TO_FRAME: 5 mm; DIM_PANEL_THICKNESS_BACK: 45 mm; DIM_PANEL_THICKNESS_FRONT: 45 mm; DIM_PANEL_WIDTH: 472 mm; DIM_RAILING_BR_FIX_LEVEL: 2430 mm; DIM_RAILING_BR_FIX_LEVEL_OPT: 2430 mm; DIM_RAILING_BR_LEFTSIDE: 510 mm; DIM_RAILING_BR_RIGHTSIDE: 510 mm; DIM_RAILING_BR_RIGHTSIDE_OPT: 850 mm; DIM_RAILING_BR_TOP_FROM_HH: 500 mm; DIM_RAILING_FIX_FROM_SILL_LINE: 140 mm; DIM_SHAFT_TOLERANCE: 25 mm; DIM_SHAFT_WALL_THICKNESS: 150 mm; DIM_SILL_BR_BOTTOM_FROM_FFL: 275 mm; DIM_SILL_BR_FIX_LEVEL: 100 mm; DIM_SILL_BR_LEFTSIDE_3: 350 mm; DIM_SILL_BR_RIGHTSIDE_3: 350 mm; DIM_SILL_CUTOUT_EXT: 30 mm; DIM_SILL_FIX_FROM_SILL_LINE: 140 mm; DIM_SILL_PH_DEPTH: 140 mm; DIM_SILL_PH_HEIGHT: 2 mm; Volume: 4.61209 m3
Constraints - Default Elevation: 1219.2 mm; Moves With Nearby Elements: no; Offset: 1615 mm
Pset_BuildingElementProxyCommon - Reference: KONE_LDO_KES201_2R_P15_TX
Phasing - Phase Created: Phase 3
Visibility - VIS_CINSERT: no; VIS_DOOR_OPENING: no; VIS_DOOR_WALL_CUTOUT: no; VIS_FRAME: yes; VIS_FRAME_BR_LEFTSIDE_OPT_1: no; VIS_FRAME_BR_LEFTSIDE_OPT_2: no; VIS_FRAME_BR_LEFTSIDE_OPT_3: no; VIS_FRAME_BR_LEFTSIDE_OPT_4: no; VIS_FRAME_BR_RIGHTSIDE_OPT_1: no; VIS_FRAME_BR_RIGHTSIDE_OPT_2: no; VIS_FRAME_BR_RIGHTSIDE_OPT_3: no; VIS_FRAME_BR_RIGHTSIDE_OPT_4: no; VIS_FRAME_BRACKETS: no; VIS_FRAME_CINSERT_OPT_1: no; VIS_FRAME_CINSERT_OPT_2: no; VIS_FRAME_MAP_LEFT: no; VIS_FRAME_MAP_RIGHT: no; VIS_PANEL_GLASS_WINDOW_LEFT: no; VIS_PANEL_GLASS_WINDOW_RIGHT: no; VIS_RAILING_BR_LEFTSIDE: yes; VIS_RAILING_BR_LEFTSIDE_OPT: no; VIS_RAILING_BR_RIGHTSIDE: yes; VIS_RAILING_BR_RIGHTSIDE_OPT: no; VIS_RAILING_BRACKETS: yes; VIS_RAILING_CINSERT_OPT: no; VIS_SILL_BR_LEFTSIDE_1: yes; VIS_SILL_BR_LEFTSIDE_2: no; VIS_SILL_BR_LEFTSIDE_3: yes; VIS_SILL_BR_LEFTSIDE_4: no; VIS_SILL_BR_LEFTSIDE_5: no; VIS_SILL_BR_RIGHTSIDE_1: no; VIS_SILL_BR_RIGHTSIDE_2: no; VIS_SILL_BR_RIGHTSIDE_3: yes; VIS_SILL_BR_RIGHTSIDE_4: no; VIS_SILL_BR_RIGHTSIDE_5: no; VIS_SILL_BRACKETS: yes; VIS_SILL_CINSERT_OPT_1: no; VIS_SILL_CINSERT_OPT_2: no; VIS_SILL_CINSERT_OPT_3: no; VIS_SILL_CINSERT_OPT_4: no; VIS_SILL_CINSERT_VERTICAL: no; VIS_SILL_POV: no
SEADMED - 01 Nimetus: Undefined; 02 Tähis: KONE_LDO_KES201_2R_P15_TX:KONE_LDO_KES201_2R_P15_TX:300904; 03 Osasüsteem: Undefined; 04 Tehniline karakteristika: Undefined; 05 Tootja: Undefined; 06 Mudel või toote tunnus: Undefined; 07 Tooteinfo: Undefined; 08 Kasutus- ja hooldusjuhend: Undefined
AC_Pset_RenovationAndPhasing - Renovation Status: Existing

# IfcTransportElement: KONE_MACHINE_MX10:KONE_MACHINE_MX10:300888
In: 0 korrus
Type - ElementType: Element type KONE_MACHINE_MX10:KONE_MACHINE_MX10:300888
OperationType: ELEVATOR; CapacityByWeight: 0 kg; CapacityByNumber: 0; Classification: 1.17 IfcTransportElement (lift) (_RKAS BIM + ARCHICAD Classification); Material: IFC Building Material (17)
Constraints - Moves With Nearby Elements: no; Offset: 7765 mm
Dimensions - Area: 1.63611 m2; Volume: 0.0980518 m3
Other - Category: Specialty Equipment; Family: KONE_MACHINE_MX10: KONE_MACHINE_MX10; Family and Type: KONE_MACHINE_MX10: KONE_MACHINE_MX10; Type: KONE_MACHINE_MX10: KONE_MACHINE_MX10; Type Id: KONE_MACHINE_MX10: KONE_MACHINE_MX10
Phasing - Phase Created: Phase 3
SEADMED - 01 Nimetus: Undefined; 02 Tähis: KONE_MACHINE_MX10:KONE_MACHINE_MX10:300888; 03 Osasüsteem: Undefined; 04 Tehniline karakteristika: Undefined; 05 Tootja: Undefined; 06 Mudel või toote tunnus: Undefined; 07 Tooteinfo: Undefined; 08 Kasutus- ja hooldusjuhend: Undefined
AC_Pset_RenovationAndPhasing - Renovation Status: Existing

# IfcTransportElement: KONE_Pit_Ladder:KONE_Pit_Ladder:300893
In: 0 korrus
Type - ElementType: Element type KONE_Pit_Ladder:KONE_Pit_Ladder:300893
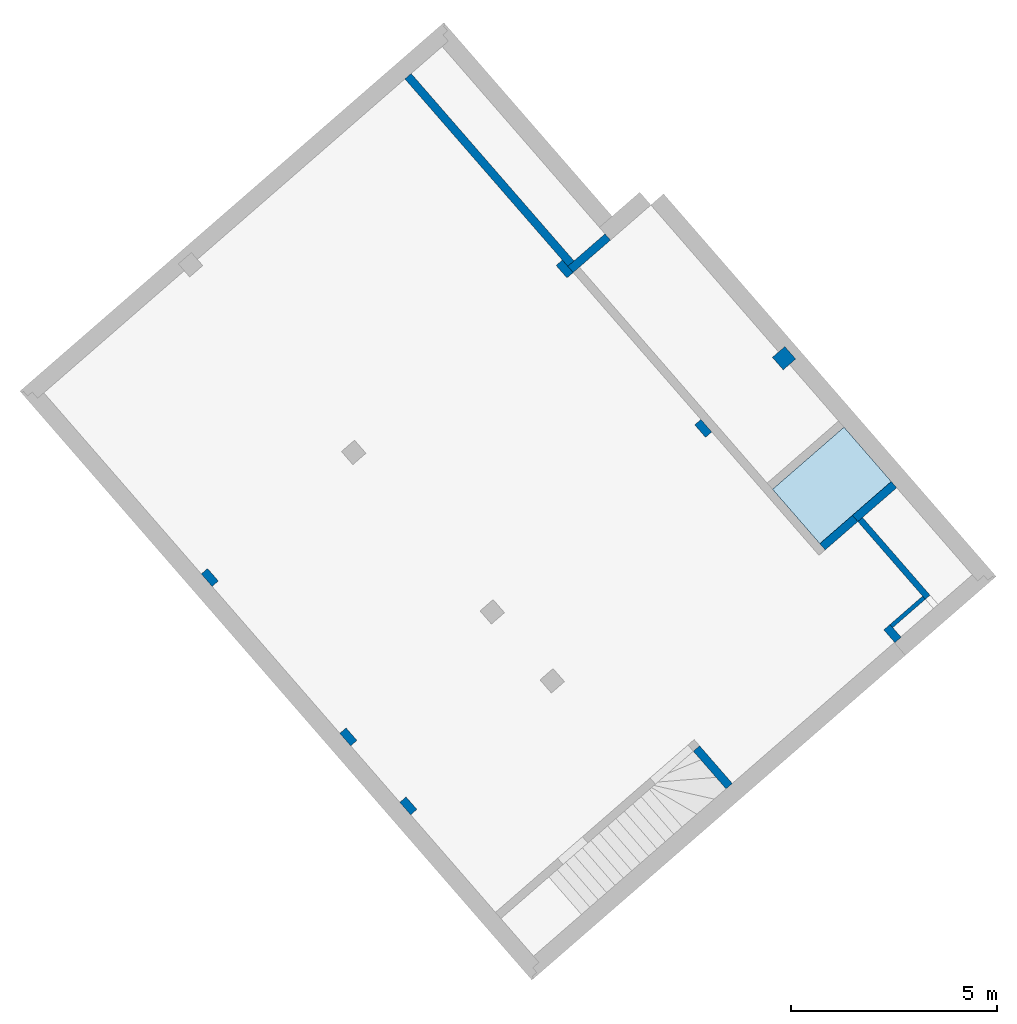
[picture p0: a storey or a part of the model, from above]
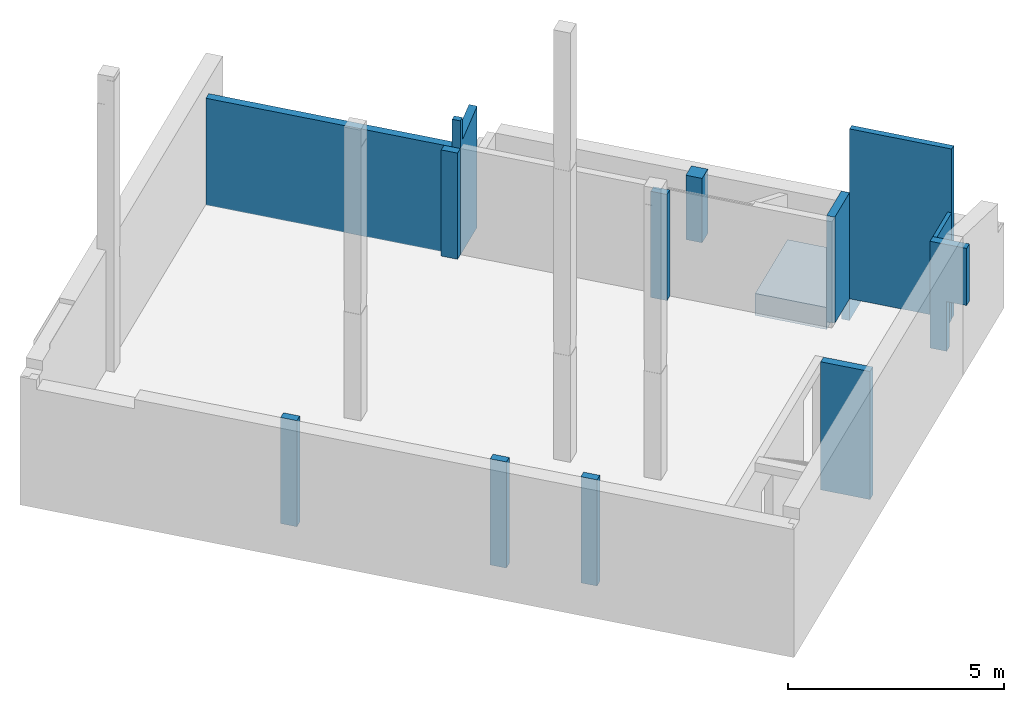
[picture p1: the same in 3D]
Properties of the parts of a building model (IFC2X3), part 9 of 13

# IfcTransportElement: KONE_Pit_Ladder:KONE_Pit_Ladder:300893
OperationType: ELEVATOR; CapacityByWeight: 0 kg; CapacityByNumber: 0; Classification: 1.17 IfcTransportElement (lift) (_RKAS BIM + ARCHICAD Classification); Material: Site specified (10)
Constraints - Moves With Nearby Elements: no; Offset: -3257.59 mm
Dimensions - Area: 0.53821 m2; Volume: 0.008867 m3
Other - Category: Specialty Equipment; Family: KONE_Pit_Ladder: KONE_Pit_Ladder; Family and Type: KONE_Pit_Ladder: KONE_Pit_Ladder; Type: KONE_Pit_Ladder: KONE_Pit_Ladder; Type Id: KONE_Pit_Ladder: KONE_Pit_Ladder
Phasing - Phase Created: Phase 3
SEADMED - 01 Nimetus: Undefined; 02 Tähis: KONE_Pit_Ladder:KONE_Pit_Ladder:300893; 03 Osasüsteem: Undefined; 04 Tehniline karakteristika: Undefined; 05 Tootja: Undefined; 06 Mudel või toote tunnus: Undefined; 07 Tooteinfo: Undefined; 08 Kasutus- ja hooldusjuhend: Undefined
AC_Pset_RenovationAndPhasing - Renovation Status: Existing

# IfcTransportElement: KONE_RBO_KM51147334_Without_Bracket:KONE_RBO_KM51147334_Without_Bracket:300962
In: 0 korrus
Type - ElementType: Element type KONE_RBO_KM51147334_Without_Bracket:KONE_RBO_KM51147334_Without_Bracket:300962
OperationType: ELEVATOR; CapacityByWeight: 0 kg; CapacityByNumber: 0; Classification: 1.17 IfcTransportElement (lift) (_RKAS BIM + ARCHICAD Classification); Material: IFC Building Material (3)
Constraints - Moves With Nearby Elements: no; Offset: 6693 mm
Dimensions - Area: 0.378488 m2; DIM_RBO_L: 50 mm; SEP_FIXING: 947.5 mm; Volume: 0.000748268 m3
Other - Category: Specialty Equipment; Family: KONE_RBO_KM51147334_Without_Bracket: KONE_RBO_KM51147334_Without_Bracket; Family and Type: KONE_RBO_KM51147334_Without_Bracket: KONE_RBO_KM51147334_Without_Bracket; Type: KONE_RBO_KM51147334_Without_Bracket: KONE_RBO_KM51147334_Without_Bracket; Type Id: KONE_RBO_KM51147334_Without_Bracket: KONE_RBO_KM51147334_Without_Bracket
Phasing - Phase Created: Phase 3
SEADMED - 01 Nimetus: Undefined; 02 Tähis: KONE_RBO_KM51147334_Without_Bracket:KONE_RBO_KM51147334_Without_Bracket:300962; 03 Osasüsteem: Undefined; 04 Tehniline karakteristika: Undefined; 05 Tootja: Undefined; 06 Mudel või toote tunnus: Undefined; 07 Tooteinfo: Undefined; 08 Kasutus- ja hooldusjuhend: Undefined
AC_Pset_RenovationAndPhasing - Renovation Status: Existing

# IfcTransportElement: KONE_Shaft_Light:KONE_Shaft_Light:300894
In: 0 korrus
Type - ElementType: Element type KONE_Shaft_Light:KONE_Shaft_Light:300894
OperationType: ELEVATOR; CapacityByWeight: 0 kg; CapacityByNumber: 0; Classification: 1.17 IfcTransportElement (lift) (_RKAS BIM + ARCHICAD Classification); Material: Site specified
Constraints - Moves With Nearby Elements: no; Offset: 1319.37 mm
Dimensions - Area: 0.115702 m2; Volume: 0.00145125 m3
Other - Category: Specialty Equipment; Family: KONE_Shaft_Light: KONE_Shaft_Light; Family and Type: KONE_Shaft_Light: KONE_Shaft_Light; Type: KONE_Shaft_Light: KONE_Shaft_Light; Type Id: KONE_Shaft_Light: KONE_Shaft_Light
Phasing - Phase Created: Phase 3
SEADMED - 01 Nimetus: Undefined; 02 Tähis: KONE_Shaft_Light:KONE_Shaft_Light:300894; 03 Osasüsteem: Undefined; 04 Tehniline karakteristika: Undefined; 05 Tootja: Undefined; 06 Mudel või toote tunnus: Undefined; 07 Tooteinfo: Undefined; 08 Kasutus- ja hooldusjuhend: Undefined
AC_Pset_RenovationAndPhasing - Renovation Status: Existing

# IfcTransportElement: KONE_Wire_Channel:KONE_Wire_Channel:300895
In: 0 korrus
Type - ElementType: Element type KONE_Wire_Channel:KONE_Wire_Channel:300895
OperationType: ELEVATOR; CapacityByWeight: 0 kg; CapacityByNumber: 0; Classification: 1.17 IfcTransportElement (lift) (_RKAS BIM + ARCHICAD Classification); Material: Site specified
Constraints - Moves With Nearby Elements: no; Offset: 3695.09 mm
Dimensions - Area: 0.7025 m2; Height: 7000 mm; Volume: 0.0175 m3
Other - Category: Specialty Equipment; Family: KONE_Wire_Channel: KONE_Wire_Channel; Family and Type: KONE_Wire_Channel: KONE_Wire_Channel; Type: KONE_Wire_Channel: KONE_Wire_Channel; Type Id: KONE_Wire_Channel: KONE_Wire_Channel
Phasing - Phase Created: Phase 3
SEADMED - 01 Nimetus: Undefined; 02 Tähis: KONE_Wire_Channel:KONE_Wire_Channel:300895; 03 Osasüsteem: Undefined; 04 Tehniline karakteristika: Undefined; 05 Tootja: Undefined; 06 Mudel või toote tunnus: Undefined; 07 Tooteinfo: Undefined; 08 Kasutus- ja hooldusjuhend: Undefined
AC_Pset_RenovationAndPhasing - Renovation Status: Existing

# IfcWall: Puitfassaadi ribisik (360)
In: 1 korrus
Type - ElementType: Element type Puitfassaadi ribisik
Classification: 1.18 IfcWall (sein) (_RKAS BIM + ARCHICAD Classification)
Arhitektuur - 01 Nimetus: Puitfassaadi ribistik; 02 Materjal: Puit, mille välispind peab vastama tuletundlikkuse B,d0 nõuetele; 03 Tähistus: Puitfassaadi ribisik; 04 Tulepüsivus: Undefined; 05 Asukoht: Exterior; 06 Kandevelementide eristatus: Non-Load-Bearing Element; 07 Helipidavus: -; 08 Soojusläbivus (U-arv): -
Ehituskonstruktsioonid - 03 Tähistus või ristlõige: Puitfassaadi ribisik
AC_Pset_RenovationAndPhasing - Renovation Status: New
Pset_WallCommon - LoadBearing: no; IsExternal: yes
Name | Material | 06 Maht (kubatuur) | 11 Ülemine kõrgusmärk | 12 Alumine kõrgusmärk
5 x Site specified | Site specified | 0,1 | 2 409; Kõrgus: 7 456; 3D pikkus: 7 456 | 2 409
61 x GENEERILINE - VÄLINE VOODER | GENEERILINE - VÄLINE VOODER | 0,0 | 100; Kõrgus: 4 900; 3D pikkus: 4 900 | 100
24 x GENEERILINE - VÄLINE VOODER | GENEERILINE - VÄLINE VOODER | 0,0 | 100; Kõrgus: 7 900; 3D pikkus: 7 900 | 100
8 x Site specified | Site specified | 0,0 | 100; Kõrgus: 9 765; 3D pikkus: 9 765 | 100
40 x Site specified | Site specified | 0,1 | 100; Kõrgus: 9 765; 3D pikkus: 9 765 | 100
5 x Site specified | Site specified | 0,1 | 50; Kõrgus: 9 815; 3D pikkus: 9 695 | 50
Site specified | Site specified | 0,0 | 50; Kõrgus: 9 815; 3D pikkus: 9 695 | 50
5 x Site specified | Site specified | 0,1 | 1 713; Kõrgus: 8 152; 3D pikkus: 8 152 | 1 713
5 x Site specified | Site specified | 0,1 | 0; Kõrgus: 9 865; 3D pikkus: 9 865 | 0
Site specified | Site specified | 0,0 | 2 409; Kõrgus: 7 456; 3D pikkus: 7 456 | 2 409
3 x Site specified | Site specified | 0,0 | 0; Kõrgus: 1 560; 3D pikkus: 1 560 | 0
3 x Site specified | Site specified | 0,0 | 0; Kõrgus: 1 700; 3D pikkus: 1 700 | 0
8 x Site specified | Site specified | 0,0 | 3 795; Kõrgus: 6 070; 3D pikkus: 6 070 | 3 795
3 x Site specified | Site specified | 0,1 | -598; Kõrgus: 10 463; 3D pikkus: 10 463 | -598
12 x Site specified | Site specified | 0,1 | -1 615; Kõrgus: 11 480; 3D pikkus: 11 480 | -1 615
6 x Site specified | Site specified | 0,1 | -995; Kõrgus: 10 860; 3D pikkus: 10 860 | -995
5 x Site specified | Site specified | 0,1 | 1 622; Kõrgus: 8 243; 3D pikkus: 8 243 | 1 622
Site specified | Site specified | 0,0 | 0; Kõrgus: 9 865; 3D pikkus: 9 865 | 0
4 x Site specified | Site specified | 0,0 | -598; Kõrgus: 10 463; 3D pikkus: 10 463 | -598
Site specified | Site specified | 0,0 | 1 622; Kõrgus: 8 243; 3D pikkus: 8 243 | 1 622
16 x GENEERILINE - VÄLINE VOODER | GENEERILINE - VÄLINE VOODER | 0,0 | 100; Kõrgus: 3 900; 3D pikkus: 3 900 | 100
53 x GENEERILINE - VÄLINE VOODER | GENEERILINE - VÄLINE VOODER | 0,1 | 100; Kõrgus: 7 900; 3D pikkus: 7 900 | 100
13 x GENEERILINE - VÄLINE VOODER | GENEERILINE - VÄLINE VOODER | 0,1 | 100; Kõrgus: 8 900; 3D pikkus: 8 900 | 100
18 x Site specified | Site specified | 0,0 | 0; Kõrgus: 1 330; 3D pikkus: 1 330 | 0
Site specified | Site specified | 0,0 | 1 713; Kõrgus: 8 152; 3D pikkus: 8 152 | 1 713
6 x Site specified | Site specified | 0,1 | -688; Kõrgus: 10 553; 3D pikkus: 10 553 | -688
3 x Site specified | Site specified | 0,1 | 1 610; Kõrgus: 8 255; 3D pikkus: 8 255 | 1 610
2 x Site specified | Site specified | 0,1 | 1 700; Kõrgus: 8 165; 3D pikkus: 8 165 | 1 700
Site specified | Site specified | 0,0 | 50; Kõrgus: 9 815; 3D pikkus: 8 165 | 50
5 x Site specified | Site specified | 0,1 | 1 518; Kõrgus: 8 347; 3D pikkus: 8 347 | 1 518
Site specified | Site specified | 0,0 | 1 518; Kõrgus: 8 347; 3D pikkus: 8 347 | 1 518
22 x GENEERILINE - VÄLINE VOODER | GENEERILINE - VÄLINE VOODER | 0,1 | 100; Kõrgus: 6 900; 3D pikkus: 6 900 | 100
12 x GENEERILINE - VÄLINE VOODER | GENEERILINE - VÄLINE VOODER | 0,0 | 100; Kõrgus: 6 900; 3D pikkus: 6 900 | 100
6 x GENEERILINE - VÄLINE VOODER | GENEERILINE - VÄLINE VOODER | 0,0 | 100; Kõrgus: 8 900; 3D pikkus: 8 900 | 100

# IfcWall: Puitfassaadi ribistik (3466)
Type - ElementType: Element type Puitfassaadi ribistik
Classification: 1.18 IfcWall (sein) (_RKAS BIM + ARCHICAD Classification)
Arhitektuur - 01 Nimetus: Puitfassaadi ribistik; 02 Materjal: Puit, mille välispind peab vastama B,d0 nõuetele; 03 Tähistus: Puitfassaadi ribistik; 04 Tulepüsivus: Undefined; 05 Asukoht: Exterior; 06 Kandevelementide eristatus: Non-Load-Bearing Element; 07 Helipidavus: -; 08 Soojusläbivus (U-arv): -
Ehituskonstruktsioonid - 03 Tähistus või ristlõige: Puitfassaadi ribistik
AC_Pset_RenovationAndPhasing - Renovation Status: New
Pset_WallCommon - LoadBearing: no; IsExternal: yes
Name | In | Material | 06 Maht (kubatuur) | 11 Ülemine kõrgusmärk | 12 Alumine kõrgusmärk
13 x Site specified | 0 korrus | Site specified | 0,0 | 1 330; Kõrgus: 414; 3D pikkus: 414 | 1 330
570 x Site specified | 0 korrus | Site specified | 0,0 | 7 915; Kõrgus: 1 950; 3D pikkus: 1 950 | 7 915
111 x Site specified | 0 korrus | Site specified | 0,0 | 4 156; Kõrgus: 1 050; 3D pikkus: 1 050 | 4 156
123 x Site specified | 0 korrus | Site specified | 0,0 | 0; Kõrgus: 120; 3D pikkus: 120 | 0
18 x Site specified | 0 korrus | Site specified | 0,0 | 3 795; Kõrgus: 1 411; 3D pikkus: 1 411 | 3 795
6 x Site specified | 0 korrus | Site specified | 0,0 | 1 578; Kõrgus: 166; 3D pikkus: 166 | 1 578
6 x Site specified | 0 korrus | Site specified | 0,0 | 4 336; Kõrgus: 870; 3D pikkus: 870 | 4 336
6 x Site specified | 0 korrus | Site specified | 0,0 | 4 310; Kõrgus: 896; 3D pikkus: 896 | 4 310
6 x Site specified | 0 korrus | Site specified | 0,0 | 4 255; Kõrgus: 951; 3D pikkus: 951 | 4 255
6 x Site specified | 0 korrus | Site specified | 0,0 | 1 595; Kõrgus: 149; 3D pikkus: 149 | 1 595
6 x Site specified | 0 korrus | Site specified | 0,0 | 4 242; Kõrgus: 964; 3D pikkus: 964 | 4 242
6 x Site specified | 0 korrus | Site specified | 0,0 | 4 350; Kõrgus: 856; 3D pikkus: 856 | 4 350
6 x Site specified | 0 korrus | Site specified | 0,0 | 4 295; Kõrgus: 911; 3D pikkus: 911 | 4 295
6 x Site specified | 0 korrus | Site specified | 0,0 | 4 362; Kõrgus: 844; 3D pikkus: 844 | 4 362
6 x Site specified | 0 korrus | Site specified | 0,0 | 4 269; Kõrgus: 937; 3D pikkus: 937 | 4 269
6 x Site specified | 0 korrus | Site specified | 0,0 | 4 323; Kõrgus: 883; 3D pikkus: 883 | 4 323
6 x Site specified | 0 korrus | Site specified | 0,0 | 4 282; Kõrgus: 924; 3D pikkus: 924 | 4 282
6 x Site specified | 0 korrus | Site specified | 0,0 | 3 335; Kõrgus: 1 871; 3D pikkus: 1 871 | 3 335
Site specified | 0 korrus | Site specified | 0,0 | 3 795; Kõrgus: 6 070; 3D pikkus: 6 070 | 3 795
6 x Site specified | 0 korrus | Site specified | 0,0 | 4 390; Kõrgus: 816; 3D pikkus: 816 | 4 390
6 x Site specified | 0 korrus | Site specified | 0,0 | 0; Kõrgus: 4 100; 3D pikkus: 4 100 | 0
6 x Site specified | 0 korrus | Site specified | 0,0 | 0; Kõrgus: 5 206; 3D pikkus: 5 206 | 0
6 x Site specified | 0 korrus | Site specified | 0,0 | 1 461; Kõrgus: 283; 3D pikkus: 283 | 1 461
6 x Site specified | 0 korrus | Site specified | 0,0 | 4 376; Kõrgus: 830; 3D pikkus: 830 | 4 376
132 x Site specified | 0 korrus | Site specified | 0,0 | 4 300; Kõrgus: 906; 3D pikkus: 906 | 4 300
14 x Site specified | 0 korrus | Site specified | 0,0 | 100; Kõrgus: 5 106; 3D pikkus: 5 106 | 100
12 x Site specified | 0 korrus | Site specified | 0,0 | 2 400; Kõrgus: 2 806; 3D pikkus: 2 806 | 2 400
12 x Site specified | 0 korrus | Site specified | 0,0 | 100; Kõrgus: 2 250; 3D pikkus: 2 250 | 100
48 x Site specified | 0 korrus | Site specified | 0,0 | 100; Kõrgus: 190; 3D pikkus: 190 | 100
59 x Site specified | 0 korrus | Site specified | 0,0 | 3 000; Kõrgus: 2 206; 3D pikkus: 2 206 | 3 000
14 x Site specified | 0 korrus | Site specified | 0,0 | 4 300; Kõrgus: 915; 3D pikkus: 915 | 4 300
Site specified | 0 korrus | Site specified | 0,0 | -1 464; Kõrgus: 3 259; 3D pikkus: 3 259 | -1 464
Site specified | 0 korrus | Site specified | 0,0 | -1 503; Kõrgus: 3 298; 3D pikkus: 3 298 | -1 503
Site specified | 0 korrus | Site specified | 0,0 | 4 330; Kõrgus: 5 535; 3D pikkus: 5 535 | 4 330
Site specified | 0 korrus | Site specified | 0,0 | -1 435; Kõrgus: 3 230; 3D pikkus: 3 230 | -1 435
114 x Site specified | 0 korrus | Site specified | 0,0 | 935; Kõrgus: 860; 3D pikkus: 860 | 935
Site specified | 0 korrus | Site specified | 0,0 | -1 537; Kõrgus: 3 332; 3D pikkus: 3 332 | -1 537
72 x Site specified | 0 korrus | Site specified | 0,0 | 4 425; Kõrgus: 781; 3D pikkus: 781 | 4 425
6 x Site specified | 0 korrus | Site specified | 0,0 | 1 476; Kõrgus: 268; 3D pikkus: 268 | 1 476
6 x Site specified | 0 korrus | Site specified | 0,0 | 1 492; Kõrgus: 252; 3D pikkus: 252 | 1 492
6 x Site specified | 0 korrus | Site specified | 0,0 | 4 228; Kõrgus: 978; 3D pikkus: 978 | 4 228
6 x Site specified | 0 korrus | Site specified | 0,0 | 1 561; Kõrgus: 183; 3D pikkus: 183 | 1 561
6 x Site specified | 0 korrus | Site specified | 0,0 | 1 612; Kõrgus: 132; 3D pikkus: 132 | 1 612
18 x Site specified | 0 korrus | Site specified | 0,0 | 100; Kõrgus: 790; 3D pikkus: 790 | 100
18 x Site specified | 0 korrus | Site specified | 0,0 | 3 600; Kõrgus: 1 606; 3D pikkus: 1 606 | 3 600
6 x Site specified | 0 korrus | Site specified | 0,0 | 1 508; Kõrgus: 236; 3D pikkus: 236 | 1 508
6 x Site specified | 0 korrus | Site specified | 0,0 | 1 526; Kõrgus: 218; 3D pikkus: 218 | 1 526
6 x Site specified | 0 korrus | Site specified | 0,0 | 1 544; Kõrgus: 3 662; 3D pikkus: 3 662 | 1 544
6 x Site specified | 0 korrus | Site specified | 0,0 | 1 630; Kõrgus: 114; 3D pikkus: 114 | 1 630
6 x Site specified | 0 korrus | Site specified | 0,0 | 1 652; Kõrgus: 131; 3D pikkus: 131 | 1 652
6 x Site specified | 0 korrus | Site specified | 0,0 | 1 666; Kõrgus: 117; 3D pikkus: 117 | 1 666
6 x Site specified | 0 korrus | Site specified | 0,0 | 1 681; Kõrgus: 3 525; 3D pikkus: 3 525 | 1 681
5 x Site specified | 0 korrus | Site specified | 0,0 | -1 615; Kõrgus: 3 410; 3D pikkus: 3 410 | -1 615
5 x Site specified | 1 korrus | Site specified | 0,0 | 4 274; Kõrgus: 5 591; 3D pikkus: 5 591 | 4 274
405 x Site specified | 1 korrus | Site specified | 0,0 | 100; Kõrgus: 9 765; 3D pikkus: 9 765 | 100
51 x Site specified | 1 korrus | Site specified (2) | 0,0 | 100; Kõrgus: 9 765; 3D pikkus: 9 749 | 100
2 x GENEERILINE - VÄLINE VOODER | 1 korrus | GENEERILINE - VÄLINE VOODER | 0,0 | -404; Kõrgus: 9 891; 3D pikkus: 9 891 | -404
GENEERILINE - VÄLINE VOODER | 1 korrus | GENEERILINE - VÄLINE VOODER | 0,0 | -389; Kõrgus: 9 883; 3D pikkus: 9 883 | -389
40 x Site specified | 1 korrus | Site specified | 0,0 | 200; Kõrgus: 2 020; 3D pikkus: 2 020 | 200
48 x Site specified | 1 korrus | Site specified | 0,0 | 4 800; Kõrgus: 3 928; 3D pikkus: 3 928 | 4 800
52 x Site specified | 1 korrus | Site specified | 0,0 | 2 220; Kõrgus: 7 645; 3D pikkus: 7 645 | 2 220
4 x Site specified | 1 korrus | Site specified (2) | 0,0 | 100; Kõrgus: 9 765; 3D pikkus: 9 643 | 100
4 x Site specified | 1 korrus | Site specified | 0,0 | 100; Kõrgus: 7 615; 3D pikkus: 7 615 | 100
4 x Site specified | 1 korrus | Site specified | 0,0 | 1 518; Kõrgus: 8 347; 3D pikkus: 8 347 | 1 518
4 x Site specified | 1 korrus | Site specified (2) | 0,0 | 2 409; Kõrgus: 7 456; 3D pikkus: 7 286 | 2 409
Site specified | 1 korrus | Site specified | 0,1 | 1 764; Kõrgus: 8 101; 3D pikkus: 8 101 | 1 764
6 x Site specified | 1 korrus | Site specified | 0,0 | 1 764; Kõrgus: 8 101; 3D pikkus: 8 101 | 1 764
Site specified | 1 korrus | Site specified | 0,1 | 1 570; Kõrgus: 8 295; 3D pikkus: 8 295 | 1 570
Site specified | 1 korrus | Site specified | 0,1 | 1 780; Kõrgus: 8 085; 3D pikkus: 8 085 | 1 780
5 x Site specified | 1 korrus | Site specified | 0,0 | 1 780; Kõrgus: 8 085; 3D pikkus: 8 085 | 1 780
6 x Site specified | 1 korrus | Site specified | 0,0 | 1 695; Kõrgus: 8 170; 3D pikkus: 8 170 | 1 695
14 x Site specified | 1 korrus | Site specified | 0,0 | 0; Kõrgus: 9 865; 3D pikkus: 9 865 | 0
2 x Site specified | 1 korrus | Site specified | 0,0 | 2 409; Kõrgus: 7 456; 3D pikkus: 7 456 | 2 409
3 x Site specified | 1 korrus | Site specified | 0,1 | 0; Kõrgus: 9 865; 3D pikkus: 9 865 | 0
6 x Site specified | 1 korrus | Site specified | 0,0 | 4 235; Kõrgus: 5 630; 3D pikkus: 5 630 | 4 235
Site specified | 1 korrus | Site specified | 0,1 | 4 235; Kõrgus: 5 630; 3D pikkus: 5 630 | 4 235
5 x Site specified | 1 korrus | Site specified | 0,0 | 4 248; Kõrgus: 5 617; 3D pikkus: 5 617 | 4 248
Site specified | 1 korrus | Site specified | 0,1 | 4 248; Kõrgus: 5 617; 3D pikkus: 5 617 | 4 248
5 x Site specified | 1 korrus | Site specified | 0,0 | 4 261; Kõrgus: 5 604; 3D pikkus: 5 604 | 4 261
Site specified | 1 korrus | Site specified | 0,1 | 4 261; Kõrgus: 5 604; 3D pikkus: 5 604 | 4 261
5 x Site specified | 1 korrus | Site specified | 0,0 | 4 288; Kõrgus: 5 577; 3D pikkus: 5 577 | 4 288
Site specified | 1 korrus | Site specified | 0,1 | 4 274; Kõrgus: 5 591; 3D pikkus: 5 591 | 4 274
6 x Site specified | 1 korrus | Site specified | 0,0 | 4 362; Kõrgus: 5 503; 3D pikkus: 5 503 | 4 362
Site specified | 1 korrus | Site specified | 0,1 | 4 288; Kõrgus: 5 577; 3D pikkus: 5 577 | 4 288
Site specified | 1 korrus | Site specified | 0,1 | 4 362; Kõrgus: 5 503; 3D pikkus: 5 503 | 4 362
GENEERILINE - VÄLINE VOODER | 1 korrus | GENEERILINE - VÄLINE VOODER | 0,0 | -78; Kõrgus: 1 009; 3D pikkus: 1 009 | -78
6 x Site specified | 1 korrus | Site specified | 0,0 | 4 384; Kõrgus: 5 481; 3D pikkus: 5 481 | 4 384
Site specified | 1 korrus | Site specified | 0,1 | 4 384; Kõrgus: 5 481; 3D pikkus: 5 481 | 4 384
6 x Site specified | 1 korrus | Site specified | 0,0 | 1 536; Kõrgus: 8 329; 3D pikkus: 8 329 | 1 536
Site specified | 1 korrus | Site specified | 0,1 | 1 536; Kõrgus: 8 329; 3D pikkus: 8 329 | 1 536
6 x Site specified | 1 korrus | Site specified | 0,0 | 1 553; Kõrgus: 8 312; 3D pikkus: 8 312 | 1 553
4 x Site specified | 1 korrus | Site specified | 0,0 | 1 622; Kõrgus: 8 243; 3D pikkus: 8 243 | 1 622
5 x Site specified | 1 korrus | Site specified | 0,0 | 1 468; Kõrgus: 8 397; 3D pikkus: 8 397 | 1 468
Site specified | 1 korrus | Site specified | 0,1 | 1 468; Kõrgus: 8 397; 3D pikkus: 8 397 | 1 468
5 x Site specified | 1 korrus | Site specified | 0,0 | 1 484; Kõrgus: 8 381; 3D pikkus: 8 381 | 1 484
Site specified | 1 korrus | Site specified | 0,1 | 1 695; Kõrgus: 8 170; 3D pikkus: 8 170 | 1 695
6 x Site specified | 1 korrus | Site specified | 0,0 | 4 316; Kõrgus: 5 549; 3D pikkus: 5 549 | 4 316
6 x Site specified | 1 korrus | Site specified | 0,0 | 4 356; Kõrgus: 5 509; 3D pikkus: 5 509 | 4 356
7 x Site specified | 1 korrus | Site specified | 0,0 | 4 302; Kõrgus: 5 563; 3D pikkus: 5 563 | 4 302
Site specified | 1 korrus | Site specified | 0,1 | 4 302; Kõrgus: 5 563; 3D pikkus: 5 563 | 4 302
Site specified | 1 korrus | Site specified | 0,1 | 1 640; Kõrgus: 8 225; 3D pikkus: 8 225 | 1 640
7 x Site specified | 1 korrus | Site specified | 0,0 | 1 640; Kõrgus: 8 225; 3D pikkus: 8 225 | 1 640
Site specified | 1 korrus | Site specified | 0,1 | 1 500; Kõrgus: 8 365; 3D pikkus: 8 365 | 1 500
5 x Site specified | 1 korrus | Site specified | 0,0 | 1 500; Kõrgus: 8 365; 3D pikkus: 8 365 | 1 500
22 x Site specified | 1 korrus | Site specified | 0,0 | 3 795; Kõrgus: 6 070; 3D pikkus: 6 070 | 3 795
2 x Site specified | 1 korrus | Site specified | 0,1 | 3 795; Kõrgus: 6 070; 3D pikkus: 6 070 | 3 795
Site specified | 1 korrus | Site specified | 0,1 | 4 316; Kõrgus: 5 549; 3D pikkus: 5 549 | 4 316
6 x Site specified | 1 korrus | Site specified | 0,0 | 4 329; Kõrgus: 5 536; 3D pikkus: 5 536 | 4 329
Site specified | 1 korrus | Site specified | 0,1 | 4 329; Kõrgus: 5 536; 3D pikkus: 5 536 | 4 329
6 x Site specified | 1 korrus | Site specified | 0,0 | 4 344; Kõrgus: 5 521; 3D pikkus: 5 521 | 4 344
Site specified | 1 korrus | Site specified | 0,1 | 4 344; Kõrgus: 5 521; 3D pikkus: 5 521 | 4 344
Site specified | 1 korrus | Site specified | 0,1 | 4 356; Kõrgus: 5 509; 3D pikkus: 5 509 | 4 356
9 x Site specified | 1 korrus | Site specified | 0,0 | 2 871; Kõrgus: 6 994; 3D pikkus: 6 994 | 2 871
GENEERILINE - VÄLINE VOODER | 1 korrus | GENEERILINE - VÄLINE VOODER | 0,0 | -41; Kõrgus: 2 870; 3D pikkus: 2 870 | -41
51 x Site specified | 1 korrus | Site specified | 0,0 | 7 915; Kõrgus: 1 950; 3D pikkus: 1 950 | 7 915
76 x Site specified | 1 korrus | Site specified | 0,0 | 4 425; Kõrgus: 5 440; 3D pikkus: 5 440 | 4 425
5 x Site specified | 1 korrus | Site specified | 0,0 | 3 335; Kõrgus: 6 530; 3D pikkus: 6 530 | 3 335
Site specified | 1 korrus | Site specified | 0,1 | 1 484; Kõrgus: 8 381; 3D pikkus: 8 381 | 1 484
Site specified | 1 korrus | Site specified | 0,0 | 50; Kõrgus: 1 060; 3D pikkus: 1 060 | 50
Site specified | 1 korrus | Site specified | 0,0 | 50; Kõrgus: 970; 3D pikkus: 970 | 50
Site specified | 1 korrus | Site specified | 0,0 | 50; Kõrgus: 790; 3D pikkus: 790 | 50
Site specified | 1 korrus | Site specified | 0,0 | 50; Kõrgus: 610; 3D pikkus: 610 | 50
Site specified | 1 korrus | Site specified | 0,0 | 50; Kõrgus: 520; 3D pikkus: 520 | 50
Site specified | 1 korrus | Site specified | 0,0 | 50; Kõrgus: 250; 3D pikkus: 250 | 50
Site specified | 1 korrus | Site specified | 0,0 | 50; Kõrgus: 340; 3D pikkus: 340 | 50
Site specified | 1 korrus | Site specified | 0,0 | 50; Kõrgus: 1 330; 3D pikkus: 1 330 | 50
Site specified | 1 korrus | Site specified | 0,0 | 50; Kõrgus: 1 240; 3D pikkus: 1 240 | 50
12 x Site specified | 1 korrus | Site specified | 0,1 | 4 425; Kõrgus: 5 440; 3D pikkus: 5 440 | 4 425
64 x Site specified | 1 korrus | Site specified | 0,0 | 935; Kõrgus: 8 930; 3D pikkus: 8 930 | 935
4 x Site specified | 1 korrus | Site specified | 0,0 | 50; Kõrgus: 9 815; 3D pikkus: 9 425 | 50
3 x Site specified | 1 korrus | Site specified | 0,0 | 50; Kõrgus: 9 815; 3D pikkus: 9 335 | 50
3 x Site specified | 1 korrus | Site specified | 0,0 | 50; Kõrgus: 9 815; 3D pikkus: 9 515 | 50
7 x Site specified | 1 korrus | Site specified | 0,0 | 50; Kõrgus: 9 815; 3D pikkus: 9 815 | 50
Site specified | 1 korrus | Site specified | 0,0 | 50; Kõrgus: 9 815; 3D pikkus: 9 695 | 50
4 x Site specified | 1 korrus | Site specified | 0,0 | 50; Kõrgus: 9 815; 3D pikkus: 9 785 | 50
3 x Site specified | 1 korrus | Site specified (2) | 0,0 | 50; Kõrgus: 9 815; 3D pikkus: 8 165 | 50
Site specified | 1 korrus | Site specified | 0,1 | 50; Kõrgus: 9 815; 3D pikkus: 9 785 | 50
Site specified | 1 korrus | Site specified | 0,1 | 50; Kõrgus: 9 815; 3D pikkus: 9 815 | 50
GENEERILINE - VÄLINE VOODER | 1 korrus | GENEERILINE - VÄLINE VOODER | 0,0 | -41; Kõrgus: 2 808; 3D pikkus: 2 808 | -41
Site specified | 1 korrus | Site specified | 0,1 | 2 871; Kõrgus: 6 994; 3D pikkus: 6 994 | 2 871
Site specified | 1 korrus | Site specified | 0,1 | 3 335; Kõrgus: 6 530; 3D pikkus: 6 530 | 3 335
29 x Site specified | 1 korrus | Site specified (2) | 0,0 | 100; Kõrgus: 9 765; 3D pikkus: 9 745 | 100
32 x Site specified | 1 korrus | Site specified | 0,1 | 100; Kõrgus: 9 765; 3D pikkus: 9 765 | 100
24 x Site specified | 1 korrus | Site specified | 0,0 | 4 300; Kõrgus: 5 565; 3D pikkus: 5 565 | 4 300
3 x Site specified | 1 korrus | Site specified | 0,1 | -1 615; Kõrgus: 11 480; 3D pikkus: 11 480 | -1 615
5 x Site specified | 1 korrus | Site specified | 0,0 | -1 615; Kõrgus: 11 480; 3D pikkus: 11 480 | -1 615
Site specified | 1 korrus | Site specified | 0,1 | -1 539; Kõrgus: 11 404; 3D pikkus: 11 404 | -1 539
Site specified | 1 korrus | Site specified | 0,1 | -513; Kõrgus: 10 378; 3D pikkus: 10 378 | -513
5 x Site specified | 1 korrus | Site specified | 0,1 | 4 300; Kõrgus: 5 565; 3D pikkus: 5 565 | 4 300
Site specified | 1 korrus | Site specified | 0,0 | -595; Kõrgus: 10 460; 3D pikkus: 10 460 | -595
Site specified | 1 korrus | Site specified | 0,0 | -521; Kõrgus: 10 386; 3D pikkus: 10 386 | -521
11 x Site specified | 1 korrus | Site specified | 0,1 | 935; Kõrgus: 8 930; 3D pikkus: 8 930 | 935
13 x Site specified | 1 korrus | Site specified | 0,0 | 4 300; Kõrgus: 915; 3D pikkus: 915 | 4 300
Site specified | 1 korrus | Site specified | 0,0 | -567; Kõrgus: 10 432; 3D pikkus: 10 432 | -567
Site specified | 1 korrus | Site specified | 0,0 | -309; Kõrgus: 10 174; 3D pikkus: 10 174 | -309
Site specified | 1 korrus | Site specified | 0,0 | -331; Kõrgus: 10 196; 3D pikkus: 10 196 | -331
Site specified | 1 korrus | Site specified | 0,0 | -455; Kõrgus: 10 320; 3D pikkus: 10 320 | -455
Site specified | 1 korrus | Site specified | 0,0 | -412; Kõrgus: 10 277; 3D pikkus: 10 277 | -412
Site specified | 1 korrus | Site specified | 0,0 | -370; Kõrgus: 10 235; 3D pikkus: 10 235 | -370
Site specified | 1 korrus | Site specified | 0,0 | -497; Kõrgus: 10 362; 3D pikkus: 10 362 | -497
Site specified | 1 korrus | Site specified | 0,0 | -190; Kõrgus: 10 055; 3D pikkus: 10 055 | -190
Site specified | 1 korrus | Site specified | 0,0 | -115; Kõrgus: 9 980; 3D pikkus: 9 980 | -115
Site specified | 1 korrus | Site specified | 0,1 | -107; Kõrgus: 9 972; 3D pikkus: 9 972 | -107
Site specified | 1 korrus | Site specified | 0,1 | -294; Kõrgus: 10 159; 3D pikkus: 10 159 | -294
Site specified | 1 korrus | Site specified | 0,0 | -161; Kõrgus: 10 026; 3D pikkus: 10 026 | -161
Site specified | 1 korrus | Site specified | 0,0 | 74; Kõrgus: 9 791; 3D pikkus: 9 791 | 74
Site specified | 1 korrus | Site specified | 0,0 | -236; Kõrgus: 10 101; 3D pikkus: 10 101 | -236
Site specified | 1 korrus | Site specified | 0,0 | 36; Kõrgus: 9 829; 3D pikkus: 9 829 | 36
Site specified | 1 korrus | Site specified | 0,0 | -92; Kõrgus: 9 957; 3D pikkus: 9 957 | -92
Site specified | 1 korrus | Site specified | 0,0 | -49; Kõrgus: 9 914; 3D pikkus: 9 914 | -49
Site specified | 1 korrus | Site specified | 0,0 | -6; Kõrgus: 9 871; 3D pikkus: 9 871 | -6
Site specified | 1 korrus | Site specified | 0,0 | -1 600; Kõrgus: 3 395; 3D pikkus: 3 395 | -1 600
20 x Site specified | 1 korrus | Site specified | 0,0 | 935; Kõrgus: 860; 3D pikkus: 860 | 935
Site specified | 1 korrus | Site specified | 0,0 | -1 585; Kõrgus: 3 380; 3D pikkus: 3 380 | -1 585
14 x Site specified | 1 korrus | Site specified | 0,0 | 935; Kõrgus: 4 271; 3D pikkus: 4 271 | 935
Site specified | 1 korrus | Site specified | 0,0 | -1 552; Kõrgus: 3 347; 3D pikkus: 3 347 | -1 552
Site specified | 1 korrus | Site specified | 0,0 | -1 567; Kõrgus: 3 362; 3D pikkus: 3 362 | -1 567
Site specified | 1 korrus | Site specified | 0,1 | -1 459; Kõrgus: 11 324; 3D pikkus: 11 324 | -1 459
Site specified | 1 korrus | Site specified | 0,0 | -1 465; Kõrgus: 11 330; 3D pikkus: 11 330 | -1 465
Site specified | 1 korrus | Site specified | 0,0 | -1 482; Kõrgus: 11 347; 3D pikkus: 11 347 | -1 482
Site specified | 1 korrus | Site specified | 0,0 | -1 510; Kõrgus: 11 375; 3D pikkus: 11 375 | -1 510
Site specified | 1 korrus | Site specified | 0,0 | -1 499; Kõrgus: 11 364; 3D pikkus: 11 364 | -1 499
Site specified | 1 korrus | Site specified | 0,0 | -1 039; Kõrgus: 10 904; 3D pikkus: 10 904 | -1 039
Site specified | 1 korrus | Site specified | 0,0 | -1 065; Kõrgus: 10 930; 3D pikkus: 10 930 | -1 065
Site specified | 1 korrus | Site specified | 0,0 | -1 053; Kõrgus: 10 918; 3D pikkus: 10 918 | -1 053
Site specified | 1 korrus | Site specified | 0,1 | -1 071; Kõrgus: 10 936; 3D pikkus: 10 936 | -1 071
Site specified | 1 korrus | Site specified | 0,0 | -1 531; Kõrgus: 11 396; 3D pikkus: 11 396 | -1 531
Site specified | 1 korrus | Site specified | 0,1 | -609; Kõrgus: 10 474; 3D pikkus: 10 474 | -609
GENEERILINE - VÄLINE VOODER | 1 korrus | GENEERILINE - VÄLINE VOODER | 0,0 | 350; Kõrgus: 9 503; 3D pikkus: 9 503 | 350
5 x GENEERILINE - VÄLINE VOODER | 1 korrus | GENEERILINE - VÄLINE VOODER | 0,0 | 350; Kõrgus: 9 475; 3D pikkus: 9 475 | 350
GENEERILINE - VÄLINE VOODER | 1 korrus | GENEERILINE - VÄLINE VOODER | 0,0 | 350; Kõrgus: 9 479; 3D pikkus: 9 479 | 350
GENEERILINE - VÄLINE VOODER | 1 korrus | GENEERILINE - VÄLINE VOODER | 0,0 | 350; Kõrgus: 9 486; 3D pikkus: 9 486 | 350
GENEERILINE - VÄLINE VOODER | 1 korrus | GENEERILINE - VÄLINE VOODER | 0,0 | 350; Kõrgus: 9 492; 3D pikkus: 9 492 | 350
GENEERILINE - VÄLINE VOODER | 1 korrus | GENEERILINE - VÄLINE VOODER | 0,1 | 350; Kõrgus: 9 497; 3D pikkus: 9 497 | 350
GENEERILINE - VÄLINE VOODER | 1 korrus | GENEERILINE - VÄLINE VOODER | 0,0 | 338; Kõrgus: 9 483; 3D pikkus: 9 483 | 338
GENEERILINE - VÄLINE VOODER | 1 korrus | GENEERILINE - VÄLINE VOODER | 0,0 | 275; Kõrgus: 9 517; 3D pikkus: 9 517 | 275
GENEERILINE - VÄLINE VOODER | 1 korrus | GENEERILINE - VÄLINE VOODER | 0,0 | 285; Kõrgus: 9 512; 3D pikkus: 9 512 | 285
GENEERILINE - VÄLINE VOODER | 1 korrus | GENEERILINE - VÄLINE VOODER | 0,0 | 299; Kõrgus: 9 504; 3D pikkus: 9 504 | 299
GENEERILINE - VÄLINE VOODER | 1 korrus | GENEERILINE - VÄLINE VOODER | 0,0 | 314; Kõrgus: 9 496; 3D pikkus: 9 496 | 314
GENEERILINE - VÄLINE VOODER | 1 korrus | GENEERILINE - VÄLINE VOODER | 0,1 | 324; Kõrgus: 9 491; 3D pikkus: 9 491 | 324
4 x GENEERILINE - VÄLINE VOODER | 1 korrus | GENEERILINE - VÄLINE VOODER | 0,0 | 265; Kõrgus: 9 523; 3D pikkus: 9 523 | 265
GENEERILINE - VÄLINE VOODER | 1 korrus | GENEERILINE - VÄLINE VOODER | 0,0 | 227; Kõrgus: 9 544; 3D pikkus: 9 544 | 227
GENEERILINE - VÄLINE VOODER | 1 korrus | GENEERILINE - VÄLINE VOODER | 0,1 | 251; Kõrgus: 9 531; 3D pikkus: 9 531 | 251
GENEERILINE - VÄLINE VOODER | 1 korrus | GENEERILINE - VÄLINE VOODER | 0,0 | 130; Kõrgus: 9 597; 3D pikkus: 9 597 | 130
GENEERILINE - VÄLINE VOODER | 1 korrus | GENEERILINE - VÄLINE VOODER | 0,0 | 139; Kõrgus: 9 592; 3D pikkus: 9 592 | 139
GENEERILINE - VÄLINE VOODER | 1 korrus | GENEERILINE - VÄLINE VOODER | 0,0 | 154; Kõrgus: 9 584; 3D pikkus: 9 584 | 154
GENEERILINE - VÄLINE VOODER | 1 korrus | GENEERILINE - VÄLINE VOODER | 0,0 | 168; Kõrgus: 9 576; 3D pikkus: 9 576 | 168
GENEERILINE - VÄLINE VOODER | 1 korrus | GENEERILINE - VÄLINE VOODER | 0,1 | 178; Kõrgus: 9 571; 3D pikkus: 9 571 | 178
GENEERILINE - VÄLINE VOODER | 1 korrus | GENEERILINE - VÄLINE VOODER | 0,0 | 120; Kõrgus: 9 603; 3D pikkus: 9 603 | 120
GENEERILINE - VÄLINE VOODER | 1 korrus | GENEERILINE - VÄLINE VOODER | 0,0 | 57; Kõrgus: 9 637; 3D pikkus: 9 637 | 57
GENEERILINE - VÄLINE VOODER | 1 korrus | GENEERILINE - VÄLINE VOODER | 0,1 | 67; Kõrgus: 9 632; 3D pikkus: 9 632 | 67
GENEERILINE - VÄLINE VOODER | 1 korrus | GENEERILINE - VÄLINE VOODER | 0,0 | 81; Kõrgus: 9 624; 3D pikkus: 9 624 | 81
GENEERILINE - VÄLINE VOODER | 1 korrus | GENEERILINE - VÄLINE VOODER | 0,0 | 96; Kõrgus: 9 616; 3D pikkus: 9 616 | 96
GENEERILINE - VÄLINE VOODER | 1 korrus | GENEERILINE - VÄLINE VOODER | 0,0 | 105; Kõrgus: 9 611; 3D pikkus: 9 611 | 105
GENEERILINE - VÄLINE VOODER | 1 korrus | GENEERILINE - VÄLINE VOODER | 0,0 | 47; Kõrgus: 9 643; 3D pikkus: 9 643 | 47
GENEERILINE - VÄLINE VOODER | 1 korrus | GENEERILINE - VÄLINE VOODER | 0,0 | -16; Kõrgus: 9 677; 3D pikkus: 9 677 | -16
GENEERILINE - VÄLINE VOODER | 1 korrus | GENEERILINE - VÄLINE VOODER | 0,1 | -6; Kõrgus: 9 672; 3D pikkus: 9 672 | -6
GENEERILINE - VÄLINE VOODER | 1 korrus | GENEERILINE - VÄLINE VOODER | 0,0 | 8; Kõrgus: 9 664; 3D pikkus: 9 664 | 8
GENEERILINE - VÄLINE VOODER | 1 korrus | GENEERILINE - VÄLINE VOODER | 0,0 | 23; Kõrgus: 9 656; 3D pikkus: 9 656 | 23
GENEERILINE - VÄLINE VOODER | 1 korrus | GENEERILINE - VÄLINE VOODER | 0,0 | -26; Kõrgus: 9 683; 3D pikkus: 9 683 | -26
GENEERILINE - VÄLINE VOODER | 1 korrus | GENEERILINE - VÄLINE VOODER | 0,1 | -89; Kõrgus: 9 717; 3D pikkus: 9 717 | -89
GENEERILINE - VÄLINE VOODER | 1 korrus | GENEERILINE - VÄLINE VOODER | 0,0 | -79; Kõrgus: 9 712; 3D pikkus: 9 712 | -79
GENEERILINE - VÄLINE VOODER | 1 korrus | GENEERILINE - VÄLINE VOODER | 0,0 | -98; Kõrgus: 9 723; 3D pikkus: 9 723 | -98
GENEERILINE - VÄLINE VOODER | 1 korrus | GENEERILINE - VÄLINE VOODER | 0,0 | -161; Kõrgus: 9 757; 3D pikkus: 9 757 | -161
GENEERILINE - VÄLINE VOODER | 1 korrus | GENEERILINE - VÄLINE VOODER | 0,0 | -152; Kõrgus: 9 752; 3D pikkus: 9 752 | -152
GENEERILINE - VÄLINE VOODER | 1 korrus | GENEERILINE - VÄLINE VOODER | 0,0 | -137; Kõrgus: 9 744; 3D pikkus: 9 744 | -137
GENEERILINE - VÄLINE VOODER | 1 korrus | GENEERILINE - VÄLINE VOODER | 0,0 | -123; Kõrgus: 9 736; 3D pikkus: 9 736 | -123
GENEERILINE - VÄLINE VOODER | 1 korrus | GENEERILINE - VÄLINE VOODER | 0,0 | -113; Kõrgus: 9 731; 3D pikkus: 9 731 | -113
GENEERILINE - VÄLINE VOODER | 1 korrus | GENEERILINE - VÄLINE VOODER | 0,0 | -171; Kõrgus: 9 763; 3D pikkus: 9 763 | -171
GENEERILINE - VÄLINE VOODER | 1 korrus | GENEERILINE - VÄLINE VOODER | 0,0 | -234; Kõrgus: 9 797; 3D pikkus: 9 797 | -234
GENEERILINE - VÄLINE VOODER | 1 korrus | GENEERILINE - VÄLINE VOODER | 0,0 | -224; Kõrgus: 9 792; 3D pikkus: 9 792 | -224
GENEERILINE - VÄLINE VOODER | 1 korrus | GENEERILINE - VÄLINE VOODER | 0,1 | -210; Kõrgus: 9 784; 3D pikkus: 9 784 | -210
GENEERILINE - VÄLINE VOODER | 1 korrus | GENEERILINE - VÄLINE VOODER | 0,0 | -195; Kõrgus: 9 776; 3D pikkus: 9 776 | -195
GENEERILINE - VÄLINE VOODER | 1 korrus | GENEERILINE - VÄLINE VOODER | 0,0 | -186; Kõrgus: 9 771; 3D pikkus: 9 771 | -186
GENEERILINE - VÄLINE VOODER | 1 korrus | GENEERILINE - VÄLINE VOODER | 0,0 | -244; Kõrgus: 9 803; 3D pikkus: 9 803 | -244
GENEERILINE - VÄLINE VOODER | 1 korrus | GENEERILINE - VÄLINE VOODER | 0,0 | -307; Kõrgus: 9 837; 3D pikkus: 9 837 | -307
GENEERILINE - VÄLINE VOODER | 1 korrus | GENEERILINE - VÄLINE VOODER | 0,0 | -297; Kõrgus: 9 832; 3D pikkus: 9 832 | -297
GENEERILINE - VÄLINE VOODER | 1 korrus | GENEERILINE - VÄLINE VOODER | 0,1 | -283; Kõrgus: 9 824; 3D pikkus: 9 824 | -283
GENEERILINE - VÄLINE VOODER | 1 korrus | GENEERILINE - VÄLINE VOODER | 0,0 | -268; Kõrgus: 9 816; 3D pikkus: 9 816 | -268
GENEERILINE - VÄLINE VOODER | 1 korrus | GENEERILINE - VÄLINE VOODER | 0,0 | -258; Kõrgus: 9 811; 3D pikkus: 9 811 | -258
GENEERILINE - VÄLINE VOODER | 1 korrus | GENEERILINE - VÄLINE VOODER | 0,0 | -316; Kõrgus: 9 843; 3D pikkus: 9 843 | -316
GENEERILINE - VÄLINE VOODER | 1 korrus | GENEERILINE - VÄLINE VOODER | 0,0 | -379; Kõrgus: 9 877; 3D pikkus: 9 877 | -379
GENEERILINE - VÄLINE VOODER | 1 korrus | GENEERILINE - VÄLINE VOODER | 0,0 | -355; Kõrgus: 9 864; 3D pikkus: 9 864 | -355
GENEERILINE - VÄLINE VOODER | 1 korrus | GENEERILINE - VÄLINE VOODER | 0,1 | -579; Kõrgus: 10 075; 3D pikkus: 10 075 | -579
GENEERILINE - VÄLINE VOODER | 1 korrus | GENEERILINE - VÄLINE VOODER | 0,1 | -579; Kõrgus: 10 358; 3D pikkus: 10 358 | -579
GENEERILINE - VÄLINE VOODER | 1 korrus | GENEERILINE - VÄLINE VOODER | 0,1 | -579; Kõrgus: 10 201; 3D pikkus: 10 201 | -579
GENEERILINE - VÄLINE VOODER | 1 korrus | GENEERILINE - VÄLINE VOODER | 0,1 | -579; Kõrgus: 10 154; 3D pikkus: 10 154 | -579
GENEERILINE - VÄLINE VOODER | 1 korrus | GENEERILINE - VÄLINE VOODER | 0,1 | -579; Kõrgus: 10 122; 3D pikkus: 10 122 | -579
GENEERILINE - VÄLINE VOODER | 1 korrus | GENEERILINE - VÄLINE VOODER | 0,1 | -579; Kõrgus: 10 279; 3D pikkus: 10 279 | -579
GENEERILINE - VÄLINE VOODER | 1 korrus | GENEERILINE - VÄLINE VOODER | 0,1 | -579; Kõrgus: 10 327; 3D pikkus: 10 327 | -579
48 x Site specified | 1 korrus | Site specified | 0,0 | 2 320; Kõrgus: 2 330; 3D pikkus: 2 330 | 2 320
4 x Site specified | 1 korrus | Site specified | 0,1 | 15; Kõrgus: 8 713; 3D pikkus: 8 713 | 15
GENEERILINE - VÄLINE VOODER | 1 korrus | GENEERILINE - VÄLINE VOODER | 0,0 | -41; Kõrgus: 2 892; 3D pikkus: 2 892 | -41
GENEERILINE - VÄLINE VOODER | 1 korrus | GENEERILINE - VÄLINE VOODER | 0,0 | -41; Kõrgus: 2 934; 3D pikkus: 2 934 | -41
6 x Site specified | 1 korrus | Site specified | 0,0 | 1 570; Kõrgus: 8 295; 3D pikkus: 8 295 | 1 570
Site specified | 1 korrus | Site specified (2) | 0,0 | 100; Kõrgus: 9 765; 3D pikkus: 9 591 | 100
16 x Site specified | 1 korrus | Site specified | 0,0 | 100; Kõrgus: 2 100; 3D pikkus: 2 100 | 100
56 x Site specified | 1 korrus | Site specified | 0,0 | 8 878; Kõrgus: 732; 3D pikkus: 732 | 8 878
3 x Site specified | 1 korrus | Site specified | 0,0 | 3 000; Kõrgus: 2 206; 3D pikkus: 2 206 | 3 000
Site specified | 1 korrus | Site specified | 0,0 | -279; Kõrgus: 10 144; 3D pikkus: 10 144 | -279
122 x Site specified | 1 korrus | Site specified | 0,0 | 0; Kõrgus: 1 330; 3D pikkus: 1 330 | 0
GENEERILINE - VÄLINE VOODER | 1 korrus | GENEERILINE - VÄLINE VOODER | 0,0 | -78; Kõrgus: 1 208; 3D pikkus: 1 208 | -78
GENEERILINE - VÄLINE VOODER | 1 korrus | GENEERILINE - VÄLINE VOODER | 0,0 | -54; Kõrgus: 2 296; 3D pikkus: 2 296 | -54
GENEERILINE - VÄLINE VOODER | 1 korrus | GENEERILINE - VÄLINE VOODER | 0,0 | -54; Kõrgus: 2 326; 3D pikkus: 2 326 | -54
GENEERILINE - VÄLINE VOODER | 1 korrus | GENEERILINE - VÄLINE VOODER | 0,0 | -54; Kõrgus: 2 346; 3D pikkus: 2 346 | -54
GENEERILINE - VÄLINE VOODER | 1 korrus | GENEERILINE - VÄLINE VOODER | 0,0 | -54; Kõrgus: 2 227; 3D pikkus: 2 227 | -54
GENEERILINE - VÄLINE VOODER | 1 korrus | GENEERILINE - VÄLINE VOODER | 0,0 | -54; Kõrgus: 2 097; 3D pikkus: 2 097 | -54
GENEERILINE - VÄLINE VOODER | 1 korrus | GENEERILINE - VÄLINE VOODER | 0,0 | -54; Kõrgus: 2 117; 3D pikkus: 2 117 | -54
GENEERILINE - VÄLINE VOODER | 1 korrus | GENEERILINE - VÄLINE VOODER | 0,0 | -54; Kõrgus: 2 147; 3D pikkus: 2 147 | -54
GENEERILINE - VÄLINE VOODER | 1 korrus | GENEERILINE - VÄLINE VOODER | 0,0 | -54; Kõrgus: 2 177; 3D pikkus: 2 177 | -54
GENEERILINE - VÄLINE VOODER | 1 korrus | GENEERILINE - VÄLINE VOODER | 0,0 | -54; Kõrgus: 2 074; 3D pikkus: 2 074 | -54
GENEERILINE - VÄLINE VOODER | 1 korrus | GENEERILINE - VÄLINE VOODER | 0,0 | -54; Kõrgus: 1 956; 3D pikkus: 1 956 | -54
GENEERILINE - VÄLINE VOODER | 1 korrus | GENEERILINE - VÄLINE VOODER | 0,0 | -54; Kõrgus: 1 982; 3D pikkus: 1 982 | -54
GENEERILINE - VÄLINE VOODER | 1 korrus | GENEERILINE - VÄLINE VOODER | 0,0 | -54; Kõrgus: 2 012; 3D pikkus: 2 012 | -54
GENEERILINE - VÄLINE VOODER | 1 korrus | GENEERILINE - VÄLINE VOODER | 0,0 | -54; Kõrgus: 2 044; 3D pikkus: 2 044 | -54
GENEERILINE - VÄLINE VOODER | 1 korrus | GENEERILINE - VÄLINE VOODER | 0,0 | -54; Kõrgus: 2 197; 3D pikkus: 2 197 | -54
GENEERILINE - VÄLINE VOODER | 1 korrus | GENEERILINE - VÄLINE VOODER | 0,0 | -66; Kõrgus: 1 875; 3D pikkus: 1 875 | -66
GENEERILINE - VÄLINE VOODER | 1 korrus | GENEERILINE - VÄLINE VOODER | 0,0 | -66; Kõrgus: 1 815; 3D pikkus: 1 815 | -66
GENEERILINE - VÄLINE VOODER | 1 korrus | GENEERILINE - VÄLINE VOODER | 0,0 | -66; Kõrgus: 1 845; 3D pikkus: 1 845 | -66
GENEERILINE - VÄLINE VOODER | 1 korrus | GENEERILINE - VÄLINE VOODER | 0,0 | -78; Kõrgus: 1 248; 3D pikkus: 1 248 | -78
GENEERILINE - VÄLINE VOODER | 1 korrus | GENEERILINE - VÄLINE VOODER | 0,0 | -66; Kõrgus: 1 795; 3D pikkus: 1 795 | -66
GENEERILINE - VÄLINE VOODER | 1 korrus | GENEERILINE - VÄLINE VOODER | 0,0 | -66; Kõrgus: 1 666; 3D pikkus: 1 666 | -66
GENEERILINE - VÄLINE VOODER | 1 korrus | GENEERILINE - VÄLINE VOODER | 0,0 | -66; Kõrgus: 1 696; 3D pikkus: 1 696 | -66
GENEERILINE - VÄLINE VOODER | 1 korrus | GENEERILINE - VÄLINE VOODER | 0,0 | -66; Kõrgus: 1 726; 3D pikkus: 1 726 | -66
GENEERILINE - VÄLINE VOODER | 1 korrus | GENEERILINE - VÄLINE VOODER | 0,0 | -66; Kõrgus: 1 776; 3D pikkus: 1 776 | -66
GENEERILINE - VÄLINE VOODER | 1 korrus | GENEERILINE - VÄLINE VOODER | 0,0 | -66; Kõrgus: 1 746; 3D pikkus: 1 746 | -66
GENEERILINE - VÄLINE VOODER | 1 korrus | GENEERILINE - VÄLINE VOODER | 0,0 | -66; Kõrgus: 1 646; 3D pikkus: 1 646 | -66
GENEERILINE - VÄLINE VOODER | 1 korrus | GENEERILINE - VÄLINE VOODER | 0,0 | -66; Kõrgus: 1 523; 3D pikkus: 1 523 | -66
GENEERILINE - VÄLINE VOODER | 1 korrus | GENEERILINE - VÄLINE VOODER | 0,0 | -66; Kõrgus: 1 547; 3D pikkus: 1 547 | -66
2 x GENEERILINE - VÄLINE VOODER | 1 korrus | GENEERILINE - VÄLINE VOODER | 0,0 | -66; Kõrgus: 1 461; 3D pikkus: 1 461 | -66
GENEERILINE - VÄLINE VOODER | 1 korrus | GENEERILINE - VÄLINE VOODER | 0,0 | -66; Kõrgus: 1 597; 3D pikkus: 1 597 | -66
GENEERILINE - VÄLINE VOODER | 1 korrus | GENEERILINE - VÄLINE VOODER | 0,0 | -66; Kõrgus: 1 626; 3D pikkus: 1 626 | -66
GENEERILINE - VÄLINE VOODER | 1 korrus | GENEERILINE - VÄLINE VOODER | 0,0 | -78; Kõrgus: 1 129; 3D pikkus: 1 129 | -78
GENEERILINE - VÄLINE VOODER | 1 korrus | GENEERILINE - VÄLINE VOODER | 0,0 | -78; Kõrgus: 1 158; 3D pikkus: 1 158 | -78
GENEERILINE - VÄLINE VOODER | 1 korrus | GENEERILINE - VÄLINE VOODER | 0,0 | -78; Kõrgus: 1 029; 3D pikkus: 1 029 | -78
GENEERILINE - VÄLINE VOODER | 1 korrus | GENEERILINE - VÄLINE VOODER | 0,0 | -78; Kõrgus: 915; 3D pikkus: 915 | -78
GENEERILINE - VÄLINE VOODER | 1 korrus | GENEERILINE - VÄLINE VOODER | 0,0 | -78; Kõrgus: 1 278; 3D pikkus: 1 278 | -78
GENEERILINE - VÄLINE VOODER | 1 korrus | GENEERILINE - VÄLINE VOODER | 0,0 | -78; Kõrgus: 979; 3D pikkus: 979 | -78
GENEERILINE - VÄLINE VOODER | 1 korrus | GENEERILINE - VÄLINE VOODER | 0,0 | -78; Kõrgus: 1 178; 3D pikkus: 1 178 | -78
GENEERILINE - VÄLINE VOODER | 1 korrus | GENEERILINE - VÄLINE VOODER | 0,0 | -66; Kõrgus: 1 491; 3D pikkus: 1 491 | -66
GENEERILINE - VÄLINE VOODER | 1 korrus | GENEERILINE - VÄLINE VOODER | 0,0 | -78; Kõrgus: 1 228; 3D pikkus: 1 228 | -78
GENEERILINE - VÄLINE VOODER | 1 korrus | GENEERILINE - VÄLINE VOODER | 0,0 | -78; Kõrgus: 964; 3D pikkus: 964 | -78
GENEERILINE - VÄLINE VOODER | 1 korrus | GENEERILINE - VÄLINE VOODER | 0,0 | -78; Kõrgus: 1 307; 3D pikkus: 1 307 | -78
GENEERILINE - VÄLINE VOODER | 1 korrus | GENEERILINE - VÄLINE VOODER | 0,0 | -66; Kõrgus: 1 436; 3D pikkus: 1 436 | -66
GENEERILINE - VÄLINE VOODER | 1 korrus | GENEERILINE - VÄLINE VOODER | 0,0 | -78; Kõrgus: 934; 3D pikkus: 934 | -78
GENEERILINE - VÄLINE VOODER | 1 korrus | GENEERILINE - VÄLINE VOODER | 0,0 | -78; Kõrgus: 1 059; 3D pikkus: 1 059 | -78
GENEERILINE - VÄLINE VOODER | 1 korrus | GENEERILINE - VÄLINE VOODER | 0,0 | -78; Kõrgus: 1 327; 3D pikkus: 1 327 | -78
GENEERILINE - VÄLINE VOODER | 1 korrus | GENEERILINE - VÄLINE VOODER | 0,0 | -78; Kõrgus: 1 079; 3D pikkus: 1 079 | -78
GENEERILINE - VÄLINE VOODER | 1 korrus | GENEERILINE - VÄLINE VOODER | 0,0 | -54; Kõrgus: 2 266; 3D pikkus: 2 266 | -54
GENEERILINE - VÄLINE VOODER | 1 korrus | GENEERILINE - VÄLINE VOODER | 0,0 | -41; Kõrgus: 2 838; 3D pikkus: 2 838 | -41
GENEERILINE - VÄLINE VOODER | 1 korrus | GENEERILINE - VÄLINE VOODER | 0,0 | 350; Kõrgus: 9 290; 3D pikkus: 9 290 | 350
GENEERILINE - VÄLINE VOODER | 1 korrus | GENEERILINE - VÄLINE VOODER | 0,0 | 350; Kõrgus: 9 178; 3D pikkus: 9 178 | 350
GENEERILINE - VÄLINE VOODER | 1 korrus | GENEERILINE - VÄLINE VOODER | 0,0 | 227; Kõrgus: 9 413; 3D pikkus: 9 413 | 227
GENEERILINE - VÄLINE VOODER | 1 korrus | GENEERILINE - VÄLINE VOODER | 0,0 | 350; Kõrgus: 9 090; 3D pikkus: 9 090 | 350
Site specified | 1 korrus | Site specified | 0,1 | 1 747; Kõrgus: 8 118; 3D pikkus: 8 118 | 1 747
6 x Site specified | 1 korrus | Site specified | 0,0 | 1 747; Kõrgus: 8 118; 3D pikkus: 8 118 | 1 747
Site specified | 1 korrus | Site specified | 0,1 | 1 730; Kõrgus: 8 135; 3D pikkus: 8 135 | 1 730
6 x Site specified | 1 korrus | Site specified | 0,0 | 1 730; Kõrgus: 8 135; 3D pikkus: 8 135 | 1 730
Site specified | 1 korrus | Site specified | 0,1 | 1 658; Kõrgus: 8 207; 3D pikkus: 8 207 | 1 658
6 x Site specified | 1 korrus | Site specified | 0,0 | 1 658; Kõrgus: 8 207; 3D pikkus: 8 207 | 1 658
6 x Site specified | 1 korrus | Site specified | 0,0 | 1 604; Kõrgus: 8 261; 3D pikkus: 8 261 | 1 604
Site specified | 1 korrus | Site specified | 0,1 | 1 604; Kõrgus: 8 261; 3D pikkus: 8 261 | 1 604
8 x Site specified | 1 korrus | Site specified | 0,0 | 1 678; Kõrgus: 8 187; 3D pikkus: 8 187 | 1 678
Site specified | 1 korrus | Site specified | 0,1 | 1 678; Kõrgus: 8 187; 3D pikkus: 8 187 | 1 678
Site specified | 1 korrus | Site specified | 0,1 | 1 587; Kõrgus: 8 278; 3D pikkus: 8 278 | 1 587
5 x Site specified | 1 korrus | Site specified | 0,0 | 1 587; Kõrgus: 8 278; 3D pikkus: 8 278 | 1 587
4 x Site specified | 1 korrus | Site specified | 0,0 | 1 713; Kõrgus: 8 152; 3D pikkus: 8 152 | 1 713
Site specified | 1 korrus | Site specified | 0,1 | 1 553; Kõrgus: 8 312; 3D pikkus: 8 312 | 1 553
Site specified | 1 korrus | Site specified | 0,1 | 1 340; Kõrgus: 8 525; 3D pikkus: 8 525 | 1 340
Site specified | 1 korrus | Site specified | 0,0 | 1 430; Kõrgus: 8 435; 3D pikkus: 8 435 | 1 430
4 x Site specified | 1 korrus | Site specified | 0,0 | 50; Kõrgus: 9 815; 3D pikkus: 8 435 | 50
4 x Site specified | 1 korrus | Site specified | 0,0 | 50; Kõrgus: 9 815; 3D pikkus: 8 525 | 50
4 x Site specified | 1 korrus | Site specified | 0,0 | 50; Kõrgus: 9 815; 3D pikkus: 8 165 | 50
2 x Site specified | 1 korrus | Site specified | 0,0 | 50; Kõrgus: 9 815; 3D pikkus: 8 255 | 50
3 x Site specified | 1 korrus | Site specified | 0,0 | 50; Kõrgus: 9 815; 3D pikkus: 8 345 | 50
3 x Site specified | 1 korrus | Site specified | 0,0 | 50; Kõrgus: 9 815; 3D pikkus: 8 615 | 50
2 x Site specified | 1 korrus | Site specified | 0,0 | 1 160; Kõrgus: 8 705; 3D pikkus: 8 705 | 1 160
Site specified | 1 korrus | Site specified | 0,1 | 800; Kõrgus: 9 065; 3D pikkus: 9 065 | 800
Site specified | 1 korrus | Site specified | 0,0 | 890; Kõrgus: 8 975; 3D pikkus: 8 975 | 890
4 x Site specified | 1 korrus | Site specified | 0,0 | 50; Kõrgus: 9 815; 3D pikkus: 8 975 | 50
4 x Site specified | 1 korrus | Site specified | 0,0 | 50; Kõrgus: 9 815; 3D pikkus: 9 065 | 50
Site specified | 1 korrus | Site specified | 0,1 | 1 070; Kõrgus: 8 795; 3D pikkus: 8 795 | 1 070
3 x Site specified | 1 korrus | Site specified | 0,0 | 50; Kõrgus: 9 815; 3D pikkus: 8 705 | 50
3 x Site specified | 1 korrus | Site specified | 0,0 | 50; Kõrgus: 9 815; 3D pikkus: 8 795 | 50
3 x Site specified | 1 korrus | Site specified | 0,0 | 50; Kõrgus: 9 815; 3D pikkus: 8 885 | 50
3 x Site specified | 1 korrus | Site specified | 0,0 | 50; Kõrgus: 9 815; 3D pikkus: 9 155 | 50
4 x Site specified | 1 korrus | Site specified | 0,0 | 50; Kõrgus: 9 815; 3D pikkus: 9 245 | 50
Site specified | 1 korrus | Site specified | 0,1 | 350; Kõrgus: 9 515; 3D pikkus: 9 515 | 350
3 x Site specified | 1 korrus | Site specified | 0,0 | 50; Kõrgus: 9 815; 3D pikkus: 9 605 | 50
Site specified | 1 korrus | Site specified | 0,1 | 530; Kõrgus: 9 335; 3D pikkus: 9 335 | 530
Site specified | 1 korrus | Site specified | 0,1 | 620; Kõrgus: 9 245; 3D pikkus: 9 245 | 620
4 x Site specified | 1 korrus | Site specified | 0,0 | 3 000; Kõrgus: 6 865; 3D pikkus: 6 865 | 3 000
4 x Site specified | 1 korrus | Site specified (2) | 0,0 | 100; Kõrgus: 9 765; 3D pikkus: 9 633 | 100
2 x Site specified | 1 korrus | Site specified (2) | 0,0 | 100; Kõrgus: 9 765; 3D pikkus: 9 624 | 100
2 x Site specified | 1 korrus | Site specified (2) | 0,0 | 100; Kõrgus: 9 765; 3D pikkus: 9 634 | 100
4 x Site specified | 1 korrus | Site specified (2) | 0,0 | 100; Kõrgus: 9 765; 3D pikkus: 9 631 | 100
2 x Site specified | 1 korrus | Site specified (2) | 0,0 | 100; Kõrgus: 9 765; 3D pikkus: 9 641 | 100
2 x Site specified | 1 korrus | Site specified (2) | 0,0 | 100; Kõrgus: 9 765; 3D pikkus: 9 628 | 100
2 x Site specified | 1 korrus | Site specified (2) | 0,0 | 100; Kõrgus: 9 765; 3D pikkus: 9 638 | 100
2 x Site specified | 1 korrus | Site specified (2) | 0,0 | 100; Kõrgus: 9 765; 3D pikkus: 9 626 | 100
GENEERILINE - VÄLINE VOODER | 1 korrus | GENEERILINE - VÄLINE VOODER | 0,0 | -78; Kõrgus: 1 099; 3D pikkus: 1 099 | -78
GENEERILINE - VÄLINE VOODER | 1 korrus | GENEERILINE - VÄLINE VOODER | 0,0 | -41; Kõrgus: 2 913; 3D pikkus: 2 913 | -41
GENEERILINE - VÄLINE VOODER | 1 korrus | GENEERILINE - VÄLINE VOODER | 0,0 | -41; Kõrgus: 2 689; 3D pikkus: 2 689 | -41
GENEERILINE - VÄLINE VOODER | 1 korrus | GENEERILINE - VÄLINE VOODER | 0,0 | -78; Kõrgus: 1 354; 3D pikkus: 1 354 | -78
GENEERILINE - VÄLINE VOODER | 1 korrus | GENEERILINE - VÄLINE VOODER | 0,0 | -41; Kõrgus: 2 709; 3D pikkus: 2 709 | -41
GENEERILINE - VÄLINE VOODER | 1 korrus | GENEERILINE - VÄLINE VOODER | 0,0 | -41; Kõrgus: 2 729; 3D pikkus: 2 729 | -41
GENEERILINE - VÄLINE VOODER | 1 korrus | GENEERILINE - VÄLINE VOODER | 0,0 | -41; Kõrgus: 2 758; 3D pikkus: 2 758 | -41
GENEERILINE - VÄLINE VOODER | 1 korrus | GENEERILINE - VÄLINE VOODER | 0,0 | -41; Kõrgus: 2 788; 3D pikkus: 2 788 | -41
GENEERILINE - VÄLINE VOODER | 1 korrus | GENEERILINE - VÄLINE VOODER | 0,0 | -41; Kõrgus: 2 659; 3D pikkus: 2 659 | -41
GENEERILINE - VÄLINE VOODER | 1 korrus | GENEERILINE - VÄLINE VOODER | 0,0 | -41; Kõrgus: 2 599; 3D pikkus: 2 599 | -41
GENEERILINE - VÄLINE VOODER | 1 korrus | GENEERILINE - VÄLINE VOODER | 0,0 | -41; Kõrgus: 2 639; 3D pikkus: 2 639 | -41
GENEERILINE - VÄLINE VOODER | 1 korrus | GENEERILINE - VÄLINE VOODER | 0,0 | -41; Kõrgus: 2 619; 3D pikkus: 2 619 | -41
GENEERILINE - VÄLINE VOODER | 1 korrus | GENEERILINE - VÄLINE VOODER | 0,0 | -41; Kõrgus: 2 530; 3D pikkus: 2 530 | -41
GENEERILINE - VÄLINE VOODER | 1 korrus | GENEERILINE - VÄLINE VOODER | 0,0 | -54; Kõrgus: 2 396; 3D pikkus: 2 396 | -54
GENEERILINE - VÄLINE VOODER | 1 korrus | GENEERILINE - VÄLINE VOODER | 0,0 | -41; Kõrgus: 2 569; 3D pikkus: 2 569 | -41
GENEERILINE - VÄLINE VOODER | 1 korrus | GENEERILINE - VÄLINE VOODER | 0,0 | -41; Kõrgus: 2 550; 3D pikkus: 2 550 | -41
GENEERILINE - VÄLINE VOODER | 1 korrus | GENEERILINE - VÄLINE VOODER | 0,0 | -41; Kõrgus: 2 476; 3D pikkus: 2 476 | -41
GENEERILINE - VÄLINE VOODER | 1 korrus | GENEERILINE - VÄLINE VOODER | 0,0 | -41; Kõrgus: 2 500; 3D pikkus: 2 500 | -41
GENEERILINE - VÄLINE VOODER | 1 korrus | GENEERILINE - VÄLINE VOODER | 0,0 | -54; Kõrgus: 2 376; 3D pikkus: 2 376 | -54
GENEERILINE - VÄLINE VOODER | 1 korrus | GENEERILINE - VÄLINE VOODER | 0,0 | -54; Kõrgus: 2 247; 3D pikkus: 2 247 | -54
97 x Site specified | 1 korrus | Site specified | 0,0 | 7 620; Kõrgus: 2 245; 3D pikkus: 2 245 | 7 620
2 x Site specified | 1 korrus | Site specified | 0,0 | 100; Kõrgus: 2 120; 3D pikkus: 2 120 | 100
4 x Site specified | 1 korrus | Site specified (2) | 0,0 | 100; Kõrgus: 9 765; 3D pikkus: 9 644 | 100
25 x Site specified | 1 korrus | Site specified | 0,0 | 7 615; Kõrgus: 2 250; 3D pikkus: 2 250 | 7 615
8 x Site specified | 1 korrus | Site specified | 0,0 | 7 865; Kõrgus: 863; 3D pikkus: 863 | 7 865
GENEERILINE - VÄLINE VOODER | 1 korrus | GENEERILINE - VÄLINE VOODER | 0,0 | -316; Kõrgus: 9 844; 3D pikkus: 9 844 | -316
GENEERILINE - VÄLINE VOODER | 1 korrus | GENEERILINE - VÄLINE VOODER | 0,0 | -26; Kõrgus: 9 465; 3D pikkus: 9 465 | -26
2 x Site specified | 1 korrus | Site specified | 0,0 | 100; Kõrgus: 9 160; 3D pikkus: 9 160 | 100
2 x Site specified | 1 korrus | Site specified (2) | 0,0 | 100; Kõrgus: 9 765; 3D pikkus: 9 636 | 100

# IfcWall: SS-01 (39)
Type - ElementType: Element type SS-01
Arhitektuur - 01 Nimetus: Sisesein; 03 Tähistus: SS-01; 08 Soojusläbivus (U-arv): -
Ehituskonstruktsioonid - 03 Tähistus või ristlõige: SS-01
AC_Pset_RenovationAndPhasing - Renovation Status: New
Name | In | Classification | Material | 02 Materjal | 04 Tulepüsivus | 05 Asukoht | 06 Kandevelementide eristatus | 07 Helipidavus | 06 Maht (kubatuur) | 11 Ülemine kõrgusmärk | 12 Alumine kõrgusmärk | LoadBearing = IsExternal
SS-01 | 0 korrus | 1.18 IfcWall (sein) (_RKAS BIM + ARCHICAD Classification) | Krohv - Lubjakivi (2), Müüriplokk - Konstuktsioon | Siseviimistlus; Lubikrohv 10mm; Kergplokk 200mm; Lubikrohv 10mm; Siseviimistlus | nõudeid ei esitata | Interior | Non-Load-Bearing Element | 48 dB | 4,0 | -1 635; Kõrgus: 3 020; 3D pikkus: 6 040 | -1 635 | no
SS-01 | 0 korrus | 1.18 IfcWall (sein) (_RKAS BIM + ARCHICAD Classification) | Krohv - Lubjakivi (2), Müüriplokk - Konstuktsioon | Siseviimistlus; Lubikrohv 10mm; Kergplokk 200mm; Lubikrohv 10mm; Siseviimistlus | nõudeid ei esitata | Interior | Non-Load-Bearing Element | 48 dB | 3,3 | -1 635; Kõrgus: 3 020; 3D pikkus: 4 940 | -1 635 | no
3 x SS-01 | 0 korrus | 1.18 IfcWall (sein) (_RKAS BIM + ARCHICAD Classification) | Krohv - Lubjakivi (2), Müüriplokk - Konstuktsioon | Siseviimistlus; Lubikrohv 10mm; Kergplokk 200mm; Lubikrohv 10mm; Siseviimistlus | nõudeid ei esitata | Interior | Non-Load-Bearing Element | 48 dB | 3,3 | -1 635; Kõrgus: 3 020; 3D pikkus: 4 950 | -1 635 | no
SS-01 | 0 korrus | 0 TELLIJA KULUD (EHITUSKULUDE LIIGITAMINE EVS 885:2005); 1.18 IfcWall (sein) (_RKAS BIM + ARCHICAD Classification) | Krohv - Lubjakivi (3), Müüriplokk - Konstuktsioon | Siseviimistlus; Lubikrohv 10mm; Kergplokk 200mm; Lubikrohv 10mm; Siseviimistlus | nõudeid ei esitata | Interior | Non-Load-Bearing Element | - | 1,9 | -1 635; Kõrgus: 3 020; 3D pikkus: 3 560 | -1 635 | no
2 x SS-01 | 0 korrus | 1.18 IfcWall (sein) (_RKAS BIM + ARCHICAD Classification) | Krohv - Lubjakivi (4), Müüriplokk - Konstuktsioon (2) | Siseviimistlus; Lubikrohv 10mm; Kergplokk 200mm; Lubikrohv 10mm; Siseviimistlus | nõudeid ei esitata | Interior | Non-Load-Bearing Element | 48 dB | 4,0 | -1 635; Kõrgus: 3 020; 3D pikkus: 6 050 | -1 635 | no
SS-02 | 0 korrus | 0 TELLIJA KULUD (EHITUSKULUDE LIIGITAMINE EVS 885:2005); 1.18 IfcWall (sein) (_RKAS BIM + ARCHICAD Classification) | Krohv - Lubjakivi, Müüriplokk - Konstuktsioon | Siseviimistlus; Mineraalkrohv 10mm; Kergplokk 200mm; Mineraalkrohv 10mm; Siseviimistlus | EI 60 | Interior | Non-Load-Bearing Element | 49 dB | 0,4 | -1 635; Kõrgus: 1 700; 3D pikkus: 2 500 | -1 635 | no
SS-01 | 0 korrus | 1.18 IfcWall (sein) (_RKAS BIM + ARCHICAD Classification) | Krohv - Lubjakivi (2), Müüriplokk - Konstuktsioon | Siseviimistlus; Lubikrohv 10mm; Kergplokk 200mm; Lubikrohv 10mm; Siseviimistlus | nõudeid ei esitata | Interior | Non-Load-Bearing Element | 48 dB | 2,9 | -1 635; Kõrgus: 3 020; 3D pikkus: 4 350 | -1 635 | no
SS-01 | 0 korrus | 0 TELLIJA KULUD (EHITUSKULUDE LIIGITAMINE EVS 885:2005); 1.18 IfcWall (sein) (_RKAS BIM + ARCHICAD Classification) | Krohv - Lubjakivi (2), Müüriplokk - Konstuktsioon | Siseviimistlus; Lubikrohv 10mm; Kergplokk 200mm; Lubikrohv 10mm; Siseviimistlus | nõudeid ei esitata | Interior | Non-Load-Bearing Element | - | 1,2 | -1 635; Kõrgus: 3 020; 3D pikkus: 2 480 | -1 635 | no
SS-02 | 0 korrus | 1.18 IfcWall (sein) (_RKAS BIM + ARCHICAD Classification) | Müüriplokk - Konstuktsioon, Krohv - Lubjakivi | Siseviimistlus; Mineraalkrohv 10mm; Kergplokk 200mm; Mineraalkrohv 10mm; Siseviimistlus | EI 60 | Interior | Non-Load-Bearing Element | 49 dB | 2,0 | -1 635; Kõrgus: 2 008; 3D pikkus: 4 930 | -1 635 | no
SS-01 | 1,5 korrus | 1.18 IfcWall (sein) (_RKAS BIM + ARCHICAD Classification) | Krohv - Lubjakivi (2), Müüriplokk - Konstuktsioon | Siseviimistlus; Lubikrohv 10mm; Kergplokk 200mm; Lubikrohv 10mm; Siseviimistlus | nõudeid ei esitata | Interior | Non-Load-Bearing Element | 48 dB | 3,7 | 1 650; Kõrgus: 3 150; 3D pikkus: 6 040 | 1 650 | no
SS-01 | 1,5 korrus | 1.18 IfcWall (sein) (_RKAS BIM + ARCHICAD Classification) | Krohv - Lubjakivi (2), Müüriplokk - Konstuktsioon | Siseviimistlus; Lubikrohv 10mm; Kergplokk 200mm; Lubikrohv 10mm; Siseviimistlus | EI 60 | Interior | Non-Load-Bearing Element | 48 dB | 2,5 | 1 650; Kõrgus: 3 150; 3D pikkus: 3 700 | 1 650 | no
SS-01 | 1,5 korrus | 1.18 IfcWall (sein) (_RKAS BIM + ARCHICAD Classification) | Krohv - Lubjakivi (2), Müüriplokk - Konstuktsioon | Siseviimistlus; Lubikrohv 10mm; Kergplokk 200mm; Lubikrohv 10mm; Siseviimistlus | nõudeid ei esitata | Interior | Non-Load-Bearing Element | 48 dB | 2,8 | 1 650; Kõrgus: 3 150; 3D pikkus: 4 760 | 1 650 | no
SS-01 | 1,5 korrus | 1.18 IfcWall (sein) (_RKAS BIM + ARCHICAD Classification) | Krohv - Lubjakivi (4), Müüriplokk - Konstuktsioon | Siseviimistlus; Lubikrohv 10mm; Kergplokk 200mm; Lubikrohv 10mm; Siseviimistlus | EI 60 | Interior | Non-Load-Bearing Element | 48 dB | 6,6 | 1 650; Kõrgus: 3 565; 3D pikkus: 10 930 | 1 650 | no
SS-01 | 1,5 korrus | 1.18 IfcWall (sein) (_RKAS BIM + ARCHICAD Classification) | Krohv - Lubjakivi (2), Müüriplokk - Konstuktsioon | Siseviimistlus; Lubikrohv 10mm; Kergplokk 200mm; Lubikrohv 10mm; Siseviimistlus | nõudeid ei esitata | Interior | Non-Load-Bearing Element | - | 0,7 | 2 300; Kõrgus: 2 500; 3D pikkus: 1 210 | 2 300 | no
SS-01 | 1,5 korrus | 1.18 IfcWall (sein) (_RKAS BIM + ARCHICAD Classification) | Krohv - Lubjakivi (2), Müüriplokk - Konstuktsioon | Siseviimistlus; Lubikrohv 10mm; Kergplokk 200mm; Lubikrohv 10mm; Siseviimistlus | nõudeid ei esitata | Interior | Non-Load-Bearing Element | 48 dB | 0,5 | 1 650; Kõrgus: 3 150; 3D pikkus: 760 | 1 650 | no
SS-01 | 1,5 korrus | 1.18 IfcWall (sein) (_RKAS BIM + ARCHICAD Classification) | Krohv - Lubjakivi (5), Müüriplokk - Konstuktsioon | Siseviimistlus; Lubikrohv 10mm; Kergplokk 200mm; Lubikrohv 10mm; Siseviimistlus | EI 60 | Interior | Non-Load-Bearing Element | 48 dB | 7,1 | 1 650; Kõrgus: 3 565; 3D pikkus: 11 740 | 1 650 | no
SS-01 | 1,5 korrus | 1.18 IfcWall (sein) (_RKAS BIM + ARCHICAD Classification) | Krohv - Lubjakivi (2), Müüriplokk - Konstuktsioon | Siseviimistlus; Lubikrohv 10mm; Kergplokk 200mm; Lubikrohv 10mm; Siseviimistlus | nõudeid ei esitata | Interior | Non-Load-Bearing Element | 48 dB | 2,5 | 1 650; Kõrgus: 3 150; 3D pikkus: 4 260 | 1 650 | no
SS-01 | 2 korrus | 1.18 IfcWall (sein) (_RKAS BIM + ARCHICAD Classification) | Krohv - Lubjakivi (2), Müüriplokk - Konstuktsioon | Siseviimistlus; Lubikrohv 10mm; Kergplokk 200mm; Lubikrohv 10mm; Siseviimistlus | nõudeid ei esitata | Interior | Non-Load-Bearing Element | 48 dB | 6,2 | 5 065; Kõrgus: 3 650; 3D pikkus: 8 510 | 5 065 | no
2 x SS-01 | 2 korrus | 1.18 IfcWall (sein) (_RKAS BIM + ARCHICAD Classification) | Krohv - Lubjakivi (2), Müüriplokk - Konstuktsioon | Siseviimistlus; Lubikrohv 10mm; Kergplokk 200mm; Lubikrohv 10mm; Siseviimistlus | nõudeid ei esitata | Interior | Non-Load-Bearing Element | 48 dB | 3,9 | 5 065; Kõrgus: 3 650; 3D pikkus: 4 970 | 5 065 | no
SS-01 | 2 korrus | 1.18 IfcWall (sein) (_RKAS BIM + ARCHICAD Classification) | Krohv - Lubjakivi (2), Müüriplokk - Konstuktsioon | Siseviimistlus; Lubikrohv 10mm; Kergplokk 200mm; Lubikrohv 10mm; Siseviimistlus | nõudeid ei esitata | Interior | Non-Load-Bearing Element | 48 dB | 4,8 | 5 065; Kõrgus: 3 650; 3D pikkus: 6 040 | 5 065 | no
SS-01 | 2 korrus | 1.18 IfcWall (sein) (_RKAS BIM + ARCHICAD Classification) | Krohv - Lubjakivi (2), Müüriplokk - Konstuktsioon | Siseviimistlus; Lubikrohv 10mm; Kergplokk 200mm; Lubikrohv 10mm; Siseviimistlus | nõudeid ei esitata | Interior | Non-Load-Bearing Element | 48 dB | 0,4 | 5 065; Kõrgus: 3 650; 3D pikkus: 1 120 | 5 065 | no
SS-01 | 2 korrus | 1.18 IfcWall (sein) (_RKAS BIM + ARCHICAD Classification) | Krohv - Lubjakivi (2), Müüriplokk - Konstuktsioon | Siseviimistlus; Lubikrohv 10mm; Kergplokk 200mm; Lubikrohv 10mm; Siseviimistlus | EI 60 | Interior | Non-Load-Bearing Element | 48 dB | 4,3 | 5 065; Kõrgus: 3 650; 3D pikkus: 6 040 | 5 065 | no
SS-01 | 2 korrus | 1.18 IfcWall (sein) (_RKAS BIM + ARCHICAD Classification) | Krohv - Lubjakivi (2), Müüriplokk - Konstuktsioon | Siseviimistlus; Lubikrohv 10mm; Kergplokk 200mm; Lubikrohv 10mm; Siseviimistlus | nõudeid ei esitata | Interior | Non-Load-Bearing Element | 48 dB | 3,8 | 5 065; Kõrgus: 3 650; 3D pikkus: 4 760 | 5 065 | no
SS-01 | 2 korrus | 1.18 IfcWall (sein) (_RKAS BIM + ARCHICAD Classification) | Krohv - Lubjakivi (2), Müüriplokk - Konstuktsioon | Siseviimistlus; Lubikrohv 10mm; Kergplokk 200mm; Lubikrohv 10mm; Siseviimistlus | nõudeid ei esitata | Interior | Non-Load-Bearing Element | 48 dB | 4,7 | 5 065; Kõrgus: 3 650; 3D pikkus: 5 990 | 5 065 | no
SS-01 | 2 korrus | 1.18 IfcWall (sein) (_RKAS BIM + ARCHICAD Classification) | Krohv - Lubjakivi (2), Müüriplokk - Konstuktsioon | Siseviimistlus; Lubikrohv 10mm; Kergplokk 200mm; Lubikrohv 10mm; Siseviimistlus | nõudeid ei esitata | Interior | Non-Load-Bearing Element | 48 dB | 4,6 | 5 065; Kõrgus: 3 650; 3D pikkus: 5 810 | 5 065 | no
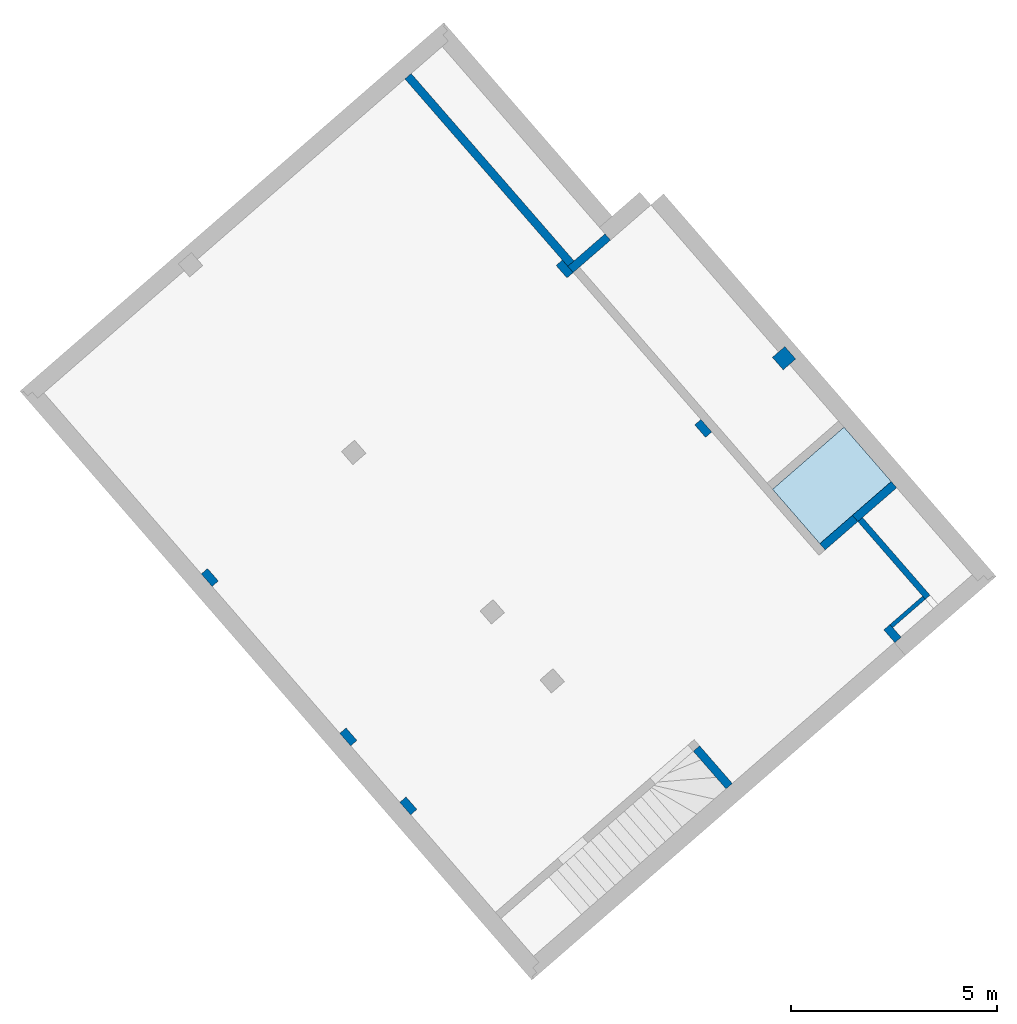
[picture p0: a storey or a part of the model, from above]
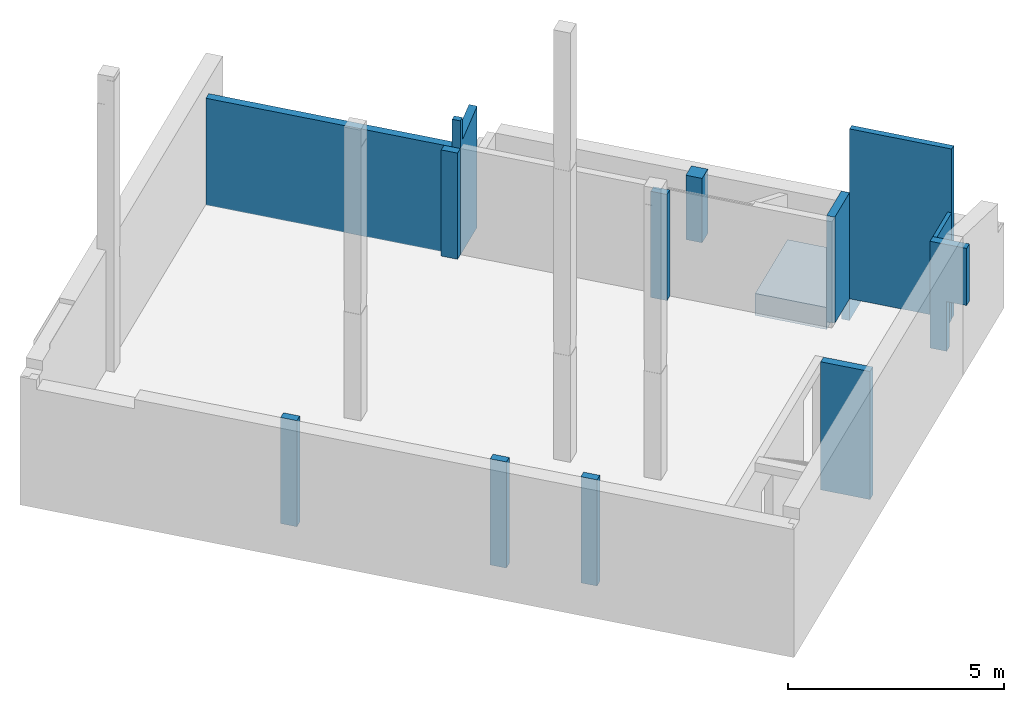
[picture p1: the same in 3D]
Properties of the parts of a building model (IFC2X3), part 10 of 13

# IfcWall: SS-01 (39)
Name | In | Classification | Material | 02 Materjal | 04 Tulepüsivus | 05 Asukoht | 06 Kandevelementide eristatus | 07 Helipidavus | 06 Maht (kubatuur) | 11 Ülemine kõrgusmärk | 12 Alumine kõrgusmärk | LoadBearing = IsExternal
SS-01 | 2 korrus | 0 TELLIJA KULUD (EHITUSKULUDE LIIGITAMINE EVS 885:2005); 1.18 IfcWall (sein) (_RKAS BIM + ARCHICAD Classification) | Krohv - Lubjakivi (3), Müüriplokk - Konstuktsioon | Siseviimistlus; Lubikrohv 10mm; Kergplokk 200mm; Lubikrohv 10mm; Siseviimistlus | nõudeid ei esitata | Undefined | Undefined | 48 dB | 1,8 | 5 065; Kõrgus: 3 650; 3D pikkus: 7 140 | 5 065
SS-01 | 2 korrus | 1.18 IfcWall (sein) (_RKAS BIM + ARCHICAD Classification) | Krohv - Lubjakivi (3), Müüriplokk - Konstuktsioon | Siseviimistlus; Lubikrohv 10mm; Kergplokk 200mm; Lubikrohv 10mm; Siseviimistlus | nõudeid ei esitata | Interior | Non-Load-Bearing Element | 48 dB | 0,4 | 5 065; Kõrgus: 3 650; 3D pikkus: 1 030 | 5 065 | no
SS-01 | 2 korrus | 1.18 IfcWall (sein) (_RKAS BIM + ARCHICAD Classification) | Krohv - Lubjakivi (3), Müüriplokk - Konstuktsioon | Siseviimistlus; Lubikrohv 10mm; Kergplokk 200mm; Lubikrohv 10mm; Siseviimistlus | nõudeid ei esitata | Interior | Non-Load-Bearing Element | 48 dB | 8,1 | 5 065; Kõrgus: 3 650; 3D pikkus: 10 830 | 5 065 | no
SS-01 | 2 korrus | 1.18 IfcWall (sein) (_RKAS BIM + ARCHICAD Classification) | Krohv - Lubjakivi (2), Müüriplokk - Konstuktsioon | Siseviimistlus; Lubikrohv 10mm; Kergplokk 200mm; Lubikrohv 10mm; Siseviimistlus | nõudeid ei esitata | Interior | Non-Load-Bearing Element | 48 dB | 5,9 | 5 065; Kõrgus: 3 650; 3D pikkus: 8 310 | 5 065 | no
SS-01 | 2 korrus | 1.18 IfcWall (sein) (_RKAS BIM + ARCHICAD Classification) | Krohv - Lubjakivi (2), Müüriplokk - Konstuktsioon | Siseviimistlus; Lubikrohv 10mm; Kergplokk 200mm; Lubikrohv 10mm; Siseviimistlus | nõudeid ei esitata | Interior | Non-Load-Bearing Element | 48 dB | 1,0 | 5 065; Kõrgus: 3 650; 3D pikkus: 1 264 | 5 065 | no
SS-01 | 2 korrus | 1.18 IfcWall (sein) (_RKAS BIM + ARCHICAD Classification) | Krohv - Lubjakivi (2), Müüriplokk - Konstuktsioon | Siseviimistlus; Lubikrohv 10mm; Kergplokk 200mm; Lubikrohv 10mm; Siseviimistlus | nõudeid ei esitata | Interior | Non-Load-Bearing Element | 48 dB | 0,9 | 5 065; Kõrgus: 3 650; 3D pikkus: 1 910 | 5 065 | no
SS-01 | 2 korrus | 1.18 IfcWall (sein) (_RKAS BIM + ARCHICAD Classification) | Krohv - Lubjakivi (2), Müüriplokk - Konstuktsioon | Siseviimistlus; Lubikrohv 10mm; Kergplokk 200mm; Lubikrohv 10mm; Siseviimistlus | nõudeid ei esitata | Interior | Non-Load-Bearing Element | 48 dB | 1,1 | 5 065; Kõrgus: 3 650; 3D pikkus: 1 404 | 5 065 | no
SS-01 | 2 korrus | 1.18 IfcWall (sein) (_RKAS BIM + ARCHICAD Classification) | Krohv - Lubjakivi (2), Müüriplokk - Konstuktsioon | Siseviimistlus; Lubikrohv 10mm; Kergplokk 200mm; Lubikrohv 10mm; Siseviimistlus | EI 60 | Interior | Non-Load-Bearing Element | 48 dB | 0,3 | 5 065; Kõrgus: 3 650; 3D pikkus: 1 200 | 5 065 | no
SS-01 | 2 korrus | 1.18 IfcWall (sein) (_RKAS BIM + ARCHICAD Classification) | Krohv - Lubjakivi (2), Müüriplokk - Konstuktsioon | Siseviimistlus; Lubikrohv 10mm; Kergplokk 200mm; Lubikrohv 10mm; Siseviimistlus | EI 60 | Interior | Non-Load-Bearing Element | 48 dB | 0,7 | 5 065; Kõrgus: 3 650; 3D pikkus: 1 420 | 5 065 | no
SS-01 | 2 korrus | 1.18 IfcWall (sein) (_RKAS BIM + ARCHICAD Classification) | Krohv - Lubjakivi (3), Müüriplokk - Konstuktsioon | Siseviimistlus; Lubikrohv 10mm; Kergplokk 200mm; Lubikrohv 10mm; Siseviimistlus | nõudeid ei esitata | Interior | Non-Load-Bearing Element | 48 dB | 15,1 | 5 065; Kõrgus: 3 650; 3D pikkus: 20 320 | 5 065 | no

# IfcWall: SS-02 (15)
Type - ElementType: Element type SS-02
Classification: 1.18 IfcWall (sein) (_RKAS BIM + ARCHICAD Classification)
Arhitektuur - 01 Nimetus: Sisesein; 03 Tähistus: SS-02; 05 Asukoht: Interior; 06 Kandevelementide eristatus: Non-Load-Bearing Element; 08 Soojusläbivus (U-arv): -
Ehituskonstruktsioonid - 03 Tähistus või ristlõige: SS-02
AC_Pset_RenovationAndPhasing - Renovation Status: New
Pset_WallCommon - LoadBearing: no; IsExternal: no
Name | In | Material | 02 Materjal | 04 Tulepüsivus | 07 Helipidavus | 06 Maht (kubatuur) | 11 Ülemine kõrgusmärk | 12 Alumine kõrgusmärk
SS-02 | 0 korrus | Krohv - Lubjakivi, Müüriplokk - Konstuktsioon | Siseviimistlus; Lubikrohv 10mm; Kergplokk 200mm | nõudeid ei esitata | 48 dB | 0,4 | -1 635; Kõrgus: 3 020; 3D pikkus: 610 | -1 635
SS-02 | 0 korrus | Krohv - Lubjakivi, Müüriplokk - Konstuktsioon | Siseviimistlus; Lubikrohv 10mm; Kergplokk 200mm | nõudeid ei esitata | 48dB | 0,3 | -1 635; Kõrgus: 3 020; 3D pikkus: 410 | -1 635
SS-02 | 0 korrus | Müüriplokk - Konstuktsioon, Krohv - Lubjakivi | Siseviimistlus; Lubikrohv 10mm; Kergplokk 200mm | nõudeid ei esitata | 48 dB | 0,3 | -1 635; Kõrgus: 3 020; 3D pikkus: 600 | -1 635
SS-02 | 1,5 korrus | Krohv - Lubjakivi, Müüriplokk - Konstuktsioon | Siseviimistlus; Lubikrohv 10mm; Kergplokk 200mm | EI 60 | 48 dB | 0,3 | 1 650; Kõrgus: 3 150; 3D pikkus: 510 | 1 650
SS-02 | 1,5 korrus | Krohv - Lubjakivi, Müüriplokk - Konstuktsioon | Siseviimistlus; Lubikrohv 10mm; Kergplokk 200mm | EI 60 | 48 dB | 0,7 | 1 650; Kõrgus: 3 150; 3D pikkus: 1 250 | 1 650
SS-02 | 1,5 korrus | Krohv - Lubjakivi, Müüriplokk - Konstuktsioon | Siseviimistlus; Lubikrohv 10mm; Kergplokk 200mm | EI 60 | 48 dB | 0,3 | 1 650; Kõrgus: 3 150; 3D pikkus: 410 | 1 650
SS-02 | 1,5 korrus | Krohv - Lubjakivi, Müüriplokk - Konstuktsioon | Siseviimistlus; Lubikrohv 10mm; Kergplokk 200mm | EI 60 | 48 dB | 0,7 | 1 650; Kõrgus: 3 150; 3D pikkus: 1 020 | 1 650
SS-02 | 2 korrus | Müüriplokk - Konstuktsioon, Krohv - Lubjakivi | Siseviimistlus; Lubikrohv 10mm; Kergplokk 200mm | nõudeid ei esitata | 48dB | 0,3 | 5 065; Kõrgus: 3 650; 3D pikkus: 410 | 5 065
SS-02 | 2 korrus | Müüriplokk - Konstuktsioon, Krohv - Lubjakivi | Siseviimistlus; Lubikrohv 10mm; Kergplokk 200mm | nõudeid ei esitata | 48dB | 0,4 | 5 065; Kõrgus: 3 650; 3D pikkus: 510 | 5 065
SS-02 | 2 korrus | Müüriplokk - Konstuktsioon (2), Krohv - Lubjakivi | Siseviimistlus; Lubikrohv 10mm; Kergplokk 200mm | EI 60 | 48 dB | 2,3 | 5 065; Kõrgus: 3 650; 3D pikkus: 3 167 | 5 065
SS-02 | 2 korrus | Krohv - Lubjakivi, Müüriplokk - Konstuktsioon | Siseviimistlus; Lubikrohv 10mm; Kergplokk 200mm; | nõudeid ei esitata | 48 dB | 0,7 | 5 065; Kõrgus: 3 650; 3D pikkus: 880 | 5 065
SS-02 | 2 korrus | Krohv - Lubjakivi, Müüriplokk - Konstuktsioon | Siseviimistlus; Lubikrohv 10mm; Kergplokk 200mm | EI 60 | 48 dB | 2,6 | 5 065; Kõrgus: 3 650; 3D pikkus: 3 500 | 5 065
SS-02 | 2 korrus | Müüriplokk - Konstuktsioon (2), Krohv - Lubjakivi (2) | Siseviimistlus; Lubikrohv 10mm; Kergplokk 200mm | nõudeid ei esitata | 48 dB | 0,1 | 5 065; Kõrgus: 3 650; 3D pikkus: 220 | 5 065
SS-02 | 2 korrus | Krohv - Lubjakivi, Müüriplokk - Konstuktsioon | Siseviimistlus; Lubikrohv 10mm; Kergplokk 200mm; | nõudeid ei esitata | 49dB | 0,8 | 5 065; Kõrgus: 3 650; 3D pikkus: 1 060 | 5 065
SS-02 | 2 korrus | Müüriplokk - Konstuktsioon, Krohv - Lubjakivi | Siseviimistlus; Lubikrohv 10mm; Kergplokk 200mm; | nõudeid ei esitata | 48 dB | 0,7 | 5 065; Kõrgus: 3 650; 3D pikkus: 1 340 | 5 065

# IfcWall: SS-03
In: 1 korrus
Type - ElementType: Element type SS-03
Classification: 0 TELLIJA KULUD (EHITUSKULUDE LIIGITAMINE EVS 885:2005); 1.18 IfcWall (sein) (_RKAS BIM + ARCHICAD Classification); Material: Müüriplokk - Konstuktsioon
Arhitektuur - 01 Nimetus: Sisesein; 02 Materjal: Kergplokk; 03 Tähistus: SS-03; 04 Tulepüsivus: nõudeid ei esitata; 05 Asukoht: Interior; 06 Kandevelementide eristatus: Load-Bearing Element; 07 Helipidavus: 48dB; 08 Soojusläbivus (U-arv): -
Ehituskonstruktsioonid - 03 Tähistus või ristlõige: SS-03; 06 Maht (kubatuur): 0,3; 11 Ülemine kõrgusmärk: -150; Kõrgus: 2 730; 3D pikkus: 1 610; 12 Alumine kõrgusmärk: -150
AC_Pset_RenovationAndPhasing - Renovation Status: New
Pset_WallCommon - LoadBearing: yes; IsExternal: no

# IfcWall: SS-04 (8)
Type - ElementType: Element type SS-04
Material: Krohv - Lubjakivi (2), Müüriplokk - Konstuktsioon
Arhitektuur - 01 Nimetus: Sisesein; 02 Materjal: Siseviimistlus; Lubikrohv 10mm; Kergplokk 150mm; Lubikrohv 10mm; Siseviimistlus; 03 Tähistus: SS-04; 05 Asukoht: Interior; 06 Kandevelementide eristatus: Non-Load-Bearing Element; 08 Soojusläbivus (U-arv): -
Ehituskonstruktsioonid - 03 Tähistus või ristlõige: SS-04
AC_Pset_RenovationAndPhasing - Renovation Status: New
Pset_WallCommon - LoadBearing: no; IsExternal: no
Name | In | Classification | 04 Tulepüsivus | 07 Helipidavus | 06 Maht (kubatuur) | 11 Ülemine kõrgusmärk | 12 Alumine kõrgusmärk
SS-04 | 0 korrus | 0 TELLIJA KULUD (EHITUSKULUDE LIIGITAMINE EVS 885:2005); 1.18 IfcWall (sein) (_RKAS BIM + ARCHICAD Classification) | nõudeid ei esitata | - | 0,6 | -1 635; Kõrgus: 3 020; 3D pikkus: 1 160 | -1 635
2 x SS-04 | 1,5 korrus | 1.18 IfcWall (sein) (_RKAS BIM + ARCHICAD Classification) | nõudeid ei esitata | 48 dB | 2,2 | 1 650; Kõrgus: 3 150; 3D pikkus: 4 760 | 1 650
SS-04 | 2 korrus | 1.18 IfcWall (sein) (_RKAS BIM + ARCHICAD Classification) | EI 60 | - | 0,3 | 5 065; Kõrgus: 3 650; 3D pikkus: 570 | 5 065
SS-04 | 2 korrus | 1.18 IfcWall (sein) (_RKAS BIM + ARCHICAD Classification) | nõudeid ei esitata | - | 2,1 | 5 065; Kõrgus: 3 650; 3D pikkus: 4 780 | 5 065
SS-04 | 2 korrus | 1.18 IfcWall (sein) (_RKAS BIM + ARCHICAD Classification) | EI 60 | 48 dB | 0,5 | 5 065; Kõrgus: 3 650; 3D pikkus: 880 | 5 065
SS-04 | 2 korrus | 1.18 IfcWall (sein) (_RKAS BIM + ARCHICAD Classification) | EI 60 | - | 1,9 | 5 065; Kõrgus: 3 650; 3D pikkus: 3 190 | 5 065
SS-04 | 2 korrus | 1.18 IfcWall (sein) (_RKAS BIM + ARCHICAD Classification) | nõudeid ei esitata | 48 dB | 1,6 | 5 065; Kõrgus: 3 650; 3D pikkus: 3 030 | 5 065

# IfcWall: SS-05 (16)
Type - ElementType: Element type SS-05
Classification: 1.18 IfcWall (sein) (_RKAS BIM + ARCHICAD Classification)
Arhitektuur - 01 Nimetus: Sisesein; 02 Materjal: Siseviimistlus; Lubikrohv 10mm; Kergplokk 150mm;; 03 Tähistus: SS-05; 05 Asukoht: Interior; 06 Kandevelementide eristatus: Non-Load-Bearing Element; 08 Soojusläbivus (U-arv): -
Ehituskonstruktsioonid - 03 Tähistus või ristlõige: SS-05
AC_Pset_RenovationAndPhasing - Renovation Status: New
Pset_WallCommon - LoadBearing: no; IsExternal: no
Name | In | Material | 04 Tulepüsivus | 07 Helipidavus | 06 Maht (kubatuur) | 11 Ülemine kõrgusmärk | 12 Alumine kõrgusmärk
SS-05 | 1 korrus | Müüriplokk - Konstuktsioon, Krohv - Lubjakivi | EI 60 | - | 1,8 | -150; Kõrgus: 4 950; 3D pikkus: 2 280 | -150
SS-05 | 1 korrus | Krohv - Lubjakivi, Müüriplokk - Konstuktsioon | EI 60 | - | 0,7 | -150; Kõrgus: 4 950; 3D pikkus: 890 | -150
SS-05 | 1 korrus | Krohv - Lubjakivi, Müüriplokk - Konstuktsioon | nõudeid ei esitata | - | 2,2 | -20; Kõrgus: 4 820; 3D pikkus: 2 850 | -20
SS-05 | 1,5 korrus | Krohv - Lubjakivi, Müüriplokk - Konstuktsioon | EI 60 | - | 1,4 | 1 650; Kõrgus: 3 150; 3D pikkus: 2 810 | 1 650
SS-05 | 1,5 korrus | Müüriplokk - Konstuktsioon, Krohv - Lubjakivi | EI 60 | 48 dB | 0,2 | 1 650; Kõrgus: 3 150; 3D pikkus: 620 | 1 650
SS-05 | 2 korrus | Krohv - Lubjakivi, Müüriplokk - Konstuktsioon | EI 60 | - | 1,6 | 5 065; Kõrgus: 3 650; 3D pikkus: 2 810 | 5 065
SS-05 | 2 korrus | Müüriplokk - Konstuktsioon, Krohv - Lubjakivi | EI 60 | - | 0,5 | 5 065; Kõrgus: 3 650; 3D pikkus: 870 | 5 065
SS-05 | 2 korrus | Müüriplokk - Konstuktsioon, Krohv - Lubjakivi | EI 60 | - | 0,6 | 5 065; Kõrgus: 3 650; 3D pikkus: 1 000 | 5 065
SS-05 | 2 korrus | Krohv - Lubjakivi, Müüriplokk - Konstuktsioon | nõudeid ei esitata | 48 dB | 0,7 | 5 065; Kõrgus: 3 650; 3D pikkus: 1 160 | 5 065
SS-05 | 2 korrus | Krohv - Lubjakivi, Müüriplokk - Konstuktsioon | nõudeid ei esitata | - | 0,5 | 5 065; Kõrgus: 3 650; 3D pikkus: 1 020 | 5 065
SS-05 | 2 korrus | Krohv - Lubjakivi, Müüriplokk - Konstuktsioon | nõudeid ei esitata | 48dB | 0,6 | 5 065; Kõrgus: 3 650; 3D pikkus: 1 210 | 5 065
SS-05 | 2 korrus | Krohv - Lubjakivi (2), Müüriplokk - Konstuktsioon | nõudeid ei esitata | - | 0,6 | 5 065; Kõrgus: 3 650; 3D pikkus: 1 060 | 5 065
SS-05 | 2 korrus | Müüriplokk - Konstuktsioon, Krohv - Lubjakivi | nõudeid ei esitata | 48dB | 0,7 | 5 065; Kõrgus: 3 650; 3D pikkus: 1 460 | 5 065
SS-05 | 2 korrus | Krohv - Lubjakivi, Müüriplokk - Konstuktsioon | nõudeid ei esitata | 48dB | 0,5 | 5 065; Kõrgus: 3 650; 3D pikkus: 1 160 | 5 065
SS-05 | 2 korrus | Müüriplokk - Konstuktsioon, Krohv - Lubjakivi (2) | EI 60 | 48dB | 0,6 | 5 065; Kõrgus: 3 650; 3D pikkus: 1 060 | 5 065
SS-05 | 2 korrus | Müüriplokk - Konstuktsioon, Krohv - Lubjakivi | nõudeid ei esitata | 48 dB | 0,7 | 5 065; Kõrgus: 3 650; 3D pikkus: 1 190 | 5 065

# IfcWall: SS-06 (4)
Type - ElementType: Element type SS-06
Classification: 1.18 IfcWall (sein) (_RKAS BIM + ARCHICAD Classification)
Arhitektuur - 01 Nimetus: Sisesein; 03 Tähistus: SS-06; 05 Asukoht: Interior; 06 Kandevelementide eristatus: Non-Load-Bearing Element; 08 Soojusläbivus (U-arv): -
Ehituskonstruktsioonid - 03 Tähistus või ristlõige: SS-06
AC_Pset_RenovationAndPhasing - Renovation Status: New
Pset_WallCommon - LoadBearing: no; IsExternal: no
Name | In | Material | 02 Materjal | 04 Tulepüsivus | 07 Helipidavus | 06 Maht (kubatuur) | 11 Ülemine kõrgusmärk | 12 Alumine kõrgusmärk
SS-06 | -1 korrus | Müüriplokk - Konstuktsioon | Kergplokk 150mm; | EI 60 | - | 1,8 | -3 415; Kõrgus: 4 800; 3D pikkus: 2 500 | -3 415
SS-06 | 0 korrus | Müüriplokk - Konstuktsioon | Kergplokk150mm | EI 60 | - | 0,2 | -3 435; Kõrgus: 4 820; 3D pikkus: 400 | -3 435
SS-06 | 2 korrus | Müüriplokk - Konstuktsioon (2) | Kergplokk 150mm | EI 60 | 48dB | 1,2 | 5 065; Kõrgus: 3 650; 3D pikkus: 2 318 | 5 065
SS-06 | 2 korrus | Müüriplokk - Konstuktsioon | Kergplokk 150mm | nõudeid ei esitata | - | 0,2 | 5 065; Kõrgus: 3 650; 3D pikkus: 360 | 5 065

# IfcWall: SS-07 (45)
Type - ElementType: Element type SS-07
Classification: 1.18 IfcWall (sein) (_RKAS BIM + ARCHICAD Classification)
Arhitektuur - 01 Nimetus: Sisesein; 03 Tähistus: SS-07; 05 Asukoht: Interior; 06 Kandevelementide eristatus: Non-Load-Bearing Element; 08 Soojusläbivus (U-arv): -
Ehituskonstruktsioonid - 03 Tähistus või ristlõige: SS-07
AC_Pset_RenovationAndPhasing - Renovation Status: New
Pset_WallCommon - LoadBearing: no; IsExternal: no
Name | In | Material | 02 Materjal | 04 Tulepüsivus | 07 Helipidavus | 06 Maht (kubatuur) | 11 Ülemine kõrgusmärk | 12 Alumine kõrgusmärk
SS-07 | 1 korrus | Krohv - Lubjakivi (2), Müüriplokk - Konstuktsioon | Siseviimistlus; Lubikrohv 10mm; Kergplokk 100mm; Lubikrohv 10mm; Siseviimistlus | nõudeid ei esitata | - | 0,1 | -620; Kõrgus: 2 673; 3D pikkus: 244 | -620
SS-07 | 1 korrus | Krohv - Lubjakivi (2), Müüriplokk - Konstuktsioon | Siseviimistlus; Lubikrohv 10mm; Kergplokk 100mm; Lubikrohv 10mm; Siseviimistlus | nõudeid ei esitata | 48dB | 0,1 | -620; Kõrgus: 2 673; 3D pikkus: 990 | -620
SS-07 | 1 korrus | Krohv - Lubjakivi (7), Müüriplokk - Konstuktsioon (2) | Siseviimistlus; Lubikrohv 10mm; Kergplokk 100mm; Lubikrohv 10mm; Siseviimistlus | nõudeid ei esitata | 48dB | 1,6 | -620; Kõrgus: 3 520; 3D pikkus: 6 820 | -620
SS-07 | 1 korrus | Krohv - Lubjakivi (2), Müüriplokk - Konstuktsioon | Siseviimistlus; Lubikrohv 10mm; Kergplokk 100mm; Lubikrohv 10mm; Siseviimistlus | nõudeid ei esitata | - | 0,5 | -620; Kõrgus: 3 520; 3D pikkus: 1 620 | -620
SS-08 | 1 korrus | Müüriplokk - Konstuktsioon, Krohv - Lubjakivi | Siseviimistlus; Lubikrohv 10mm; Kergplokk 100mm; | nõudeid ei esitata | - | 0,1 | -620; Kõrgus: 2 673; 3D pikkus: 186 | -620
SS-07 | 1 korrus | Krohv - Lubjakivi (5), Müüriplokk - Konstuktsioon | Siseviimistlus; Lubikrohv 10mm; Kergplokk 100mm; Lubikrohv 10mm; Siseviimistlus | nõudeid ei esitata | - | 1,1 | -620; Kõrgus: 2 673; 3D pikkus: 4 580 | -620
SS-07 | 1 korrus | Krohv - Lubjakivi (6), Müüriplokk - Konstuktsioon (3) | Siseviimistlus; Lubikrohv 10mm; Kergplokk 100mm; Lubikrohv 10mm; Siseviimistlus | nõudeid ei esitata | 48dB | 0,6 | -620; Kõrgus: 3 272; 3D pikkus: 1 464 | -620
SS-07 | 1 korrus | Krohv - Lubjakivi (7), Müüriplokk - Konstuktsioon (3) | Siseviimistlus; Lubikrohv 10mm; Kergplokk 100mm; Lubikrohv 10mm; Siseviimistlus | nõudeid ei esitata | 48dB | 0,6 | -620; Kõrgus: 3 520; 3D pikkus: 1 564 | -620
SS-07 | 1 korrus | Krohv - Lubjakivi (2), Müüriplokk - Konstuktsioon | Siseviimistlus; Lubikrohv 10mm; Kergplokk 100mm; Lubikrohv 10mm; Siseviimistlus | nõudeid ei esitata | 48dB | 0,5 | -620; Kõrgus: 2 947; 3D pikkus: 1 434 | -620
SS-07 | 1 korrus | Krohv - Lubjakivi (2), Müüriplokk - Konstuktsioon | Siseviimistlus; Lubikrohv 10mm; Kergplokk 100mm; Lubikrohv 10mm; Siseviimistlus | nõudeid ei esitata | 48dB | 0,5 | -620; Kõrgus: 2 673; 3D pikkus: 1 620 | -620
SS-07 | 1 korrus | Krohv - Lubjakivi (6), Müüriplokk - Konstuktsioon (3) | Siseviimistlus; Lubikrohv 10mm; Kergplokk 100mm; Lubikrohv 10mm; Siseviimistlus | nõudeid ei esitata | 48dB | 0,5 | -620; Kõrgus: 2 973; 3D pikkus: 1 464 | -620
SS-07 | 1 korrus | Krohv - Lubjakivi (2), Müüriplokk - Konstuktsioon | Siseviimistlus; Lubikrohv 10mm; Kergplokk 100mm; Lubikrohv 10mm; Siseviimistlus | nõudeid ei esitata | 48dB | 0,6 | -620; Kõrgus: 2 670; 3D pikkus: 2 210 | -620
SS-07 | 1 korrus | Krohv - Lubjakivi (4), Müüriplokk - Konstuktsioon (2) | Siseviimistlus; Lubikrohv 10mm; Kergplokk 100mm; Lubikrohv 10mm; Siseviimistlus | nõudeid ei esitata | 48dB | 0,6 | -620; Kõrgus: 3 520; 3D pikkus: 1 354 | -620
SS-07 | 1 korrus | Krohv - Lubjakivi (2), Müüriplokk - Konstuktsioon | Siseviimistlus; Lubikrohv 10mm; Kergplokk 100mm; Lubikrohv 10mm; Siseviimistlus | nõudeid ei esitata | - | 0,6 | -620; Kõrgus: 3 395; 3D pikkus: 1 590 | -620
SS-07 | 1 korrus | Krohv - Lubjakivi (2), Müüriplokk - Konstuktsioon | Siseviimistlus; Lubikrohv 10mm; Kergplokk 100mm; Lubikrohv 10mm; Siseviimistlus | nõudeid ei esitata | 48dB | 0,5 | -620; Kõrgus: 3 494; 3D pikkus: 1 234 | -620
SS-07 | 1 korrus | Krohv - Lubjakivi (2), Müüriplokk - Konstuktsioon | Siseviimistlus; Lubikrohv 10mm; Kergplokk 100mm; Lubikrohv 10mm; Siseviimistlus | nõudeid ei esitata | 48dB | 0,6 | -620; Kõrgus: 2 673; 3D pikkus: 2 210 | -620
SS-07 | 1 korrus | Krohv - Lubjakivi (3), Müüriplokk - Konstuktsioon | Siseviimistlus; Lubikrohv 10mm; Kergplokk 100mm; Lubikrohv 10mm; Siseviimistlus | nõudeid ei esitata | - | 0,4 | -620; Kõrgus: 2 673; 3D pikkus: 2 010 | -620
SS-07 | 1 korrus | Krohv - Lubjakivi (2), Müüriplokk - Konstuktsioon | Siseviimistlus; Lubikrohv 10mm; Kergplokk 100mm; Lubikrohv 10mm; Siseviimistlus | nõudeid ei esitata | - | 1,5 | -620; Kõrgus: 2 673; 3D pikkus: 5 675 | -620
SS-07 | 1 korrus | Krohv - Lubjakivi (2), Müüriplokk - Konstuktsioon | Siseviimistlus; Lubikrohv 10mm; Kergplokk 100mm; Lubikrohv 10mm; Siseviimistlus | nõudeid ei esitata | 48dB | 0,4 | -620; Kõrgus: 3 199; 3D pikkus: 1 620 | -620
SS-07 | 1 korrus | Krohv - Lubjakivi (2), Müüriplokk - Konstuktsioon | Siseviimistlus; Lubikrohv 10mm; Kergplokk 100mm; Lubikrohv 10mm; Siseviimistlus | nõudeid ei esitata | 48dB | 0,5 | -620; Kõrgus: 3 220; 3D pikkus: 1 434 | -620
SS-07 | 1 korrus | Krohv - Lubjakivi (2), Müüriplokk - Konstuktsioon | Siseviimistlus; Lubikrohv 10mm; Kergplokk 100mm; Lubikrohv 10mm; Siseviimistlus | nõudeid ei esitata | - | 0,1 | -620; Kõrgus: 2 642; 3D pikkus: 930 | -620
SS-07 | 1 korrus | Krohv - Lubjakivi (3), Müüriplokk - Konstuktsioon | Siseviimistlus; Lubikrohv 10mm; Kergplokk 100mm; Lubikrohv 10mm; Siseviimistlus | nõudeid ei esitata | - | 0,6 | -620; Kõrgus: 2 920; 3D pikkus: 3 000 | -620
SS-07 | 1 korrus | Krohv - Lubjakivi (2), Müüriplokk - Konstuktsioon | Siseviimistlus; Lubikrohv 10mm; Kergplokk 100mm; Lubikrohv 10mm; Siseviimistlus | nõudeid ei esitata | - | 0,2 | -620; Kõrgus: 3 520; 3D pikkus: 1 040 | -620
SS-07 | 1 korrus | Krohv - Lubjakivi (5), Müüriplokk - Konstuktsioon | Siseviimistlus; Lubikrohv 10mm; Kergplokk 100mm; Lubikrohv 10mm; Siseviimistlus | nõudeid ei esitata | 48dB | 0,8 | -620; Kõrgus: 3 520; 3D pikkus: 4 200 | -620
SS-07 | 1,5 korrus | Krohv - Lubjakivi (2), Müüriplokk - Konstuktsioon | Siseviimistlus; Lubikrohv 10mm; Kergplokk 100mm; Lubikrohv 10mm; Siseviimistlus | nõudeid ei esitata | 48 dB | 1,1 | 1 650; Kõrgus: 3 150; 3D pikkus: 2 980 | 1 650
SS-07 | 1,5 korrus | Krohv - Lubjakivi (3), Müüriplokk - Konstuktsioon | Siseviimistlus; Lubikrohv 10mm; Kergplokk 100mm; Lubikrohv 10mm; Siseviimistlus | nõudeid ei esitata | - | 0,2 | 2 500; Kõrgus: 2 300; 3D pikkus: 1 940 | 2 500
SS-07 | 1,5 korrus | Krohv - Lubjakivi (3), Müüriplokk - Konstuktsioon | Siseviimistlus; Lubikrohv 10mm; Kergplokk 100mm; Lubikrohv 10mm; Siseviimistlus | nõudeid ei esitata | - | 1,1 | 2 300; Kõrgus: 2 500; 3D pikkus: 4 800 | 2 300
SS-07 | 1,5 korrus | Krohv - Lubjakivi (2), Müüriplokk - Konstuktsioon | Siseviimistlus; Lubikrohv 10mm; Kergplokk 100mm; Lubikrohv 10mm; Siseviimistlus | nõudeid ei esitata | - | 1,4 | 2 300; Kõrgus: 2 500; 3D pikkus: 4 990 | 2 300
SS-07 | 1,5 korrus | Krohv - Lubjakivi (2), Müüriplokk - Konstuktsioon | Siseviimistlus; Lubikrohv 10mm; Kergplokk 100mm; Lubikrohv 10mm; Siseviimistlus | nõudeid ei esitata | - | 1,2 | 2 300; Kõrgus: 2 500; 3D pikkus: 5 000 | 2 300
SS-07 | 1,5 korrus | Krohv - Lubjakivi (2), Müüriplokk - Konstuktsioon | Siseviimistlus; Lubikrohv 10mm; Kergplokk 100mm; Lubikrohv 10mm; Siseviimistlus | EI 60 | 48 dB | 0,4 | 1 650; Kõrgus: 3 150; 3D pikkus: 1 050 | 1 650
SS-07 | 1,5 korrus | Krohv - Lubjakivi (3), Müüriplokk - Konstuktsioon | Siseviimistlus; Lubikrohv 10mm; Kergplokk 100mm; Lubikrohv 10mm; Siseviimistlus | EI 60 | 48 dB | 0,4 | 1 650; Kõrgus: 3 150; 3D pikkus: 1 060 | 1 650
SS-07 | 1,5 korrus | Krohv - Lubjakivi (2), Müüriplokk - Konstuktsioon | Siseviimistlus; Lubikrohv 10mm; Kergplokk 100mm; Lubikrohv 10mm; Siseviimistlus | nõudeid ei esitata | - | 0,4 | 4 300; Kõrgus: 500; 3D pikkus: 5 980 | 4 300
SS-07 | 1,5 korrus | Krohv - Lubjakivi (2), Müüriplokk - Konstuktsioon | Siseviimistlus; Lubikrohv 10mm; Kergplokk 100mm; Lubikrohv 10mm; Siseviimistlus | nõudeid ei esitata | - | 0,6 | 2 300; Kõrgus: 2 500; 3D pikkus: 2 130 | 2 300
SS-07 | 1,5 korrus | Krohv - Lubjakivi (2), Müüriplokk - Konstuktsioon | Siseviimistlus; Lubikrohv 10mm; Kergplokk 100mm; Lubikrohv 10mm; Siseviimistlus | nõudeid ei esitata | - | 0,5 | 2 300; Kõrgus: 2 500; 3D pikkus: 2 040 | 2 300
SS-07 | 1,5 korrus | Krohv - Lubjakivi (2), Müüriplokk - Konstuktsioon | Siseviimistlus; Lubikrohv 10mm; Kergplokk 100mm; Lubikrohv 10mm; Siseviimistlus | nõudeid ei esitata | - | 0,4 | 2 500; Kõrgus: 2 300; 3D pikkus: 1 520 | 2 500
2 x SS-07 | 1,5 korrus | Krohv - Lubjakivi (2), Müüriplokk - Konstuktsioon | Siseviimistlus; Lubikrohv 10mm; Kergplokk 100mm; Lubikrohv 10mm; Siseviimistlus | nõudeid ei esitata | - | 0,1 | 1 650; Kõrgus: 3 150; 3D pikkus: 360 | 1 650
SS-07 | 1,5 korrus | Krohv - Lubjakivi (2), Müüriplokk - Konstuktsioon | Siseviimistlus; Lubikrohv 10mm; Kergplokk 100mm; Lubikrohv 10mm; Siseviimistlus | nõudeid ei esitata | 48 dB | 0,2 | 1 650; Kõrgus: 3 150; 3D pikkus: 690 | 1 650
SS-07 | 2 korrus | Krohv - Lubjakivi (5), Müüriplokk - Konstuktsioon | Siseviimistlus; Lubikrohv 10mm; Kergplokk100mm; Lubikrohv 10mm; Siseviimistlus | nõudeid ei esitata | 48dB | 1,3 | 5 065; Kõrgus: 3 650; 3D pikkus: 4 970 | 5 065
SS-07 | 2 korrus | Krohv - Lubjakivi (3), Müüriplokk - Konstuktsioon | Siseviimistlus; Lubikrohv 10mm; Kergplokk100mm; Lubikrohv 10mm; Siseviimistlus | nõudeid ei esitata | 48dB | 1,1 | 5 065; Kõrgus: 3 650; 3D pikkus: 3 685 | 5 065
SS-07 | 2 korrus | Krohv - Lubjakivi (2), Müüriplokk - Konstuktsioon | Siseviimistlus; Lubikrohv 10mm; Kergplokk100mm; Lubikrohv 10mm; Siseviimistlus | nõudeid ei esitata | 48dB | 0,2 | 5 065; Kõrgus: 3 650; 3D pikkus: 501 | 5 065
2 x SS-07 | 2 korrus | Krohv - Lubjakivi (2), Müüriplokk - Konstuktsioon | Siseviimistlus; Lubikrohv 10mm; Kergplokk100mm; Lubikrohv 10mm; Siseviimistlus | nõudeid ei esitata | 48dB | 0,5 | 5 065; Kõrgus: 3 650; 3D pikkus: 1 164 | 5 065
SS-07 | 2 korrus | Krohv - Lubjakivi (2), Müüriplokk - Konstuktsioon | Siseviimistlus; Lubikrohv 10mm; Kergplokk100mm; Lubikrohv 10mm; Siseviimistlus | nõudeid ei esitata | 48dB | 0,6 | 5 065; Kõrgus: 3 650; 3D pikkus: 1 370 | 5 065
SS-07 | 2 korrus | Krohv - Lubjakivi (2), Müüriplokk - Konstuktsioon | Siseviimistlus; Lubikrohv 10mm; Kergplokk100mm; Lubikrohv 10mm; Siseviimistlus | nõudeid ei esitata | 48dB | 0,5 | 5 065; Kõrgus: 3 650; 3D pikkus: 1 230 | 5 065

# IfcWall: SS-08 (47)
Type - ElementType: Element type SS-08
Arhitektuur - 01 Nimetus: Sisesein; 03 Tähistus: SS-08; 05 Asukoht: Interior; 06 Kandevelementide eristatus: Non-Load-Bearing Element; 08 Soojusläbivus (U-arv): -
Ehituskonstruktsioonid - 03 Tähistus või ristlõige: SS-08
AC_Pset_RenovationAndPhasing - Renovation Status: New
Pset_WallCommon - LoadBearing: no; IsExternal: no
Name | In | Classification | Material | 02 Materjal | 04 Tulepüsivus | 07 Helipidavus | 06 Maht (kubatuur) | 11 Ülemine kõrgusmärk | 12 Alumine kõrgusmärk
2 x SS-08 | 0 korrus | 1.18 IfcWall (sein) (_RKAS BIM + ARCHICAD Classification) | Krohv - Lubjakivi, Müüriplokk - Konstuktsioon | Siseviimistlus; Lubikrohv 10mm; Kergplokk100mm | nõudeid ei esitata | 48dB | 0,1 | -1 635; Kõrgus: 3 020; 3D pikkus: 400 | -1 635
SS-08 | 0 korrus | 1.18 IfcWall (sein) (_RKAS BIM + ARCHICAD Classification) | Müüriplokk - Konstuktsioon, Krohv - Lubjakivi | Siseviimistlus; Lubikrohv 10mm; Kergplokk100mm | nõudeid ei esitata | 48dB | 0,1 | -1 635; Kõrgus: 3 020; 3D pikkus: 400 | -1 635
SS-08 | 0 korrus | 1.18 IfcWall (sein) (_RKAS BIM + ARCHICAD Classification) | Krohv - Lubjakivi, Müüriplokk - Konstuktsioon | Siseviimistlus; Lubikrohv 10mm; Kergplokk 100mm | nõudeid ei esitata | 48dB | 0,3 | -1 635; Kõrgus: 3 020; 3D pikkus: 1 000 | -1 635
SS-08 | 0 korrus | 1.18 IfcWall (sein) (_RKAS BIM + ARCHICAD Classification) | Krohv - Lubjakivi, Müüriplokk - Konstuktsioon | Siseviimistlus; Lubikrohv 10mm; Kergplokk 100mm | nõudeid ei esitata | 48dB | 0,2 | -1 635; Kõrgus: 3 020; 3D pikkus: 590 | -1 635
SS-08 | 0 korrus | 1.18 IfcWall (sein) (_RKAS BIM + ARCHICAD Classification) | Krohv - Lubjakivi, Müüriplokk - Konstuktsioon | Siseviimistlus; Lubikrohv 10mm; Kergplokk100mm | nõudeid ei esitata | 48dB | 0,5 | -1 635; Kõrgus: 3 020; 3D pikkus: 1 400 | -1 635
SS-08 | 0 korrus | 1.18 IfcWall (sein) (_RKAS BIM + ARCHICAD Classification) | Krohv - Lubjakivi, Müüriplokk - Konstuktsioon | Siseviimistlus; Lubikrohv 10mm; Kergplokk 100mm | nõudeid ei esitata | 48dB | 0,1 | -1 635; Kõrgus: 3 020; 3D pikkus: 410 | -1 635
SS-08 | 0 korrus | 1.18 IfcWall (sein) (_RKAS BIM + ARCHICAD Classification) | Krohv - Lubjakivi, Müüriplokk - Konstuktsioon | Siseviimistlus; Lubikrohv 10mm; Kergplokk 100mm | nõudeid ei esitata | 48dB | 0,1 | -1 635; Kõrgus: 3 020; 3D pikkus: 600 | -1 635
SS-08 | 0 korrus | 1.18 IfcWall (sein) (_RKAS BIM + ARCHICAD Classification) | Krohv - Lubjakivi, Müüriplokk - Konstuktsioon | Siseviimistlus; Lubikrohv 10mm; Kergplokk 100mm | nõudeid ei esitata | 48dB | 0,5 | -1 635; Kõrgus: 3 020; 3D pikkus: 1 590 | -1 635
SS-08 | 1 korrus | 1.18 IfcWall (sein) (_RKAS BIM + ARCHICAD Classification) | Müüriplokk - Konstuktsioon, Krohv - Lubjakivi | Siseviimistlus; Lubikrohv 10mm; Kergplokk 100mm; | nõudeid ei esitata | - | 0,4 | -620; Kõrgus: 3 520; 3D pikkus: 950 | -620
SS-08 | 1 korrus | 1.18 IfcWall (sein) (_RKAS BIM + ARCHICAD Classification) | Müüriplokk - Konstuktsioon, Krohv - Lubjakivi | Siseviimistlus; Lubikrohv 10mm; Kergplokk 100mm; | nõudeid ei esitata | 48dB | 0,5 | -620; Kõrgus: 3 520; 3D pikkus: 1 234 | -620
SS-08 | 1 korrus | 1.18 IfcWall (sein) (_RKAS BIM + ARCHICAD Classification) | Krohv - Lubjakivi, Müüriplokk - Konstuktsioon | Siseviimistlus; Lubikrohv 10mm; Kergplokk 100mm; | nõudeid ei esitata | 48dB | 0,5 | -620; Kõrgus: 3 520; 3D pikkus: 1 434 | -620
SS-08 | 1 korrus | 1.18 IfcWall (sein) (_RKAS BIM + ARCHICAD Classification) | Müüriplokk - Konstuktsioon, Krohv - Lubjakivi | Siseviimistlus; Lubikrohv 10mm; Kergplokk 100mm | nõudeid ei esitata | - | 0,1 | -20; Kõrgus: 2 370; 3D pikkus: 510 | -20
SS-08 | 1 korrus | 0 TELLIJA KULUD (EHITUSKULUDE LIIGITAMINE EVS 885:2005); 1.18 IfcWall (sein) (_RKAS BIM + ARCHICAD Classification) | Krohv - Lubjakivi, Müüriplokk - Konstuktsioon | Kergplokk | nõudeid ei esitata | - | 0,2 | -415; Kõrgus: 1 800; 3D pikkus: 1 050 | -415
SS-08 | 1 korrus | 1.18 IfcWall (sein) (_RKAS BIM + ARCHICAD Classification) | Krohv - Lubjakivi, Müüriplokk - Konstuktsioon | Siseviimistlus; Lubikrohv 10mm; Kergplokk 100mm | nõudeid ei esitata | - | 0,3 | -20; Kõrgus: 2 370; 3D pikkus: 1 290 | -20
SS-08 | 1 korrus | 1.18 IfcWall (sein) (_RKAS BIM + ARCHICAD Classification) | Krohv - Lubjakivi, Müüriplokk - Konstuktsioon | Siseviimistlus; Lubikrohv 10mm; Kergplokk 100mm; Lubikrohv 10mm; Siseviimistlus | nõudeid ei esitata | - | 0,1 | -620; Kõrgus: 2 500; 3D pikkus: 320 | -620
SS-08 | 1 korrus | 1.18 IfcWall (sein) (_RKAS BIM + ARCHICAD Classification) | Müüriplokk - Konstuktsioon, Krohv - Lubjakivi | Siseviimistlus; Lubikrohv 10mm; Kergplokk 100mm; | nõudeid ei esitata | 48dB | 0,0 | -620; Kõrgus: 3 494; 3D pikkus: 110 | -620
SS-08 | 1,5 korrus | 1.18 IfcWall (sein) (_RKAS BIM + ARCHICAD Classification) | Krohv - Lubjakivi, Müüriplokk - Konstuktsioon | Siseviimistlus; Lubikrohv 10mm; Kergplokk100mm | nõudeid ei esitata | 48dB | 0,1 | 1 650; Kõrgus: 3 150; 3D pikkus: 400 | 1 650
SS-08 | 1,5 korrus | 1.18 IfcWall (sein) (_RKAS BIM + ARCHICAD Classification) | Krohv - Lubjakivi, Müüriplokk - Konstuktsioon | Siseviimistlus; Lubikrohv 10mm; Kergplokk100mm | EI 60 | 48dB | 0,1 | 1 650; Kõrgus: 3 150; 3D pikkus: 450 | 1 650
2 x SS-08 | 1,5 korrus | 1.18 IfcWall (sein) (_RKAS BIM + ARCHICAD Classification) | Krohv - Lubjakivi, Müüriplokk - Konstuktsioon | Siseviimistlus; Lubikrohv 10mm; Kergplokk100mm | EI 60 | 48dB | 0,1 | 1 650; Kõrgus: 3 150; 3D pikkus: 410 | 1 650
SS-08 | 1,5 korrus | 1.18 IfcWall (sein) (_RKAS BIM + ARCHICAD Classification) | Müüriplokk - Konstuktsioon, Krohv - Lubjakivi | Siseviimistlus; Lubikrohv 10mm; Kergplokk 100mm | nõudeid ei esitata | - | 0,1 | 2 480; Kõrgus: 2 320; 3D pikkus: 500 | 2 480
SS-08 | 1,5 korrus | 1.18 IfcWall (sein) (_RKAS BIM + ARCHICAD Classification) | Krohv - Lubjakivi, Müüriplokk - Konstuktsioon | Siseviimistlus; Lubikrohv 10mm; Kergplokk100mm | EI 60 | 48dB | 0,4 | 1 650; Kõrgus: 3 565; 3D pikkus: 1 390 | 1 650
SS-08 | 1,5 korrus | 1.18 IfcWall (sein) (_RKAS BIM + ARCHICAD Classification) | Krohv - Lubjakivi, Müüriplokk - Konstuktsioon | Siseviimistlus; Lubikrohv 10mm; Kergplokk100mm | EI 60 | 48dB | 0,3 | 1 650; Kõrgus: 3 150; 3D pikkus: 1 000 | 1 650
SS-08 | 1,5 korrus | 1.18 IfcWall (sein) (_RKAS BIM + ARCHICAD Classification) | Krohv - Lubjakivi, Müüriplokk - Konstuktsioon | Siseviimistlus; Lubikrohv 10mm; Kergplokk 100mm | nõudeid ei esitata | - | 0,3 | 2 500; Kõrgus: 2 300; 3D pikkus: 1 300 | 2 500
SS-08 | 1,5 korrus | 1.18 IfcWall (sein) (_RKAS BIM + ARCHICAD Classification) | Krohv - Lubjakivi, Müüriplokk - Konstuktsioon | Siseviimistlus; Lubikrohv 10mm; Kergplokk100mm | EI 60 | 48dB | 0,5 | 1 650; Kõrgus: 3 150; 3D pikkus: 1 390 | 1 650
SS-08 | 1,5 korrus | 1.18 IfcWall (sein) (_RKAS BIM + ARCHICAD Classification) | Krohv - Lubjakivi, Müüriplokk - Konstuktsioon | Siseviimistlus; Lubikrohv 10mm; Kergplokk 100mm | EI 60 | 48 dB | 0,3 | 1 650; Kõrgus: 3 150; 3D pikkus: 1 050 | 1 650
SS-08 | 1,5 korrus | 1.18 IfcWall (sein) (_RKAS BIM + ARCHICAD Classification) | Müüriplokk - Konstuktsioon, Krohv - Lubjakivi | Siseviimistlus; Lubikrohv 10mm; Kergplokk100mm | EI 60 | 48dB | 0,1 | 1 780; Kõrgus: 3 020; 3D pikkus: 400 | 1 780
2 x SS-08 | 1,5 korrus | 1.18 IfcWall (sein) (_RKAS BIM + ARCHICAD Classification) | Müüriplokk - Konstuktsioon, Krohv - Lubjakivi | Siseviimistlus; Lubikrohv 10mm; Kergplokk100mm | EI 60 | 48dB | 0,1 | 1 650; Kõrgus: 3 150; 3D pikkus: 410 | 1 650
SS-08 | 2 korrus | 1.18 IfcWall (sein) (_RKAS BIM + ARCHICAD Classification) | Krohv - Lubjakivi, Müüriplokk - Konstuktsioon | Siseviimistlus; Lubikrohv 10mm; Kergplokk100mm | nõudeid ei esitata | 48dB | 0,1 | 5 065; Kõrgus: 3 650; 3D pikkus: 450 | 5 065
2 x SS-08 | 2 korrus | 1.18 IfcWall (sein) (_RKAS BIM + ARCHICAD Classification) | Krohv - Lubjakivi, Müüriplokk - Konstuktsioon | Siseviimistlus; Lubikrohv 10mm; Kergplokk100mm | nõudeid ei esitata | 48dB | 0,1 | 5 065; Kõrgus: 3 650; 3D pikkus: 400 | 5 065
SS-08 | 2 korrus | 1.18 IfcWall (sein) (_RKAS BIM + ARCHICAD Classification) | Müüriplokk - Konstuktsioon, Krohv - Lubjakivi | Siseviimistlus; Lubikrohv 10mm; Kergplokk100mm | EI 60 | 48dB | 0,1 | 5 065; Kõrgus: 3 650; 3D pikkus: 400 | 5 065
SS-08 | 2 korrus | 1.18 IfcWall (sein) (_RKAS BIM + ARCHICAD Classification) | Krohv - Lubjakivi, Müüriplokk - Konstuktsioon | Siseviimistlus; Lubikrohv 10mm; Kergplokk100mm | nõudeid ei esitata | 48dB | 0,5 | 5 065; Kõrgus: 3 650; 3D pikkus: 1 400 | 5 065
SS-08 | 2 korrus | 1.18 IfcWall (sein) (_RKAS BIM + ARCHICAD Classification) | Krohv - Lubjakivi, Müüriplokk - Konstuktsioon | Siseviimistlus; Lubikrohv 10mm; Kergplokk100mm | EI 60 | 48dB | 0,1 | 5 065; Kõrgus: 3 650; 3D pikkus: 400 | 5 065
SS-08 | 2 korrus | 1.18 IfcWall (sein) (_RKAS BIM + ARCHICAD Classification) | Krohv - Lubjakivi, Müüriplokk - Konstuktsioon | Siseviimistlus; Lubikrohv 10mm; Kergplokk100mm | nõudeid ei esitata | 48dB | 0,5 | 5 065; Kõrgus: 3 650; 3D pikkus: 1 290 | 5 065
3 x SS-08 | 2 korrus | 1.18 IfcWall (sein) (_RKAS BIM + ARCHICAD Classification) | Krohv - Lubjakivi, Müüriplokk - Konstuktsioon | Siseviimistlus; Lubikrohv 10mm; Kergplokk100mm | nõudeid ei esitata | 48dB | 0,2 | 5 065; Kõrgus: 3 650; 3D pikkus: 410 | 5 065
SS-08 | 2 korrus | 1.18 IfcWall (sein) (_RKAS BIM + ARCHICAD Classification) | Müüriplokk - Konstuktsioon, Krohv - Lubjakivi | Siseviimistlus; Lubikrohv 10mm; Kergplokk100mm | nõudeid ei esitata | 48dB | 0,2 | 5 065; Kõrgus: 3 650; 3D pikkus: 410 | 5 065
SS-08 | 2 korrus | 1.18 IfcWall (sein) (_RKAS BIM + ARCHICAD Classification) | Müüriplokk - Konstuktsioon, Krohv - Lubjakivi | Siseviimistlus; Lubikrohv 10mm; Kergplokk100mm | nõudeid ei esitata | 48dB | 0,1 | 5 065; Kõrgus: 3 650; 3D pikkus: 400 | 5 065
SS-08 | 2 korrus | 1.18 IfcWall (sein) (_RKAS BIM + ARCHICAD Classification) | Krohv - Lubjakivi, Müüriplokk - Konstuktsioon | Siseviimistlus; Lubikrohv 10mm; Kergplokk100mm | EI 60 | 48dB | 0,2 | 5 065; Kõrgus: 3 650; 3D pikkus: 500 | 5 065
SS-08 | 2 korrus | 1.18 IfcWall (sein) (_RKAS BIM + ARCHICAD Classification) | Krohv - Lubjakivi, Müüriplokk - Konstuktsioon | Siseviimistlus; Lubikrohv 10mm; Kergplokk100mm | nõudeid ei esitata | 48dB | 0,5 | 5 065; Kõrgus: 3 650; 3D pikkus: 1 390 | 5 065
SS-08 | 2 korrus | 1.18 IfcWall (sein) (_RKAS BIM + ARCHICAD Classification) | Müüriplokk - Konstuktsioon, Krohv - Lubjakivi | Siseviimistlus; Lubikrohv 10mm; Kergplokk100mm | nõudeid ei esitata | 48dB | 0,1 | 5 065; Kõrgus: 3 650; 3D pikkus: 490 | 5 065
SS-08 | 2 korrus | 1.18 IfcWall (sein) (_RKAS BIM + ARCHICAD Classification) | Krohv - Lubjakivi, Müüriplokk - Konstuktsioon | Siseviimistlus; Lubikrohv 10mm; Kergplokk100mm | nõudeid ei esitata | 48dB | 0,6 | 5 065; Kõrgus: 3 650; 3D pikkus: 1 710 | 5 065
SS-08 | 2 korrus | 1.18 IfcWall (sein) (_RKAS BIM + ARCHICAD Classification) | Krohv - Lubjakivi, Müüriplokk - Konstuktsioon | Siseviimistlus; Lubikrohv 10mm; Kergplokk100mm | nõudeid ei esitata | 48dB | 0,3 | 5 065; Kõrgus: 3 650; 3D pikkus: 870 | 5 065

# IfcWall: SS-09 (21)
Type - ElementType: Element type SS-09
Arhitektuur - 01 Nimetus: Sisesein; 03 Tähistus: SS-09; 04 Tulepüsivus: nõudeid ei esitata; 05 Asukoht: Interior; 06 Kandevelementide eristatus: Non-Load-Bearing Element; 08 Soojusläbivus (U-arv): -
Ehituskonstruktsioonid - 03 Tähistus või ristlõige: SS-09
AC_Pset_RenovationAndPhasing - Renovation Status: New
Pset_WallCommon - LoadBearing: no; IsExternal: no
Name | In | Classification | Material | 02 Materjal | 07 Helipidavus | 06 Maht (kubatuur) | 11 Ülemine kõrgusmärk | 12 Alumine kõrgusmärk
SS-09 | -1 korrus | 1.18 IfcWall (sein) (_RKAS BIM + ARCHICAD Classification) | Müüriplokk - Konstuktsioon | Kergplokk 100mm | - | 0,3 | -3 435; Kõrgus: 3 020; 3D pikkus: 1 050 | -3 435
SS-09 | 0 korrus | 1.18 IfcWall (sein) (_RKAS BIM + ARCHICAD Classification) | Müüriplokk - Konstuktsioon | Kergplokk100mm | - | 0,1 | -1 765; Kõrgus: 3 150; 3D pikkus: 300 | -1 765
SS-09 | 0 korrus | 1.18 IfcWall (sein) (_RKAS BIM + ARCHICAD Classification) | Müüriplokk - Konstuktsioon | Kergplokk 100mm | - | 0,1 | -1 635; Kõrgus: 3 020; 3D pikkus: 300 | -1 635
SS-09 | 1 korrus | 1.18 IfcWall (sein) (_RKAS BIM + ARCHICAD Classification) | Müüriplokk - Konstuktsioon | Kergplokk 100mm; | 48dB | 0,0 | -620; Kõrgus: 2 947; 3D pikkus: 120 | -620
SS-09 | 1 korrus | 1.18 IfcWall (sein) (_RKAS BIM + ARCHICAD Classification) | Müüriplokk - Konstuktsioon | Kergplokk 100mm | - | 0,1 | -20; Kõrgus: 2 320; 3D pikkus: 400 | -20
SS-09 | 1 korrus | 1.18 IfcWall (sein) (_RKAS BIM + ARCHICAD Classification) | Müüriplokk - Konstuktsioon (2) | Siseviimistlus; Lubikrohv 10mm; Kergplokk 100mm; | - | 0,1 | -620; Kõrgus: 3 520; 3D pikkus: 144 | -620
SS-09 | 1 korrus | 1.18 IfcWall (sein) (_RKAS BIM + ARCHICAD Classification) | Müüriplokk - Konstuktsioon (2) | Kergplokk 100mm; | - | 0,1 | -620; Kõrgus: 3 520; 3D pikkus: 330 | -620
SS-09 | 1 korrus | 1.18 IfcWall (sein) (_RKAS BIM + ARCHICAD Classification) | Müüriplokk - Konstuktsioon | Kergplokk 100mm; | - | 0,0 | -620; Kõrgus: 3 494; 3D pikkus: 210 | -620
SS-09 | 1 korrus | 1.18 IfcWall (sein) (_RKAS BIM + ARCHICAD Classification) | Müüriplokk - Konstuktsioon | Kergplokk 100mm; | 48dB | 0,0 | -620; Kõrgus: 3 220; 3D pikkus: 120 | -620
SS-09 | 1,5 korrus | 1.18 IfcWall (sein) (_RKAS BIM + ARCHICAD Classification) | Müüriplokk - Konstuktsioon | Kergplokk 100mm | - | 0,4 | 1 385; Kõrgus: 3 415; 3D pikkus: 1 050 | 1 385
SS-09 | 1,5 korrus | 0 TELLIJA KULUD (EHITUSKULUDE LIIGITAMINE EVS 885:2005); 1.18 IfcWall (sein) (_RKAS BIM + ARCHICAD Classification) | Müüriplokk - Konstuktsioon | Kergplokk100mm | - | 0,1 | 1 385; Kõrgus: 3 830; 3D pikkus: 300 | 1 385
SS-09 | 1,5 korrus | 1.18 IfcWall (sein) (_RKAS BIM + ARCHICAD Classification) | Müüriplokk - Konstuktsioon | Kergplokk 100mm | - | 0,1 | 2 300; Kõrgus: 2 500; 3D pikkus: 400 | 2 300
SS-09 | 1,5 korrus | 1.18 IfcWall (sein) (_RKAS BIM + ARCHICAD Classification) | Müüriplokk - Konstuktsioon | Kergplokk100mm | - | 0,1 | 1 385; Kõrgus: 3 415; 3D pikkus: 300 | 1 385
SS-09 | 2 korrus | 1.18 IfcWall (sein) (_RKAS BIM + ARCHICAD Classification) | Müüriplokk - Konstuktsioon | Kergplokk100mm | - | 0,0 | 5 065; Kõrgus: 3 650; 3D pikkus: 210 | 5 065
2 x SS-09 | 2 korrus | 1.18 IfcWall (sein) (_RKAS BIM + ARCHICAD Classification) | Müüriplokk - Konstuktsioon | Kergplokk100mm | - | 0,1 | 5 065; Kõrgus: 3 650; 3D pikkus: 210 | 5 065
SS-09 | 2 korrus | 1.18 IfcWall (sein) (_RKAS BIM + ARCHICAD Classification) | Müüriplokk - Konstuktsioon | Kergplokk100mm | - | 0,1 | 5 065; Kõrgus: 3 650; 3D pikkus: 270 | 5 065
SS-09 | 2 korrus | 1.18 IfcWall (sein) (_RKAS BIM + ARCHICAD Classification) | Müüriplokk - Konstuktsioon | Kergplokk100mm | - | 0,4 | 4 800; Kõrgus: 3 915; 3D pikkus: 1 050 | 4 800
SS-09 | 2 korrus | 0 TELLIJA KULUD (EHITUSKULUDE LIIGITAMINE EVS 885:2005); 1.18 IfcWall (sein) (_RKAS BIM + ARCHICAD Classification) | Müüriplokk - Konstuktsioon | Kergplokk100mm | - | 0,1 | 4 800; Kõrgus: 3 915; 3D pikkus: 300 | 4 800
2 x SS-09 | 2 korrus | 1.18 IfcWall (sein) (_RKAS BIM + ARCHICAD Classification) | Müüriplokk - Konstuktsioon | Kergplokk100mm | - | 0,1 | 4 800; Kõrgus: 3 915; 3D pikkus: 300 | 4 800

# IfcWall: SS-10 (69)
Type - ElementType: Element type SS-10
Arhitektuur - 01 Nimetus: Sisesein; 03 Tähistus: SS-10; 05 Asukoht: Interior; 08 Soojusläbivus (U-arv): -
Ehituskonstruktsioonid - 03 Tähistus või ristlõige: SS-10
AC_Pset_RenovationAndPhasing - Renovation Status: New
Pset_WallCommon - IsExternal: no
Name | In | Classification | Material | 02 Materjal | 04 Tulepüsivus | 06 Kandevelementide eristatus | 07 Helipidavus | 06 Maht (kubatuur) | 11 Ülemine kõrgusmärk | 12 Alumine kõrgusmärk | LoadBearing
SS-10 | 0 korrus | 1.18 IfcWall (sein) (_RKAS BIM + ARCHICAD Classification) | Krohv - Lubjakivi (2), Raudbetoon - Konstruktsioon | Siseviimistlus; Lubikrohv 10mm; Monteeritav raudbetoonsein 200mm; Lubikrohv 10mm; Siseviimistlus | nõudeid ei esitata | Load-Bearing Element | 48 dB | 2,3 | -1 635; Kõrgus: 3 020; 3D pikkus: 3 979 | -1 635 | yes
SS-10 | 0 korrus | 1.18 IfcWall (sein) (_RKAS BIM + ARCHICAD Classification) | Krohv - Lubjakivi (3), Raudbetoon - Konstruktsioon | Siseviimistlus; Lubikrohv 10mm; Monteeritav raudbetoonsein 200mm; Lubikrohv 10mm; Siseviimistlus | nõudeid ei esitata | Load-Bearing Element | 48 dB | 5,0 | -1 635; Kõrgus: 3 020; 3D pikkus: 10 220 | -1 635 | yes
SS-10 | 0 korrus | 1.18 IfcWall (sein) (_RKAS BIM + ARCHICAD Classification) | Krohv - Lubjakivi (2), Raudbetoon - Konstruktsioon | Siseviimistlus; Lubikrohv 10mm; Monteeritav raudbetoonsein 200mm; Lubikrohv 10mm; Siseviimistlus | nõudeid ei esitata | Load-Bearing Element | 48 dB | 4,2 | -1 635; Kõrgus: 3 020; 3D pikkus: 9 250 | -1 635 | yes
SS-10 | 0 korrus | 1.18 IfcWall (sein) (_RKAS BIM + ARCHICAD Classification) | Krohv - Lubjakivi (8), Raudbetoon - Konstruktsioon (2) | Siseviimistlus; Lubikrohv 10mm; Monteeritav raudbetoonsein 200mm; Lubikrohv 10mm; Siseviimistlus | nõudeid ei esitata | Load-Bearing Element | 48dB | 3,6 | -1 635; Kõrgus: 3 020; 3D pikkus: 9 080 | -1 635 | yes
SS-10 | 0 korrus | 1.18 IfcWall (sein) (_RKAS BIM + ARCHICAD Classification) | Krohv - Lubjakivi (4), Raudbetoon - Konstruktsioon | Siseviimistlus; Lubikrohv 10mm; Monteeritav raudbetoonsein 200mm; Lubikrohv 10mm; Siseviimistlus | nõudeid ei esitata | Load-Bearing Element | 48 dB | 0,7 | -1 635; Kõrgus: 3 020; 3D pikkus: 1 080 | -1 635 | yes
SS-10 | 0 korrus | 1.18 IfcWall (sein) (_RKAS BIM + ARCHICAD Classification) | Krohv - Lubjakivi (6), Raudbetoon - Konstruktsioon (2) | Siseviimistlus; Lubikrohv 10mm; Monteeritav raudbetoonsein 200mm; Lubikrohv 10mm; Siseviimistlus | nõudeid ei esitata | Load-Bearing Element | 48 dB | 6,9 | -1 635; Kõrgus: 3 285; 3D pikkus: 11 880 | -1 635 | yes
SS-10 | 0 korrus | 1.18 IfcWall (sein) (_RKAS BIM + ARCHICAD Classification) | Krohv - Lubjakivi (3), Raudbetoon - Konstruktsioon | Siseviimistlus; Lubikrohv 10mm; Monteeritav raudbetoonsein 200mm; Lubikrohv 10mm; Siseviimistlus | EI 60 | Load-Bearing Element | 48dB | 1,1 | -1 835; Kõrgus: 3 220; 3D pikkus: 3 000 | -1 835 | yes
SS-10 | 0 korrus | 1.18 IfcWall (sein) (_RKAS BIM + ARCHICAD Classification) | Krohv - Lubjakivi (2), Raudbetoon - Konstruktsioon | Siseviimistlus; Lubikrohv 10mm; Monteeritav raudbetoonsein 200mm; Lubikrohv 10mm; Siseviimistlus | nõudeid ei esitata | Load-Bearing Element | 48 dB | 2,3 | -1 635; Kõrgus: 3 285; 3D pikkus: 3 460 | -1 635 | yes
SS-10 | 0 korrus | 1.18 IfcWall (sein) (_RKAS BIM + ARCHICAD Classification) | Krohv - Lubjakivi (2), Raudbetoon - Konstruktsioon | Siseviimistlus; Lubikrohv 10mm; Monteeritav raudbetoonsein 200mm; Lubikrohv 10mm; Siseviimistlus | nõudeid ei esitata | Load-Bearing Element | 48 dB | 3,3 | -1 635; Kõrgus: 3 020; 3D pikkus: 4 950 | -1 635 | yes
SS-10 | 1 korrus | 1.18 IfcWall (sein) (_RKAS BIM + ARCHICAD Classification) | Krohv - Lubjakivi (2), Raudbetoon - Konstruktsioon | Siseviimistlus; Lubikrohv 10mm; Monteeritav raudbetoonsein 200mm; Lubikrohv 10mm; Siseviimistlus | nõudeid ei esitata | Load-Bearing Element | 49 dB | 0,3 | -20; Kõrgus: 2 520; 3D pikkus: 1 230 | -20 | yes
SS-10 | 1 korrus | 1.18 IfcWall (sein) (_RKAS BIM + ARCHICAD Classification) | Krohv - Lubjakivi (3), Raudbetoon - Konstruktsioon | Siseviimistlus; Lubikrohv 10mm; Monteeritav raudbetoonsein 200mm; Lubikrohv 10mm; Siseviimistlus | nõudeid ei esitata | Load-Bearing Element | 60 dB | 5,8 | -20; Kõrgus: 4 820; 3D pikkus: 5 507 | -20 | yes
SS-10 | 1 korrus | 1.18 IfcWall (sein) (_RKAS BIM + ARCHICAD Classification) | Krohv - Lubjakivi (3), Raudbetoon - Konstruktsioon | Siseviimistlus; Lubikrohv 10mm; Monteeritav raudbetoonsein 200mm; Lubikrohv 10mm; Siseviimistlus | nõudeid ei esitata | Load-Bearing Element | - | 1,2 | 2 170; Kõrgus: 1 030; 3D pikkus: 5 334 | 2 170 | yes
SS-11 | 1 korrus | 1.18 IfcWall (sein) (_RKAS BIM + ARCHICAD Classification) | Krohv - Lubjakivi, Raudbetoon - Konstruktsioon | Siseviimistlus; Lubikrohv 10mm; Monteeritav raudbetoonsein 200mm; Lubikrohv 10mm; Siseviimistlus | EI 60 | Load-Bearing Element | 60 dB | 1,7 | -150; Kõrgus: 4 950; 3D pikkus: 1 851 | -150 | yes
SS-10 | 1 korrus | 1.18 IfcWall (sein) (_RKAS BIM + ARCHICAD Classification) | Krohv - Lubjakivi (2), Raudbetoon - Konstruktsioon | Siseviimistlus; Lubikrohv 10mm; Monteeritav raudbetoonsein 200mm; Lubikrohv 10mm; Siseviimistlus | nõudeid ei esitata | Load-Bearing Element | - | 2,1 | -150; Kõrgus: 4 950; 3D pikkus: 2 280 | -150 | yes
SS-10 | 1 korrus | 1.18 IfcWall (sein) (_RKAS BIM + ARCHICAD Classification) | Krohv - Lubjakivi (2), Raudbetoon - Konstruktsioon | Siseviimistlus; Lubikrohv 10mm; Monteeritav raudbetoonsein 200mm; Lubikrohv 10mm; Siseviimistlus | EI 60 | Load-Bearing Element | 55 dB | 2,4 | -20; Kõrgus: 4 820; 3D pikkus: 3 160 | -20 | yes
SS-10 | 1 korrus | 1.18 IfcWall (sein) (_RKAS BIM + ARCHICAD Classification) | Krohv - Lubjakivi (5), Raudbetoon - Konstruktsioon | Siseviimistlus; Lubikrohv 10mm; Monteeritav raudbetoonsein 200mm; Lubikrohv 10mm; Siseviimistlus | nõudeid ei esitata | Load-Bearing Element | 48dB | 4,0 | -620; Kõrgus: 3 520; 3D pikkus: 6 300 | -620 | yes
SS-10 | 1 korrus | 1.18 IfcWall (sein) (_RKAS BIM + ARCHICAD Classification) | Krohv - Lubjakivi (12), Raudbetoon - Konstruktsioon | Siseviimistlus; Lubikrohv 10mm; Monteeritav raudbetoonsein 200mm; Lubikrohv 10mm; Siseviimistlus | nõudeid ei esitata | Load-Bearing Element | 48dB | 4,1 | -620; Kõrgus: 3 520; 3D pikkus: 6 510 | -620 | yes
SS-10 | 1 korrus | 1.18 IfcWall (sein) (_RKAS BIM + ARCHICAD Classification) | Krohv - Lubjakivi (4), Raudbetoon - Konstruktsioon | Siseviimistlus; Lubikrohv 10mm; Monteeritav raudbetoonsein 200mm; Lubikrohv 10mm; Siseviimistlus | nõudeid ei esitata | Load-Bearing Element | 48dB | 5,5 | -620; Kõrgus: 3 520; 3D pikkus: 8 500 | -620 | yes
SS-10 | 1 korrus | 1.18 IfcWall (sein) (_RKAS BIM + ARCHICAD Classification) | Krohv - Lubjakivi (6), Raudbetoon - Konstruktsioon | Siseviimistlus; Lubikrohv 10mm; Monteeritav raudbetoonsein 200mm; Lubikrohv 10mm; Siseviimistlus | EI 60 | Load-Bearing Element | 48dB | 5,5 | -620; Kõrgus: 3 520; 3D pikkus: 8 500 | -620 | yes
SS-10 | 1 korrus | 0 TELLIJA KULUD (EHITUSKULUDE LIIGITAMINE EVS 885:2005); 1.18 IfcWall (sein) (_RKAS BIM + ARCHICAD Classification) | Krohv - Lubjakivi (2), Raudbetoon - Konstruktsioon | Siseviimistlus; Lubikrohv 10mm; Monteeritav raudbetoonsein 200mm; Lubikrohv 10mm; Siseviimistlus | EI 60 | Load-Bearing Element | 48dB | 1,2 | -620; Kõrgus: 3 830; 3D pikkus: 1 558 | -620 | yes
SS-10 | 1 korrus | 1.18 IfcWall (sein) (_RKAS BIM + ARCHICAD Classification) | Krohv - Lubjakivi (2), Raudbetoon - Konstruktsioon | Siseviimistlus; Lubikrohv 10mm; Monteeritav raudbetoonsein 200mm; Lubikrohv 10mm; Siseviimistlus | nõudeid ei esitata | Load-Bearing Element | 49 dB | 0,8 | -20; Kõrgus: 2 520; 3D pikkus: 1 430 | -20 | yes
SS-10 | 1 korrus | 0 TELLIJA KULUD (EHITUSKULUDE LIIGITAMINE EVS 885:2005); 1.18 IfcWall (sein) (_RKAS BIM + ARCHICAD Classification) | Krohv - Lubjakivi (2), Raudbetoon - Konstruktsioon | Siseviimistlus; Lubikrohv 10mm; Monteeritav raudbetoonsein 200mm; Lubikrohv 10mm; Siseviimistlus | EI 60 | Load-Bearing Element | 48dB | 1,1 | -620; Kõrgus: 3 437; 3D pikkus: 1 575 | -620 | yes
SS-10 | 1 korrus | 0 TELLIJA KULUD (EHITUSKULUDE LIIGITAMINE EVS 885:2005); 1.18 IfcWall (sein) (_RKAS BIM + ARCHICAD Classification) | Krohv - Lubjakivi (2), Raudbetoon - Konstruktsioon | Siseviimistlus; Lubikrohv 10mm; Monteeritav raudbetoonsein 200mm; Lubikrohv 10mm; Siseviimistlus | EI 60 | Load-Bearing Element | 48dB | 0,5 | -620; Kõrgus: 2 603; 3D pikkus: 1 073 | -620 | yes
SS-10 | 1 korrus | 1.18 IfcWall (sein) (_RKAS BIM + ARCHICAD Classification) | Krohv - Lubjakivi (2), Raudbetoon - Konstruktsioon | Siseviimistlus; Lubikrohv 10mm; Kergplokk150mm; Lubikrohv 10mm; Siseviimistlus | nõudeid ei esitata | Non-Load-Bearing Element | 48 dB | 0,3 | 25; Kõrgus: 1 360; 3D pikkus: 1 140 | 25 | no
SS-10 | 1 korrus | 1.18 IfcWall (sein) (_RKAS BIM + ARCHICAD Classification) | Krohv - Lubjakivi (2), Raudbetoon - Konstruktsioon | Siseviimistlus; Lubikrohv 10mm; Monteeritav raudbetoonsein 200mm; Lubikrohv 10mm; Siseviimistlus | EI 60 | Load-Bearing Element | - | 1,2 | -620; Kõrgus: 3 395; 3D pikkus: 2 407 | -620 | yes
SS-10 | 1 korrus | 1.18 IfcWall (sein) (_RKAS BIM + ARCHICAD Classification) | Krohv - Lubjakivi (5), Raudbetoon - Konstruktsioon | Siseviimistlus; Lubikrohv 10mm; Monteeritav raudbetoonsein 200mm; Lubikrohv 10mm; Siseviimistlus | nõudeid ei esitata | Load-Bearing Element | - | 5,8 | -620; Kõrgus: 3 395; 3D pikkus: 8 430 | -620 | yes
SS-10 | 1 korrus | 1.18 IfcWall (sein) (_RKAS BIM + ARCHICAD Classification) | Krohv - Lubjakivi (2), Raudbetoon - Konstruktsioon | Siseviimistlus; Lubikrohv 10mm; Monteeritav raudbetoonsein 200mm; Lubikrohv 10mm; Siseviimistlus | nõudeid ei esitata | Load-Bearing Element | - | 4,8 | -20; Kõrgus: 4 820; 3D pikkus: 5 573 | -20 | yes
SS-10 | 1 korrus | 1.18 IfcWall (sein) (_RKAS BIM + ARCHICAD Classification) | Krohv - Lubjakivi (5), Raudbetoon - Konstruktsioon | Siseviimistlus; Lubikrohv 10mm; Monteeritav raudbetoonsein 200mm; Lubikrohv 10mm; Siseviimistlus | nõudeid ei esitata | Load-Bearing Element | 55 dB | 8,5 | -20; Kõrgus: 4 820; 3D pikkus: 10 200 | -20 | yes
SS-10 | 1 korrus | 1.18 IfcWall (sein) (_RKAS BIM + ARCHICAD Classification) | Krohv - Lubjakivi (2), Raudbetoon - Konstruktsioon | Siseviimistlus; Lubikrohv 10mm; Monteeritav raudbetoonsein 200mm; Lubikrohv 10mm; Siseviimistlus | nõudeid ei esitata | Load-Bearing Element | - | 0,5 | 885; Kõrgus: 500; 3D pikkus: 4 640 | 885 | yes
SS-10 | 1 korrus | 1.18 IfcWall (sein) (_RKAS BIM + ARCHICAD Classification) | Krohv - Lubjakivi (2), Raudbetoon - Konstruktsioon | Siseviimistlus; Lubikrohv 10mm; Monteeritav raudbetoonsein 200mm; Lubikrohv 10mm; Siseviimistlus | nõudeid ei esitata | Load-Bearing Element | - | 0,7 | 885; Kõrgus: 500; 3D pikkus: 6 590 | 885 | yes
SS-10 | 1 korrus | 0 TELLIJA KULUD (EHITUSKULUDE LIIGITAMINE EVS 885:2005); 1.18 IfcWall (sein) (_RKAS BIM + ARCHICAD Classification) | Krohv - Lubjakivi (2), Raudbetoon - Konstruktsioon | Siseviimistlus; Lubikrohv 10mm; Monteeritav raudbetoonsein 200mm; Lubikrohv 10mm; Siseviimistlus | EI 60 | Load-Bearing Element | 48dB | 0,9 | -620; Kõrgus: 3 070; 3D pikkus: 1 575 | -620 | yes
SS-10 | 1 korrus | 1.18 IfcWall (sein) (_RKAS BIM + ARCHICAD Classification) | Krohv - Lubjakivi (3), Raudbetoon - Konstruktsioon | Siseviimistlus; Lubikrohv 10mm; Monteeritav raudbetoonsein 200mm; Lubikrohv 10mm; Siseviimistlus | nõudeid ei esitata | Load-Bearing Element | - | 1,3 | -620; Kõrgus: 3 395; 3D pikkus: 3 280 | -620 | yes
SS-10 | 1 korrus | 1.18 IfcWall (sein) (_RKAS BIM + ARCHICAD Classification) | Krohv - Lubjakivi (2), Raudbetoon - Konstruktsioon | Siseviimistlus; Lubikrohv 10mm; Monteeritav raudbetoonsein 200mm; Lubikrohv 10mm; Siseviimistlus | nõudeid ei esitata | Load-Bearing Element | - | 1,9 | -20; Kõrgus: 2 320; 3D pikkus: 3 710 | -20 | yes
SS-10 | 1 korrus | 1.18 IfcWall (sein) (_RKAS BIM + ARCHICAD Classification) | Krohv - Lubjakivi (4), Raudbetoon - Konstruktsioon | Siseviimistlus; Lubikrohv 10mm; Monteeritav raudbetoonsein 200mm; Lubikrohv 10mm; Siseviimistlus | nõudeid ei esitata | Load-Bearing Element | - | 1,0 | -20; Kõrgus: 2 370; 3D pikkus: 2 760 | -20 | yes
SS-10 | 1 korrus | 1.18 IfcWall (sein) (_RKAS BIM + ARCHICAD Classification) | Krohv - Lubjakivi (2), Raudbetoon - Konstruktsioon | Siseviimistlus; Lubikrohv 10mm; Monteeritav raudbetoonsein 200mm; Lubikrohv 10mm; Siseviimistlus | nõudeid ei esitata | Load-Bearing Element | - | 2,2 | -20; Kõrgus: 2 320; 3D pikkus: 5 607 | -20 | yes
SS-10 | 1 korrus | 1.18 IfcWall (sein) (_RKAS BIM + ARCHICAD Classification) | Krohv - Lubjakivi (2), Raudbetoon - Konstruktsioon | Siseviimistlus; Lubikrohv 10mm; Monteeritav raudbetoonsein 200mm; Lubikrohv 10mm; Siseviimistlus | nõudeid ei esitata | Load-Bearing Element | 48dB | 1,2 | -620; Kõrgus: 3 520; 3D pikkus: 1 610 | -620 | yes
SS-10 | 1 korrus | 0 TELLIJA KULUD (EHITUSKULUDE LIIGITAMINE EVS 885:2005); 1.18 IfcWall (sein) (_RKAS BIM + ARCHICAD Classification) | Krohv - Lubjakivi (2), Raudbetoon - Konstruktsioon | Siseviimistlus; Lubikrohv 10mm; Monteeritav raudbetoonsein 200mm; Lubikrohv 10mm; Siseviimistlus | EI 60 | Load-Bearing Element | 48dB | 0,7 | -620; Kõrgus: 3 820; 3D pikkus: 830 | -620 | yes
SS-10 | 1,5 korrus | 1.18 IfcWall (sein) (_RKAS BIM + ARCHICAD Classification) | Krohv - Lubjakivi (5), Raudbetoon - Konstruktsioon (2) | Siseviimistlus; Lubikrohv 10mm; Monteeritav raudbetoonsein 200mm; Lubikrohv 10mm; Siseviimistlus | nõudeid ei esitata | Load-Bearing Element | 48 dB | 3,6 | 1 650; Kõrgus: 3 150; 3D pikkus: 6 740 | 1 650 | yes
SS-10 | 1,5 korrus | 1.18 IfcWall (sein) (_RKAS BIM + ARCHICAD Classification) | Krohv - Lubjakivi (2), Raudbetoon - Konstruktsioon | Siseviimistlus; Lubikrohv 10mm; Monteeritav raudbetoonsein 200mm; Lubikrohv 10mm; Siseviimistlus | nõudeid ei esitata | Load-Bearing Element | 48 dB | 2,6 | 1 650; Kõrgus: 3 150; 3D pikkus: 4 477 | 1 650 | yes
SS-10 | 1,5 korrus | 1.18 IfcWall (sein) (_RKAS BIM + ARCHICAD Classification) | Krohv - Lubjakivi (2), Raudbetoon - Konstruktsioon | Siseviimistlus; Lubikrohv 10mm; Monteeritav raudbetoonsein 200mm; Lubikrohv 10mm; Siseviimistlus | nõudeid ei esitata | Load-Bearing Element | - | 1,8 | 1 650; Kõrgus: 3 565; 3D pikkus: 3 297 | 1 650 | yes
SS-10 | 1,5 korrus | 1.18 IfcWall (sein) (_RKAS BIM + ARCHICAD Classification) | Krohv - Lubjakivi (5), Raudbetoon - Konstruktsioon | Siseviimistlus; Lubikrohv 10mm; Monteeritav raudbetoonsein 200mm; Lubikrohv 10mm; Siseviimistlus | EI 60 | Load-Bearing Element | 48 dB | 19,4 | 1 385; Kõrgus: 3 415; 3D pikkus: 29 890 | 1 385 | yes
SS-10 | 1,5 korrus | 1.18 IfcWall (sein) (_RKAS BIM + ARCHICAD Classification) | Krohv - Lubjakivi (2), Raudbetoon - Konstruktsioon | Siseviimistlus; Lubikrohv 10mm; Monteeritav raudbetoonsein 200mm; Lubikrohv 10mm; Siseviimistlus | nõudeid ei esitata | Load-Bearing Element | - | 0,7 | 885; Kõrgus: 500; 3D pikkus: 6 670 | 885 | yes
SS-10 | 1,5 korrus | 1.18 IfcWall (sein) (_RKAS BIM + ARCHICAD Classification) | Krohv - Lubjakivi (4), Raudbetoon - Konstruktsioon (2) | Siseviimistlus; Lubikrohv 10mm; Monteeritav raudbetoonsein 200mm; Lubikrohv 10mm; Siseviimistlus | nõudeid ei esitata | Load-Bearing Element | - | 0,9 | 4 300; Kõrgus: 500; 3D pikkus: 8 110 | 4 300 | yes
SS-10 | 1,5 korrus | 1.18 IfcWall (sein) (_RKAS BIM + ARCHICAD Classification) | Krohv - Lubjakivi (2), Raudbetoon - Konstruktsioon | Siseviimistlus; Lubikrohv 10mm; Monteeritav raudbetoonsein 200mm; Lubikrohv 10mm; Siseviimistlus | EI 60 | Load-Bearing Element | 48 dB | 2,4 | 1 650; Kõrgus: 3 565; 3D pikkus: 3 460 | 1 650 | yes
SS-10 | 1,5 korrus | 1.18 IfcWall (sein) (_RKAS BIM + ARCHICAD Classification) | Krohv - Lubjakivi (2), Raudbetoon - Konstruktsioon | Siseviimistlus; Lubikrohv 10mm; Monteeritav raudbetoonsein 200mm; Lubikrohv 10mm; Siseviimistlus | EI 60 | Load-Bearing Element | 48 dB | 0,5 | 1 650; Kõrgus: 3 150; 3D pikkus: 760 | 1 650 | yes
SS-10 | 1,5 korrus | 1.18 IfcWall (sein) (_RKAS BIM + ARCHICAD Classification) | Krohv - Lubjakivi (3), Raudbetoon - Konstruktsioon | Siseviimistlus; Lubikrohv 10mm; Monteeritav raudbetoonsein 200mm; Lubikrohv 10mm; Siseviimistlus | EI 60 | Load-Bearing Element | 48 dB | 4,0 | 1 650; Kõrgus: 3 150; 3D pikkus: 5 900 | 1 650 | yes
SS-10 | 1,5 korrus | 1.18 IfcWall (sein) (_RKAS BIM + ARCHICAD Classification) | Krohv - Lubjakivi (4), Raudbetoon - Konstruktsioon (2) | Siseviimistlus; Lubikrohv 10mm; Monteeritav raudbetoonsein 200mm; Lubikrohv 10mm; Siseviimistlus | nõudeid ei esitata | Load-Bearing Element | 48dB | 3,3 | 2 100; Kõrgus: 2 700; 3D pikkus: 5 620 | 2 100 | yes
SS-10 | 1,5 korrus | 1.18 IfcWall (sein) (_RKAS BIM + ARCHICAD Classification) | Krohv - Lubjakivi (3), Raudbetoon - Konstruktsioon | Siseviimistlus; Lubikrohv 10mm; Monteeritav raudbetoonsein 200mm; Lubikrohv 10mm; Siseviimistlus | nõudeid ei esitata | Load-Bearing Element | 48 dB | 1,3 | 2 500; Kõrgus: 2 300; 3D pikkus: 2 660 | 2 500 | yes
SS-10 | 1,5 korrus | 1.18 IfcWall (sein) (_RKAS BIM + ARCHICAD Classification) | Krohv - Lubjakivi (3), Raudbetoon - Konstruktsioon | Siseviimistlus; Lubikrohv 10mm; Monteeritav raudbetoonsein 200mm; Lubikrohv 10mm; Siseviimistlus | nõudeid ei esitata | Load-Bearing Element | 48 dB | 0,7 | 2 100; Kõrgus: 2 700; 3D pikkus: 1 110 | 2 100 | yes
SS-10 | 1,5 korrus | 1.18 IfcWall (sein) (_RKAS BIM + ARCHICAD Classification) | Krohv - Lubjakivi (4), Raudbetoon - Konstruktsioon | Siseviimistlus; Lubikrohv 10mm; Monteeritav raudbetoonsein 200mm; Lubikrohv 10mm; Siseviimistlus | nõudeid ei esitata | Load-Bearing Element | 48 dB | 3,0 | 1 650; Kõrgus: 3 150; 3D pikkus: 4 970 | 1 650 | yes
SS-10 | 2 korrus | 1.18 IfcWall (sein) (_RKAS BIM + ARCHICAD Classification) | Krohv - Lubjakivi (2), Raudbetoon - Konstruktsioon (2) | Siseviimistlus; Lubikrohv 10mm; Monteeritav raudbetoonsein 200mm; Lubikrohv 10mm; Siseviimistlus | nõudeid ei esitata | Load-Bearing Element | 48 dB | 4,8 | 5 065; Kõrgus: 3 650; 3D pikkus: 6 030 | 5 065 | yes
SS-10 | 2 korrus | 1.18 IfcWall (sein) (_RKAS BIM + ARCHICAD Classification) | Krohv - Lubjakivi (2), Raudbetoon - Konstruktsioon | Siseviimistlus; Lubikrohv 10mm; Monteeritav raudbetoonsein 200mm; Lubikrohv 10mm; Siseviimistlus | EI 60 | Load-Bearing Element | 48 dB | 2,7 | 5 065; Kõrgus: 3 650; 3D pikkus: 3 979 | 5 065 | yes
SS-10 | 2 korrus | 1.18 IfcWall (sein) (_RKAS BIM + ARCHICAD Classification) | Krohv - Lubjakivi (2), Raudbetoon - Konstruktsioon | Siseviimistlus; Lubikrohv 10mm; Monteeritav raudbetoonsein 200mm; Lubikrohv 10mm; Siseviimistlus | nõudeid ei esitata | Load-Bearing Element | 48 dB | 7,8 | 4 800; Kõrgus: 3 915; 3D pikkus: 10 438 | 4 800 | yes
SS-10 | 2 korrus | 1.18 IfcWall (sein) (_RKAS BIM + ARCHICAD Classification) | Krohv - Lubjakivi (2), Raudbetoon - Konstruktsioon | Siseviimistlus; Lubikrohv 10mm; Monteeritav raudbetoonsein 200mm; Lubikrohv 10mm; Siseviimistlus | nõudeid ei esitata | Load-Bearing Element | 48 dB | 3,4 | 5 065; Kõrgus: 3 650; 3D pikkus: 4 285 | 5 065 | yes
SS-10 | 2 korrus | 1.18 IfcWall (sein) (_RKAS BIM + ARCHICAD Classification) | Krohv - Lubjakivi (2), Raudbetoon - Konstruktsioon | Siseviimistlus; Lubikrohv 10mm; Monteeritav raudbetoonsein 200mm; Lubikrohv 10mm; Siseviimistlus | nõudeid ei esitata | Load-Bearing Element | 48 dB | 0,9 | 5 065; Kõrgus: 3 650; 3D pikkus: 1 757 | 5 065 | yes
SS-10 | 2 korrus | 1.18 IfcWall (sein) (_RKAS BIM + ARCHICAD Classification) | Krohv - Lubjakivi (2), Raudbetoon - Konstruktsioon | Siseviimistlus; Lubikrohv 10mm; Monteeritav raudbetoonsein 200mm; Lubikrohv 10mm; Siseviimistlus | EI 60 | Load-Bearing Element | 48 dB | 1,1 | 5 065; Kõrgus: 3 650; 3D pikkus: 1 472 | 5 065 | yes
SS-10 | 2 korrus | 1.18 IfcWall (sein) (_RKAS BIM + ARCHICAD Classification) | Krohv - Lubjakivi (2), Raudbetoon - Konstruktsioon | Siseviimistlus; Lubikrohv 10mm; Monteeritav raudbetoonsein 200mm; Lubikrohv 10mm; Siseviimistlus | nõudeid ei esitata | Load-Bearing Element | - | 2,1 | 5 065; Kõrgus: 3 650; 3D pikkus: 3 297 | 5 065 | yes
SS-10 | 2 korrus | 1.18 IfcWall (sein) (_RKAS BIM + ARCHICAD Classification) | Krohv - Lubjakivi (2), Raudbetoon - Konstruktsioon | Siseviimistlus; Lubikrohv 10mm; Monteeritav raudbetoonsein 200mm; Lubikrohv 10mm; Siseviimistlus | EI 60 | Load-Bearing Element | 48 dB | 0,9 | 5 065; Kõrgus: 3 650; 3D pikkus: 1 229 | 5 065 | yes
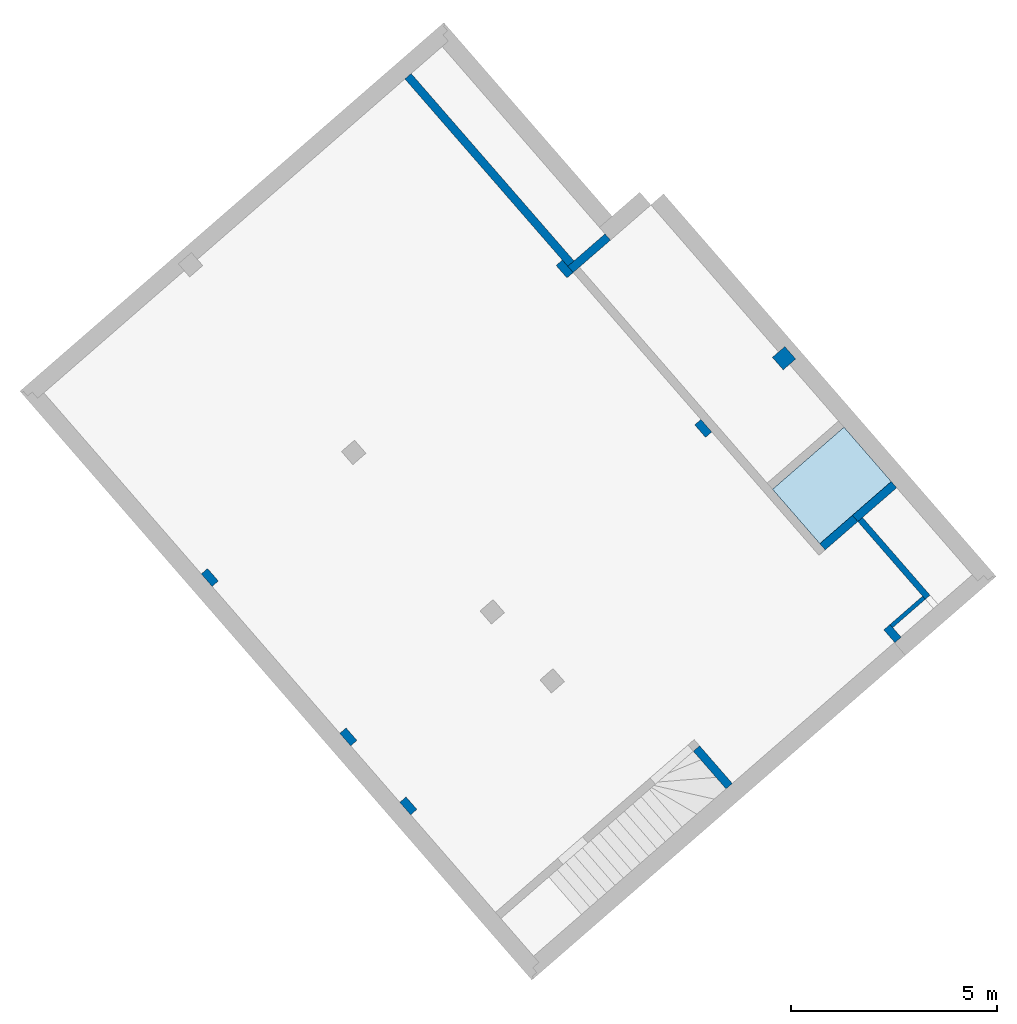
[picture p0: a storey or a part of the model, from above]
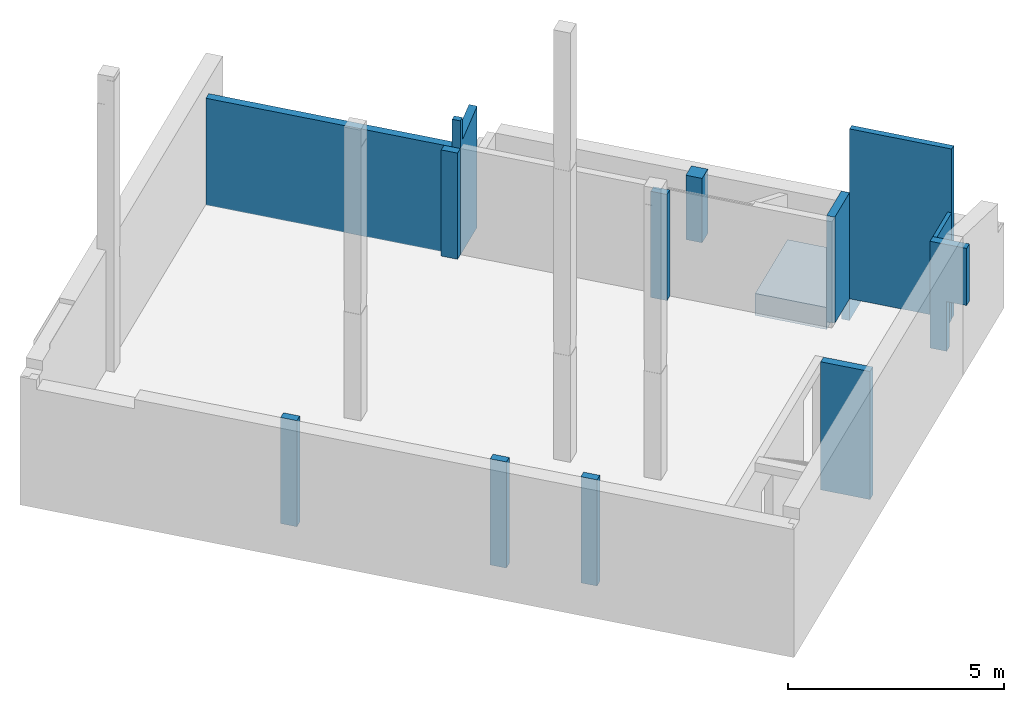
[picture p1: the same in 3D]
Properties of the parts of a building model (IFC2X3), part 11 of 13

# IfcWall: SS-10 (69)
Name | In | Classification | Material | 02 Materjal | 04 Tulepüsivus | 06 Kandevelementide eristatus | 07 Helipidavus | 06 Maht (kubatuur) | 11 Ülemine kõrgusmärk | 12 Alumine kõrgusmärk | LoadBearing
SS-10 | 2 korrus | 1.18 IfcWall (sein) (_RKAS BIM + ARCHICAD Classification) | Krohv - Lubjakivi (2), Raudbetoon - Konstruktsioon | Siseviimistlus; Lubikrohv 10mm; Monteeritav raudbetoonsein 200mm; Lubikrohv 10mm; Siseviimistlus | EI 60 | Load-Bearing Element | 48 dB | 1,9 | 4 800; Kõrgus: 3 915; 3D pikkus: 3 010 | 4 800 | yes
SS-10 | 2 korrus | 1.18 IfcWall (sein) (_RKAS BIM + ARCHICAD Classification) | Krohv - Lubjakivi (2), Raudbetoon - Konstruktsioon | Siseviimistlus; Lubikrohv 10mm; Monteeritav raudbetoonsein 200mm; Lubikrohv 10mm; Siseviimistlus | nõudeid ei esitata | Load-Bearing Element | 48 dB | 4,0 | 5 065; Kõrgus: 3 650; 3D pikkus: 4 959 | 5 065 | yes
SS-10 | 2 korrus | 1.18 IfcWall (sein) (_RKAS BIM + ARCHICAD Classification) | Krohv - Lubjakivi (2), Raudbetoon - Konstruktsioon | Siseviimistlus; Lubikrohv 10mm; Monteeritav raudbetoonsein 200mm; Lubikrohv 10mm; Siseviimistlus | EI 60 | Load-Bearing Element | 48 dB | 1,4 | 5 065; Kõrgus: 3 650; 3D pikkus: 1 770 | 5 065 | yes
SS-10 | 2 korrus | 1.18 IfcWall (sein) (_RKAS BIM + ARCHICAD Classification) | Krohv - Lubjakivi (2), Raudbetoon - Konstruktsioon | Siseviimistlus; Lubikrohv 10mm; Monteeritav raudbetoonsein 200mm; Lubikrohv 10mm; Siseviimistlus | nõudeid ei esitata | Load-Bearing Element | 49 dB | 4,4 | 5 065; Kõrgus: 3 650; 3D pikkus: 5 480 | 5 065 | yes
SS-10 | 2 korrus | 1.18 IfcWall (sein) (_RKAS BIM + ARCHICAD Classification) | Krohv - Lubjakivi (3), Raudbetoon - Konstruktsioon | Siseviimistlus; Lubikrohv 10mm; Monteeritav raudbetoonsein 200mm; Lubikrohv 10mm; Siseviimistlus | nõudeid ei esitata | Load-Bearing Element | 48 dB | 11,7 | 4 800; Kõrgus: 3 915; 3D pikkus: 15 190 | 4 800 | yes
SS-10 | 2 korrus | 1.18 IfcWall (sein) (_RKAS BIM + ARCHICAD Classification) | Krohv - Lubjakivi (3), Raudbetoon - Konstruktsioon | Siseviimistlus; Lubikrohv 10mm; Monteeritav raudbetoonsein 200mm; Lubikrohv 10mm; Siseviimistlus | nõudeid ei esitata | Load-Bearing Element | 48 dB | 8,0 | 4 800; Kõrgus: 3 915; 3D pikkus: 10 640 | 4 800 | yes
SS-10 | 2 korrus | 1.18 IfcWall (sein) (_RKAS BIM + ARCHICAD Classification) | Krohv - Lubjakivi (7), Raudbetoon - Konstruktsioon | Siseviimistlus; Lubikrohv 10mm; Monteeritav raudbetoonsein 200mm; Lubikrohv 10mm; Siseviimistlus | nõudeid ei esitata | Load-Bearing Element | 48 dB | 14,4 | 4 800; Kõrgus: 3 915; 3D pikkus: 19 873 | 4 800 | yes
SS-10 | 2 korrus | 1.18 IfcWall (sein) (_RKAS BIM + ARCHICAD Classification) | Krohv - Lubjakivi (2), Raudbetoon - Konstruktsioon | Siseviimistlus; Lubikrohv 10mm; Monteeritav raudbetoonsein 200mm; Lubikrohv 10mm; Siseviimistlus | nõudeid ei esitata | Load-Bearing Element | 48 dB | 4,0 | 5 065; Kõrgus: 3 650; 3D pikkus: 5 009 | 5 065 | yes
SS-10 | 2 korrus | 1.18 IfcWall (sein) (_RKAS BIM + ARCHICAD Classification) | Krohv - Lubjakivi (2), Raudbetoon - Konstruktsioon | Siseviimistlus; Lubikrohv 10mm; Monteeritav raudbetoonsein 200mm; Lubikrohv 10mm; Siseviimistlus | EI 60 | Load-Bearing Element | 48 dB | 0,4 | 5 065; Kõrgus: 3 650; 3D pikkus: 560 | 5 065 | yes
SS-10 | 2 korrus | 1.18 IfcWall (sein) (_RKAS BIM + ARCHICAD Classification) | Krohv - Lubjakivi (2), Raudbetoon - Konstruktsioon | Siseviimistlus; Lubikrohv 10mm; Monteeritav raudbetoonsein 200mm; Lubikrohv 10mm; Siseviimistlus | nõudeid ei esitata | Load-Bearing Element | 48 dB | 8,3 | 4 800; Kõrgus: 3 915; 3D pikkus: 10 890 | 4 800 | yes
SS-10 | 2 korrus | 1.18 IfcWall (sein) (_RKAS BIM + ARCHICAD Classification) | Krohv - Lubjakivi (2), Raudbetoon - Konstruktsioon | Siseviimistlus; Lubikrohv 10mm; Monteeritav raudbetoonsein 200mm; Lubikrohv 10mm; Siseviimistlus | EI 60 | Load-Bearing Element | 48 dB | 2,7 | 5 065; Kõrgus: 3 650; 3D pikkus: 3 460 | 5 065 | yes

# IfcWall: SS-11 (48)
Type - ElementType: Element type SS-11
Arhitektuur - 01 Nimetus: Sisesein; 03 Tähistus: SS-11; 05 Asukoht: Interior; 06 Kandevelementide eristatus: Load-Bearing Element; 08 Soojusläbivus (U-arv): -
Ehituskonstruktsioonid - 03 Tähistus või ristlõige: SS-11
AC_Pset_RenovationAndPhasing - Renovation Status: New
Pset_WallCommon - LoadBearing: yes; IsExternal: no
Name | In | Classification | Material | 02 Materjal | 04 Tulepüsivus | 07 Helipidavus | 06 Maht (kubatuur) | 11 Ülemine kõrgusmärk | 12 Alumine kõrgusmärk
SS-11 | 0 korrus | 1.18 IfcWall (sein) (_RKAS BIM + ARCHICAD Classification) | Krohv - Lubjakivi, Raudbetoon - Konstruktsioon | Siseviimistlus; Lubikrohv 10mm; Monteeritav raudbetoonsein 200mm | nõudeid ei esitata | 48 dB | 0,7 | -1 635; Kõrgus: 3 020; 3D pikkus: 2 160 | -1 635
SS-11 | 0 korrus | 1.18 IfcWall (sein) (_RKAS BIM + ARCHICAD Classification) | Krohv - Lubjakivi, Raudbetoon - Konstruktsioon (2) | Siseviimistlus; Lubikrohv 10mm; Monteeritav raudbetoonsein 200mm | EI 60 | 48 dB | 0,9 | -1 635; Kõrgus: 3 020; 3D pikkus: 1 550 | -1 635
SS-11 | 0 korrus | 1.18 IfcWall (sein) (_RKAS BIM + ARCHICAD Classification) | Krohv - Lubjakivi, Raudbetoon - Konstruktsioon | Siseviimistlus; Lubikrohv 10mm; Monteeritav raudbetoonsein 200mm | nõudeid ei esitata | 48 dB | 1,0 | -1 635; Kõrgus: 3 285; 3D pikkus: 1 600 | -1 635
SS-11 | 0 korrus | 1.18 IfcWall (sein) (_RKAS BIM + ARCHICAD Classification) | Raudbetoon - Konstruktsioon, Krohv - Lubjakivi (2) | Siseviimistlus; Lubikrohv 10mm; Monteeritav raudbetoonsein 200mm; | EI 60 | 48dB | 3,9 | -1 635; Kõrgus: 3 020; 3D pikkus: 6 517 | -1 635
SS-11 | 0 korrus | 1.18 IfcWall (sein) (_RKAS BIM + ARCHICAD Classification) | Krohv - Lubjakivi (2), Raudbetoon - Konstruktsioon | Siseviimistlus; Lubikrohv 10mm; Monteeritav raudbetoonsein 200mm | nõudeid ei esitata | 48 dB | 0,6 | -1 635; Kõrgus: 3 285; 3D pikkus: 900 | -1 635
SS-11 | 0 korrus | 1.18 IfcWall (sein) (_RKAS BIM + ARCHICAD Classification) | Krohv - Lubjakivi, Raudbetoon - Konstruktsioon | Siseviimistlus; Lubikrohv 10mm; Monteeritav raudbetoonsein 200mm | nõudeid ei esitata | 48 dB | 0,8 | -1 635; Kõrgus: 3 020; 3D pikkus: 1 290 | -1 635
SS-11 | 0 korrus | 1.18 IfcWall (sein) (_RKAS BIM + ARCHICAD Classification) | Krohv - Lubjakivi, Raudbetoon - Konstruktsioon | Siseviimistlus; Lubikrohv 10mm; Monteeritav raudbetoonsein 200mm; | EI 60 | 48dB | 0,2 | -1 635; Kõrgus: 2 000; 3D pikkus: 1 350 | -1 635
SS-11 | 1 korrus | 1.18 IfcWall (sein) (_RKAS BIM + ARCHICAD Classification) | Raudbetoon - Konstruktsioon, Krohv - Lubjakivi | Siseviimistlus; Lubikrohv 10mm; Monteeritav raudbetoonsein 200mm; | EI 60 | 48 dB | 1,9 | -150; Kõrgus: 4 950; 3D pikkus: 1 917 | -150
SS-11 | 1 korrus | 1.18 IfcWall (sein) (_RKAS BIM + ARCHICAD Classification) | Raudbetoon - Konstruktsioon, Krohv - Lubjakivi (2) | Siseviimistlus; Lubikrohv 10mm; Monteeritav raudbetoonsein 200mm; | EI 60 | 48 dB | 4,5 | -150; Kõrgus: 4 950; 3D pikkus: 4 545 | -150
SS-11 | 1 korrus | 1.18 IfcWall (sein) (_RKAS BIM + ARCHICAD Classification) | Krohv - Lubjakivi, Raudbetoon - Konstruktsioon | Siseviimistlus; Lubikrohv 10mm; Monteeritav raudbetoonsein 200mm | EI 60 | - | 3,7 | -150; Kõrgus: 4 950; 3D pikkus: 3 540 | -150
SS-11 | 1 korrus | 1.18 IfcWall (sein) (_RKAS BIM + ARCHICAD Classification) | Raudbetoon - Konstruktsioon, Krohv - Lubjakivi | Siseviimistlus; Lubikrohv 10mm; Monteeritav raudbetoonsein 200mm | EI 60 | 60 dB | 3,1 | -20; Kõrgus: 4 820; 3D pikkus: 3 060 | -20
SS-11 | 1 korrus | 1.18 IfcWall (sein) (_RKAS BIM + ARCHICAD Classification) | Krohv - Lubjakivi (2), Raudbetoon - Konstruktsioon | Siseviimistlus; Lubikrohv 10mm; Monteeritav raudbetoonsein 200mm | EI 60 | 60 dB | 0,5 | -150; Kõrgus: 4 950; 3D pikkus: 647 | -150
SS-11 | 1 korrus | 0 TELLIJA KULUD (EHITUSKULUDE LIIGITAMINE EVS 885:2005); 1.18 IfcWall (sein) (_RKAS BIM + ARCHICAD Classification) | Raudbetoon - Konstruktsioon, Krohv - Lubjakivi | Siseviimistlus; Lubikrohv 10mm; Monteeritav raudbetoonsein 200mm; | EI 60 | 48dB | 0,7 | -620; Kõrgus: 3 820; 3D pikkus: 939 | -620
SS-11 | 1 korrus | 1.18 IfcWall (sein) (_RKAS BIM + ARCHICAD Classification) | Krohv - Lubjakivi, Raudbetoon - Konstruktsioon | Siseviimistlus; Lubikrohv 10mm; Monteeritav raudbetoonsein 200mm; | nõudeid ei esitata | - | 0,1 | -620; Kõrgus: 3 520; 3D pikkus: 200 | -620
SS-11 | 1 korrus | 1.18 IfcWall (sein) (_RKAS BIM + ARCHICAD Classification) | Raudbetoon - Konstruktsioon, Krohv - Lubjakivi | Siseviimistlus; Lubikrohv 10mm; Monteeritav raudbetoonsein 200mm | EI 60 | 48 dB | 2,3 | -150; Kõrgus: 4 950; 3D pikkus: 2 440 | -150
SS-11 | 1 korrus | 1.18 IfcWall (sein) (_RKAS BIM + ARCHICAD Classification) | Krohv - Lubjakivi, Raudbetoon - Konstruktsioon | Siseviimistlus; Lubikrohv 10mm; Monteeritav raudbetoonsein 200mm | nõudeid ei esitata | 48dB | 0,5 | -20; Kõrgus: 4 820; 3D pikkus: 710 | -20
SS-11 | 1 korrus | 1.18 IfcWall (sein) (_RKAS BIM + ARCHICAD Classification) | Raudbetoon - Konstruktsioon, Krohv - Lubjakivi | Siseviimistlus; Lubikrohv 10mm; Monteeritav raudbetoonsein 200mm | nõudeid ei esitata | 48 dB | 1,4 | -415; Kõrgus: 5 215; 3D pikkus: 1 960 | -415
SS-11 | 1 korrus | 1.18 IfcWall (sein) (_RKAS BIM + ARCHICAD Classification) | Raudbetoon - Konstruktsioon, Krohv - Lubjakivi | Siseviimistlus; Lubikrohv 10mm; Monteeritav raudbetoonsein 200mm | nõudeid ei esitata | 60 dB | 1,5 | -20; Kõrgus: 4 820; 3D pikkus: 1 510 | -20
SS-11 | 1 korrus | 1.18 IfcWall (sein) (_RKAS BIM + ARCHICAD Classification) | Raudbetoon - Konstruktsioon, Krohv - Lubjakivi | Siseviimistlus; Lubikrohv 10mm; Monteeritav raudbetoonsein 200mm | EI 60 | 48 dB | 1,5 | -150; Kõrgus: 4 950; 3D pikkus: 1 430 | -150
SS-11 | 1 korrus | 1.18 IfcWall (sein) (_RKAS BIM + ARCHICAD Classification) | Raudbetoon - Konstruktsioon, Krohv - Lubjakivi | Siseviimistlus; Lubikrohv 10mm; Monteeritav raudbetoonsein 200mm | nõudeid ei esitata | 48 dB | 1,1 | -1 635; Kõrgus: 3 020; 3D pikkus: 2 700 | -1 635
SS-11 | 1 korrus | 1.18 IfcWall (sein) (_RKAS BIM + ARCHICAD Classification) | Raudbetoon - Konstruktsioon, Krohv - Lubjakivi | Siseviimistlus; Lubikrohv 10mm; Monteeritav raudbetoonsein 200mm | EI 60 | 48 dB | 3,1 | -415; Kõrgus: 5 215; 3D pikkus: 3 000 | -415
SS-11 | 1 korrus | 0 TELLIJA KULUD (EHITUSKULUDE LIIGITAMINE EVS 885:2005); 1.18 IfcWall (sein) (_RKAS BIM + ARCHICAD Classification) | Raudbetoon - Konstruktsioon, Krohv - Lubjakivi | Siseviimistlus; Lubikrohv 10mm; Monteeritav raudbetoonsein 200mm | EI 60 | - | 0,9 | -620; Kõrgus: 3 820; 3D pikkus: 1 150 | -620
SS-11 | 1,5 korrus | 1.18 IfcWall (sein) (_RKAS BIM + ARCHICAD Classification) | Krohv - Lubjakivi, Raudbetoon - Konstruktsioon | Siseviimistlus; Lubikrohv 10mm; Monteeritav raudbetoonsein 200mm | EI 60 | 48 dB | 4,3 | 1 650; Kõrgus: 3 150; 3D pikkus: 6 527 | 1 650
SS-11 | 1,5 korrus | 1.18 IfcWall (sein) (_RKAS BIM + ARCHICAD Classification) | Krohv - Lubjakivi, Raudbetoon - Konstruktsioon | Siseviimistlus; Lubikrohv 10mm; Monteeritav raudbetoonsein 200mm | nõudeid ei esitata | 48 dB | 0,7 | 1 650; Kõrgus: 3 150; 3D pikkus: 2 160 | 1 650
SS-11 | 1,5 korrus | 1.18 IfcWall (sein) (_RKAS BIM + ARCHICAD Classification) | Raudbetoon - Konstruktsioon, Krohv - Lubjakivi | Siseviimistlus; Lubikrohv 10mm; Monteeritav raudbetoonsein 200mm | EI 60 | 48 dB | 1,2 | -415; Kõrgus: 5 215; 3D pikkus: 1 410 | -415
SS-11 | 1,5 korrus | 1.18 IfcWall (sein) (_RKAS BIM + ARCHICAD Classification) | Krohv - Lubjakivi, Raudbetoon - Konstruktsioon | Siseviimistlus; Lubikrohv 10mm; Monteeritav raudbetoonsein 200mm | EI 60 | 48 dB | 1,0 | 1 650; Kõrgus: 3 150; 3D pikkus: 1 600 | 1 650
SS-11 | 1,5 korrus | 1.18 IfcWall (sein) (_RKAS BIM + ARCHICAD Classification) | Raudbetoon - Konstruktsioon, Krohv - Lubjakivi | Siseviimistlus; Lubikrohv 10mm; Monteeritav raudbetoonsein 200mm | EI 60 | 48 dB | 0,6 | 1 650; Kõrgus: 3 150; 3D pikkus: 947 | 1 650
SS-11 | 1,5 korrus | 1.18 IfcWall (sein) (_RKAS BIM + ARCHICAD Classification) | Krohv - Lubjakivi, Raudbetoon - Konstruktsioon | Siseviimistlus; Lubikrohv 10mm; Monteeritav raudbetoonsein 200mm | EI 60 | 48 dB | 0,9 | 1 650; Kõrgus: 3 150; 3D pikkus: 1 400 | 1 650
SS-11 | 1,5 korrus | 1.18 IfcWall (sein) (_RKAS BIM + ARCHICAD Classification) | Raudbetoon - Konstruktsioon, Krohv - Lubjakivi (2) | Siseviimistlus; Lubikrohv 10mm; Monteeritav raudbetoonsein 200mm | nõudeid ei esitata | - | 0,9 | 1 385; Kõrgus: 3 415; 3D pikkus: 1 460 | 1 385
SS-11 | 1,5 korrus | 1.18 IfcWall (sein) (_RKAS BIM + ARCHICAD Classification) | Raudbetoon - Konstruktsioon, Krohv - Lubjakivi | Siseviimistlus; Lubikrohv 10mm; Monteeritav raudbetoonsein 200mm | EI 60 | 48 dB | 6,6 | -415; Kõrgus: 5 215; 3D pikkus: 6 737 | -415
SS-11 | 1,5 korrus | 1.18 IfcWall (sein) (_RKAS BIM + ARCHICAD Classification) | Raudbetoon - Konstruktsioon, Krohv - Lubjakivi | Siseviimistlus; Lubikrohv 10mm; Monteeritav raudbetoonsein 200mm | nõudeid ei esitata | 48 dB | 1,7 | 1 385; Kõrgus: 3 830; 3D pikkus: 2 700 | 1 385
SS-11 | 2 korrus | 1.18 IfcWall (sein) (_RKAS BIM + ARCHICAD Classification) | Krohv - Lubjakivi, Raudbetoon - Konstruktsioon | Siseviimistlus; Lubikrohv 10mm; Monteeritav raudbetoonsein 200mm | EI 60 | 48 dB | 1,2 | 5 065; Kõrgus: 3 650; 3D pikkus: 1 600 | 5 065
SS-11 | 2 korrus | 1.18 IfcWall (sein) (_RKAS BIM + ARCHICAD Classification) | Raudbetoon - Konstruktsioon, Krohv - Lubjakivi | Siseviimistlus; Lubikrohv 10mm; Monteeritav raudbetoonsein 200mm | nõudeid ei esitata | 48 dB | 1,0 | 5 065; Kõrgus: 3 650; 3D pikkus: 2 170 | 5 065
SS-11 | 2 korrus | 1.18 IfcWall (sein) (_RKAS BIM + ARCHICAD Classification) | Krohv - Lubjakivi, Raudbetoon - Konstruktsioon | Siseviimistlus; Lubikrohv 10mm; Monteeritav raudbetoonsein 200mm; | nõudeid ei esitata | 48 dB | 3,8 | 5 065; Kõrgus: 3 650; 3D pikkus: 4 959 | 5 065
SS-11 | 2 korrus | 1.18 IfcWall (sein) (_RKAS BIM + ARCHICAD Classification) | Raudbetoon - Konstruktsioon, Krohv - Lubjakivi | Siseviimistlus; Lubikrohv 10mm; Monteeritav raudbetoonsein 200mm | nõudeid ei esitata | 48dB | 0,4 | 4 800; Kõrgus: 3 915; 3D pikkus: 510 | 4 800
SS-11 | 2 korrus | 1.18 IfcWall (sein) (_RKAS BIM + ARCHICAD Classification) | Raudbetoon - Konstruktsioon, Krohv - Lubjakivi | Siseviimistlus; Lubikrohv 10mm; Monteeritav raudbetoonsein 200mm | nõudeid ei esitata | 48 dB | 3,5 | 5 065; Kõrgus: 3 650; 3D pikkus: 4 590 | 5 065
SS-11 | 2 korrus | 1.18 IfcWall (sein) (_RKAS BIM + ARCHICAD Classification) | Raudbetoon - Konstruktsioon, Krohv - Lubjakivi | Siseviimistlus; Lubikrohv 10mm; Monteeritav raudbetoonsein 200mm | EI 60 | 48 dB | 2,7 | 5 065; Kõrgus: 3 650; 3D pikkus: 3 497 | 5 065
SS-11 | 2 korrus | 1.18 IfcWall (sein) (_RKAS BIM + ARCHICAD Classification) | Raudbetoon - Konstruktsioon, Krohv - Lubjakivi | Siseviimistlus; Lubikrohv 10mm; Monteeritav raudbetoonsein 200mm | EI 60 | - | 4,8 | 5 065; Kõrgus: 3 650; 3D pikkus: 6 200 | 5 065
SS-11 | 2 korrus | 1.18 IfcWall (sein) (_RKAS BIM + ARCHICAD Classification) | Krohv - Lubjakivi, Raudbetoon - Konstruktsioon | Siseviimistlus; Lubikrohv 10mm; Monteeritav raudbetoonsein 200mm | EI 60 | 48dB | 3,4 | 5 065; Kõrgus: 3 650; 3D pikkus: 4 688 | 5 065
SS-11 | 2 korrus | 1.18 IfcWall (sein) (_RKAS BIM + ARCHICAD Classification) | Raudbetoon - Konstruktsioon, Krohv - Lubjakivi | Siseviimistlus; Lubikrohv 10mm; Monteeritav raudbetoonsein 200mm | nõudeid ei esitata | 48dB | 0,7 | 5 065; Kõrgus: 3 650; 3D pikkus: 947 | 5 065
SS-11 | 2 korrus | 1.18 IfcWall (sein) (_RKAS BIM + ARCHICAD Classification) | Krohv - Lubjakivi, Raudbetoon - Konstruktsioon | Siseviimistlus; Lubikrohv 10mm; Monteeritav raudbetoonsein 200mm | nõudeid ei esitata | 48dB | 0,4 | 5 065; Kõrgus: 3 650; 3D pikkus: 500 | 5 065
SS-11 | 2 korrus | 1.18 IfcWall (sein) (_RKAS BIM + ARCHICAD Classification) | Krohv - Lubjakivi, Raudbetoon - Konstruktsioon | Siseviimistlus; Lubikrohv 10mm; Monteeritav raudbetoonsein 200mm | nõudeid ei esitata | 48 dB | 1,3 | 5 065; Kõrgus: 3 650; 3D pikkus: 1 750 | 5 065
SS-11 | 2 korrus | 1.18 IfcWall (sein) (_RKAS BIM + ARCHICAD Classification) | Krohv - Lubjakivi, Raudbetoon - Konstruktsioon | Siseviimistlus; Lubikrohv 10mm; Monteeritav raudbetoonsein 200mm | nõudeid ei esitata | 48 dB | 1,9 | 5 065; Kõrgus: 3 650; 3D pikkus: 2 710 | 5 065
SS-11 | 2 korrus | 1.18 IfcWall (sein) (_RKAS BIM + ARCHICAD Classification) | Raudbetoon - Konstruktsioon, Krohv - Lubjakivi | Siseviimistlus; Lubikrohv 10mm; Monteeritav raudbetoonsein 200mm | nõudeid ei esitata | 48 dB | 1,0 | 4 800; Kõrgus: 3 915; 3D pikkus: 1 250 | 4 800
SS-11 | 2 korrus | 1.18 IfcWall (sein) (_RKAS BIM + ARCHICAD Classification) | Raudbetoon - Konstruktsioon, Krohv - Lubjakivi | Siseviimistlus; Lubikrohv 10mm; Monteeritav raudbetoonsein 200mm | EI 60 | 48 dB | 2,3 | 5 065; Kõrgus: 3 650; 3D pikkus: 2 970 | 5 065
SS-11 | 2 korrus | 1.18 IfcWall (sein) (_RKAS BIM + ARCHICAD Classification) | Krohv - Lubjakivi, Raudbetoon - Konstruktsioon | Siseviimistlus; Lubikrohv 10mm; Monteeritav raudbetoonsein 200mm | EI 60 | - | 0,7 | 4 800; Kõrgus: 3 915; 3D pikkus: 850 | 4 800
SS-11 | 2 korrus | 1.18 IfcWall (sein) (_RKAS BIM + ARCHICAD Classification) | Krohv - Lubjakivi, Raudbetoon - Konstruktsioon | Siseviimistlus; Lubikrohv 10mm; Monteeritav raudbetoonsein 200mm | nõudeid ei esitata | 48 dB | 1,0 | 5 065; Kõrgus: 3 650; 3D pikkus: 1 300 | 5 065
SS-11 | 2 korrus | 1.18 IfcWall (sein) (_RKAS BIM + ARCHICAD Classification) | Raudbetoon - Konstruktsioon, Krohv - Lubjakivi | Siseviimistlus; Lubikrohv 10mm; Monteeritav raudbetoonsein 200mm | nõudeid ei esitata | 48 dB | 0,2 | 5 065; Kõrgus: 3 650; 3D pikkus: 260 | 5 065

# IfcWall: SS-12 (14)
Type - ElementType: Element type SS-12
Material: Raudbetoon - Konstruktsioon
Arhitektuur - 03 Tähistus: SS-12; 06 Kandevelementide eristatus: Load-Bearing Element; 08 Soojusläbivus (U-arv): -
Ehituskonstruktsioonid - 03 Tähistus või ristlõige: SS-12
AC_Pset_RenovationAndPhasing - Renovation Status: New
Pset_WallCommon - LoadBearing: yes
Name | In | Classification | 01 Nimetus | 02 Materjal | 04 Tulepüsivus | 05 Asukoht | 07 Helipidavus | 06 Maht (kubatuur) | 11 Ülemine kõrgusmärk | 12 Alumine kõrgusmärk | IsExternal
SS-12 | -1 korrus | 0 TELLIJA KULUD (EHITUSKULUDE LIIGITAMINE EVS 885:2005); 1.18 IfcWall (sein) (_RKAS BIM + ARCHICAD Classification) | Välissein | Monteeritav r/bet. seinapaneel 200mm | EI 60 | Exterior | 48dB | 5,6 | -3 435; Kõrgus: 3 020; 3D pikkus: 9 300 | -3 435 | yes
SS-12 | -1 korrus | 1.18 IfcWall (sein) (_RKAS BIM + ARCHICAD Classification) | Sisesein | Monteeritav raudbetoonsein 200mm | EI 60 | Interior | 48 dB | 0,6 | -3 415; Kõrgus: 3 000; 3D pikkus: 1 050 | -3 415 | no
SS-12 | -1 korrus | 1.18 IfcWall (sein) (_RKAS BIM + ARCHICAD Classification) | Välissein | Monteeritav r/bet. seinapaneel 200mm; | EI 60 | Exterior | 48dB | 0,6 | -4 035; Kõrgus: 2 420; 3D pikkus: 1 250 | -4 035 | yes
SS-12 | -1 korrus | 1.18 IfcWall (sein) (_RKAS BIM + ARCHICAD Classification) | Sisesein | Monteeritav raudbetoonsein 200mm; | EI 60 | Interior | - | 0,8 | -3 435; Kõrgus: 3 800; 3D pikkus: 1 200 | -3 435 | no
SS-12 | -1 korrus | 1.18 IfcWall (sein) (_RKAS BIM + ARCHICAD Classification) | Välissein | Monteeritav r/bet. seinapaneel 200mm | nõudeid ei esitata | Exterior | - | 3,6 | -3 435; Kõrgus: 3 020; 3D pikkus: 6 030 | -3 435 | yes
SS-12 | -1 korrus | 0 TELLIJA KULUD (EHITUSKULUDE LIIGITAMINE EVS 885:2005); 1.18 IfcWall (sein) (_RKAS BIM + ARCHICAD Classification) | Sisesein | Monoliitne r/betoon | nõudeid ei esitata | Interior | - | 3,5 | -4 035; Kõrgus: 3 620; 3D pikkus: 6 395 | -4 035 | no
SS-12 | -1 korrus | 1.18 IfcWall (sein) (_RKAS BIM + ARCHICAD Classification) | Sisesein | Monteeritav raudbetoonsein 200mm | EI 60 | Interior | 48 dB | 1,1 | -3 435; Kõrgus: 2 942; 3D pikkus: 2 300 | -3 435 | no
SS-12 | -1 korrus | 1.18 IfcWall (sein) (_RKAS BIM + ARCHICAD Classification) | Sisesein | Monteeritav raudbetoonsein 200mm | nõudeid ei esitata | Interior | - | 0,4 | -3 435; Kõrgus: 3 020; 3D pikkus: 897 | -3 435 | no
SS-12 | -1 korrus | 0 TELLIJA KULUD (EHITUSKULUDE LIIGITAMINE EVS 885:2005); 1.18 IfcWall (sein) (_RKAS BIM + ARCHICAD Classification) | Sisesein | Monoliitne r/betoon | nõudeid ei esitata | Interior | - | 0,9 | -4 035; Kõrgus: 3 620; 3D pikkus: 1 210 | -4 035 | no
SS-12 | 1 korrus | 1.18 IfcWall (sein) (_RKAS BIM + ARCHICAD Classification) | Sisesein | Monteeritav raudbetoonsein 200mm | EI 60 | Interior | - | 1,1 | -150; Kõrgus: 4 950; 3D pikkus: 1 160 | -150 | no
SS-12 | 1,5 korrus | 1.18 IfcWall (sein) (_RKAS BIM + ARCHICAD Classification) | Sisesein | Monteeritav raudbetoonsein 200mm | EI 60 | Interior | - | 1,1 | -415; Kõrgus: 5 215; 3D pikkus: 1 050 | -415 | no
SS-12 | 2 korrus | 1.18 IfcWall (sein) (_RKAS BIM + ARCHICAD Classification) | Sisesein | Monteeritav raudbetoonsein 200mm | EI 60 | Interior | - | 0,8 | 4 800; Kõrgus: 3 915; 3D pikkus: 1 050 | 4 800 | no
SS-12 | 2 korrus | 1.18 IfcWall (sein) (_RKAS BIM + ARCHICAD Classification) | Sisesein | Monteeritav raudbetoonsein 200mm | EI 60 | Interior | - | 0,4 | 4 800; Kõrgus: 3 915; 3D pikkus: 550 | 4 800 | no
SS-12 | 2 korrus | 1.18 IfcWall (sein) (_RKAS BIM + ARCHICAD Classification) | Sisesein | Monteeritav raudbetoonsein 200mm | nõudeid ei esitata | Interior | - | 1,2 | 5 065; Kõrgus: 3 650; 3D pikkus: 1 610 | 5 065 | no

# IfcWall: SS-14 (16)
Type - ElementType: Element type SS-14
Classification: 1.18 IfcWall (sein) (_RKAS BIM + ARCHICAD Classification)
Arhitektuur - 01 Nimetus: Sisesein; 02 Materjal: Siseviimistlus; Kipsplaat 2x12mm; Metallist kipsi karkass 66mm; 03 Tähistus: SS-14; 04 Tulepüsivus: nõudeid ei esitata; 05 Asukoht: Interior; 06 Kandevelementide eristatus: Non-Load-Bearing Element; 07 Helipidavus: -; 08 Soojusläbivus (U-arv): -
Ehituskonstruktsioonid - 03 Tähistus või ristlõige: SS-14
AC_Pset_RenovationAndPhasing - Renovation Status: New
Pset_WallCommon - LoadBearing: no; IsExternal: no
Name | In | Material | 06 Maht (kubatuur) | 11 Ülemine kõrgusmärk | 12 Alumine kõrgusmärk
SS-14 | 1 korrus | Teras, Kipsplaat - Veekindel (2) | 0,2 | -620; Kõrgus: 2 417; 3D pikkus: 1 280 | -620
SS-14 | 1 korrus | Kipsplaat - Veekindel (2), Teras | 0,3 | -620; Kõrgus: 2 918; 3D pikkus: 1 050 | -620
SS-14 | 1 korrus | Kipsplaat - Veekindel (2), Teras | 0,3 | -620; Kõrgus: 3 192; 3D pikkus: 1 050 | -620
SS-14 | 1 korrus | Kipsplaat - Veekindel (2), Teras | 0,3 | -620; Kõrgus: 3 465; 3D pikkus: 1 159 | -620
SS-14 | 1 korrus | Kipsplaat - Veekindel (2), Teras | 0,3 | -620; Kõrgus: 3 520; 3D pikkus: 1 160 | -620
SS-14 | 1 korrus | Kipsplaat - Veekindel (2), Teras | 0,3 | -620; Kõrgus: 3 520; 3D pikkus: 1 040 | -620
2 x SS-14 | 1 korrus | Kipsplaat - Veekindel (2), Teras | 0,3 | -620; Kõrgus: 3 520; 3D pikkus: 1 150 | -620
SS-14 | 1 korrus | Kipsplaat - Veekindel (2), Teras | 0,3 | -620; Kõrgus: 3 244; 3D pikkus: 1 270 | -620
SS-14 | 1,5 korrus | Kipsplaat - Veekindel (2), Teras | 0,3 | 1 780; Kõrgus: 3 020; 3D pikkus: 1 050 | 1 780
SS-14 | 2 korrus | Kipsplaat - Veekindel (2), Teras | 0,3 | 5 195; Kõrgus: 3 520; 3D pikkus: 1 023 | 5 195
2 x SS-14 | 2 korrus | Kipsplaat - Veekindel (2), Teras | 0,4 | 5 195; Kõrgus: 3 520; 3D pikkus: 1 215 | 5 195
SS-14 | 2 korrus | Teras, Kipsplaat - Veekindel (2) | 0,5 | 5 195; Kõrgus: 3 520; 3D pikkus: 1 775 | 5 195
SS-14 | 2 korrus | Kipsplaat - Veekindel (2), Teras | 0,5 | 5 195; Kõrgus: 3 520; 3D pikkus: 1 592 | 5 195
SS-14 | 2 korrus | Kipsplaat - Veekindel (2), Teras | 0,4 | 5 195; Kõrgus: 3 520; 3D pikkus: 1 535 | 5 195

# IfcWall: SS-15 (3)
In: 1,5 korrus
Type - ElementType: Element type SS-15
Classification: 1.18 IfcWall (sein) (_RKAS BIM + ARCHICAD Classification); Material: Krohv - Lubjakivi (2), Puitplaat (2), Õhkvahe
Arhitektuur - 01 Nimetus: Sisesein; 02 Materjal: Siseviimistlus; Lubikrohv 10mm; Puitlaastplaat 12mm; C-profiilis karkass; Puitlaastplaat 12mm; Lubikrohv 10mm; Siseviimistlus; 03 Tähistus: SS-15; 04 Tulepüsivus: nõudeid ei esitata; 05 Asukoht: Interior; 07 Helipidavus: -; 08 Soojusläbivus (U-arv): -
Ehituskonstruktsioonid - 03 Tähistus või ristlõige: SS-15
AC_Pset_RenovationAndPhasing - Renovation Status: New
Pset_WallCommon - IsExternal: no
Name | 06 Kandevelementide eristatus | 06 Maht (kubatuur) | 11 Ülemine kõrgusmärk | 12 Alumine kõrgusmärk | LoadBearing
SS-15 | Load-Bearing Element | 0,4 | 4 290; Kõrgus: 510; 3D pikkus: 2 280 | 4 290 | yes
SS-15 | Non-Load-Bearing Element | 0,5 | 4 100; Kõrgus: 700; 3D pikkus: 2 380 | 4 100 | no
SS-15 | Load-Bearing Element | 4,6 | 4 100; Kõrgus: 1 115; 3D pikkus: 20 470 | 4 100 | yes

# IfcWall: SS-16 (4)
Type - ElementType: Element type SS-16
Classification: 1.18 IfcWall (sein) (_RKAS BIM + ARCHICAD Classification)
Arhitektuur - 01 Nimetus: Sisesein; 03 Tähistus: SS-16; 04 Tulepüsivus: nõudeid ei esitata; 05 Asukoht: Interior; 06 Kandevelementide eristatus: Non-Load-Bearing Element; 07 Helipidavus: -; 08 Soojusläbivus (U-arv): -
Ehituskonstruktsioonid - 03 Tähistus või ristlõige: SS-16
AC_Pset_RenovationAndPhasing - Renovation Status: New
Pset_WallCommon - LoadBearing: no; IsExternal: no
Name | In | Material | 02 Materjal | 06 Maht (kubatuur) | 11 Ülemine kõrgusmärk | 12 Alumine kõrgusmärk
SS-16 | 1,5 korrus | Krohv - Lubjakivi (2), Puitplaat (2), Õhkvahe | Siseviimistlus; Lubikrohv 10mm; Puitlaastplaat 12mm; C-profiilis karkass; Puitlaastplaat 12mm; Lubikrohv 10mm; Siseviimistlus | 1,3 | 4 000; Kõrgus: 745; 3D pikkus: 4 075 | 4 000
SS-16 | 1,5 korrus | Krohv - Lubjakivi (2), Puitplaat (2), Õhkvahe | Siseviimistlus; Lubikrohv 10mm; Puitlaastplaat 12mm; C-profiilis karkass; Puitlaastplaat 12mm; Lubikrohv 10mm; Siseviimistlus | 1,7 | 4 000; Kõrgus: 745; 3D pikkus: 5 285 | 4 000
SS-13 | 1,5 korrus | Krohv - Lubjakivi (2), Raudbetoon - Konstruktsioon | Siseviimistlus; Lubikrohv 10mm; Monteeritav raudbetoonsein 300mm; Lubikrohv 10mm; Siseviimistlus | 1,0 | 4 300; Kõrgus: 500; 3D pikkus: 4 720 | 4 300
SS-16 | 2 korrus | Krohv - Lubjakivi (2), Puitplaat (2), Õhkvahe | Siseviimistlus; Lubikrohv 10mm; Puitlaastplaat 12mm; C-profiilis karkass; Puitlaastplaat 12mm; Lubikrohv 10mm; Siseviimistlus | 0,5 | 8 015; Kõrgus: 700; 3D pikkus: 1 810 | 8 015

# IfcWall: VS-01 (34)
Type - ElementType: Element type VS-01
Classification: 1.18 IfcWall (sein) (_RKAS BIM + ARCHICAD Classification)
Arhitektuur - 01 Nimetus: Välissein; 03 Tähistus: VS-01; 04 Tulepüsivus: nõudeid ei esitata; 05 Asukoht: Exterior; 06 Kandevelementide eristatus: Load-Bearing Element; 07 Helipidavus: 60 dB
Ehituskonstruktsioonid - 03 Tähistus või ristlõige: VS-01
AC_Pset_RenovationAndPhasing - Renovation Status: New
Pset_WallCommon - LoadBearing: yes; IsExternal: yes
Name | In | Material | 02 Materjal | 08 Soojusläbivus (U-arv) | 06 Maht (kubatuur) | 11 Ülemine kõrgusmärk | 12 Alumine kõrgusmärk
VS-01 | 0 korrus | Krohv - Lubjakivi, Raudbetoon - Toode, Soojustus - Plastik Kõva (2), Õhkvahe, Puit - Konstruktsioon (2) | Siseviimistlus; Lubikrohv 10mm; Raudbetoonpaneel 200mm; PIR isolatsioonimaterjal 150mm; Tuletõkke PIR isolatsioonimaterjal 50mm; Vertikaalroovitis 20mm; Horisontaalroovitis 22mm; Laudis 22mm; Puitribid 28x28...50x250mm | 0,11 W/m2K | 1,2 | -688; Kõrgus: 2 073; 3D pikkus: 1 300 | -688
VS-01 | 0 korrus | Puit - Konstruktsioon (2), Õhkvahe, Soojustus - Plastik Kõva (2), Raudbetoon - Toode, Krohv - Lubjakivi | Siseviimistlus; Lubikrohv 10mm; Raudbetoonpaneel 200mm; PIR isolatsioonimaterjal 150mm; Tuletõkke PIR isolatsioonimaterjal 50mm; Vertikaalroovitis 20mm; Horisontaalroovitis 22mm; Laudis 22mm; Puitribid 28x28...50x250mm | 0,11 W/m2K | 0,7 | -634; Kõrgus: 2 019; 3D pikkus: 675 | -634
VS-01 | 0 korrus | Puit - Konstruktsioon (2), Õhkvahe, Soojustus - Plastik Kõva (2), Raudbetoon - Toode, Krohv - Lubjakivi | Siseviimistlus; Lubikrohv 10mm; Raudbetoonpaneel 200mm; PIR isolatsioonimaterjal 150mm; Tuletõkke PIR isolatsioonimaterjal 50mm; Vertikaalroovitis 20mm; Horisontaalroovitis 22mm; Laudis 22mm; Puitribid 28x28...50x250mm | 0,11 W/m2K | 8,2 | -1 615; Kõrgus: 3 000; 3D pikkus: 18 010 | -1 615
VS-01 | 0 korrus | Puit - Konstruktsioon (2), Õhkvahe, Soojustus - Plastik Kõva (2), Raudbetoon - Toode, Krohv - Lubjakivi | Siseviimistlus; Lubikrohv 10mm; Raudbetoonpaneel 200mm; PIR isolatsioonimaterjal 150mm; Tuletõkke PIR isolatsioonimaterjal 50mm; Vertikaalroovitis 20mm; Horisontaalroovitis 22mm; Laudis 22mm; Puitribid 28x28...50x250mm | 0,11 W/m2K | 0,8 | 935; Kõrgus: 450; 3D pikkus: 3 465 | 935
VS-01 | 0 korrus | Puit - Konstruktsioon (2), Õhkvahe, Soojustus - Plastik Kõva (2), Raudbetoon - Toode, Krohv - Lubjakivi | Siseviimistlus; Lubikrohv 10mm; Raudbetoonpaneel 200mm; PIR isolatsioonimaterjal 150mm; Tuletõkke PIR isolatsioonimaterjal 50mm; Vertikaalroovitis 20mm; Horisontaalroovitis 22mm; Laudis 22mm; Puitribid 28x28...50x250mm | 0,11 W/m2K | 0,8 | 935; Kõrgus: 450; 3D pikkus: 3 450 | 935
VS-01 | 0 korrus | Puit - Konstruktsioon (2), Õhkvahe, Soojustus - Plastik Kõva (2), Raudbetoon - Toode, Krohv - Lubjakivi | Siseviimistlus; Lubikrohv 10mm; Raudbetoonpaneel 200mm; PIR isolatsioonimaterjal 150mm; Tuletõkke PIR isolatsioonimaterjal 50mm; Vertikaalroovitis 20mm; Horisontaalroovitis 22mm; Laudis 22mm; Puitribid 28x28...50x250mm | 0,11 W/m2K | 0,8 | -1 365; Kõrgus: 2 750; 3D pikkus: 675 | -1 365
VS-01 | 0 korrus | Puit - Konstruktsioon (2), Õhkvahe, Soojustus - Plastik Kõva (2), Raudbetoon - Toode, Krohv - Lubjakivi | Siseviimistlus; Lubikrohv 10mm; Raudbetoonpaneel 200mm; PIR isolatsioonimaterjal 150mm; Tuletõkke PIR isolatsioonimaterjal 50mm; Vertikaalroovitis 20mm; Horisontaalroovitis 22mm; Laudis 22mm; Puitribid 28x28...50x250mm | 0,11 W/m2K | 0,6 | 935; Kõrgus: 450; 3D pikkus: 2 580 | 935
VS-01 | 1 korrus | Puit - Konstruktsioon (2), Õhkvahe, Soojustus - Plastik Kõva (2), Raudbetoon - Toode, Krohv - Lubjakivi | Siseviimistlus; Mineraalkrohv 10mm; Raudbetoonpaneel 200mm; PIR isolatsioonimaterjal 150mm; Tuletõkke PIR isolatsioonimaterjal 50mm; Vertikaalroovitis 20mm; Horisontaalroovitis 22mm; Laudis 22mm; Puitribid 28x28...50x250mm | 0,11 W/m2K | 2,7 | 100; Kõrgus: 4 700; 3D pikkus: 5 215 | 100
VS-01 | 1 korrus | Puit - Konstruktsioon (4), Õhkvahe (2), Soojustus - Plastik Kõva (4), Raudbetoon - Toode (2), Krohv - Lubjakivi (3) | Siseviimistlus; Mineraalkrohv 10mm; Raudbetoonpaneel 200mm; PIR isolatsioonimaterjal 150mm; Tuletõkke PIR isolatsioonimaterjal 50mm; Vertikaalroovitis 20mm; Horisontaalroovitis 22mm; Laudis 22mm; Puitribid 28x28...50x250mm | 0,11 W/m2K | 35,1 | 100; Kõrgus: 4 700; 3D pikkus: 20 942 | 100
VS-01 | 1 korrus | Puit - Konstruktsioon (2), Õhkvahe, Soojustus - Plastik Kõva (2), Raudbetoon - Toode (3), Krohv - Lubjakivi (4) | Siseviimistlus; Lubikrohv 10mm; SW r/b element 200mm; PIR soojusisolatsioon 150mm; PIR väline soojusisolatsioon; 50mm; Vertikaalsed roovid 45mm; Horisontaalsed roovid 22mm; Fassaadiplaat 8mm | 0,11 W/m2K | 6,2 | 4 100; Kõrgus: 700; 3D pikkus: 18 347 | 4 100
VS-06 | 1 korrus | Krohv - Lubjakivi, Raudbetoon - Konstruktsioon, Soojustus - Plastik Kõva (2), Puit - Konstruktsioon, Alumiinium, Plaat - Sein | Siseviimistlus; Lubikrohv 10mm; SW r/b element 200mm; PIR soojusisolatsioon 150mm; Tuletõkke PIR väline soojusisolatsioon 50mm; Vertikaalsed roovid 45mm; Horisontaalsed roovid 22mm; Fassaadiplaat 8mm | 0,11 W/m2K | 0,4 | 434; Kõrgus: 1 216; 3D pikkus: 967 | 434
VS-01 | 1 korrus | Puit - Konstruktsioon (2), Õhkvahe, Soojustus - Plastik Kõva (2), Raudbetoon - Toode, Krohv - Lubjakivi | Siseviimistlus; Mineraalkrohv 10mm; Raudbetoonpaneel 200mm; PIR isolatsioonimaterjal 150mm; Tuletõkke PIR isolatsioonimaterjal 50mm; Vertikaalroovitis 20mm; Horisontaalroovitis 22mm; Laudis 22mm; Puitribid 28x28...50x250mm | 0,11 W/m2K | 2,1 | 100; Kõrgus: 4 325; 3D pikkus: 1 295 | 100
VS-01 | 1 korrus | Krohv - Lubjakivi (7), Raudbetoon - Toode (3), Soojustus - Plastik Kõva (2), Õhkvahe, Puit - Konstruktsioon (2) | Siseviimistlus; Mineraalkrohv 10mm; Raudbetoonpaneel 200mm; PIR isolatsioonimaterjal 150mm; Tuletõkke PIR isolatsioonimaterjal 50mm; Vertikaalroovitis 20mm; Horisontaalroovitis 22mm; Laudis 22mm; Puitribid 28x28...50x250mm | 0,11 W/m2K | 11,2 | 0; Kõrgus: 1 330; 3D pikkus: 30 830 | 0
VS-01 | 1 korrus | Puit - Konstruktsioon (4), Õhkvahe (2), Soojustus - Plastik Kõva (4), Raudbetoon - Toode (3), Krohv - Lubjakivi (2) | Siseviimistlus; Mineraalkrohv 10mm; Raudbetoonpaneel 200mm; PIR isolatsioonimaterjal 150mm; Tuletõkke PIR isolatsioonimaterjal 50mm; Vertikaalroovitis 20mm; Horisontaalroovitis 22mm; Laudis 22mm; Puitribid 28x28...50x250mm | 0,11 W/m2K | 29,8 | 100; Kõrgus: 4 645; 3D pikkus: 13 572 | 100
VS-01 | 1,5 korrus | Puit - Konstruktsioon (2), Õhkvahe, Soojustus - Plastik Kõva (2), Raudbetoon - Toode, Krohv - Lubjakivi (3) | Siseviimistlus; Mineraalkrohv 10mm; Raudbetoonpaneel 200mm; PIR isolatsioonimaterjal 150mm; Tuletõkke PIR isolatsioonimaterjal 50mm; Vertikaalroovitis 20mm; Horisontaalroovitis 22mm; Laudis 22mm; Puitribid 28x28...50x250mm | 0,11 W/m2K | 16,6 | 1 385; Kõrgus: 3 415; 3D pikkus: 17 910 | 1 385
VS-01 | 1,5 korrus | Puit - Konstruktsioon (2), Õhkvahe, Soojustus - Plastik Kõva (2), Raudbetoon - Toode, Krohv - Lubjakivi | Raudbetoonpaneel 200mm; PIR isolatsioonimaterjal 150mm; Tuletõkke PIR isolatsioonimaterjal 50mm; Vertikaalroovitis 45x70mm (samm 600mm); Horisontaalroovitis 20x70mm (samm 600mm); Laudis 22mm; Puitribid 28x28...50x250mm | 0,11 W/m2K | 19,8 | 50; Kõrgus: 6 400; 3D pikkus: 8 390 | 50
VS-01 | 1,5 korrus | Puit - Konstruktsioon (2), Õhkvahe, Soojustus - Plastik Kõva (2), Raudbetoon - Toode, Krohv - Lubjakivi (4) | Siseviimistlus; Mineraalkrohv 10mm; Raudbetoonpaneel 200mm; PIR isolatsioonimaterjal 150mm; Tuletõkke PIR isolatsioonimaterjal 50mm; Vertikaalroovitis 20mm; Horisontaalroovitis 22mm; Laudis 22mm; Puitribid 28x28...50x250mm | 0,11 W/m2K | 12,7 | 1 385; Kõrgus: 3 415; 3D pikkus: 12 130 | 1 385
VS-01 | 1,5 korrus | Puit - Konstruktsioon (2), Õhkvahe, Soojustus - Plastik Kõva (2), Raudbetoon - Toode, Krohv - Lubjakivi (11) | Siseviimistlus; Mineraalkrohv 10mm; Raudbetoonpaneel 200mm; PIR isolatsioonimaterjal 150mm; Tuletõkke PIR isolatsioonimaterjal 50mm; Vertikaalroovitis 20mm; Horisontaalroovitis 22mm; Laudis 22mm; Puitribid 28x28...50x250mm | 0,11 W/m2K | 35,7 | 1 330; Kõrgus: 3 470; 3D pikkus: 29 800 | 1 330
VS-01 | 2 korrus | Puit - Konstruktsioon (2), Õhkvahe, Soojustus - Plastik Kõva (2), Raudbetoon - Toode, Krohv - Lubjakivi | Raudbetoonpaneel 200mm; PIR isolatsioonimaterjal 150mm; Tuletõkke PIR isolatsioonimaterjal 50mm; Vertikaalroovitis 45x70mm (samm 600mm); Horisontaalroovitis 20x70mm (samm 600mm); Laudis 22mm; Puitribid 28x28...50x250mm | 0,11W/m2K | 30,8 | 4 800; Kõrgus: 4 180; 3D pikkus: 21 274 | 4 800
VS-01 | 2 korrus | Puit - Konstruktsioon (2), Õhkvahe, Soojustus - Plastik Kõva (2), Raudbetoon - Toode, Krohv - Lubjakivi (5) | Raudbetoonpaneel 200mm; PIR isolatsioonimaterjal 150mm; Tuletõkke PIR isolatsioonimaterjal 50mm; Vertikaalroovitis 45x70mm (samm 600mm); Horisontaalroovitis 20x70mm (samm 600mm); Laudis 22mm; Puitribid 28x28...50x250mm | 0,11W/m2K | 30,0 | 4 745; Kõrgus: 4 235; 3D pikkus: 17 352 | 4 745
VS-01 | 2 korrus | Puit - Konstruktsioon (2), Õhkvahe, Soojustus - Plastik Kõva (2), Raudbetoon - Toode, Krohv - Lubjakivi (10) | Raudbetoonpaneel 200mm; PIR isolatsioonimaterjal 150mm; Tuletõkke PIR isolatsioonimaterjal 50mm; Vertikaalroovitis 45x70mm (samm 600mm); Horisontaalroovitis 20x70mm (samm 600mm); Laudis 22mm; Puitribid 28x28...50x250mm | 0,11W/m2K | 46,7 | 4 425; Kõrgus: 4 555; 3D pikkus: 31 662 | 4 425
VS-01 | 2 korrus | Puit - Konstruktsioon (2), Õhkvahe, Soojustus - Plastik Kõva (2), Raudbetoon - Toode, Krohv - Lubjakivi | Siseviimistlus; Lubikrohv 10mm; SW r/b element 200mm; PIR soojusisolatsioon 150mm; PIR väline soojusisolatsioon; 50mm; Vertikaalsed roovid 45mm; Horisontaalsed roovid 22mm; Fassaadiplaat 8mm | 0,11 W/m2K | 0,7 | 3 795; Kõrgus: 630; 3D pikkus: 2 285 | 3 795
VS-01 | 2 korrus | Puit - Konstruktsioon (2), Õhkvahe, Soojustus - Plastik Kõva (2), Raudbetoon - Toode (2), Krohv - Lubjakivi | Siseviimistlus; Lubikrohv 10mm; SW r/b element 200mm; PIR soojusisolatsioon 150mm; PIR väline soojusisolatsioon; 50mm; Vertikaalsed roovid 45mm; Horisontaalsed roovid 22mm; Fassaadiplaat 8mm | 0,11 W/m2K | 1,0 | 3 795; Kõrgus: 630; 3D pikkus: 3 322 | 3 795
VS-01 | 2 korrus | Puit - Konstruktsioon (2), Õhkvahe, Soojustus - Plastik Kõva (2), Raudbetoon - Toode, Krohv - Lubjakivi | Siseviimistlus; Mineraalkrohv 10mm; Raudbetoonpaneel 200mm; PIR isolatsioonimaterjal 150mm; Tuletõkke PIR isolatsioonimaterjal 50mm; Vertikaalroovitis 20mm; Horisontaalroovitis 22mm; Laudis 22mm; Puitribid 28x28...50x250mm | 0,11 W/m2K | 0,2 | 2 862; Kõrgus: 473; 3D pikkus: 1 091 | 2 862
VS-01 | 2 korrus | Puit - Konstruktsioon (2), Õhkvahe, Soojustus - Plastik Kõva (2), Raudbetoon - Toode, Krohv - Lubjakivi | Siseviimistlus; Mineraalkrohv 10mm; Raudbetoonpaneel 200mm; PIR isolatsioonimaterjal 150mm; Tuletõkke PIR isolatsioonimaterjal 50mm; Vertikaalroovitis 20mm; Horisontaalroovitis 22mm; Laudis 22mm; Puitribid 28x28...50x250mm | 0,11 W/m2K | 0,8 | 2 410; Kõrgus: 1 690; 3D pikkus: 1 140 | 2 410
VS-01 | 2 korrus | Puit - Konstruktsioon (2), Õhkvahe, Soojustus - Plastik Kõva (2), Raudbetoon - Toode, Krohv - Lubjakivi (2) | Raudbetoonpaneel 200mm; PIR isolatsioonimaterjal 150mm; Tuletõkke PIR isolatsioonimaterjal 50mm; Vertikaalroovitis 45x70mm (samm 600mm); Horisontaalroovitis 20x70mm (samm 600mm); Laudis 22mm; Puitribid 28x28...50x250mm | 0,11W/m2K | 17,4 | 4 800; Kõrgus: 4 180; 3D pikkus: 8 390 | 4 800
VS-01 | 2 korrus | Puit - Konstruktsioon (2), Õhkvahe, Soojustus - Plastik Kõva (2), Raudbetoon - Toode, Krohv - Lubjakivi | Raudbetoonpaneel 200mm; PIR isolatsioonimaterjal 150mm; Tuletõkke PIR isolatsioonimaterjal 50mm; Vertikaalroovitis 45x70mm (samm 600mm); Horisontaalroovitis 20x70mm (samm 600mm); Laudis 22mm; Puitribid 28x28...50x250mm | 0,11W/m2K | 3,2 | 4 800; Kõrgus: 4 180; 3D pikkus: 2 182 | 4 800
VS-01 | 2 korrus | Puit - Konstruktsioon (2), Õhkvahe, Soojustus - Plastik Kõva (2), Raudbetoon - Toode, Krohv - Lubjakivi (2) | Raudbetoonpaneel 200mm; PIR isolatsioonimaterjal 150mm; Tuletõkke PIR isolatsioonimaterjal 50mm; Vertikaalroovitis 45x70mm (samm 600mm); Horisontaalroovitis 20x70mm (samm 600mm); Laudis 22mm; Puitribid 28x28...50x250mm | 0,11W/m2K | 15,3 | 4 800; Kõrgus: 4 180; 3D pikkus: 12 350 | 4 800
VS-01 | 2 korrus | Krohv - Lubjakivi, Raudbetoon - Toode, Soojustus - Plastik Kõva (2), Õhkvahe, Puit - Konstruktsioon (2) | Raudbetoonpaneel 200mm; PIR isolatsioonimaterjal 150mm; Tuletõkke PIR isolatsioonimaterjal 50mm; Vertikaalroovitis 45x70mm (samm 600mm); Horisontaalroovitis 20x70mm (samm 600mm); Laudis 22mm; Puitribid 28x28...50x250mm | 0,11W/m2K | 12,1 | 4 800; Kõrgus: 4 180; 3D pikkus: 8 720 | 4 800
VS-01 | 2 korrus | Puit - Konstruktsioon (2), Õhkvahe, Soojustus - Plastik Kõva (2), Raudbetoon - Toode, Krohv - Lubjakivi (2) | Raudbetoonpaneel 200mm; PIR isolatsioonimaterjal 150mm; Tuletõkke PIR isolatsioonimaterjal 50mm; Vertikaalroovitis 45x70mm (samm 600mm); Horisontaalroovitis 20x70mm (samm 600mm); Laudis 22mm; Puitribid 28x28...50x250mm | 0,11W/m2K | 5,6 | 4 800; Kõrgus: 4 180; 3D pikkus: 3 680 | 4 800
VS-01 | 2 korrus | Puit - Konstruktsioon (2), Õhkvahe, Soojustus - Plastik Kõva (2), Raudbetoon - Toode, Krohv - Lubjakivi (3) | Raudbetoonpaneel 200mm; PIR isolatsioonimaterjal 150mm; Tuletõkke PIR isolatsioonimaterjal 50mm; Vertikaalroovitis 45x70mm (samm 600mm); Horisontaalroovitis 20x70mm (samm 600mm); Laudis 22mm; Puitribid 28x28...50x250mm | 0,11W/m2K | 41,0 | 4 800; Kõrgus: 4 180; 3D pikkus: 29 600 | 4 800
VS-01 | 2 korrus | Puit - Konstruktsioon (2), Õhkvahe, Soojustus - Plastik Kõva (2), Raudbetoon - Toode, Krohv - Lubjakivi (2) | Raudbetoonpaneel 200mm; PIR isolatsioonimaterjal 150mm; Tuletõkke PIR isolatsioonimaterjal 50mm; Vertikaalroovitis 45x70mm (samm 600mm); Horisontaalroovitis 20x70mm (samm 600mm); Laudis 22mm; Puitribid 28x28...50x250mm | 0,11W/m2K | 25,1 | 4 800; Kõrgus: 4 180; 3D pikkus: 17 570 | 4 800
VS-01 | 2 korrus | Puit - Konstruktsioon (2), Õhkvahe, Soojustus - Plastik Kõva (2), Raudbetoon - Toode, Krohv - Lubjakivi (7) | Raudbetoonpaneel 200mm; PIR isolatsioonimaterjal 150mm; Tuletõkke PIR isolatsioonimaterjal 50mm; Vertikaalroovitis 45x70mm (samm 600mm); Horisontaalroovitis 20x70mm (samm 600mm); Laudis 22mm; Puitribid 28x28...50x250mm | 0,11W/m2K | 24,3 | 4 745; Kõrgus: 4 235; 3D pikkus: 18 010 | 4 745
VS-01 | 2 korrus | Puit - Konstruktsioon (2), Õhkvahe, Soojustus - Plastik Kõva (2), Raudbetoon - Toode, Krohv - Lubjakivi | Siseviimistlus; Lubikrohv 10mm; SW r/b element 200mm; PIR soojusisolatsioon 150mm; PIR väline soojusisolatsioon; 50mm; Vertikaalsed roovid 45mm; Horisontaalsed roovid 22mm; Fassaadiplaat 8mm | 0,11 W/m2K | 1,4 | 3 335; Kõrgus: 1 260; 3D pikkus: 2 296 | 3 335

# IfcWall: VS-01* (8)
Type - ElementType: Element type VS-01*
Classification: 1.18 IfcWall (sein) (_RKAS BIM + ARCHICAD Classification)
Arhitektuur - 01 Nimetus: Välissein; 03 Tähistus: VS-01*; 04 Tulepüsivus: nõudeid ei esitata; 05 Asukoht: Exterior; 06 Kandevelementide eristatus: Load-Bearing Element; 07 Helipidavus: 60 dB
Ehituskonstruktsioonid - 03 Tähistus või ristlõige: VS-01*
AC_Pset_RenovationAndPhasing - Renovation Status: New
Pset_WallCommon - LoadBearing: yes; IsExternal: yes
Name | In | Material | 02 Materjal | 08 Soojusläbivus (U-arv) | 06 Maht (kubatuur) | 11 Ülemine kõrgusmärk | 12 Alumine kõrgusmärk
VS-01* | 0 korrus | Raudbetoon - Toode, Soojustus - Plastik Kõva (2), Õhkvahe, Puit - Konstruktsioon (2) | Raudbetoonpaneel 200mm; PIR isolatsioonimaterjal 150mm; Tuletõkke PIR isolatsioonimaterjal 50mm; Vertikaalroovitis 20mm; Horisontaalroovitis 22mm; Laudis 22mm; Puitribid 28x28...50x250mm | 0,11 W/m2K | 1,0 | -2 030; Kõrgus: 3 415; 3D pikkus: 1 420 | -2 030
VS-06 | 1 korrus | Krohv - Lubjakivi (2), Raudbetoon - Konstruktsioon, Soojustus - Plastik Kõva (2), Puit - Konstruktsioon, Alumiinium, Plaat - Sein | Raudbetoonpaneel 200mm; PIR isolatsioonimaterjal 150mm; Tuletõkke PIR isolatsioonimaterjal 50mm; Vertikaalroovitis 20mm; Horisontaalroovitis 22mm; Laudis 22mm; Puitribid 28x28...50x250mm | 0,11 W/m2K | 0,5 | 50; Kõrgus: 1 280; 3D pikkus: 800 | 50
VS-01* | 1 korrus | Puit - Konstruktsioon (2), Õhkvahe, Soojustus - Plastik Kõva (2), Raudbetoon - Toode | Raudbetoonpaneel 200mm; PIR isolatsioonimaterjal 150mm; Tuletõkke PIR isolatsioonimaterjal 50mm; Vertikaalroovitis 20mm; Horisontaalroovitis 22mm; Laudis 22mm; Puitribid 28x28...50x250mm | 0,11 W/m2K | 12,9 | 100; Kõrgus: 4 700; 3D pikkus: 6 540 | 100
VS-01* | 1,5 korrus | Puit - Konstruktsioon (2), Õhkvahe, Soojustus - Plastik Kõva (2), Raudbetoon - Toode | Raudbetoonpaneel 200mm; PIR isolatsioonimaterjal 150mm; Tuletõkke PIR isolatsioonimaterjal 50mm; Vertikaalroovitis 20mm; Horisontaalroovitis 22mm; Laudis 22mm; Puitribid 28x28...50x250mm | 0,11 W/m2K | 2,0 | 1 330; Kõrgus: 3 470; 3D pikkus: 1 210 | 1 330
VS-01* | 1,5 korrus | Puit - Konstruktsioon (2), Õhkvahe, Soojustus - Plastik Kõva (2), Raudbetoon - Toode | Raudbetoonpaneel 200mm; PIR isolatsioonimaterjal 150mm; Tuletõkke PIR isolatsioonimaterjal 50mm; Vertikaalroovitis 20mm; Horisontaalroovitis 22mm; Laudis 22mm; Puitribid 28x28...50x250mm | 0,11 W/m2K | 0,7 | 1 330; Kõrgus: 3 470; 3D pikkus: 620 | 1 330
VS-01* | 1,5 korrus | Puit - Konstruktsioon (2), Õhkvahe, Soojustus - Plastik Kõva (2), Raudbetoon - Toode | Raudbetoonpaneel 200mm; PIR isolatsioonimaterjal 150mm; Tuletõkke PIR isolatsioonimaterjal 50mm; Vertikaalroovitis 20mm; Horisontaalroovitis 22mm; Laudis 22mm; Puitribid 28x28...50x250mm | 0,11 W/m2K | 2,1 | 1 385; Kõrgus: 3 360; 3D pikkus: 1 260 | 1 385
VS-01* | 2 korrus | Puit - Konstruktsioon (2), Õhkvahe, Soojustus - Plastik Kõva (2), Raudbetoon - Toode | Raudbetoonpaneel 200mm; PIR isolatsioonimaterjal 150mm; Tuletõkke PIR isolatsioonimaterjal 50mm; Vertikaalroovitis 45x70mm (samm 600mm); Horisontaalroovitis 20x70mm (samm 600mm); Laudis 22mm; Puitribid 28x28...50x250mm | 0,11W/m2K | 0,9 | 4 800; Kõrgus: 4 180; 3D pikkus: 620 | 4 800
VS-01* | 2 korrus | Raudbetoon - Toode, Soojustus - Plastik Kõva (2), Õhkvahe, Puit - Konstruktsioon (2) | Raudbetoonpaneel 200mm; PIR isolatsioonimaterjal 150mm; Tuletõkke PIR isolatsioonimaterjal 50mm; Vertikaalroovitis 45x70mm (samm 600mm); Horisontaalroovitis 20x70mm (samm 600mm); Laudis 22mm; Puitribid 28x28...50x250mm | 0,11W/m2K | 2,4 | 4 745; Kõrgus: 4 235; 3D pikkus: 1 210 | 4 745

# IfcWall: VS-03 (26)
Type - ElementType: Element type VS-03
Arhitektuur - 01 Nimetus: Välissein; 03 Tähistus: VS-03; 04 Tulepüsivus: nõudeid ei esitata; 05 Asukoht: Exterior; 06 Kandevelementide eristatus: Load-Bearing Element
Ehituskonstruktsioonid - 03 Tähistus või ristlõige: VS-03
AC_Pset_RenovationAndPhasing - Renovation Status: New
Pset_WallCommon - LoadBearing: yes; IsExternal: yes
Name | In | Classification | Material | 02 Materjal | 07 Helipidavus | 08 Soojusläbivus (U-arv) | 06 Maht (kubatuur) | 11 Ülemine kõrgusmärk | 12 Alumine kõrgusmärk
VS-03 | 0 korrus | 1.18 IfcWall (sein) (_RKAS BIM + ARCHICAD Classification) | Membraan - Veekindel (2), Soojustus - Plastik Kõva (2), Raudbetoon - Konstruktsioon, Krohv - Lubjakivi | Siseviimistlus; Lubikrohv 10mm; Monteeritav r/bet. seinapaneel 200mm; SBS bituumenhüdroisolatsioon; Vahtpolüstüreen soojustus EPS120 PERIMEETER 50+150mm; drenaazhimatt; Geotekstiil; Tihendatud pinnas (kesliiv) | 60 dB | 0,18 W/m2K | 16,4 | -2 235; Kõrgus: 2 085; 3D pikkus: 18 970 | -2 235
VS-03 | 0 korrus | 1.18 IfcWall (sein) (_RKAS BIM + ARCHICAD Classification) | Krohv - Lubjakivi, Raudbetoon - Konstruktsioon, Soojustus - Plastik Kõva (2), Membraan - Veekindel (2) | Siseviimistlus; Lubikrohv 10mm; Monteeritav r/bet. seinapaneel 200mm; SBS bituumenhüdroisolatsioon; Vahtpolüstüreen soojustus EPS120 PERIMEETER 50+150mm; drenaazhimatt; Geotekstiil; Tihendatud pinnas (kesliiv) | 60 dB | 0,18 W/m2K | 7,4 | -2 235; Kõrgus: 2 479; 3D pikkus: 9 415 | -2 235
VS-03 | 0 korrus | 0 TELLIJA KULUD (EHITUSKULUDE LIIGITAMINE EVS 885:2005); 1.18 IfcWall (sein) (_RKAS BIM + ARCHICAD Classification) | Krohv - Lubjakivi, Raudbetoon - Konstruktsioon, Soojustus - Plastik Kõva (2), Membraan - Veekindel (2) | Siseviimistlus; Lubikrohv 10mm; Monteeritav r/bet. seinapaneel 200mm; SBS bituumenhüdroisolatsioon; Vahtpolüstüreen soojustus EPS120 PERIMEETER 50+150mm; drenaazhimatt; Geotekstiil; Tihendatud pinnas (kesliiv) | 60dB | 0,18W/m2K | 1,1 | -2 235; Kõrgus: 1 770; 3D pikkus: 3 010 | -2 235
VS-03 | 0 korrus | 1.18 IfcWall (sein) (_RKAS BIM + ARCHICAD Classification) | Krohv - Lubjakivi, Raudbetoon - Konstruktsioon, Soojustus - Plastik Kõva (2), Membraan - Veekindel (2) | Siseviimistlus; Lubikrohv 10mm; Monteeritav r/bet. seinapaneel 200mm; SBS bituumenhüdroisolatsioon; Vahtpolüstüreen soojustus EPS120 PERIMEETER 50+150mm; drenaazhimatt; Geotekstiil; Tihendatud pinnas (kesliiv) | 60dB | 0,18 W/m2K | 34,0 | -2 235; Kõrgus: 2 085; 3D pikkus: 39 115 | -2 235
VS-03 | 1 korrus | 1.18 IfcWall (sein) (_RKAS BIM + ARCHICAD Classification) | Krohv - Lubjakivi, Raudbetoon - Konstruktsioon, Soojustus - Plastik Kõva (2), Membraan - Veekindel (2) | Siseviimistlus; Lubikrohv 10mm; Monteeritav r/bet. seinapaneel 200mm; SBS bituumenhüdroisolatsioon; Vahtpolüstüreen soojustus EPS120 PERIMEETER 50+150mm; drenaazhimatt; Geotekstiil; Tihendatud pinnas (kesliiv) | 60 dB | 0,18 W/m2K | 2,7 | -1 220; Kõrgus: 3 430; 3D pikkus: 1 863 | -1 220
VS-03 | 1 korrus | 1.18 IfcWall (sein) (_RKAS BIM + ARCHICAD Classification) | Krohv - Lubjakivi, Raudbetoon - Konstruktsioon, Soojustus - Plastik Kõva (2), Membraan - Veekindel (2) | Siseviimistlus; Lubikrohv 10mm; Monteeritav r/bet. seinapaneel 200mm; SBS bituumenhüdroisolatsioon; Vahtpolüstüreen soojustus EPS120 PERIMEETER 50+150mm; drenaazhimatt; Geotekstiil; Tihendatud pinnas (kesliiv) | 60 dB | 0,18 W/m2K | 1,9 | -1 220; Kõrgus: 2 505; 3D pikkus: 1 830 | -1 220
VS-03 | 1 korrus | 1.18 IfcWall (sein) (_RKAS BIM + ARCHICAD Classification) | Membraan - Veekindel (2), Soojustus - Plastik Kõva (2), Raudbetoon - Konstruktsioon, Krohv - Lubjakivi | Siseviimistlus; Lubikrohv 10mm; Monteeritav r/bet. seinapaneel 200mm; SBS bituumenhüdroisolatsioon; Vahtpolüstüreen soojustus EPS120 PERIMEETER 50+150mm; drenaazhimatt; Geotekstiil; Tihendatud pinnas (kesliiv) | 60 dB | 0,18 W/m2K | 0,9 | -620; Kõrgus: 1 340; 3D pikkus: 1 575 | -620
VS-03 | 1 korrus | 1.18 IfcWall (sein) (_RKAS BIM + ARCHICAD Classification) | Krohv - Lubjakivi, Raudbetoon - Konstruktsioon, Soojustus - Plastik Kõva (2), Membraan - Veekindel (2) | Siseviimistlus; Lubikrohv 10mm; Monteeritav r/bet. seinapaneel 200mm; SBS bituumenhüdroisolatsioon; Vahtpolüstüreen soojustus EPS120 PERIMEETER 50+150mm; drenaazhimatt; Geotekstiil; Tihendatud pinnas (kesliiv) | 60 dB | 0,18 W/m2K | 2,3 | -1 220; Kõrgus: 2 970; 3D pikkus: 1 830 | -1 220
VS-03 | 1 korrus | 1.18 IfcWall (sein) (_RKAS BIM + ARCHICAD Classification) | Membraan - Veekindel (2), Soojustus - Plastik Kõva (2), Raudbetoon - Konstruktsioon, Krohv - Lubjakivi | Siseviimistlus; Lubikrohv 10mm; Monteeritav r/bet. seinapaneel 200mm; SBS bituumenhüdroisolatsioon; Vahtpolüstüreen soojustus EPS120 PERIMEETER 50+150mm; drenaazhimatt; Geotekstiil; Tihendatud pinnas (kesliiv) | 60 dB | 0,18 W/m2K | 0,2 | 1 703; Kõrgus: 657; 3D pikkus: 1 073 | 1 703
VS-03 | 1 korrus | 0 TELLIJA KULUD (EHITUSKULUDE LIIGITAMINE EVS 885:2005); 1.18 IfcWall (sein) (_RKAS BIM + ARCHICAD Classification) | Membraan - Veekindel (2), Soojustus - Plastik Kõva (2), Raudbetoon - Konstruktsioon, Krohv - Lubjakivi | Siseviimistlus; Lubikrohv 10mm; Monteeritav r/bet. seinapaneel 200mm; SBS bituumenhüdroisolatsioon; Vahtpolüstüreen soojustus EPS120 PERIMEETER 50+150mm; drenaazhimatt; Geotekstiil; Tihendatud pinnas (kesliiv) | 60 dB | 0,18 W/m2K | 0,4 | 1 983; Kõrgus: 787; 3D pikkus: 1 575 | 1 983
VS-03 | 1 korrus | 1.18 IfcWall (sein) (_RKAS BIM + ARCHICAD Classification) | Membraan - Veekindel (2), Soojustus - Plastik Kõva (2), Raudbetoon - Konstruktsioon, Krohv - Lubjakivi | Siseviimistlus; Lubikrohv 10mm; Monteeritav r/bet. seinapaneel 200mm; SBS bituumenhüdroisolatsioon; Vahtpolüstüreen soojustus EPS120 PERIMEETER 50+150mm; drenaazhimatt; Geotekstiil; Tihendatud pinnas (kesliiv) | 60 dB | 0,18 W/m2K | 0,6 | -620; Kõrgus: 930; 3D pikkus: 1 575 | -620
VS-03 | 1 korrus | 1.18 IfcWall (sein) (_RKAS BIM + ARCHICAD Classification) | Krohv - Lubjakivi, Raudbetoon - Konstruktsioon, Soojustus - Plastik Kõva (2), Membraan - Veekindel (2) | Siseviimistlus; Lubikrohv 10mm; Monteeritav r/bet. seinapaneel 200mm; SBS bituumenhüdroisolatsioon; Vahtpolüstüreen soojustus EPS120 PERIMEETER 50+150mm; drenaazhimatt; Geotekstiil; Tihendatud pinnas (kesliiv) | 60 dB | 0,18 W/m2K | 0,4 | -150; Kõrgus: 975; 3D pikkus: 945 | -150
VS-03 | 1 korrus | 1.18 IfcWall (sein) (_RKAS BIM + ARCHICAD Classification) | Membraan - Veekindel (2), Soojustus - Plastik Kõva (2), Raudbetoon - Konstruktsioon, Krohv - Lubjakivi | Siseviimistlus; Lubikrohv 10mm; Monteeritav r/bet. seinapaneel 200mm; SBS bituumenhüdroisolatsioon; Vahtpolüstüreen soojustus EPS120 PERIMEETER 50+150mm; drenaazhimatt; Geotekstiil; Tihendatud pinnas (kesliiv) | 60 dB | 0,18 W/m2K | 1,2 | -620; Kõrgus: 1 750; 3D pikkus: 1 575 | -620
VS-03 | 1 korrus | 1.18 IfcWall (sein) (_RKAS BIM + ARCHICAD Classification) | Membraan - Veekindel (2), Soojustus - Plastik Kõva (2), Raudbetoon - Konstruktsioon, Krohv - Lubjakivi | Siseviimistlus; Lubikrohv 10mm; Monteeritav r/bet. seinapaneel 200mm; SBS bituumenhüdroisolatsioon; Vahtpolüstüreen soojustus EPS120 PERIMEETER 50+150mm; drenaazhimatt; Geotekstiil; Tihendatud pinnas (kesliiv) | 60 dB | 0,18 W/m2K | 1,7 | -620; Kõrgus: 2 570; 3D pikkus: 1 575 | -620
VS-03 | 1 korrus | 1.18 IfcWall (sein) (_RKAS BIM + ARCHICAD Classification) | Krohv - Lubjakivi, Raudbetoon - Konstruktsioon, Soojustus - Plastik Kõva (2), Membraan - Veekindel (2) | Siseviimistlus; Lubikrohv 10mm; Monteeritav r/bet. seinapaneel 200mm; SBS bituumenhüdroisolatsioon; Vahtpolüstüreen soojustus EPS120 PERIMEETER 50+150mm; drenaazhimatt; Geotekstiil; Tihendatud pinnas (kesliiv) | 60 dB | 0,18 W/m2K | 0,4 | -150; Kõrgus: 510; 3D pikkus: 1 825 | -150
VS-03 | 1 korrus | 1.18 IfcWall (sein) (_RKAS BIM + ARCHICAD Classification) | Membraan - Veekindel (2), Soojustus - Plastik Kõva (2), Raudbetoon - Konstruktsioon, Krohv - Lubjakivi | Siseviimistlus; Lubikrohv 10mm; Monteeritav r/bet. seinapaneel 200mm; SBS bituumenhüdroisolatsioon; Vahtpolüstüreen soojustus EPS120 PERIMEETER 50+150mm; drenaazhimatt; Geotekstiil; Tihendatud pinnas (kesliiv) | 60 dB | 0,18 W/m2K | 1,4 | -620; Kõrgus: 2 160; 3D pikkus: 1 575 | -620
VS-03 | 1 korrus | 0 TELLIJA KULUD (EHITUSKULUDE LIIGITAMINE EVS 885:2005); 1.18 IfcWall (sein) (_RKAS BIM + ARCHICAD Classification) | Krohv - Lubjakivi, Raudbetoon - Konstruktsioon, Soojustus - Plastik Kõva (2), Membraan - Veekindel (2) | Siseviimistlus; Lubikrohv 10mm; Monteeritav r/bet. seinapaneel 200mm; SBS bituumenhüdroisolatsioon; Vahtpolüstüreen soojustus EPS120 PERIMEETER 50+150mm; drenaazhimatt; Geotekstiil; Tihendatud pinnas (kesliiv) | 60dB | 0,18 W/m2K | 27,7 | -1 220; Kõrgus: 3 181; 3D pikkus: 20 769 | -1 220
VS-03 | 1 korrus | 1.18 IfcWall (sein) (_RKAS BIM + ARCHICAD Classification) | Membraan - Veekindel (2), Soojustus - Plastik Kõva (2), Raudbetoon - Konstruktsioon, Krohv - Lubjakivi | Siseviimistlus; Lubikrohv 10mm; Monteeritav r/bet. seinapaneel 200mm; SBS bituumenhüdroisolatsioon; Vahtpolüstüreen soojustus EPS120 PERIMEETER 50+150mm; drenaazhimatt; Geotekstiil; Tihendatud pinnas (kesliiv) | 60 dB | 0,18 W/m2K | 0,6 | -620; Kõrgus: 2 980; 3D pikkus: 502 | -620
VS-03 | 1 korrus | 0 TELLIJA KULUD (EHITUSKULUDE LIIGITAMINE EVS 885:2005); 1.18 IfcWall (sein) (_RKAS BIM + ARCHICAD Classification) | Membraan - Veekindel (2), Soojustus - Plastik Kõva (2), Raudbetoon - Konstruktsioon, Krohv - Lubjakivi | Siseviimistlus; Lubikrohv 10mm; Monteeritav r/bet. seinapaneel 200mm; SBS bituumenhüdroisolatsioon; Vahtpolüstüreen soojustus EPS120 PERIMEETER 50+150mm; drenaazhimatt; Geotekstiil; Tihendatud pinnas (kesliiv) | 60 dB | 0,18 W/m2K | 0,4 | 2 808; Kõrgus: 787; 3D pikkus: 1 558 | 2 808
VS-03 | 1 korrus | 1.18 IfcWall (sein) (_RKAS BIM + ARCHICAD Classification) | Membraan - Veekindel (2), Soojustus - Plastik Kõva (2), Raudbetoon - Konstruktsioon, Krohv - Lubjakivi | Siseviimistlus; Lubikrohv 10mm; Monteeritav r/bet. seinapaneel 200mm; SBS bituumenhüdroisolatsioon; Vahtpolüstüreen soojustus EPS120 PERIMEETER 50+150mm; drenaazhimatt; Geotekstiil; Tihendatud pinnas (kesliiv) | 60 dB | 0,18 W/m2K | 0,4 | 2 393; Kõrgus: 787; 3D pikkus: 1 575 | 2 393
VS-03 | 1 korrus | 1.18 IfcWall (sein) (_RKAS BIM + ARCHICAD Classification) | Krohv - Lubjakivi, Raudbetoon - Konstruktsioon, Soojustus - Plastik Kõva (2), Membraan - Veekindel (2) | Siseviimistlus; Lubikrohv 10mm; Monteeritav r/bet. seinapaneel 200mm; SBS bituumenhüdroisolatsioon; Vahtpolüstüreen soojustus EPS120 PERIMEETER 50+150mm; drenaazhimatt; Geotekstiil; Tihendatud pinnas (kesliiv) | 60 dB | 0,18 W/m2K | 0,8 | -1 220; Kõrgus: 2 045; 3D pikkus: 885 | -1 220
VS-03 | 1 korrus | 0 TELLIJA KULUD (EHITUSKULUDE LIIGITAMINE EVS 885:2005); 1.18 IfcWall (sein) (_RKAS BIM + ARCHICAD Classification) | Membraan - Veekindel (2), Soojustus - Plastik Kõva (2), Raudbetoon - Konstruktsioon, Krohv - Lubjakivi (2) | Siseviimistlus; Lubikrohv 10mm; Monteeritav r/bet. seinapaneel 200mm; SBS bituumenhüdroisolatsioon; Vahtpolüstüreen soojustus EPS120 PERIMEETER 50+150mm; drenaazhimatt; Geotekstiil; Tihendatud pinnas (kesliiv) | 60 dB | 0,18 W/m2K | 0,2 | 3 200; Kõrgus: 395; 3D pikkus: 906 | 3 200
VS-05 | 1 korrus | 1.18 IfcWall (sein) (_RKAS BIM + ARCHICAD Classification) | Krohv - Lubjakivi, Raudbetoon - Konstruktsioon, Soojustus - Plastik Kõva (2), Plaat - Sein | Siseviimistlus; Lubikrohv 10mm; SW r/b element 200mm; Hüdroisolatsioon; PIR soojusisolatsioon 150mm; PIR väline soojusisolatsioon 50mm; Tsementkiudplaat Minerit Pastell Grafit95 8musta värvi) 8mm | ≥48 dB | 0,11 W/m2K | 0,0 | -100; Kõrgus: 100; 3D pikkus: 1 000 | -100
VS-05 | 1 korrus | 1.18 IfcWall (sein) (_RKAS BIM + ARCHICAD Classification) | Plaat - Sein, Soojustus - Plastik Kõva (2), Raudbetoon - Konstruktsioon, Krohv - Lubjakivi | Siseviimistlus; Lubikrohv 10mm; SW r/b element 200mm; Hüdroisolatsioon; PIR soojusisolatsioon 150mm; PIR väline soojusisolatsioon 50mm; Tsementkiudplaat Minerit Pastell Grafit95 8musta värvi) 8mm | ≥48 dB | 0,11 W/m2K | 0,1 | -100; Kõrgus: 100; 3D pikkus: 1 400 | -100
VS-05 | 1 korrus | 1.18 IfcWall (sein) (_RKAS BIM + ARCHICAD Classification) | Plaat - Sein, Soojustus - Plastik Kõva (2), Raudbetoon - Konstruktsioon, Krohv - Lubjakivi | Siseviimistlus; Lubikrohv 10mm; SW r/b element 200mm; Hüdroisolatsioon; PIR soojusisolatsioon 150mm; PIR väline soojusisolatsioon 50mm; Tsementkiudplaat Minerit Pastell Grafit95 8musta värvi) 8mm | ≥48 dB | 0,11 W/m2K | 0,1 | -100; Kõrgus: 100; 3D pikkus: 2 280 | -100
VS-05 | 1 korrus | 1.18 IfcWall (sein) (_RKAS BIM + ARCHICAD Classification) | Plaat - Sein, Soojustus - Plastik Kõva (2), Raudbetoon - Konstruktsioon, Krohv - Lubjakivi | Siseviimistlus; Lubikrohv 10mm; SW r/b element 200mm; Hüdroisolatsioon; PIR soojusisolatsioon 150mm; PIR väline soojusisolatsioon 50mm; Tsementkiudplaat Minerit Pastell Grafit95 8musta värvi) 8mm | ≥48 dB | 0,11 W/m2K | 0,1 | -100; Kõrgus: 100; 3D pikkus: 2 281 | -100

# IfcWall: VS-03* (7)
In: -1 korrus
Type - ElementType: Element type VS-03*
Arhitektuur - 01 Nimetus: Välissein; 03 Tähistus: VS-03*; 04 Tulepüsivus: nõudeid ei esitata; 05 Asukoht: Exterior; 06 Kandevelementide eristatus: Load-Bearing Element; 07 Helipidavus: 60dB; 08 Soojusläbivus (U-arv): 0,18W/m2K
Ehituskonstruktsioonid - 03 Tähistus või ristlõige: VS-03*; 12 Alumine kõrgusmärk: -4 035
AC_Pset_RenovationAndPhasing - Renovation Status: New
Pset_WallCommon - LoadBearing: yes; IsExternal: yes
Name | Classification | Material | 02 Materjal | 06 Maht (kubatuur) | 11 Ülemine kõrgusmärk
VS-03* | 0 TELLIJA KULUD (EHITUSKULUDE LIIGITAMINE EVS 885:2005); 1.18 IfcWall (sein) (_RKAS BIM + ARCHICAD Classification) | Raudbetoon - Konstruktsioon, Soojustus - Plastik Kõva (2), Membraan - Veekindel (2) | Siseviimistlus; Monteeritav r/bet. seinapaneel 200mm; SBS bituumenhüdroisolatsioon; Vahtpolüstüreen soojustus EPS120 PERIMEETER 50+150mm; drenaazhimatt; Geotekstiil; Tihendatud pinnas (kesliiv) | 3,8 | -4 035; Kõrgus: 3 935; 3D pikkus: 2 915
VS-03* | 1.18 IfcWall (sein) (_RKAS BIM + ARCHICAD Classification) | Raudbetoon - Konstruktsioon, Soojustus - Plastik Kõva (2), Membraan - Veekindel (2) | Siseviimistlus; Monteeritav r/bet. seinapaneel 200mm; SBS bituumenhüdroisolatsioon; Vahtpolüstüreen soojustus EPS120 PERIMEETER 50+150mm; drenaazhimatt; Geotekstiil; Tihendatud pinnas (kesliiv) | 21,6 | -4 035; Kõrgus: 4 015; 3D pikkus: 13 740
VS-03* | 1.18 IfcWall (sein) (_RKAS BIM + ARCHICAD Classification) | Membraan - Veekindel (2), Soojustus - Plastik Kõva (2), Raudbetoon - Konstruktsioon | Siseviimistlus; Lubikrohv 10mm; Monteeritav r/bet. seinapaneel 200mm; SBS bituumenhüdroisolatsioon; Vahtpolüstüreen soojustus EPS120 PERIMEETER 50+150mm; drenaazhimatt; Geotekstiil; Tihendatud pinnas (kesliiv) | 1,2 | -4 035; Kõrgus: 2 400; 3D pikkus: 1 300
VS-03* | 1.18 IfcWall (sein) (_RKAS BIM + ARCHICAD Classification) | Raudbetoon - Konstruktsioon, Soojustus - Plastik Kõva (2), Membraan - Veekindel (2) | Siseviimistlus; Monteeritav r/bet. seinapaneel 200mm; SBS bituumenhüdroisolatsioon; Vahtpolüstüreen soojustus EPS120 PERIMEETER 50+150mm; drenaazhimatt; Geotekstiil; Tihendatud pinnas (kesliiv) | 6,2 | -4 035; Kõrgus: 2 400; 3D pikkus: 6 635
VS-03* | 1.18 IfcWall (sein) (_RKAS BIM + ARCHICAD Classification) | Raudbetoon - Konstruktsioon, Soojustus - Plastik Kõva (2), Membraan - Veekindel (2) | Siseviimistlus; Monteeritav r/bet. seinapaneel 200mm; SBS bituumenhüdroisolatsioon; Vahtpolüstüreen soojustus EPS120 PERIMEETER 50+150mm; drenaazhimatt; Geotekstiil; Tihendatud pinnas (kesliiv) | 27,3 | -4 035; Kõrgus: 3 620; 3D pikkus: 18 945
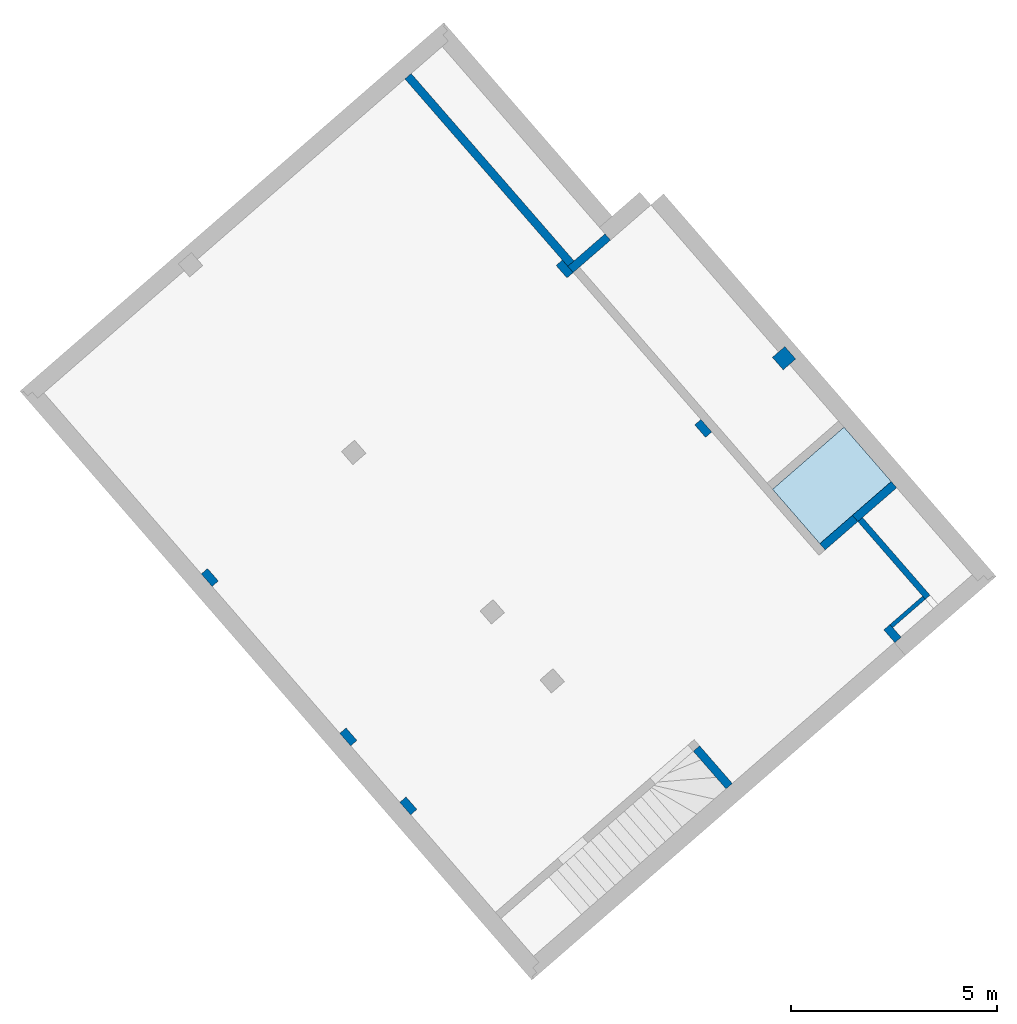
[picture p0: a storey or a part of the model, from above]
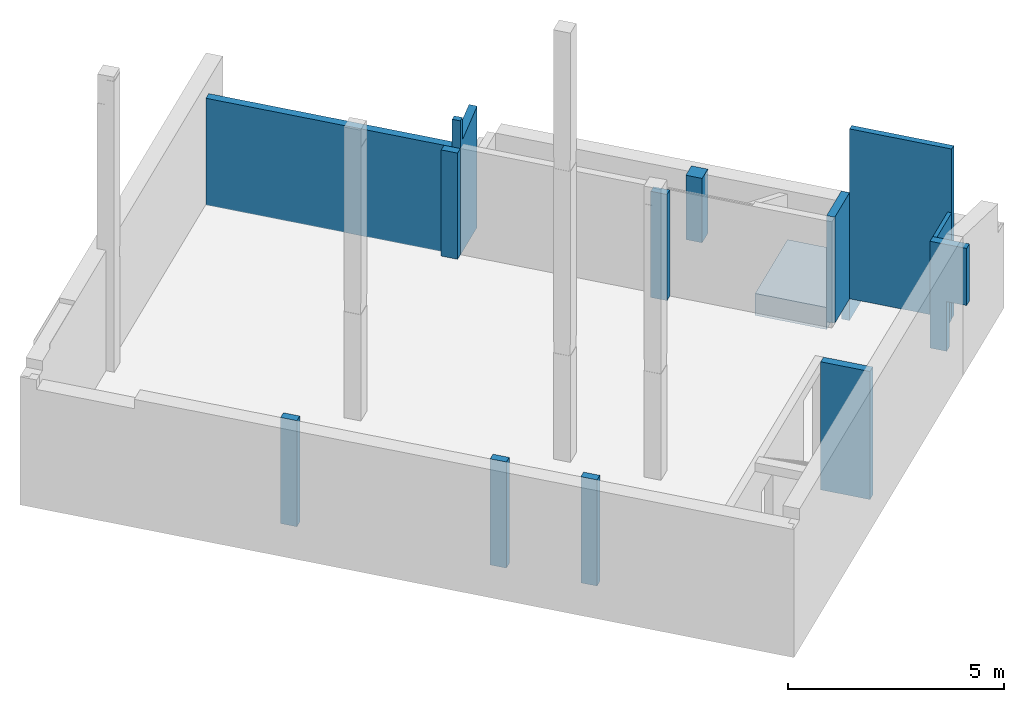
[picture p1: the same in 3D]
Properties of the parts of a building model (IFC2X3), part 12 of 13

# IfcWall: VS-03* (7)
Name | Classification | Material | 02 Materjal | 06 Maht (kubatuur) | 11 Ülemine kõrgusmärk
VS-03* | 1.18 IfcWall (sein) (_RKAS BIM + ARCHICAD Classification) | Raudbetoon - Konstruktsioon, Soojustus - Plastik Kõva (2), Membraan - Veekindel (2) | Siseviimistlus; Lubikrohv 10mm; Monteeritav r/bet. seinapaneel 200mm; SBS bituumenhüdroisolatsioon; Vahtpolüstüreen soojustus EPS120 PERIMEETER 50+150mm; drenaazhimatt; Geotekstiil; Tihendatud pinnas (kesliiv) | 12,0 | -4 035; Kõrgus: 2 400; 3D pikkus: 12 310
VS-03* | 1.18 IfcWall (sein) (_RKAS BIM + ARCHICAD Classification) | Membraan - Veekindel (2), Soojustus - Plastik Kõva (2), Raudbetoon - Konstruktsioon | Siseviimistlus; Monteeritav r/bet. seinapaneel 200mm; SBS bituumenhüdroisolatsioon; Vahtpolüstüreen soojustus EPS120 PERIMEETER 50+150mm; drenaazhimatt; Geotekstiil; Tihendatud pinnas (kesliiv) | 18,9 | -4 035; Kõrgus: 3 935; 3D pikkus: 12 015

# IfcWall: VS-04 (7)
Type - ElementType: Element type VS-04
Classification: 1.18 IfcWall (sein) (_RKAS BIM + ARCHICAD Classification)
Arhitektuur - 01 Nimetus: Välissein; 02 Materjal: Siseviimistlus; Lubikrohv 10mm; SW r/b element 200mm; Hüdroisolatsioon; PIR soojusisolatsioon 150mm; PIR väline soojusisolatsioon 50mm; 03 Tähistus: VS-04; 04 Tulepüsivus: nõudeid ei esitata; 05 Asukoht: Exterior; 06 Kandevelementide eristatus: Load-Bearing Element; 08 Soojusläbivus (U-arv): 0,11 W/m2K
Ehituskonstruktsioonid - 03 Tähistus või ristlõige: VS-04
AC_Pset_RenovationAndPhasing - Renovation Status: New
Pset_WallCommon - LoadBearing: yes; IsExternal: yes
Name | In | Material | 07 Helipidavus | 06 Maht (kubatuur) | 11 Ülemine kõrgusmärk | 12 Alumine kõrgusmärk
VS-03 | 0 korrus | Membraan - Veekindel (2), Soojustus - Plastik Kõva (2), Raudbetoon - Konstruktsioon, Krohv - Lubjakivi | ≥48 dB | 3,4 | -2 235; Kõrgus: 1 426; 3D pikkus: 8 710 | -2 235
VS-03 | 0 korrus | Krohv - Lubjakivi, Raudbetoon - Konstruktsioon, Soojustus - Plastik Kõva (2), Membraan - Veekindel (2) | 49 dB | 4,6 | -620; Kõrgus: 520; 3D pikkus: 21 307 | -620
VS-03 | 1 korrus | Membraan - Veekindel (2), Soojustus - Plastik Kõva (2), Raudbetoon - Konstruktsioon, Krohv - Lubjakivi | 49 dB | 0,3 | 1 735; Kõrgus: 1 400; 3D pikkus: 1 200 | 1 735
VS-03 | 1 korrus | Membraan - Veekindel (2), Soojustus - Plastik Kõva (2), Raudbetoon - Konstruktsioon, Krohv - Lubjakivi | 49 dB | 0,3 | 1 620; Kõrgus: 1 045; 3D pikkus: 1 233 | 1 620
VS-03 | 1 korrus | Membraan - Veekindel (2), Soojustus - Plastik Kõva (2), Raudbetoon - Konstruktsioon, Krohv - Lubjakivi | 49 dB | 0,3 | 2 195; Kõrgus: 1 400; 3D pikkus: 1 179 | 2 195
VS-03 | 1 korrus | Membraan - Veekindel (2), Soojustus - Plastik Kõva (2), Raudbetoon - Konstruktsioon, Krohv - Lubjakivi | 49 dB | 1,0 | -620; Kõrgus: 520; 3D pikkus: 4 873 | -620
VS-03 | 1 korrus | Krohv - Lubjakivi, Raudbetoon - Konstruktsioon, Soojustus - Plastik Kõva (2), Membraan - Veekindel (2) | 49 dB | 3,7 | -620; Kõrgus: 520; 3D pikkus: 17 215 | -620

# IfcWall: VS-05 (58)
Type - ElementType: Element type VS-05
Arhitektuur - 01 Nimetus: Välissein; 03 Tähistus: VS-05; 05 Asukoht: Exterior; 06 Kandevelementide eristatus: Load-Bearing Element; 07 Helipidavus: 60 dB; 08 Soojusläbivus (U-arv): 0,18 W/m2K
Ehituskonstruktsioonid - 03 Tähistus või ristlõige: VS-05
AC_Pset_RenovationAndPhasing - Renovation Status: New
Pset_WallCommon - LoadBearing: yes; IsExternal: yes
Name | In | Classification | Material | 02 Materjal | 04 Tulepüsivus | 06 Maht (kubatuur) | 11 Ülemine kõrgusmärk | 12 Alumine kõrgusmärk
VS-05 | 0 korrus | 0 TELLIJA KULUD (EHITUSKULUDE LIIGITAMINE EVS 885:2005); 1.18 IfcWall (sein) (_RKAS BIM + ARCHICAD Classification) | Krohv - Lubjakivi, Raudbetoon - Konstruktsioon, Soojustus - Plastik Kõva (2), Plaat - Sein | Siseviimistlus; Lubikrohv 10mm; r/b element 200mm; Hüdroisolatsioon; PIR soojusisolatsioon 150mm; PIR väline soojusisolatsioon 50mm; Tsementkiudplaat Minerit Pastell Grafit95 8 musta värvi) 8mm | nõudeid ei esitata | 0,7 | -1 815; Kõrgus: 3 200; 3D pikkus: 8 310 | -1 815
VS-05 | 0 korrus | 1.18 IfcWall (sein) (_RKAS BIM + ARCHICAD Classification) | Krohv - Lubjakivi, Raudbetoon - Konstruktsioon, Soojustus - Plastik Kõva (2), Plaat - Sein | Siseviimistlus; Lubikrohv 10mm; r/b element 200mm; Hüdroisolatsioon; PIR soojusisolatsioon 150mm; PIR väline soojusisolatsioon 50mm; Tsementkiudplaat Minerit Pastell Grafit95 8 musta värvi) 8mm | nõudeid ei esitata | 1,4 | -1 815; Kõrgus: 200; 3D pikkus: 16 670 | -1 815
VS-05 | 0 korrus | 1.18 IfcWall (sein) (_RKAS BIM + ARCHICAD Classification) | Plaat - Sein, Soojustus - Plastik Kõva (2), Raudbetoon - Konstruktsioon, Krohv - Lubjakivi | Siseviimistlus; Lubikrohv 10mm; r/b element 200mm; Hüdroisolatsioon; PIR soojusisolatsioon 150mm; PIR väline soojusisolatsioon 50mm; Tsementkiudplaat Minerit Pastell Grafit95 8 musta värvi) 8mm | nõudeid ei esitata | 0,4 | -1 815; Kõrgus: 1 915; 3D pikkus: 4 660 | -1 815
VS-05 | 0 korrus | 0 TELLIJA KULUD (EHITUSKULUDE LIIGITAMINE EVS 885:2005); 1.18 IfcWall (sein) (_RKAS BIM + ARCHICAD Classification) | Krohv - Lubjakivi, Raudbetoon - Konstruktsioon, Soojustus - Plastik Kõva (2), Plaat - Sein | Siseviimistlus; Lubikrohv 10mm; r/b element 200mm; Hüdroisolatsioon; PIR soojusisolatsioon 150mm; PIR väline soojusisolatsioon 50mm; Tsementkiudplaat Minerit Pastell Grafit95 8 musta värvi) 8mm | EI 60 | 0,8 | -1 815; Kõrgus: 3 200; 3D pikkus: 9 010 | -1 815
VS-05 | 1 korrus | 1.18 IfcWall (sein) (_RKAS BIM + ARCHICAD Classification) | Krohv - Lubjakivi, Raudbetoon - Konstruktsioon, Soojustus - Plastik Kõva (2), Plaat - Sein | Siseviimistlus; Lubikrohv 10mm; r/b element 200mm; Hüdroisolatsioon; PIR soojusisolatsioon 150mm; PIR väline soojusisolatsioon 50mm; Tsementkiudplaat Minerit Pastell Grafit95 8 musta värvi) 8mm | nõudeid ei esitata | 0,7 | -150; Kõrgus: 200; 3D pikkus: 8 798 | -150
VS-05 | 1 korrus | 1.18 IfcWall (sein) (_RKAS BIM + ARCHICAD Classification) | Plaat - Sein, Soojustus - Plastik Kõva (2), Raudbetoon - Konstruktsioon, Krohv - Lubjakivi (3) | Siseviimistlus; Lubikrohv 10mm; r/b element 200mm; Hüdroisolatsioon; PIR soojusisolatsioon 150mm; PIR väline soojusisolatsioon 50mm; Tsementkiudplaat Minerit Pastell Grafit95 8 musta värvi) 8mm | nõudeid ei esitata | 0,2 | 3 595; Kõrgus: 200; 3D pikkus: 2 085 | 3 595
VS-05 | 1 korrus | 1.18 IfcWall (sein) (_RKAS BIM + ARCHICAD Classification) | Krohv - Lubjakivi, Raudbetoon - Konstruktsioon, Soojustus - Plastik Kõva (2), Plaat - Sein | Siseviimistlus; Lubikrohv 10mm; r/b element 200mm; Hüdroisolatsioon; PIR soojusisolatsioon 150mm; PIR väline soojusisolatsioon 50mm; Tsementkiudplaat Minerit Pastell Grafit95 8 musta värvi) 8mm | nõudeid ei esitata | 0,1 | 360; Kõrgus: 200; 3D pikkus: 1 625 | 360
VS-05 | 1 korrus | 1.18 IfcWall (sein) (_RKAS BIM + ARCHICAD Classification) | Plaat - Sein, Soojustus - Plastik Kõva (2), Raudbetoon - Konstruktsioon, Krohv - Lubjakivi | Siseviimistlus; Lubikrohv 10mm; r/b element 200mm; Hüdroisolatsioon; PIR soojusisolatsioon 150mm; PIR väline soojusisolatsioon 50mm; Tsementkiudplaat Minerit Pastell Grafit95 8 musta värvi) 8mm | nõudeid ei esitata | 0,1 | 825; Kõrgus: 200; 3D pikkus: 1 630 | 825
VS-05 | 1 korrus | 1.18 IfcWall (sein) (_RKAS BIM + ARCHICAD Classification) | Plaat - Sein, Soojustus - Plastik Kõva (2), Raudbetoon - Konstruktsioon, Krohv - Lubjakivi | Siseviimistlus; Lubikrohv 10mm; r/b element 200mm; Hüdroisolatsioon; PIR soojusisolatsioon 150mm; PIR väline soojusisolatsioon 50mm; Tsementkiudplaat Minerit Pastell Grafit95 8 musta värvi) 8mm | nõudeid ei esitata | 0,1 | 1 285; Kõrgus: 200; 3D pikkus: 1 630 | 1 285
VS-05 | 1 korrus | 1.18 IfcWall (sein) (_RKAS BIM + ARCHICAD Classification) | Plaat - Sein, Soojustus - Plastik Kõva (2), Raudbetoon - Konstruktsioon, Krohv - Lubjakivi | Siseviimistlus; Lubikrohv 10mm; r/b element 200mm; Hüdroisolatsioon; PIR soojusisolatsioon 150mm; PIR väline soojusisolatsioon 50mm; Tsementkiudplaat Minerit Pastell Grafit95 8 musta värvi) 8mm | nõudeid ei esitata | 0,1 | 1 750; Kõrgus: 200; 3D pikkus: 1 630 | 1 750
VS-05 | 1 korrus | 1.18 IfcWall (sein) (_RKAS BIM + ARCHICAD Classification) | Krohv - Lubjakivi, Raudbetoon - Konstruktsioon, Soojustus - Plastik Kõva (2), Plaat - Sein | Siseviimistlus; Lubikrohv 10mm; r/b element 200mm; Hüdroisolatsioon; PIR soojusisolatsioon 150mm; PIR väline soojusisolatsioon 50mm; Tsementkiudplaat Minerit Pastell Grafit95 8 musta värvi) 8mm | nõudeid ei esitata | 0,0 | -100; Kõrgus: 200; 3D pikkus: 585 | -100
VS-05 | 1 korrus | 1.18 IfcWall (sein) (_RKAS BIM + ARCHICAD Classification) | Plaat - Sein, Soojustus - Plastik Kõva (2), Raudbetoon - Konstruktsioon, Krohv - Lubjakivi | Siseviimistlus; Lubikrohv 10mm; r/b element 200mm; Hüdroisolatsioon; PIR soojusisolatsioon 150mm; PIR väline soojusisolatsioon 50mm; Tsementkiudplaat Minerit Pastell Grafit95 8 musta värvi) 8mm | nõudeid ei esitata | 0,1 | 2 210; Kõrgus: 200; 3D pikkus: 1 630 | 2 210
VS-05 | 1 korrus | 1.18 IfcWall (sein) (_RKAS BIM + ARCHICAD Classification) | Krohv - Lubjakivi, Raudbetoon - Konstruktsioon, Soojustus - Plastik Kõva (2), Plaat - Sein | Siseviimistlus; Lubikrohv 10mm; r/b element 200mm; Hüdroisolatsioon; PIR soojusisolatsioon 150mm; PIR väline soojusisolatsioon 50mm; Tsementkiudplaat Minerit Pastell Grafit95 8 musta värvi) 8mm | nõudeid ei esitata | 0,1 | -150; Kõrgus: 200; 3D pikkus: 910 | -150
VS-05 | 1 korrus | 1.18 IfcWall (sein) (_RKAS BIM + ARCHICAD Classification) | Plaat - Sein, Soojustus - Plastik Kõva (2), Raudbetoon - Konstruktsioon, Krohv - Lubjakivi | Siseviimistlus; Lubikrohv 10mm; r/b element 200mm; Hüdroisolatsioon; PIR soojusisolatsioon 150mm; PIR väline soojusisolatsioon 50mm; Tsementkiudplaat Minerit Pastell Grafit95 8 musta värvi) 8mm | nõudeid ei esitata | 0,1 | 1 285; Kõrgus: 665; 3D pikkus: 200 | 1 285
VS-05 | 1 korrus | 1.18 IfcWall (sein) (_RKAS BIM + ARCHICAD Classification) | Plaat - Sein, Soojustus - Plastik Kõva (2), Raudbetoon - Konstruktsioon, Krohv - Lubjakivi | Siseviimistlus; Lubikrohv 10mm; r/b element 200mm; Hüdroisolatsioon; PIR soojusisolatsioon 150mm; PIR väline soojusisolatsioon 50mm; Tsementkiudplaat Minerit Pastell Grafit95 8 musta värvi) 8mm | nõudeid ei esitata | 0,1 | 310; Kõrgus: 610; 3D pikkus: 200 | 310
VS-05 | 1 korrus | 1.18 IfcWall (sein) (_RKAS BIM + ARCHICAD Classification) | Krohv - Lubjakivi, Raudbetoon - Konstruktsioon, Soojustus - Plastik Kõva (2), Plaat - Sein | Siseviimistlus; Lubikrohv 10mm; r/b element 200mm; Hüdroisolatsioon; PIR soojusisolatsioon 150mm; PIR väline soojusisolatsioon 50mm; Tsementkiudplaat Minerit Pastell Grafit95 8 musta värvi) 8mm | nõudeid ei esitata | 0,2 | -100; Kõrgus: 100; 3D pikkus: 3 790 | -100
VS-05 | 1 korrus | 1.18 IfcWall (sein) (_RKAS BIM + ARCHICAD Classification) | Krohv - Lubjakivi, Raudbetoon - Konstruktsioon, Soojustus - Plastik Kõva (2), Plaat - Sein | Siseviimistlus; Lubikrohv 10mm; r/b element 200mm; Hüdroisolatsioon; PIR soojusisolatsioon 150mm; PIR väline soojusisolatsioon 50mm; Tsementkiudplaat Minerit Pastell Grafit95 8 musta värvi) 8mm | nõudeid ei esitata | 0,0 | -100; Kõrgus: 100; 3D pikkus: 1 003 | -100
VS-05 | 1 korrus | 1.18 IfcWall (sein) (_RKAS BIM + ARCHICAD Classification) | Krohv - Lubjakivi (9), Raudbetoon - Konstruktsioon, Soojustus - Plastik Kõva (4), Plaat - Sein (2) | Siseviimistlus; Lubikrohv 10mm; r/b element 200mm; Hüdroisolatsioon; PIR soojusisolatsioon 150mm; tuletõkke PIR väline soojusisolatsioon 50mm; Tsementkiudplaat Minerit Pastell Grafit95 8 musta värvi) 8mm | nõudeid ei esitata | 2,3 | -150; Kõrgus: 200; 3D pikkus: 31 520 | -150
VS-05 | 1 korrus | 1.18 IfcWall (sein) (_RKAS BIM + ARCHICAD Classification) | Krohv - Lubjakivi, Raudbetoon - Konstruktsioon, Soojustus - Plastik Kõva (2), Plaat - Sein | Siseviimistlus; Lubikrohv 10mm; r/b element 200mm; Hüdroisolatsioon; PIR soojusisolatsioon 150mm; PIR väline soojusisolatsioon 50mm; Tsementkiudplaat Minerit Pastell Grafit95 8 musta värvi) 8mm | nõudeid ei esitata | 0,5 | -100; Kõrgus: 200; 3D pikkus: 6 810 | -100
VS-05 | 1 korrus | 1.18 IfcWall (sein) (_RKAS BIM + ARCHICAD Classification) | Plaat - Sein, Soojustus - Plastik Kõva (2), Raudbetoon - Konstruktsioon (2), Krohv - Lubjakivi (2) | Siseviimistlus; Lubikrohv 10mm; r/b element 200mm; Hüdroisolatsioon; PIR soojusisolatsioon 150mm; PIR väline soojusisolatsioon 50mm; Tsementkiudplaat Minerit Pastell Grafit95 8 musta värvi) 8mm | nõudeid ei esitata | 0,1 | 720; Kõrgus: 200; 3D pikkus: 1 375 | 720
VS-05 | 1 korrus | 1.18 IfcWall (sein) (_RKAS BIM + ARCHICAD Classification) | Plaat - Sein, Soojustus - Plastik Kõva (2), Raudbetoon - Konstruktsioon, Krohv - Lubjakivi | Siseviimistlus; Lubikrohv 10mm; r/b element 200mm; Hüdroisolatsioon; PIR soojusisolatsioon 150mm; PIR väline soojusisolatsioon 50mm; Tsementkiudplaat Minerit Pastell Grafit95 8 musta värvi) 8mm | nõudeid ei esitata | 0,1 | 310; Kõrgus: 200; 3D pikkus: 1 375 | 310
VS-05 | 1 korrus | 1.18 IfcWall (sein) (_RKAS BIM + ARCHICAD Classification) | Plaat - Sein, Soojustus - Plastik Kõva (2), Raudbetoon - Konstruktsioon, Krohv - Lubjakivi | Siseviimistlus; Lubikrohv 10mm; r/b element 200mm; Hüdroisolatsioon; PIR soojusisolatsioon 150mm; PIR väline soojusisolatsioon 50mm; Tsementkiudplaat Minerit Pastell Grafit95 8 musta värvi) 8mm | nõudeid ei esitata | 0,1 | 3 135; Kõrgus: 660; 3D pikkus: 200 | 3 135
VS-05 | 1 korrus | 1.18 IfcWall (sein) (_RKAS BIM + ARCHICAD Classification) | Plaat - Sein, Soojustus - Plastik Kõva (2), Raudbetoon - Konstruktsioon, Krohv - Lubjakivi | Siseviimistlus; Lubikrohv 10mm; r/b element 200mm; Hüdroisolatsioon; PIR soojusisolatsioon 150mm; PIR väline soojusisolatsioon 50mm; Tsementkiudplaat Minerit Pastell Grafit95 8 musta värvi) 8mm | nõudeid ei esitata | 0,1 | 2 360; Kõrgus: 200; 3D pikkus: 1 375 | 2 360
VS-05 | 1 korrus | 1.18 IfcWall (sein) (_RKAS BIM + ARCHICAD Classification) | Plaat - Sein, Soojustus - Plastik Kõva (2), Raudbetoon - Konstruktsioon, Krohv - Lubjakivi | Siseviimistlus; Lubikrohv 10mm; r/b element 200mm; Hüdroisolatsioon; PIR soojusisolatsioon 150mm; PIR väline soojusisolatsioon 50mm; Tsementkiudplaat Minerit Pastell Grafit95 8 musta värvi) 8mm | nõudeid ei esitata | 0,1 | 3 180; Kõrgus: 615; 3D pikkus: 200 | 3 180
VS-05 | 1 korrus | 1.18 IfcWall (sein) (_RKAS BIM + ARCHICAD Classification) | Plaat - Sein, Soojustus - Plastik Kõva (2), Raudbetoon - Konstruktsioon, Krohv - Lubjakivi | Siseviimistlus; Lubikrohv 10mm; r/b element 200mm; Hüdroisolatsioon; PIR soojusisolatsioon 150mm; PIR väline soojusisolatsioon 50mm; Tsementkiudplaat Minerit Pastell Grafit95 8 musta värvi) 8mm | nõudeid ei esitata | 0,1 | 1 540; Kõrgus: 200; 3D pikkus: 1 375 | 1 540
VS-05 | 1 korrus | 1.18 IfcWall (sein) (_RKAS BIM + ARCHICAD Classification) | Plaat - Sein, Soojustus - Plastik Kõva (2), Raudbetoon - Konstruktsioon (2), Krohv - Lubjakivi | Siseviimistlus; Lubikrohv 10mm; r/b element 200mm; Hüdroisolatsioon; PIR soojusisolatsioon 150mm; PIR väline soojusisolatsioon 50mm; Tsementkiudplaat Minerit Pastell Grafit95 8 musta värvi) 8mm | nõudeid ei esitata | 0,1 | 3 595; Kõrgus: 200; 3D pikkus: 960 | 3 595
VS-05 | 1 korrus | 1.18 IfcWall (sein) (_RKAS BIM + ARCHICAD Classification) | Plaat - Sein, Soojustus - Plastik Kõva (2), Raudbetoon - Konstruktsioon, Krohv - Lubjakivi | Siseviimistlus; Lubikrohv 10mm; r/b element 200mm; Hüdroisolatsioon; PIR soojusisolatsioon 150mm; PIR väline soojusisolatsioon 50mm; Tsementkiudplaat Minerit Pastell Grafit95 8 musta värvi) 8mm | nõudeid ei esitata | 0,1 | 1 950; Kõrgus: 200; 3D pikkus: 1 375 | 1 950
VS-05 | 1 korrus | 1.18 IfcWall (sein) (_RKAS BIM + ARCHICAD Classification) | Plaat - Sein, Soojustus - Plastik Kõva (2), Raudbetoon - Konstruktsioon, Krohv - Lubjakivi | Siseviimistlus; Lubikrohv 10mm; r/b element 200mm; Hüdroisolatsioon; PIR soojusisolatsioon 150mm; PIR väline soojusisolatsioon 50mm; Tsementkiudplaat Minerit Pastell Grafit95 8 musta värvi) 8mm | nõudeid ei esitata | 0,1 | 3 135; Kõrgus: 200; 3D pikkus: 1 000 | 3 135
VS-05 | 1 korrus | 1.18 IfcWall (sein) (_RKAS BIM + ARCHICAD Classification) | Plaat - Sein, Soojustus - Plastik Kõva (2), Raudbetoon - Konstruktsioon, Krohv - Lubjakivi | Siseviimistlus; Lubikrohv 10mm; r/b element 200mm; Hüdroisolatsioon; PIR soojusisolatsioon 150mm; PIR väline soojusisolatsioon 50mm; Tsementkiudplaat Minerit Pastell Grafit95 8 musta värvi) 8mm | nõudeid ei esitata | 0,3 | 3 595; Kõrgus: 200; 3D pikkus: 3 737 | 3 595
VS-05 | 1 korrus | 1.18 IfcWall (sein) (_RKAS BIM + ARCHICAD Classification) | Plaat - Sein, Soojustus - Plastik Kõva (2), Raudbetoon - Konstruktsioon, Krohv - Lubjakivi | Siseviimistlus; Lubikrohv 10mm; r/b element 200mm; Hüdroisolatsioon; PIR soojusisolatsioon 150mm; PIR väline soojusisolatsioon 50mm; Tsementkiudplaat Minerit Pastell Grafit95 8 musta värvi) 8mm | nõudeid ei esitata | 0,1 | 2 770; Kõrgus: 200; 3D pikkus: 1 377 | 2 770
VS-05 | 1 korrus | 1.18 IfcWall (sein) (_RKAS BIM + ARCHICAD Classification) | Plaat - Sein, Soojustus - Plastik Kõva (2), Raudbetoon - Konstruktsioon, Krohv - Lubjakivi | Siseviimistlus; Lubikrohv 10mm; r/b element 200mm; Hüdroisolatsioon; PIR soojusisolatsioon 150mm; PIR väline soojusisolatsioon 50mm; Tsementkiudplaat Minerit Pastell Grafit95 8 musta värvi) 8mm | nõudeid ei esitata | 0,1 | 1 130; Kõrgus: 200; 3D pikkus: 1 375 | 1 130
VS-05 | 1 korrus | 1.18 IfcWall (sein) (_RKAS BIM + ARCHICAD Classification) | Plaat - Sein, Soojustus - Plastik Kõva (2), Raudbetoon - Konstruktsioon, Krohv - Lubjakivi | Siseviimistlus; Lubikrohv 10mm; r/b element 200mm; Hüdroisolatsioon; PIR soojusisolatsioon 150mm; PIR väline soojusisolatsioon 50mm; Tsementkiudplaat Minerit Pastell Grafit95 8 musta värvi) 8mm | nõudeid ei esitata | 0,1 | 2 665; Kõrgus: 670; 3D pikkus: 200 | 2 665
VS-05 | 1 korrus | 1.18 IfcWall (sein) (_RKAS BIM + ARCHICAD Classification) | Plaat - Sein, Soojustus - Plastik Kõva (2), Raudbetoon - Konstruktsioon, Krohv - Lubjakivi | Siseviimistlus; Lubikrohv 10mm; r/b element 200mm; Hüdroisolatsioon; PIR soojusisolatsioon 150mm; PIR väline soojusisolatsioon 50mm; Tsementkiudplaat Minerit Pastell Grafit95 8 musta värvi) 8mm | nõudeid ei esitata | 0,1 | 3 180; Kõrgus: 200; 3D pikkus: 1 375 | 3 180
VS-05 | 1 korrus | 1.18 IfcWall (sein) (_RKAS BIM + ARCHICAD Classification) | Plaat - Sein, Soojustus - Plastik Kõva (2), Raudbetoon - Konstruktsioon | Siseviimistlus; Lubikrohv 10mm; r/b element 200mm; Hüdroisolatsioon; PIR soojusisolatsioon 150mm; PIR väline soojusisolatsioon 50mm; Tsementkiudplaat Minerit Pastell Grafit95 8 musta värvi) 8mm | nõudeid ei esitata | 0,0 | 825; Kõrgus: 660; 3D pikkus: 200 | 825
VS-05 | 1 korrus | 1.18 IfcWall (sein) (_RKAS BIM + ARCHICAD Classification) | Plaat - Sein, Soojustus - Plastik Kõva (2), Raudbetoon - Konstruktsioon, Krohv - Lubjakivi | Siseviimistlus; Lubikrohv 10mm; r/b element 200mm; Hüdroisolatsioon; PIR soojusisolatsioon 150mm; PIR väline soojusisolatsioon 50mm; Tsementkiudplaat Minerit Pastell Grafit95 8 musta värvi) 8mm | nõudeid ei esitata | 0,1 | 1 750; Kõrgus: 660; 3D pikkus: 200 | 1 750
VS-05 | 1 korrus | 1.18 IfcWall (sein) (_RKAS BIM + ARCHICAD Classification) | Plaat - Sein, Soojustus - Plastik Kõva (2), Raudbetoon - Konstruktsioon, Krohv - Lubjakivi | Siseviimistlus; Lubikrohv 10mm; r/b element 200mm; Hüdroisolatsioon; PIR soojusisolatsioon 150mm; PIR väline soojusisolatsioon 50mm; Tsementkiudplaat Minerit Pastell Grafit95 8 musta värvi) 8mm | nõudeid ei esitata | 0,1 | 360; Kõrgus: 665; 3D pikkus: 200 | 360
VS-05 | 1 korrus | 1.18 IfcWall (sein) (_RKAS BIM + ARCHICAD Classification) | Plaat - Sein, Soojustus - Plastik Kõva (2), Raudbetoon - Konstruktsioon, Krohv - Lubjakivi | Siseviimistlus; Lubikrohv 10mm; r/b element 200mm; Hüdroisolatsioon; PIR soojusisolatsioon 150mm; PIR väline soojusisolatsioon 50mm; Tsementkiudplaat Minerit Pastell Grafit95 8 musta värvi) 8mm | nõudeid ei esitata | 0,0 | 2 360; Kõrgus: 610; 3D pikkus: 198 | 2 360
VS-05 | 1 korrus | 1.18 IfcWall (sein) (_RKAS BIM + ARCHICAD Classification) | Plaat - Sein, Soojustus - Plastik Kõva (2), Raudbetoon - Konstruktsioon, Krohv - Lubjakivi | Siseviimistlus; Lubikrohv 10mm; r/b element 200mm; Hüdroisolatsioon; PIR soojusisolatsioon 150mm; PIR väline soojusisolatsioon 50mm; Tsementkiudplaat Minerit Pastell Grafit95 8 musta värvi) 8mm | nõudeid ei esitata | 0,1 | 1 950; Kõrgus: 610; 3D pikkus: 200 | 1 950
VS-05 | 1 korrus | 1.18 IfcWall (sein) (_RKAS BIM + ARCHICAD Classification) | Plaat - Sein, Soojustus - Plastik Kõva (2), Raudbetoon - Konstruktsioon, Krohv - Lubjakivi | Siseviimistlus; Lubikrohv 10mm; r/b element 200mm; Hüdroisolatsioon; PIR soojusisolatsioon 150mm; PIR väline soojusisolatsioon 50mm; Tsementkiudplaat Minerit Pastell Grafit95 8 musta värvi) 8mm | nõudeid ei esitata | 0,1 | 1 540; Kõrgus: 610; 3D pikkus: 200 | 1 540
VS-05 | 1 korrus | 1.18 IfcWall (sein) (_RKAS BIM + ARCHICAD Classification) | Plaat - Sein, Soojustus - Plastik Kõva (2), Raudbetoon - Konstruktsioon, Krohv - Lubjakivi | Siseviimistlus; Lubikrohv 10mm; r/b element 200mm; Hüdroisolatsioon; PIR soojusisolatsioon 150mm; PIR väline soojusisolatsioon 50mm; Tsementkiudplaat Minerit Pastell Grafit95 8 musta värvi) 8mm | nõudeid ei esitata | 0,1 | 720; Kõrgus: 610; 3D pikkus: 200 | 720
VS-05 | 1 korrus | 1.18 IfcWall (sein) (_RKAS BIM + ARCHICAD Classification) | Plaat - Sein, Soojustus - Plastik Kõva (2), Raudbetoon - Konstruktsioon, Krohv - Lubjakivi | Siseviimistlus; Lubikrohv 10mm; r/b element 200mm; Hüdroisolatsioon; PIR soojusisolatsioon 150mm; PIR väline soojusisolatsioon 50mm; Tsementkiudplaat Minerit Pastell Grafit95 8 musta värvi) 8mm | nõudeid ei esitata | 0,1 | 1 130; Kõrgus: 610; 3D pikkus: 200 | 1 130
VS-05 | 1 korrus | 1.18 IfcWall (sein) (_RKAS BIM + ARCHICAD Classification) | Plaat - Sein, Soojustus - Plastik Kõva (2), Raudbetoon - Konstruktsioon, Krohv - Lubjakivi | Siseviimistlus; Lubikrohv 10mm; r/b element 200mm; Hüdroisolatsioon; PIR soojusisolatsioon 150mm; PIR väline soojusisolatsioon 50mm; Tsementkiudplaat Minerit Pastell Grafit95 8 musta värvi) 8mm | nõudeid ei esitata | 0,1 | -465; Kõrgus: 1 915; 3D pikkus: 1 260 | -465
VS-05 | 1 korrus | 1.18 IfcWall (sein) (_RKAS BIM + ARCHICAD Classification) | Plaat - Sein, Soojustus - Plastik Kõva (2), Raudbetoon - Konstruktsioon, Krohv - Lubjakivi | Siseviimistlus; Lubikrohv 10mm; r/b element 200mm; Hüdroisolatsioon; PIR soojusisolatsioon 150mm; PIR väline soojusisolatsioon 50mm; Tsementkiudplaat Minerit Pastell Grafit95 8 musta värvi) 8mm | nõudeid ei esitata | 0,1 | -100; Kõrgus: 610; 3D pikkus: 200 | -100
VS-05 | 1 korrus | 1.18 IfcWall (sein) (_RKAS BIM + ARCHICAD Classification) | Plaat - Sein, Soojustus - Plastik Kõva (2), Raudbetoon - Konstruktsioon, Krohv - Lubjakivi | Siseviimistlus; Lubikrohv 10mm; r/b element 200mm; Hüdroisolatsioon; PIR soojusisolatsioon 150mm; PIR väline soojusisolatsioon 50mm; Tsementkiudplaat Minerit Pastell Grafit95 8 musta värvi) 8mm | nõudeid ei esitata | 0,1 | -100; Kõrgus: 200; 3D pikkus: 1 238 | -100
VS-05 | 1 korrus | 1.18 IfcWall (sein) (_RKAS BIM + ARCHICAD Classification) | Plaat - Sein, Soojustus - Plastik Kõva (2), Raudbetoon - Konstruktsioon, Krohv - Lubjakivi | Siseviimistlus; Lubikrohv 10mm; r/b element 200mm; Hüdroisolatsioon; PIR soojusisolatsioon 150mm; PIR väline soojusisolatsioon 50mm; Tsementkiudplaat Minerit Pastell Grafit95 8 musta värvi) 8mm | nõudeid ei esitata | 0,0 | -100; Kõrgus: 200; 3D pikkus: 325 | -100
VS-05 | 1 korrus | 1.18 IfcWall (sein) (_RKAS BIM + ARCHICAD Classification) | Plaat - Sein, Soojustus - Plastik Kõva (2), Raudbetoon - Konstruktsioon, Krohv - Lubjakivi | Siseviimistlus; Lubikrohv 10mm; r/b element 200mm; Hüdroisolatsioon; PIR soojusisolatsioon 150mm; PIR väline soojusisolatsioon 50mm; Tsementkiudplaat Minerit Pastell Grafit95 8 musta värvi) 8mm | nõudeid ei esitata | 0,1 | 2 770; Kõrgus: 610; 3D pikkus: 200 | 2 770
VS-05 | 1 korrus | 1.18 IfcWall (sein) (_RKAS BIM + ARCHICAD Classification) | Krohv - Lubjakivi (2), Raudbetoon - Konstruktsioon (2), Soojustus - Plastik Kõva (2), Plaat - Sein | Siseviimistlus; Lubikrohv 10mm; r/b element 200mm; Hüdroisolatsioon; PIR soojusisolatsioon 150mm; PIR väline soojusisolatsioon 50mm; Tsementkiudplaat Minerit Pastell Grafit95 8 musta värvi) 8mm | nõudeid ei esitata | 0,6 | -150; Kõrgus: 150; 3D pikkus: 9 050 | -150
VS-05 | 1 korrus | 1.18 IfcWall (sein) (_RKAS BIM + ARCHICAD Classification) | Plaat - Sein, Soojustus - Plastik Kõva (2), Raudbetoon - Konstruktsioon, Krohv - Lubjakivi | Siseviimistlus; Lubikrohv 10mm; r/b element 200mm; Hüdroisolatsioon; PIR soojusisolatsioon 150mm; PIR väline soojusisolatsioon 50mm; Tsementkiudplaat Minerit Pastell Grafit95 8 musta värvi) 8mm | nõudeid ei esitata | 0,0 | -100; Kõrgus: 200; 3D pikkus: 509 | -100
VS-05 | 1 korrus | 1.18 IfcWall (sein) (_RKAS BIM + ARCHICAD Classification) | Krohv - Lubjakivi, Raudbetoon - Konstruktsioon, Soojustus - Plastik Kõva (2), Plaat - Sein | Siseviimistlus; Lubikrohv 10mm; r/b element 200mm; Hüdroisolatsioon; PIR soojusisolatsioon 150mm; PIR väline soojusisolatsioon 50mm; Tsementkiudplaat Minerit Pastell Grafit95 8 musta värvi) 8mm | nõudeid ei esitata | 0,1 | -150; Kõrgus: 150; 3D pikkus: 1 240 | -150
VS-05 | 1 korrus | 1.18 IfcWall (sein) (_RKAS BIM + ARCHICAD Classification) | Krohv - Lubjakivi (2), Raudbetoon - Konstruktsioon, Soojustus - Plastik Kõva (2), Plaat - Sein | Siseviimistlus; Lubikrohv 10mm; r/b element 200mm; Hüdroisolatsioon; PIR soojusisolatsioon 150mm; PIR väline soojusisolatsioon 50mm; Tsementkiudplaat Minerit Pastell Grafit95 8 musta värvi) 8mm | nõudeid ei esitata | 2,8 | -150; Kõrgus: 584; 3D pikkus: 16 810 | -150
VS-05 | 1 korrus | 1.18 IfcWall (sein) (_RKAS BIM + ARCHICAD Classification) | Krohv - Lubjakivi, Raudbetoon - Konstruktsioon, Soojustus - Plastik Kõva (2), Plaat - Sein | Siseviimistlus; Lubikrohv 10mm; r/b element 200mm; Hüdroisolatsioon; PIR soojusisolatsioon 150mm; PIR väline soojusisolatsioon 50mm; Tsementkiudplaat Minerit Pastell Grafit95 8 musta värvi) 8mm | nõudeid ei esitata | 0,8 | -100; Kõrgus: 200; 3D pikkus: 10 110 | -100
VS-05 | 1 korrus | 1.18 IfcWall (sein) (_RKAS BIM + ARCHICAD Classification) | Plaat - Sein, Soojustus - Plastik Kõva (2), Raudbetoon - Konstruktsioon, Krohv - Lubjakivi | Siseviimistlus; Lubikrohv 10mm; r/b element 200mm; Hüdroisolatsioon; PIR soojusisolatsioon 150mm; PIR väline soojusisolatsioon 50mm; Tsementkiudplaat Minerit Pastell Grafit95 8 musta värvi) 8mm | nõudeid ei esitata | 0,2 | -100; Kõrgus: 100; 3D pikkus: 3 743 | -100
VS-05 | 1 korrus | 1.18 IfcWall (sein) (_RKAS BIM + ARCHICAD Classification) | Krohv - Lubjakivi, Raudbetoon - Konstruktsioon, Soojustus - Plastik Kõva (2), Plaat - Sein | Siseviimistlus; Lubikrohv 10mm; r/b element 200mm; Hüdroisolatsioon; PIR soojusisolatsioon 150mm; PIR väline soojusisolatsioon 50mm; Tsementkiudplaat Minerit Pastell Grafit95 8 musta värvi) 8mm | nõudeid ei esitata | 0,7 | -100; Kõrgus: 200; 3D pikkus: 8 548 | -100
VS-05 | 1 korrus | 1.18 IfcWall (sein) (_RKAS BIM + ARCHICAD Classification) | Plaat - Sein, Soojustus - Plastik Kõva (2), Raudbetoon - Konstruktsioon, Krohv - Lubjakivi (2) | Siseviimistlus; Lubikrohv 10mm; r/b element 200mm; Hüdroisolatsioon; PIR soojusisolatsioon 150mm; PIR väline soojusisolatsioon 50mm; Tsementkiudplaat Minerit Pastell Grafit95 8 musta värvi) 8mm | nõudeid ei esitata | 0,4 | -100; Kõrgus: 200; 3D pikkus: 4 972 | -100
VS-05 | 1 korrus | 1.18 IfcWall (sein) (_RKAS BIM + ARCHICAD Classification) | Plaat - Sein, Soojustus - Plastik Kõva (2), Raudbetoon - Konstruktsioon, Krohv - Lubjakivi | Siseviimistlus; Lubikrohv 10mm; r/b element 200mm; Hüdroisolatsioon; PIR soojusisolatsioon 150mm; PIR väline soojusisolatsioon 50mm; Tsementkiudplaat Minerit Pastell Grafit95 8 musta värvi) 8mm | nõudeid ei esitata | 0,0 | -100; Kõrgus: 200; 3D pikkus: 320 | -100
VS-05 | 1 korrus | 1.18 IfcWall (sein) (_RKAS BIM + ARCHICAD Classification) | Plaat - Sein, Soojustus - Plastik Kõva (2), Raudbetoon - Konstruktsioon, Krohv - Lubjakivi | Siseviimistlus; Lubikrohv 10mm; r/b element 200mm; Hüdroisolatsioon; PIR soojusisolatsioon 150mm; PIR väline soojusisolatsioon 50mm; Tsementkiudplaat Minerit Pastell Grafit95 8 musta värvi) 8mm | nõudeid ei esitata | 0,1 | -150; Kõrgus: 710; 3D pikkus: 200 | -150
VS-05 | 1 korrus | 1.18 IfcWall (sein) (_RKAS BIM + ARCHICAD Classification) | Krohv - Lubjakivi, Raudbetoon - Konstruktsioon, Soojustus - Plastik Kõva (2), Plaat - Sein | Siseviimistlus; Lubikrohv 10mm; r/b element 200mm; Hüdroisolatsioon; PIR soojusisolatsioon 150mm; PIR väline soojusisolatsioon 50mm; Tsementkiudplaat Minerit Pastell Grafit95 8 musta värvi) 8mm | nõudeid ei esitata | 0,5 | -100; Kõrgus: 200; 3D pikkus: 6 600 | -100
VS-05 | 1 korrus | 1.18 IfcWall (sein) (_RKAS BIM + ARCHICAD Classification) | Plaat - Sein, Soojustus - Plastik Kõva (2), Raudbetoon - Konstruktsioon, Krohv - Lubjakivi | Siseviimistlus; Lubikrohv 10mm; r/b element 200mm; Hüdroisolatsioon; PIR soojusisolatsioon 150mm; PIR väline soojusisolatsioon 50mm; Tsementkiudplaat Minerit Pastell Grafit95 8 musta värvi) 8mm | nõudeid ei esitata | 0,0 | 3 595; Kõrgus: 20; 3D pikkus: 4 319 | 3 595

# IfcWall: VS-06 (8)
Type - ElementType: Element type VS-06
Classification: 1.18 IfcWall (sein) (_RKAS BIM + ARCHICAD Classification)
Arhitektuur - 01 Nimetus: Välissein; 02 Materjal: Siseviimistlus; Lubikrohv 10mm; r/b element 200mm; PIR soojusisolatsioon 150mm; Tuletõkke PIR väline soojusisolatsioon 50mm; Vertikaalsed puitroovid 32mm; Horisontaalsed alumiiniumroovid 25mm; Valge täismass fassaadiplaat Equitone Tectiva T90 12mm;; 03 Tähistus: VS-06; 05 Asukoht: Exterior; 06 Kandevelementide eristatus: Load-Bearing Element; 07 Helipidavus: 60 dB
Ehituskonstruktsioonid - 03 Tähistus või ristlõige: VS-06
AC_Pset_RenovationAndPhasing - Renovation Status: New
Pset_WallCommon - LoadBearing: yes; IsExternal: yes
Name | In | Material | 04 Tulepüsivus | 08 Soojusläbivus (U-arv) | 06 Maht (kubatuur) | 11 Ülemine kõrgusmärk | 12 Alumine kõrgusmärk
VS-06 | 1 korrus | Krohv - Lubjakivi, Raudbetoon - Konstruktsioon, Soojustus - Plastik Kõva (2), Puit - Konstruktsioon, Alumiinium, Plaat - Sein | EI 60 | 0,11W/m2K | 7,1 | -905; Kõrgus: 2 555; 3D pikkus: 8 909 | -905
VS-06 | 1,5 korrus | Plaat - Sein, Alumiinium, Puit - Konstruktsioon, Soojustus - Plastik Kõva (2), Raudbetoon - Konstruktsioon, Krohv - Lubjakivi | EI 60 | 0,11 W/m2K | 13,2 | 1 650; Kõrgus: 3 095; 3D pikkus: 9 079 | 1 650
VS-06 | 1,5 korrus | Krohv - Lubjakivi, Raudbetoon - Konstruktsioon, Soojustus - Plastik Kõva (2), Puit - Konstruktsioon, Alumiinium, Plaat - Sein | nõudeid ei esitata | 0,11 W/m2K | 1,0 | 1 650; Kõrgus: 3 095; 3D pikkus: 967 | 1 650
VS-06 | 1,5 korrus | Plaat - Sein, Alumiinium, Puit - Konstruktsioon, Soojustus - Plastik Kõva (2), Raudbetoon - Konstruktsioon, Krohv - Lubjakivi | nõudeid ei esitata | 0,11 W/m2K | 2,2 | 50; Kõrgus: 4 695; 3D pikkus: 997 | 50
VS-06 | 2 korrus | Krohv - Lubjakivi (3), Raudbetoon - Konstruktsioon, Soojustus - Plastik Kõva (2), Puit - Konstruktsioon, Alumiinium, Plaat - Sein | nõudeid ei esitata | 0,14W/m2K | 12,3 | 4 745; Kõrgus: 4 235; 3D pikkus: 19 206 | 4 745
VS-06 | 2 korrus | Krohv - Lubjakivi, Raudbetoon - Konstruktsioon, Soojustus - Plastik Kõva (2), Puit - Konstruktsioon, Alumiinium, Plaat - Sein | EI 60 | 0,11 W/m2K | 12,5 | 4 745; Kõrgus: 4 235; 3D pikkus: 6 457 | 4 745
VS-06 | 2 korrus | Krohv - Lubjakivi (2), Raudbetoon - Konstruktsioon, Soojustus - Plastik Kõva (2), Puit - Konstruktsioon, Alumiinium, Plaat - Sein | EI 60 | 0,11 W/m2K | 2,1 | 4 745; Kõrgus: 4 235; 3D pikkus: 1 030 | 4 745
VS-06 | 2 korrus | Plaat - Sein, Alumiinium, Puit - Konstruktsioon, Soojustus - Plastik Kõva (2), Raudbetoon - Konstruktsioon, Krohv - Lubjakivi (2) | EI 60 | 0,11 W/m2K | 1,8 | 4 745; Kõrgus: 4 235; 3D pikkus: 1 580 | 4 745

# IfcWall: VS-07 (5)
In: Katus
Type - ElementType: Element type VS-07
Classification: 1.18 IfcWall (sein) (_RKAS BIM + ARCHICAD Classification)
Arhitektuur - 01 Nimetus: Parapett; 02 Materjal: 2x katusekatte (PVC) ülespööre; Aurutõkkekangas (vuugid teibitud); PIR soojustus 80mm; Aeroc kergplokk (või analoog); PIR isolatsioonimaterjal 150mm; Tuletõkke PIR isolatsioonimaterjal 50mm; Vertikaalroovitis 20mm; Horisontaalroovitis 22mm; Laudis 22mm; Puitribid 28x28...50x250mm; 03 Tähistus: VS-07; 04 Tulepüsivus: nõudeid ei esitata; 05 Asukoht: Exterior; 06 Kandevelementide eristatus: Load-Bearing Element; 07 Helipidavus: -; 08 Soojusläbivus (U-arv): -
Ehituskonstruktsioonid - 03 Tähistus või ristlõige: VS-07; 12 Alumine kõrgusmärk: 8 980
AC_Pset_RenovationAndPhasing - Renovation Status: New
Pset_WallCommon - LoadBearing: yes; IsExternal: yes
Name | Material | 06 Maht (kubatuur) | 11 Ülemine kõrgusmärk
VS-07 | Soojustus - Plastik Kõva (3), 00_müüriplokk FIBO 200mm, Õhkvahe, Puit - Konstruktsioon (2) | 29,3 | 8 980; Kõrgus: 885; 3D pikkus: 58 762
VS-07 | Puit - Konstruktsioon (2), Õhkvahe, Soojustus - Plastik Kõva (3), 00_müüriplokk FIBO 200mm | 21,9 | 8 980; Kõrgus: 885; 3D pikkus: 43 816
VS-07 | Soojustus - Plastik Kõva (3), 00_müüriplokk FIBO 200mm, Õhkvahe, Puit - Konstruktsioon (2) | 8,3 | 8 980; Kõrgus: 885; 3D pikkus: 17 330
VS-07 | Puit - Konstruktsioon (2), Õhkvahe, Soojustus - Plastik Kõva (3), 00_müüriplokk FIBO 200mm | 10,4 | 8 980; Kõrgus: 885; 3D pikkus: 21 138
VS-07 | Soojustus - Plastik Kõva (3), 00_müüriplokk FIBO 200mm, Õhkvahe, Puit - Konstruktsioon (2) | 15,4 | 8 980; Kõrgus: 885; 3D pikkus: 31 142

# IfcWall: VS-08 (2)
In: Katus
Type - ElementType: Element type VS-08
Classification: 1.18 IfcWall (sein) (_RKAS BIM + ARCHICAD Classification)
Arhitektuur - 01 Nimetus: Parapett; 02 Materjal: 2x katusekatte (SBS) ülespööre; Aurutõkkekangas (vuugid teibitud); PIR soojustus 80mm; Aeroc kergplokk (või analoog); PIR soojusisolatsioon 150mm; Tuletõkke PIR väline soojusisolatsioon 50mm; Vertikaalsed puitroovid 32mm; Horisontaalsed alumiiniumroovid 25mm; Valge täismass fassaadiplaat Equitone Tectiva T90 12mm;; 03 Tähistus: VS-08; 04 Tulepüsivus: nõudeid ei esitata; 05 Asukoht: Exterior; 06 Kandevelementide eristatus: Load-Bearing Element; 07 Helipidavus: -; 08 Soojusläbivus (U-arv): -
Ehituskonstruktsioonid - 03 Tähistus või ristlõige: VS-08; 12 Alumine kõrgusmärk: 8 980
AC_Pset_RenovationAndPhasing - Renovation Status: New
Pset_WallCommon - LoadBearing: yes; IsExternal: yes
Name | Material | 06 Maht (kubatuur) | 11 Ülemine kõrgusmärk
VS-08 | Plaat - Sein, Alumiinium, Õhkvahe, Soojustus - Plastik Kõva (3), 00_müüriplokk FIBO 200mm | 9,0 | 8 980; Kõrgus: 885; 3D pikkus: 19 106
VS-08 | Soojustus - Plastik Kõva (3), 00_müüriplokk FIBO 200mm, Õhkvahe, Alumiinium, Plaat - Sein | 4,2 | 8 980; Kõrgus: 885; 3D pikkus: 8 902

# IfcWall: VS-09 (48)
Type - ElementType: Element type VS-09
Classification: 1.18 IfcWall (sein) (_RKAS BIM + ARCHICAD Classification)
Arhitektuur - 01 Nimetus: Välissein; 02 Materjal: Siseviimistlus; Lubikrohv 10mm; Kergplokk 200mm; PIR soojustus 160mm; Aurutõkkekangas; Katusekatte (SBS) ülespööre; 03 Tähistus: VS-09; 04 Tulepüsivus: nõudeid ei esitata; 05 Asukoht: Exterior; 06 Kandevelementide eristatus: Non-Load-Bearing Element; 07 Helipidavus: 49 dB; 08 Soojusläbivus (U-arv): 0,27W/m2K
Ehituskonstruktsioonid - 03 Tähistus või ristlõige: VS-09
AC_Pset_RenovationAndPhasing - Renovation Status: New
Pset_WallCommon - LoadBearing: no; IsExternal: yes
Name | In | Material | 06 Maht (kubatuur) | 11 Ülemine kõrgusmärk | 12 Alumine kõrgusmärk
VS-09 | 2 korrus | Membraan - Veekindel (2), Soojustus - Plastik Kõva, Müüriplokk - Konstuktsioon, Krohv - Lubjakivi | 0,4 | 2 900; Kõrgus: 1 295; 3D pikkus: 2 235 | 2 900
VS-09 | 2 korrus | Membraan - Veekindel (2), Soojustus - Plastik Kõva, Müüriplokk - Konstuktsioon, Krohv - Lubjakivi | 0,6 | 2 900; Kõrgus: 1 295; 3D pikkus: 1 735 | 2 900
VS-09 | 2 korrus | Krohv - Lubjakivi, Müüriplokk - Konstuktsioon, Soojustus - Plastik Kõva, Membraan - Veekindel (2) | 0,8 | 2 900; Kõrgus: 1 295; 3D pikkus: 2 230 | 2 900
VS-09 | 2 korrus | Membraan - Veekindel (2), Soojustus - Plastik Kõva, Müüriplokk - Konstuktsioon, Krohv - Lubjakivi | 0,4 | 2 900; Kõrgus: 1 295; 3D pikkus: 1 740 | 2 900
VS-09 | Katus | Membraan - Veekindel (2), Soojustus - Plastik Kõva, Müüriplokk - Konstuktsioon, Krohv - Lubjakivi | 0,6 | 8 715; Kõrgus: 1 650; 3D pikkus: 2 030 | 8 715
3 x VS-09 | Katus | Membraan - Veekindel (2), Soojustus - Plastik Kõva, Müüriplokk - Konstuktsioon, Krohv - Lubjakivi | 2,0 | 8 715; Kõrgus: 2 000; 3D pikkus: 4 515 | 8 715
7 x VS-09 | Katus | Membraan - Veekindel (2), Soojustus - Plastik Kõva, Müüriplokk - Konstuktsioon, Krohv - Lubjakivi | 0,7 | 8 715; Kõrgus: 1 875; 3D pikkus: 2 035 | 8 715
7 x VS-09 | Katus | Membraan - Veekindel (2), Soojustus - Plastik Kõva, Müüriplokk - Konstuktsioon, Krohv - Lubjakivi | 0,6 | 8 715; Kõrgus: 1 875; 3D pikkus: 2 030 | 8 715
7 x VS-09 | Katus | Membraan - Veekindel (2), Soojustus - Plastik Kõva, Müüriplokk - Konstuktsioon, Krohv - Lubjakivi | 1,8 | 8 715; Kõrgus: 1 700; 3D pikkus: 5 445 | 8 715
7 x VS-09 | Katus | Membraan - Veekindel (2), Soojustus - Plastik Kõva, Müüriplokk - Konstuktsioon, Krohv - Lubjakivi | 2,6 | 8 715; Kõrgus: 1 875; 3D pikkus: 5 450 | 8 715
3 x VS-09 | Katus | Membraan - Veekindel (2), Soojustus - Plastik Kõva, Müüriplokk - Konstuktsioon, Krohv - Lubjakivi | 0,7 | 8 715; Kõrgus: 2 000; 3D pikkus: 1 915 | 8 715
3 x VS-09 | Katus | Membraan - Veekindel (2), Soojustus - Plastik Kõva, Müüriplokk - Konstuktsioon, Krohv - Lubjakivi | 0,6 | 8 715; Kõrgus: 2 000; 3D pikkus: 1 910 | 8 715
3 x VS-09 | Katus | Membraan - Veekindel (2), Soojustus - Plastik Kõva, Müüriplokk - Konstuktsioon, Krohv - Lubjakivi | 1,5 | 8 715; Kõrgus: 1 700; 3D pikkus: 4 520 | 8 715
VS-09 | Katus | Membraan - Veekindel (2), Soojustus - Plastik Kõva, Müüriplokk - Konstuktsioon, Krohv - Lubjakivi | 1,8 | 8 715; Kõrgus: 1 650; 3D pikkus: 5 445 | 8 715
VS-09 | Katus | Membraan - Veekindel (2), Soojustus - Plastik Kõva, Müüriplokk - Konstuktsioon, Krohv - Lubjakivi | 0,7 | 8 715; Kõrgus: 1 650; 3D pikkus: 2 035 | 8 715
VS-09 | Katus | Membraan - Veekindel (2), Soojustus - Plastik Kõva, Müüriplokk - Konstuktsioon, Krohv - Lubjakivi | 2,6 | 8 715; Kõrgus: 1 650; 3D pikkus: 5 450 | 8 715

# IfcWallStandardCase: SS-01
In: 2 korrus
Type - ElementType: Element type SS-01
Classification: 0 TELLIJA KULUD (EHITUSKULUDE LIIGITAMINE EVS 885:2005); 1.18 IfcWall (sein) (_RKAS BIM + ARCHICAD Classification); Material: Krohv - Lubjakivi 10 mm, Müüriplokk - Konstuktsioon 200 mm, Krohv - Lubjakivi 10 mm
Arhitektuur - 01 Nimetus: Sisesein; 02 Materjal: Siseviimistlus; Lubikrohv 10mm; Kergplokk 200mm; Lubikrohv 10mm; Siseviimistlus; 03 Tähistus: SS-01; 04 Tulepüsivus: nõudeid ei esitata; 05 Asukoht: Interior; 06 Kandevelementide eristatus: Non-Load-Bearing Element; 07 Helipidavus: -; 08 Soojusläbivus (U-arv): -
Ehituskonstruktsioonid - 03 Tähistus või ristlõige: SS-01; 06 Maht (kubatuur): 0,8; 11 Ülemine kõrgusmärk: 7 615; Kõrgus: 1 100; 3D pikkus: 3 420; 12 Alumine kõrgusmärk: 7 615
AC_Pset_RenovationAndPhasing - Renovation Status: New
Pset_WallCommon - LoadBearing: no; IsExternal: no

# IfcWallStandardCase: SS-10 (2)
Type - ElementType: Element type SS-10
Classification: 1.18 IfcWall (sein) (_RKAS BIM + ARCHICAD Classification); Material: Krohv - Lubjakivi 10 mm, Raudbetoon - Konstruktsioon 200 mm, Krohv - Lubjakivi 10 mm
Arhitektuur - 01 Nimetus: Sisesein; 02 Materjal: Siseviimistlus; Lubikrohv 10mm; Monteeritav raudbetoonsein 200mm; Lubikrohv 10mm; Siseviimistlus; 03 Tähistus: SS-10; 04 Tulepüsivus: nõudeid ei esitata; 05 Asukoht: Interior; 06 Kandevelementide eristatus: Load-Bearing Element; 07 Helipidavus: -; 08 Soojusläbivus (U-arv): -
Ehituskonstruktsioonid - 03 Tähistus või ristlõige: SS-10
AC_Pset_RenovationAndPhasing - Renovation Status: New
Pset_WallCommon - LoadBearing: yes; IsExternal: no
Name | In | 06 Maht (kubatuur) | 11 Ülemine kõrgusmärk | 12 Alumine kõrgusmärk
SS-10 | 1 korrus | 0,3 | 885; Kõrgus: 500; 3D pikkus: 2 300 | 885
SS-10 | 1,5 korrus | 0,7 | 4 300; Kõrgus: 500; 3D pikkus: 6 670 | 4 300

# IfcWallStandardCase: SS-15
In: 1,5 korrus
Type - ElementType: Element type SS-15
Classification: 1.18 IfcWall (sein) (_RKAS BIM + ARCHICAD Classification); Material: Krohv - Lubjakivi 10 mm, Puitplaat 12 mm, Õhkvahe 276 mm, Puitplaat 12 mm, Krohv - Lubjakivi 10 mm
Arhitektuur - 01 Nimetus: Sisesein; 02 Materjal: Siseviimistlus; Lubikrohv 10mm; Puitlaastplaat 12mm; C-profiilis karkass; Puitlaastplaat 12mm; Lubikrohv 10mm; Siseviimistlus; 03 Tähistus: SS-15; 04 Tulepüsivus: nõudeid ei esitata; 05 Asukoht: Interior; 06 Kandevelementide eristatus: Load-Bearing Element; 07 Helipidavus: -; 08 Soojusläbivus (U-arv): -
Ehituskonstruktsioonid - 03 Tähistus või ristlõige: SS-15; 06 Maht (kubatuur): 0,4; 11 Ülemine kõrgusmärk: 4 290; Kõrgus: 510; 3D pikkus: 2 280; 12 Alumine kõrgusmärk: 4 290
AC_Pset_RenovationAndPhasing - Renovation Status: New
Pset_WallCommon - LoadBearing: yes; IsExternal: no

# IfcWallStandardCase: VS-03 (2)
In: 1 korrus
Type - ElementType: Element type VS-03
Material: Krohv - Lubjakivi 10 mm, Raudbetoon - Konstruktsioon 200 mm, Membraan - Veekindel 0 mm, Soojustus - Plastik Kõva 150 mm, Soojustus - Plastik Kõva 50 mm, Membraan - Veekindel 5 mm, Membraan - Veekindel 5 mm
Arhitektuur - 01 Nimetus: Välissein; 02 Materjal: Siseviimistlus; Lubikrohv 10mm; Monteeritav r/bet. seinapaneel 200mm; SBS bituumenhüdroisolatsioon; Vahtpolüstüreen soojustus EPS120 PERIMEETER 50+150mm; drenaazhimatt; Geotekstiil; Tihendatud pinnas (kesliiv); 03 Tähistus: VS-03; 04 Tulepüsivus: nõudeid ei esitata; 05 Asukoht: Exterior; 06 Kandevelementide eristatus: Load-Bearing Element; 08 Soojusläbivus (U-arv): 0,18 W/m2K
Ehituskonstruktsioonid - 03 Tähistus või ristlõige: VS-03
AC_Pset_RenovationAndPhasing - Renovation Status: New
Pset_WallCommon - LoadBearing: yes; IsExternal: yes
Name | Classification | 07 Helipidavus | 06 Maht (kubatuur) | 11 Ülemine kõrgusmärk | 12 Alumine kõrgusmärk
VS-03 | 0 TELLIJA KULUD (EHITUSKULUDE LIIGITAMINE EVS 885:2005); 1.18 IfcWall (sein) (_RKAS BIM + ARCHICAD Classification) | 60dB | 15,9 | -1 220; Kõrgus: 3 430; 3D pikkus: 11 005 | -1 220
VS-03 | 1.18 IfcWall (sein) (_RKAS BIM + ARCHICAD Classification) | 60 dB | 1,2 | 3 200; Kõrgus: 395; 3D pikkus: 7 458 | 3 200

# IfcWallStandardCase: VS-04, VS-03
In: 0 korrus
Type - ElementType: Element type VS-04
Classification: 1.18 IfcWall (sein) (_RKAS BIM + ARCHICAD Classification); Material: Krohv - Lubjakivi 10 mm, Raudbetoon - Konstruktsioon 200 mm, Membraan - Veekindel 0 mm, Soojustus - Plastik Kõva 150 mm, Soojustus - Plastik Kõva 50 mm, Membraan - Veekindel 5 mm, Membraan - Veekindel 5 mm
Arhitektuur - 01 Nimetus: Välissein; 02 Materjal: Siseviimistlus; Lubikrohv 10mm; SW r/b element 200mm; Hüdroisolatsioon; PIR soojusisolatsioon 150mm; PIR väline soojusisolatsioon 50mm; 03 Tähistus: VS-04; 04 Tulepüsivus: nõudeid ei esitata; 05 Asukoht: Exterior; 06 Kandevelementide eristatus: Load-Bearing Element; 07 Helipidavus: ≥48 dB; 08 Soojusläbivus (U-arv): 0,11 W/m2K
Ehituskonstruktsioonid - 03 Tähistus või ristlõige: VS-04; 06 Maht (kubatuur): 2,9; 11 Ülemine kõrgusmärk: -2 235; Kõrgus: 420; 3D pikkus: 16 270; 12 Alumine kõrgusmärk: -2 235
AC_Pset_RenovationAndPhasing - Renovation Status: New
Pset_WallCommon - LoadBearing: yes; IsExternal: yes

# IfcWallStandardCase: VS-05 (2)
In: 1 korrus
Type - ElementType: Element type VS-05
Classification: 1.18 IfcWall (sein) (_RKAS BIM + ARCHICAD Classification); Material: Krohv - Lubjakivi 10 mm, Raudbetoon - Konstruktsioon 200 mm, Membraan - Veekindel 0 mm, Soojustus - Plastik Kõva 150 mm, Soojustus - Plastik Kõva 50 mm, Plaat - Sein 8 mm
Arhitektuur - 01 Nimetus: Välissein; 02 Materjal: Siseviimistlus; Lubikrohv 10mm; r/b element 200mm; Hüdroisolatsioon; PIR soojusisolatsioon 150mm; PIR väline soojusisolatsioon 50mm; Tsementkiudplaat Minerit Pastell Grafit95 8 musta värvi) 8mm; 03 Tähistus: VS-05; 04 Tulepüsivus: nõudeid ei esitata; 05 Asukoht: Exterior; 06 Kandevelementide eristatus: Load-Bearing Element; 07 Helipidavus: 60 dB; 08 Soojusläbivus (U-arv): 0,18 W/m2K
Ehituskonstruktsioonid - 03 Tähistus või ristlõige: VS-05
AC_Pset_RenovationAndPhasing - Renovation Status: New
Pset_WallCommon - LoadBearing: yes; IsExternal: yes
Name | 06 Maht (kubatuur) | 11 Ülemine kõrgusmärk | 12 Alumine kõrgusmärk
VS-05 | 0,0 | 2 210; Kõrgus: 652; 3D pikkus: 138 | 2 210
VS-05 | 0,1 | 2 665; Kõrgus: 200; 3D pikkus: 1 049 | 2 665

# IfcWindow: 1015 x 2460 x 20, Klaasfassaadi integreeritud aken * CW Window 22
In: 1,5 korrus
Type - ParameterTakesPrecedence: no; Sizeable: no
Classification: 1.19 IfcWindow (aken) (_RKAS BIM + ARCHICAD Classification); Material: Aluminium MUST (16), Klaas
Avatäited - 01 Nimetus: Klaasfassaadi integreeritud aken; 02 Materjal: Metall, klaas; 06 Soojusläbivus: 0,8W/m2K; 07 Helipidavus: 35dB; 08 Veepidavus: 7A; 09 Õhuläbilaskvus: klass 4; 10 Tulekindlus: nõudeid ei esitata; 11 Vastupanu tulekoormusele: C3; 12 Klaaspakett: kolmekordne klaaspakett; 13 Klaasingu erisused: kolmekordne klaaspakett, välimine klaas karastatud, sisemine klaas lamineeritud, klaaside vahelised liistud musta värvi; 15 Avanemine: sissepoole paremale; 16 Liigendatus: -; 17 Sulused, lukustus: Link tootekeskne TBT (Tilt Before Turn) harjatud roostevaba viimistlusega, link kooskõlastada eelnevalt arhitektiga. Pöördavatav asend avatav ainult võtmega! Kaldavatav asend on avatav ilma võtmeta. Hinged tootekeskesed.; 18 Viimistlus: Raam ja leng on värvitud tumehalliks RAL 7016 (Anthrazitgrau).; 19 Mudel või toote tunnus: AWS 70.HI (või samaväärne analoog); 20 Tootja: Schüco (või samaväärne analoog); 21 Tooteinfo: Undefined; 22 Kasutus- ja hooldusjuhend: Undefined; 14 Päikesekiirgus tegur (g-väärtus): 0,38; 23 viide sõlmele: Undefined
Pset_ManufacturerOccurrence - SerialNumber: Off
AC_Pset_RenovationAndPhasing - Renovation Status: New

# IfcWindow: 1045 x 2320 x 20, Klaasfassaadi integreeritud mehhaaniliselt avatav suitsuärastusaken * CW Window 22
In: 1 korrus
Type - ParameterTakesPrecedence: no; Sizeable: no
Classification: 1.19 IfcWindow (aken) (_RKAS BIM + ARCHICAD Classification); Material: Aluminium MUST (16), Klaas
Avatäited - 01 Nimetus: Klaasfassaadi integreeritud mehhaaniliselt avatav suitsuärastusaken; 02 Materjal: Metall, klaas; 06 Soojusläbivus: 0,74W/m2K; 07 Helipidavus: 34dB; 08 Veepidavus: 7A; 09 Õhuläbilaskvus: klass 4; 10 Tulekindlus: nõudeid ei esitata; 11 Vastupanu tulekoormusele: C3; 12 Klaaspakett: kolmekordne klaaspakett; 13 Klaasingu erisused: kolmekordne klaaspakett, välimine klaas lamineeritud, sisemine klaas karastatud, klaaside vahelised liistud musta värvi; 15 Avanemine: Sissepoole vasakule, peab olema avatav mehhaaniliselt, kaabeldus ei tohi jääda nähtavale.; 16 Liigendatus: -; 17 Sulused, lukustus: Sissepoole vasakule, peab olema avatav mehhaaniliselt, kaabeldus ei tohi jääda nähtavale.; 18 Viimistlus: Raam ja leng on värvitud tumehalliks RAL 7016 (Anthrazitgrau).; 19 Mudel või toote tunnus: AWS 70.HI (või samaväärne analoog); 20 Tootja: Schüco (või samaväärne analoog); 21 Tooteinfo: Undefined; 22 Kasutus- ja hooldusjuhend: Undefined; 14 Päikesekiirgus tegur (g-väärtus): 0,58; 23 viide sõlmele: Undefined
Pset_ManufacturerOccurrence - SerialNumber: Off
AC_Pset_RenovationAndPhasing - Renovation Status: New

# IfcWindow: 1045 x 2655 x 20, Klaasfassaadi integreeritud aken * CW Window 22
In: 1 korrus
Type - ParameterTakesPrecedence: no; Sizeable: no
Classification: 0 TELLIJA KULUD (EHITUSKULUDE LIIGITAMINE EVS 885:2005); 1.19 IfcWindow (aken) (_RKAS BIM + ARCHICAD Classification); Material: Aluminium MUST (16), Klaas
Avatäited - 01 Nimetus: Klaasfassaadi integreeritud aken; 02 Materjal: Metall, klaas; 06 Soojusläbivus: 0,8W/m2K; 07 Helipidavus: 35dB; 08 Veepidavus: 7A; 09 Õhuläbilaskvus: klass 4; 10 Tulekindlus: nõudeid ei esitata; 11 Vastupanu tulekoormusele: C3; 12 Klaaspakett: kolmekordne klaaspakett; 13 Klaasingu erisused: kolmekordne klaaspakett, välimine klaas karastatud, sisemine klaas lamineeritud, klaaside vahelised liistud musta värvi; 15 Avanemine: sissepoole paremale; 16 Liigendatus: -; 17 Sulused, lukustus: Link tootekeskne TBT (Tilt Before Turn) harjatud roostevaba viimistlusega, link kooskõlastada eelnevalt arhitektiga. Pöördavatav asend avatav ainult võtmega! Kaldavatav asend on avatav ilma võtmeta. Hinged tootekeskesed.; 18 Viimistlus: Raam ja leng on värvitud tumehalliks RAL 7016 (Anthrazitgrau); 19 Mudel või toote tunnus: AWS 70.HI (või samaväärne analoog); 20 Tootja: Schüco (või samaväärne analoog); 21 Tooteinfo: Undefined; 22 Kasutus- ja hooldusjuhend: Undefined; 14 Päikesekiirgus tegur (g-väärtus): 0,58; 23 viide sõlmele: Undefined
Pset_ManufacturerOccurrence - SerialNumber: Off
AC_Pset_RenovationAndPhasing - Renovation Status: New

# IfcWindow: 1195 x 2655 x 20, Klaasfassaadi integreeritud aken * CW Window 22
In: 1 korrus
Type - ParameterTakesPrecedence: no; Sizeable: no
Classification: 1.19 IfcWindow (aken) (_RKAS BIM + ARCHICAD Classification); Material: Aluminium MUST (16), Klaas
Avatäited - 01 Nimetus: Klaasfassaadi integreeritud aken; 02 Materjal: Metall, klaas; 06 Soojusläbivus: 0,8W/m2K; 07 Helipidavus: 35dB; 08 Veepidavus: 7A; 09 Õhuläbilaskvus: klass 4; 10 Tulekindlus: nõudeid ei esitata; 11 Vastupanu tulekoormusele: C3; 12 Klaaspakett: kolmekordne klaaspakett; 13 Klaasingu erisused: kolmekordne klaaspakett, välimine klaas karastatud, sisemine klaas lamineeritud, klaaside vahelised liistud musta värvi; 15 Avanemine: sissepoole vasakule; 16 Liigendatus: -; 17 Sulused, lukustus: Link tootekeskne TBT (Tilt Before Turn) harjatud roostevaba viimistlusega, link kooskõlastada eelnevalt arhitektiga. Pöördavatav asend avatav ainult võtmega! Kaldavatav asend on avatav ilma võtmeta. Hinged tootekeskesed.; 18 Viimistlus: Raam ja leng on värvitud tumehalliks RAL 7016 (Anthrazitgrau).; 19 Mudel või toote tunnus: AWS 70.HI (või samaväärne analoog); 20 Tootja: Schüco (või samaväärne analoog); 21 Tooteinfo: Undefined; 22 Kasutus- ja hooldusjuhend: Undefined; 14 Päikesekiirgus tegur (g-väärtus): 0,58; 23 viide sõlmele: Undefined
Pset_ManufacturerOccurrence - SerialNumber: Off
AC_Pset_RenovationAndPhasing - Renovation Status: New

# IfcWindow: 1260 x 2320 x 20, Klaasfassaadi integreeritud mehhaaniliselt avatav suitsuärastusaken * CW Window 22
In: 1 korrus
Type - ParameterTakesPrecedence: no; Sizeable: no
Classification: 1.19 IfcWindow (aken) (_RKAS BIM + ARCHICAD Classification); Material: Aluminium MUST (16), Klaas
Avatäited - 01 Nimetus: Klaasfassaadi integreeritud mehhaaniliselt avatav suitsuärastusaken; 02 Materjal: Metall, klaas; 06 Soojusläbivus: 0,74W/m2K; 07 Helipidavus: 34dB; 08 Veepidavus: 7A; 09 Õhuläbilaskvus: klass 4; 10 Tulekindlus: nõudeid ei esitata; 11 Vastupanu tulekoormusele: C3; 12 Klaaspakett: kolmekordne klaaspakett; 13 Klaasingu erisused: kolmekordne klaaspakett, välimine klaas lamineeritud, sisemine klaas karastatud, klaaside vahelised liistud musta värvi; 15 Avanemine: Sissepoole vasakule; 16 Liigendatus: -; 17 Sulused, lukustus: Elektrooniliselt pöördavatav. Lukustus vastavalt tootjale. Hinged tootekeskesed. Kaabeldus ei tohi olla nähtaval.; 18 Viimistlus: Raam ja leng on värvitud tumehalliks RAL 7016 (Anthrazitgrau).; 19 Mudel või toote tunnus: AWS 70.HI (või samaväärne analoog); 20 Tootja: Schüco (või samaväärne analoog); 21 Tooteinfo: Undefined; 22 Kasutus- ja hooldusjuhend: Undefined; 14 Päikesekiirgus tegur (g-väärtus): 0,58; 23 viide sõlmele: Undefined
Pset_ManufacturerOccurrence - SerialNumber: Off
AC_Pset_RenovationAndPhasing - Renovation Status: New

# IfcWindow: 1260 x 2655 x 20 (2)
In: 1 korrus
Type - ParameterTakesPrecedence: no; Sizeable: no
Classification: 1.19 IfcWindow (aken) (_RKAS BIM + ARCHICAD Classification); Material: Aluminium MUST (16), Klaas
Avatäited - 01 Nimetus: Klaasfassaadi integreeritud aken; 02 Materjal: Metall, klaas; 06 Soojusläbivus: 0,8W/m2K; 07 Helipidavus: 35dB; 08 Veepidavus: 7A; 09 Õhuläbilaskvus: klass 4; 10 Tulekindlus: nõudeid ei esitata; 11 Vastupanu tulekoormusele: C3; 12 Klaaspakett: kolmekordne klaaspakett; 13 Klaasingu erisused: kolmekordne klaaspakett, välimine klaas karastatud, sisemine klaas lamineeritud, klaaside vahelised liistud musta värvi; 16 Liigendatus: -; 17 Sulused, lukustus: Link tootekeskne TBT (Tilt Before Turn) harjatud roostevaba viimistlusega, link kooskõlastada eelnevalt arhitektiga. Pöördavatav asend avatav ainult võtmega! Kaldavatav asend on avatav ilma võtmeta. Hinged tootekeskesed.; 18 Viimistlus: Raam ja leng on värvitud tumehalliks RAL 7016 (Anthrazitgrau).; 19 Mudel või toote tunnus: AWS 70.HI (või samaväärne analoog); 20 Tootja: Schüco (või samaväärne analoog); 21 Tooteinfo: Undefined; 22 Kasutus- ja hooldusjuhend: Undefined; 14 Päikesekiirgus tegur (g-väärtus): 0,58; 23 viide sõlmele: Undefined
Pset_ManufacturerOccurrence - SerialNumber: Off
AC_Pset_RenovationAndPhasing - Renovation Status: New
Name | 15 Avanemine
Klaasfassaadi integreeritud aken * CW Window 22 | sissepoole vasakule
Klaasfassaadi integreeritud aken * CW Window 22 | sissepoole paremale

# IfcWindow: 680 x 2660 x 20, Klaasfassaadi integreeritud aken * CW Window 22
In: 2 korrus
Type - ParameterTakesPrecedence: no; Sizeable: no
Classification: 0 TELLIJA KULUD (EHITUSKULUDE LIIGITAMINE EVS 885:2005); 1.19 IfcWindow (aken) (_RKAS BIM + ARCHICAD Classification); Material: Aluminium MUST (16), Klaas
Avatäited - 01 Nimetus: Klaasfassaadi integreeritud aken; 02 Materjal: Metall, klaas; 06 Soojusläbivus: 0,8W/m2K; 07 Helipidavus: 35dB; 08 Veepidavus: 7A; 09 Õhuläbilaskvus: klass 4; 10 Tulekindlus: nõudeid ei esitata; 11 Vastupanu tulekoormusele: C3; 12 Klaaspakett: kolmekordne klaaspakett; 13 Klaasingu erisused: kolmekordne klaaspakett, välimine klaas karastatud, sisemine klaas lamineeritud, klaaside vahelised liistud musta värvi; 15 Avanemine: Sissepoole paremale; 16 Liigendatus: -; 17 Sulused, lukustus: Link tootekeskne TBT (Tilt Before Turn) harjatud roostevaba viimistlusega, link kooskõlastada eelnevalt arhitektiga. Pöördavatav asend avatav ainult võtmega! Kaldavatav asend on avatav ilma võtmeta. Hinged tootekeskesed.; 18 Viimistlus: Raam ja leng on värvitud tumehalliks RAL 7016 (Anthrazitgrau).; 19 Mudel või toote tunnus: AWS 70.HI (või samaväärne analoog); 20 Tootja: Schüco (või samaväärne analoog); 21 Tooteinfo: Undefined; 22 Kasutus- ja hooldusjuhend: Undefined; 14 Päikesekiirgus tegur (g-väärtus): 0,38; 23 viide sõlmele: Undefined
Pset_ManufacturerOccurrence - SerialNumber: Off
AC_Pset_RenovationAndPhasing - Renovation Status: New

# IfcWindow: 720 x 2510 x 20, Klaasfassaadi integreeritud aken * CW Window 22
In: 0 korrus
Type - ParameterTakesPrecedence: no; Sizeable: no
Classification: 1.19 IfcWindow (aken) (_RKAS BIM + ARCHICAD Classification); Material: Aluminium MUST (16), Klaas
Avatäited - 01 Nimetus: Klaasfassaadi integreeritud aken; 02 Materjal: Metall, klaas; 06 Soojusläbivus: 0,8W/m2K; 07 Helipidavus: 35dB; 08 Veepidavus: 7A; 09 Õhuläbilaskvus: klass 4; 10 Tulekindlus: nõudeid ei esitata; 11 Vastupanu tulekoormusele: C3; 12 Klaaspakett: kolmekordne klaaspakett; 13 Klaasingu erisused: kolmekordne klaaspakett, välimine klaas karastatud, sisemine klaas lamineeritud, klaaside vahelised liistud musta värvi; 15 Avanemine: sissepoole paremale; 16 Liigendatus: -; 17 Sulused, lukustus: Link tootekeskne TBT (Tilt Before Turn) harjatud roostevaba viimistlusega, link kooskõlastada eelnevalt arhitektiga. Pöördavatav asend avatav ainult võtmega! Kaldavatav asend on avatav ilma võtmeta. Hinged tootekeskesed.; 18 Viimistlus: Raam ja leng on värvitud tumehalliks RAL 7016 (Anthrazitgrau).; 19 Mudel või toote tunnus: AWS 70.HI (või samaväärne analoog); 20 Tootja: Schüco (või samaväärne analoog); 21 Tooteinfo: Undefined; 22 Kasutus- ja hooldusjuhend: Undefined; 14 Päikesekiirgus tegur (g-väärtus): 0,38; 23 viide sõlmele: Undefined
Pset_ManufacturerOccurrence - SerialNumber: Off
AC_Pset_RenovationAndPhasing - Renovation Status: New

# IfcWindow: 845 x 2660 x 20, Klaasfassaadi integreeritud aken * CW Window 22
In: 2 korrus
Type - ParameterTakesPrecedence: no; Sizeable: no
Classification: 0 TELLIJA KULUD (EHITUSKULUDE LIIGITAMINE EVS 885:2005); 1.19 IfcWindow (aken) (_RKAS BIM + ARCHICAD Classification); Material: Aluminium MUST (16), Klaas
Avatäited - 01 Nimetus: Klaasfassaadi integreeritud aken; 02 Materjal: Metall, klaas; 06 Soojusläbivus: 0,8W/m2K; 07 Helipidavus: 35dB; 08 Veepidavus: 7A; 09 Õhuläbilaskvus: klass 4; 10 Tulekindlus: nõudeid ei esitata; 11 Vastupanu tulekoormusele: C3; 12 Klaaspakett: kolmekordne klaaspakett; 13 Klaasingu erisused: kolmekordne klaaspakett, välimine klaas karastatud, sisemine klaas lamineeritud, klaaside vahelised liistud musta värvi; 15 Avanemine: sissepoole paremale; 16 Liigendatus: -; 17 Sulused, lukustus: Link tootekeskne TBT (Tilt Before Turn) harjatud roostevaba viimistlusega, link kooskõlastada eelnevalt arhitektiga. Pöördavatav asend avatav ainult võtmega! Kaldavatav asend on avatav ilma võtmeta. Hinged tootekeskesed.; 18 Viimistlus: Raam ja leng on värvitud tumehalliks RAL 7016 (Anthrazitgrau).; 19 Mudel või toote tunnus: AWS 70.HI (või samaväärne analoog); 20 Tootja: Schüco (või samaväärne analoog); 21 Tooteinfo: Undefined; 22 Kasutus- ja hooldusjuhend: Undefined; 14 Päikesekiirgus tegur (g-väärtus): 0,38; 23 viide sõlmele: Undefined
Pset_ManufacturerOccurrence - SerialNumber: Off
AC_Pset_RenovationAndPhasing - Renovation Status: New

# IfcWindow: 990 x 2660 x 20, Klaasfassaadi integreeritud aken * CW Window 22
In: 2 korrus
Type - ParameterTakesPrecedence: no; Sizeable: no
Classification: 0 TELLIJA KULUD (EHITUSKULUDE LIIGITAMINE EVS 885:2005); 1.19 IfcWindow (aken) (_RKAS BIM + ARCHICAD Classification); Material: Aluminium MUST (16), Klaas
Avatäited - 01 Nimetus: Klaasfassaadi integreeritud aken; 02 Materjal: Metall, klaas; 06 Soojusläbivus: 0,8W/m2K; 07 Helipidavus: 35dB; 08 Veepidavus: 7A; 09 Õhuläbilaskvus: klass 4; 10 Tulekindlus: nõudeid ei esitata; 11 Vastupanu tulekoormusele: C3; 12 Klaaspakett: kolmekordne klaaspaket; 13 Klaasingu erisused: kolmekordne klaaspakett, välimine klaas karastatud, sisemine klaas lamineeritud, klaaside vahelised liistud musta värvi; 15 Avanemine: sissepoole paremale; 16 Liigendatus: -; 17 Sulused, lukustus: Link tootekeskne TBT (Tilt Before Turn) harjatud roostevaba viimistlusega, link kooskõlastada eelnevalt arhitektiga. Pöördavatav asend avatav ainult võtmega! Kaldavatav asend on avatav ilma võtmeta. Hinged tootekeskesed.; 18 Viimistlus: Raam ja leng on värvitud tumehalliks RAL 7016 (Anthrazitgrau).; 19 Mudel või toote tunnus: AWS 70.HI (või samaväärne analoog); 20 Tootja: Schüco (või samaväärne analoog); 21 Tooteinfo: Undefined; 22 Kasutus- ja hooldusjuhend: Undefined; 14 Päikesekiirgus tegur (g-väärtus): 0,38; 23 viide sõlmele: Undefined
Pset_ManufacturerOccurrence - SerialNumber: Off
AC_Pset_RenovationAndPhasing - Renovation Status: New

# IfcWindow: A-01 700×1 200 (19)
In: 1 korrus
Type - OperationType: SINGLE_PANEL; ParameterTakesPrecedence: no; Sizeable: no
Type - Window Lining Properties - LiningDepth: 50 mm; LiningThickness: 50 mm
Type - Window Panel Properties - Panel 1 - OperationType: TILTANDTURNLEFTHAND; PanelPosition: MIDDLE; FrameDepth: 50 mm; FrameThickness: 50 mm
OverallHeight: 1200 mm; OverallWidth: 700 mm; Classification: 0 TELLIJA KULUD (EHITUSKULUDE LIIGITAMINE EVS 885:2005); 1.19 IfcWindow (aken) (_RKAS BIM + ARCHICAD Classification)
Pset_WindowCommon - ThermalTransmittance: 0; GlazingAreaFraction: 0.5775; IsExternal: yes
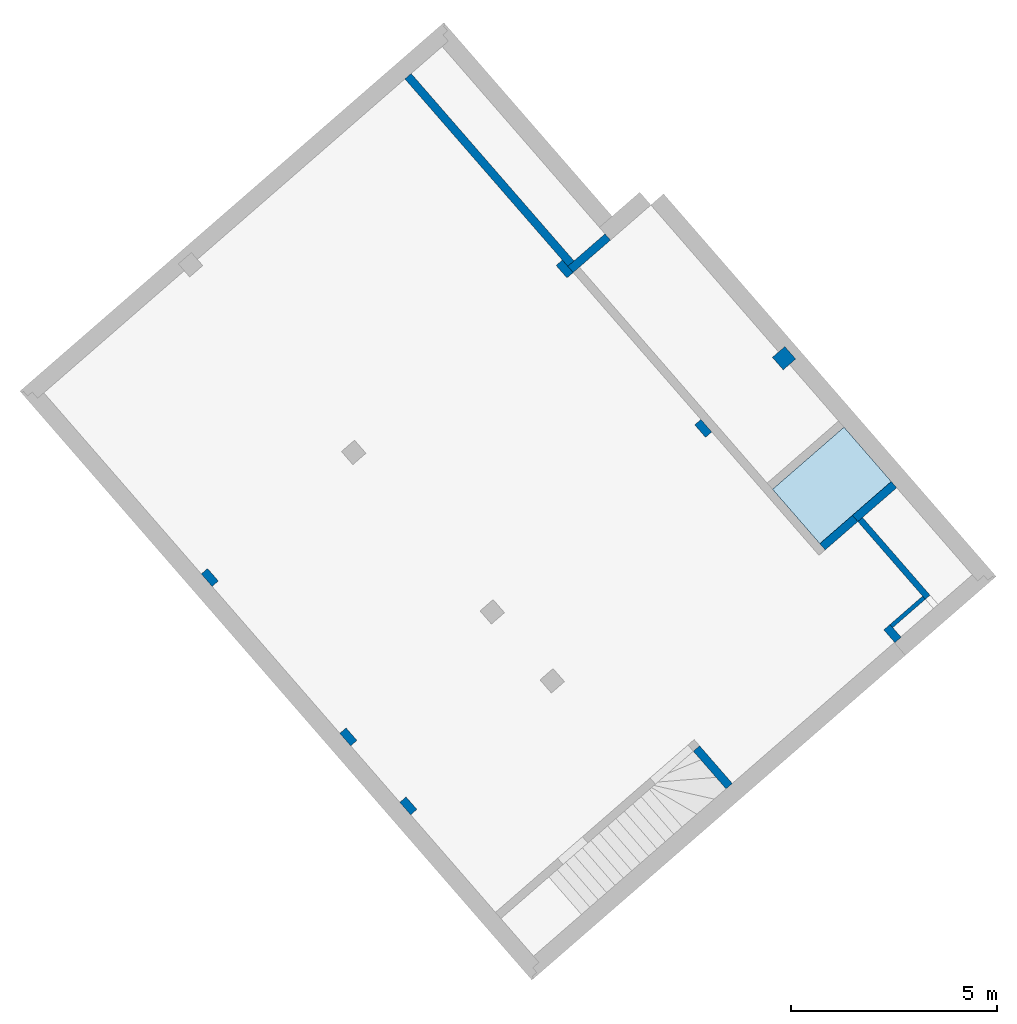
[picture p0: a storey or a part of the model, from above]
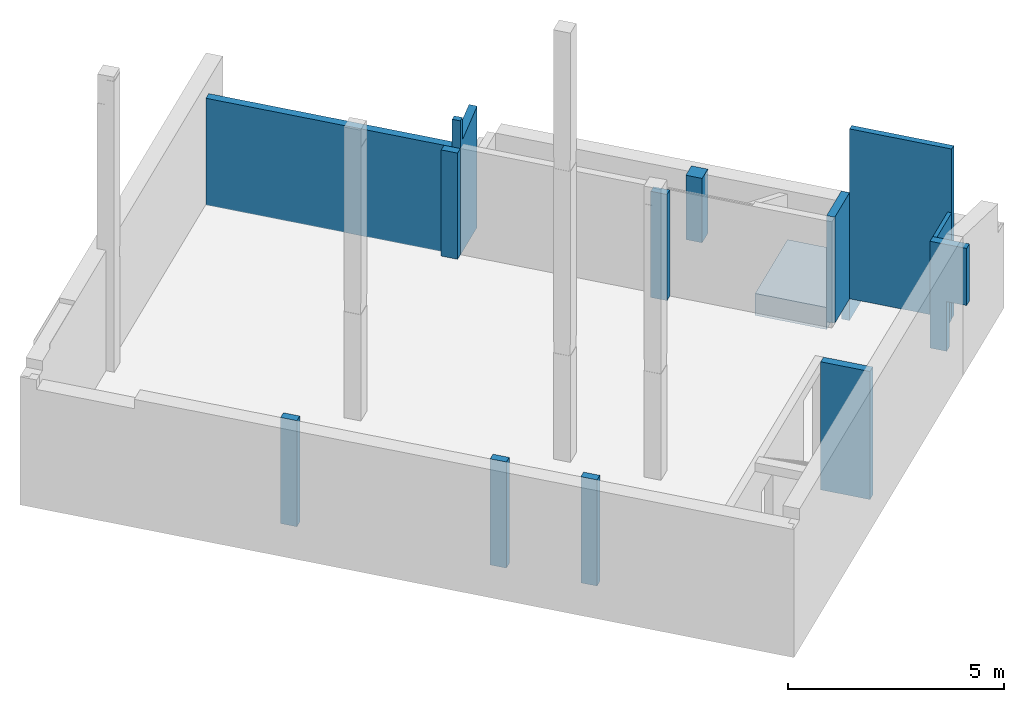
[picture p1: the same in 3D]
Properties of the parts of a building model (IFC2X3), part 13 of 13

# IfcWindow: A-01 700×1 200 (19)
Avatäited - 01 Nimetus: Välisaken; 02 Materjal: Puitalumiiniumprofiiliga klaaspakett; 03 Tähistus: A-01 700×1 200; 04 Avamõõdu geomeetria: 700×1 200; 05 Asukoha info: Exterior; 06 Soojusläbivus: 0,74W/m2K; 07 Helipidavus: 34dB; 08 Veepidavus: 7A; 09 Õhuläbilaskvus: klass 4; 10 Tulekindlus: nõudeid ei esitata; 11 Vastupanu tulekoormusele: C3; 12 Klaaspakett: Kolmekordne klaaspakett; 13 Klaasingu erisused: Sisemine klaas lamineeritud, välimine klaaskarastatud; 15 Avanemine: Sisse; 16 Liigendatus: -; 17 Sulused, lukustus: Link TBT (Tilt Before Turn) Hoppe London (matt kroomi viimistlusega), Pöördavatav asend avatav ainult võtmega! Link paigaldada aknaraami alumisse osasse. Hinged tootekeskesed, hingede viimistlus sama, mis akna raamil.; 18 Viimistlus: Raam ja leng on RAL 7016 (Anthrazitgrau). Akna kinnituskruvid ei tohi nähtavale jääda, aktsepteeritavad ei ole ka korkidega kaetud kruviaugud.; 19 Mudel või toote tunnus: DK88 (või samaväärne analoog); 20 Tootja: Viking Window AS (või samaväärne analoog); 21 Tooteinfo: Undefined; 22 Kasutus- ja hooldusjuhend: Undefined; 14 Päikesekiirgus tegur (g-väärtus): 0,38; 23 viide sõlmele: Undefined
AC_Pset_RenovationAndPhasing - Renovation Status: New

# IfcWindow: A-02 700×2 500 (17)
In: 1,5 korrus
Type - OperationType: SINGLE_PANEL; ParameterTakesPrecedence: no; Sizeable: no
Type - Window Lining Properties - LiningDepth: 50 mm; LiningThickness: 50 mm
Type - Window Panel Properties - Panel 1 - OperationType: TILTANDTURNRIGHTHAND; PanelPosition: MIDDLE; FrameDepth: 50 mm; FrameThickness: 50 mm
OverallHeight: 2500 mm; OverallWidth: 700 mm; Classification: 0 TELLIJA KULUD (EHITUSKULUDE LIIGITAMINE EVS 885:2005); 1.19 IfcWindow (aken) (_RKAS BIM + ARCHICAD Classification)
Pset_WindowCommon - ThermalTransmittance: 0; GlazingAreaFraction: 1.2925; IsExternal: yes
Avatäited - 01 Nimetus: Välisaken; 02 Materjal: Puitalumiiniumprofiiliga klaaspakett; 03 Tähistus: A-02 700×2 500; 04 Avamõõdu geomeetria: 700×2 500; 05 Asukoha info: Exterior; 06 Soojusläbivus: 0,74W/m2K; 07 Helipidavus: 34dB; 08 Veepidavus: 7A; 09 Õhuläbilaskvus: klass 4; 10 Tulekindlus: nõudeid ei esitata; 11 Vastupanu tulekoormusele: C3; 12 Klaaspakett: Kolmekordne klaaspakett; 13 Klaasingu erisused: Sisemine klaas lamineeritud, välimine klaaskarastatud; 15 Avanemine: Sisse; 16 Liigendatus: -; 17 Sulused, lukustus: Link TBT (Tilt Before Turn) Hoppe London (matt kroomi viimistlusega), Pöördavatav asend avatav ainult võtmega! Hinged tootekeskesed, hingede viimistlus sama, mis akna raamil.; 18 Viimistlus: Raam ja leng on värvitud tumehalliks RAL 7016 (Anthrazitgrau). Akna kinnituskruvid ei tohi jääda nähtavale, aktsepteeritavad ei ole ka korkidega kaetud kruviaugud.; 19 Mudel või toote tunnus: DK88 (või samaväärne analoog); 20 Tootja: Viking Window AS (või samaväärne analoog); 21 Tooteinfo: Undefined; 22 Kasutus- ja hooldusjuhend: Undefined; 14 Päikesekiirgus tegur (g-väärtus): 0,38; 23 viide sõlmele: Undefined
AC_Pset_RenovationAndPhasing - Renovation Status: New

# IfcWindow: A-03 700×2 700 (50)
Type - OperationType: SINGLE_PANEL; ParameterTakesPrecedence: no; Sizeable: no
Type - Window Lining Properties - LiningDepth: 50 mm; LiningThickness: 50 mm
Type - Window Panel Properties - Panel 1 - OperationType: TILTANDTURNLEFTHAND; PanelPosition: MIDDLE; FrameDepth: 50 mm; FrameThickness: 50 mm
OverallHeight: 2700 mm; OverallWidth: 700 mm; Classification: 0 TELLIJA KULUD (EHITUSKULUDE LIIGITAMINE EVS 885:2005); 1.19 IfcWindow (aken) (_RKAS BIM + ARCHICAD Classification)
Pset_WindowCommon - ThermalTransmittance: 0; GlazingAreaFraction: 1.4025; IsExternal: yes
Avatäited - 01 Nimetus: Välisaken; 02 Materjal: Puitalumiiniumprofiiliga klaaspakett; 03 Tähistus: A-03 700×2 700; 04 Avamõõdu geomeetria: 700×2 700; 05 Asukoha info: Exterior; 06 Soojusläbivus: 0,74W/m2K; 07 Helipidavus: 34dB; 08 Veepidavus: 7A; 10 Tulekindlus: nõudeid ei esitata; 11 Vastupanu tulekoormusele: C3; 12 Klaaspakett: Kolmekordne klaaspakett; 13 Klaasingu erisused: Sisemine klaas lamineeritud, välimine klaaskarastatud; 15 Avanemine: Sisse; 16 Liigendatus: -; 19 Mudel või toote tunnus: DK88 (või samaväärne analoog); 20 Tootja: Viking Window AS (või samaväärne analoog); 21 Tooteinfo: Undefined; 22 Kasutus- ja hooldusjuhend: Undefined; 14 Päikesekiirgus tegur (g-väärtus): 0,38; 23 viide sõlmele: Undefined
AC_Pset_RenovationAndPhasing - Renovation Status: New
Name | In | 09 Õhuläbilaskvus | 17 Sulused, lukustus | 18 Viimistlus
11 x Välisaken * Window 22 | 1 korrus | klass 4 | Link TBT (Tilt Before Turn) Hoppe London (matt kroomi viimistlusega), Pöördavatav asend avatav ainult võtmega! Hinged tootekeskesed, hingede viimistlus sama, mis akna raamil. | Raam ja leng on värvitud tumehalliks RAL 7016 (Anthrazitgrau). Akna kinnituskruvid ei tohi nähtavale jääda, aktsepteeritavad ei ole ka korkidega kaetud kruviaugud.
39 x Välisaken * Window 22 | 2 korrus | Klass 4 | Link TBT (Tilt Before Turn) Hoppe London (matt kroomi viimistlusega), Pöördavatav asend avatav ainult võtmega! Hinged tootekeskesed, hingede viimistlus sama, mis aknaraamil. | Raam ja leng on värvitud tumehalliks RAL 7016 (Anthrazitgrau). Akna kinnituskruvid ei tohi jääda nähtavale, aktsepteeritavad ei ole ka korkidega kaetud kruviaugud.

# IfcWindow: A-03 700×2 700 (43)
In: 2 korrus
Type - OperationType: SINGLE_PANEL; ParameterTakesPrecedence: no; Sizeable: no
Type - Window Lining Properties - LiningDepth: 50 mm; LiningThickness: 50 mm
Type - Window Panel Properties - Panel 1 - OperationType: TILTANDTURNRIGHTHAND; PanelPosition: MIDDLE; FrameDepth: 50 mm; FrameThickness: 50 mm
OverallHeight: 2700 mm; OverallWidth: 700 mm
Pset_WindowCommon - ThermalTransmittance: 0; GlazingAreaFraction: 1.4025; IsExternal: yes
Avatäited - 01 Nimetus: Välisaken; 02 Materjal: Puitalumiiniumprofiiliga klaaspakett; 03 Tähistus: A-03 700×2 700; 04 Avamõõdu geomeetria: 700×2 700; 05 Asukoha info: Exterior; 06 Soojusläbivus: 0,74W/m2K; 07 Helipidavus: 34dB; 08 Veepidavus: 7A; 09 Õhuläbilaskvus: Klass 4; 10 Tulekindlus: nõudeid ei esitata; 11 Vastupanu tulekoormusele: C3; 12 Klaaspakett: Kolmekordne klaaspakett; 13 Klaasingu erisused: Sisemine klaas lamineeritud, välimine klaaskarastatud; 15 Avanemine: Sisse; 16 Liigendatus: -; 17 Sulused, lukustus: Link TBT (Tilt Before Turn) Hoppe London (matt kroomi viimistlusega), Pöördavatav asend avatav ainult võtmega! Hinged tootekeskesed, hingede viimistlus sama, mis aknaraamil.; 18 Viimistlus: Raam ja leng on värvitud tumehalliks RAL 7016 (Anthrazitgrau). Akna kinnituskruvid ei tohi jääda nähtavale, aktsepteeritavad ei ole ka korkidega kaetud kruviaugud.; 19 Mudel või toote tunnus: DK88 (või samaväärne analoog); 20 Tootja: Viking Window AS (või samaväärne analoog); 21 Tooteinfo: Undefined; 22 Kasutus- ja hooldusjuhend: Undefined; 14 Päikesekiirgus tegur (g-väärtus): 0,38; 23 viide sõlmele: Undefined
AC_Pset_RenovationAndPhasing - Renovation Status: New
Name | Classification
42 x Välisaken * Window 22 | 0 TELLIJA KULUD (EHITUSKULUDE LIIGITAMINE EVS 885:2005); 1.19 IfcWindow (aken) (_RKAS BIM + ARCHICAD Classification)
Välisaken * Window 22 | 1.19 IfcWindow (aken) (_RKAS BIM + ARCHICAD Classification)

# IfcWindow: A-04 1 000×2 700, Välisaken * Window 22
In: 2 korrus
Type - OperationType: SINGLE_PANEL; ParameterTakesPrecedence: no; Sizeable: no
Type - Window Lining Properties - LiningDepth: 50 mm; LiningThickness: 50 mm
Type - Window Panel Properties - Panel 1 - OperationType: TILTANDTURNRIGHTHAND; PanelPosition: MIDDLE; FrameDepth: 50 mm; FrameThickness: 50 mm
OverallHeight: 2700 mm; OverallWidth: 999.941 mm; Classification: 0 TELLIJA KULUD (EHITUSKULUDE LIIGITAMINE EVS 885:2005); 1.19 IfcWindow (aken) (_RKAS BIM + ARCHICAD Classification)
Pset_WindowCommon - ThermalTransmittance: 0; GlazingAreaFraction: 2.16735; IsExternal: yes
Avatäited - 01 Nimetus: Välisaken; 02 Materjal: Puitalumiiniumprofiiliga klaaspakett; 03 Tähistus: A-04 1 000×2 700; 04 Avamõõdu geomeetria: 1 000×2 700; 05 Asukoha info: Exterior; 06 Soojusläbivus: 0,74W/m2K; 07 Helipidavus: 34dB; 08 Veepidavus: 7A; 09 Õhuläbilaskvus: klass 4; 10 Tulekindlus: nõudeid ei esitata; 11 Vastupanu tulekoormusele: C3; 12 Klaaspakett: kolmekordne klaaspakett, klaaside vahelised liistud musta värvi; 13 Klaasingu erisused: sisemine klaas lamineeritud, välimine klaas karastatud; 15 Avanemine: Sisse; 16 Liigendatus: -; 17 Sulused, lukustus: Link TBT (Tilt Before Turn) Hoppe London (matt kroomi viimistlusega), Pöördavatav asend avatav ainult võtmega! Hinged tootekeskesed, hingede viimistlus sama, mis aknaraamil.; 18 Viimistlus: Raam ja leng on värvitud tumehalliks RAL 7016 (Anthrazitgrau). Akna kinnituskruvid ei tohi jääda nähtavale, aktsepteeritavad ei ole ka korkidega kaetud kruviaugud.; 19 Mudel või toote tunnus: DK88 (või samaväärne analoog); 20 Tootja: Viking Window AS (või samaväärne analoog); 21 Tooteinfo: Undefined; 22 Kasutus- ja hooldusjuhend: Undefined; 14 Päikesekiirgus tegur (g-väärtus): 0,38; 23 viide sõlmele: Undefined
AC_Pset_RenovationAndPhasing - Renovation Status: New

# IfcWindow: A-13 1 150×2 700, Välisaken * Window 22
In: 2 korrus
Type - OperationType: SINGLE_PANEL; ParameterTakesPrecedence: no; Sizeable: no
Type - Window Lining Properties - LiningDepth: 50 mm; LiningThickness: 50 mm
Type - Window Panel Properties - Panel 1 - OperationType: TILTANDTURNLEFTHAND; PanelPosition: MIDDLE; FrameDepth: 50 mm; FrameThickness: 50 mm
OverallHeight: 2700 mm; OverallWidth: 1150 mm; Classification: 0 TELLIJA KULUD (EHITUSKULUDE LIIGITAMINE EVS 885:2005); 1.19 IfcWindow (aken) (_RKAS BIM + ARCHICAD Classification)
Pset_WindowCommon - ThermalTransmittance: 0; GlazingAreaFraction: 2.55; IsExternal: yes
Avatäited - 01 Nimetus: Välisaken; 02 Materjal: Puitalumiiniumprofiiliga klaaspakett; 03 Tähistus: A-13 1 150×2 700; 04 Avamõõdu geomeetria: 1 150×2 700; 05 Asukoha info: Exterior; 06 Soojusläbivus: 0,74W/m2K; 07 Helipidavus: 34dB; 08 Veepidavus: A7; 09 Õhuläbilaskvus: klass 4; 10 Tulekindlus: nõudeid ei esitata; 11 Vastupanu tulekoormusele: C3; 12 Klaaspakett: Kolmekordne klaaspakett; 13 Klaasingu erisused: Sisemine klaas lamineeritud, välimine klaaskarastatud; 15 Avanemine: Sisse; 16 Liigendatus: -; 17 Sulused, lukustus: Link TBT (Tilt Before Turn) Hoppe London (matt kroomi viimistlusega), Pöördavatav asend avatav ainult võtmega! Hinged tootekeskesed, hingede viimistlus sama, mis aknaraamil.; 18 Viimistlus: Raam ja leng on värvitud tumehalliks RAL 7016 (Anthrazitgrau). Akna kinnituskruvid ei tohi jääda nähtavale, aktsepteeritavad ei ole ka korkidega kaetud kruviaugud.; 19 Mudel või toote tunnus: DK88 (või samaväärne analoog); 20 Tootja: Viking Window AS (või samaväärne analoog); 21 Tooteinfo: Undefined; 22 Kasutus- ja hooldusjuhend: Undefined; 14 Päikesekiirgus tegur (g-väärtus): 0,38; 23 viide sõlmele: Undefined
AC_Pset_RenovationAndPhasing - Renovation Status: New

# IfcWindow: A-14 1 150×1 200, Välisaken * Window 22
In: 1 korrus
Type - OperationType: SINGLE_PANEL; ParameterTakesPrecedence: no; Sizeable: no
Type - Window Lining Properties - LiningDepth: 50 mm; LiningThickness: 50 mm
Type - Window Panel Properties - Panel 1 - OperationType: TILTANDTURNLEFTHAND; PanelPosition: MIDDLE; FrameDepth: 50 mm; FrameThickness: 50 mm
OverallHeight: 1200 mm; OverallWidth: 1150 mm; Classification: 0 TELLIJA KULUD (EHITUSKULUDE LIIGITAMINE EVS 885:2005); 1.19 IfcWindow (aken) (_RKAS BIM + ARCHICAD Classification)
Pset_WindowCommon - ThermalTransmittance: 0; GlazingAreaFraction: 1.05; IsExternal: yes
Avatäited - 01 Nimetus: Välisaken; 02 Materjal: Alumiiniumprofiiliga klaaspakett; 03 Tähistus: A-14 1 150×1 200; 04 Avamõõdu geomeetria: 1 150×1 200; 05 Asukoha info: Exterior; 06 Soojusläbivus: 0,74W/m2K; 07 Helipidavus: 34dB; 08 Veepidavus: 7A; 09 Õhuläbilaskvus: klass 4; 10 Tulekindlus: nõudeid ei esitata; 11 Vastupanu tulekoormusele: C3; 12 Klaaspakett: Kolmekordne klaaspaket; 13 Klaasingu erisused: Sisemine klaas lamineeritud, välimine klaaskarastatud; 15 Avanemine: Sisse; 16 Liigendatus: -; 17 Sulused, lukustus: Link TBT (Tilt Before Turn) Hoppe London (matt kroomi viimistlusega), Pöördavatav asend avatav ainult võtmega! Link paigaldada aknaraami alumisse osasse. Hinged tootekeskesed, hingede viimistlus sama, mis akna raamil.; 18 Viimistlus: Raam ja leng on värvitud tumehalliks RAL 7016 (Anthrazitgrau). Akna kinnituskruvid ei tohi nähtavale jääda, aktsepteeritavad ei ole ka korkidega kaetud kruviaugud.; 19 Mudel või toote tunnus: DK88 (või samaväärne analoog); 20 Tootja: Viking Window AS (või samaväärne analoog); 21 Tooteinfo: Undefined; 22 Kasutus- ja hooldusjuhend: Undefined; 14 Päikesekiirgus tegur (g-väärtus): 0,38; 23 viide sõlmele: Undefined
AC_Pset_RenovationAndPhasing - Renovation Status: New

# IfcWindow: A-15 700×2 300 (17)
In: 1,5 korrus
Type - OperationType: SINGLE_PANEL; ParameterTakesPrecedence: no; Sizeable: no
Type - Window Lining Properties - LiningDepth: 50 mm; LiningThickness: 50 mm
Type - Window Panel Properties - Panel 1 - OperationType: TILTANDTURNLEFTHAND; PanelPosition: MIDDLE; FrameDepth: 50 mm; FrameThickness: 50 mm
OverallHeight: 2300 mm; OverallWidth: 700 mm; Classification: 0 TELLIJA KULUD (EHITUSKULUDE LIIGITAMINE EVS 885:2005); 1.19 IfcWindow (aken) (_RKAS BIM + ARCHICAD Classification)
Pset_WindowCommon - ThermalTransmittance: 0; GlazingAreaFraction: 1.1825; IsExternal: yes
Avatäited - 01 Nimetus: Välisaken; 02 Materjal: Puitalumiiniumprofiiliga klaaspakett; 03 Tähistus: A-15 700×2 300; 04 Avamõõdu geomeetria: 700×2 300; 05 Asukoha info: Exterior; 06 Soojusläbivus: 0,74W/m2K; 07 Helipidavus: 34dB; 08 Veepidavus: 7A; 09 Õhuläbilaskvus: klass 4; 10 Tulekindlus: nõudeid ei esitata; 11 Vastupanu tulekoormusele: C3; 12 Klaaspakett: Kolmekordne klaaspakett; 13 Klaasingu erisused: Sisemine klaas lamineeritud, välimine klaaskarastatud; 15 Avanemine: Sisse; 16 Liigendatus: -; 17 Sulused, lukustus: Link TBT (Tilt Before Turn) Hoppe London (matt kroomi viimistlusega), Pöördavatav asend avatav ainult võtmega! Hinged tootekeskesed, hingede viimistlus sama, mis aknaraamil.; 18 Viimistlus: Raam ja leng on värvitud tumehalliks RAL 7016 (Anthrazitgrau). Akna kinnituskruvid ei tohi jääda nähtavale, aktsepteeritavad ei ole ka korkidega kaetud kruviaugud.; 19 Mudel või toote tunnus: DK88 (või samaväärne analoog); 20 Tootja: Viking Window AS (või samaväärne analoog); 21 Tooteinfo: Undefined; 22 Kasutus- ja hooldusjuhend: Undefined; 14 Päikesekiirgus tegur (g-väärtus): 0,38; 23 viide sõlmele: Undefined
AC_Pset_RenovationAndPhasing - Renovation Status: New

# IfcWindow: KA-01 1 000×1 500, Katuseaken * Skylight Flat Panel 22
In: 2 korrus
Type - ParameterTakesPrecedence: no; Sizeable: no
Type - Window Lining Properties - LiningDepth: 50 mm; LiningThickness: 100 mm
OverallHeight: 1500 mm; OverallWidth: 1000 mm; Classification: 1.19 IfcWindow (aken) (_RKAS BIM + ARCHICAD Classification)
Pset_WindowCommon - ThermalTransmittance: 0; GlazingAreaFraction: 0; IsExternal: yes
Avatäited - 01 Nimetus: Katuseaken; 02 Materjal: Alumiiniumprofiil; 03 Tähistus: KA-01 1 000×1 500; 04 Avamõõdu geomeetria: 1 000×1 500; 05 Asukoha info: Exterior; 06 Soojusläbivus: 1,1 W/m2k; 07 Helipidavus: 30 dB; 08 Veepidavus: 7a; 09 Õhuläbilaskvus: klass 4; 10 Tulekindlus: nõudeid ei esitata; 11 Vastupanu tulekoormusele: C3; 12 Klaaspakett: 3 kordne klaaspakett; 13 Klaasingu erisused: Välimine klaas karastatud, sisemine klaas lamineeritud.; 15 Avanemine: Avatav; 16 Liigendatus: -; 17 Sulused, lukustus: Tootekesksed suitsueemaldusakna sulused. Peavad olema kasutatav ka tavatuulutuseks. Aken peab olema peidetud elektroonilise avamis- ja riivistussüsteemiga.; 18 Viimistlus: Raam ja leng on värvitud tumehalliks RAL 7016 (Anthrazitgrau). Akna kinnituskruvid ei tohi jääda nähtavale, aktsepteeritavad ei ole ka korkidega kaetud kruviaugud.; 19 Mudel või toote tunnus: FW50+SI (või samaväärne analoog); 20 Tootja: Schüco (või samaväärne analoog); 21 Tooteinfo: Undefined; 22 Kasutus- ja hooldusjuhend: Undefined; 14 Päikesekiirgus tegur (g-väärtus): 0,38; 23 viide sõlmele: Undefined
AC_Pset_RenovationAndPhasing - Renovation Status: New

# IfcWindow: KA-02 4 730×1 376 (8)
In: Katus
Type - ParameterTakesPrecedence: no; Sizeable: no
Type - Window Lining Properties - LiningDepth: 50 mm; LiningThickness: 100 mm
OverallHeight: 1375.85 mm; OverallWidth: 4730 mm; Classification: 1.19 IfcWindow (aken) (_RKAS BIM + ARCHICAD Classification)
Pset_WindowCommon - ThermalTransmittance: 0; GlazingAreaFraction: 0; IsExternal: yes
Avatäited - 01 Nimetus: Katuseaken; 02 Materjal: Alumiiniumprofiil; 03 Tähistus: KA-02 4 730×1 376; 04 Avamõõdu geomeetria: 4 730×1 376; 05 Asukoha info: Exterior; 06 Soojusläbivus: 1,1 W/m2k; 07 Helipidavus: 30 dB; 08 Veepidavus: 7a; 09 Õhuläbilaskvus: klass 4; 10 Tulekindlus: nõudeid ei esitata; 11 Vastupanu tulekoormusele: C3; 12 Klaaspakett: 3 kordne klaaspakett; 13 Klaasingu erisused: Välimine klaas karastatud, sisemine klaas lamineeritud.; 15 Avanemine: Keskmine osa avatav; 16 Liigendatus: 3- ruuduga; 17 Sulused, lukustus: Tootekesksed suitsueemaldusakna sulused. Peavad olema kasutatavad ka tavatuulutuseks. Aken peab olema peidetud elektroonilise avamis- ja riivistussüsteemiga. Aken varustada vihma ja tuule anduritega.; 18 Viimistlus: Raam ja leng on värvitud tumehalliks RAL 7016 (Anthrazitgrau). Akna kinnituskruvid ei tohi jääda nähtavale, aktsepteeritavad ei ole ka korkidega kaetud kruviaugud.; 19 Mudel või toote tunnus: FW50+SI (või samaväärne analoog); 20 Tootja: Schüco (või samaväärne analoog); 21 Tooteinfo: Undefined; 22 Kasutus- ja hooldusjuhend: Undefined; 14 Päikesekiirgus tegur (g-väärtus): 0,38; 23 viide sõlmele: Undefined
AC_Pset_RenovationAndPhasing - Renovation Status: New

# IfcWindow: KA-03 3 800×1 242 (3)
In: Katus
Type - ParameterTakesPrecedence: no; Sizeable: no
Type - Window Lining Properties - LiningDepth: 50 mm; LiningThickness: 100 mm
OverallHeight: 1242.33 mm; OverallWidth: 3800 mm; Classification: 1.19 IfcWindow (aken) (_RKAS BIM + ARCHICAD Classification)
Pset_WindowCommon - ThermalTransmittance: 0; GlazingAreaFraction: 0; IsExternal: yes
Avatäited - 01 Nimetus: Katuseaken; 02 Materjal: Alumiiniumprofiil; 03 Tähistus: KA-03 3 800×1 242; 04 Avamõõdu geomeetria: 3 800×1 242; 05 Asukoha info: Exterior; 06 Soojusläbivus: 1,1 W/m2k; 07 Helipidavus: 30 dB; 08 Veepidavus: 7a; 09 Õhuläbilaskvus: klass 4; 10 Tulekindlus: nõudeid ei esitata; 11 Vastupanu tulekoormusele: C3; 12 Klaaspakett: 3 kordne klaaspakett; 13 Klaasingu erisused: Välimine klaas karastatud, sisemine klaas lamineeritud.; 15 Avanemine: Üks pool avatav; 16 Liigendatus: 2- ruuduga; 17 Sulused, lukustus: Tootekesksed suitsueemaldusakna sulused. Peavad olema kasutatavad ka tavatuulutuseks. Aken peab olema peidetud elektroonilise avamis- ja riivistussüsteemiga. Aken varustada vihma ja tuule anduritega.; 18 Viimistlus: Raam ja leng on värvitud tumehalliks RAL 7016 (Anthrazitgrau). Akna kinnituskruvid ei tohi jääda nähtavale, aktsepteeritavad ei ole ka korkidega kaetud kruviaugud.; 19 Mudel või toote tunnus: FW50+SI (või samaväärne analoog); 20 Tootja: Schüco (või samaväärne analoog); 21 Tooteinfo: Undefined; 22 Kasutus- ja hooldusjuhend: Undefined; 14 Päikesekiirgus tegur (g-väärtus): 0,38; 23 viide sõlmele: Undefined
AC_Pset_RenovationAndPhasing - Renovation Status: New
